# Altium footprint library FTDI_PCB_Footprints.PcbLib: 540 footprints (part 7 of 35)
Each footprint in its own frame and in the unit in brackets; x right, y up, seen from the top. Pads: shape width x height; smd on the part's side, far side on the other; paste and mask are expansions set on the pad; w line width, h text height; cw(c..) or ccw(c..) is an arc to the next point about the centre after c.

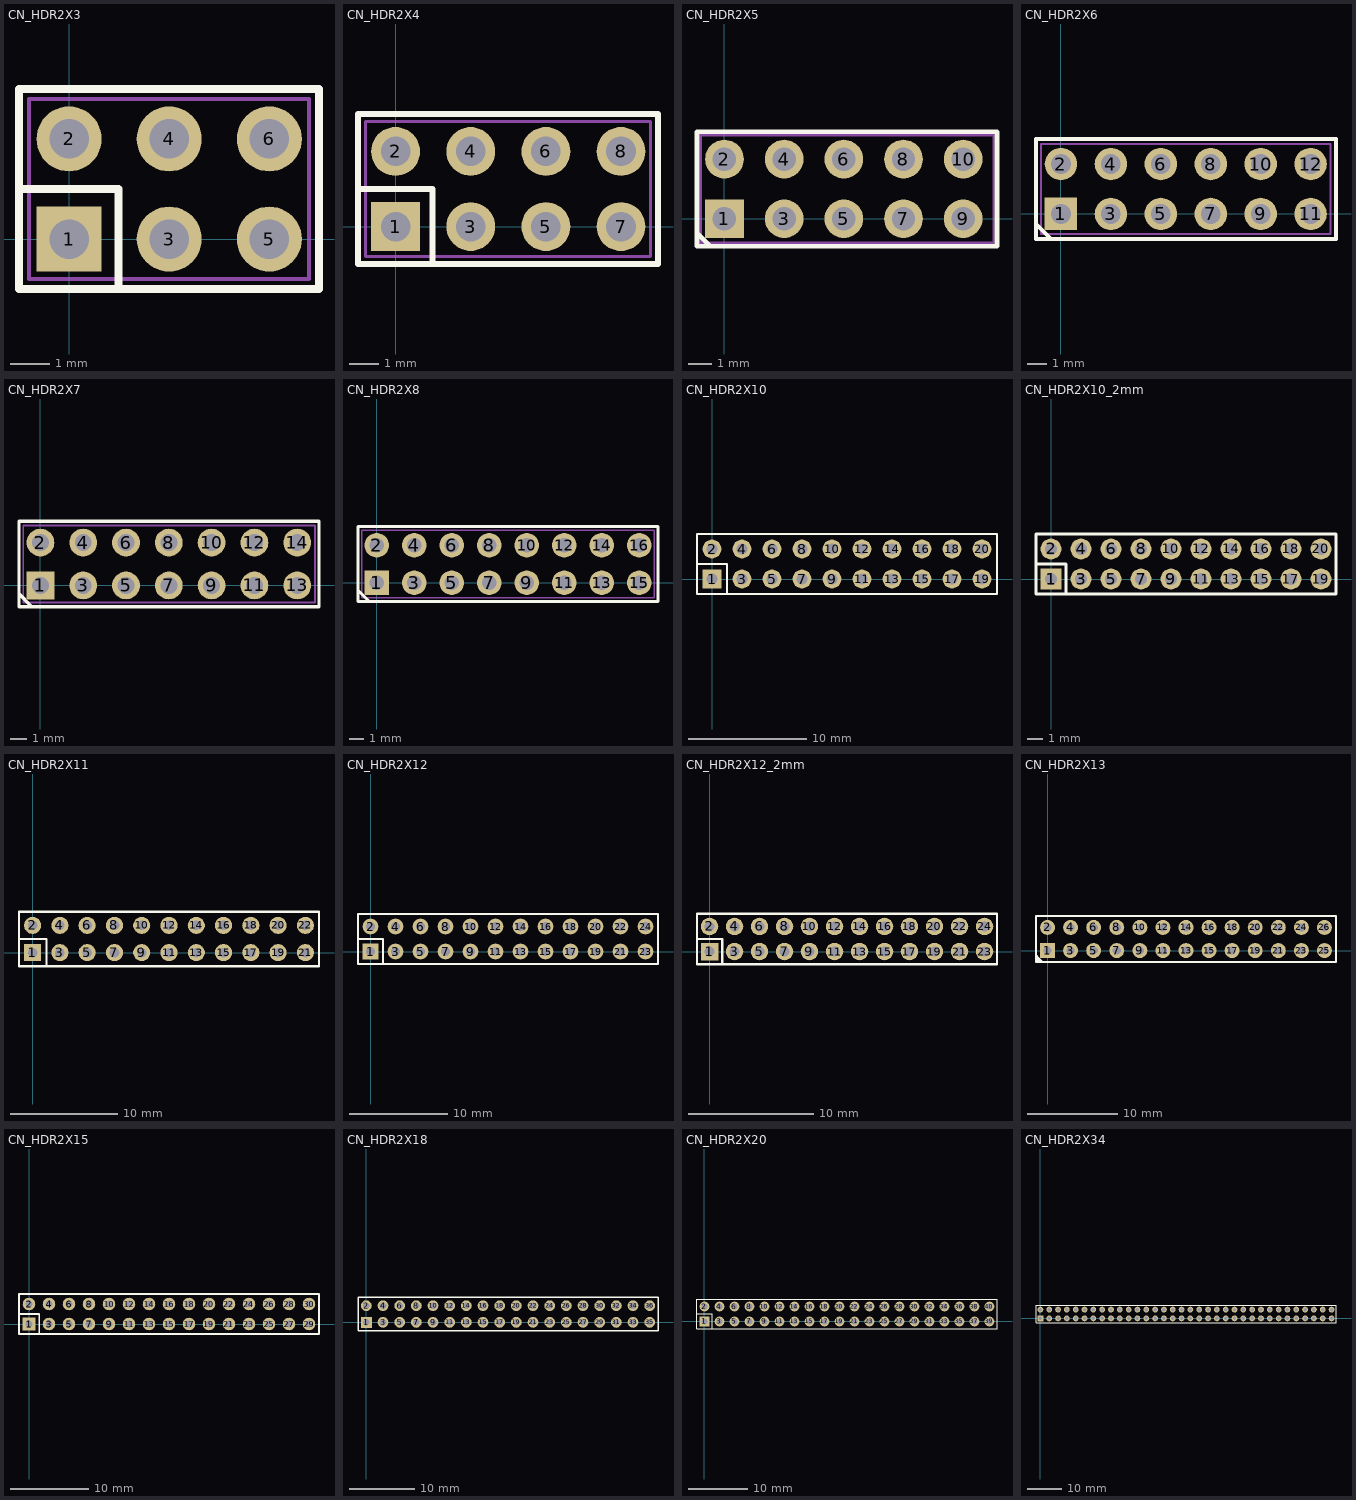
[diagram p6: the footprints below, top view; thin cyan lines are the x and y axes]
## CN_HDR2X3 [mil] "Connector; Header; 2x3 Position; pitch 0.1\""
pads (6):
  rect 65x65 hole 39.37: 1(0,0)
  round 65 hole 39.37: 2(0,100) 3(100,0) 4(100,100) 5(200,0) 6(200,100)
Top Overlay:
  lines w7.87: -50,50 49.21,50 49.21,-50 ; -50,-50 249.61,-50 249.61,150 -50,150 -50,-50
M7_3D_Body:
  lines w3.94: -40,-40 -40,140 239.76,140 239.76,-40 -40,-40

## CN_HDR2X4 [mil] "Connector; Header; 2x4 Position; pitch 0.1\""
pads (8):
  rect 65x65 hole 39.37: 1(0,0)
  round 65 hole 39.37: 2(0,100) 3(100,0) 4(100,100) 5(200,0) 6(200,100) 7(300,0) 8(300,100)
Top Overlay:
  lines w7.87: -50,50 49.21,50 49.21,-50 ; -50,-50 349.21,-50 349.21,150 -50,150 -50,-50
M7_3D_Body:
  lines w3.94: -40,-40 -40,140 339.37,140 339.37,-40 -40,-40

## CN_HDR2X5 [mil] "Connector; Header; 2x5 Position; pitch 0.1\""
pads (10):
  rect 65x65 hole 39.37: 1(0,0)
  round 65 hole 39.37: 2(0,100) 3(100,0) 4(100,100) 5(200,0) 6(200,100) 7(300,0) 8(300,100) 9(400,0) 10(400,100)
Top Overlay:
  lines w7.87: -45.96,-23.92 -23.72,-46.16 ; -46.06,-46.06 456.69,-46.06 456.69,146.06 -46.06,146.06 -46.06,-46.06
M13_Assembly_Info:
  lines w3.94: -40,-40 -40,140 450.79,140 450.79,-40 -40,-40

## CN_HDR2X6 [mil] "Connector; Header; 6x2 Position; pitch 0.1\""
pads (12):
  rect 65x65 hole 39.37: 1(0,0)
  round 65 hole 39.37: 2(0,100) 3(100,0) 4(100,100) 5(200,0) 6(200,100) 7(300,0) 8(300,100) 9(400,0) 10(400,100) 11(500,0) 12(500,100)
Top Overlay:
  lines w7.87: -50,-19.88 -19.88,-50 ; -50,-50 550.79,-50 550.79,150 -50,150 -50,-50
M7_3D_Body:
  lines w3.94: -40,-40 540,-40 540,140 -40,140 -40,-40

## CN_HDR2X7 [mil] "Connector; Header; 7x2 Position; pitch 0.1\""
pads (14):
  rect 65x65 hole 39.37: 1(0,0)
  round 65 hole 39.37: 2(0,100) 3(100,0) 4(100,100) 5(200,0) 6(200,100) 7(300,0) 8(300,100) 9(400,0) 10(400,100) 11(500,0) 12(500,100) 13(600,0) 14(600,100)
Top Overlay:
  lines w7.87: -50,-19.88 -19.88,-50 ; -50,-50 650.79,-50 650.79,150 -50,150 -50,-50
M7_3D_Body:
  lines w3.94: -40,-40 -40,140 641.34,140 641.34,-40 -40,-40

## CN_HDR2X8 [mil] "Connector; Header; 8x2 Position; pitch 0.1\""
pads (16):
  rect 65x65 hole 39.37: 1(0,0)
  round 65 hole 39.37: 2(0,100) 3(100,0) 4(100,100) 5(200,0) 6(200,100) 7(300,0) 8(300,100) 9(400,0) 10(400,100) 11(500,0) 12(500,100) 13(600,0) 14(600,100) 15(700,0) 16(700,100)
Top Overlay:
  lines w7.87: -50,-19.88 -19.88,-50 ; -50,-50 750,-50 750,150 -50,150 -50,-50
M7_3D_Body:
  lines w3.94: -40,-40 -40,140 740,140 740,-40 -40,-40

## CN_HDR2X10 [mm] "Connector; Header; Female; 2x10 Position; Pitch 0.1\""
pads (20):
  rect 1.6x1.6 hole 0.9: 1(0,0)
  round 1.6 hole 0.9: 2(0,2.54) 3(2.54,0) 4(2.54,2.54) 5(5.08,0) 6(5.08,2.54) 7(7.62,0) 8(7.62,2.54) 9(10.16,0) 10(10.16,2.54) 11(12.7,0) 12(12.7,2.54) 13(15.24,0) 14(15.24,2.54) 15(17.78,0) 16(17.78,2.54) 17(20.32,0) 18(20.32,2.54) 19(22.86,0) 20(22.86,2.54)
Top Overlay:
  lines w0.2: -1.265,1.27 1.275,1.27 1.275,-1.27 ; -1.27,-1.27 24.13,-1.27 24.13,3.81 -1.27,3.81 -1.27,-1.27

## CN_HDR2X10_2mm [mm] "Connector; Header; 2 Rows x 10 Positions; pitch 2.0mm"
pads (20):
  rect 1.4x1.4 hole 0.8: 1(0,0)
  round 1.4 hole 0.8: 2(0,2) 3(2,0) 4(2,2) 5(4,0) 6(4,2) 7(6,0) 8(6,2) 9(8,0) 10(8,2) 11(10,0) 12(10,2) 13(12,0) 14(12,2) 15(14,0) 16(14,2) 17(16,0) 18(16,2) 19(18,0) 20(18,2)
Top Overlay:
  lines w0.2: 1,-1 1,1 -1,1 ; -1,1 -1,-1 19,-1 19,1 19,3 -1,3 -1,1

## CN_HDR2X11 [mm] "Connector; Header; Female; 2x11 Position; Pitch 0.1\""
pads (22):
  rect 1.6x1.6 hole 0.9: 1(0,0)
  round 1.6 hole 0.9: 2(0,2.54) 3(2.54,0) 4(2.54,2.54) 5(5.08,0) 6(5.08,2.54) 7(7.62,0) 8(7.62,2.54) 9(10.16,0) 10(10.16,2.54) 11(12.7,0) 12(12.7,2.54) 13(15.24,0) 14(15.24,2.54) 15(17.78,0) 16(17.78,2.54) 17(20.32,0) 18(20.32,2.54) 19(22.86,0) 20(22.86,2.54) 21(25.4,0) 22(25.4,2.54)
Top Overlay:
  lines w0.2: -1.265,1.27 1.275,1.27 1.275,-1.27 ; -1.27,-1.27 26.67,-1.27 26.67,3.81 -1.27,3.81 -1.27,-1.27

## CN_HDR2X12 [mm] "Connector; Header; Female; 2x12 Position; Pitch 0.1\""
pads (24):
  rect 1.6x1.6 hole 0.9: 1(0,0)
  round 1.6 hole 0.9: 2(0,2.54) 3(2.54,0) 4(2.54,2.54) 5(5.08,0) 6(5.08,2.54) 7(7.62,0) 8(7.62,2.54) 9(10.16,0) 10(10.16,2.54) 11(12.7,0) 12(12.7,2.54) 13(15.24,0) 14(15.24,2.54) 15(17.78,0) 16(17.78,2.54) 17(20.32,0) 18(20.32,2.54) 19(22.86,0) 20(22.86,2.54) 21(25.4,0) 22(25.4,2.54) 23(27.94,0) 24(27.94,2.54)
Top Overlay:
  lines w0.2: -1.265,1.27 1.275,1.27 1.275,-1.27 ; -1.27,-1.27 -1.27,3.81 29.21,3.81 29.21,-1.27 -1.27,-1.27

## CN_HDR2X12_2mm [mm] "Connector; Header; 2 Rows x 12 Positions; pitch 2.0mm"
height 4.5
pads (24):
  rect 1.4x1.4 hole 0.8: 1(0,0)
  round 1.4 hole 0.8: 2(0,2) 3(2,0) 4(2,2) 5(4,0) 6(4,2) 7(6,0) 8(6,2) 9(8,0) 10(8,2) 11(10,0) 12(10,2) 13(12,0) 14(12,2) 15(14,0) 16(14,2) 17(16,0) 18(16,2) 19(18,0) 20(18,2) 21(20,0) 22(20,2) 23(22,0) 24(22,2)
Top Overlay:
  lines w0.2: 1,-1 1,1 -1,1 ; -1,1 -1,3 23,3 23,-1 -1,-1 -1,1

## CN_HDR2X13 [mil] "Connector; Header; Male; 13x2 Position; Pitch 0.1\""
pads (26):
  rect 65x65 hole 35.43: 1(0,0)
  round 65 hole 35.43: 2(0,100) 3(100,0) 4(100,100) 5(200,0) 6(200,100) 7(300,0) 8(300,100) 9(400,0) 10(400,100) 11(500,0) 12(500,100) 13(600,0) 14(600,100) 15(700,0) 16(700,100) 17(800,0) 18(800,100) 19(900,0) 20(900,100) 21(1000,0) 22(1000,100) 23(1100,0) 24(1100,100) 25(1200,0) 26(1200,100)
Top Overlay:
  region: -50,-50 -50,-15.35 -32.68,-32.68 -15.35,-50
  lines w7.87: -50,-50 -50,150 1250,150 1250,-50 -50,-50

## CN_HDR2X15 [mm] "Connector; Header; Female; 15x2 Position; Pitch 0.1\""
pads (30):
  rect 1.6x1.6 hole 0.9: 1(0,0)
  round 1.6 hole 0.9: 2(0,2.54) 3(2.54,0) 4(2.54,2.54) 5(5.08,0) 6(5.08,2.54) 7(7.62,0) 8(7.62,2.54) 9(10.16,0) 10(10.16,2.54) 11(12.7,0) 12(12.7,2.54) 13(15.24,0) 14(15.24,2.54) 15(17.78,0) 16(17.78,2.54) 17(20.32,0) 18(20.32,2.54) 19(22.86,0) 20(22.86,2.54) 21(25.4,0) 22(25.4,2.54) 23(27.94,0) 24(27.94,2.54) 25(30.48,0) 26(30.48,2.54) 27(33.02,0) 28(33.02,2.54) 29(35.56,0) 30(35.56,2.54)
Top Overlay:
  lines w0.2: -1.265,1.27 1.275,1.27 1.275,-1.27 ; -1.27,-1.27 36.83,-1.27 36.83,3.81 -1.27,3.81 -1.27,-1.27

## CN_HDR2X18 [mil] "Connector; Header; 18x2 Position; Pitch 0.1\""
pads (36):
  rect 65x65 hole 39.37: 1(0,0)
  round 65 hole 39.37: 2(0,100) 3(100,0) 4(100,100) 5(200,0) 6(200,100) 7(300,0) 8(300,100) 9(400,0) 10(400,100) 11(500,0) 12(500,100) 13(600,0) 14(600,100) 15(700,0) 16(700,100) 17(800,0) 18(800,100) 19(900,0) 20(900,100) 21(1000,0) 22(1000,100) 23(1100,0) 24(1100,100) 25(1200,0) 26(1200,100) 27(1300,0) 28(1300,100) 29(1400,0) 30(1400,100) 31(1500,0) 32(1500,100) 33(1600,0) 34(1600,100) 35(1700,0) 36(1700,100)
Top Overlay:
  lines w7.87: -50,-50 -50,150 1750,150 1750,-50 -50,-50

## CN_HDR2X20 [mil] "Connector; Header; Male; 2x20 Positions; Pitch 0.1\""
height 329.92
pads (40):
  rect 65x65 hole 39.37: 1(0,0)
  round 65 hole 39.37: 2(0,100) 3(100,0) 4(100,100) 5(200,0) 6(200,100) 7(300,0) 8(300,100) 9(400,0) 10(400,100) 11(500,0) 12(500,100) 13(600,0) 14(600,100) 15(700,0) 16(700,100) 17(800,0) 18(800,100) 19(900,0) 20(900,100) 21(1000,0) 22(1000,100) 23(1100,0) 24(1100,100) 25(1200,0) 26(1200,100) 27(1300,0) 28(1300,100) 29(1400,0) 30(1400,100) 31(1500,0) 32(1500,100) 33(1600,0) 34(1600,100) 35(1700,0) 36(1700,100) 37(1800,0) 38(1800,100) 39(1900,0) 40(1900,100)
Top Overlay:
  lines w7.87: -50,51.18 51.18,51.18 51.18,-50 ; -50,-50 1750,-50 1950.39,-50 1950.39,150 1750,150 -50,150 -50,-50

## CN_HDR2X34 [mil] "Connector; Header; Male; 2x34 Positions; Pitch 0.1\""
height 329.92
pads (68):
  rect 65x65 hole 39.37: 1(0,0)
  round 65 hole 39.37: 2(0,100) 3(100,0) 4(100,100) 5(200,0) 6(200,100) 7(300,0) 8(300,100) 9(400,0) 10(400,100) 11(500,0) 12(500,100) 13(600,0) 14(600,100) 15(700,0) 16(700,100) 17(800,0) 18(800,100) 19(900,0) 20(900,100) 21(1000,0) 22(1000,100) 23(1100,0) 24(1100,100) 25(1200,0) 26(1200,100) 27(1300,0) 28(1300,100) 29(1400,0) 30(1400,100) 31(1500,0) 32(1500,100) 33(1600,0) 34(1600,100) 35(1700,0) 36(1700,100) 37(1800,0) 38(1800,100) 39(1900,0) 40(1900,100) 41(2000,0) 42(2000,100) 43(2100,0) 44(2100,100) 45(2200,0) 46(2200,100) 47(2300,0) 48(2300,100) 49(2400,0) 50(2400,100) 51(2500,0) 52(2500,100) 53(2600,0) 54(2600,100) 55(2700,0) 56(2700,100) 57(2800,0) 58(2800,100) 59(2900,0) 60(2900,100) 61(3000,0) 62(3000,100) 63(3100,0) 64(3100,100) 65(3200,0) 66(3200,100) 67(3300,0) 68(3300,100)
Top Overlay:
  lines w7.87: -50,-50 -50,150 1750,150 3350.39,150 3350.39,-50 1750,-50 -50,-50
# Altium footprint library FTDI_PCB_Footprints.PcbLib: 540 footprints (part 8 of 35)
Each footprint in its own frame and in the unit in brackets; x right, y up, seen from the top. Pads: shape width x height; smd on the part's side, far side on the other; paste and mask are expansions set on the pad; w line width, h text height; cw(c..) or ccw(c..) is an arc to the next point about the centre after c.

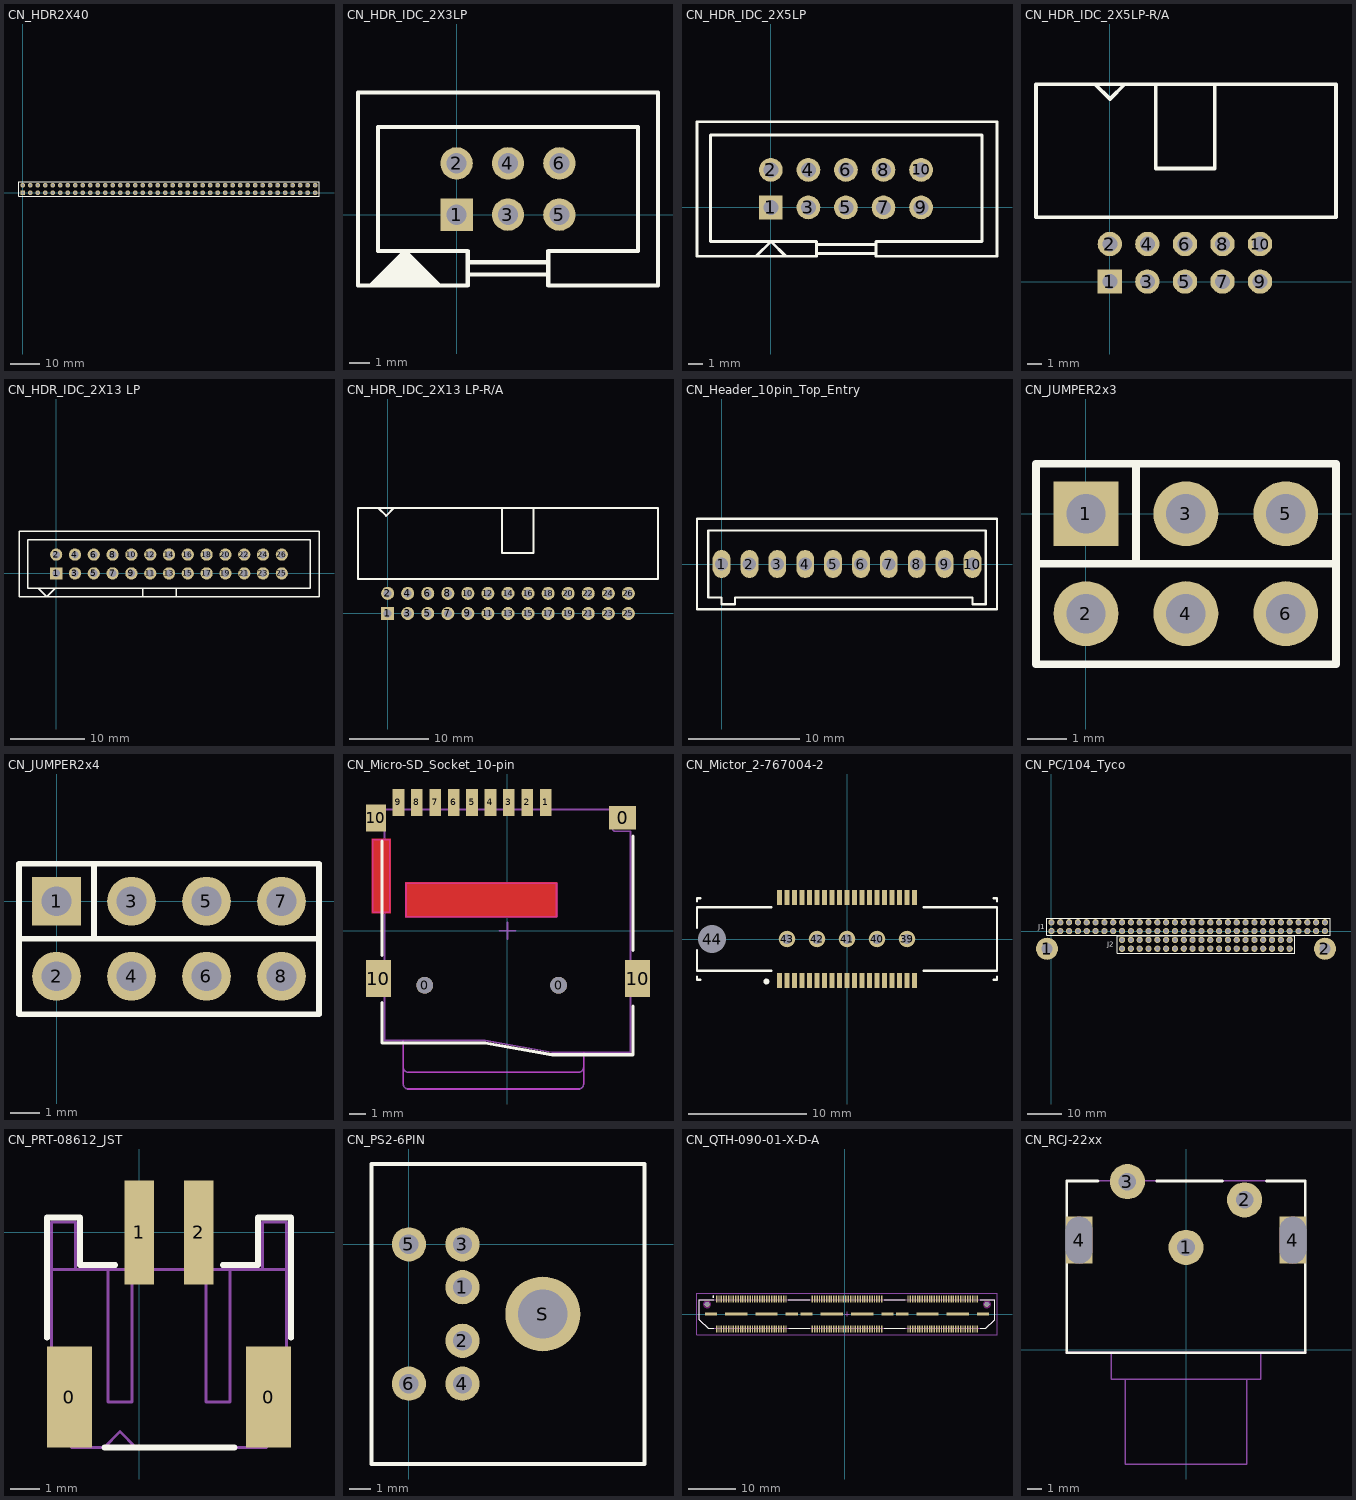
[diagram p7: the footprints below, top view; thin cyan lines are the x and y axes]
## CN_HDR2X40 [mil] "Connector; Header; Male; 2x80 Positions; Pitch 0.1\""
height 329.92
pads (80):
  rect 65x65 hole 39.37: 1(0,0)
  round 65 hole 39.37: 2(0,100) 3(100,0) 4(100,100) 5(200,0) 6(200,100) 7(300,0) 8(300,100) 9(400,0) 10(400,100) 11(500,0) 12(500,100) 13(600,0) 14(600,100) 15(700,0) 16(700,100) 17(800,0) 18(800,100) 19(900,0) 20(900,100) 21(1000,0) 22(1000,100) 23(1100,0) 24(1100,100) 25(1200,0) 26(1200,100) 27(1300,0) 28(1300,100) 29(1400,0) 30(1400,100) 31(1500,0) 32(1500,100) 33(1600,0) 34(1600,100) 35(1700,0) 36(1700,100) 37(1800,0) 38(1800,100) 39(1900,0) 40(1900,100) 41(2000,0) 42(2000,100) 43(2100,0) 44(2100,100) 45(2200,0) 46(2200,100) 47(2300,0) 48(2300,100) 49(2400,0) 50(2400,100) 51(2500,0) 52(2500,100) 53(2600,0) 54(2600,100) 55(2700,0) 56(2700,100) 57(2800,0) 58(2800,100) 59(2900,0) 60(2900,100) 61(3000,0) 62(3000,100) 63(3100,0) 64(3100,100) 65(3200,0) 66(3200,100) 67(3300,0) 68(3300,100) 69(3400,0) 70(3400,100) 71(3500,0) 72(3500,100) 73(3600,0) 74(3600,100) 75(3700,0) 76(3700,100) 77(3800,0) 78(3800,100) 79(3900,0) 80(3900,100)
Top Overlay:
  lines w7.87: -50,-50 1750,-50 3950.39,-50 3950.39,150 1750,150 -50,150 -50,-50

## CN_HDR_IDC_2X3LP [mm] "Connector; Header; Lo Profile; 2x3 Position; Pitch 0.1\""
height 9.57
pads (6):
  rect 1.6x1.6 hole 1: 1(0,0)
  round 1.6 hole 1: 2(0,2.54) 3(2.54,0) 4(2.54,2.54) 5(5.08,0) 6(5.08,2.54)
Top Overlay:
  region: -2.55,-1.805 -4.25,-3.505 -0.85,-3.505
  lines w0.2: -4.25,-3.505 -2.55,-1.805 -0.85,-3.505 ; 0.55,-2.95 4.53,-2.95 ; 0.55,-2.35 4.53,-2.35 ; -4.875,-3.505 -4.875,6.045 9.955,6.045 9.955,-3.505 4.53,-3.505 4.53,-1.805 8.965,-1.805 8.965,4.345 -3.885,4.345 -3.885,-1.805 0.55,-1.805 0.55,-3.505 -4.875,-3.505

## CN_HDR_IDC_2X5LP [mm] "Connector; Header; Lo Profile; 5x2 Position; Pitch 0.1\""
pads (10):
  rect 1.6x1.6 hole 1: 1(0,0)
  round 1.6 hole 1: 2(0,2.54) 3(2.54,0) 4(2.54,2.54) 5(5.08,0) 6(5.08,2.54) 7(7.62,0) 8(7.62,2.54) 9(10.16,0) 10(10.16,2.54)
Top Overlay:
  lines w0.2: -1,-3.3 0,-2.3 1,-3.3 ; 3.1,-3.1 7.1,-3.1 ; 3.1,-2.5 7.1,-2.5 ; -5,-3.3 3.1,-3.3 3.1,-2.3 -4.1,-2.3 -4.1,4.9 14.3,4.9 14.3,-2.3 7.1,-2.3 7.1,-3.3 15.3,-3.3 15.3,5.8 -5,5.8 -5,-3.3

## CN_HDR_IDC_2X5LP-R/A [mil] "Connector; Header; Horizontal; Lo Profile; 5x2 Position; Pitch 0.1\""
pads (10):
  rect 65x65 hole 39.37: 1(0,0)
  round 65 hole 39.37: 2(0,100) 3(100,0) 4(100,100) 5(200,0) 6(200,100) 7(300,0) 8(300,100) 9(400,0) 10(400,100)
Top Overlay:
  lines w10: -39.37,525.59 0,486.22 39.37,525.59 ; 122.05,525.59 122.05,301.18 279.53,301.18 279.53,525.59 ; -196.85,171.26 602.36,171.26 602.36,525.59 -196.85,525.59 -196.85,171.26
3D body: height 393.7, standoff 0, extent -196.85,171.26 602.36,525.59

## CN_HDR_IDC_2X13 LP [mil] "Connector; Header; Vertical; Low Profile; 2x13 Positions; Pitch 0.1\""
height 358.27
pads (26):
  rect 65x65 hole 39.37: 1(0,0)
  round 65 hole 39.37: 2(0,100) 3(100,0) 4(100,100) 5(200,0) 6(200,100) 7(300,0) 8(300,100) 9(400,0) 10(400,100) 11(500,0) 12(500,100) 13(600,0) 14(600,100) 15(700,0) 16(700,100) 17(800,0) 18(800,100) 19(900,0) 20(900,100) 21(1000,0) 22(1000,100) 23(1100,0) 24(1100,100) 25(1200,0) 26(1200,100)
Top Overlay:
  lines w7.87: -95.08,-78.15 -50,-123.23 -4.92,-78.15 ; 461.42,-123.23 461.42,-77.95 ; 638.58,-123.23 638.58,-77.95 ; -197.64,-123.23 -197.64,223.23 1397.64,223.23 1397.64,-123.23 -197.64,-123.23 ; -152.36,-77.95 1352.36,-77.95 1352.36,177.95 -152.36,177.95 -152.36,-77.95
3D body: height 358.27, standoff 0, extent -197.64,-123.23 1397.64,223.23

## CN_HDR_IDC_2X13 LP-R/A [mil] "Connector; Header; Horizontal; Low Profile; 2x13 Positions; Pitch 0.1\""
height 358.27
pads (26):
  rect 65x65 hole 39.37: 1(0,0)
  round 65 hole 39.37: 2(0,100) 3(100,0) 4(100,100) 5(200,0) 6(200,100) 7(300,0) 8(300,100) 9(400,0) 10(400,100) 11(500,0) 12(500,100) 13(600,0) 14(600,100) 15(700,0) 16(700,100) 17(800,0) 18(800,100) 19(900,0) 20(900,100) 21(1000,0) 22(1000,100) 23(1100,0) 24(1100,100) 25(1200,0) 26(1200,100)
Top Overlay:
  lines w7.87: 602.36,171.26 688.74,171.26
  lines w10: -47.24,525.59 -7.87,486.22 31.5,525.59 ; 569.29,525.59 569.29,301.18 726.77,301.18 726.77,525.59 ; -147.64,171.26 -147.64,525.59 1347.64,525.59 1347.64,171.26 -147.64,171.26
3D body: height 393.7, standoff 0, extent -147.64,171.26 1347.64,525.59

## CN_Header_10pin_Top_Entry [mm] "HEADER, TOP ENTRY, 10WAY     Connector Type:Board to Board; No. of Positions:10; Pitch:2.5mm; Mounting Type:PCB; Series:Type 373; Colour:Green; Current Rating:4A; Voltage Rating AC:130V;"
height 10.1
pads (10):
  oval 1.6x2.5 hole 1.2: 1(0,0) 2(2.5,0) 3(5,0) 4(7.5,0) 5(10,0) 6(12.5,0) 7(15,0) 8(17.5,0) 9(20,0) 10(22.5,0)
Top Overlay:
  lines w0.2: -1.19,2.995 -1.19,-3 0,-3 0,-3.6 ; -1.19,3 23.7,3 23.7,-3.6 22.5,-3.6 ; 0,-3.6 1.2,-3.6 1.2,-3 22.5,-3 22.5,-3.6 ; 0,-3.6 0,-3.6 ; 22.5,-3.6 22.5,-3.6 ; -2.2,-4.05 -2.2,4.05 24.7,4.05 24.7,-4.05 -2.2,-4.05

## CN_JUMPER2x3 [mil] "2 possition jumper; 0.1\" pitch"
pads (6):
  rect 65x65 hole 39.37: 1(0,0)
  round 65 hole 39.37: 2(0,-100) 3(100,0) 4(100,-100) 5(200,0) 6(200,-100)
Top Overlay:
  lines w7.87: -50,-50 250.28,-50 ; 50.2,-50 50.2,50 ; -50,-150.59 -50,50 250.28,50 250.28,-150.59 -50,-150.59
M13_Assembly_Info:
  lines w3.94: -50,-150.59 -50,50 250.28,50 250.28,-150.59 -50,-150.59
3D body: height 0, standoff 0, extent -50,-150.59 250.28,50

## CN_JUMPER2x4 [mil] "2 possition jumper; 0.1\" pitch"
pads (8):
  rect 65x65 hole 39.37: 1(0,0)
  round 65 hole 39.37: 2(0,-100) 3(100,0) 4(100,-100) 5(200,0) 6(200,-100) 7(300,0) 8(300,-100)
Top Overlay:
  lines w7.87: -50,-50 349.96,-50 ; 50.2,-50 50.2,50 ; 349.96,-150.59 -50,-150.59 -50,50 349.96,50 ; 350,-150.59 350,50
M13_Assembly_Info:
  lines w3.94: -50,-150.59 349.96,-150.59 349.96,50 -50,50 -50,-150.59
3D body: height 0, standoff 0, extent -50,-150.59 349.96,50

## CN_Micro-SD_Socket_10-pin [mm] "Micro SD PUSH connector Connector"
height 1.85
pads (15):
  round 1 hole 1 unplated: 0(-4.95,-3.25) 0(3.05,-3.25)
  rect 1.6x1.4 smd: 0(6.88,6.75)
  rect 0.7x1.6 smd: 1(2.28,7.68) 2(1.18,7.68) 3(0.08,7.68) 4(-1.02,7.68) 5(-2.12,7.68) 6(-3.22,7.68) 7(-4.32,7.68) 8(-5.42,7.68) 9(-6.52,7.68)
  rect 1.2x1.6 smd: 10(-7.87,6.75)
  rect 1.5x2.2 smd: 10(-7.72,-2.85) 10(7.78,-2.85)
Top Layer:
  pour cut-out: -6.12,0.8 -6.12,2.9 2.98,2.9 2.98,0.8
  pour cut-out: -8.12,5.5 -6.97,5.5 -6.97,1.05 -8.12,1.05
Top Overlay:
  lines w0.2: -7.5,-4.3 -7.5,-6.7 -1.34,-6.7 2.66,-7.4 7.5,-7.4 7.5,-4.5 ; -7.5,-1.47 -7.5,5.35 ; 7.5,-1.16 7.5,5.66
M13_Assembly_Info:
  lines w0.1: -7.35,-3.45 -8.05,-3.45 -8.05,-2.25 -7.35,-2.25 ; -7.35,6.25 -8.05,6.25 -8.05,7.25 -7.35,7.25 ; -6.67,7.25 -6.67,8.05 -6.37,8.05 -6.37,7.25 ; -6.23,-9.15 ccw(c-5.93,-9.15) -5.93,-9.45 ; -6.23,-8.15 ccw(c-5.93,-8.15) -5.93,-8.45 ; -5.57,7.25 -5.57,8.05 -5.27,8.05 -5.27,7.25 ; -4.47,7.25 -4.47,8.05 -4.17,8.05 -4.17,7.25 ; -3.37,7.25 -3.37,8.05 -3.07,8.05 -3.07,7.25 ; -2.27,7.25 -2.27,8.05 -1.97,8.05 -1.97,7.25 ; -1.17,7.25 -1.17,8.05 -0.87,8.05 -0.87,7.25 ; -0.07,7.25 -0.07,8.05 0.23,8.05 0.23,7.25 ; 1.03,7.25 1.03,8.05 1.33,8.05 1.33,7.25 ; 2.13,7.25 2.13,8.05 2.43,8.05 2.43,7.25 ; 4.25,-9.45 ccw(c4.25,-9.15) 4.55,-9.15 ; 4.25,-8.45 ccw(c4.25,-8.15) 4.55,-8.15 ; 6.43,7.25 6.43,6.25 ; 7.35,-3.45 8.05,-3.45 8.05,-2.25 7.35,-2.25 ; -7.35,7.25 -7.35,-6.55 -1.35,-6.55 2.65,-7.25 7.35,-7.25 7.35,5.95 6.43,5.95 cw(c6.43,6.1) 6.43,6.25 ; -7.35,7.25 7.13,7.25 7.13,6.25 6.43,6.25
M13_Assembly_Info keep-out:
  lines w0.1: -6.23,-9.15 -6.23,-6.55 ; -5.93,-9.45 4.25,-9.45 ; -5.93,-8.45 4.25,-8.45 ; 4.55,-9.15 4.55,-7.25 ; -8.06,1.11 -7.04,1.11 -7.04,1.95 -7.04,5.44 -8.055,5.44 -8.06,5.435 -8.06,1.11 ; -6.07,0.85 2.93,0.85 2.93,2.85 -6.07,2.85 -6.07,0.85
M15_Country_Yard:
  lines w0.1: -0.5,0 0.5,0 ; 0,-0.5 0,0.5
3D body: height 1.85, standoff 0, extent -7.35,-7.25 7.35,7.25

## CN_Mictor_2-767004-2 [mil] "Connector; High-Speed, Receptacle; 38 Position; Vertical"
height 250
pads (44):
  rect 17x50 smd: 1(-225,-139) 2(-225,139) 3(-200,-139) 4(-200,139) 5(-175,-139) 6(-175,139) 7(-150,-139) 8(-150,139) 9(-125,-139) 10(-125,139) 11(-100,-139) 12(-100,139) 13(-75,-139) 14(-75,139) 15(-50,-139) 16(-50,139) 17(-25,-139) 18(-25,139) 19(0,-139) 20(0,139) 21(25,-139) 22(25,139) 23(50,-139) 24(50,139) 25(75,-139) 26(75,139) 27(100,-139) 28(100,139) 29(125,-139) 30(125,139) 31(150,-139) 32(150,139) 33(175,-139) 34(175,139) 35(200,-139) 36(200,139) 37(225,-139) 38(225,139)
  round 55.12 hole 32: 39(200,0) 40(100,0) 41(0,0) 42(-100,0) 43(-200,0)
  round 82.19 hole 94 unplated: 44(-450,0)
Top Overlay:
  circle w9.84: c-268.7,-141.73 r4.92
  lines w7.87: -500,-125.69 -500,-136 -489.69,-136 ; -500,-37.91 -500,-106 -251.97,-106 ; -500,37.91 -500,106 -251.97,106 ; -500,125.69 -500,136 -489.69,136 ; 255.91,-106 500,-106 500,106 255.91,106 ; 489.69,-136 500,-136 500,-125.69 ; 489.69,136 500,136 500,125.69

## CN_PC/104_Tyco [mm] "Tyco Electronics; PC/104 series; Part No. 1375793-2; Number of Positions = 104; 104 Loaded Positions; Contact Type = Stackthrough; 2.54 mm Centerline"
height 15.24
pads (106):
  round 6.35 hole 3.18: 1(-1.27,-5.08) 2(78.74,-5.08)
  round 1.8 hole 1.15: A1(0,0) A2(2.54,0) A3(5.08,0) A4(7.62,0) A5(10.16,0) A6(12.7,0) A7(15.24,0) A8(17.78,0) A9(20.32,0) A10(22.86,0) A11(25.4,0) A12(27.94,0) A13(30.48,0) A14(33.02,0) A15(35.56,0) A16(38.1,0) A17(40.64,0) A18(43.18,0) A19(45.72,0) A20(48.26,0) A21(50.8,0) A22(53.34,0) A23(55.88,0) A24(58.42,0) A25(60.96,0) A26(63.5,0) A27(66.04,0) A28(68.58,0) A29(71.12,0) A30(73.66,0) A31(76.2,0) A32(78.74,0) B1(0,2.54) B2(2.54,2.54) B3(5.08,2.54) B4(7.62,2.54) B5(10.16,2.54) B6(12.7,2.54) B7(15.24,2.54) B8(17.78,2.54) B9(20.32,2.54) B10(22.86,2.54) B11(25.4,2.54) B12(27.94,2.54) B13(30.48,2.54) B14(33.02,2.54) B15(35.56,2.54) B16(38.1,2.54) B17(40.64,2.54) B18(43.18,2.54) B19(45.72,2.54) B20(48.26,2.54) B21(50.8,2.54) B22(53.34,2.54) B23(55.88,2.54) B24(58.42,2.54) B25(60.96,2.54) B26(63.5,2.54) B27(66.04,2.54) B28(68.58,2.54) B29(71.12,2.54) B30(73.66,2.54) B31(76.2,2.54) B32(78.74,2.54) C0(20.32,-2.54) C1(22.86,-2.54) C2(25.4,-2.54) C3(27.94,-2.54) C4(30.48,-2.54) C5(33.02,-2.54) C6(35.56,-2.54) C7(38.1,-2.54) C8(40.64,-2.54) C9(43.18,-2.54) C10(45.72,-2.54) C11(48.26,-2.54) C12(50.8,-2.54) C13(53.34,-2.54) C14(55.88,-2.54) C15(58.42,-2.54) C16(60.96,-2.54) C17(63.5,-2.54) C18(66.04,-2.54) C19(68.58,-2.54) D0(20.32,-5.08) D1(22.86,-5.08) D2(25.4,-5.08) D3(27.94,-5.08) D4(30.48,-5.08) D5(33.02,-5.08) D6(35.56,-5.08) D7(38.1,-5.08) D8(40.64,-5.08) D9(43.18,-5.08) D10(45.72,-5.08) D11(48.26,-5.08) D12(50.8,-5.08) D13(53.34,-5.08) D14(55.88,-5.08) D15(58.42,-5.08) D16(60.96,-5.08) D17(63.5,-5.08) D18(66.04,-5.08) D19(68.58,-5.08)
Top Overlay:
  lines w0.2: -1.4,-1.25 -1.4,3.7 80.2,3.7 80.2,-1.25 -1.4,-1.25 ; 18.95,-6.35 18.95,-1.4 70.05,-1.4 70.05,-6.35 18.95,-6.35
  text "J1" at -3.75,0.6 h1.5
  text "J2" at 16,-4.5 h1.5

## CN_PRT-08612_JST [mm] "2-pin; 2.0mm-pitch; JST Right Angle Connector - White"
height 5.5
pads (4):
  rect 1.5x3.4 smd: 0(-2.35,-5.55) 0(4.35,-5.55)
  rect 1x3.5 smd: 1(0,0) 2(2,0)
Top Overlay:
  lines w0.2: -3.1,-3.55 -3.1,0.5 -2,0.5 -2,-1.1 -0.81,-1.1 ; -1.17,-7.25 3.2,-7.25 ; 2.81,-1.1 4,-1.1 4,0.5 5.1,0.5 5.1,-3.55
M13_Assembly_Info:
  lines w0.1: -2.15,-1.25 -2.15,0.35 -2.95,0.35 -2.95,-1.25 ; -1.89,-7.25 -1.89,-6.25 -2.29,-6.25 ; -1.19,-7.25 -0.65,-6.71 -0.11,-7.25 ; -1.05,-1.25 -1.05,-5.71 -0.25,-5.71 -0.25,-1.25 -0.25,1.35 0.25,1.35 0.25,-1.25 ; 1.75,-1.25 1.75,1.35 2.25,1.35 2.25,-1.25 2.25,-5.71 3.05,-5.71 3.05,-1.25 ; 3.89,-7.25 3.89,-6.25 4.29,-6.25 ; 4.15,-1.25 4.15,0.35 4.95,0.35 4.95,-1.25 ; -2.95,-1.25 -2.95,-6.25 -2.29,-6.25 ; -2.95,-1.25 4.95,-1.25 ; -2.29,-6.25 -2.29,-7.25 4.29,-7.25 4.29,-6.25 ; 4.29,-6.25 4.95,-6.25 4.95,-1.25
3D body: height 5.5, standoff 0, extent -2.95,-7.25 4.95,0.35

## CN_PS2-6PIN [mm] "PS2 Socket, 6 Pin, Through Hole"
pads (7):
  round 1.6 hole 0.9: 1(2.5,-2) 2(2.5,-4.5) 3(2.5,0) 4(2.5,-6.5) 5(0,0) 6(0,-6.5)
  round 3.5 hole 2.3: S(6.25,-3.25)
Top Overlay:
  lines w0.2: -1.75,-10.25 -1.75,3.75 11,3.75 11,-10.25 -1.75,-10.25

## CN_QTH-090-01-X-D-A [mm] "0.50mm pitch, 180 pin, high speed terminal strip; Samtec"
height 4.27
pads (194):
  rect 0.3x1.45 smd: 1(-26.75,3.09) 2(-26.75,-3.09) 3(-26.25,3.09) 4(-26.25,-3.09) 5(-25.75,3.09) 6(-25.75,-3.09) 7(-25.25,3.09) 8(-25.25,-3.09) 9(-24.75,3.09) 10(-24.75,-3.09) 11(-24.25,3.09) 12(-24.25,-3.09) 13(-23.75,3.09) 14(-23.75,-3.09) 15(-23.25,3.09) 16(-23.25,-3.09) 17(-22.75,3.09) 18(-22.75,-3.09) 19(-22.25,3.09) 20(-22.25,-3.09) 21(-21.75,3.09) 22(-21.75,-3.09) 23(-21.25,3.09) 24(-21.25,-3.09) 25(-20.75,3.09) 26(-20.75,-3.09) 27(-20.25,3.09) 28(-20.25,-3.09) 29(-19.75,3.09) 30(-19.75,-3.09) 31(-19.25,3.09) 32(-19.25,-3.09) 33(-18.75,3.09) 34(-18.75,-3.09) 35(-18.25,3.09) 36(-18.25,-3.09) 37(-17.75,3.09) 38(-17.75,-3.09) 39(-17.25,3.09) 40(-17.25,-3.09) 41(-16.75,3.09) 42(-16.75,-3.09) 43(-16.25,3.09) 44(-16.25,-3.09) 45(-15.75,3.09) 46(-15.75,-3.09) 47(-15.25,3.09) 48(-15.25,-3.09) 49(-14.75,3.09) 50(-14.75,-3.09) 51(-14.25,3.09) 52(-14.25,-3.09) 53(-13.75,3.09) 54(-13.75,-3.09) 55(-13.25,3.09) 56(-13.25,-3.09) 57(-12.75,3.09) 58(-12.75,-3.09) 59(-12.25,3.09) 60(-12.25,-3.09) 61(-6.75,3.09) 62(-6.75,-3.09) 63(-6.25,3.09) 64(-6.25,-3.09) 65(-5.75,3.09) 66(-5.75,-3.09) 67(-5.25,3.09) 68(-5.25,-3.09) 69(-4.75,3.09) 70(-4.75,-3.09) 71(-4.25,3.09) 72(-4.25,-3.09) 73(-3.75,3.09) 74(-3.75,-3.09) 75(-3.25,3.09) 76(-3.25,-3.09) 77(-2.75,3.09) 78(-2.75,-3.09) 79(-2.25,3.09) 80(-2.25,-3.09) 81(-1.75,3.09) 82(-1.75,-3.09) 83(-1.25,3.09) 84(-1.25,-3.09) 85(-0.75,3.09) 86(-0.75,-3.09) 87(-0.25,3.09) 88(-0.25,-3.09) 89(0.25,3.09) 90(0.25,-3.09) 91(0.75,3.09) 92(0.75,-3.09) 93(1.25,3.09) 94(1.25,-3.09) 95(1.75,3.09) 96(1.75,-3.09) 97(2.25,3.09) 98(2.25,-3.09) 99(2.75,3.09) 100(2.75,-3.09) 101(3.25,3.09) 102(3.25,-3.09) 103(3.75,3.09) 104(3.75,-3.09) 105(4.25,3.09) 106(4.25,-3.09) 107(4.75,3.09) 108(4.75,-3.09) 109(5.25,3.09) 110(5.25,-3.09) 111(5.75,3.09) 112(5.75,-3.09) 113(6.25,3.09) 114(6.25,-3.09) 115(6.75,3.09) 116(6.75,-3.09) 117(7.25,3.09) 118(7.25,-3.09) 119(7.75,3.09) 120(7.75,-3.09) 121(13.25,3.09) 122(13.25,-3.09) 123(13.75,3.09) 124(13.75,-3.09) 125(14.25,3.09) 126(14.25,-3.09) 127(14.75,3.09) 128(14.75,-3.09) 129(15.25,3.09) 130(15.25,-3.09) 131(15.75,3.09) 132(15.75,-3.09) 133(16.25,3.09) 134(16.25,-3.09) 135(16.75,3.09) 136(16.75,-3.09) 137(17.25,3.09) 138(17.25,-3.09) 139(17.75,3.09) 140(17.75,-3.09) 141(18.25,3.09) 142(18.25,-3.09) 143(18.75,3.09) 144(18.75,-3.09) 145(19.25,3.09) 146(19.25,-3.09) 147(19.75,3.09) 148(19.75,-3.09) 149(20.25,3.09) 150(20.25,-3.09) 151(20.75,3.09) 152(20.75,-3.09) 153(21.25,3.09) 154(21.25,-3.09) 155(21.75,3.09) 156(21.75,-3.09) 157(22.25,3.09) 158(22.25,-3.09) 159(22.75,3.09) 160(22.75,-3.09) 161(23.25,3.09) 162(23.25,-3.09) 163(23.75,3.09) 164(23.75,-3.09) 165(24.25,3.09) 166(24.25,-3.09) 167(24.75,3.09) 168(24.75,-3.09) 169(25.25,3.09) 170(25.25,-3.09) 171(25.75,3.09) 172(25.75,-3.09) 173(26.25,3.09) 174(26.25,-3.09) 175(26.75,3.09) 176(26.75,-3.09) 177(27.25,3.09) 178(27.25,-3.09) 179(27.75,3.09) 180(27.75,-3.09)
  rect 2.54x0.635 smd: 181(-27.955,0) 184(-11.045,0) 185(-7.955,0) 188(8.955,0) 189(12.045,0) 192(28.955,0)
  rect 4.7x0.635 smd: 182(-22.675,0) 183(-16.325,0) 186(-2.675,0) 187(3.675,0) 190(17.325,0) 191(23.675,0)
  round 1 hole 1 unplated: 193(-28.74,2.03) 194(29.74,2.03)
Top Overlay:
  circle w0.25: c-27.45,3.65 r0.125
  lines w0.2: -27.3,-3 -28.55,-3 -30.35,-1.2 -30.35,3 -27.3,3 ; -11.75,3 -7.3,3 ; -11.7,-3 -7.25,-3 ; 8.3,-3 12.7,-3 ; 8.3,3 12.7,3 ; 28.3,-3 29.55,-3 31.35,-1.2 31.35,3 28.3,3
Keep-Out Layer:
  pour cut-out: -27.933,2.03 -27.961,2.239 -28.041,2.433 -28.169,2.601 -28.337,2.729 -28.531,2.809 -28.74,2.837 -28.949,2.809 -29.143,2.729 -29.311,2.601 -29.439,2.433 -29.519,2.239 -29.547,2.03 -29.519,1.821 -29.439,1.627 -29.311,1.459 -29.143,1.331 -28.949,1.251 -28.74,1.223 -28.531,1.251 -28.337,1.331 -28.169,1.459 -28.041,1.627 -27.961,1.821
  pour cut-out: 30.547,2.03 30.519,2.239 30.439,2.433 30.311,2.601 30.143,2.729 29.949,2.809 29.74,2.837 29.531,2.809 29.337,2.729 29.169,2.601 29.041,2.433 28.961,2.239 28.933,2.03 28.961,1.821 29.041,1.627 29.169,1.459 29.337,1.331 29.531,1.251 29.74,1.223 29.949,1.251 30.143,1.331 30.311,1.459 30.439,1.627 30.519,1.821
M13_Assembly_Info:
  lines w0.1: -30.35,-1.2 -30.35,3 31.35,3 31.35,-1.2 29.55,-3 -28.55,-3 -30.35,-1.2
M15_Country_Yard:
  lines w0.05: 0,0 1,0 ; 0.5,-0.5 0.5,0.5 ; -30.85,-4.3 31.85,-4.3 31.85,4.3 -30.85,4.3 -30.85,-4.3

## CN_RCJ-22xx [mm] "RCA Jack; Dual; Right Angle; PCB Mount; Vertical"
height 27.4
pads (5):
  round 2.4 hole 1.2: 1(0,7) 2(4,10.25) 3(-4,11.5)
  rect 1.8x3.2 hole 1.8 slot 3.2 at 90 deg unplated: 4(-7.3,7.5) 4(7.3,7.5)
Top Overlay:
  lines w0.2: -6,11.55 -8.15,11.55 -8.15,-0.2 8.15,-0.2 8.15,11.55 5.5,11.55 ; -2,11.55 2.5,11.55
Mechanical 1:
  lines w0.2: -8.15,-0.2 8.15,-0.2
M13_Assembly_Info:
  lines w0.1: -5.1,-0.2 -5.1,-2 -4.15,-2 ; 5.1,-0.2 5.1,-2 4.15,-2 ; -4.15,-2 4.15,-2 ; -4.15,-2 -4.15,-7.8 4.15,-7.8 4.15,-2 ; 4.15,-2 4.15,-2 ; -8.15,-0.2 8.15,-0.2 8.15,11.55 -8.15,11.55 -8.15,-0.2
3D body: height 0, standoff 0, extent -8.15,-0.2 8.15,11.55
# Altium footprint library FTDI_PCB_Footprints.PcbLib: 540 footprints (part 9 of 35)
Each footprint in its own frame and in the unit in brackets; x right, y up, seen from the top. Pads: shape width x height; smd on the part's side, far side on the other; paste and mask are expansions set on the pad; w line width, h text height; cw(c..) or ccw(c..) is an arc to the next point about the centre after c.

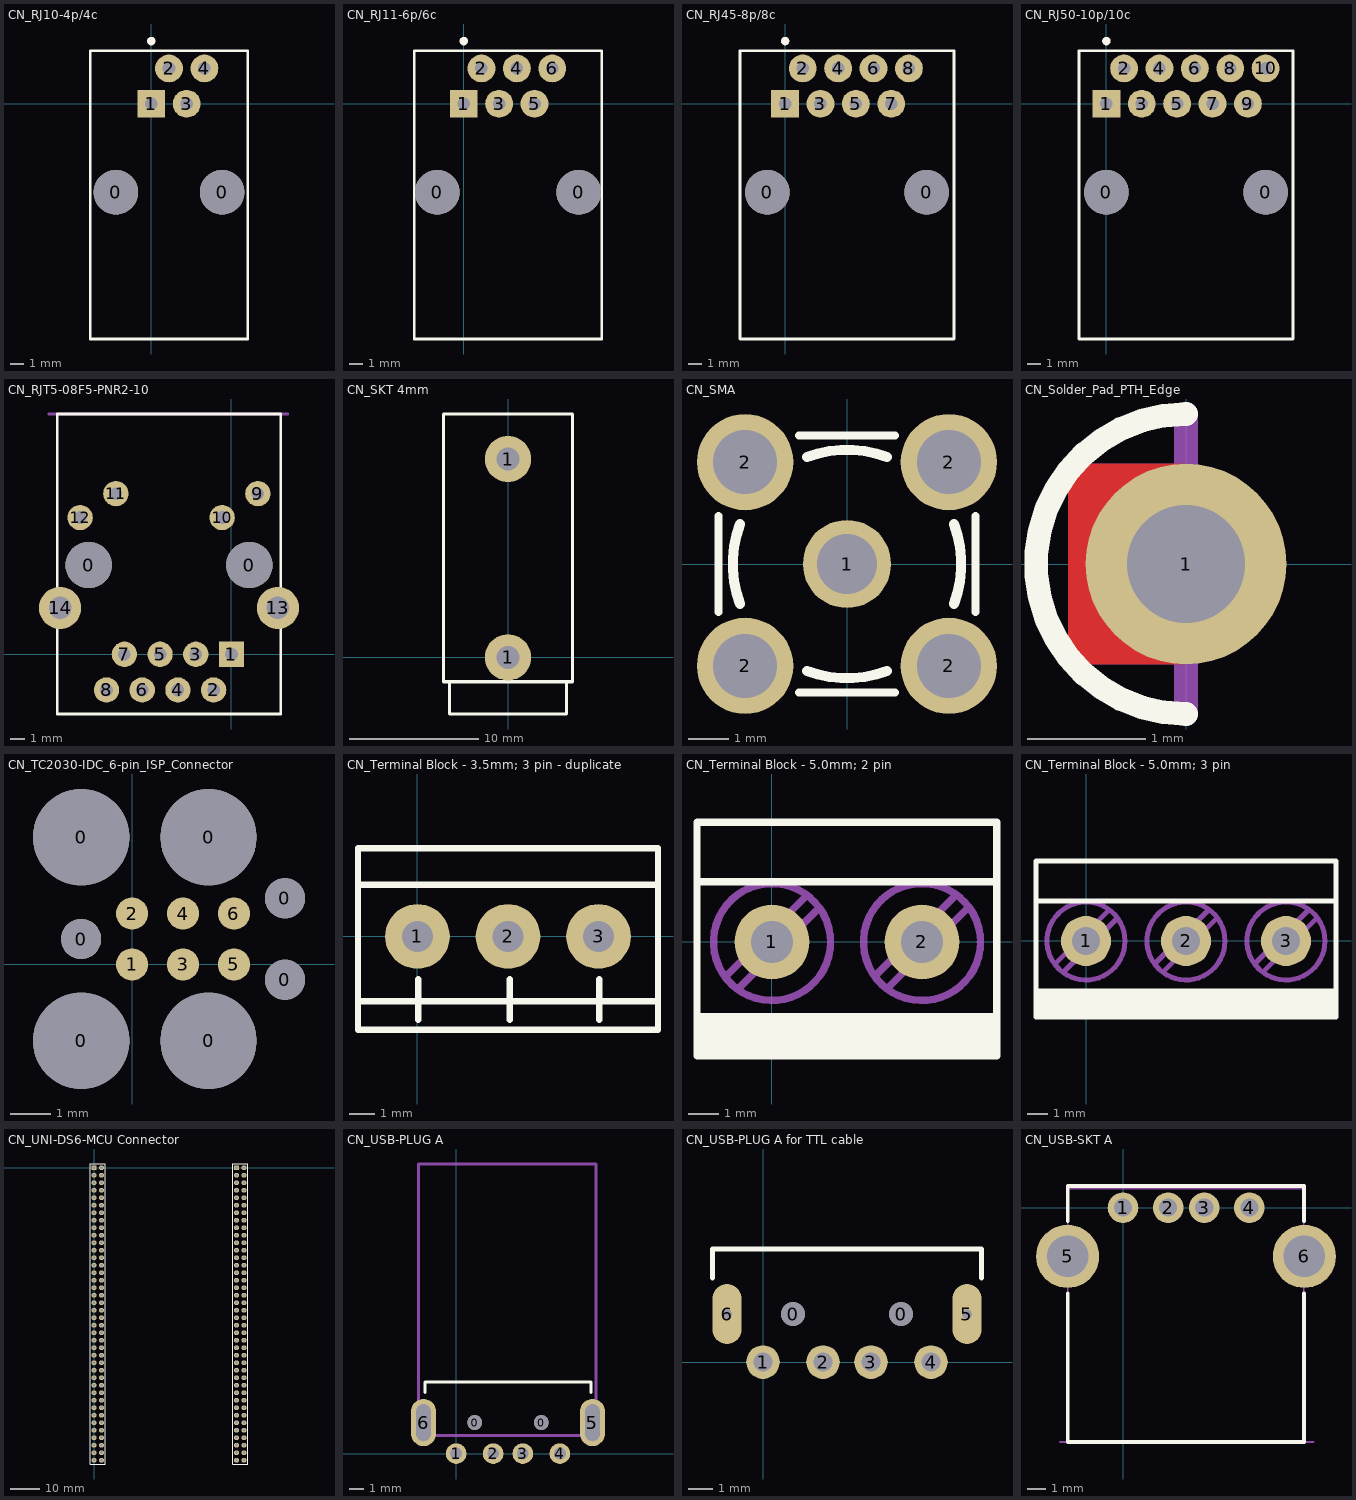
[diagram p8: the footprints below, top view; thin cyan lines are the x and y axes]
## CN_RJ10-4p/4c [mm] "SS-64444-NF; RJ10-4p/4c; Steward Connector"
height 12.83
pads (6):
  round 3.2 hole 3.2 unplated: 0(-2.54,-6.35) 0(5.08,-6.35)
  rect 2x2 hole 0.9: 1(0,0)
  round 2 hole 0.9: 2(1.27,2.54) 3(2.54,0) 4(3.81,2.54)
Top Overlay:
  circle w0.3: c0,4.5 r0.15
  lines w0.2: -4.381,-16.891 6.921,-16.891 6.921,3.81 -4.381,3.81 -4.381,-16.891
3D body: height 12.83, standoff 0, extent -4.375,-16.9 6.925,3.8

## CN_RJ11-6p/6c [mm] "SS-6466-NF; RJ11-6p/6c; Steward Connector"
height 12.83
pads (8):
  round 3.2 hole 3.2 unplated: 0(-1.905,-6.35) 0(8.255,-6.35)
  rect 2x2 hole 0.9: 1(0,0)
  round 2 hole 0.9: 2(1.27,2.54) 3(2.54,0) 4(3.81,2.54) 5(5.08,0) 6(6.35,2.54)
Top Overlay:
  circle w0.3: c0,4.5 r0.15
  lines w0.2: -3.556,-16.891 9.906,-16.891 9.906,3.81 -3.556,3.81 -3.556,-16.891
3D body: height 12.83, standoff 0, extent -3.55,-16.9 9.9,3.8

## CN_RJ45-8p/8c [mm] "SS-6488-NF; RJ45-8p/8c; Steward Connector"
height 12.83
pads (10):
  round 3.2 hole 3.2 unplated: 0(-1.27,-6.35) 0(10.16,-6.35)
  rect 2x2 hole 0.9: 1(0,0)
  round 2 hole 0.9: 2(1.27,2.54) 3(2.54,0) 4(3.81,2.54) 5(5.08,0) 6(6.35,2.54) 7(7.62,0) 8(8.89,2.54)
Top Overlay:
  circle w0.3: c0,4.5 r0.15
  lines w0.2: -3.238,-16.891 12.128,-16.891 12.128,3.81 -3.238,3.81 -3.238,-16.891
3D body: height 12.83, standoff 0, extent -3.25,-16.9 12.125,3.8

## CN_RJ50-10p/10c [mm] "SS-641010-NF; RJ50-10p/10c; Steward Connector"
height 12.83
pads (12):
  round 3.2 hole 3.2 unplated: 0(0,-6.35) 0(11.43,-6.35)
  rect 2x2 hole 0.9: 1(0,0)
  round 2 hole 0.9: 2(1.27,2.54) 3(2.54,0) 4(3.81,2.54) 5(5.08,0) 6(6.35,2.54) 7(7.62,0) 8(8.89,2.54) 9(10.16,0) 10(11.43,2.54)
Top Overlay:
  circle w0.3: c0,4.5 r0.15
  lines w0.2: -1.968,-16.891 13.399,-16.891 13.399,3.81 -1.968,3.81 -1.968,-16.891
3D body: height 12.83, standoff 0, extent -1.975,-16.9 13.4,3.8

## CN_RJT5-08F5-PNR2-10 [mm] "RJ45 Connector with magnetics and LEDs; eConn Electronics (Su-Zhou) Ltd."
height 13.75
pads (16):
  round 3.3 hole 3.3 unplated: 0(-10.16,6.35) 0(1.27,6.35)
  rect 1.8x1.8 hole 0.9: 1(0,0)
  round 1.8 hole 0.9: 2(-1.27,-2.54) 3(-2.54,0) 4(-3.81,-2.54) 5(-5.08,0) 6(-6.35,-2.54) 7(-7.62,0) 8(-8.89,-2.54) 9(1.88,11.43) 10(-0.66,9.73) 11(-8.23,11.43) 12(-10.77,9.73)
  round 3 hole 1.6: 13(3.305,3.3) 14(-12.195,3.3)
Top Overlay:
  lines w0.2: -12.395,17.05 -12.395,-4.25 3.505,-4.25 3.505,17.05 ; -12.395,17.1 3.505,17.1
Mechanical 1:
  lines w0.2: -13,17.1 4,17.1
3D body: height 13.5, standoff 0, extent -12.375,-4.25 3.5,17.1

## CN_SKT 4mm [mm] "pcb mounted insulated socket 4mm right angle"
height 12.4
pads (2):
  round 3.6 hole 1.8: 1(0,0) 1(0,15.4)
Top Overlay:
  lines w0.25: -4.55,-1.9 -4.55,-4.4 4.55,-4.4 4.55,-1.9 ; -5,-1.9 -5,18.9 5,18.9 5,-1.9 -5,-1.9
M13_Assembly_Info:
  lines w0.1: -5,-1.9 -5,18.9 5,18.9 5,-1.9 -5,-1.9
3D body: height 12.7, standoff 0, extent -5,-1.9 5,18.9

## CN_SMA [mm] "SMA Straight PCB Socket"
pads (5):
  round 2.2 hole 1.5: 1(0,0)
  round 2.4 hole 1.6: 2(-2.54,-2.54) 2(-2.54,2.54) 2(2.54,-2.54) 2(2.54,2.54)
Top Overlay:
  lines w0.2: -3.2,-1.2 -3.2,1.2 ; -1.2,-3.2 1.2,-3.2 ; -1.2,3.2 1.2,3.2 ; 3.2,-1.2 3.2,1.2
  lines w0.254: -2.67,-0.998 cw(c0,0) -2.67,0.998 ; -0.998,-2.67 ccw(c0,0) 0.998,-2.67 ; -0.998,2.67 cw(c0,0) 0.998,2.67 ; 2.67,-0.998 ccw(c0,0) 2.67,0.998

## CN_Solder_Pad_PTH_Edge [mm] "Soldering pad for PCB on PCB designs"
height 4.6
pads (1):
  round 1.7 hole 1: 1(0,0)
Top Layer:
  rectangle: -1,-0.85 0,0.85
Bottom Layer:
  rectangle: -1,-0.85 0,0.85
Top Overlay:
  lines w0.2: 0,-1.27 cw(c0,0) 0,1.27
Mechanical 1:
  lines w0.2: 0,-1.27 0,1.27

## CN_TC2030-IDC_6-pin_ISP_Connector [mm] "TC2030-IDC-10 6-Pin Tag-Connect Plug-of-Nails(tm) Legged Spring-Pin Cable with Ribbon; Tag-Connect"
pads (13):
  round 2.4 hole 2.4 unplated: 0(-1.27,-1.905) 0(-1.27,3.175) 0(1.905,-1.905) 0(1.905,3.175)
  round 1 hole 1 unplated: 0(-1.27,0.635) 0(3.81,-0.381) 0(3.81,1.651)
  round 0.8 smd paste-1: 1(0,0) 2(0,1.27) 3(1.27,0) 4(1.27,1.27) 5(2.54,0) 6(2.54,1.27)

## CN_Terminal Block - 3.5mm; 3 pin - duplicate [mm] "3pin; Terminal Block Connector; 5.0mm pitch; Phoenix Contact; 1729021"
height 10
pads (3):
  round 2.5 hole 1.2: 1(0,0) 2(3.5,0) 3(7,0)
Top Overlay:
  lines w0.25: -2.3,-2.5 9.3,-2.5 ; -2.3,2 9.3,2 ; 0.025,-3.225 0.025,-1.65 ; 3.575,-3.225 3.575,-1.65 ; 7.025,-3.225 7.025,-1.65 ; -2.3,-3.6 9.3,-3.6 9.3,3.4 -2.3,3.4 -2.3,-3.6
3D body: height 9, standoff 0, extent -2.375,-3.675 9.475,3.4

## CN_Terminal Block - 5.0mm; 2 pin [mm] "2pin; Terminal Block Connector; 5.0mm pitch; Phoenix Contact; 1729018"
height 10
pads (2):
  round 2.5 hole 1.4: 1(0,0) 2(5,0)
Top Overlay:
  rectangle: -2.5,-3.8 7.5,-2.55
  lines w0.25: -2.5,-2.5 7.5,-2.5 ; -2.5,2 7.5,2 ; -2.5,-3.8 7.5,-3.8 7.5,4 -2.5,4 -2.5,-3.8
M13_Assembly_Info:
  circle w0.25: c0,0 r1.95
  circle w0.25: c5,0 r1.95
  lines w0.25: -1.556,-1.167 1.167,1.556 ; -1.149,-1.573 1.573,1.149 ; 3.427,-1.149 6.149,1.573 ; 3.833,-1.556 6.556,1.167
3D body: height 9, standoff 0, extent -2.375,-3.675 7.375,3.875

## CN_Terminal Block - 5.0mm; 3 pin [mm] "3pin; Terminal Block Connector; 5.0mm pitch; Phoenix Contact; 1729021"
height 10
pads (3):
  round 2.5 hole 1.4: 1(0,0) 2(5,0) 3(10,0)
Top Overlay:
  rectangle: -2.5,-3.8 12.5,-2.525
  lines w0.25: -2.5,-2.5 12.5,-2.5 ; -2.5,2 12.5,2 ; -2.5,-3.8 12.5,-3.8 12.5,4 -2.5,4 -2.5,-3.8
M13_Assembly_Info:
  circle w0.25: c10,0 r1.95
  circle w0.25: c0,0 r1.95
  circle w0.25: c5,0 r1.95
  lines w0.25: -1.556,-1.167 1.167,1.556 ; -1.149,-1.573 1.573,1.149 ; 3.427,-1.149 6.149,1.573 ; 3.833,-1.556 6.556,1.167 ; 8.427,-1.149 11.149,1.573 ; 8.833,-1.556 11.556,1.167
3D body: height 9, standoff 0, extent -2.375,-3.675 12.375,3.875

## CN_UNI-DS6-MCU Connector [mil] "MCU Connector for UNI-DS6 Board from Mikroelektronika"
height 329.92
pads (160):
  rect 65x65 hole 39.37: 1(0,0) 81(1900,0)
  round 65 hole 39.37: 2(100,0) 3(0,-100) 4(100,-100) 5(0,-200) 6(100,-200) 7(0,-300) 8(100,-300) 9(0,-400) 10(100,-400) 11(0,-500) 12(100,-500) 13(0,-600) 14(100,-600) 15(0,-700) 16(100,-700) 17(0,-800) 18(100,-800) 19(0,-900) 20(100,-900) 21(0,-1000) 22(100,-1000) 23(0,-1100) 24(100,-1100) 25(0,-1200) 26(100,-1200) 27(0,-1300) 28(100,-1300) 29(0,-1400) 30(100,-1400) 31(0,-1500) 32(100,-1500) 33(0,-1600) 34(100,-1600) 35(0,-1700) 36(100,-1700) 37(0,-1800) 38(100,-1800) 39(0,-1900) 40(100,-1900) 41(0,-2000) 42(100,-2000) 43(0,-2100) 44(100,-2100) 45(0,-2200) 46(100,-2200) 47(0,-2300) 48(100,-2300) 49(0,-2400) 50(100,-2400) 51(0,-2500) 52(100,-2500) 53(0,-2600) 54(100,-2600) 55(0,-2700) 56(100,-2700) 57(0,-2800) 58(100,-2800) 59(0,-2900) 60(100,-2900) 61(0,-3000) 62(100,-3000) 63(0,-3100) 64(100,-3100) 65(0,-3200) 66(100,-3200) 67(0,-3300) 68(100,-3300) 69(0,-3400) 70(100,-3400) 71(0,-3500) 72(100,-3500) 73(0,-3600) 74(100,-3600) 75(0,-3700) 76(100,-3700) 77(0,-3800) 78(100,-3800) 79(0,-3900) 80(100,-3900) 82(2000,0) 83(1900,-100) 84(2000,-100) 85(1900,-200) 86(2000,-200) 87(1900,-300) 88(2000,-300) 89(1900,-400) 90(2000,-400) 91(1900,-500) 92(2000,-500) 93(1900,-600) 94(2000,-600) 95(1900,-700) 96(2000,-700) 97(1900,-800) 98(2000,-800) 99(1900,-900) 100(2000,-900) 101(1900,-1000) 102(2000,-1000) 103(1900,-1100) 104(2000,-1100) 105(1900,-1200) 106(2000,-1200) 107(1900,-1300) 108(2000,-1300) 109(1900,-1400) 110(2000,-1400) 111(1900,-1500) 112(2000,-1500) 113(1900,-1600) 114(2000,-1600) 115(1900,-1700) 116(2000,-1700) 117(1900,-1800) 118(2000,-1800) 119(1900,-1900) 120(2000,-1900) 121(1900,-2000) 122(2000,-2000) 123(1900,-2100) 124(2000,-2100) 125(1900,-2200) 126(2000,-2200) 127(1900,-2300) 128(2000,-2300) 129(1900,-2400) 130(2000,-2400) 131(1900,-2500) 132(2000,-2500) 133(1900,-2600) 134(2000,-2600) 135(1900,-2700) 136(2000,-2700) 137(1900,-2800) 138(2000,-2800) 139(1900,-2900) 140(2000,-2900) 141(1900,-3000) 142(2000,-3000) 143(1900,-3100) 144(2000,-3100) 145(1900,-3200) 146(2000,-3200) 147(1900,-3300) 148(2000,-3300) 149(1900,-3400) 150(2000,-3400) 151(1900,-3500) 152(2000,-3500) 153(1900,-3600) 154(2000,-3600) 155(1900,-3700) 156(2000,-3700) 157(1900,-3800) 158(2000,-3800) 159(1900,-3900) 160(2000,-3900)
Top Overlay:
  lines w7.87: -50,-3950.39 -50,-1750 -50,50 150,50 150,-1750 150,-3950.39 -50,-3950.39 ; 1850,-3950.39 2050,-3950.39 2050,-1750 2050,50 1850,50 1850,-1750 1850,-3950.39

## CN_USB-PLUG A [mm] "Connector; USB2.0, Type A, Thru-Hole; 4 Position; Right Angle"
pads (8):
  round 1 hole 1 unplated: 0(1.25,2.1) 0(5.75,2.1)
  round 1.4 hole 0.8: 1(0,0) 2(2.5,0) 3(4.5,0) 4(7,0)
  oval 1.7x3.2 hole 1 slot 2.5 at 90 deg: 5(9.2,2.1) 6(-2.2,2.1)
Top Overlay:
  lines w0.2: -2.1,4.115 -2.1,4.825 ; -2.1,4.835 9.1,4.835 ; 9.1,4.115 9.1,4.825
M13_Assembly_Info:
  lines w0.2: -2.55,19.555 9.45,19.555 ; -2.55,19.555 -2.55,19.555 ; -2.55,19.555 -2.55,1.225 9.45,1.225 9.45,19.555 ; 9.45,19.555 9.45,19.555
3D body: height 1.88, standoff -2.62, extent -2.55,1.225 9.45,19.555

## CN_USB-PLUG A for TTL cable [mm] "Connector; USB2.0, Type A, Thru-Hole; 4 Position; Right Angle"
pads (8):
  round 1 hole 1 unplated: 0(1.25,2) 0(5.75,2)
  round 1.4 hole 0.8: 1(0,0) 2(2.5,0) 3(4.5,0) 4(7,0)
  oval 1.2x2.5 hole 0.4: 5(8.5,2) 6(-1.5,2)
Top Overlay:
  lines w0.2: -2.1,3.5 -2.1,4.71 9.1,4.71 9.1,3.5

## CN_USB-SKT A [mm] "Connector; USB2.0, Type A, Thru-Hole; 4 Position; Right Angle"
pads (6):
  round 1.7 hole 1: 1(-0.01,0) 2(2.49,0) 3(4.49,0) 4(6.99,0)
  round 3.5 hole 2.3: 5(-3.08,-2.7) 6(10.04,-2.7)
Top Overlay:
  lines w0.2: -3.08,-4.75 -3.08,-12.98 10.02,-12.98 10.02,-4.75 ; -3.08,-0.75 -3.08,1.2 10.02,1.2 10.02,-0.75
M13_Assembly_Info:
  lines w0.1: -3.5,-12.975 10.55,-12.975 ; -3.075,1.025 -3.075,-12.95 -3.05,-12.975 10,-12.975 10,1.05 -3.05,1.05
3D body: height 7.57, standoff -3.28, extent -4.425,-13.035 11.375,1.125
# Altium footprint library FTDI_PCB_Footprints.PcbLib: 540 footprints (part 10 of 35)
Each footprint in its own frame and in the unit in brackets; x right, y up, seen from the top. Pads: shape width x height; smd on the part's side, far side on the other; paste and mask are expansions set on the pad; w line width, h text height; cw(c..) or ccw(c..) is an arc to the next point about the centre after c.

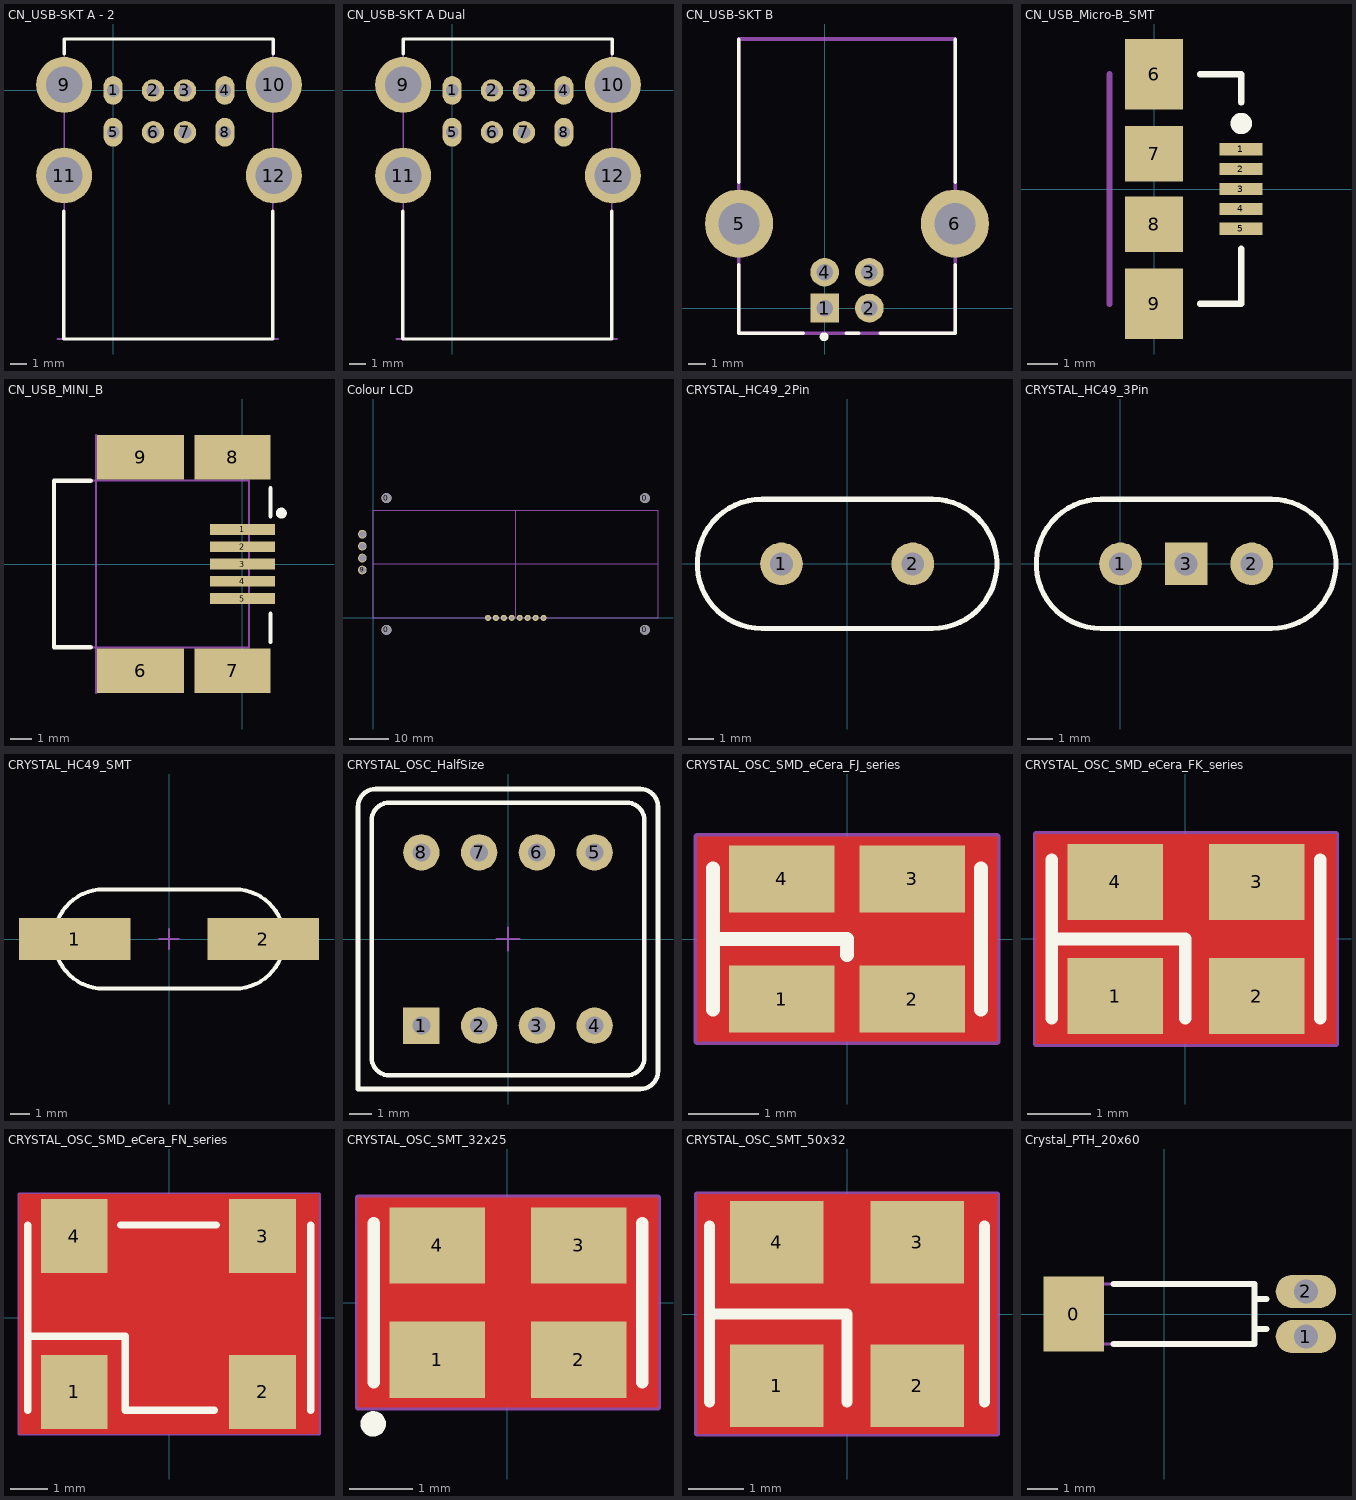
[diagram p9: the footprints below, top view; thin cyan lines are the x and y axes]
## CN_USB-SKT A - 2 [mm] "Connector; USB2.0, Type A, Thru-Hole; 4 Position; Right Angle"
pads (12):
  oval 1.2x1.8 hole 0.8: 1(0,0) 4(7,0) 5(0,-2.62) 8(7,-2.62)
  round 1.4 hole 0.8: 2(2.5,0) 3(4.5,0) 6(2.5,-2.62) 7(4.5,-2.62)
  round 3.5 hole 2.3: 9(-3.07,0.35) 10(10.07,0.35) 11(-3.07,-5.33) 12(10.07,-5.33)
Top Overlay:
  lines w0.2: -3.095,-7.55 -3.095,-15.575 10.005,-15.575 10.005,-7.55 ; -3.07,2.3 -3.07,3.225 10.03,3.225 10.03,2.3
M13_Assembly_Info:
  lines w0.1: -3.5,-15.575 10.35,-15.575 ; -3.065,-15.575 10.01,-15.575 10.01,3.225 -3.065,3.225 -3.065,-15.575
3D body: height 16.17, standoff -3.97, extent -4.659,-15.58 11.58,1.6

## CN_USB-SKT A Dual [mm] "Connector; USB2.0, Type A, Thru-Hole; 4 Position; Right Angle"
pads (12):
  oval 1.2x1.8 hole 0.8: 1(0,0) 4(7,0) 5(0,-2.62) 8(7,-2.62)
  round 1.4 hole 0.8: 2(2.5,0) 3(4.5,0) 6(2.5,-2.62) 7(4.5,-2.62)
  round 3.5 hole 2.3: 9(-3.07,0.35) 10(10.07,0.35) 11(-3.07,-5.33) 12(10.07,-5.33)
Top Overlay:
  lines w0.2: -3.095,-7.55 -3.095,-15.575 10.005,-15.575 10.005,-7.55 ; -3.07,2.3 -3.07,3.225 10.03,3.225 10.03,2.3
M13_Assembly_Info:
  lines w0.1: -3.5,-15.575 10.35,-15.575 ; -3.065,-15.575 10.01,-15.575 10.01,3.225 -3.065,3.225 -3.065,-15.575
3D body: height 0, standoff 0, extent -3.075,-15.6 10,3.175

## CN_USB-SKT B [mm] "Connector; USB2.0, Type B, Thru-Hole; 4 Position; Right Angle"
height 10.95
pads (6):
  rect 1.6x1.6 hole 0.92: 1(0,0)
  round 1.6 hole 0.92: 2(2.5,0) 3(2.5,2) 4(0,2)
  round 3.8 hole 2.3: 5(-4.77,4.71) 6(7.27,4.71)
Top Overlay:
  circle w0.25: c-0.025,-1.6 r0.125
  lines w0.2: -4.8,2.41 -4.8,-1.4 -1.2,-1.4 ; -4.8,7.01 -4.8,14.99 ; 1.2,-1.4 1.9,-1.4 ; 3.1,-1.4 7.3,-1.4 7.3,2.41 ; 7.3,7.01 7.3,14.99
M13_Assembly_Info:
  lines w0.2: -4.8,-1.4 -4.8,15.01 7.3,15.01 7.3,-1.4 -4.8,-1.4
3D body: height 11.02, standoff -3.7, extent -6.199,-1.3 8.699,15

## CN_USB_Micro-B_SMT [mm] "USB-Micro-B connector SMT"
pads (9):
  rect 1.4x0.4 smd: 1(2.84,1.3) 2(2.84,0.65) 3(2.84,0) 4(2.84,-0.65) 5(2.84,-1.3)
  rect 1.9x2.3 smd: 6(0,3.75) 9(0,-3.75)
  rect 1.9x1.8 smd: 7(0,1.15) 8(0,-1.15)
Top Overlay:
  circle w0.5: c2.85,2.14 r0.1
  lines w0.2: 1.5,-3.75 2.85,-3.75 2.85,-1.95 ; 1.5,3.75 2.85,3.75 2.85,2.82
Mechanical 1:
  lines w0.2: -1.45,-3.75 -1.45,3.75
3D body: height 2.77, standoff -0.18, extent -2.76,-4.037 2.84,4.037

## CN_USB_MINI_B [mm] "USB Mini-B Connector"
height 5
pads (9):
  rect 3x0.5 smd: 1(0,1.6) 2(0,0.8) 3(0,0) 4(0,-0.8) 5(0,-1.6)
  rect 4x2.05 smd: 6(-4.7,-4.925) 9(-4.7,4.925)
  rect 3.5x2.05 smd: 7(-0.45,-4.925) 8(-0.45,4.925)
Top Overlay:
  circle w0.25: c1.8,2.35 r0.125
  lines w0.2: -7,-3.85 -8.7,-3.85 -8.7,3.85 -7,3.85 ; 1.3,-3.6 1.3,-2.3 ; 1.3,2.2 1.3,3.5
Mechanical 1:
  lines w0.1: -6.75,-5.95 -6.75,5.95
M13_Assembly_Info:
  lines w0.1: -8.7,-3.85 -8.7,3.85 0.3,3.85 0.3,-3.85 -8.7,-3.85
3D body: height 3.97, standoff -0.98, extent -8.35,-5.35 0.85,5.35

## Colour LCD [mm]
pads (16):
  round 2.5 hole 2.5 unplated: 0(3.3,30.1) 0(3.3,-3) 0(68.3,30.1) 0(68.3,-3)
  round 1.524 hole 0.8: 1(42.814,0) 2(40.814,0) 3(38.814,0) 4(36.814,0) 5(34.814,0) 6(32.814,0) 7(30.814,0) 8(28.814,0)
  round 2.2 hole 1.7: 9(-2.769,12.042) 10(-2.769,21.042) 11(-2.769,18.042) 12(-2.769,15.042)
M13_Assembly_Info:
  lines w0.254: 0,13.55 71.6,13.55 ; 35.8,0 35.8,27.1 ; 0,0 0,27.1 71.6,27.1 71.6,0 0,0

## CRYSTAL_HC49_2Pin [mil] "Crystal"
pads (2):
  round 65 hole 35: 1(-100,0) 2(100,0)
Top Overlay:
  lines w7.87: -129.92,-98.43 cw(c-129.92,0) -129.92,98.43 129.92,98.43 cw(c129.92,0) 129.92,-98.43 -129.92,-98.43
M13_Assembly_Info:
  lines w3.94: -130.31,-98.82 cw(c-130.31,-0.39) -130.31,98.03 129.53,98.03 cw(c129.53,-0.39) 129.53,-98.82 -130.31,-98.82
3D body: height 138.4, standoff -156.88, extent -223.43,-91.34 223.43,91.73

## CRYSTAL_HC49_3Pin [mil] "Crystal with ground pin"
pads (3):
  round 65 hole 35: 1(0,0) 2(200,0)
  rect 65x65 hole 35: 3(100,0)
Top Overlay:
  lines w7.87: -29.92,-98.43 cw(c-29.92,0) -29.92,98.43 229.92,98.43 cw(c229.92,0) 229.92,-98.43 -29.92,-98.43
M13_Assembly_Info:
  lines w3.94: -30.31,-98.82 cw(c-30.31,-0.39) -30.31,98.03 229.53,98.03 cw(c229.53,-0.39) 229.53,-98.82 -30.31,-98.82
3D body: height 138.4, standoff -156.88, extent -123.43,-91.34 323.43,91.73

## CRYSTAL_HC49_SMT [mm] "Crystal SMT"
pads (2):
  rect 5.6x2.1 smd: 1(-4.75,0) 2(4.75,0)
Top Overlay:
  lines w0.2: -3.29,-2.5 cw(c-3.29,0) -3.29,2.5 3.31,2.5 cw(c3.31,0) 3.31,-2.5 -3.29,-2.5
M13_Assembly_Info:
  lines w0.1: -3.3,-2.51 cw(c-3.3,-0.01) -3.3,2.49 3.3,2.49 cw(c3.3,-0.01) 3.3,-2.51 -3.3,-2.51
M15_Country_Yard:
  lines w0.1: -0.5,0 0.5,0 ; 0,-0.5 0,0.5
3D body: height 3.52, standoff -3.98, extent -5.665,-2.32 5.685,2.33

## CRYSTAL_OSC_HalfSize [mm] "DIP; 8 Leads; Row Spacing 7.62 mm; Pitch 2.54 mm"
height 5.33
pads (8):
  rect 1.6x1.6 hole 0.8: 1(-3.81,-3.81)
  round 1.6 hole 0.8: 2(-1.27,-3.81) 3(1.27,-3.81) 4(3.81,-3.81) 5(3.81,3.81) 6(1.27,3.81) 7(-1.27,3.81) 8(-3.81,3.81)
Top Overlay:
  lines w0.2: -6.6,-6.6 5.82,-6.6 ccw(c5.82,-5.82) 6.6,-5.82 6.6,5.82 ccw(c5.82,5.82) 5.82,6.6 -5.82,6.6 ccw(c-5.82,5.82) -6.6,5.82 -6.6,-6.6 ; -6,-5.22 ccw(c-5.22,-5.22) -5.22,-6 5.22,-6 ccw(c5.22,-5.22) 6,-5.22 6,5.22 ccw(c5.22,5.22) 5.22,6 -5.22,6 ccw(c-5.22,5.22) -6,5.22 -6,-5.22
M13_Assembly_Info:
  lines w0.1: -6.6,-6.6 5.82,-6.6 ccw(c5.82,-5.82) 6.6,-5.82 6.6,5.82 ccw(c5.82,5.82) 5.82,6.6 -5.82,6.6 ccw(c-5.82,5.82) -6.6,5.82 -6.6,-6.6
M15_Country_Yard:
  lines w0.1: -0.5,0 0.5,0 ; 0,-0.5 0,0.5
3D body: height 0, standoff 0, extent -6.6,-6.6 6.6,6.6

## CRYSTAL_OSC_SMD_eCera_FJ_series [mm] "eCera; FJ series; 3.3V CMOS; Low Jitter; Seam Sealed Crystal Clock Oscillator; 2.5x2mm"
height 0.9
pads (4):
  rect 1.5x0.95 smd: 1(-0.925,-0.85) 2(0.925,-0.85) 3(0.925,0.85) 4(-0.925,0.85)
Top Layer:
  pour cut-out: -2.125,1.45 2.125,1.45 2.125,-1.45 -2.125,-1.45
Top Overlay:
  lines w0.2: -1.9,-1 -1.9,1 ; -1.9,0 0,0 0,-0.225 ; 1.9,-1 1.9,1
M13_Assembly_Info:
  circle w0.2: c-0.95,-0.675 r0.1
  lines w0.1: -1.25,-1 -1.25,1 1.25,1 1.25,-1 -1.25,-1
M15_Country_Yard:
  lines w0.1: -0.5,0 0.5,0 ; 0,-0.5 0,0.5 ; -2.125,-1.45 2.125,-1.45 2.125,1.45 -2.125,1.45 -2.125,-1.45
3D body: height 0, standoff 0, extent -1.25,-1 1.25,1

## CRYSTAL_OSC_SMD_eCera_FK_series [mm] "eCera; FK series; 3.3V CMOS; Low Jitter; Seam Sealed Crystal Clock Oscillator; 3.2x2.5mm"
height 1
pads (4):
  rect 1.5x1.2 smd: 1(-1.1,-0.9) 2(1.125,-0.9) 3(1.125,0.9) 4(-1.1,0.9)
Top Layer:
  pour cut-out: -2.35,1.65 2.375,1.65 2.375,-1.65 -2.35,-1.65
Top Overlay:
  lines w0.2: -2.1,-1.25 -2.1,1.25 ; -2.1,0 0,0 0,-1.25 ; 2.125,-1.25 2.125,1.25
M13_Assembly_Info:
  circle w0.2: c-1.275,-0.925 r0.1
  lines w0.1: -1.6,-1.25 -1.6,1.25 1.6,1.25 1.6,-1.25 -1.6,-1.25
M15_Country_Yard:
  lines w0.1: -0.5,0 0.5,0 ; 0,-0.5 0,0.5 ; -2.35,-1.65 -2.35,1.65 2.375,1.65 2.375,-1.65 -2.35,-1.65
3D body: height 0, standoff 0, extent -1.6,-1.25 1.6,1.25

## CRYSTAL_OSC_SMD_eCera_FN_series [mm] "eCera; FN series; 3.3V CMOS; Low Jitter; Seam Sealed Crystal Clock Oscillator; 7x5mm"
height 1.4
pads (4):
  rect 1.8x2 smd: 1(-2.562,-2) 2(2.518,-2) 3(2.518,2.2) 4(-2.562,2.2)
Top Layer:
  pour cut-out: -4.05,3.325 4.025,3.325 4.025,-3.125 -4.05,-3.125
Top Overlay:
  lines w0.2: -3.812,-2.5 -3.812,2.5 ; -3.812,-0.5 -1.187,-0.5 -1.187,-2.5 1.213,-2.5 ; -1.312,2.5 1.263,2.5 ; 3.813,-2.5 3.813,2.5
M13_Assembly_Info:
  circle w0.2: c-3.487,-2.15 r0.1
  lines w0.1: -3.812,-2.5 3.813,-2.5 3.813,2.5 -3.812,2.5 -3.812,-2.5
M15_Country_Yard:
  lines w0.1: -0.5,0 0.5,0 ; 0,-0.5 0,0.5 ; -4.038,-3.125 -4.038,3.325 4.038,3.325 4.038,-3.125 -4.038,-3.125
3D body: height 0, standoff 0, extent -3.812,-2.5 3.813,2.5

## CRYSTAL_OSC_SMT_32x25 [mm] "3.3V CMOS; Low Jitter; Crystal Clock Oscillator; 3.2x2.5mm"
height 1
pads (4):
  rect 1.5x1.2 smd: 1(-1.1,-0.9) 2(1.125,-0.9) 3(1.125,0.9) 4(-1.1,0.9)
Top Layer:
  pour cut-out: -2.35,1.65 2.375,1.65 2.375,-1.65 -2.35,-1.65
Top Overlay:
  circle w0.2: c-2.11,-1.91 r0.1
  lines w0.2: -2.1,-1.25 -2.1,1.25 ; 2.125,-1.25 2.125,1.25
M13_Assembly_Info:
  circle w0.2: c-1.275,-0.925 r0.1
  lines w0.1: -1.6,-1.25 -1.6,1.25 1.6,1.25 1.6,-1.25 -1.6,-1.25
M15_Country_Yard:
  lines w0.1: -0.5,0 0.5,0 ; 0,-0.5 0,0.5 ; -2.35,-1.65 -2.35,1.65 2.375,1.65 2.375,-1.65 -2.35,-1.65
3D body: height 0, standoff 0, extent -1.6,-1.25 1.6,1.25

## CRYSTAL_OSC_SMT_50x32 [mm] "3.3V CMOS; Low Jitter; Crystal Clock Oscillator; 5.0x3.2mm"
height 1.2
pads (4):
  rect 1.7x1.5 smd: 1(-1.275,-1.3) 2(1.275,-1.3) 3(1.275,1.3) 4(-1.275,1.3)
Top Layer:
  pour cut-out: -2.725,2.175 2.725,2.175 2.725,-2.175 -2.725,-2.175
Top Overlay:
  lines w0.2: -2.5,-1.6 -2.5,1.6 ; -2.5,0 0,0 0,-1.6 ; 2.5,-1.6 2.5,1.6
M13_Assembly_Info:
  circle w0.2: c-2.15,-1.225 r0.1
  lines w0.1: -2.5,-1.6 -2.5,1.6 2.5,1.6 2.5,-1.6 -2.5,-1.6
M15_Country_Yard:
  lines w0.1: -0.5,0 0.5,0 ; 0,-0.5 0,0.5 ; -2.725,-2.175 2.725,-2.175 2.725,2.175 -2.725,2.175 -2.725,-2.175
3D body: height 0, standoff 0, extent -2.5,-1.6 2.5,1.6

## Crystal_PTH_20x60 [mm] "Tuning Fork Quartz Crystal; 32.768kHz; PTH"
height 2
pads (3):
  rect 2x2.5 smd: 0(-3,0)
  oval 2x1.1 hole 0.8: 1(4.7,-0.75) 2(4.7,0.75)
Top Overlay:
  lines w0.2: -1.68,-1 3,-1 3,1 -1.68,1 ; 3,-0.5 3.4,-0.5 ; 3,0.5 3.4,0.5
M13_Assembly_Info:
  lines w0.1: -3,-1 3,-1 3,1 -3,1 -3,-1
3D body: height 2, standoff 0, extent -3,-1 3,1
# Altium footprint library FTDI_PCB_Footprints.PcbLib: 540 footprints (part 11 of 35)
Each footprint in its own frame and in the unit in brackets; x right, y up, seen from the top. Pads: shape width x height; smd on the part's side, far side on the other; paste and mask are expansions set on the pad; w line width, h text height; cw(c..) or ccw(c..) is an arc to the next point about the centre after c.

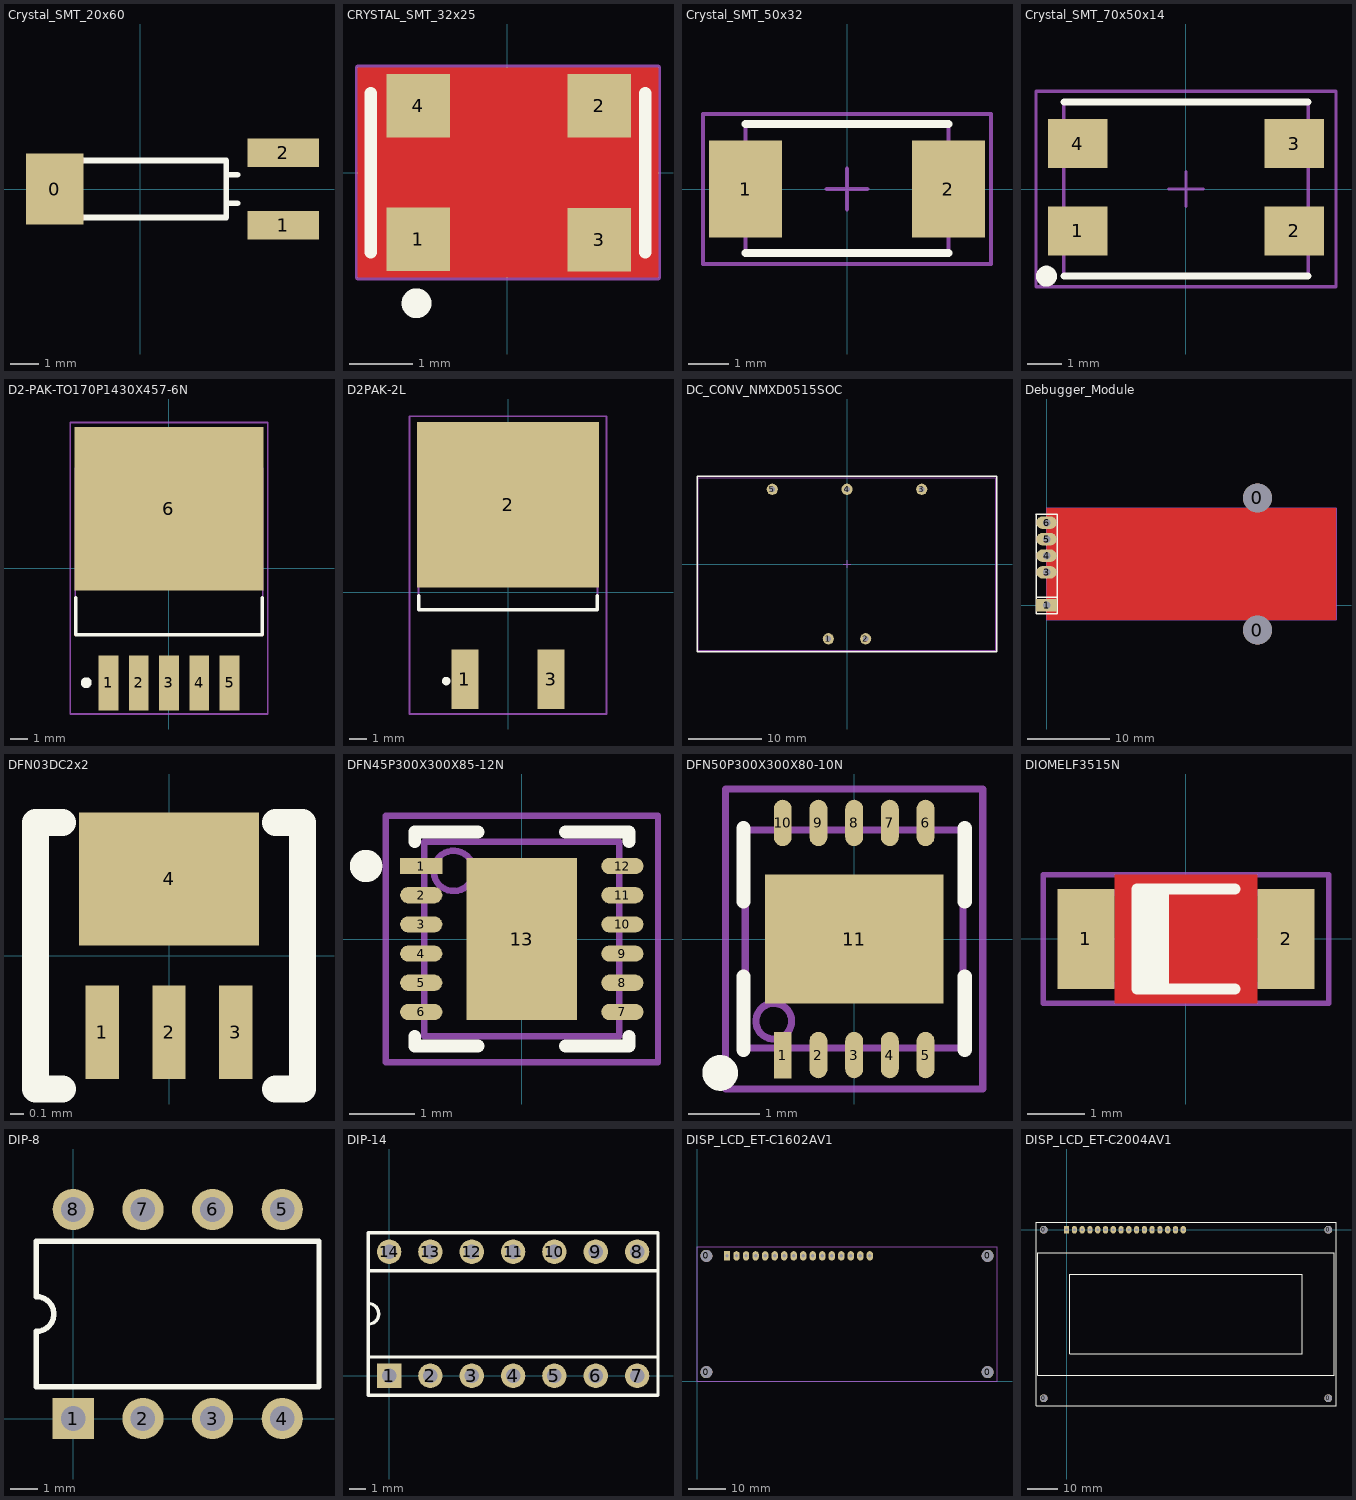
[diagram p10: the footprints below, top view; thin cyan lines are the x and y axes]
## Crystal_SMT_20x60 [mm] "Tuning Fork Quartz Crystal; 32.768kHz; SMD"
height 2
pads (3):
  rect 2x2.5 smd: 0(-3,0)
  rect 2.5x1 smd: 1(5,-1.275) 2(5,1.275)
Top Overlay:
  lines w0.2: 3,-0.5 3.4,-0.5 ; 3,0.5 3.4,0.5 ; -3,-1 -3,1 3,1 3,-1 -3,-1
M13_Assembly_Info:
  lines w0.1: -3,-1 -3,1 3,1 3,-1 -3,-1
3D body: height 2, standoff 0, extent -3,-1 3,1

## CRYSTAL_SMT_32x25 [mm] "Seam Sealed Crystal; 3.2x2.5mm"
height 1
pads (4):
  rect 1x1 smd: 1(-1.4,-1.05) 2(1.45,1.05) 3(1.45,-1.06) 4(-1.4,1.05)
Top Layer:
  pour cut-out: -2.35,1.65 2.375,1.65 2.375,-1.65 -2.35,-1.65
Top Overlay:
  circle w0.254: c-1.429,-2.057 r0.108
  lines w0.2: -2.15,-1.25 -2.15,1.25 ; 2.175,-1.25 2.175,1.25
M13_Assembly_Info:
  circle w0.2: c-1.275,-0.925 r0.1
  lines w0.1: -1.6,-1.25 -1.6,1.25 1.6,1.25 1.6,-1.25 -1.6,-1.25
M15_Country_Yard:
  lines w0.1: -0.5,0 0.5,0 ; 0,-0.5 0,0.5 ; -2.35,-1.65 -2.35,1.65 2.375,1.65 2.375,-1.65 -2.35,-1.65
3D body: height 0, standoff 0, extent -1.6,-1.25 1.6,1.25

## Crystal_SMT_50x32 [mm] "Quartz Crystal; 5.0x3.2mm"
height 1.3
pads (2):
  rect 1.8x2.4 smd: 1(-2.5,0) 2(2.5,0)
Top Overlay:
  lines w0.2: -2.5,-1.575 2.5,-1.575 ; -2.5,1.6 2.5,1.6
M13_Assembly_Info:
  lines w0.1: -2.5,-1.6 -2.5,1.6 2.5,1.6 2.5,-1.6 -2.5,-1.6
M15_Country_Yard:
  lines w0.1: -0.5,0 0.5,0 ; 0,-0.5 0,0.5 ; -3.55,-1.85 3.55,-1.85 3.55,1.85 -3.55,1.85 -3.55,-1.85
3D body: height 0, standoff 0, extent -2.5,-1.6 2.5,1.6

## Crystal_SMT_70x50x14 [mm] "Quartz Crystal; 7.0x5.0mm"
height 1.25
pads (4):
  rect 1.7x1.4 smd: 1(-3.1,-1.2) 2(3.1,-1.2) 3(3.1,1.3) 4(-3.1,1.3)
Top Overlay:
  circle w0.4: c-4,-2.5 r0.1
  lines w0.2: -3.5,-2.5 3.5,-2.5 ; -3.5,2.5 3.5,2.5
M13_Assembly_Info:
  lines w0.1: -3.5,-2.5 3.5,-2.5 3.5,2.5 -3.5,2.5 -3.5,-2.5
M15_Country_Yard:
  lines w0.1: -0.5,0 0.5,0 ; 0,-0.5 0,0.5 ; -4.3,-2.8 -4.3,2.8 4.3,2.8 4.3,-2.8 -4.3,-2.8
3D body: height 0, standoff 0, extent -3.5,-2.5 3.5,2.5

## D2-PAK-TO170P1430X457-6N [mm] "D2-PAK, 6-Pads, Body 9.4x10.5mm (max), IPC Medium Density"
height 4.572
pads (6):
  rect 1.1x3.1 smd: 1(-3.404,-6.45) 2(-1.702,-6.45) 3(0,-6.45) 4(1.702,-6.45) 5(3.404,-6.45)
  rect 10.65x9.2 smd: 6(0,3.35)
Top Overlay:
  circle w0.3: c-4.656,-6.44 r0.156
  lines w0.2: -5.25,-1.65 -5.25,-3.75 5.25,-3.75 5.25,-1.65
M13_Assembly_Info:
  lines w0.1: -5.275,-3.75 5.275,-3.75 5.275,5.65 -5.275,5.65 -5.275,-3.75
M15_Country_Yard:
  lines w0.1: -0.5,0 0.5,0 ; 0,-0.5 0,0.5 ; -5.55,-8.2 5.55,-8.2 5.55,8.2 -5.55,8.2 -5.55,-8.2
3D body: height 4.57, standoff 0.1, extent -5.275,-3.75 5.275,5.65

## D2PAK-2L [mm] "D2PAK-2L, Body 15.85x10.4x4.6mm (max)"
height 4.6
pads (3):
  rect 1.6x3.5 smd: 1(-2.54,-5.138) 3(2.54,-5.138)
  rect 10.7x9.75 smd: 2(0,5.138)
Top Overlay:
  circle w0.25: c-3.64,-5.238 r0.125
  lines w0.2: -5.25,-0.203 -5.25,-1.038 5.25,-1.038 5.25,-0.203
M13_Assembly_Info:
  lines w0.1: -5.275,-1.038 5.275,-1.038 5.275,7.962 -5.275,7.962 -5.275,-1.038
M15_Country_Yard:
  lines w0.1: -5.8,-7.176 5.8,-7.176 5.8,10.363 -5.8,10.363 -5.8,-7.176
3D body: height 4.69, standoff 0, extent -5.275,-1.038 5.275,7.962

## DC_CONV_NMXD0515SOC [mil] "Isolated 5W Regulated Dual Output DC/DC Converter"
pads (5):
  round 60 hole 30: 1(-100,-400) 2(100,-400) 3(400,400) 4(0,400) 5(-400,400)
Top Overlay:
  lines w7.87: -802.76,-468.11 802.76,-468.11 802.76,468.5 -802.76,468.5 -802.76,-468.11
M13_Assembly_Info:
  lines w3.94: -797,-462.5 797,-462.5 797,462.5 -797,462.5 -797,-462.5
M15_Country_Yard:
  lines w3.94: -19.68,0 19.68,0 ; 0,-19.68 0,19.68

## Debugger_Module [mm] "VNC2 Debugger Module"
pads (7):
  round 3.5 hole 3.5 unplated: 0(25.5,-3) 0(25.5,13)
  rect 2.5x1.5 hole 0.9: 1(0,0)
  oval 2.5x1.5 hole 0.9: 3(0,4) 4(0,6) 5(0,8) 6(0,10)
Top Layer:
  pour cut-out: 0,-1.75 35,-1.75 35,11.75 0,11.75
Top Overlay:
  lines w0.2: -1.28,11 1.26,11 ; -1.27,11 -1.27,-1 1.27,-1 1.27,11 ; -1.26,0.98 1.28,0.98
M13_Assembly_Info:
  lines w0.2: 24,-1.75 24,11.75 ; 27,-1.75 27,11.75 ; 0,-1.75 0,11.75 35,11.75 35,-1.75 0,-1.75
3D body: height 1.88, standoff 0, extent 0,-1.75 35,11.75

## DFN03DC2x2 [mm]
pads (4):
  rect 0.25x0.7 smd: 1(-0.5,-0.575) 2(0,-0.575) 3(0.5,-0.575)
  rect 1.35x1 smd: 4(0,0.575)
Top Overlay:
  lines w0.203: -0.8,-1 -1,-1 -1,1 -0.8,1 ; 0.8,-1 1,-1 1,1 0.8,1

## DFN45P300X300X85-12N [mm] "DFN, 12-Leads, Body 3.0x3.0mm (max), Pitch 0.45mm, IPC Medium Density"
height 0.85
pads (13):
  rect 0.65x0.25 smd: 1(-1.55,1.125)
  oval 0.65x0.25 smd: 2(-1.55,0.675) 3(-1.55,0.225) 4(-1.55,-0.225) 5(-1.55,-0.675) 6(-1.55,-1.125) 7(1.55,-1.125) 8(1.55,-0.675) 9(1.55,-0.225) 10(1.55,0.225) 11(1.55,0.675) 12(1.55,1.125)
  rect 1.7x2.5 smd: 13(0,0)
Top Overlay:
  circle w0.25: c-2.4,1.125 r0.125
  lines w0.2: -1.65,-1.5 -1.65,-1.65 -0.675,-1.65 ; -1.65,1.5 -1.65,1.65 -0.675,1.65 ; 0.675,-1.65 1.65,-1.65 1.65,-1.5 ; 0.675,1.65 1.65,1.65 1.65,1.5
M13_Assembly_Info:
  circle w0.1: c-1.05,1.05 r0.31
  lines w0.1: -1.5,-1.5 -1.5,1.5 1.5,1.5 1.5,-1.5 -1.5,-1.5
M15_Country_Yard:
  lines w0.1: -0.5,0 0.5,0 ; 0,-0.5 0,0.5 ; -2.1,-1.9 -2.1,1.9 2.1,1.9 2.1,-1.9 -2.1,-1.9
3D body: height 0.85, standoff 0.02, extent -1.5,-1.5 1.5,1.5

## DFN50P300X300X80-10N [mm] "DFN, 10-Leads, Body 3.0x3.0mm (max), Pitch 0.50mm, IPC Medium Density"
height 0.8
pads (11):
  rect 0.25x0.65 smd: 1(-1,-1.625)
  oval 0.25x0.65 smd: 2(-0.5,-1.625) 3(0,-1.625) 4(0.5,-1.625) 5(1,-1.625) 6(1,1.625) 7(0.5,1.625) 8(0,1.625) 9(-0.5,1.625) 10(-1,1.625)
  rect 2.5x1.8 smd paste+0: 11(0,0)
Top Overlay:
  circle w0.25: c-1.875,-1.875 r0.125
  lines w0.2: -1.55,-1.55 -1.55,-0.525 ; -1.55,0.525 -1.55,1.55 ; 1.55,-1.55 1.55,-0.525 ; 1.55,0.525 1.55,1.55
M13_Assembly_Info:
  circle w0.1: c-1.125,-1.15 r0.25
  lines w0.1: -1.525,-1.525 -1.525,1.525 1.525,1.525 1.525,-1.525 -1.525,-1.525
M15_Country_Yard:
  lines w0.1: -0.5,0 0.5,0 ; 0,-0.5 0,0.5 ; -1.8,-2.1 -1.8,2.1 1.8,2.1 1.8,-2.1 -1.8,-2.1
3D body: height 0.8, standoff 0.05, extent -1.525,-1.525 1.525,1.525

## DIOMELF3515N [mm] "MELF Diode, 2-Leads, Body 3.5x1.5mm, IPC Medium Density"
height 1.6
pads (2):
  rect 1x1.75 smd: 1(-1.75,0) 2(1.75,0)
Top Layer:
  pour cut-out: -1.25,1.125 1.25,1.125 1.25,-1.125 -1.25,-1.125
Top Overlay:
  rectangle: -0.85,-0.875 -0.3,0.875
  lines w0.2: 0.85,-0.875 -0.85,-0.875 -0.85,0.875 0.85,0.875
M13_Assembly_Info:
  rectangle: -1.85,-0.8 -1.352,0.8
  lines w0.1: -1.85,-0.8 -1.85,0.8 1.85,0.8 1.85,-0.8 -1.85,-0.8
M15_Country_Yard:
  lines w0.1: -0.5,0 0.5,0 ; 0,-0.5 0,0.5 ; -2.5,-1.125 -2.5,1.125 2.5,1.125 2.5,-1.125 -2.5,-1.125
3D body: height 1.6, standoff 0, extent -1.85,-0.8 1.85,0.8

## DIP-8 [mm] "DIP; 8 Leads; Row Spacing 7.62 mm; Pitch 2.54 mm"
height 5.33
pads (8):
  rect 1.5x1.5 hole 0.9: 1(0,0)
  round 1.5 hole 0.9: 2(2.54,0) 3(5.08,0) 4(7.62,0) 5(7.62,7.62) 6(5.08,7.62) 7(2.54,7.62) 8(0,7.62)
Top Overlay:
  lines w0.2: -1.34,1.16 8.96,1.16 8.96,6.46 -1.34,6.46 -1.34,4.445 cw(c-1.34,3.81) -1.34,3.175 -1.34,1.16

## DIP-14 [mm] "DIP; 14 Leads; Row Spacing 7.62 mm; Pitch 2.54 mm"
height 5.08
pads (14):
  rect 1.5x1.5 hole 0.9: 1(0,0)
  round 1.5 hole 0.9: 2(2.54,0) 3(5.08,0) 4(7.62,0) 5(10.16,0) 6(12.7,0) 7(15.24,0) 8(15.24,7.62) 9(12.7,7.62) 10(10.16,7.62) 11(7.62,7.62) 12(5.08,7.62) 13(2.54,7.62) 14(0,7.62)
Top Overlay:
  lines w0.2: -1.275,1.16 16.525,1.16 ; -1.275,3.175 ccw(c-1.275,3.81) -1.275,4.445 ; -1.275,6.46 16.525,6.46 ; -1.275,-1.2 -1.275,8.8 16.525,8.8 16.525,-1.2 -1.275,-1.2

## DISP_LCD_ET-C1602AV1 [mm] "LCD Module; 16x2"
height 14
pads (20):
  round 3.2 hole 3.2 unplated: 0(2.5,2.5) 0(2.5,33.5) 0(77.5,2.5) 0(77.5,33.5)
  rect 1.7x2.5 hole 0.9: 1(8,33.5)
  oval 1.7x2.5 hole 0.9: 2(10.54,33.5) 3(13.08,33.5) 4(15.62,33.5) 5(18.16,33.5) 6(20.7,33.5) 7(23.24,33.5) 8(25.78,33.5) 9(28.32,33.5) 10(30.86,33.5) 11(33.4,33.5) 12(35.94,33.5) 13(38.48,33.5) 14(41.02,33.5) 15(43.56,33.5) 16(46.1,33.5)
M13_Assembly_Info:
  lines w0.1: 0,0 0,36 80,36 80,0 0,0
3D body: height 4.14, standoff 2.54, extent 0,0 80,36
3D body: height 11.5, standoff 1.6, extent 4.35,4.55 75.65,31.45
3D body: height 12, standoff 10, extent 7.75,11.1 72.25,24.9

## DISP_LCD_ET-C2004AV1 [mm] "LCD Module; 20x4"
height 14
pads (20):
  round 2.54 hole 2.54: 0(-7.5,-55) 0(-7.5,0) 0(85.5,-55) 0(85.5,0)
  rect 1.7x2.5 hole 0.9: 1(0,0)
  oval 1.7x2.5 hole 0.9: 2(2.54,0) 3(5.08,0) 4(7.62,0) 5(10.16,0) 6(12.7,0) 7(15.24,0) 8(17.78,0) 9(20.32,0) 10(22.86,0) 11(25.4,0) 12(27.94,0) 13(30.48,0) 14(33.02,0) 15(35.56,0) 16(38.1,0)
Top Overlay:
  lines w0.2: -10,-57.5 88,-57.5 88,2.5 -10,2.5 -10,-57.5 ; -9.5,-47.5 87.5,-47.5 87.5,-7.5 -9.5,-7.5 -9.5,-47.5 ; 1,-40.5 1,-14.5 77,-14.5 77,-40.5 1,-40.5
3D body: height 12, standoff 10, extent 1,-40.5 77,-14.5
3D body: height 11.5, standoff 1.6, extent -9.5,-47.5 87.5,-7.5
3D body: height 1.6, standoff 0, extent -10,-57.5 88,2.5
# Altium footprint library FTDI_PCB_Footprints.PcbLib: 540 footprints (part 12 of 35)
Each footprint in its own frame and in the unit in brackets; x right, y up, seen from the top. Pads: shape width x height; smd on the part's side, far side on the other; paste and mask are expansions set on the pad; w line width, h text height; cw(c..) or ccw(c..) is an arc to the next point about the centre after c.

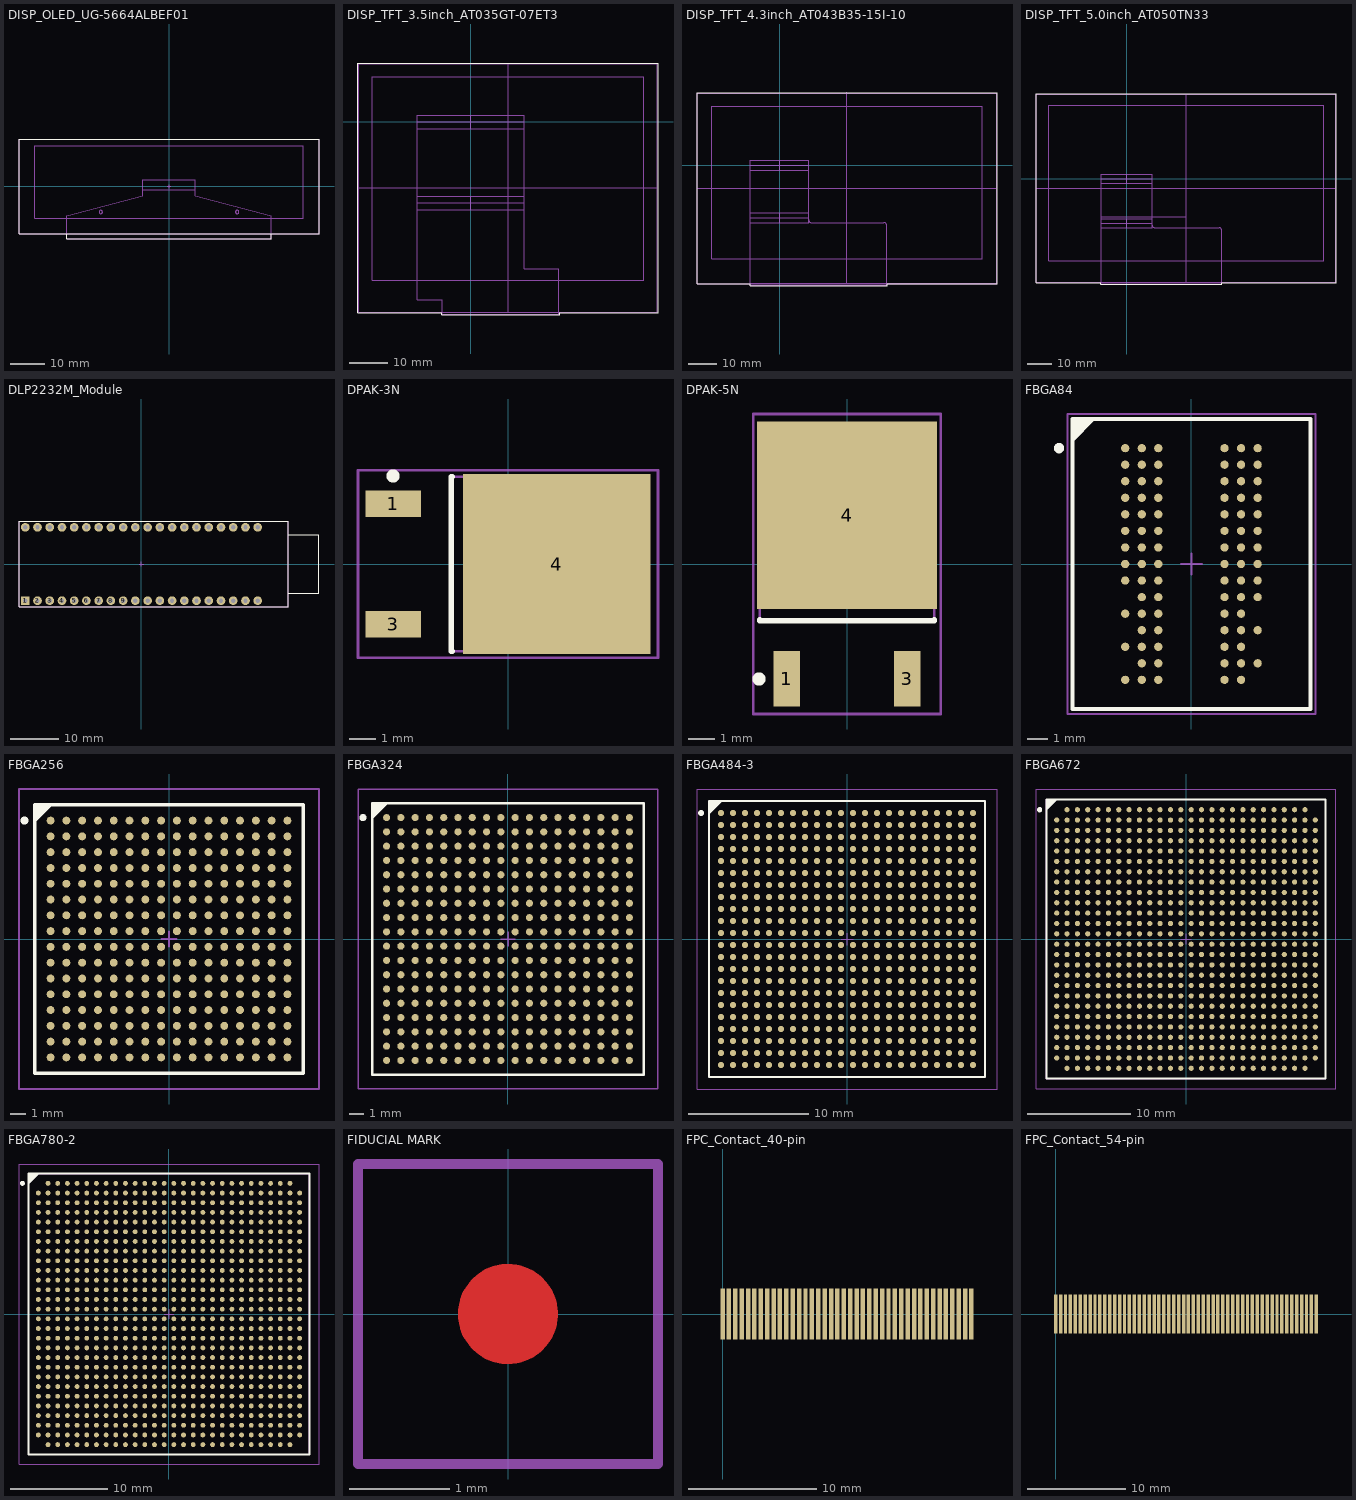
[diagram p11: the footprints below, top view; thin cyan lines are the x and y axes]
## DISP_OLED_UG-5664ALBEF01 [mm] "UG-5664ALBEF01; Folding Type; OEL Display Module; 256x64 pixels; Monochrome; COF Package"
height 4
Top Overlay:
  lines w0.2: -30,-13.9 -30,-15.4 30,-15.4 30,-13.9 ; -44,-13.9 44,-13.9 44,13.9 -44,13.9 -44,-13.9
M15_Country_Yard:
  circle w0.2: c-20,-7.5 r0.5
  circle w0.2: c20,-7.5 r0.5
  lines w0.1: -30,-8.626 -30,-13.9 -30,-15.4 30,-15.4 30,-13.9 30,-8.625 7.752,-2.66 7.752,-1 ; -29.999,-8.626 -7.748,-2.66 -7.748,-1 ; -0.55,0 0.55,0 ; 0,-0.5 0,0.5 ; -7.748,-1 7.752,-1 ; -7.748,-1 -7.748,2 7.752,2 7.752,-1 ; -44,-13.9 -44,13.9 44,13.9 44,-13.9 -44,-13.9 ; -39.4,-9.275 -39.4,11.9 39.375,11.9 39.375,-9.275 -39.4,-9.275

## DISP_TFT_3.5inch_AT035GT-07ET3 [mm] "3.5\"; TFT Display; 320x240 pixels; with Touch-pad; A-TOPS ELECTRONICS COMPANY; Part No. AT035GT-07ET3"
height 4.05
Top Overlay:
  lines w0.2: -29.1,-49.25 -7.5,-49.25 -7.5,-49.81 22.9,-49.81 22.9,-49.25 48.3,-49.25 48.3,15.15 -29.1,15.15 -29.1,-49.25
M13_Assembly_Info:
  lines w0.1: -28.95,-49.1 48.15,-49.1 48.15,15 -28.95,15 -28.95,-49.1 ; -25.44,-40.88 44.64,-40.88 44.64,11.68 -25.44,11.68 -25.44,-40.88
M15_Country_Yard:
  lines w0.1: -28.95,-17.05 48.15,-17.05 ; -13.75,-20.9 13.75,-20.9 ; -13.75,-0.1 -13.75,-45.94 -7.35,-45.94 -7.35,-49.66 22.75,-49.66 22.75,-37.94 13.75,-37.94 13.75,-1.75 ; -13.75,0 13.75,0 ; 0,-22.65 0,-19.15 ; 0,-1.75 0,1.75 ; 9.6,-49.1 9.6,15 ; 13.75,-1.75 13.75,1.75 -13.75,1.75 -13.75,-1.75 13.75,-1.75 ; -13.75,-22.65 13.75,-22.65 13.75,-19.15 -13.75,-19.15 -13.75,-22.65
  text "1" at 13.17,-23.69 h0.8
  text "54" at -13.43,-23.71 h0.8
  text "54" at -13.43,-2.81 h0.8
  text "1" at 13.17,-2.79 h0.8
  text "For TFT cable on top of the PCB" at -9.66,0.48 h0.8
  text "For TFT cable on bottom of the PCB" at -9.63,-20.51 h0.8
3D body: height 8.1, standoff 3.6, extent -28.95,-49.1 48.15,15

## DISP_TFT_4.3inch_AT043B35-15I-10 [mm] "4.3\"; TFT Display; 480x272 pixels; with Touch-pad; A-TOPS ELECTRONICS COMPANY; Part No. AT043B35-15I-10"
height 4.2
Top Overlay:
  lines w0.2: -29.14,-41.9 -29.14,25.5 76.65,25.5 76.65,-41.9 37.95,-41.9 37.95,-42.46 -10.4,-42.46 -10.4,-41.9 -29.14,-41.9
M13_Assembly_Info:
  lines w0.1: 76.49,25.35 -29,25.35 -29,-41.75 76.5,-41.75 76.5,25.35 ; -23.984,-33.062 71.416,-33.062 71.416,20.798 -23.984,20.798 -23.984,-33.062
M15_Country_Yard:
  lines w0.1: -29,-8.2 76.5,-8.2 ; -10.31,-42.31 -10.31,1.75 10.19,1.75 10.19,-16.76 ; -10.31,-41.6 37.79,-41.6 76.5,-41.6 ; -10.31,-20.25 10.19,-20.25 10.19,-16.76 ; -10.31,-18.5 10.19,-18.5 ; -10.31,-16.75 10.18,-16.75 10.19,-16.76 ; -10.31,-1.75 10.19,-1.75 ; -10.31,0 10.19,0 ; -10.25,-42.31 37.79,-42.31 37.79,-21.25 ccw(c36.79,-21.25) 36.79,-20.25 ; 0,-20.25 0,-16.75 ; 0,-1.75 0,1.75 ; 10.19,-19.25 ccw(c11.19,-19.25) 11.19,-20.25 36.8,-20.25 ; 23.75,-41.75 23.75,25.65
  text "TFT cable - straight" at -6.85,0.45 h0.8
  text "TFT cable - folded back" at -6.9,-18.05 h0.8
  text "40" at 8.7,-1.5 h0.8
  text "1" at -10,-1.5 h0.8
  text "1" at -10.1,-20.05 h0.8
  text "40" at 8.7,-20.05 h0.8
3D body: height 4.5, standoff 0.5, extent -29,-41.75 76.5,25.35

## DISP_TFT_5.0inch_AT050TN33 [mm] "5\"; TFT Display; 480x272 pixels; with Touch-pad; A-TOPS ELECTRONICS COMPANY; Part No. AT050TN33"
height 4.25
Top Overlay:
  lines w0.2: -36.55,-41.9 -10.35,-41.9 -10.35,-42.46 38.45,-42.46 38.45,-41.9 84.45,-41.9 84.45,34.2 -36.55,34.2 -36.55,-41.9
M13_Assembly_Info:
  lines w0.1: -36.4,-41.75 -36.4,34.05 84.3,34.05 84.3,-41.75 -36.4,-41.75 ; -31.44,-33.086 -31.44,29.746 79.44,29.746 79.44,-33.086 -31.44,-33.086
M15_Country_Yard:
  lines w0.1: -36.4,-3.85 84.3,-3.85 ; -10.25,-42.16 -10.25,1.75 10.25,1.75 10.25,-19.7 -10.25,-19.7 ; -10.25,-17.95 10.25,-17.95 ; -10.25,-16.2 10.25,-16.2 ; -10.25,-15.3 23.95,-15.3 ; -10.25,-1.75 10.25,-1.75 ; -10.25,0 10.25,0 ; -10.2,-42.31 38.29,-42.31 38.29,-20.7 ccw(c37.29,-20.7) 37.29,-19.7 11.25,-19.7 cw(c11.25,-18.7) 10.25,-18.7 ; 0,-1.75 0,1.75 ; 0.05,-19.7 0.05,-16.2 ; 23.5,-3.81 24.5,-3.81 ; 23.95,-41.75 23.95,34.05 ; 24,-4.31 24,-3.31
  text "TFT cable - straight" at -6.85,0.5 h0.8
  text "TFT cable - folded back" at -6.9,-17.45 h0.8
  text "1" at -9.85,-1.5 h0.8
  text "40" at 8.64,-1.47 h0.8
  text "40" at 8.64,-19.47 h0.8
  text "1" at -9.85,-19.5 h0.8
3D body: height 4.5, standoff 0.5, extent -36.4,-41.75 84.3,34.05

## DLP2232M_Module [mm] "DIP; 40 Leads; Row Spacing 15.24 mm; Pitch 2.54 mm"
height 5.59
pads (40):
  rect 1.8x1.8 hole 0.9: 1(-24.13,-7.62)
  round 1.8 hole 0.9: 2(-21.59,-7.62) 3(-19.05,-7.62) 4(-16.51,-7.62) 5(-13.97,-7.62) 6(-11.43,-7.62) 7(-8.89,-7.62) 8(-6.35,-7.62) 9(-3.81,-7.62) 10(-1.27,-7.62) 11(1.27,-7.62) 12(3.81,-7.62) 13(6.35,-7.62) 14(8.89,-7.62) 15(11.43,-7.62) 16(13.97,-7.62) 17(16.51,-7.62) 18(19.05,-7.62) 19(21.59,-7.62) 20(24.13,-7.62) 21(24.13,7.62) 22(21.59,7.62) 23(19.05,7.62) 24(16.51,7.62) 25(13.97,7.62) 26(11.43,7.62) 27(8.89,7.62) 28(6.35,7.62) 29(3.81,7.62) 30(1.27,7.62) 31(-1.27,7.62) 32(-3.81,7.62) 33(-6.35,7.62) 34(-8.89,7.62) 35(-11.43,7.62) 36(-13.97,7.62) 37(-16.51,7.62) 38(-19.05,7.62) 39(-21.59,7.62) 40(-24.13,7.62)
Top Overlay:
  lines w0.2: 30.47,-6.1 36.86,-6.1 36.86,6.1 30.47,6.1 ; -25.43,-8.9 30.47,-8.9 30.47,8.9 -25.43,8.9 -25.43,-8.9
M13_Assembly_Info:
  lines w0.1: -25.43,-8.9 -25.43,8.9 30.47,8.9 30.47,-8.9 -25.43,-8.9
M15_Country_Yard:
  lines w0.1: -0.5,0 0.5,0 ; 0,-0.5 0,0.5
3D body: height 0, standoff 0, extent -25.43,-8.9 30.47,8.9

## DPAK-3N [mm] "D-PAK, 3-Pads, Body 6.2x6.6mm (max), IPC Medium Density"
height 2.4
pads (3):
  rect 2.1x1 smd: 1(-4.35,2.28) 3(-4.35,-2.28)
  rect 7.1x6.8 smd: 4(1.85,0)
Top Overlay:
  circle w0.25: c-4.35,3.33 r0.125
  lines w0.2: -2.1,-3.3 -2.15,-3.3 -2.15,3.3 -2.1,3.3
M13_Assembly_Info:
  lines w0.1: -2.15,-3.3 4.05,-3.3 4.05,3.3 -2.15,3.3 -2.15,-3.3
M15_Country_Yard:
  lines w0.1: -0.5,0 0.5,0 ; 0,-0.5 0,0.5 ; -5.675,-3.55 5.675,-3.55 5.675,3.55 -5.675,3.55 -5.675,-3.55
3D body: height 2.4, standoff 0, extent -2.15,-3.3 4.05,3.3

## DPAK-5N [mm] "D-PAK, 5-Pins, Body 6.2x6.6mm (max), IPC Medium Density"
height 2.4
pads (3):
  rect 1x2.1 smd: 1(-2.28,-4.35) 3(2.28,-4.35)
  rect 6.8x7.1 smd: 4(0,1.85)
Top Overlay:
  circle w0.25: c-3.33,-4.35 r0.125
  lines w0.2: -3.3,-2.1 -3.3,-2.15 3.3,-2.15 3.3,-2.1
M13_Assembly_Info:
  lines w0.1: -3.3,-2.15 -3.3,4.05 3.3,4.05 3.3,-2.15 -3.3,-2.15
M15_Country_Yard:
  lines w0.1: -0.5,0 0.5,0 ; 0,-0.5 0,0.5 ; -3.55,-5.675 -3.55,5.675 3.55,5.675 3.55,-5.675 -3.55,-5.675
3D body: height 2.4, standoff 0, extent -3.3,-2.15 3.3,4.05

## FBGA84 [mm] "FBGA, 84-Leads, Body 14.0x11.5mm,  Pitch 0.80mm"
height 1.2
pads (84):
  round 0.4 smd: A1(-3.2,5.6) A2(-2.4,5.6) A3(-1.6,5.6) A7(1.6,5.6) A8(2.4,5.6) A9(3.2,5.6) B1(-3.2,4.8) B2(-2.4,4.8) B3(-1.6,4.8) B7(1.6,4.8) B8(2.4,4.8) B9(3.2,4.8) C1(-3.2,4) C2(-2.4,4) C3(-1.6,4) C7(1.6,4) C8(2.4,4) C9(3.2,4) D1(-3.2,3.2) D2(-2.4,3.2) D3(-1.6,3.2) D7(1.6,3.2) D8(2.4,3.2) D9(3.2,3.2) E1(-3.2,2.4) E2(-2.4,2.4) E3(-1.6,2.4) E7(1.6,2.4) E8(2.4,2.4) E9(3.2,2.4) F1(-3.2,1.6) F2(-2.4,1.6) F3(-1.6,1.6) F7(1.6,1.6) F8(2.4,1.6) F9(3.2,1.6) G1(-3.2,0.8) G2(-2.4,0.8) G3(-1.6,0.8) G7(1.6,0.8) G8(2.4,0.8) G9(3.2,0.8) H1(-3.2,0) H2(-2.4,0) H3(-1.6,0) H7(1.6,0) H8(2.4,0) H9(3.2,0) J1(-3.2,-0.8) J2(-2.4,-0.8) J3(-1.6,-0.8) J7(1.6,-0.8) J8(2.4,-0.8) J9(3.2,-0.8) K2(-2.4,-1.6) K3(-1.6,-1.6) K7(1.6,-1.6) K8(2.4,-1.6) K9(3.2,-1.6) L1(-3.2,-2.4) L2(-2.4,-2.4) L3(-1.6,-2.4) L7(1.6,-2.4) L8(2.4,-2.4) M2(-2.4,-3.2) M3(-1.6,-3.2) M7(1.6,-3.2) M8(2.4,-3.2) M9(3.2,-3.2) N1(-3.2,-4) N2(-2.4,-4) N3(-1.6,-4) N7(1.6,-4) N8(2.4,-4) P2(-2.4,-4.8) P3(-1.6,-4.8) P7(1.6,-4.8) P8(2.4,-4.8) P9(3.2,-4.8) R1(-3.2,-5.6) R2(-2.4,-5.6) R3(-1.6,-5.6) R7(1.6,-5.6) R8(2.4,-5.6)
Top Overlay:
  circle w0.25: c-6.4,5.6 r0.125
  region: -4.75,7 -5.75,6 -5.75,7
  lines w0.2: -5.75,6 -4.75,7 ; -5.75,-7 5.75,-7 5.75,7 -5.75,7 -5.75,-7
M13_Assembly_Info:
  lines w0.1: -5.75,-7 5.75,-7 5.75,7 -5.75,7 -5.75,-7
M15_Country_Yard:
  lines w0.1: -0.5,0 0.5,0 ; 0,-0.5 0,0.5 ; -6,-7.25 6,-7.25 6,7.25 -6,7.25 -6,-7.25
3D body: height 1.2, standoff 0.25, extent -5.75,-7 5.75,7

## FBGA256 [mm] "BGA, 256-Leads, Body 17x17mm, Pitch 1mm"
height 2.2
pads (256):
  round 0.5 smd: A1(-7.5,7.5) A2(-6.5,7.5) A3(-5.5,7.5) A4(-4.5,7.5) A5(-3.5,7.5) A6(-2.5,7.5) A7(-1.5,7.5) A8(-0.5,7.5) A9(0.5,7.5) A10(1.5,7.5) A11(2.5,7.5) A12(3.5,7.5) A13(4.5,7.5) A14(5.5,7.5) A15(6.5,7.5) A16(7.5,7.5) B1(-7.5,6.5) B2(-6.5,6.5) B3(-5.5,6.5) B4(-4.5,6.5) B5(-3.5,6.5) B6(-2.5,6.5) B7(-1.5,6.5) B8(-0.5,6.5) B9(0.5,6.5) B10(1.5,6.5) B11(2.5,6.5) B12(3.5,6.5) B13(4.5,6.5) B14(5.5,6.5) B15(6.5,6.5) B16(7.5,6.5) C1(-7.5,5.5) C2(-6.5,5.5) C3(-5.5,5.5) C4(-4.5,5.5) C5(-3.5,5.5) C6(-2.5,5.5) C7(-1.5,5.5) C8(-0.5,5.5) C9(0.5,5.5) C10(1.5,5.5) C11(2.5,5.5) C12(3.5,5.5) C13(4.5,5.5) C14(5.5,5.5) C15(6.5,5.5) C16(7.5,5.5) D1(-7.5,4.5) D2(-6.5,4.5) D3(-5.5,4.5) D4(-4.5,4.5) D5(-3.5,4.5) D6(-2.5,4.5) D7(-1.5,4.5) D8(-0.5,4.5) D9(0.5,4.5) D10(1.5,4.5) D11(2.5,4.5) D12(3.5,4.5) D13(4.5,4.5) D14(5.5,4.5) D15(6.5,4.5) D16(7.5,4.5) E1(-7.5,3.5) E2(-6.5,3.5) E3(-5.5,3.5) E4(-4.5,3.5) E5(-3.5,3.5) E6(-2.5,3.5) E7(-1.5,3.5) E8(-0.5,3.5) E9(0.5,3.5) E10(1.5,3.5) E11(2.5,3.5) E12(3.5,3.5) E13(4.5,3.5) E14(5.5,3.5) E15(6.5,3.5) E16(7.5,3.5) F1(-7.5,2.5) F2(-6.5,2.5) F3(-5.5,2.5) F4(-4.5,2.5) F5(-3.5,2.5) F6(-2.5,2.5) F7(-1.5,2.5) F8(-0.5,2.5) F9(0.5,2.5) F10(1.5,2.5) F11(2.5,2.5) F12(3.5,2.5) F13(4.5,2.5) F14(5.5,2.5) F15(6.5,2.5) F16(7.5,2.5) G1(-7.5,1.5) G2(-6.5,1.5) G3(-5.5,1.5) G4(-4.5,1.5) G5(-3.5,1.5) G6(-2.5,1.5) G7(-1.5,1.5) G8(-0.5,1.5) G9(0.5,1.5) G10(1.5,1.5) G11(2.5,1.5) G12(3.5,1.5) G13(4.5,1.5) G14(5.5,1.5) G15(6.5,1.5) G16(7.5,1.5) H1(-7.5,0.5) H2(-6.5,0.5) H3(-5.5,0.5) H4(-4.5,0.5) H5(-3.5,0.5) H6(-2.5,0.5) H7(-1.5,0.5) H8(-0.5,0.5) H9(0.5,0.5) H10(1.5,0.5) H11(2.5,0.5) H12(3.5,0.5) H13(4.5,0.5) H14(5.5,0.5) H15(6.5,0.5) H16(7.5,0.5) J1(-7.5,-0.5) J2(-6.5,-0.5) J3(-5.5,-0.5) J4(-4.5,-0.5) J5(-3.5,-0.5) J6(-2.5,-0.5) J7(-1.5,-0.5) J8(-0.5,-0.5) J9(0.5,-0.5) J10(1.5,-0.5) J11(2.5,-0.5) J12(3.5,-0.5) J13(4.5,-0.5) J14(5.5,-0.5) J15(6.5,-0.5) J16(7.5,-0.5) K1(-7.5,-1.5) K2(-6.5,-1.5) K3(-5.5,-1.5) K4(-4.5,-1.5) K5(-3.5,-1.5) K6(-2.5,-1.5) K7(-1.5,-1.5) K8(-0.5,-1.5) K9(0.5,-1.5) K10(1.5,-1.5) K11(2.5,-1.5) K12(3.5,-1.5) K13(4.5,-1.5) K14(5.5,-1.5) K15(6.5,-1.5) K16(7.5,-1.5) L1(-7.5,-2.5) L2(-6.5,-2.5) L3(-5.5,-2.5) L4(-4.5,-2.5) L5(-3.5,-2.5) L6(-2.5,-2.5) L7(-1.5,-2.5) L8(-0.5,-2.5) L9(0.5,-2.5) L10(1.5,-2.5) L11(2.5,-2.5) L12(3.5,-2.5) L13(4.5,-2.5) L14(5.5,-2.5) L15(6.5,-2.5) L16(7.5,-2.5) M1(-7.5,-3.5) M2(-6.5,-3.5) M3(-5.5,-3.5) M4(-4.5,-3.5) M5(-3.5,-3.5) M6(-2.5,-3.5) M7(-1.5,-3.5) M8(-0.5,-3.5) M9(0.5,-3.5) M10(1.5,-3.5) M11(2.5,-3.5) M12(3.5,-3.5) M13(4.5,-3.5) M14(5.5,-3.5) M15(6.5,-3.5) M16(7.5,-3.5) N1(-7.5,-4.5) N2(-6.5,-4.5) N3(-5.5,-4.5) N4(-4.5,-4.5) N5(-3.5,-4.5) N6(-2.5,-4.5) N7(-1.5,-4.5) N8(-0.5,-4.5) N9(0.5,-4.5) N10(1.5,-4.5) N11(2.5,-4.5) N12(3.5,-4.5) N13(4.5,-4.5) N14(5.5,-4.5) N15(6.5,-4.5) N16(7.5,-4.5) P1(-7.5,-5.5) P2(-6.5,-5.5) P3(-5.5,-5.5) P4(-4.5,-5.5) P5(-3.5,-5.5) P6(-2.5,-5.5) P7(-1.5,-5.5) P8(-0.5,-5.5) P9(0.5,-5.5) P10(1.5,-5.5) P11(2.5,-5.5) P12(3.5,-5.5) P13(4.5,-5.5) P14(5.5,-5.5) P15(6.5,-5.5) P16(7.5,-5.5) R1(-7.5,-6.5) R2(-6.5,-6.5) R3(-5.5,-6.5) R4(-4.5,-6.5) R5(-3.5,-6.5) R6(-2.5,-6.5) R7(-1.5,-6.5) R8(-0.5,-6.5) R9(0.5,-6.5) R10(1.5,-6.5) R11(2.5,-6.5) R12(3.5,-6.5) R13(4.5,-6.5) R14(5.5,-6.5) R15(6.5,-6.5) R16(7.5,-6.5) T1(-7.5,-7.5) T2(-6.5,-7.5) T3(-5.5,-7.5) T4(-4.5,-7.5) T5(-3.5,-7.5) T6(-2.5,-7.5) T7(-1.5,-7.5) T8(-0.5,-7.5) T9(0.5,-7.5) T10(1.5,-7.5) T11(2.5,-7.5) T12(3.5,-7.5) T13(4.5,-7.5) T14(5.5,-7.5) T15(6.5,-7.5) T16(7.5,-7.5)
Top Overlay:
  circle w0.25: c-9.15,7.5 r0.125
  region: -7.5,8.5 -8.5,7.5 -8.5,8.5
  lines w0.2: -8.5,7.5 -7.5,8.5 ; -8.5,-8.5 -8.5,8.5 8.5,8.5 8.5,-8.5 -8.5,-8.5
M13_Assembly_Info:
  lines w0.1: -8.5,-8.5 -8.5,8.5 8.5,8.5 8.5,-8.5 -8.5,-8.5
M15_Country_Yard:
  lines w0.1: -0.5,0 0.5,0 ; 0,-0.5 0,0.5 ; -9.5,-9.5 -9.5,9.5 9.5,9.5 9.5,-9.5 -9.5,-9.5
3D body: height 2.2, standoff 0, extent -8.5,-8.5 8.5,8.5

## FBGA324 [mm] "BGA, 324-Leads, Body 19x19mm, Pitch 1mm"
height 2.2
pads (324):
  round 0.5 smd: A1(-8.5,8.5) A2(-7.5,8.5) A3(-6.5,8.5) A4(-5.5,8.5) A5(-4.5,8.5) A6(-3.5,8.5) A7(-2.5,8.5) A8(-1.5,8.5) A9(-0.5,8.5) A10(0.5,8.5) A11(1.5,8.5) A12(2.5,8.5) A13(3.5,8.5) A14(4.5,8.5) A15(5.5,8.5) A16(6.5,8.5) A17(7.5,8.5) A18(8.5,8.5) B1(-8.5,7.5) B2(-7.5,7.5) B3(-6.5,7.5) B4(-5.5,7.5) B5(-4.5,7.5) B6(-3.5,7.5) B7(-2.5,7.5) B8(-1.5,7.5) B9(-0.5,7.5) B10(0.5,7.5) B11(1.5,7.5) B12(2.5,7.5) B13(3.5,7.5) B14(4.5,7.5) B15(5.5,7.5) B16(6.5,7.5) B17(7.5,7.5) B18(8.5,7.5) C1(-8.5,6.5) C2(-7.5,6.5) C3(-6.5,6.5) C4(-5.5,6.5) C5(-4.5,6.5) C6(-3.5,6.5) C7(-2.5,6.5) C8(-1.5,6.5) C9(-0.5,6.5) C10(0.5,6.5) C11(1.5,6.5) C12(2.5,6.5) C13(3.5,6.5) C14(4.5,6.5) C15(5.5,6.5) C16(6.5,6.5) C17(7.5,6.5) C18(8.5,6.5) D1(-8.5,5.5) D2(-7.5,5.5) D3(-6.5,5.5) D4(-5.5,5.5) D5(-4.5,5.5) D6(-3.5,5.5) D7(-2.5,5.5) D8(-1.5,5.5) D9(-0.5,5.5) D10(0.5,5.5) D11(1.5,5.5) D12(2.5,5.5) D13(3.5,5.5) D14(4.5,5.5) D15(5.5,5.5) D16(6.5,5.5) D17(7.5,5.5) D18(8.5,5.5) E1(-8.5,4.5) E2(-7.5,4.5) E3(-6.5,4.5) E4(-5.5,4.5) E5(-4.5,4.5) E6(-3.5,4.5) E7(-2.5,4.5) E8(-1.5,4.5) E9(-0.5,4.5) E10(0.5,4.5) E11(1.5,4.5) E12(2.5,4.5) E13(3.5,4.5) E14(4.5,4.5) E15(5.5,4.5) E16(6.5,4.5) E17(7.5,4.5) E18(8.5,4.5) F1(-8.5,3.5) F2(-7.5,3.5) F3(-6.5,3.5) F4(-5.5,3.5) F5(-4.5,3.5) F6(-3.5,3.5) F7(-2.5,3.5) F8(-1.5,3.5) F9(-0.5,3.5) F10(0.5,3.5) F11(1.5,3.5) F12(2.5,3.5) F13(3.5,3.5) F14(4.5,3.5) F15(5.5,3.5) F16(6.5,3.5) F17(7.5,3.5) F18(8.5,3.5) G1(-8.5,2.5) G2(-7.5,2.5) G3(-6.5,2.5) G4(-5.5,2.5) G5(-4.5,2.5) G6(-3.5,2.5) G7(-2.5,2.5) G8(-1.5,2.5) G9(-0.5,2.5) G10(0.5,2.5) G11(1.5,2.5) G12(2.5,2.5) G13(3.5,2.5) G14(4.5,2.5) G15(5.5,2.5) G16(6.5,2.5) G17(7.5,2.5) G18(8.5,2.5) H1(-8.5,1.5) H2(-7.5,1.5) H3(-6.5,1.5) H4(-5.5,1.5) H5(-4.5,1.5) H6(-3.5,1.5) H7(-2.5,1.5) H8(-1.5,1.5) H9(-0.5,1.5) H10(0.5,1.5) H11(1.5,1.5) H12(2.5,1.5) H13(3.5,1.5) H14(4.5,1.5) H15(5.5,1.5) H16(6.5,1.5) H17(7.5,1.5) H18(8.5,1.5) J1(-8.5,0.5) J2(-7.5,0.5) J3(-6.5,0.5) J4(-5.5,0.5) J5(-4.5,0.5) J6(-3.5,0.5) J7(-2.5,0.5) J8(-1.5,0.5) J9(-0.5,0.5) J10(0.5,0.5) J11(1.5,0.5) J12(2.5,0.5) J13(3.5,0.5) J14(4.5,0.5) J15(5.5,0.5) J16(6.5,0.5) J17(7.5,0.5) J18(8.5,0.5) K1(-8.5,-0.5) K2(-7.5,-0.5) K3(-6.5,-0.5) K4(-5.5,-0.5) K5(-4.5,-0.5) K6(-3.5,-0.5) K7(-2.5,-0.5) K8(-1.5,-0.5) K9(-0.5,-0.5) K10(0.5,-0.5) K11(1.5,-0.5) K12(2.5,-0.5) K13(3.5,-0.5) K14(4.5,-0.5) K15(5.5,-0.5) K16(6.5,-0.5) K17(7.5,-0.5) K18(8.5,-0.5) L1(-8.5,-1.5) L2(-7.5,-1.5) L3(-6.5,-1.5) L4(-5.5,-1.5) L5(-4.5,-1.5) L6(-3.5,-1.5) L7(-2.5,-1.5) L8(-1.5,-1.5) L9(-0.5,-1.5) L10(0.5,-1.5) L11(1.5,-1.5) L12(2.5,-1.5) L13(3.5,-1.5) L14(4.5,-1.5) L15(5.5,-1.5) L16(6.5,-1.5) L17(7.5,-1.5) L18(8.5,-1.5) M1(-8.5,-2.5) M2(-7.5,-2.5) M3(-6.5,-2.5) M4(-5.5,-2.5) M5(-4.5,-2.5) M6(-3.5,-2.5) M7(-2.5,-2.5) M8(-1.5,-2.5) M9(-0.5,-2.5) M10(0.5,-2.5) M11(1.5,-2.5) M12(2.5,-2.5) M13(3.5,-2.5) M14(4.5,-2.5) M15(5.5,-2.5) M16(6.5,-2.5) M17(7.5,-2.5) M18(8.5,-2.5) N1(-8.5,-3.5) N2(-7.5,-3.5) N3(-6.5,-3.5) N4(-5.5,-3.5) N5(-4.5,-3.5) N6(-3.5,-3.5) N7(-2.5,-3.5) N8(-1.5,-3.5) N9(-0.5,-3.5) N10(0.5,-3.5) N11(1.5,-3.5) N12(2.5,-3.5) N13(3.5,-3.5) N14(4.5,-3.5) N15(5.5,-3.5) N16(6.5,-3.5) N17(7.5,-3.5) N18(8.5,-3.5) P1(-8.5,-4.5) P2(-7.5,-4.5) P3(-6.5,-4.5) P4(-5.5,-4.5) P5(-4.5,-4.5) P6(-3.5,-4.5) P7(-2.5,-4.5) P8(-1.5,-4.5) P9(-0.5,-4.5) P10(0.5,-4.5) P11(1.5,-4.5) P12(2.5,-4.5) P13(3.5,-4.5) P14(4.5,-4.5) P15(5.5,-4.5) P16(6.5,-4.5) P17(7.5,-4.5) P18(8.5,-4.5) R1(-8.5,-5.5) R2(-7.5,-5.5) R3(-6.5,-5.5) R4(-5.5,-5.5) R5(-4.5,-5.5) R6(-3.5,-5.5) R7(-2.5,-5.5) R8(-1.5,-5.5) R9(-0.5,-5.5) R10(0.5,-5.5) R11(1.5,-5.5) R12(2.5,-5.5) R13(3.5,-5.5) R14(4.5,-5.5) R15(5.5,-5.5) R16(6.5,-5.5) R17(7.5,-5.5) R18(8.5,-5.5) T1(-8.5,-6.5) T2(-7.5,-6.5) T3(-6.5,-6.5) T4(-5.5,-6.5) T5(-4.5,-6.5) T6(-3.5,-6.5) T7(-2.5,-6.5) T8(-1.5,-6.5) T9(-0.5,-6.5) T10(0.5,-6.5) T11(1.5,-6.5) T12(2.5,-6.5) T13(3.5,-6.5) T14(4.5,-6.5) T15(5.5,-6.5) T16(6.5,-6.5) T17(7.5,-6.5) T18(8.5,-6.5) U1(-8.5,-7.5) U2(-7.5,-7.5) U3(-6.5,-7.5) U4(-5.5,-7.5) U5(-4.5,-7.5) U6(-3.5,-7.5) U7(-2.5,-7.5) U8(-1.5,-7.5) U9(-0.5,-7.5) U10(0.5,-7.5) U11(1.5,-7.5) U12(2.5,-7.5) U13(3.5,-7.5) U14(4.5,-7.5) U15(5.5,-7.5) U16(6.5,-7.5) U17(7.5,-7.5) U18(8.5,-7.5) V1(-8.5,-8.5) V2(-7.5,-8.5) V3(-6.5,-8.5) V4(-5.5,-8.5) V5(-4.5,-8.5) V6(-3.5,-8.5) V7(-2.5,-8.5) V8(-1.5,-8.5) V9(-0.5,-8.5) V10(0.5,-8.5) V11(1.5,-8.5) V12(2.5,-8.5) V13(3.5,-8.5) V14(4.5,-8.5) V15(5.5,-8.5) V16(6.5,-8.5) V17(7.5,-8.5) V18(8.5,-8.5)
Top Overlay:
  circle w0.25: c-10.15,8.5 r0.125
  region: -8.5,9.5 -9.5,8.5 -9.5,9.5
  lines w0.2: -9.5,8.5 -8.5,9.5 ; -9.5,-9.5 -9.5,9.5 9.5,9.5 9.5,-9.5 -9.5,-9.5
M13_Assembly_Info:
  lines w0.1: -9.5,-9.5 -9.5,9.5 9.5,9.5 9.5,-9.5 -9.5,-9.5
M15_Country_Yard:
  lines w0.1: -0.5,0 0.5,0 ; 0,-0.5 0,0.5 ; -10.5,-10.5 -10.5,10.5 10.5,10.5 10.5,-10.5 -10.5,-10.5
3D body: height 2.2, standoff 0, extent -9.5,-9.5 9.5,9.5

## FBGA484-3 [mm] "BGA, 484-Leads, Body 23x23mm, Pitch 1mm"
height 2.6
pads (484):
  round 0.5 smd: A1(-10.5,10.5) A2(-9.5,10.5) A3(-8.5,10.5) A4(-7.5,10.5) A5(-6.5,10.5) A6(-5.5,10.5) A7(-4.5,10.5) A8(-3.5,10.5) A9(-2.5,10.5) A10(-1.5,10.5) A11(-0.5,10.5) A12(0.5,10.5) A13(1.5,10.5) A14(2.5,10.5) A15(3.5,10.5) A16(4.5,10.5) A17(5.5,10.5) A18(6.5,10.5) A19(7.5,10.5) A20(8.5,10.5) A21(9.5,10.5) A22(10.5,10.5) AA1(-10.5,-9.5) AA2(-9.5,-9.5) AA3(-8.5,-9.5) AA4(-7.5,-9.5) AA5(-6.5,-9.5) AA6(-5.5,-9.5) AA7(-4.5,-9.5) AA8(-3.5,-9.5) AA9(-2.5,-9.5) AA10(-1.5,-9.5) AA11(-0.5,-9.5) AA12(0.5,-9.5) AA13(1.5,-9.5) AA14(2.5,-9.5) AA15(3.5,-9.5) AA16(4.5,-9.5) AA17(5.5,-9.5) AA18(6.5,-9.5) AA19(7.5,-9.5) AA20(8.5,-9.5) AA21(9.5,-9.5) AA22(10.5,-9.5) AB1(-10.5,-10.5) AB2(-9.5,-10.5) AB3(-8.5,-10.5) AB4(-7.5,-10.5) AB5(-6.5,-10.5) AB6(-5.5,-10.5) AB7(-4.5,-10.5) AB8(-3.5,-10.5) AB9(-2.5,-10.5) AB10(-1.5,-10.5) AB11(-0.5,-10.5) AB12(0.5,-10.5) AB13(1.5,-10.5) AB14(2.5,-10.5) AB15(3.5,-10.5) AB16(4.5,-10.5) AB17(5.5,-10.5) AB18(6.5,-10.5) AB19(7.5,-10.5) AB20(8.5,-10.5) AB21(9.5,-10.5) AB22(10.5,-10.5) B1(-10.5,9.5) B2(-9.5,9.5) B3(-8.5,9.5) B4(-7.5,9.5) B5(-6.5,9.5) B6(-5.5,9.5) B7(-4.5,9.5) B8(-3.5,9.5) B9(-2.5,9.5) B10(-1.5,9.5) B11(-0.5,9.5) B12(0.5,9.5) B13(1.5,9.5) B14(2.5,9.5) B15(3.5,9.5) B16(4.5,9.5) B17(5.5,9.5) B18(6.5,9.5) B19(7.5,9.5) B20(8.5,9.5) B21(9.5,9.5) B22(10.5,9.5) C1(-10.5,8.5) C2(-9.5,8.5) C3(-8.5,8.5) C4(-7.5,8.5) C5(-6.5,8.5) C6(-5.5,8.5) C7(-4.5,8.5) C8(-3.5,8.5) C9(-2.5,8.5) C10(-1.5,8.5) C11(-0.5,8.5) C12(0.5,8.5) C13(1.5,8.5) C14(2.5,8.5) C15(3.5,8.5) C16(4.5,8.5) C17(5.5,8.5) C18(6.5,8.5) C19(7.5,8.5) C20(8.5,8.5) C21(9.5,8.5) C22(10.5,8.5) D1(-10.5,7.5) D2(-9.5,7.5) D3(-8.5,7.5) D4(-7.5,7.5) D5(-6.5,7.5) D6(-5.5,7.5) D7(-4.5,7.5) D8(-3.5,7.5) D9(-2.5,7.5) D10(-1.5,7.5) D11(-0.5,7.5) D12(0.5,7.5) D13(1.5,7.5) D14(2.5,7.5) D15(3.5,7.5) D16(4.5,7.5) D17(5.5,7.5) D18(6.5,7.5) D19(7.5,7.5) D20(8.5,7.5) D21(9.5,7.5) D22(10.5,7.5) E1(-10.5,6.5) E2(-9.5,6.5) E3(-8.5,6.5) E4(-7.5,6.5) E5(-6.5,6.5) E6(-5.5,6.5) E7(-4.5,6.5) E8(-3.5,6.5) E9(-2.5,6.5) E10(-1.5,6.5) E11(-0.5,6.5) E12(0.5,6.5) E13(1.5,6.5) E14(2.5,6.5) E15(3.5,6.5) E16(4.5,6.5) E17(5.5,6.5) E18(6.5,6.5) E19(7.5,6.5) E20(8.5,6.5) E21(9.5,6.5) E22(10.5,6.5) F1(-10.5,5.5) F2(-9.5,5.5) F3(-8.5,5.5) F4(-7.5,5.5) F5(-6.5,5.5) F6(-5.5,5.5) F7(-4.5,5.5) F8(-3.5,5.5) F9(-2.5,5.5) F10(-1.5,5.5) F11(-0.5,5.5) F12(0.5,5.5) F13(1.5,5.5) F14(2.5,5.5) F15(3.5,5.5) F16(4.5,5.5) F17(5.5,5.5) F18(6.5,5.5) F19(7.5,5.5) F20(8.5,5.5) F21(9.5,5.5) F22(10.5,5.5) G1(-10.5,4.5) G2(-9.5,4.5) G3(-8.5,4.5) G4(-7.5,4.5) G5(-6.5,4.5) G6(-5.5,4.5) G7(-4.5,4.5) G8(-3.5,4.5) G9(-2.5,4.5) G10(-1.5,4.5) G11(-0.5,4.5) G12(0.5,4.5) G13(1.5,4.5) G14(2.5,4.5) G15(3.5,4.5) G16(4.5,4.5) G17(5.5,4.5) G18(6.5,4.5) G19(7.5,4.5) G20(8.5,4.5) G21(9.5,4.5) G22(10.5,4.5) H1(-10.5,3.5) H2(-9.5,3.5) H3(-8.5,3.5) H4(-7.5,3.5) H5(-6.5,3.5) H6(-5.5,3.5) H7(-4.5,3.5) H8(-3.5,3.5) H9(-2.5,3.5) H10(-1.5,3.5) H11(-0.5,3.5) H12(0.5,3.5) H13(1.5,3.5) H14(2.5,3.5) H15(3.5,3.5) H16(4.5,3.5) H17(5.5,3.5) H18(6.5,3.5) H19(7.5,3.5) H20(8.5,3.5) H21(9.5,3.5) H22(10.5,3.5) J1(-10.5,2.5) J2(-9.5,2.5) J3(-8.5,2.5) J4(-7.5,2.5) J5(-6.5,2.5) J6(-5.5,2.5) J7(-4.5,2.5) J8(-3.5,2.5) J9(-2.5,2.5) J10(-1.5,2.5) J11(-0.5,2.5) J12(0.5,2.5) J13(1.5,2.5) J14(2.5,2.5) J15(3.5,2.5) J16(4.5,2.5) J17(5.5,2.5) J18(6.5,2.5) J19(7.5,2.5) J20(8.5,2.5) J21(9.5,2.5) J22(10.5,2.5) K1(-10.5,1.5) K2(-9.5,1.5) K3(-8.5,1.5) K4(-7.5,1.5) K5(-6.5,1.5) K6(-5.5,1.5) K7(-4.5,1.5) K8(-3.5,1.5) K9(-2.5,1.5) K10(-1.5,1.5) K11(-0.5,1.5) K12(0.5,1.5) K13(1.5,1.5) K14(2.5,1.5) K15(3.5,1.5) K16(4.5,1.5) K17(5.5,1.5) K18(6.5,1.5) K19(7.5,1.5) K20(8.5,1.5) K21(9.5,1.5) K22(10.5,1.5) L1(-10.5,0.5) L2(-9.5,0.5) L3(-8.5,0.5) L4(-7.5,0.5) L5(-6.5,0.5) L6(-5.5,0.5) L7(-4.5,0.5) L8(-3.5,0.5) L9(-2.5,0.5) L10(-1.5,0.5) L11(-0.5,0.5) L12(0.5,0.5) L13(1.5,0.5) L14(2.5,0.5) L15(3.5,0.5) L16(4.5,0.5) L17(5.5,0.5) L18(6.5,0.5) L19(7.5,0.5) L20(8.5,0.5) L21(9.5,0.5) L22(10.5,0.5) M1(-10.5,-0.5) M2(-9.5,-0.5) M3(-8.5,-0.5) M4(-7.5,-0.5) M5(-6.5,-0.5) M6(-5.5,-0.5) M7(-4.5,-0.5) M8(-3.5,-0.5) M9(-2.5,-0.5) M10(-1.5,-0.5) M11(-0.5,-0.5) M12(0.5,-0.5) M13(1.5,-0.5) M14(2.5,-0.5) M15(3.5,-0.5) M16(4.5,-0.5) M17(5.5,-0.5) M18(6.5,-0.5) M19(7.5,-0.5) M20(8.5,-0.5) M21(9.5,-0.5) M22(10.5,-0.5) N1(-10.5,-1.5) N2(-9.5,-1.5) N3(-8.5,-1.5) N4(-7.5,-1.5) N5(-6.5,-1.5) N6(-5.5,-1.5) N7(-4.5,-1.5) N8(-3.5,-1.5) N9(-2.5,-1.5) N10(-1.5,-1.5) N11(-0.5,-1.5) N12(0.5,-1.5) N13(1.5,-1.5) N14(2.5,-1.5) N15(3.5,-1.5) N16(4.5,-1.5) N17(5.5,-1.5) N18(6.5,-1.5) N19(7.5,-1.5) N20(8.5,-1.5) N21(9.5,-1.5) N22(10.5,-1.5) P1(-10.5,-2.5) P2(-9.5,-2.5) P3(-8.5,-2.5) P4(-7.5,-2.5) P5(-6.5,-2.5) P6(-5.5,-2.5) P7(-4.5,-2.5) P8(-3.5,-2.5) P9(-2.5,-2.5) P10(-1.5,-2.5) P11(-0.5,-2.5) P12(0.5,-2.5) P13(1.5,-2.5) P14(2.5,-2.5) P15(3.5,-2.5) P16(4.5,-2.5) P17(5.5,-2.5) P18(6.5,-2.5) P19(7.5,-2.5) P20(8.5,-2.5) P21(9.5,-2.5) P22(10.5,-2.5) R1(-10.5,-3.5) R2(-9.5,-3.5) R3(-8.5,-3.5) R4(-7.5,-3.5) R5(-6.5,-3.5) R6(-5.5,-3.5) R7(-4.5,-3.5) R8(-3.5,-3.5) R9(-2.5,-3.5) R10(-1.5,-3.5) R11(-0.5,-3.5) R12(0.5,-3.5) R13(1.5,-3.5) R14(2.5,-3.5) R15(3.5,-3.5) R16(4.5,-3.5) R17(5.5,-3.5) R18(6.5,-3.5) R19(7.5,-3.5) R20(8.5,-3.5) R21(9.5,-3.5) R22(10.5,-3.5) T1(-10.5,-4.5) T2(-9.5,-4.5) T3(-8.5,-4.5) T4(-7.5,-4.5) T5(-6.5,-4.5) T6(-5.5,-4.5) T7(-4.5,-4.5) T8(-3.5,-4.5) T9(-2.5,-4.5) T10(-1.5,-4.5) T11(-0.5,-4.5) T12(0.5,-4.5) T13(1.5,-4.5) T14(2.5,-4.5) T15(3.5,-4.5) T16(4.5,-4.5) T17(5.5,-4.5) T18(6.5,-4.5) T19(7.5,-4.5) T20(8.5,-4.5) T21(9.5,-4.5) T22(10.5,-4.5) U1(-10.5,-5.5) U2(-9.5,-5.5) U3(-8.5,-5.5) U4(-7.5,-5.5) U5(-6.5,-5.5) U6(-5.5,-5.5) U7(-4.5,-5.5) U8(-3.5,-5.5) U9(-2.5,-5.5) U10(-1.5,-5.5) U11(-0.5,-5.5) U12(0.5,-5.5) U13(1.5,-5.5) U14(2.5,-5.5) U15(3.5,-5.5) U16(4.5,-5.5) U17(5.5,-5.5) U18(6.5,-5.5) U19(7.5,-5.5) U20(8.5,-5.5) U21(9.5,-5.5) U22(10.5,-5.5) V1(-10.5,-6.5) V2(-9.5,-6.5) V3(-8.5,-6.5) V4(-7.5,-6.5) V5(-6.5,-6.5) V6(-5.5,-6.5) V7(-4.5,-6.5) V8(-3.5,-6.5) V9(-2.5,-6.5) V10(-1.5,-6.5) V11(-0.5,-6.5) V12(0.5,-6.5) V13(1.5,-6.5) V14(2.5,-6.5) V15(3.5,-6.5) V16(4.5,-6.5) V17(5.5,-6.5) V18(6.5,-6.5) V19(7.5,-6.5) V20(8.5,-6.5) V21(9.5,-6.5) V22(10.5,-6.5) W1(-10.5,-7.5) W2(-9.5,-7.5) W3(-8.5,-7.5) W4(-7.5,-7.5) W5(-6.5,-7.5) W6(-5.5,-7.5) W7(-4.5,-7.5) W8(-3.5,-7.5) W9(-2.5,-7.5) W10(-1.5,-7.5) W11(-0.5,-7.5) W12(0.5,-7.5) W13(1.5,-7.5) W14(2.5,-7.5) W15(3.5,-7.5) W16(4.5,-7.5) W17(5.5,-7.5) W18(6.5,-7.5) W19(7.5,-7.5) W20(8.5,-7.5) W21(9.5,-7.5) W22(10.5,-7.5) Y1(-10.5,-8.5) Y2(-9.5,-8.5) Y3(-8.5,-8.5) Y4(-7.5,-8.5) Y5(-6.5,-8.5) Y6(-5.5,-8.5) Y7(-4.5,-8.5) Y8(-3.5,-8.5) Y9(-2.5,-8.5) Y10(-1.5,-8.5) Y11(-0.5,-8.5) Y12(0.5,-8.5) Y13(1.5,-8.5) Y14(2.5,-8.5) Y15(3.5,-8.5) Y16(4.5,-8.5) Y17(5.5,-8.5) Y18(6.5,-8.5) Y19(7.5,-8.5) Y20(8.5,-8.5) Y21(9.5,-8.5) Y22(10.5,-8.5)
Top Overlay:
  circle w0.25: c-12.15,10.5 r0.125
  region: -10.5,11.5 -11.5,10.5 -11.5,11.5
  lines w0.2: -11.5,10.5 -10.5,11.5 ; -11.5,-11.5 -11.5,11.5 11.5,11.5 11.5,-11.5 -11.5,-11.5
M13_Assembly_Info:
  lines w0.1: -11.5,-11.5 -11.5,11.5 11.5,11.5 11.5,-11.5 -11.5,-11.5
M15_Country_Yard:
  lines w0.1: -0.5,0 0.5,0 ; 0,-0.5 0,0.5 ; -12.5,-12.5 -12.5,12.5 12.5,12.5 12.5,-12.5 -12.5,-12.5
3D body: height 2.6, standoff 0, extent -11.5,-11.5 11.5,11.5

## FBGA672 [mm] "BGA, 672-Leads, Body 27x27mm, Pitch 1mm"
height 3.5
pads (672):
  round 0.5 smd: A2(-11.5,12.5) A3(-10.5,12.5) A4(-9.5,12.5) A5(-8.5,12.5) A6(-7.5,12.5) A7(-6.5,12.5) A8(-5.5,12.5) A9(-4.5,12.5) A10(-3.5,12.5) A11(-2.5,12.5) A12(-1.5,12.5) A13(-0.5,12.5) A14(0.5,12.5) A15(1.5,12.5) A16(2.5,12.5) A17(3.5,12.5) A18(4.5,12.5) A19(5.5,12.5) A20(6.5,12.5) A21(7.5,12.5) A22(8.5,12.5) A23(9.5,12.5) A24(10.5,12.5) A25(11.5,12.5) AA1(-12.5,-7.5) AA2(-11.5,-7.5) AA3(-10.5,-7.5) AA4(-9.5,-7.5) AA5(-8.5,-7.5) AA6(-7.5,-7.5) AA7(-6.5,-7.5) AA8(-5.5,-7.5) AA9(-4.5,-7.5) AA10(-3.5,-7.5) AA11(-2.5,-7.5) AA12(-1.5,-7.5) AA13(-0.5,-7.5) AA14(0.5,-7.5) AA15(1.5,-7.5) AA16(2.5,-7.5) AA17(3.5,-7.5) AA18(4.5,-7.5) AA19(5.5,-7.5) AA20(6.5,-7.5) AA21(7.5,-7.5) AA22(8.5,-7.5) AA23(9.5,-7.5) AA24(10.5,-7.5) AA25(11.5,-7.5) AA26(12.5,-7.5) AB1(-12.5,-8.5) AB2(-11.5,-8.5) AB3(-10.5,-8.5) AB4(-9.5,-8.5) AB5(-8.5,-8.5) AB6(-7.5,-8.5) AB7(-6.5,-8.5) AB8(-5.5,-8.5) AB9(-4.5,-8.5) AB10(-3.5,-8.5) AB11(-2.5,-8.5) AB12(-1.5,-8.5) AB13(-0.5,-8.5) AB14(0.5,-8.5) AB15(1.5,-8.5) AB16(2.5,-8.5) AB17(3.5,-8.5) AB18(4.5,-8.5) AB19(5.5,-8.5) AB20(6.5,-8.5) AB21(7.5,-8.5) AB22(8.5,-8.5) AB23(9.5,-8.5) AB24(10.5,-8.5) AB25(11.5,-8.5) AB26(12.5,-8.5) AC1(-12.5,-9.5) AC2(-11.5,-9.5) AC3(-10.5,-9.5) AC4(-9.5,-9.5) AC5(-8.5,-9.5) AC6(-7.5,-9.5) AC7(-6.5,-9.5) AC8(-5.5,-9.5) AC9(-4.5,-9.5) AC10(-3.5,-9.5) AC11(-2.5,-9.5) AC12(-1.5,-9.5) AC13(-0.5,-9.5) AC14(0.5,-9.5) AC15(1.5,-9.5) AC16(2.5,-9.5) AC17(3.5,-9.5) AC18(4.5,-9.5) AC19(5.5,-9.5) AC20(6.5,-9.5) AC21(7.5,-9.5) AC22(8.5,-9.5) AC23(9.5,-9.5) AC24(10.5,-9.5) AC25(11.5,-9.5) AC26(12.5,-9.5) AD1(-12.5,-10.5) AD2(-11.5,-10.5) AD3(-10.5,-10.5) AD4(-9.5,-10.5) AD5(-8.5,-10.5) AD6(-7.5,-10.5) AD7(-6.5,-10.5) AD8(-5.5,-10.5) AD9(-4.5,-10.5) AD10(-3.5,-10.5) AD11(-2.5,-10.5) AD12(-1.5,-10.5) AD13(-0.5,-10.5) AD14(0.5,-10.5) AD15(1.5,-10.5) AD16(2.5,-10.5) AD17(3.5,-10.5) AD18(4.5,-10.5) AD19(5.5,-10.5) AD20(6.5,-10.5) AD21(7.5,-10.5) AD22(8.5,-10.5) AD23(9.5,-10.5) AD24(10.5,-10.5) AD25(11.5,-10.5) AD26(12.5,-10.5) AE1(-12.5,-11.5) AE2(-11.5,-11.5) AE3(-10.5,-11.5) AE4(-9.5,-11.5) AE5(-8.5,-11.5) AE6(-7.5,-11.5) AE7(-6.5,-11.5) AE8(-5.5,-11.5) AE9(-4.5,-11.5) AE10(-3.5,-11.5) AE11(-2.5,-11.5) AE12(-1.5,-11.5) AE13(-0.5,-11.5) AE14(0.5,-11.5) AE15(1.5,-11.5) AE16(2.5,-11.5) AE17(3.5,-11.5) AE18(4.5,-11.5) AE19(5.5,-11.5) AE20(6.5,-11.5) AE21(7.5,-11.5) AE22(8.5,-11.5) AE23(9.5,-11.5) AE24(10.5,-11.5) AE25(11.5,-11.5) AE26(12.5,-11.5) AF2(-11.5,-12.5) AF3(-10.5,-12.5) AF4(-9.5,-12.5) AF5(-8.5,-12.5) AF6(-7.5,-12.5) AF7(-6.5,-12.5) AF8(-5.5,-12.5) AF9(-4.5,-12.5) AF10(-3.5,-12.5) AF11(-2.5,-12.5) AF12(-1.5,-12.5) AF13(-0.5,-12.5) AF14(0.5,-12.5) AF15(1.5,-12.5) AF16(2.5,-12.5) AF17(3.5,-12.5) AF18(4.5,-12.5) AF19(5.5,-12.5) AF20(6.5,-12.5) AF21(7.5,-12.5) AF22(8.5,-12.5) AF23(9.5,-12.5) AF24(10.5,-12.5) AF25(11.5,-12.5) B1(-12.5,11.5) B2(-11.5,11.5) B3(-10.5,11.5) B4(-9.5,11.5) B5(-8.5,11.5) B6(-7.5,11.5) B7(-6.5,11.5) B8(-5.5,11.5) B9(-4.5,11.5) B10(-3.5,11.5) B11(-2.5,11.5) B12(-1.5,11.5) B13(-0.5,11.5) B14(0.5,11.5) B15(1.5,11.5) B16(2.5,11.5) B17(3.5,11.5) B18(4.5,11.5) B19(5.5,11.5) B20(6.5,11.5) B21(7.5,11.5) B22(8.5,11.5) B23(9.5,11.5) B24(10.5,11.5) B25(11.5,11.5) B26(12.5,11.5) C1(-12.5,10.5) C2(-11.5,10.5) C3(-10.5,10.5) C4(-9.5,10.5) C5(-8.5,10.5) C6(-7.5,10.5) C7(-6.5,10.5) C8(-5.5,10.5) C9(-4.5,10.5) C10(-3.5,10.5) C11(-2.5,10.5) C12(-1.5,10.5) C13(-0.5,10.5) C14(0.5,10.5) C15(1.5,10.5) C16(2.5,10.5) C17(3.5,10.5) C18(4.5,10.5) C19(5.5,10.5) C20(6.5,10.5) C21(7.5,10.5) C22(8.5,10.5) C23(9.5,10.5) C24(10.5,10.5) C25(11.5,10.5) C26(12.5,10.5) D1(-12.5,9.5) D2(-11.5,9.5) D3(-10.5,9.5) D4(-9.5,9.5) D5(-8.5,9.5) D6(-7.5,9.5) D7(-6.5,9.5) D8(-5.5,9.5) D9(-4.5,9.5) D10(-3.5,9.5) D11(-2.5,9.5) D12(-1.5,9.5) D13(-0.5,9.5) D14(0.5,9.5) D15(1.5,9.5) D16(2.5,9.5) D17(3.5,9.5) D18(4.5,9.5) D19(5.5,9.5) D20(6.5,9.5) D21(7.5,9.5) D22(8.5,9.5) D23(9.5,9.5) D24(10.5,9.5) D25(11.5,9.5) D26(12.5,9.5) E1(-12.5,8.5) E2(-11.5,8.5) E3(-10.5,8.5) E4(-9.5,8.5) E5(-8.5,8.5) E6(-7.5,8.5) E7(-6.5,8.5) E8(-5.5,8.5) E9(-4.5,8.5) E10(-3.5,8.5) E11(-2.5,8.5) E12(-1.5,8.5) E13(-0.5,8.5) E14(0.5,8.5) E15(1.5,8.5) E16(2.5,8.5) E17(3.5,8.5) E18(4.5,8.5) E19(5.5,8.5) E20(6.5,8.5) E21(7.5,8.5) E22(8.5,8.5) E23(9.5,8.5) E24(10.5,8.5) E25(11.5,8.5) E26(12.5,8.5) F1(-12.5,7.5) F2(-11.5,7.5) F3(-10.5,7.5) F4(-9.5,7.5) F5(-8.5,7.5) F6(-7.5,7.5) F7(-6.5,7.5) F8(-5.5,7.5) F9(-4.5,7.5) F10(-3.5,7.5) F11(-2.5,7.5) F12(-1.5,7.5) F13(-0.5,7.5) F14(0.5,7.5) F15(1.5,7.5) F16(2.5,7.5) F17(3.5,7.5) F18(4.5,7.5) F19(5.5,7.5) F20(6.5,7.5) F21(7.5,7.5) F22(8.5,7.5) F23(9.5,7.5) F24(10.5,7.5) F25(11.5,7.5) F26(12.5,7.5) G1(-12.5,6.5) G2(-11.5,6.5) G3(-10.5,6.5) G4(-9.5,6.5) G5(-8.5,6.5) G6(-7.5,6.5) G7(-6.5,6.5) G8(-5.5,6.5) G9(-4.5,6.5) G10(-3.5,6.5) G11(-2.5,6.5) G12(-1.5,6.5) G13(-0.5,6.5) G14(0.5,6.5) G15(1.5,6.5) G16(2.5,6.5) G17(3.5,6.5) G18(4.5,6.5) G19(5.5,6.5) G20(6.5,6.5) G21(7.5,6.5) G22(8.5,6.5) G23(9.5,6.5) G24(10.5,6.5) G25(11.5,6.5) G26(12.5,6.5) H1(-12.5,5.5) H2(-11.5,5.5) H3(-10.5,5.5) H4(-9.5,5.5) H5(-8.5,5.5) H6(-7.5,5.5) H7(-6.5,5.5) H8(-5.5,5.5) H9(-4.5,5.5) H10(-3.5,5.5) H11(-2.5,5.5) H12(-1.5,5.5) H13(-0.5,5.5) H14(0.5,5.5) H15(1.5,5.5) H16(2.5,5.5) H17(3.5,5.5) H18(4.5,5.5) H19(5.5,5.5) H20(6.5,5.5) H21(7.5,5.5) H22(8.5,5.5) H23(9.5,5.5) H24(10.5,5.5) H25(11.5,5.5) H26(12.5,5.5) J1(-12.5,4.5) J2(-11.5,4.5) J3(-10.5,4.5) J4(-9.5,4.5) J5(-8.5,4.5) J6(-7.5,4.5) J7(-6.5,4.5) J8(-5.5,4.5) J9(-4.5,4.5) J10(-3.5,4.5) J11(-2.5,4.5) J12(-1.5,4.5) J13(-0.5,4.5) J14(0.5,4.5) J15(1.5,4.5) J16(2.5,4.5) J17(3.5,4.5) J18(4.5,4.5) J19(5.5,4.5) J20(6.5,4.5) J21(7.5,4.5) J22(8.5,4.5) J23(9.5,4.5) J24(10.5,4.5) J25(11.5,4.5) J26(12.5,4.5) K1(-12.5,3.5) K2(-11.5,3.5) K3(-10.5,3.5) K4(-9.5,3.5) K5(-8.5,3.5) K6(-7.5,3.5) K7(-6.5,3.5) K8(-5.5,3.5) K9(-4.5,3.5) K10(-3.5,3.5) K11(-2.5,3.5) K12(-1.5,3.5) K13(-0.5,3.5) K14(0.5,3.5) K15(1.5,3.5) K16(2.5,3.5) K17(3.5,3.5) K18(4.5,3.5) K19(5.5,3.5) K20(6.5,3.5) K21(7.5,3.5) K22(8.5,3.5) K23(9.5,3.5) K24(10.5,3.5) K25(11.5,3.5) K26(12.5,3.5) L1(-12.5,2.5) L2(-11.5,2.5) L3(-10.5,2.5) L4(-9.5,2.5) L5(-8.5,2.5) L6(-7.5,2.5) L7(-6.5,2.5) L8(-5.5,2.5) L9(-4.5,2.5) L10(-3.5,2.5) L11(-2.5,2.5) L12(-1.5,2.5) L13(-0.5,2.5) L14(0.5,2.5) L15(1.5,2.5) L16(2.5,2.5) L17(3.5,2.5) L18(4.5,2.5) L19(5.5,2.5) L20(6.5,2.5) L21(7.5,2.5) L22(8.5,2.5) L23(9.5,2.5) L24(10.5,2.5) L25(11.5,2.5) L26(12.5,2.5) M1(-12.5,1.5) M2(-11.5,1.5) M3(-10.5,1.5) M4(-9.5,1.5) M5(-8.5,1.5) M6(-7.5,1.5) M7(-6.5,1.5) M8(-5.5,1.5) M9(-4.5,1.5) M10(-3.5,1.5) M11(-2.5,1.5) M12(-1.5,1.5) M13(-0.5,1.5) M14(0.5,1.5) M15(1.5,1.5) M16(2.5,1.5) M17(3.5,1.5) M18(4.5,1.5) M19(5.5,1.5) M20(6.5,1.5) M21(7.5,1.5) M22(8.5,1.5) M23(9.5,1.5) M24(10.5,1.5) M25(11.5,1.5) M26(12.5,1.5) N1(-12.5,0.5) N2(-11.5,0.5) N3(-10.5,0.5) N4(-9.5,0.5) N5(-8.5,0.5) N6(-7.5,0.5) N7(-6.5,0.5) N8(-5.5,0.5) N9(-4.5,0.5) N10(-3.5,0.5) N11(-2.5,0.5) N12(-1.5,0.5) N13(-0.5,0.5) N14(0.5,0.5) N15(1.5,0.5) N16(2.5,0.5) N17(3.5,0.5) N18(4.5,0.5) N19(5.5,0.5) N20(6.5,0.5) N21(7.5,0.5) N22(8.5,0.5) N23(9.5,0.5) N24(10.5,0.5) N25(11.5,0.5) N26(12.5,0.5) P1(-12.5,-0.5) P2(-11.5,-0.5) P3(-10.5,-0.5) P4(-9.5,-0.5) P5(-8.5,-0.5) P6(-7.5,-0.5) P7(-6.5,-0.5) P8(-5.5,-0.5) P9(-4.5,-0.5) P10(-3.5,-0.5) P11(-2.5,-0.5) P12(-1.5,-0.5) P13(-0.5,-0.5) P14(0.5,-0.5) P15(1.5,-0.5) P16(2.5,-0.5) P17(3.5,-0.5) P18(4.5,-0.5) P19(5.5,-0.5) P20(6.5,-0.5) P21(7.5,-0.5) P22(8.5,-0.5) P23(9.5,-0.5) P24(10.5,-0.5) P25(11.5,-0.5) P26(12.5,-0.5) R1(-12.5,-1.5) R2(-11.5,-1.5) R3(-10.5,-1.5) R4(-9.5,-1.5) R5(-8.5,-1.5) R6(-7.5,-1.5) R7(-6.5,-1.5) R8(-5.5,-1.5) R9(-4.5,-1.5) R10(-3.5,-1.5) R11(-2.5,-1.5) R12(-1.5,-1.5) R13(-0.5,-1.5) R14(0.5,-1.5) R15(1.5,-1.5) R16(2.5,-1.5) R17(3.5,-1.5) R18(4.5,-1.5) R19(5.5,-1.5) R20(6.5,-1.5) R21(7.5,-1.5) R22(8.5,-1.5) R23(9.5,-1.5) R24(10.5,-1.5) R25(11.5,-1.5) R26(12.5,-1.5) T1(-12.5,-2.5) T2(-11.5,-2.5) T3(-10.5,-2.5) T4(-9.5,-2.5) T5(-8.5,-2.5) T6(-7.5,-2.5) T7(-6.5,-2.5) T8(-5.5,-2.5) T9(-4.5,-2.5) T10(-3.5,-2.5) T11(-2.5,-2.5) T12(-1.5,-2.5) T13(-0.5,-2.5) T14(0.5,-2.5) T15(1.5,-2.5) T16(2.5,-2.5) T17(3.5,-2.5) T18(4.5,-2.5) T19(5.5,-2.5) T20(6.5,-2.5) T21(7.5,-2.5) T22(8.5,-2.5) T23(9.5,-2.5) T24(10.5,-2.5) T25(11.5,-2.5) T26(12.5,-2.5) U1(-12.5,-3.5) U2(-11.5,-3.5) U3(-10.5,-3.5) U4(-9.5,-3.5) U5(-8.5,-3.5) U6(-7.5,-3.5) U7(-6.5,-3.5) U8(-5.5,-3.5) U9(-4.5,-3.5) U10(-3.5,-3.5) U11(-2.5,-3.5) U12(-1.5,-3.5) U13(-0.5,-3.5) U14(0.5,-3.5) U15(1.5,-3.5) U16(2.5,-3.5) U17(3.5,-3.5) U18(4.5,-3.5) U19(5.5,-3.5) U20(6.5,-3.5) U21(7.5,-3.5) U22(8.5,-3.5) U23(9.5,-3.5) U24(10.5,-3.5) U25(11.5,-3.5) U26(12.5,-3.5) V1(-12.5,-4.5) V2(-11.5,-4.5) V3(-10.5,-4.5) V4(-9.5,-4.5) V5(-8.5,-4.5) V6(-7.5,-4.5) V7(-6.5,-4.5) V8(-5.5,-4.5) V9(-4.5,-4.5) V10(-3.5,-4.5) V11(-2.5,-4.5) V12(-1.5,-4.5) V13(-0.5,-4.5) V14(0.5,-4.5) V15(1.5,-4.5) V16(2.5,-4.5) V17(3.5,-4.5) V18(4.5,-4.5) V19(5.5,-4.5) V20(6.5,-4.5) V21(7.5,-4.5) V22(8.5,-4.5) V23(9.5,-4.5) V24(10.5,-4.5) V25(11.5,-4.5) V26(12.5,-4.5) W1(-12.5,-5.5) W2(-11.5,-5.5) W3(-10.5,-5.5) W4(-9.5,-5.5) W5(-8.5,-5.5) W6(-7.5,-5.5) W7(-6.5,-5.5) W8(-5.5,-5.5) W9(-4.5,-5.5) W10(-3.5,-5.5) W11(-2.5,-5.5) W12(-1.5,-5.5) W13(-0.5,-5.5) W14(0.5,-5.5) W15(1.5,-5.5) W16(2.5,-5.5) W17(3.5,-5.5) W18(4.5,-5.5) W19(5.5,-5.5) W20(6.5,-5.5) W21(7.5,-5.5) W22(8.5,-5.5) W23(9.5,-5.5) W24(10.5,-5.5) W25(11.5,-5.5) W26(12.5,-5.5) Y1(-12.5,-6.5) Y2(-11.5,-6.5) Y3(-10.5,-6.5) Y4(-9.5,-6.5) Y5(-8.5,-6.5) Y6(-7.5,-6.5) Y7(-6.5,-6.5) Y8(-5.5,-6.5) Y9(-4.5,-6.5) Y10(-3.5,-6.5) Y11(-2.5,-6.5) Y12(-1.5,-6.5) Y13(-0.5,-6.5) Y14(0.5,-6.5) Y15(1.5,-6.5) Y16(2.5,-6.5) Y17(3.5,-6.5) Y18(4.5,-6.5) Y19(5.5,-6.5) Y20(6.5,-6.5) Y21(7.5,-6.5) Y22(8.5,-6.5) Y23(9.5,-6.5) Y24(10.5,-6.5) Y25(11.5,-6.5) Y26(12.5,-6.5)
Top Overlay:
  circle w0.25: c-14.15,12.5 r0.125
  region: -12.5,13.5 -13.5,12.5 -13.5,13.5
  lines w0.2: -13.5,12.5 -12.5,13.5 ; -13.5,-13.5 -13.5,13.5 13.5,13.5 13.5,-13.5 -13.5,-13.5
M13_Assembly_Info:
  lines w0.1: -13.5,-13.5 -13.5,13.5 13.5,13.5 13.5,-13.5 -13.5,-13.5
M15_Country_Yard:
  lines w0.1: -0.5,0 0.5,0 ; 0,-0.5 0,0.5 ; -14.5,-14.5 -14.5,14.5 14.5,14.5 14.5,-14.5 -14.5,-14.5
3D body: height 3.5, standoff 0, extent -13.5,-13.5 13.5,13.5

## FBGA780-2 [mm] "BGA, 780-Leads, Body 29x29mm, Pitch 1mm"
height 2.6
pads (780):
  round 0.5 smd: A2(-12.5,13.5) A3(-11.5,13.5) A4(-10.5,13.5) A5(-9.5,13.5) A6(-8.5,13.5) A7(-7.5,13.5) A8(-6.5,13.5) A9(-5.5,13.5) A10(-4.5,13.5) A11(-3.5,13.5) A12(-2.5,13.5) A13(-1.5,13.5) A14(-0.5,13.5) A15(0.5,13.5) A16(1.5,13.5) A17(2.5,13.5) A18(3.5,13.5) A19(4.5,13.5) A20(5.5,13.5) A21(6.5,13.5) A22(7.5,13.5) A23(8.5,13.5) A24(9.5,13.5) A25(10.5,13.5) A26(11.5,13.5) A27(12.5,13.5) AA1(-13.5,-6.5) AA2(-12.5,-6.5) AA3(-11.5,-6.5) AA4(-10.5,-6.5) AA5(-9.5,-6.5) AA6(-8.5,-6.5) AA7(-7.5,-6.5) AA8(-6.5,-6.5) AA9(-5.5,-6.5) AA10(-4.5,-6.5) AA11(-3.5,-6.5) AA12(-2.5,-6.5) AA13(-1.5,-6.5) AA14(-0.5,-6.5) AA15(0.5,-6.5) AA16(1.5,-6.5) AA17(2.5,-6.5) AA18(3.5,-6.5) AA19(4.5,-6.5) AA20(5.5,-6.5) AA21(6.5,-6.5) AA22(7.5,-6.5) AA23(8.5,-6.5) AA24(9.5,-6.5) AA25(10.5,-6.5) AA26(11.5,-6.5) AA27(12.5,-6.5) AA28(13.5,-6.5) AB1(-13.5,-7.5) AB2(-12.5,-7.5) AB3(-11.5,-7.5) AB4(-10.5,-7.5) AB5(-9.5,-7.5) AB6(-8.5,-7.5) AB7(-7.5,-7.5) AB8(-6.5,-7.5) AB9(-5.5,-7.5) AB10(-4.5,-7.5) AB11(-3.5,-7.5) AB12(-2.5,-7.5) AB13(-1.5,-7.5) AB14(-0.5,-7.5) AB15(0.5,-7.5) AB16(1.5,-7.5) AB17(2.5,-7.5) AB18(3.5,-7.5) AB19(4.5,-7.5) AB20(5.5,-7.5) AB21(6.5,-7.5) AB22(7.5,-7.5) AB23(8.5,-7.5) AB24(9.5,-7.5) AB25(10.5,-7.5) AB26(11.5,-7.5) AB27(12.5,-7.5) AB28(13.5,-7.5) AC1(-13.5,-8.5) AC2(-12.5,-8.5) AC3(-11.5,-8.5) AC4(-10.5,-8.5) AC5(-9.5,-8.5) AC6(-8.5,-8.5) AC7(-7.5,-8.5) AC8(-6.5,-8.5) AC9(-5.5,-8.5) AC10(-4.5,-8.5) AC11(-3.5,-8.5) AC12(-2.5,-8.5) AC13(-1.5,-8.5) AC14(-0.5,-8.5) AC15(0.5,-8.5) AC16(1.5,-8.5) AC17(2.5,-8.5) AC18(3.5,-8.5) AC19(4.5,-8.5) AC20(5.5,-8.5) AC21(6.5,-8.5) AC22(7.5,-8.5) AC23(8.5,-8.5) AC24(9.5,-8.5) AC25(10.5,-8.5) AC26(11.5,-8.5) AC27(12.5,-8.5) AC28(13.5,-8.5) AD1(-13.5,-9.5) AD2(-12.5,-9.5) AD3(-11.5,-9.5) AD4(-10.5,-9.5) AD5(-9.5,-9.5) AD6(-8.5,-9.5) AD7(-7.5,-9.5) AD8(-6.5,-9.5) AD9(-5.5,-9.5) AD10(-4.5,-9.5) AD11(-3.5,-9.5) AD12(-2.5,-9.5) AD13(-1.5,-9.5) AD14(-0.5,-9.5) AD15(0.5,-9.5) AD16(1.5,-9.5) AD17(2.5,-9.5) AD18(3.5,-9.5) AD19(4.5,-9.5) AD20(5.5,-9.5) AD21(6.5,-9.5) AD22(7.5,-9.5) AD23(8.5,-9.5) AD24(9.5,-9.5) AD25(10.5,-9.5) AD26(11.5,-9.5) AD27(12.5,-9.5) AD28(13.5,-9.5) AE1(-13.5,-10.5) AE2(-12.5,-10.5) AE3(-11.5,-10.5) AE4(-10.5,-10.5) AE5(-9.5,-10.5) AE6(-8.5,-10.5) AE7(-7.5,-10.5) AE8(-6.5,-10.5) AE9(-5.5,-10.5) AE10(-4.5,-10.5) AE11(-3.5,-10.5) AE12(-2.5,-10.5) AE13(-1.5,-10.5) AE14(-0.5,-10.5) AE15(0.5,-10.5) AE16(1.5,-10.5) AE17(2.5,-10.5) AE18(3.5,-10.5) AE19(4.5,-10.5) AE20(5.5,-10.5) AE21(6.5,-10.5) AE22(7.5,-10.5) AE23(8.5,-10.5) AE24(9.5,-10.5) AE25(10.5,-10.5) AE26(11.5,-10.5) AE27(12.5,-10.5) AE28(13.5,-10.5) AF1(-13.5,-11.5) AF2(-12.5,-11.5) AF3(-11.5,-11.5) AF4(-10.5,-11.5) AF5(-9.5,-11.5) AF6(-8.5,-11.5) AF7(-7.5,-11.5) AF8(-6.5,-11.5) AF9(-5.5,-11.5) AF10(-4.5,-11.5) AF11(-3.5,-11.5) AF12(-2.5,-11.5) AF13(-1.5,-11.5) AF14(-0.5,-11.5) AF15(0.5,-11.5) AF16(1.5,-11.5) AF17(2.5,-11.5) AF18(3.5,-11.5) AF19(4.5,-11.5) AF20(5.5,-11.5) AF21(6.5,-11.5) AF22(7.5,-11.5) AF23(8.5,-11.5) AF24(9.5,-11.5) AF25(10.5,-11.5) AF26(11.5,-11.5) AF27(12.5,-11.5) AF28(13.5,-11.5) AG1(-13.5,-12.5) AG2(-12.5,-12.5) AG3(-11.5,-12.5) AG4(-10.5,-12.5) AG5(-9.5,-12.5) AG6(-8.5,-12.5) AG7(-7.5,-12.5) AG8(-6.5,-12.5) AG9(-5.5,-12.5) AG10(-4.5,-12.5) AG11(-3.5,-12.5) AG12(-2.5,-12.5) AG13(-1.5,-12.5) AG14(-0.5,-12.5) AG15(0.5,-12.5) AG16(1.5,-12.5) AG17(2.5,-12.5) AG18(3.5,-12.5) AG19(4.5,-12.5) AG20(5.5,-12.5) AG21(6.5,-12.5) AG22(7.5,-12.5) AG23(8.5,-12.5) AG24(9.5,-12.5) AG25(10.5,-12.5) AG26(11.5,-12.5) AG27(12.5,-12.5) AG28(13.5,-12.5) AH2(-12.5,-13.5) AH3(-11.5,-13.5) AH4(-10.5,-13.5) AH5(-9.5,-13.5) AH6(-8.5,-13.5) AH7(-7.5,-13.5) AH8(-6.5,-13.5) AH9(-5.5,-13.5) AH10(-4.5,-13.5) AH11(-3.5,-13.5) AH12(-2.5,-13.5) AH13(-1.5,-13.5) AH14(-0.5,-13.5) AH15(0.5,-13.5) AH16(1.5,-13.5) AH17(2.5,-13.5) AH18(3.5,-13.5) AH19(4.5,-13.5) AH20(5.5,-13.5) AH21(6.5,-13.5) AH22(7.5,-13.5) AH23(8.5,-13.5) AH24(9.5,-13.5) AH25(10.5,-13.5) AH26(11.5,-13.5) AH27(12.5,-13.5) B1(-13.5,12.5) B2(-12.5,12.5) B3(-11.5,12.5) B4(-10.5,12.5) B5(-9.5,12.5) B6(-8.5,12.5) B7(-7.5,12.5) B8(-6.5,12.5) B9(-5.5,12.5) B10(-4.5,12.5) B11(-3.5,12.5) B12(-2.5,12.5) B13(-1.5,12.5) B14(-0.5,12.5) B15(0.5,12.5) B16(1.5,12.5) B17(2.5,12.5) B18(3.5,12.5) B19(4.5,12.5) B20(5.5,12.5) B21(6.5,12.5) B22(7.5,12.5) B23(8.5,12.5) B24(9.5,12.5) B25(10.5,12.5) B26(11.5,12.5) B27(12.5,12.5) B28(13.5,12.5) C1(-13.5,11.5) C2(-12.5,11.5) C3(-11.5,11.5) C4(-10.5,11.5) C5(-9.5,11.5) C6(-8.5,11.5) C7(-7.5,11.5) C8(-6.5,11.5) C9(-5.5,11.5) C10(-4.5,11.5) C11(-3.5,11.5) C12(-2.5,11.5) C13(-1.5,11.5) C14(-0.5,11.5) C15(0.5,11.5) C16(1.5,11.5) C17(2.5,11.5) C18(3.5,11.5) C19(4.5,11.5) C20(5.5,11.5) C21(6.5,11.5) C22(7.5,11.5) C23(8.5,11.5) C24(9.5,11.5) C25(10.5,11.5) C26(11.5,11.5) C27(12.5,11.5) C28(13.5,11.5) D1(-13.5,10.5) D2(-12.5,10.5) D3(-11.5,10.5) D4(-10.5,10.5) D5(-9.5,10.5) D6(-8.5,10.5) D7(-7.5,10.5) D8(-6.5,10.5) D9(-5.5,10.5) D10(-4.5,10.5) D11(-3.5,10.5) D12(-2.5,10.5) D13(-1.5,10.5) D14(-0.5,10.5) D15(0.5,10.5) D16(1.5,10.5) D17(2.5,10.5) D18(3.5,10.5) D19(4.5,10.5) D20(5.5,10.5) D21(6.5,10.5) D22(7.5,10.5) D23(8.5,10.5) D24(9.5,10.5) D25(10.5,10.5) D26(11.5,10.5) D27(12.5,10.5) D28(13.5,10.5) E1(-13.5,9.5) E2(-12.5,9.5) E3(-11.5,9.5) E4(-10.5,9.5) E5(-9.5,9.5) E6(-8.5,9.5) E7(-7.5,9.5) E8(-6.5,9.5) E9(-5.5,9.5) E10(-4.5,9.5) E11(-3.5,9.5) E12(-2.5,9.5) E13(-1.5,9.5) E14(-0.5,9.5) E15(0.5,9.5) E16(1.5,9.5) E17(2.5,9.5) E18(3.5,9.5) E19(4.5,9.5) E20(5.5,9.5) E21(6.5,9.5) E22(7.5,9.5) E23(8.5,9.5) E24(9.5,9.5) E25(10.5,9.5) E26(11.5,9.5) E27(12.5,9.5) E28(13.5,9.5) F1(-13.5,8.5) F2(-12.5,8.5) F3(-11.5,8.5) F4(-10.5,8.5) F5(-9.5,8.5) F6(-8.5,8.5) F7(-7.5,8.5) F8(-6.5,8.5) F9(-5.5,8.5) F10(-4.5,8.5) F11(-3.5,8.5) F12(-2.5,8.5) F13(-1.5,8.5) F14(-0.5,8.5) F15(0.5,8.5) F16(1.5,8.5) F17(2.5,8.5) F18(3.5,8.5) F19(4.5,8.5) F20(5.5,8.5) F21(6.5,8.5) F22(7.5,8.5) F23(8.5,8.5) F24(9.5,8.5) F25(10.5,8.5) F26(11.5,8.5) F27(12.5,8.5) F28(13.5,8.5) G1(-13.5,7.5) G2(-12.5,7.5) G3(-11.5,7.5) G4(-10.5,7.5) G5(-9.5,7.5) G6(-8.5,7.5) G7(-7.5,7.5) G8(-6.5,7.5) G9(-5.5,7.5) G10(-4.5,7.5) G11(-3.5,7.5) G12(-2.5,7.5) G13(-1.5,7.5) G14(-0.5,7.5) G15(0.5,7.5) G16(1.5,7.5) G17(2.5,7.5) G18(3.5,7.5) G19(4.5,7.5) G20(5.5,7.5) G21(6.5,7.5) G22(7.5,7.5) G23(8.5,7.5) G24(9.5,7.5) G25(10.5,7.5) G26(11.5,7.5) G27(12.5,7.5) G28(13.5,7.5) H1(-13.5,6.5) H2(-12.5,6.5) H3(-11.5,6.5) H4(-10.5,6.5) H5(-9.5,6.5) H6(-8.5,6.5) H7(-7.5,6.5) H8(-6.5,6.5) H9(-5.5,6.5) H10(-4.5,6.5) H11(-3.5,6.5) H12(-2.5,6.5) H13(-1.5,6.5) H14(-0.5,6.5) H15(0.5,6.5) H16(1.5,6.5) H17(2.5,6.5) H18(3.5,6.5) H19(4.5,6.5) H20(5.5,6.5) H21(6.5,6.5) H22(7.5,6.5) H23(8.5,6.5) H24(9.5,6.5) H25(10.5,6.5) H26(11.5,6.5) H27(12.5,6.5) H28(13.5,6.5) J1(-13.5,5.5) J2(-12.5,5.5) J3(-11.5,5.5) J4(-10.5,5.5) J5(-9.5,5.5) J6(-8.5,5.5) J7(-7.5,5.5) J8(-6.5,5.5) J9(-5.5,5.5) J10(-4.5,5.5) J11(-3.5,5.5) J12(-2.5,5.5) J13(-1.5,5.5) J14(-0.5,5.5) J15(0.5,5.5) J16(1.5,5.5) J17(2.5,5.5) J18(3.5,5.5) J19(4.5,5.5) J20(5.5,5.5) J21(6.5,5.5) J22(7.5,5.5) J23(8.5,5.5) J24(9.5,5.5) J25(10.5,5.5) J26(11.5,5.5) J27(12.5,5.5) J28(13.5,5.5) K1(-13.5,4.5) K2(-12.5,4.5) K3(-11.5,4.5) K4(-10.5,4.5) K5(-9.5,4.5) K6(-8.5,4.5) K7(-7.5,4.5) K8(-6.5,4.5) K9(-5.5,4.5) K10(-4.5,4.5) K11(-3.5,4.5) K12(-2.5,4.5) K13(-1.5,4.5) K14(-0.5,4.5) K15(0.5,4.5) K16(1.5,4.5) K17(2.5,4.5) K18(3.5,4.5) K19(4.5,4.5) K20(5.5,4.5) K21(6.5,4.5) K22(7.5,4.5) K23(8.5,4.5) K24(9.5,4.5) K25(10.5,4.5) K26(11.5,4.5) K27(12.5,4.5) K28(13.5,4.5) L1(-13.5,3.5) L2(-12.5,3.5) L3(-11.5,3.5) L4(-10.5,3.5) L5(-9.5,3.5) L6(-8.5,3.5) L7(-7.5,3.5) L8(-6.5,3.5) L9(-5.5,3.5) L10(-4.5,3.5) L11(-3.5,3.5) L12(-2.5,3.5) L13(-1.5,3.5) L14(-0.5,3.5) L15(0.5,3.5) L16(1.5,3.5) L17(2.5,3.5) L18(3.5,3.5) L19(4.5,3.5) L20(5.5,3.5) L21(6.5,3.5) L22(7.5,3.5) L23(8.5,3.5) L24(9.5,3.5) L25(10.5,3.5) L26(11.5,3.5) L27(12.5,3.5) L28(13.5,3.5) M1(-13.5,2.5) M2(-12.5,2.5) M3(-11.5,2.5) M4(-10.5,2.5) M5(-9.5,2.5) M6(-8.5,2.5) M7(-7.5,2.5) M8(-6.5,2.5) M9(-5.5,2.5) M10(-4.5,2.5) M11(-3.5,2.5) M12(-2.5,2.5) M13(-1.5,2.5) M14(-0.5,2.5) M15(0.5,2.5) M16(1.5,2.5) M17(2.5,2.5) M18(3.5,2.5) M19(4.5,2.5) M20(5.5,2.5) M21(6.5,2.5) M22(7.5,2.5) M23(8.5,2.5) M24(9.5,2.5) M25(10.5,2.5) M26(11.5,2.5) M27(12.5,2.5) M28(13.5,2.5) N1(-13.5,1.5) N2(-12.5,1.5) N3(-11.5,1.5) N4(-10.5,1.5) N5(-9.5,1.5) N6(-8.5,1.5) N7(-7.5,1.5) N8(-6.5,1.5) N9(-5.5,1.5) N10(-4.5,1.5) N11(-3.5,1.5) N12(-2.5,1.5) N13(-1.5,1.5) N14(-0.5,1.5) N15(0.5,1.5) N16(1.5,1.5) N17(2.5,1.5) N18(3.5,1.5) N19(4.5,1.5) N20(5.5,1.5) N21(6.5,1.5) N22(7.5,1.5) N23(8.5,1.5) N24(9.5,1.5) N25(10.5,1.5) N26(11.5,1.5) N27(12.5,1.5) N28(13.5,1.5) P1(-13.5,0.5) P2(-12.5,0.5) P3(-11.5,0.5) P4(-10.5,0.5) P5(-9.5,0.5) P6(-8.5,0.5) P7(-7.5,0.5) P8(-6.5,0.5) P9(-5.5,0.5) P10(-4.5,0.5) P11(-3.5,0.5) P12(-2.5,0.5) P13(-1.5,0.5) P14(-0.5,0.5) P15(0.5,0.5) P16(1.5,0.5) P17(2.5,0.5) P18(3.5,0.5) P19(4.5,0.5) P20(5.5,0.5) P21(6.5,0.5) P22(7.5,0.5) P23(8.5,0.5) P24(9.5,0.5) P25(10.5,0.5) P26(11.5,0.5) P27(12.5,0.5) P28(13.5,0.5) R1(-13.5,-0.5) R2(-12.5,-0.5) R3(-11.5,-0.5) R4(-10.5,-0.5) R5(-9.5,-0.5) R6(-8.5,-0.5) R7(-7.5,-0.5) R8(-6.5,-0.5) R9(-5.5,-0.5) R10(-4.5,-0.5) R11(-3.5,-0.5) R12(-2.5,-0.5) R13(-1.5,-0.5) R14(-0.5,-0.5) R15(0.5,-0.5) R16(1.5,-0.5) R17(2.5,-0.5) R18(3.5,-0.5) R19(4.5,-0.5) R20(5.5,-0.5) R21(6.5,-0.5) R22(7.5,-0.5) R23(8.5,-0.5) R24(9.5,-0.5) R25(10.5,-0.5) R26(11.5,-0.5) R27(12.5,-0.5) R28(13.5,-0.5) T1(-13.5,-1.5) T2(-12.5,-1.5) T3(-11.5,-1.5) T4(-10.5,-1.5) T5(-9.5,-1.5) T6(-8.5,-1.5) T7(-7.5,-1.5) T8(-6.5,-1.5) T9(-5.5,-1.5) T10(-4.5,-1.5) T11(-3.5,-1.5) T12(-2.5,-1.5) T13(-1.5,-1.5) T14(-0.5,-1.5) T15(0.5,-1.5) T16(1.5,-1.5) T17(2.5,-1.5) T18(3.5,-1.5) T19(4.5,-1.5) T20(5.5,-1.5) T21(6.5,-1.5) T22(7.5,-1.5) T23(8.5,-1.5) T24(9.5,-1.5) T25(10.5,-1.5) T26(11.5,-1.5) T27(12.5,-1.5) T28(13.5,-1.5) U1(-13.5,-2.5) U2(-12.5,-2.5) U3(-11.5,-2.5) U4(-10.5,-2.5) U5(-9.5,-2.5) U6(-8.5,-2.5) U7(-7.5,-2.5) U8(-6.5,-2.5) U9(-5.5,-2.5) U10(-4.5,-2.5) U11(-3.5,-2.5) U12(-2.5,-2.5) U13(-1.5,-2.5) U14(-0.5,-2.5) U15(0.5,-2.5) U16(1.5,-2.5) U17(2.5,-2.5) U18(3.5,-2.5) U19(4.5,-2.5) U20(5.5,-2.5) U21(6.5,-2.5) U22(7.5,-2.5) U23(8.5,-2.5) U24(9.5,-2.5) U25(10.5,-2.5) U26(11.5,-2.5) U27(12.5,-2.5) U28(13.5,-2.5) V1(-13.5,-3.5) V2(-12.5,-3.5) V3(-11.5,-3.5) V4(-10.5,-3.5) V5(-9.5,-3.5) V6(-8.5,-3.5) V7(-7.5,-3.5) V8(-6.5,-3.5) V9(-5.5,-3.5) V10(-4.5,-3.5) V11(-3.5,-3.5) V12(-2.5,-3.5) V13(-1.5,-3.5) V14(-0.5,-3.5) V15(0.5,-3.5) V16(1.5,-3.5) V17(2.5,-3.5) V18(3.5,-3.5) V19(4.5,-3.5) V20(5.5,-3.5) V21(6.5,-3.5) V22(7.5,-3.5) V23(8.5,-3.5) V24(9.5,-3.5) V25(10.5,-3.5) V26(11.5,-3.5) V27(12.5,-3.5) V28(13.5,-3.5) W1(-13.5,-4.5) W2(-12.5,-4.5) W3(-11.5,-4.5) W4(-10.5,-4.5) W5(-9.5,-4.5) W6(-8.5,-4.5) W7(-7.5,-4.5) W8(-6.5,-4.5) W9(-5.5,-4.5) W10(-4.5,-4.5) W11(-3.5,-4.5) W12(-2.5,-4.5) W13(-1.5,-4.5) W14(-0.5,-4.5) W15(0.5,-4.5) W16(1.5,-4.5) W17(2.5,-4.5) W18(3.5,-4.5) W19(4.5,-4.5) W20(5.5,-4.5) W21(6.5,-4.5) W22(7.5,-4.5) W23(8.5,-4.5) W24(9.5,-4.5) W25(10.5,-4.5) W26(11.5,-4.5) W27(12.5,-4.5) W28(13.5,-4.5) Y1(-13.5,-5.5) Y2(-12.5,-5.5) Y3(-11.5,-5.5) Y4(-10.5,-5.5) Y5(-9.5,-5.5) Y6(-8.5,-5.5) Y7(-7.5,-5.5) Y8(-6.5,-5.5) Y9(-5.5,-5.5) Y10(-4.5,-5.5) Y11(-3.5,-5.5) Y12(-2.5,-5.5) Y13(-1.5,-5.5) Y14(-0.5,-5.5) Y15(0.5,-5.5) Y16(1.5,-5.5) Y17(2.5,-5.5) Y18(3.5,-5.5) Y19(4.5,-5.5) Y20(5.5,-5.5) Y21(6.5,-5.5) Y22(7.5,-5.5) Y23(8.5,-5.5) Y24(9.5,-5.5) Y25(10.5,-5.5) Y26(11.5,-5.5) Y27(12.5,-5.5) Y28(13.5,-5.5)
Top Overlay:
  circle w0.25: c-15.15,13.5 r0.125
  region: -13.5,14.5 -14.5,13.5 -14.5,14.5
  lines w0.2: -14.5,13.5 -13.5,14.5 ; -14.5,-14.5 14.5,-14.5 14.5,14.5 -14.5,14.5 -14.5,-14.5
M13_Assembly_Info:
  lines w0.1: -14.5,-14.5 14.5,-14.5 14.5,14.5 -14.5,14.5 -14.5,-14.5
M15_Country_Yard:
  lines w0.1: -0.5,0 0.5,0 ; 0,-0.5 0,0.5 ; -15.5,-15.5 15.5,-15.5 15.5,15.5 -15.5,15.5 -15.5,-15.5
3D body: height 2.6, standoff 0, extent -14.5,-14.5 14.5,14.5

## FIDUCIAL MARK [mm]
Top Layer:
  circle w0.5: c0,0 r0.25
Top Solder:
  circle w1.5: c0,0 r0.75
M15_Country_Yard:
  lines w0.1: -1.5,-1.5 -1.5,1.5 1.5,1.5 1.5,-1.5 -1.5,-1.5
3D body: height 0, standoff 0, extent -0.5,-0.5 0.5,0.5

## FPC_Contact_40-pin [mm]
pads (40):
  rect 0.35x4 smd: 1(0,0) 2(0.5,0) 3(1,0) 4(1.5,0) 5(2,0) 6(2.5,0) 7(3,0) 8(3.5,0) 9(4,0) 10(4.5,0) 11(5,0) 12(5.5,0) 13(6,0) 14(6.5,0) 15(7,0) 16(7.5,0) 17(8,0) 18(8.5,0) 19(9,0) 20(9.5,0) 21(10,0) 22(10.5,0) 23(11,0) 24(11.5,0) 25(12,0) 26(12.5,0) 27(13,0) 28(13.5,0) 29(14,0) 30(14.5,0) 31(15,0) 32(15.5,0) 33(16,0) 34(16.5,0) 35(17,0) 36(17.5,0) 37(18,0) 38(18.5,0) 39(19,0) 40(19.5,0)

## FPC_Contact_54-pin [mm]
pads (54):
  rect 0.35x4 smd: 1(0,0) 2(0.5,0) 3(1,0) 4(1.5,0) 5(2,0) 6(2.5,0) 7(3,0) 8(3.5,0) 9(4,0) 10(4.5,0) 11(5,0) 12(5.5,0) 13(6,0) 14(6.5,0) 15(7,0) 16(7.5,0) 17(8,0) 18(8.5,0) 19(9,0) 20(9.5,0) 21(10,0) 22(10.5,0) 23(11,0) 24(11.5,0) 25(12,0) 26(12.5,0) 27(13,0) 28(13.5,0) 29(14,0) 30(14.5,0) 31(15,0) 32(15.5,0) 33(16,0) 34(16.5,0) 35(17,0) 36(17.5,0) 37(18,0) 38(18.5,0) 39(19,0) 40(19.5,0) 41(20,0) 42(20.5,0) 43(21,0) 44(21.5,0) 45(22,0) 46(22.5,0) 47(23,0) 48(23.5,0) 49(24,0) 50(24.5,0) 51(25,0) 52(25.5,0) 53(26,0) 54(26.5,0)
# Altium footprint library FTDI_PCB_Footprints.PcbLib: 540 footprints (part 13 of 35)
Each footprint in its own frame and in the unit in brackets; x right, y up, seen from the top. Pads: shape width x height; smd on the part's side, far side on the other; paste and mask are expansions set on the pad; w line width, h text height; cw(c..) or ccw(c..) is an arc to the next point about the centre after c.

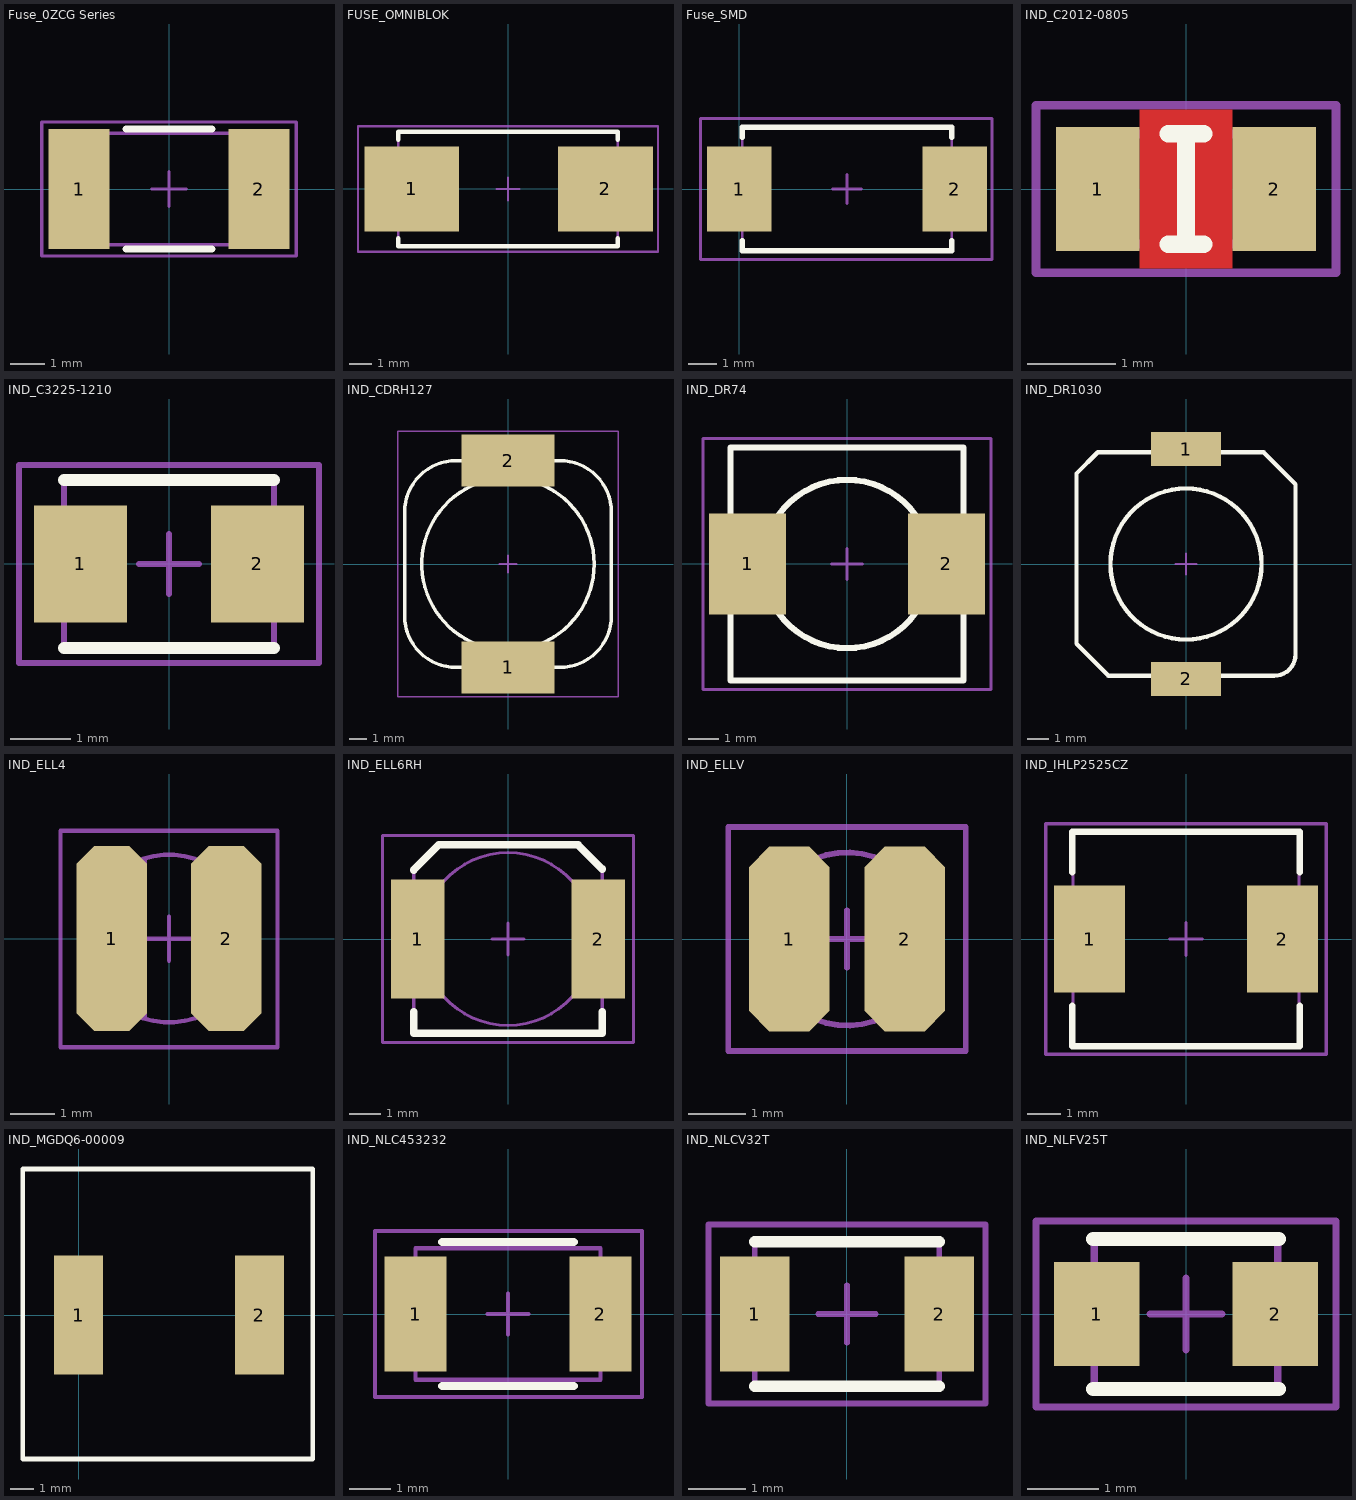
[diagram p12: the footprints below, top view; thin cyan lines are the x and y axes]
## Fuse_0ZCG Series [mm] "Fuse SMT; 0ZCG Series - 1812 Chip; Bel Fuse"
pads (2):
  rect 1.78x3.5 smd: 1(-2.615,0) 2(2.615,0)
Top Overlay:
  lines w0.2: -1.25,-1.75 1.25,-1.75 ; -1.25,1.75 1.25,1.75
M13_Assembly_Info:
  lines w0.1: -2.275,-1.62 -2.275,1.62 2.275,1.62 2.275,-1.62 -2.275,-1.62
M15_Country_Yard:
  lines w0.1: -0.5,0 0.5,0 ; 0,-0.5 0,0.5 ; -3.7,-1.95 3.7,-1.95 3.7,1.95 -3.7,1.95 -3.7,-1.95
3D body: height 0, standoff 0, extent -2.275,-1.62 2.275,1.62

## FUSE_OMNIBLOK [mm]
pads (2):
  rect 4.24x3.81 smd: 1(-4.3,0) 2(4.35,0)
Top Overlay:
  lines w0.2: -4.9,-2.2 -4.9,-2.55 4.9,-2.55 4.9,-2.2 ; -4.9,2.2 -4.9,2.55 4.9,2.55 4.9,2.2
M13_Assembly_Info:
  lines w0.1: -4.9,-2.55 4.9,-2.55 4.9,2.55 -4.9,2.55 -4.9,-2.55
M15_Country_Yard:
  lines w0.1: -0.5,0 0.5,0 ; 0,-0.5 0,0.5 ; -6.7,-2.8 -6.7,2.8 6.7,2.8 6.7,-2.8 -6.7,-2.8
3D body: height 0, standoff 0, extent -4.9,-2.55 4.9,2.55

## Fuse_SMD [mm] "Fuse SMT; Picofuse series; Littelfuse"
pads (2):
  rect 2.25x2.95 smd: 1(0,0) 2(7.5,0)
Top Overlay:
  lines w0.2: 0.1,-1.8 0.1,-2.15 7.4,-2.15 7.4,-1.8 ; 0.1,1.8 0.1,2.15 7.4,2.15 7.4,1.8
M13_Assembly_Info:
  lines w0.1: 0.1,-2.15 7.4,-2.15 7.4,2.15 0.1,2.15 0.1,-2.15
M15_Country_Yard:
  lines w0.1: 3.25,0 4.25,0 ; 3.75,-0.5 3.75,0.5 ; -1.35,-2.45 8.8,-2.45 8.8,2.45 -1.35,2.45 -1.35,-2.45
3D body: height 0, standoff 0, extent 0.1,-2.15 7.4,2.15

## IND_C2012-0805 [mm] "Chip Inductor; Body 2 x 1.2 mm (LxW typ)"
height 1.1
pads (2):
  rect 0.95x1.4 smd: 1(-1,0) 2(1,0)
Top Layer:
  pour cut-out: -0.525,0.9 0.525,0.9 0.525,-0.9 -0.525,-0.9
Top Overlay:
  lines w0.2: -0.2,-0.625 0.2,-0.625 ; -0.2,0.625 0.2,0.625 ; 0,-0.625 0,0.625
M13_Assembly_Info:
  lines w0.1: -1,-0.625 1,-0.625 1,0.625 -1,0.625 -1,-0.625
M15_Country_Yard:
  lines w0.1: -0.35,0 0.35,0 ; 0,-0.35 0,0.35 ; -1.7,-0.95 -1.7,0.95 1.7,0.95 1.7,-0.95 -1.7,-0.95
3D body: height 1, standoff 0, extent 0.7,-0.625 1,0.625
3D body: height 1, standoff 0, extent -1,-0.625 -0.7,0.625
3D body: height 1, standoff 0, extent -0.7,-0.625 0.7,0.625

## IND_C3225-1210 [mm] "Molded Inductor, 2-Leads, Body 3.2x2.5mm, IPC Medium Density"
height 2.4
pads (2):
  rect 1.55x1.95 smd: 1(-1.475,0) 2(1.475,0)
Top Overlay:
  lines w0.2: -1.75,-1.4 1.75,-1.4 ; -1.75,1.4 1.75,1.4
M13_Assembly_Info:
  lines w0.1: -1.75,-1.35 1.75,-1.35 1.75,1.35 -1.75,1.35 -1.75,-1.35
M15_Country_Yard:
  lines w0.1: -0.5,0 0.5,0 ; 0,-0.5 0,0.5 ; -2.5,-1.65 2.5,-1.65 2.5,1.65 -2.5,1.65 -2.5,-1.65
3D body: height 2.4, standoff 0, extent -1.75,-1.35 1.75,1.35

## IND_CDRH127 [mm] "Sumida Power Inductor-CDRH series"
pads (2):
  rect 5.4x3 smd: 1(0,-6) 2(0,6)
Top Overlay:
  circle w0.2: c0,0 r5
  lines w0.2: -6,-3 ccw(c-3,-3) -3,-6 3,-6 ccw(c3,-3) 6,-3 6,3 ccw(c3,3) 3,6 -3,6 ccw(c-3,3) -6,3 -6,-3
M13_Assembly_Info:
  lines w0.1: -6,-3 ccw(c-3,-3) -3,-6 3,-6 ccw(c3,-3) 6,-3 6,3 ccw(c3,3) 3,6 -3,6 ccw(c-3,3) -6,3 -6,-3
M15_Country_Yard:
  lines w0.1: -0.5,0 0.5,0 ; 0,-0.5 0,0.5 ; -6.4,-7.7 6.4,-7.7 6.4,7.7 -6.4,7.7 -6.4,-7.7
3D body: height 0, standoff 0, extent -6,-6 6,6

## IND_DR74 [mm] "DR Series  High Power Density,  High Efficiency, Shielded Inductors"
height 3.5
pads (2):
  rect 2.5x3.3 smd: 1(-3.25,0) 2(3.25,0)
Top Overlay:
  circle w0.2: c0,0 r2.75
  lines w0.2: -3.8,-3.8 -3.8,3.8 3.8,3.8 3.8,-3.8 -3.8,-3.8
M13_Assembly_Info:
  circle w0.1: c0,0 r2.75
  lines w0.1: -3.8,-3.8 -3.8,3.8 3.8,3.8 3.8,-3.8 -3.8,-3.8
M15_Country_Yard:
  lines w0.1: -0.5,0 0.5,0 ; 0,-0.5 0,0.5 ; -4.7,-4.1 -4.7,4.1 4.7,4.1 4.7,-4.1 -4.7,-4.1
3D body: height 0, standoff 0, extent -3.8,-3.8 3.8,3.8

## IND_DR1030 [mm] "TAIYO YUDEN Inductor, series NP04S"
height 3
pads (2):
  rect 3.3x1.6 smd: 1(0,5.4) 2(0,-5.4)
Top Overlay:
  circle w0.2: c0,0 r3.55
  lines w0.2: -5.15,-3.75 -3.65,-5.25 4.15,-5.25 ccw(c4.15,-4.25) 5.15,-4.25 5.15,3.75 3.65,5.25 -4.15,5.25 -5.15,4.25 -5.15,-3.75
M13_Assembly_Info:
  circle w0.1: c0,0 r3.55
  lines w0.1: -5.15,-3.75 -3.65,-5.25 4.15,-5.25 ccw(c4.15,-4.25) 5.15,-4.25 5.15,3.75 3.65,5.25 -4.15,5.25 -5.15,4.25 -5.15,-3.75
M15_Country_Yard:
  lines w0.1: -0.5,0 0.5,0 ; 0,-0.5 0,0.5
3D body: height 0, standoff 0, extent -5.15,-5.25 5.15,5.25

## IND_ELL4 [mm] "ELL4 SMD Choke Coils; Panasonic"
height 1.2
pads (2):
  oct 1.6x4.2 smd: 1(-1.3,0) 2(1.3,0)
M13_Assembly_Info:
  circle w0.1: c0,0 r1.9
  region: -0.5,-1.82 -0.74,-1.74 -1.06,-1.62 -1.58,-1.1 -1.58,-0.98 -1.76,-0.8 -1.76,-0.58 -1.86,-0.48 -1.86,-0.22 -1.9,-0.18 -1.88,-0.16 -1.88,0.46 -1.78,0.56 -1.78,0.76 -1.62,0.92 -1.62,1.06 -1.34,1.34 -1.34,1.36 -1.32,1.36 -1.06,1.62 -0.92,1.62 -0.76,1.78 -0.56,1.78 -0.5,1.84
M15_Country_Yard:
  lines w0.1: -0.5,0 0.5,0 ; 0,-0.5 0,0.5 ; -2.46,-2.46 2.46,-2.46 2.46,2.44 -2.46,2.44 -2.46,-2.46
3D body: height 1.2, standoff 0, extent -1.885,-1.9 1.9,1.893

## IND_ELL6RH [mm] "Panasonic; SMD Choke Coil"
height 2.8
pads (2):
  rect 1.7x3.8 smd: 1(-2.875,0) 2(2.875,0)
Top Overlay:
  lines w0.25: -3,-2.325 -3,-3 3,-3 3,-2.325 ; -3,2.2 -2.2,3 2.225,3 3,2.225
M13_Assembly_Info:
  circle w0.1: c0,0 r2.75
  lines w0.1: -3,-3 3,-3 3,2.225 2.225,3 -2.2,3 -3,2.2 -3,-3
M15_Country_Yard:
  lines w0.1: -0.5,0 0.5,0 ; 0,-0.5 0,0.5 ; -4,-3.3 -4,3.3 4,3.3 4,-3.3 -4,-3.3
3D body: height 2.8, standoff 0, extent -3,-3 3,3

## IND_ELLV [mm] "SMD Choke Coil; Panasonic; ELLV series"
height 1.5
pads (2):
  oct 1.4x3.2 smd: 1(-1,0) 2(1,0)
M13_Assembly_Info:
  circle w0.1: c0,0 r1.5
  region: -0.5,1.4 -0.5,-1.4 -0.58,-1.4 -0.7,-1.28 -0.78,-1.28 -0.9,-1.16 -0.94,-1.16 -1.08,-1.02 -1.1,-1.02 -1.1,-1 -1.24,-0.86 -1.24,-0.82 -1.36,-0.7 -1.36,-0.56 -1.44,-0.48 -1.44,-0.28 -1.5,-0.22 -1.5,0.28 -1.44,0.34 -1.44,0.5 -1.38,0.56 -1.38,0.66 -1.24,0.8 -1.24,0.86 -0.9,1.2 -0.84,1.2 -0.66,1.38 -0.52,1.38
M15_Country_Yard:
  lines w0.1: -0.5,0 0.5,0 ; 0,-0.5 0,0.5 ; -2.06,-1.94 2.06,-1.94 2.06,1.94 -2.06,1.94 -2.06,-1.94
3D body: height 1.5, standoff 0, extent -1.5,-1.467 1.488,1.527

## IND_IHLP2525CZ [mm] "Molded Inductor, 2-Leads, Body 6.9x6.5mm, IHLP2525CZ series, Vishay, IPC Medium Density"
height 3
pads (2):
  rect 2.15x3.25 smd: 1(-2.925,0) 2(2.925,0)
Top Overlay:
  lines w0.2: -3.45,-2.025 -3.45,-3.25 3.45,-3.25 3.45,-2.025 ; -3.45,2.025 -3.45,3.25 3.45,3.25 3.45,2.025
M13_Assembly_Info:
  lines w0.1: -3.43,-3.25 3.43,-3.25 3.43,3.25 -3.43,3.25 -3.43,-3.25
M15_Country_Yard:
  lines w0.1: -0.5,0 0.5,0 ; 0,-0.5 0,0.5 ; -4.25,-3.5 4.25,-3.5 4.25,3.5 -4.25,3.5 -4.25,-3.5
3D body: height 3, standoff 0, extent -3.43,-3.25 3.43,3.25

## IND_MGDQ6-00009 [mm] "10uH/5.4A Power inductor. Tayco Electronics"
pads (2):
  rect 2.13x5.13 smd: 1(0,0) 2(7.8,0)
Top Overlay:
  lines w0.2: -2.4,-6.2 -2.4,6.3 10.1,6.3 10.1,-6.2 -2.4,-6.2

## IND_NLC453232 [mm] "Molded Inductor, NLC453232 series, TDK; 2-Leads, Body 4.5x3.2mm (1812), IPC Medium Density"
height 3.2
pads (2):
  rect 1.5x2.8 smd: 1(-2.25,0) 2(2.25,0)
Top Overlay:
  lines w0.2: -1.6,-1.75 1.6,-1.75 ; -1.6,1.75 1.6,1.75
M13_Assembly_Info:
  lines w0.1: -2.25,-1.6 -2.25,1.6 2.25,1.6 2.25,-1.6 -2.25,-1.6
M15_Country_Yard:
  lines w0.1: -0.5,0 0.5,0 ; 0,-0.5 0,0.5 ; -3.24,-2.02 -3.24,2.02 3.26,2.02 3.26,-2.02 -3.24,-2.02
3D body: height 3.2, standoff 0, extent -2.25,-1.6 2.25,1.6

## IND_NLCV32T [mm] "Molded Inductor, NLCV32T series, TDK; 2-Leads, Body 3.2x2.5mm (1210), IPC Medium Density"
height 1.9
pads (2):
  rect 1.2x2 smd: 1(-1.6,0) 2(1.6,0)
Top Overlay:
  lines w0.2: -1.6,-1.25 1.6,-1.25 ; -1.6,1.25 1.6,1.25
M13_Assembly_Info:
  lines w0.1: -1.6,-1.25 -1.6,1.25 1.6,1.25 1.6,-1.25 -1.6,-1.25
M15_Country_Yard:
  lines w0.1: -0.5,0 0.5,0 ; 0,-0.5 0,0.5 ; -2.4,-1.55 2.4,-1.55 2.4,1.55 -2.4,1.55 -2.4,-1.55
3D body: height 0, standoff 0, extent -1.6,-1.25 1.6,1.25

## IND_NLFV25T [mm] "Molded Inductor, NLFV25T series, TDK; 2-Leads, Body 2.5x2.0mm, IPC Medium Density"
height 1.9
pads (2):
  rect 1.2x1.45 smd: 1(-1.25,0) 2(1.25,0)
Top Overlay:
  lines w0.2: -1.3,-1.05 1.3,-1.05 ; -1.3,1.05 1.3,1.05
M13_Assembly_Info:
  lines w0.1: -1.285,-1.05 -1.285,1.05 1.285,1.05 1.285,-1.05 -1.285,-1.05
M15_Country_Yard:
  lines w0.1: -0.5,0 0.5,0 ; 0,-0.5 0,0.5 ; -2.1,-1.3 -2.1,1.3 2.1,1.3 2.1,-1.3 -2.1,-1.3
3D body: height 1.9, standoff 0, extent -1.285,-1.05 1.285,1.05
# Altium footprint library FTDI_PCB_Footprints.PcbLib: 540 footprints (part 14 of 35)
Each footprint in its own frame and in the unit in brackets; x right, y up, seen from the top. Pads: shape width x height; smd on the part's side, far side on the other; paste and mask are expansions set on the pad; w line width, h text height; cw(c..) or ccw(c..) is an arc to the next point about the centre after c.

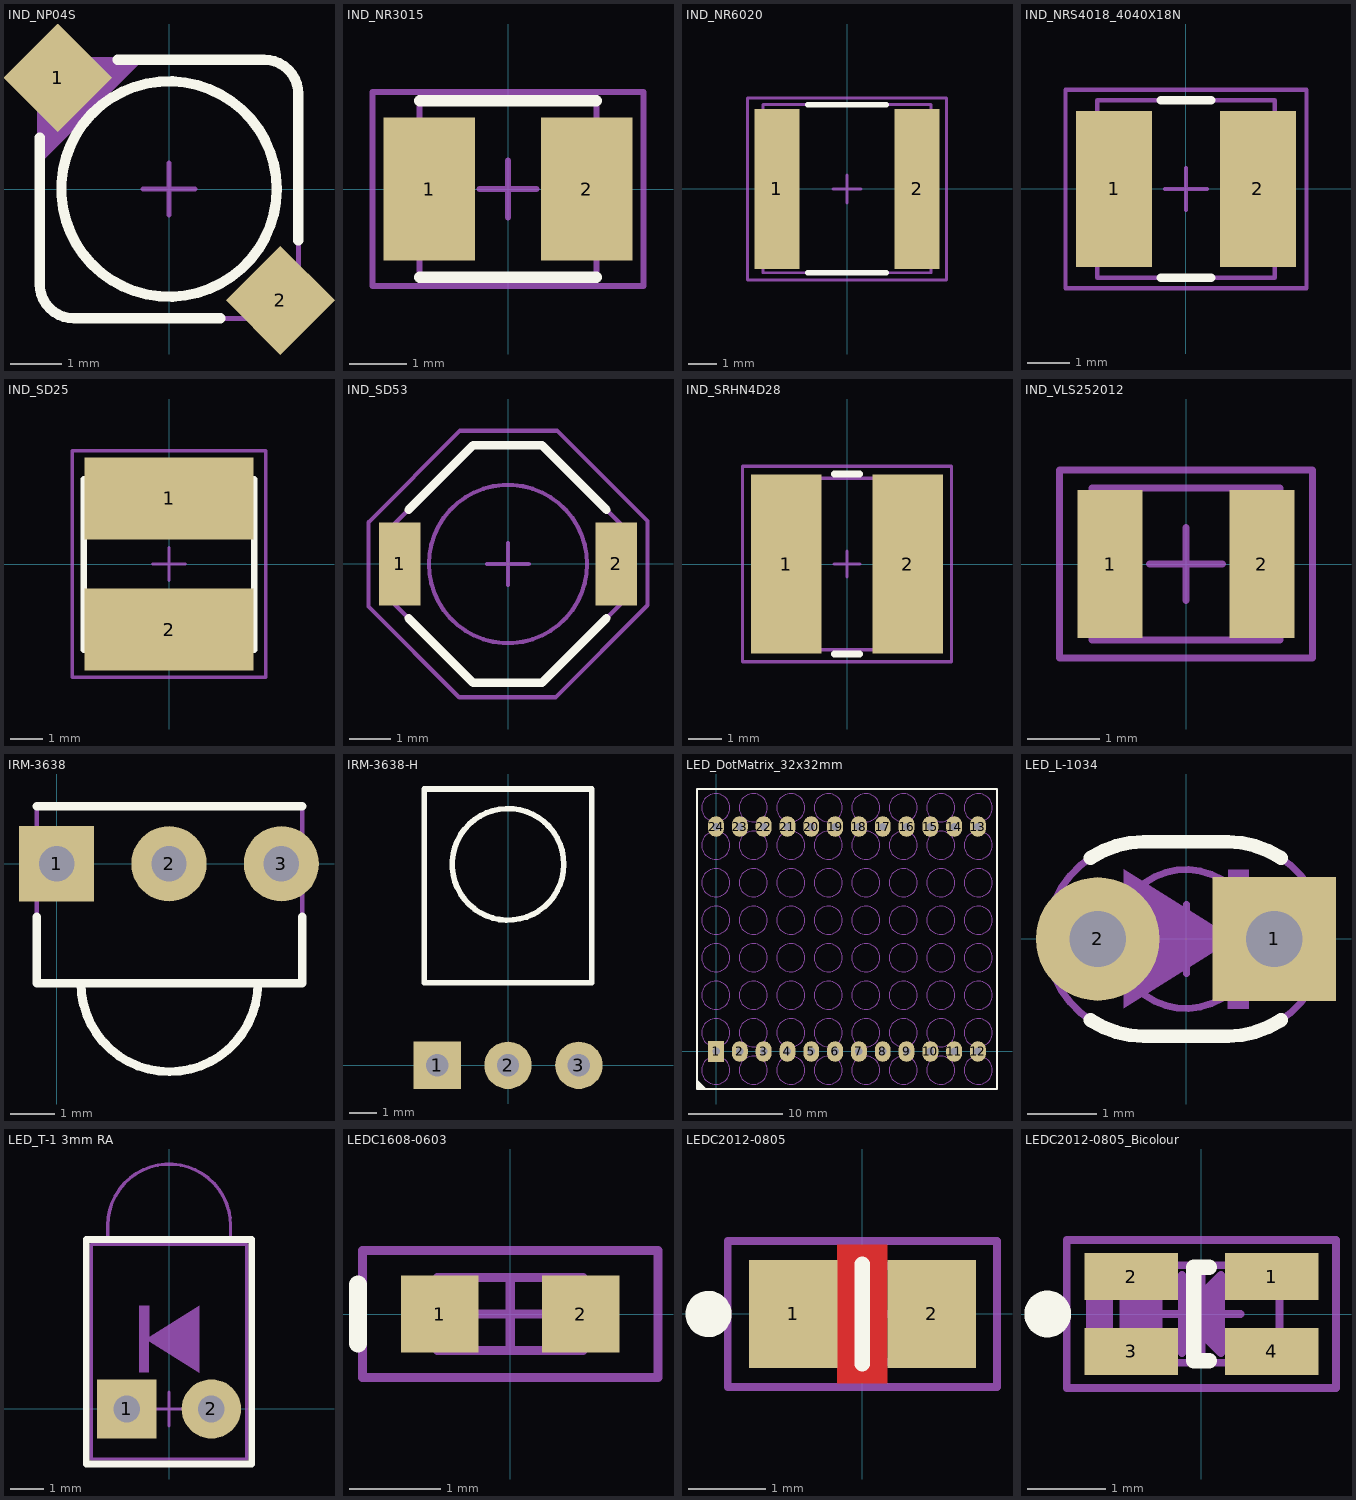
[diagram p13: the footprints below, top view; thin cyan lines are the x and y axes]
## IND_NP04S [mm] "TAIYO YUDEN Inductor, series NP04S"
height 3
pads (2):
  rect 1.5x1.5 smd rot 45: 1(-2.16,2.16) 2(2.16,-2.16)
Top Overlay:
  circle w0.2: c0,0 r2.09
  lines w0.2: -2.51,1 -2.51,-1.84 ccw(c-1.84,-1.84) -1.84,-2.51 1,-2.51 ; -1,2.51 1.84,2.51 cw(c1.84,1.84) 2.51,1.84 2.51,-1
M13_Assembly_Info:
  circle w0.1: c0,0 r2.09
  region: -1.81,2.51 -0.5,2.51 -2.51,0.49 -2.51,1.82
  lines w0.1: -2.51,1.81 -1.81,2.51 1.84,2.51 cw(c1.84,1.84) 2.51,1.84 2.51,-1.81 1.81,-2.51 -1.84,-2.51 cw(c-1.84,-1.84) -2.51,-1.84 -2.51,1.82
M15_Country_Yard:
  lines w0.1: -0.5,0 0.5,0 ; 0,-0.5 0,0.5
3D body: height 0, standoff 0, extent -2.51,-2.51 2.51,2.51

## IND_NR3015 [mm] "Precision Wire Wound Inductor, 2-Leads, Body 3.00x3.00mm, IPC Medium Density"
height 1.5
pads (2):
  rect 1.6x2.5 smd: 1(-1.38,0) 2(1.38,0)
Top Overlay:
  lines w0.2: -1.55,-1.55 1.55,-1.55 ; -1.55,1.55 1.55,1.55
M13_Assembly_Info:
  lines w0.1: -1.55,-1.55 -1.55,1.55 1.55,1.55 1.55,-1.55 -1.55,-1.55
M15_Country_Yard:
  lines w0.1: -0.5,0 0.5,0 ; 0,-0.5 0,0.5 ; -2.375,-1.7 -2.375,1.7 2.375,1.7 2.375,-1.7 -2.375,-1.7
3D body: height 1.5, standoff 0, extent -1.55,-1.55 1.55,1.55

## IND_NR6020 [mm] "Inductor, NR6020 series, Taiyo Yuden"
height 2
pads (2):
  rect 1.6x5.7 smd: 1(-2.5,0) 2(2.5,0)
Top Overlay:
  lines w0.2: -1.4,-2.99 1.4,-2.99 ; -1.4,3.01 1.4,3.01
M13_Assembly_Info:
  lines w0.1: -3,-2.99 3,-2.99 3,3.01 -3,3.01 -3,-2.99
M15_Country_Yard:
  lines w0.1: -0.5,0 0.5,0 ; 0,-0.5 0,0.5 ; -3.55,-3.25 3.55,-3.25 3.55,3.25 -3.55,3.25 -3.55,-3.25
3D body: height 2, standoff 0, extent -3,-2.99 3,3.01

## IND_NRS4018_4040X18N [mm] "Molded Inductor, 2-Leads, Body 4.0x4.0mm, IPC Medium Density"
height 1.8
pads (2):
  rect 1.8x3.7 smd: 1(-1.7,0) 2(1.7,0)
Top Overlay:
  lines w0.2: -0.6,-2.1 0.6,-2.1 ; -0.6,2.1 0.6,2.1
M13_Assembly_Info:
  lines w0.1: -2.1,-2.1 2.1,-2.1 2.1,2.1 -2.1,2.1 -2.1,-2.1
M15_Country_Yard:
  lines w0.1: -0.5,0 0.5,0 ; 0,-0.5 0,0.5 ; -2.85,-2.35 2.85,-2.35 2.85,2.35 -2.85,2.35 -2.85,-2.35
3D body: height 1.8, standoff 0, extent -2.1,-2.1 2.1,2.1

## IND_SD25 [mm] "SD25 series, Cooper Bussmann, High Power Density,  Low Profile, Shielded Inductor"
height 2.5
pads (2):
  rect 5.15x2.5 smd: 1(0,2) 2(0,-2)
Top Overlay:
  lines w0.2: -2.6,-2.61 -2.6,2.59 2.6,2.59 2.6,-2.61 -2.6,-2.61
M13_Assembly_Info:
  lines w0.1: -2.6,-2.61 2.6,-2.61 2.6,2.59 -2.6,2.59 -2.6,-2.61
M15_Country_Yard:
  lines w0.1: -0.5,0 0.5,0 ; 0,-0.5 0,0.5 ; -2.95,-3.45 2.95,-3.45 2.95,3.45 -2.95,3.45 -2.95,-3.45
3D body: height 2.5, standoff 0, extent -2.6,-2.61 2.6,2.59

## IND_SD53 [mm] "SD53 series, Coiltronics/Cooper Bussmann, High Power Density,  Low Profile, Shielded Inductor"
height 3
pads (2):
  rect 1x2 smd: 1(-2.6,0) 2(2.6,0)
Top Overlay:
  lines w0.2: -2.385,-1.302 -0.837,-2.85 0.817,-2.85 2.365,-1.302 ; -2.385,1.302 -0.837,2.85 0.817,2.85 2.365,1.302
M13_Assembly_Info:
  circle w0.1: c0,0 r1.9
  lines w0.1: -2.85,-0.837 -0.837,-2.85 0.817,-2.85 2.85,-0.817 2.85,0.817 0.817,2.85 -0.837,2.85 -2.85,0.837 -2.85,-0.837
M15_Country_Yard:
  lines w0.1: -0.5,0 0.5,0 ; 0,-0.5 0,0.5 ; -3.35,-1.02 -3.35,1 -1.15,3.2 1.18,3.2 3.35,1.03 3.35,-0.99 1.14,-3.2 -1.17,-3.2 -3.35,-1.02
3D body: height 3, standoff 0, extent -2.85,-2.85 2.85,2.85

## IND_SRHN4D28 [mm] "Power Inductor SRHN4D28 series"
height 3
pads (2):
  rect 2.1x5.3 smd: 1(-1.8,0) 2(1.8,0)
Top Overlay:
  lines w0.2: -0.381,-2.667 0.381,-2.667 ; -0.381,2.667 0.381,2.667
M13_Assembly_Info:
  lines w0.1: -2.413,-2.54 -2.413,2.54 2.413,2.54 2.413,-2.54 -2.413,-2.54
M15_Country_Yard:
  lines w0.1: -0.381,0 0.381,0 ; 0,-0.381 0,0.381 ; -3.1,-2.9 -3.1,2.9 3.1,2.9 3.1,-2.9 -3.1,-2.9
3D body: height 3, standoff 0, extent -2.413,-2.54 2.413,2.54

## IND_VLS252012 [mm] "Inductor, 2-Leads, Body 2.5x2.0mm, VLS series, TDK; IPC Medium Density"
height 1.2
pads (2):
  rect 0.9x2.05 smd: 1(-1.05,0) 2(1.05,0)
M13_Assembly_Info:
  lines w0.1: -1.3,-1.05 1.3,-1.05 1.3,1.05 -1.3,1.05 -1.3,-1.05
M15_Country_Yard:
  lines w0.1: -0.5,0 0.5,0 ; 0,-0.5 0,0.5 ; -1.75,-1.3 1.75,-1.3 1.75,1.3 -1.75,1.3 -1.75,-1.3
3D body: height 1.2, standoff 0, extent -1.3,-1.05 1.3,1.05

## IRM-3638 [mm] "Infrared remote control receiver"
pads (3):
  rect 1.7x1.7 hole 0.8: 1(0,0)
  round 1.7 hole 0.8: 2(2.54,0) 3(5.08,0)
Top Overlay:
  lines w0.2: -0.45,-1.2 -0.45,-2.7 5.55,-2.7 5.55,-1.2 ; -0.45,1.3 5.55,1.3 ; 0.55,-2.7 ccw(c2.55,-2.7) 4.55,-2.7
M13_Assembly_Info:
  lines w0.1: 0.55,-2.7 ccw(c2.55,-2.7) 4.55,-2.7 ; -0.45,-2.7 -0.45,1.3 5.55,1.3 5.55,-2.7 -0.45,-2.7

## IRM-3638-H [mm] "Infrared remote control receiver"
pads (3):
  rect 1.7x1.7 hole 0.8: 1(-2.54,0)
  round 1.7 hole 0.8: 2(0,0) 3(2.54,0)
Top Overlay:
  circle w0.2: c0,7.2 r2
  lines w0.2: -3,2.95 -3,9.9 3,9.9 3,2.95 -3,2.95
M13_Assembly_Info:
  circle w0.1: c0,7.2 r2
  lines w0.1: -3,2.95 -3,9.9 3,9.9 3,2.95 -3,2.95

## LED_DotMatrix_32x32mm [mm]
pads (24):
  rect 1.7x2.2 hole 0.8: 1(0,0)
  oval 1.7x2.2 hole 0.8: 2(2.54,0) 3(5.08,0) 4(7.62,0) 5(10.16,0) 6(12.7,0) 7(15.24,0) 8(17.78,0) 9(20.32,0) 10(22.86,0) 11(25.4,0) 12(27.94,0) 13(27.94,24) 14(25.4,24) 15(22.86,24) 16(20.32,24) 17(17.78,24) 18(15.24,24) 19(12.7,24) 20(10.16,24) 21(7.62,24) 22(5.08,24) 23(2.54,24) 24(0,24)
Top Overlay:
  region: -2.03,-4 -2.03,-3 -1.03,-4
  lines w0.2: -2.03,-4 -2.03,28 29.97,28 29.97,-4 -2.03,-4
M13_Assembly_Info:
  circle w0.1: c-0.03,14 r1.5
  circle w0.1: c3.97,14 r1.5
  circle w0.1: c11.97,14 r1.5
  circle w0.1: c7.97,14 r1.5
  circle w0.1: c23.97,14 r1.5
  circle w0.1: c27.97,14 r1.5
  circle w0.1: c19.97,14 r1.5
  circle w0.1: c15.97,14 r1.5
  circle w0.1: c15.97,18 r1.5
  circle w0.1: c19.97,18 r1.5
  circle w0.1: c27.97,18 r1.5
  circle w0.1: c23.97,18 r1.5
  circle w0.1: c7.97,18 r1.5
  circle w0.1: c11.97,18 r1.5
  circle w0.1: c3.97,18 r1.5
  circle w0.1: c-0.03,18 r1.5
  circle w0.1: c-0.03,26 r1.5
  circle w0.1: c3.97,26 r1.5
  circle w0.1: c11.97,26 r1.5
  circle w0.1: c7.97,26 r1.5
  circle w0.1: c23.97,26 r1.5
  circle w0.1: c27.97,26 r1.5
  circle w0.1: c19.97,26 r1.5
  circle w0.1: c15.97,26 r1.5
  circle w0.1: c15.97,22 r1.5
  circle w0.1: c19.97,22 r1.5
  circle w0.1: c27.97,22 r1.5
  circle w0.1: c23.97,22 r1.5
  circle w0.1: c7.97,22 r1.5
  circle w0.1: c11.97,22 r1.5
  circle w0.1: c3.97,22 r1.5
  circle w0.1: c-0.03,22 r1.5
  circle w0.1: c-0.03,6 r1.5
  circle w0.1: c3.97,6 r1.5
  circle w0.1: c11.97,6 r1.5
  circle w0.1: c7.97,6 r1.5
  circle w0.1: c23.97,6 r1.5
  circle w0.1: c27.97,6 r1.5
  circle w0.1: c19.97,6 r1.5
  circle w0.1: c15.97,6 r1.5
  circle w0.1: c15.97,10 r1.5
  circle w0.1: c19.97,10 r1.5
  circle w0.1: c27.97,10 r1.5
  circle w0.1: c23.97,10 r1.5
  circle w0.1: c7.97,10 r1.5
  circle w0.1: c11.97,10 r1.5
  circle w0.1: c3.97,10 r1.5
  circle w0.1: c-0.03,10 r1.5
  circle w0.1: c-0.03,2 r1.5
  circle w0.1: c3.97,2 r1.5
  circle w0.1: c11.97,2 r1.5
  circle w0.1: c7.97,2 r1.5
  circle w0.1: c23.97,2 r1.5
  circle w0.1: c27.97,2 r1.5
  circle w0.1: c19.97,2 r1.5
  circle w0.1: c15.97,2 r1.5
  circle w0.1: c15.97,-2 r1.5
  circle w0.1: c19.97,-2 r1.5
  circle w0.1: c27.97,-2 r1.5
  circle w0.1: c23.97,-2 r1.5
  circle w0.1: c7.97,-2 r1.5
  circle w0.1: c11.97,-2 r1.5
  circle w0.1: c3.97,-2 r1.5
  circle w0.1: c-0.03,-2 r1.5
  lines w0.1: -2.03,-4 -2.03,28 29.97,28 29.97,-4 -2.03,-4
3D body: height 10, standoff 0, extent -1.93,-3.9 29.87,27.9

## LED_L-1034 [mil] "2mm; Flat Top LED Lamp"
height 196.85
pads (2):
  rect 70x70 hole 32: 1(49.8,0)
  round 70 hole 32: 2(-50.2,0)
Top Overlay:
  lines w7.87: -54.36,-46.01 ccw(c-24.02,0) -24.02,-55.12 ; -54.36,46.01 cw(c-24.02,0) -24.02,55.12 ; -23.62,-55.12 23.62,-55.12 ; -23.62,55.12 23.62,55.12 ; 23.23,-55.12 ccw(c23.23,0) 53.58,-46.01 ; 23.23,55.12 cw(c23.23,0) 53.58,46.01
M13_Assembly_Info:
  circle w3.94: c-0.39,0 r39.37
  region: 23.74,39.29 35.35,39.29 35.35,-39.41 23.54,-39.41
  region: -35.47,39.49 -35.47,-39.21 27.48,0.12
  lines w3.94: -24.02,-55.12 cw(c-24.02,0) -24.02,55.12 23.23,55.12 cw(c23.23,0) 23.23,-55.12 -24.02,-55.12
M15_Country_Yard:
  lines w3.94: -19.68,0 19.69,0 ; 0,-19.68 0,19.69
3D body: height 74.8, standoff 0, extent -38.19,-39.37 40.24,39.21

## LED_T-1 3mm RA [mil] "T-1 (3 mm) Right Angle LED Indicators"
height 196.85
pads (2):
  rect 70x70 hole 31.5: 1(-50,0)
  round 70 hole 31.5: 2(50,0)
Top Overlay:
  lines w7.87: -97.44,-64.96 -97.44,200 97.44,200 97.44,-64.96 -97.44,-64.96
M13_Assembly_Info:
  region: -23.74,42.99 -35.35,42.99 -35.35,121.69 -23.54,121.69
  region: 35.47,42.8 35.47,121.5 -27.48,82.17
  lines w3.94: -72.24,194.09 -72.24,216.54 cw(c0.2,216.54) 72.64,216.54 72.64,194.09 ; -91.54,-59.06 -91.54,194.09 91.54,194.09 91.54,-59.06 -91.54,-59.06
M15_Country_Yard:
  lines w3.94: -19.68,0 19.69,0 ; 0,-19.69 0,19.68

## LEDC1608-0603 [mm] "Molded Diode, 2-Leads, Body 1.6x0.8mm, IPC Medium Density"
height 0.8
pads (2):
  rect 0.85x0.85 smd: 1(-0.775,0) 2(0.775,0)
Top Overlay:
  lines w0.2: -1.675,-0.325 -1.675,0.325
M13_Assembly_Info:
  rectangle: -0.8,-0.4 -0.4,0.4
  lines w0.1: -0.8,-0.4 -0.8,0.4 0.8,0.4 0.8,-0.4 -0.8,-0.4
M15_Country_Yard:
  lines w0.1: -0.4,0 0.4,0 ; 0,-0.4 0,0.4 ; -1.625,-0.7 -1.625,0.7 1.625,0.7 1.625,-0.7 -1.625,-0.7
3D body: height 0.8, standoff 0, extent -0.8,-0.4 0.8,0.4

## LEDC2012-0805 [mm] "Chip LED diode; Body 2 x 1.3 mm (LxW typ)"
height 0.65
pads (2):
  rect 1.15x1.4 smd: 1(-0.9,0) 2(0.9,0)
Top Layer:
  pour cut-out: -0.325,0.9 0.325,0.9 0.325,-0.9 -0.325,-0.9
Top Overlay:
  circle w0.3: c-2,0 r0.15
  lines w0.2: 0,-0.65 0,0.65
M13_Assembly_Info:
  rectangle: -1,-0.625 -0.5,0.625
  region: 0.25,-0.5 0.25,0.5 -0.25,0
  lines w0.1: -0.25,-0.5 -0.25,0.5 ; -1,-0.625 -1,0.625 1,0.625 1,-0.625 -1,-0.625 ; -0.25,0 0.25,-0.5 0.25,0.5 -0.25,0
M15_Country_Yard:
  lines w0.1: -0.35,0 0.35,0 ; 0,-0.35 0,0.35 ; -1.75,-0.95 1.75,-0.95 1.75,0.95 -1.75,0.95 -1.75,-0.95
3D body: height 1, standoff 0, extent -1,-0.625 1,0.625

## LEDC2012-0805_Bicolour [mm] "Chip LED, 4-Leads, Body 2.0x1.5mm, IPC Medium Density"
height 0.45
pads (4):
  rect 1.2x0.6 smd: 1(0.9,0.48) 2(-0.9,0.48) 3(-0.9,-0.48) 4(0.9,-0.48)
Top Overlay:
  circle w0.3: c-1.97,0 r0.15
  lines w0.2: 0.1,-0.6 -0.1,-0.6 -0.1,0.6 0.1,0.6
M13_Assembly_Info:
  rectangle: -1.48,-0.18 -1.13,0.18
  rectangle: -1,-0.625 -0.5,0.625
  region: 0.25,-0.5 0.25,0.5 -0.25,0
  lines w0.1: -0.25,-0.5 -0.25,0.5 ; -1,-0.625 1,-0.625 1,0.625 -1,0.625 -1,-0.625 ; -0.25,0 0.25,0.5 0.25,-0.5 -0.25,0
M15_Country_Yard:
  lines w0.1: -0.5,0 0.5,0 ; 0,-0.5 0,0.5 ; -1.725,-0.95 1.725,-0.95 1.725,0.95 -1.725,0.95 -1.725,-0.95
3D body: height 0.45, standoff 0, extent -1,-0.625 1,0.625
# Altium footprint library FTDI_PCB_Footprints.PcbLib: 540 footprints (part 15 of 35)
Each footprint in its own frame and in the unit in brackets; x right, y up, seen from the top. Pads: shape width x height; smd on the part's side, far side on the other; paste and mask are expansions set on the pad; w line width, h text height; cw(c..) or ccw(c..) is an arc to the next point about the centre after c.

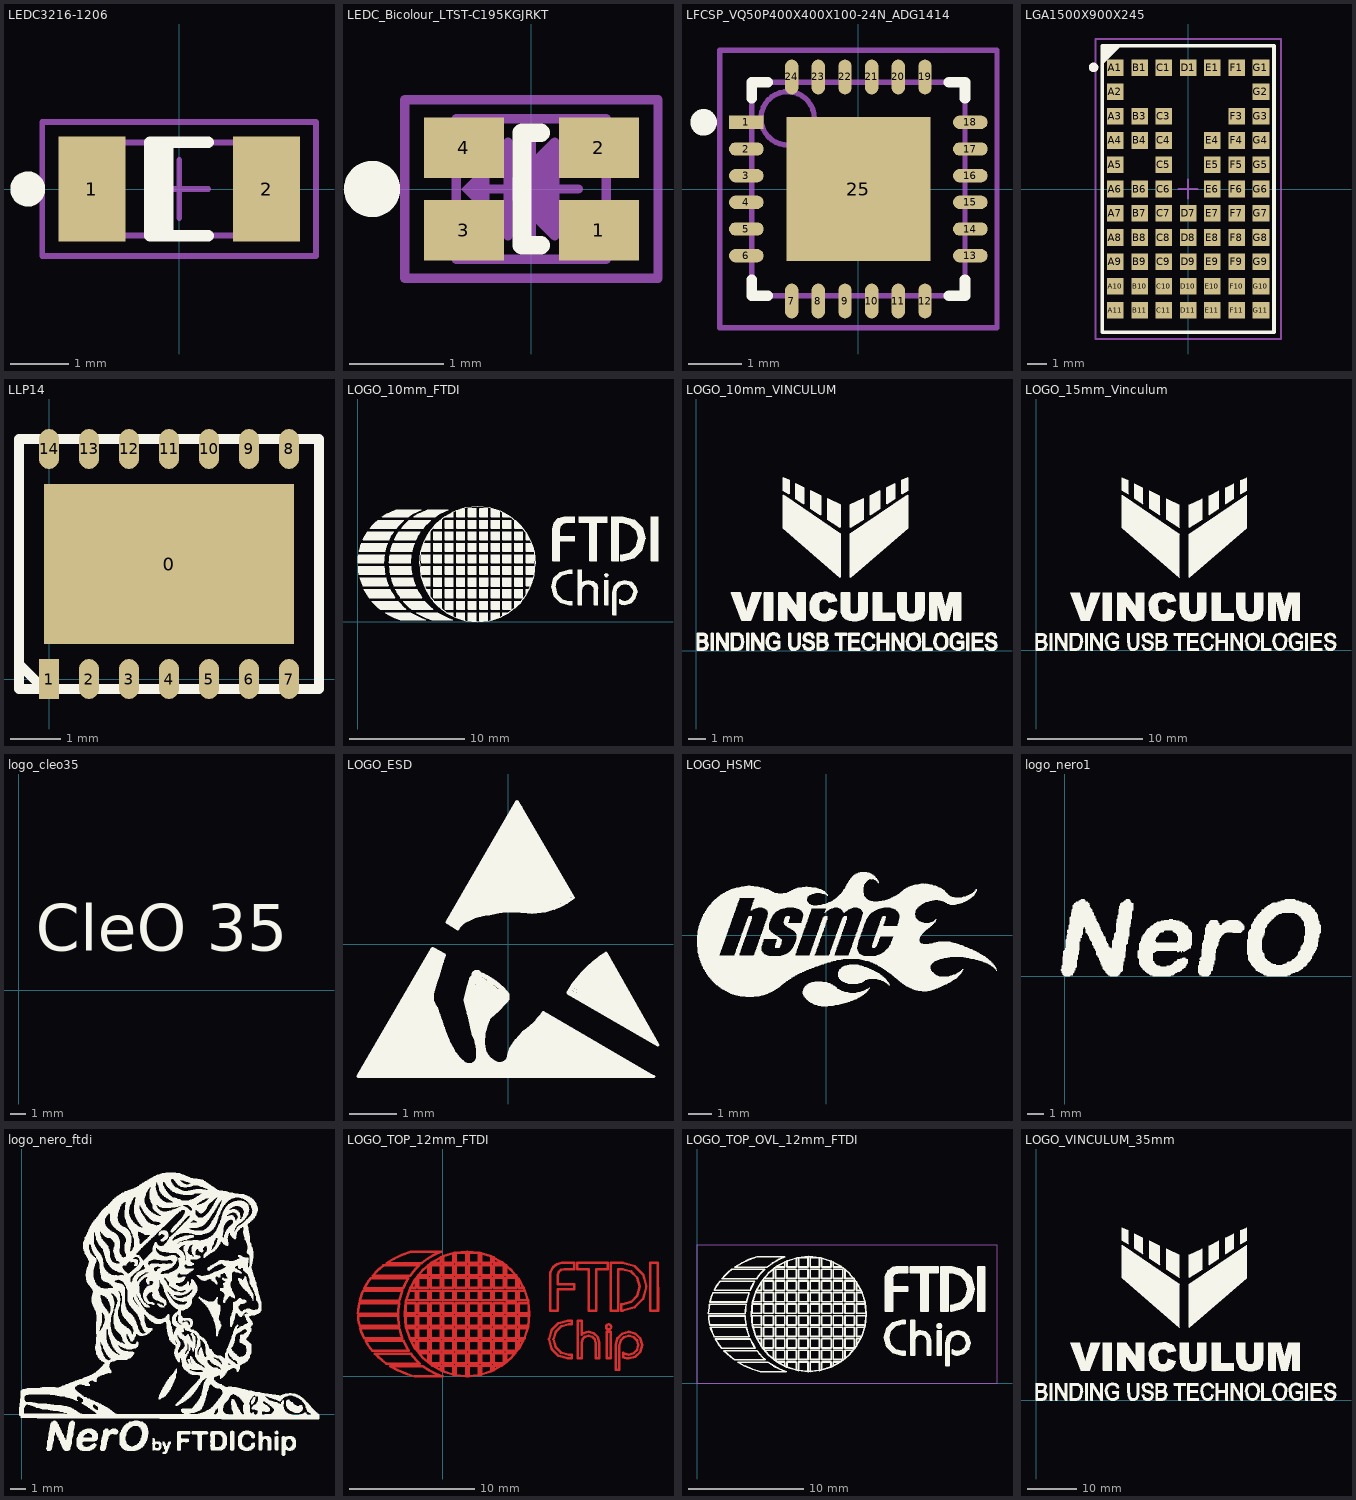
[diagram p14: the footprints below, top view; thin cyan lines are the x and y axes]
## LEDC3216-1206 [mm] "Chip LED diode; Body 3.2 x 1.6 mm (LxW typ)"
height 0.71
pads (2):
  rect 1.15x1.8 smd: 1(-1.5,0) 2(1.5,0)
Top Overlay:
  circle w0.3: c-2.6,0 r0.15
  lines w0.2: -0.35,-0.8 -0.35,0.8 ; -0.2,-0.8 -0.2,0.8 ; 0.5,-0.8 -0.5,-0.8 -0.5,0.8 0.5,0.8
M13_Assembly_Info:
  rectangle: -1.6,-0.8 -0.992,0.8
  lines w0.1: -1.6,-0.8 -1.6,0.8 1.6,0.8 1.6,-0.8 -1.6,-0.8
M15_Country_Yard:
  lines w0.1: -0.5,0 0.5,0 ; 0,-0.5 0,0.5 ; -2.35,-1.15 -2.35,1.15 2.35,1.15 2.35,-1.15 -2.35,-1.15
3D body: height 1.12, standoff -0.4, extent -1.6,-0.8 1.6,0.8

## LEDC_Bicolour_LTST-C195KGJRKT [mm] "Chip LED, 4-Leads, Body 2.0x1.5mm, IPC Medium Density"
height 0.45
pads (4):
  rect 0.85x0.65 smd: 1(0.72,-0.44) 2(0.72,0.44) 3(-0.72,-0.44) 4(-0.72,0.44)
Top Overlay:
  circle w0.3: c-1.7,0 r0.15
  lines w0.2: 0.1,-0.6 -0.1,-0.6 -0.1,0.6 0.1,0.6
M13_Assembly_Info:
  region: -0.75,0 -0.45,0.3 -0.45,-0.3
  region: 0.25,-0.5 0.25,0.5 -0.25,0
  lines w0.1: -0.25,-0.5 -0.25,0.5 ; -0.8,-0.75 -0.8,0.75 0.8,0.75 0.8,-0.75 -0.8,-0.75 ; -0.25,0 0.25,-0.5 0.25,0.5 -0.25,0
M15_Country_Yard:
  lines w0.1: -0.5,0 0.5,0 ; 0,-0.5 0,0.5 ; -1.35,-0.95 -1.35,0.95 1.35,0.95 1.35,-0.95 -1.35,-0.95
3D body: height 0.45, standoff 0, extent -0.8,-0.75 0.8,0.75

## LFCSP_VQ50P400X400X100-24N_ADG1414 [mm] "QFN, 24-Leads, Body 4.0x4.0mm (max), Pitch 0.50mm, IPC Medium Density"
height 1
pads (25):
  rect 0.65x0.25 smd: 1(-2.1,1.25)
  oval 0.65x0.25 smd: 2(-2.1,0.75) 3(-2.1,0.25) 4(-2.1,-0.25) 5(-2.1,-0.75) 6(-2.1,-1.25) 13(2.1,-1.25) 14(2.1,-0.75) 15(2.1,-0.25) 16(2.1,0.25) 17(2.1,0.75) 18(2.1,1.25)
  oval 0.25x0.65 smd: 7(-1.25,-2.1) 8(-0.75,-2.1) 9(-0.25,-2.1) 10(0.25,-2.1) 11(0.75,-2.1) 12(1.25,-2.1) 19(1.25,2.1) 20(0.75,2.1) 21(0.25,2.1) 22(-0.25,2.1) 23(-0.75,2.1) 24(-1.25,2.1)
  rect 2.7x2.7 smd: 25(0,0)
Top Overlay:
  circle w0.25: c-2.9,1.25 r0.125
  lines w0.2: -2,-1.7 -2,-2 -1.7,-2 ; -2,1.7 -2,2 -1.7,2 ; 1.7,-2 2,-2 2,-1.7 ; 1.7,2 2,2 2,1.7
M13_Assembly_Info:
  circle w0.1: c-1.325,1.325 r0.5
  lines w0.1: -2,-2 2,-2 2,2 -2,2 -2,-2
M15_Country_Yard:
  lines w0.1: -0.5,0 0.5,0 ; 0,-0.5 0,0.5 ; -2.6,-2.6 2.6,-2.6 2.6,2.6 -2.6,2.6 -2.6,-2.6
3D body: height 1, standoff 0.02, extent -2,-2 2,2

## LGA1500X900X245 [mm] "uModule, LGA, 77-Leads, Body 15.0x9.0mm,  Pitch 1.27mm, Linear Technology"
height 2.45
pads (66):
  rect 0.87x0.87 smd: A1(-3.81,6.35) A2(-3.81,5.08) A3(-3.81,3.81) A4(-3.81,2.54) A5(-3.81,1.27) A6(-3.81,0) A7(-3.81,-1.27) A8(-3.81,-2.54) A9(-3.81,-3.81) A10(-3.81,-5.08) A11(-3.81,-6.35) B1(-2.54,6.35) B3(-2.54,3.81) B4(-2.54,2.54) B6(-2.54,0) B7(-2.54,-1.27) B8(-2.54,-2.54) B9(-2.54,-3.81) B10(-2.54,-5.08) B11(-2.54,-6.35) C1(-1.27,6.35) C3(-1.27,3.81) C4(-1.27,2.54) C5(-1.27,1.27) C6(-1.27,0) C7(-1.27,-1.27) C8(-1.27,-2.54) C9(-1.27,-3.81) C10(-1.27,-5.08) C11(-1.27,-6.35) D1(0,6.35) D7(0,-1.27) D8(0,-2.54) D9(0,-3.81) D10(0,-5.08) D11(0,-6.35) E1(1.27,6.35) E4(1.27,2.54) E5(1.27,1.27) E6(1.27,0) E7(1.27,-1.27) E8(1.27,-2.54) E9(1.27,-3.81) E10(1.27,-5.08) E11(1.27,-6.35) F1(2.54,6.35) F3(2.54,3.81) F4(2.54,2.54) F5(2.54,1.27) F6(2.54,0) F7(2.54,-1.27) F8(2.54,-2.54) F9(2.54,-3.81) F10(2.54,-5.08) F11(2.54,-6.35) G1(3.81,6.35) G2(3.81,5.08) G3(3.81,3.81) G4(3.81,2.54) G5(3.81,1.27) G6(3.81,0) G7(3.81,-1.27) G8(3.81,-2.54) G9(3.81,-3.81) G10(3.81,-5.08) G11(3.81,-6.35)
Top Overlay:
  circle w0.25: c-4.95,6.365 r0.125
  region: -4.5,6.61 -3.61,7.5 -4.5,7.5
  lines w0.2: -4.5,6.61 -3.61,7.5 ; -4.5,-7.5 4.5,-7.5 4.5,7.5 -4.5,7.5 -4.5,-7.5
M13_Assembly_Info:
  lines w0.1: -4.5,-7.5 4.5,-7.5 4.5,7.5 -4.5,7.5 -4.5,-7.5
M15_Country_Yard:
  lines w0.1: -0.5,0 0.5,0 ; 0,-0.5 0,0.5 ; -4.85,-7.85 4.85,-7.85 4.85,7.85 -4.85,7.85 -4.85,-7.85
3D body: height 2.45, standoff 0, extent -4.5,-7.5 4.5,7.5

## LLP14 [mm]
pads (15):
  rect 5x3.2 smd: 0(2.4,2.3)
  rect 0.4x0.8 smd: 1(0,0)
  oval 0.4x0.8 smd: 2(0.8,0) 3(1.6,0) 4(2.4,0) 5(3.2,0) 6(4,0) 7(4.8,0) 8(4.8,4.6) 9(4,4.6) 10(3.2,4.6) 11(2.4,4.6) 12(1.6,4.6) 13(0.8,4.6) 14(0,4.6)
Top Overlay:
  lines w0.2: -0.6,0.3 -0.1,-0.2 ; -0.6,-0.2 5.4,-0.2 5.4,4.8 -0.6,4.8 -0.6,-0.2

## LOGO_10mm_FTDI [mm]
Top Overlay:
  drawing of 816 lines, arcs and shapes, not listed

## LOGO_10mm_VINCULUM [mm]
Top Overlay:
  drawing of 1161 lines, arcs and shapes, not listed

## LOGO_15mm_Vinculum [mm] "Logo, Vinculum, 15mm Height"
Top Overlay:
  drawing of 1150 lines, arcs and shapes, not listed

## logo_cleo35 [mm]
pads (88):
  round 0.4 on Top Overlay: 0(0.203,2.845) 0(0.203,3.327) 0(0.279,2.388) 0(0.279,3.759) 0(0.432,4.191) 0(0.457,1.905) 0(0.635,4.623) 0(0.711,1.448) 0(0.889,5.004) 0(1.067,1.041) 0(1.219,5.334) 0(1.448,0.711) 0(1.626,5.639) 0(1.854,0.457) 0(2.083,5.867) 0(2.362,0.279) 0(2.642,5.994) 0(2.896,0.178) 0(3.254,6.011) 0(3.48,0.159) 0(3.754,6.011) 0(3.98,0.159) 0(4.254,6.011) 0(4.48,0.159) 0(4.754,6.011) 0(4.98,0.159) 0(5.26,6.011) 0(5.486,0.159) 0(5.76,6.011) 0(5.986,0.159) 0(6.26,6.011) 0(6.486,0.159) 0(6.76,6.011) 0(6.986,0.159) 0(7.239,6.045) 0(7.465,0.192) 0(7.739,6.045) 0(7.965,0.192) 0(8.239,6.045) 0(8.465,0.192) 0(8.739,6.045) 0(8.965,0.192) 0(9.246,6.045) 0(9.472,0.192) 0(9.746,6.045) 0(9.972,0.192) 0(10.246,6.045) 0(10.472,0.192) 0(10.746,6.045) 0(10.972,0.192) 0(11.252,6.045) 0(11.478,0.192) 0(11.752,6.045) 0(11.978,0.192) 0(12.252,6.045) 0(12.478,0.192) 0(12.752,6.045) 0(12.978,0.192) 0(13.259,6.045) 0(13.485,0.192) 0(13.759,6.045) 0(13.985,0.192) 0(14.259,6.045) 0(14.485,0.192) 0(14.759,6.045) 0(14.985,0.192) 0(15.291,6.045) 0(15.517,0.192) 0(15.791,6.045) 0(16.017,0.192) 0(16.291,6.045) 0(16.509,0.192) 0(16.789,6.045) 0(17.018,0.33) 0(17.297,5.842) 0(17.501,0.533) 0(17.755,5.588) 0(17.932,0.813) 0(18.136,5.258) 0(18.313,1.143) 0(18.466,4.902) 0(18.618,1.575) 0(18.72,4.47) 0(18.872,2.032) 0(18.923,4.013) 0(18.999,2.515) 0(19.05,3.531) 0(19.075,3.023)
Top Overlay:
  text "CleO 35" at 1.092,1.524 h5.08

## LOGO_ESD [mm]
Top Overlay:
  drawing of 1029 lines, arcs and shapes, not listed

## LOGO_HSMC [mm]
Top Overlay:
  drawing of 2170 lines, arcs and shapes, not listed

## logo_nero1 [mm]
pads (99):
  round 0.3 on Top Overlay: 0(0.686,-1.295) 0(2.413,6.274) 0(2.819,-1.651) 0(4.445,6.274) 0(5.258,-1.651) 0(6.071,-1.651) 0(6.477,6.274) 0(8.103,-1.651) 0(8.509,6.274) 0(9.322,6.274) 0(10.135,-1.651) 0(11.76,6.274) 0(12.167,-1.651) 0(13.995,6.071) 1(1.194,-1.473) 1(2.007,6.274) 1(3.226,-1.651) 1(4.039,6.274) 1(5.664,-1.651) 1(6.071,6.274) 1(6.477,-1.651) 1(8.103,6.274) 1(8.509,-1.651) 1(8.915,6.274) 1(10.541,-1.651) 1(11.354,6.274) 1(12.573,-1.651) 1(13.487,6.198) 2(1.6,-1.575) 2(1.6,6.223) 2(3.632,-1.651) 2(3.632,6.274) 2(5.664,6.274) 2(6.883,-1.651) 2(7.696,6.274) 2(8.915,-1.651) 2(10.947,-1.651) 2(10.947,6.274) 2(12.979,-1.626) 2(12.979,6.274) 3(1.067,6.096) 3(2.007,-1.651) 3(3.226,6.274) 3(4.039,-1.651) 3(5.258,6.274) 3(7.29,-1.651) 3(7.29,6.274) 3(9.322,-1.651) 3(10.541,6.274) 3(11.354,-1.651) 3(12.573,6.274) 3(13.386,-1.6) 4(-1.651,2.464) 4(-1.626,1.905) 4(-1.575,2.997) 4(-1.524,1.346) 4(-1.448,3.505) 4(-1.346,0.787) 4(-1.27,3.962) 4(-1.092,0.254) 4(-1.041,4.394) 4(-0.762,4.801) 4(-0.737,-0.229) 4(-0.356,5.232) 4(-0.33,-0.66) 4(0.076,5.588) 4(0.178,-1.041) 4(0.559,5.867) 4(2.413,-1.645) 4(2.819,6.268) 4(4.445,-1.645) 4(4.851,6.268) 4(6.883,6.268) 4(7.696,-1.645) 4(9.728,-1.645) 4(10.135,6.268) 4(11.76,-1.645) 4(12.167,6.268) 4(13.792,-1.499) 4(14.529,5.842) 4(14.605,-1.194) 4(14.986,5.563) 4(15.088,-0.889) 4(15.392,5.232) 4(15.494,-0.559) 4(15.824,-0.203) 4(15.824,4.801) 4(16.129,0.203) 4(16.129,4.343) 4(16.332,0.635) 4(16.383,3.81) 4(16.51,1.092) 4(16.586,3.277) 4(16.637,1.626) 4(16.662,2.718) 4(16.688,2.159) 9(14.199,-1.372) 10(4.851,-1.651) 10(9.728,6.274)
Top Overlay:
  drawing of 1107 lines, arcs and shapes, not listed

## logo_nero_ftdi [mm]
Top Overlay:
  drawing of 7473 lines, arcs and shapes, not listed

## LOGO_TOP_12mm_FTDI [mm]
Top Layer:
  lines w0.2: -2.955,4.121 -2.955,4.857 -2.154,4.857 -2.154,4.059 ; -2.955,5.795 -2.955,5.062 -2.154,5.062 -2.154,5.867 -2.944,5.867 ; -2.944,4.061 -2.154,4.059 ; -2.908,6.072 -2.154,6.072 -2.154,6.869 -2.656,6.869 ; -2.899,3.861 -2.154,3.858 -2.154,3.053 -2.62,3.053 ; -2.57,7.07 -2.154,7.07 -2.154,7.809 ; -2.527,2.855 -2.154,2.855 -2.154,2.208 ; -2.174,4.062 -2.168,4.061 -2.16,4.059 -2.154,4.059 ; -1.951,8.082 -1.147,8.082 -1.147,8.88 ; -1.886,1.85 -1.147,1.85 -1.147,1.121 ; -0.898,9.084 -0.141,9.084 -0.141,9.513 ; -0.765,0.843 -0.141,0.843 -0.141,0.496 ; 0.056,0.409 0.056,0.843 0.863,0.843 0.863,0.151 ; 0.056,9.601 0.056,9.084 0.863,9.084 0.863,9.859 ; 1.062,0.105 1.062,0.843 1.868,0.843 1.868,0.024 ; 2.068,0.026 2.068,0.843 2.874,0.843 2.874,0.11 ; 3.076,0.151 3.076,0.843 3.879,0.843 3.879,0.409 ; 3.076,9.859 3.076,9.084 3.879,9.084 3.879,9.595 ; 4.073,0.498 4.073,0.843 4.686,0.843 ; 4.073,9.508 4.073,9.084 4.809,9.084 ; 5.079,1.13 5.079,1.85 5.8,1.85 ; 5.079,8.88 5.079,8.082 5.872,8.082 ; 6.081,2.22 6.081,2.855 6.446,2.855 ; 6.081,7.791 6.081,7.07 6.488,7.07 ; 6.542,3.053 6.081,3.053 6.081,3.858 6.806,3.858 ; 6.575,6.869 6.081,6.869 6.081,6.072 6.824,6.072 ; 6.846,4.059 6.081,4.059 6.081,4.857 6.891,4.857 6.891,4.326 ; 6.847,5.867 6.081,5.867 6.081,5.062 6.891,5.062 6.891,5.694 ; 9.197,8.111 9.265,8.347 9.447,8.515 9.705,8.579 10.507,8.579 10.508,9.084 9.513,9.086 9.139,8.979 8.822,8.727 8.627,8.382 8.611,8.316 8.601,8.25 8.597,8.187 8.6,5.263 9.202,5.263 9.202,6.974 10.507,6.974 10.507,7.375 9.202,7.375 9.197,8.111 ; 9.197,8.111 9.197,8.11 9.197,8.113 9.197,8.111 ; 10.807,1.445 10.818,1.445 10.807,1.445 ; 10.807,1.445 10.807,4.462 11.111,4.462 11.111,3.35 11.276,3.461 11.464,3.533 11.662,3.559 12.094,3.442 12.401,3.137 12.518,2.706 12.518,1.445 12.216,1.445 12.216,2.709 12.14,2.986 11.941,3.181 11.662,3.256 11.384,3.182 11.186,2.987 11.111,2.71 11.111,1.445 10.807,1.445 ; 14.387,9.085 13.421,9.077 13.421,5.261 14.026,5.264 14.026,8.58 14.389,8.579 15.066,8.388 15.551,7.887 15.737,7.18 15.553,6.47 15.072,5.965 14.396,5.772 14.29,5.772 14.29,5.27 14.393,5.27 15.348,5.532 16.028,6.219 16.287,7.183 16.026,8.143 15.343,8.825 14.386,9.085 ; 14.386,9.085 14.387,9.085 ; 14.387,9.085 14.387,9.085 ; 14.387,9.085 14.387,9.085 ; -6.764,5.041 -6.758,5.041 -6.746,5.041 -6.739,5.041 -3.559,5.027 -3.546,5.305 -3.517,5.588 -3.477,5.853 -6.657,5.853 -6.696,5.596 -6.742,5.311 -6.764,5.041 ; -6.742,4.841 -6.726,4.571 -6.686,4.303 -6.636,4.047 -3.488,4.047 -3.525,4.298 -3.556,4.576 -3.567,4.841 -6.742,4.841 ; -6.624,6.049 -6.554,6.314 -6.457,6.592 -6.353,6.857 -3.227,6.857 -3.316,6.592 -3.4,6.314 -3.461,6.049 -6.624,6.049 ; -6.576,3.846 -6.49,3.577 -6.386,3.294 -6.267,3.04 -3.211,3.04 -3.304,3.294 -3.385,3.577 -3.45,3.846 -6.576,3.846 ; -6.254,7.06 -6.107,7.326 -5.93,7.603 -5.748,7.854 -2.744,7.854 -2.886,7.603 -3.02,7.326 -3.136,7.06 -6.254,7.06 ; -6.158,2.839 -6.003,2.572 -5.808,2.291 -5.605,2.037 -2.694,2.037 -2.851,2.295 -2.998,2.567 -3.126,2.839 -6.158,2.839 ; -5.583,8.051 -5.328,8.334 -5.034,8.62 -4.73,8.875 -1.883,8.875 -2.134,8.621 -2.377,8.336 -2.588,8.055 -5.583,8.051 ; -5.42,1.827 -2.548,1.827 -2.322,1.544 -2.083,1.275 -1.831,1.031 -4.502,1.031 -4.818,1.279 -5.138,1.552 -5.42,1.827 ; -4.473,9.062 -3.878,9.419 -3.224,9.732 -2.546,9.979 -0.131,9.979 -0.676,9.732 -1.197,9.419 -1.676,9.062 -4.473,9.062 ; -4.185,0.821 -3.576,0.49 -2.919,0.208 -2.243,0 0,0 -0.545,0.213 -1.093,0.498 -1.581,0.821 -4.185,0.821 ; -3.035,5 -2.934,6.002 -2.643,6.936 -2.182,7.782 -1.573,8.52 -0.835,9.13 0.012,9.59 0.946,9.881 1.948,9.983 2.951,9.881 3.886,9.59 4.732,9.13 5.47,8.52 6.079,7.782 6.54,6.936 6.831,6.002 6.932,5 6.831,3.997 6.54,3.062 6.079,2.216 5.47,1.478 4.732,0.868 3.886,0.408 2.951,0.117 1.948,0.015 0.946,0.117 0.012,0.408 -0.835,0.868 -1.573,1.478 -2.182,2.216 -2.643,3.062 -2.934,3.997 -3.035,5 ; -1.951,2.056 -1.951,2.855 -1.143,2.855 -1.143,2.056 -1.951,2.056 ; -1.951,3.059 -1.951,3.858 -1.143,3.858 -1.143,3.059 -1.951,3.059 ; -1.951,4.058 -1.951,4.857 -1.143,4.857 -1.143,4.058 -1.951,4.058 ; -1.951,5.068 -1.951,5.867 -1.143,5.867 -1.143,5.068 -1.951,5.068 ; -1.951,6.071 -1.951,6.869 -1.143,6.869 -1.143,6.071 -1.951,6.071 ; -1.951,7.075 -1.951,7.875 -1.143,7.875 -1.143,7.075 -1.951,7.075 ; -0.949,1.051 -0.949,1.85 -0.141,1.85 -0.141,1.051 -0.949,1.051 ; -0.949,2.056 -0.949,2.855 -0.141,2.855 -0.141,2.056 -0.949,2.056 ; -0.949,3.059 -0.949,3.858 -0.141,3.858 -0.141,3.059 -0.949,3.059 ; -0.949,4.058 -0.949,4.857 -0.141,4.857 -0.141,4.058 -0.949,4.058 ; -0.949,5.068 -0.949,5.867 -0.141,5.867 -0.141,5.068 -0.949,5.068 ; -0.949,6.071 -0.949,6.869 -0.141,6.869 -0.141,6.071 -0.949,6.071 ; -0.949,7.075 -0.949,7.875 -0.141,7.875 -0.141,7.075 -0.949,7.075 ; -0.949,8.082 -0.949,8.88 -0.141,8.88 -0.141,8.082 -0.949,8.082 ; 0.056,1.051 0.056,1.85 0.865,1.85 0.865,1.051 0.056,1.051 ; 0.056,2.056 0.056,2.855 0.865,2.855 0.865,2.056 0.056,2.056 ; 0.056,3.059 0.056,3.858 0.865,3.858 0.865,3.059 0.056,3.059 ; 0.056,4.058 0.056,4.857 0.865,4.857 0.865,4.058 0.056,4.058 ; 0.056,5.068 0.056,5.867 0.865,5.867 0.865,5.068 0.056,5.068 ; 0.056,6.071 0.056,6.869 0.865,6.869 0.865,6.071 0.056,6.071 ; 0.056,7.075 0.056,7.875 0.865,7.875 0.865,7.075 0.056,7.075 ; 0.056,8.082 0.056,8.88 0.865,8.88 0.865,8.082 0.056,8.082 ; 1.062,1.051 1.062,1.85 1.869,1.85 1.869,1.051 1.062,1.051 ; 1.062,2.056 1.062,2.855 1.869,2.855 1.869,2.056 1.062,2.056 ; 1.062,3.059 1.062,3.858 1.869,3.858 1.869,3.059 1.062,3.059 ; 1.062,4.058 1.062,4.857 1.869,4.857 1.869,4.058 1.062,4.058 ; 1.062,5.068 1.062,5.867 1.869,5.867 1.869,5.068 1.062,5.068 ; 1.062,6.071 1.062,6.869 1.869,6.869 1.869,6.071 1.062,6.071 ; 1.062,7.075 1.062,7.875 1.869,7.875 1.869,7.075 1.062,7.075 ; 1.062,8.082 1.062,8.88 1.869,8.88 1.869,8.082 1.062,8.082 ; 1.062,9.084 1.062,9.882 1.869,9.882 1.869,9.084 1.062,9.084 ; 2.068,1.051 2.068,1.85 2.876,1.85 2.876,1.051 2.068,1.051 ; 2.068,2.056 2.068,2.855 2.876,2.855 2.876,2.056 2.068,2.056 ; 2.068,3.059 2.068,3.858 2.876,3.858 2.876,3.059 2.068,3.059 ; 2.068,4.058 2.068,4.857 2.876,4.857 2.876,4.058 2.068,4.058 ; 2.068,5.068 2.068,5.867 2.876,5.867 2.876,5.068 2.068,5.068 ; 2.068,6.071 2.068,6.869 2.876,6.869 2.876,6.071 2.068,6.071 ; 2.068,7.075 2.068,7.875 2.876,7.875 2.876,7.075 2.068,7.075 ; 2.068,8.082 2.068,8.88 2.876,8.88 2.876,8.082 2.068,8.082 ; 2.068,9.084 2.068,9.882 2.876,9.882 2.876,9.084 2.068,9.084 ; 3.076,1.051 3.076,1.85 3.883,1.85 3.883,1.051 3.076,1.051 ; 3.076,2.056 3.076,2.855 3.883,2.855 3.883,2.056 3.076,2.056 ; 3.076,3.059 3.076,3.858 3.883,3.858 3.883,3.059 3.076,3.059 ; 3.076,4.058 3.076,4.857 3.883,4.857 3.883,4.058 3.076,4.058 ; 3.076,5.068 3.076,5.867 3.883,5.867 3.883,5.068 3.076,5.068 ; 3.076,6.071 3.076,6.869 3.883,6.869 3.883,6.071 3.076,6.071 ; 3.076,7.075 3.076,7.875 3.883,7.875 3.883,7.075 3.076,7.075 ; 3.076,8.082 3.076,8.88 3.883,8.88 3.883,8.082 3.076,8.082 ; 4.073,1.051 4.073,1.85 4.88,1.85 4.88,1.051 4.073,1.051 ; 4.073,2.056 4.073,2.855 4.88,2.855 4.88,2.056 4.073,2.056 ; 4.073,3.059 4.073,3.858 4.88,3.858 4.88,3.059 4.073,3.059 ; 4.073,4.058 4.073,4.857 4.88,4.857 4.88,4.058 4.073,4.058 ; 4.073,5.068 4.073,5.867 4.88,5.867 4.88,5.068 4.073,5.068 ; 4.073,6.071 4.073,6.869 4.88,6.869 4.88,6.071 4.073,6.071 ; 4.073,7.075 4.073,7.875 4.88,7.875 4.88,7.075 4.073,7.075 ; 4.073,8.082 4.073,8.88 4.88,8.88 4.88,8.082 4.073,8.082 ; 5.079,2.056 5.079,2.855 5.887,2.855 5.887,2.056 5.079,2.056 ; 5.079,3.059 5.079,3.858 5.887,3.858 5.887,3.059 5.079,3.059 ; 5.079,4.058 5.079,4.857 5.887,4.857 5.887,4.058 5.079,4.058 ; 5.079,5.068 5.079,5.867 5.887,5.867 5.887,5.068 5.079,5.068 ; 5.079,6.066 5.079,6.865 5.887,6.865 5.887,6.066 5.079,6.066 ; 5.079,7.075 5.079,7.875 5.887,7.875 5.887,7.075 5.079,7.075 ; 8.497,2.954 8.703,2.194 9.244,1.652 10.005,1.445 10.307,1.445 10.307,1.75 10.061,1.75 9.455,1.914 9.022,2.347 8.857,2.954 9.023,3.561 9.458,3.993 10.066,4.158 10.307,4.158 10.307,4.463 10.002,4.463 9.242,4.256 8.702,3.715 8.497,2.954 ; 10.769,8.578 10.769,9.085 13.181,9.085 13.181,8.578 12.276,8.579 12.278,5.261 11.669,5.261 11.673,8.578 10.769,8.578 ; 13.066,3.96 13.093,4.06 13.165,4.13 13.265,4.157 13.366,4.13 13.438,4.06 13.465,3.96 13.438,3.858 13.366,3.786 13.265,3.759 13.165,3.786 13.093,3.858 13.066,3.96 ; 13.117,1.445 13.117,3.56 13.423,3.56 13.423,1.445 13.117,1.445 ; 13.821,0.538 14.13,0.538 14.13,2.502 14.233,2.881 14.504,3.151 14.883,3.255 15.262,3.151 15.533,2.881 15.636,2.501 15.533,2.122 15.262,1.852 14.883,1.749 14.719,1.768 14.561,1.822 14.419,1.909 14.419,1.552 14.566,1.495 14.72,1.458 14.878,1.445 15.411,1.589 15.79,1.969 15.934,2.502 15.79,3.034 15.411,3.414 14.878,3.559 14.345,3.414 13.966,3.034 13.821,2.502 13.821,0.538 ; 16.603,5.268 16.603,9.085 17.207,9.085 17.209,5.268 16.603,5.268

## LOGO_TOP_OVL_12mm_FTDI [mm]
Top Overlay:
  drawing of 586 lines, arcs and shapes, not listed
M15_Country_Yard:
  lines w0.1: 0,0 26.02,0 26.02,12.01 0,12.01 0,0

## LOGO_VINCULUM_35mm [mm] "Logo, Vinculum, H=35mm"
Top Overlay:
  drawing of 1150 lines, arcs and shapes, not listed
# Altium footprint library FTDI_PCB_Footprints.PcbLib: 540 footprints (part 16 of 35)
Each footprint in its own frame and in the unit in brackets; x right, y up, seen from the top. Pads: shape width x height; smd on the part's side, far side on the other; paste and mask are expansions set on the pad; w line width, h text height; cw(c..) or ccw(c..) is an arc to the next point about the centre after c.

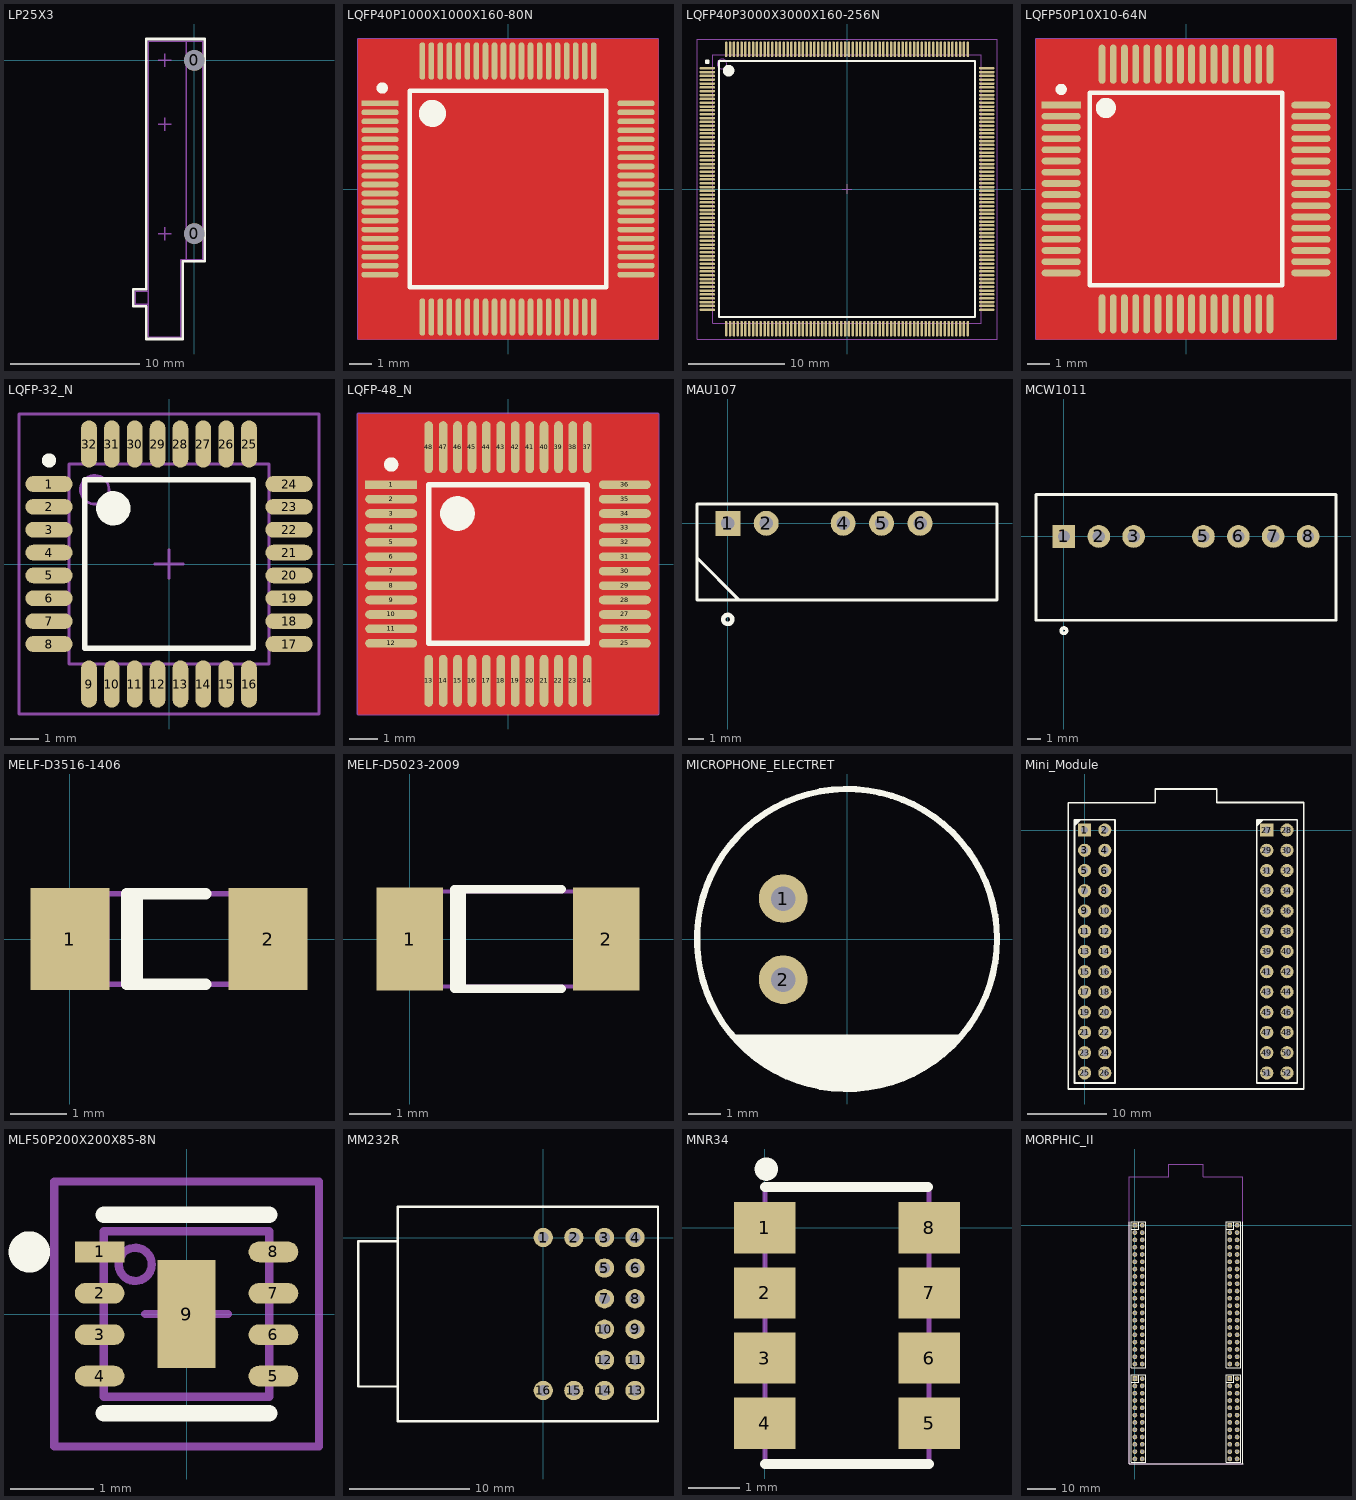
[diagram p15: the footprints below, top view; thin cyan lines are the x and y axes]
## LP25X3 [mm] "Light Pipe; Dialight; 515-1064; + 3xLEDs 0805 (Red, Green, Yellow)"
height 3.5
pads (2):
  round 1.6 hole 1.6 unplated: 0(0,-13.41) 0(0,0)
Top Overlay:
  lines w0.2: -4.73,-19.02 -4.73,-17.71 -3.72,-17.71 -3.72,1.65 0.79,1.65 0.79,-15.56 -0.89,-15.56 -0.89,-21.56 -3.72,-21.56 -3.72,-19.02 -4.73,-19.02
M13_Assembly_Info:
  lines w0.1: -3.565,-21.41 -3.565,1.492 0.635,1.492 0.635,-15.41 -1.04,-15.41 -1.04,-21.41 -3.54,-21.41 ; -3.565,-18.87 -4.585,-18.87 -4.585,-17.85 -3.565,-17.85 ; -0.635,-15.41 -0.635,1.492
M15_Country_Yard:
  lines w0.1: -2.79,-13.41 -1.79,-13.41 ; -2.79,-4.95 -1.79,-4.95 ; -2.79,0 -1.79,0 ; -2.29,-13.91 -2.29,-12.91 ; -2.29,-5.45 -2.29,-4.45 ; -2.29,-0.5 -2.29,0.5
3D body: height 13.71, standoff -2.85, extent -4.612,-21.408 0.57,1.528

## LQFP40P1000X1000X160-80N [mm] "LQFP, 80-Leads, Body 10.0x10.0mm (max), Pitch 0.40mm, IPC Medium Density"
height 1.6
pads (80):
  rect 1.65x0.25 smd: 1(-5.675,3.8)
  oval 1.65x0.25 smd: 2(-5.675,3.4) 3(-5.675,3) 4(-5.675,2.6) 5(-5.675,2.2) 6(-5.675,1.8) 7(-5.675,1.4) 8(-5.675,1) 9(-5.675,0.6) 10(-5.675,0.2) 11(-5.675,-0.2) 12(-5.675,-0.6) 13(-5.675,-1) 14(-5.675,-1.4) 15(-5.675,-1.8) 16(-5.675,-2.2) 17(-5.675,-2.6) 18(-5.675,-3) 19(-5.675,-3.4) 20(-5.675,-3.8) 41(5.675,-3.8) 42(5.675,-3.4) 43(5.675,-3) 44(5.675,-2.6) 45(5.675,-2.2) 46(5.675,-1.8) 47(5.675,-1.4) 48(5.675,-1) 49(5.675,-0.6) 50(5.675,-0.2) 51(5.675,0.2) 52(5.675,0.6) 53(5.675,1) 54(5.675,1.4) 55(5.675,1.8) 56(5.675,2.2) 57(5.675,2.6) 58(5.675,3) 59(5.675,3.4) 60(5.675,3.8)
  oval 0.25x1.65 smd: 21(-3.8,-5.675) 22(-3.4,-5.675) 23(-3,-5.675) 24(-2.6,-5.675) 25(-2.2,-5.675) 26(-1.8,-5.675) 27(-1.4,-5.675) 28(-1,-5.675) 29(-0.6,-5.675) 30(-0.2,-5.675) 31(0.2,-5.675) 32(0.6,-5.675) 33(1,-5.675) 34(1.4,-5.675) 35(1.8,-5.675) 36(2.2,-5.675) 37(2.6,-5.675) 38(3,-5.675) 39(3.4,-5.675) 40(3.8,-5.675) 61(3.8,5.675) 62(3.4,5.675) 63(3,5.675) 64(2.6,5.675) 65(2.2,5.675) 66(1.8,5.675) 67(1.4,5.675) 68(1,5.675) 69(0.6,5.675) 70(0.2,5.675) 71(-0.2,5.675) 72(-0.6,5.675) 73(-1,5.675) 74(-1.4,5.675) 75(-1.8,5.675) 76(-2.2,5.675) 77(-2.6,5.675) 78(-3,5.675) 79(-3.4,5.675) 80(-3.8,5.675)
Top Layer:
  pour cut-out: -6.65,6.65 6.65,6.65 6.65,-6.65 -6.65,-6.65
Top Overlay:
  circle w0.6: c-3.35,3.35 r0.3
  circle w0.25: c-5.575,4.475 r0.125
  lines w0.2: -4.35,-4.35 4.35,-4.35 4.35,4.35 -4.35,4.35 -4.35,-4.35
M13_Assembly_Info:
  circle w0.1: c-4.05,4.05 r0.5
  lines w0.1: -5,-5 5,-5 5,5 -5,5 -5,-5
M15_Country_Yard:
  lines w0.1: -0.5,0 0.5,0 ; 0,-0.5 0,0.5 ; -6.65,-6.65 6.65,-6.65 6.65,6.65 -6.65,6.65 -6.65,-6.65
3D body: height 1.6, standoff 0.15, extent -5,-5 5,5

## LQFP40P3000X3000X160-256N [mm] "LQFP, 256-Leads, Body 30.0x30.0mm (max), Pitch 0.40mm, IPC Medium Density"
height 1.6
pads (256):
  oval 1.65x0.25 smd: 1(-14.575,12.6) 2(-14.575,12.2) 3(-14.575,11.8) 4(-14.575,11.4) 5(-14.575,11) 6(-14.575,10.6) 7(-14.575,10.2) 8(-14.575,9.8) 9(-14.575,9.4) 10(-14.575,9) 11(-14.575,8.6) 12(-14.575,8.2) 13(-14.575,7.8) 14(-14.575,7.4) 15(-14.575,7) 16(-14.575,6.6) 17(-14.575,6.2) 18(-14.575,5.8) 19(-14.575,5.4) 20(-14.575,5) 21(-14.575,4.6) 22(-14.575,4.2) 23(-14.575,3.8) 24(-14.575,3.4) 25(-14.575,3) 26(-14.575,2.6) 27(-14.575,2.2) 28(-14.575,1.8) 29(-14.575,1.4) 30(-14.575,1) 31(-14.575,0.6) 32(-14.575,0.2) 33(-14.575,-0.2) 34(-14.575,-0.6) 35(-14.575,-1) 36(-14.575,-1.4) 37(-14.575,-1.8) 38(-14.575,-2.2) 39(-14.575,-2.6) 40(-14.575,-3) 41(-14.575,-3.4) 42(-14.575,-3.8) 43(-14.575,-4.2) 44(-14.575,-4.6) 45(-14.575,-5) 46(-14.575,-5.4) 47(-14.575,-5.8) 48(-14.575,-6.2) 49(-14.575,-6.6) 50(-14.575,-7) 51(-14.575,-7.4) 52(-14.575,-7.8) 53(-14.575,-8.2) 54(-14.575,-8.6) 55(-14.575,-9) 56(-14.575,-9.4) 57(-14.575,-9.8) 58(-14.575,-10.2) 59(-14.575,-10.6) 60(-14.575,-11) 61(-14.575,-11.4) 62(-14.575,-11.8) 63(-14.575,-12.2) 64(-14.575,-12.6) 129(14.575,-12.6) 130(14.575,-12.2) 131(14.575,-11.8) 132(14.575,-11.4) 133(14.575,-11) 134(14.575,-10.6) 135(14.575,-10.2) 136(14.575,-9.8) 137(14.575,-9.4) 138(14.575,-9) 139(14.575,-8.6) 140(14.575,-8.2) 141(14.575,-7.8) 142(14.575,-7.4) 143(14.575,-7) 144(14.575,-6.6) 145(14.575,-6.2) 146(14.575,-5.8) 147(14.575,-5.4) 148(14.575,-5) 149(14.575,-4.6) 150(14.575,-4.2) 151(14.575,-3.8) 152(14.575,-3.4) 153(14.575,-3) 154(14.575,-2.6) 155(14.575,-2.2) 156(14.575,-1.8) 157(14.575,-1.4) 158(14.575,-1) 159(14.575,-0.6) 160(14.575,-0.2) 161(14.575,0.2) 162(14.575,0.6) 163(14.575,1) 164(14.575,1.4) 165(14.575,1.8) 166(14.575,2.2) 167(14.575,2.6) 168(14.575,3) 169(14.575,3.4) 170(14.575,3.8) 171(14.575,4.2) 172(14.575,4.6) 173(14.575,5) 174(14.575,5.4) 175(14.575,5.8) 176(14.575,6.2) 177(14.575,6.6) 178(14.575,7) 179(14.575,7.4) 180(14.575,7.8) 181(14.575,8.2) 182(14.575,8.6) 183(14.575,9) 184(14.575,9.4) 185(14.575,9.8) 186(14.575,10.2) 187(14.575,10.6) 188(14.575,11) 189(14.575,11.4) 190(14.575,11.8) 191(14.575,12.2) 192(14.575,12.6)
  oval 0.25x1.65 smd: 65(-12.6,-14.575) 66(-12.2,-14.575) 67(-11.8,-14.575) 68(-11.4,-14.575) 69(-11,-14.575) 70(-10.6,-14.575) 71(-10.2,-14.575) 72(-9.8,-14.575) 73(-9.4,-14.575) 74(-9,-14.575) 75(-8.6,-14.575) 76(-8.2,-14.575) 77(-7.8,-14.575) 78(-7.4,-14.575) 79(-7,-14.575) 80(-6.6,-14.575) 81(-6.2,-14.575) 82(-5.8,-14.575) 83(-5.4,-14.575) 84(-5,-14.575) 85(-4.6,-14.575) 86(-4.2,-14.575) 87(-3.8,-14.575) 88(-3.4,-14.575) 89(-3,-14.575) 90(-2.6,-14.575) 91(-2.2,-14.575) 92(-1.8,-14.575) 93(-1.4,-14.575) 94(-1,-14.575) 95(-0.6,-14.575) 96(-0.2,-14.575) 97(0.2,-14.575) 98(0.6,-14.575) 99(1,-14.575) 100(1.4,-14.575) 101(1.8,-14.575) 102(2.2,-14.575) 103(2.6,-14.575) 104(3,-14.575) 105(3.4,-14.575) 106(3.8,-14.575) 107(4.2,-14.575) 108(4.6,-14.575) 109(5,-14.575) 110(5.4,-14.575) 111(5.8,-14.575) 112(6.2,-14.575) 113(6.6,-14.575) 114(7,-14.575) 115(7.4,-14.575) 116(7.8,-14.575) 117(8.2,-14.575) 118(8.6,-14.575) 119(9,-14.575) 120(9.4,-14.575) 121(9.8,-14.575) 122(10.2,-14.575) 123(10.6,-14.575) 124(11,-14.575) 125(11.4,-14.575) 126(11.8,-14.575) 127(12.2,-14.575) 128(12.6,-14.575) 193(12.6,14.575) 194(12.2,14.575) 195(11.8,14.575) 196(11.4,14.575) 197(11,14.575) 198(10.6,14.575) 199(10.2,14.575) 200(9.8,14.575) 201(9.4,14.575) 202(9,14.575) 203(8.6,14.575) 204(8.2,14.575) 205(7.8,14.575) 206(7.4,14.575) 207(7,14.575) 208(6.6,14.575) 209(6.2,14.575) 210(5.8,14.575) 211(5.4,14.575) 212(5,14.575) 213(4.6,14.575) 214(4.2,14.575) 215(3.8,14.575) 216(3.4,14.575) 217(3,14.575) 218(2.6,14.575) 219(2.2,14.575) 220(1.8,14.575) 221(1.4,14.575) 222(1,14.575) 223(0.6,14.575) 224(0.2,14.575) 225(-0.2,14.575) 226(-0.6,14.575) 227(-1,14.575) 228(-1.4,14.575) 229(-1.8,14.575) 230(-2.2,14.575) 231(-2.6,14.575) 232(-3,14.575) 233(-3.4,14.575) 234(-3.8,14.575) 235(-4.2,14.575) 236(-4.6,14.575) 237(-5,14.575) 238(-5.4,14.575) 239(-5.8,14.575) 240(-6.2,14.575) 241(-6.6,14.575) 242(-7,14.575) 243(-7.4,14.575) 244(-7.8,14.575) 245(-8.2,14.575) 246(-8.6,14.575) 247(-9,14.575) 248(-9.4,14.575) 249(-9.8,14.575) 250(-10.2,14.575) 251(-10.6,14.575) 252(-11,14.575) 253(-11.4,14.575) 254(-11.8,14.575) 255(-12.2,14.575) 256(-12.6,14.575)
Top Overlay:
  circle w0.6: c-12.35,12.35 r0.3
  circle w0.25: c-14.575,13.275 r0.125
  lines w0.2: -13.35,-13.35 13.35,-13.35 13.35,13.35 -13.35,13.35 -13.35,-13.35
M13_Assembly_Info:
  circle w0.1: c-13.05,13.05 r0.5
  lines w0.1: -14,-14 14,-14 14,14 -14,14 -14,-14
M15_Country_Yard:
  lines w0.1: -0.5,0 0.5,0 ; 0,-0.5 0,0.5 ; -15.65,-15.65 15.65,-15.65 15.65,15.65 -15.65,15.65 -15.65,-15.65
3D body: height 1.6, standoff 0.15, extent -14,-14 14,14

## LQFP50P10X10-64N [mm] "LQFP, 64-Leads, Body 10x10mm (max), Pitch 0.50mm, IPC Medium Density"
height 1.6
pads (64):
  rect 1.75x0.3 smd: 1(-5.575,3.75)
  oval 1.75x0.3 smd: 2(-5.575,3.25) 3(-5.575,2.75) 4(-5.575,2.25) 5(-5.575,1.75) 6(-5.575,1.25) 7(-5.575,0.75) 8(-5.575,0.25) 9(-5.575,-0.25) 10(-5.575,-0.75) 11(-5.575,-1.25) 12(-5.575,-1.75) 13(-5.575,-2.25) 14(-5.575,-2.75) 15(-5.575,-3.25) 16(-5.575,-3.75) 33(5.575,-3.75) 34(5.575,-3.25) 35(5.575,-2.75) 36(5.575,-2.25) 37(5.575,-1.75) 38(5.575,-1.25) 39(5.575,-0.75) 40(5.575,-0.25) 41(5.575,0.25) 42(5.575,0.75) 43(5.575,1.25) 44(5.575,1.75) 45(5.575,2.25) 46(5.575,2.75) 47(5.575,3.25) 48(5.575,3.75)
  oval 0.3x1.75 smd: 17(-3.75,-5.575) 18(-3.25,-5.575) 19(-2.75,-5.575) 20(-2.25,-5.575) 21(-1.75,-5.575) 22(-1.25,-5.575) 23(-0.75,-5.575) 24(-0.25,-5.575) 25(0.25,-5.575) 26(0.75,-5.575) 27(1.25,-5.575) 28(1.75,-5.575) 29(2.25,-5.575) 30(2.75,-5.575) 31(3.25,-5.575) 32(3.75,-5.575) 49(3.75,5.575) 50(3.25,5.575) 51(2.75,5.575) 52(2.25,5.575) 53(1.75,5.575) 54(1.25,5.575) 55(0.75,5.575) 56(0.25,5.575) 57(-0.25,5.575) 58(-0.75,5.575) 59(-1.25,5.575) 60(-1.75,5.575) 61(-2.25,5.575) 62(-2.75,5.575) 63(-3.25,5.575) 64(-3.75,5.575)
Top Layer:
  pour cut-out: -6.7,6.7 6.7,6.7 6.7,-6.7 -6.7,-6.7
Top Overlay:
  circle w0.25: c-5.575,4.45 r0.125
  circle w0.6: c-3.58,3.62 r0.15
  lines w0.2: -4.3,-4.3 -4.3,4.3 4.3,4.3 4.3,-4.3 -4.3,-4.3
M13_Assembly_Info:
  circle w0.1: c-4.3,4.3 r0.4
  lines w0.1: -5,-5 -5,5 5,5 5,-5 -5,-5
M15_Country_Yard:
  lines w0.1: -0.5,0 0.5,0 ; 0,-0.5 0,0.5 ; -6.7,-6.7 -6.7,6.7 6.7,6.7 6.7,-6.7 -6.7,-6.7
3D body: height 1.22, standoff -0.13, extent -6.014,-6.003 6.014,6.025

## LQFP-32_N [mm] "32-Pin Thin Quad Flat Pack 0.8 mm Pitch, IPC Medium Density"
height 1.6
pads (32):
  oval 1.65x0.55 smd: 1(-4.2,2.8) 2(-4.2,2) 3(-4.2,1.2) 4(-4.2,0.4) 5(-4.2,-0.4) 6(-4.2,-1.2) 7(-4.2,-2) 8(-4.2,-2.8) 17(4.2,-2.8) 18(4.2,-2) 19(4.2,-1.2) 20(4.2,-0.4) 21(4.2,0.4) 22(4.2,1.2) 23(4.2,2) 24(4.2,2.8)
  oval 0.55x1.65 smd: 9(-2.8,-4.2) 10(-2,-4.2) 11(-1.2,-4.2) 12(-0.4,-4.2) 13(0.4,-4.2) 14(1.2,-4.2) 15(2,-4.2) 16(2.8,-4.2) 25(2.8,4.2) 26(2,4.2) 27(1.2,4.2) 28(0.4,4.2) 29(-0.4,4.2) 30(-1.2,4.2) 31(-2,4.2) 32(-2.8,4.2)
Top Overlay:
  circle w0.6: c-1.95,1.95 r0.3
  circle w0.25: c-4.2,3.625 r0.125
  lines w0.2: -2.95,-2.95 2.95,-2.95 2.95,2.95 -2.95,2.95 -2.95,-2.95
M13_Assembly_Info:
  circle w0.1: c-2.6,2.6 r0.5
  lines w0.1: -3.5,-3.5 3.5,-3.5 3.5,3.5 -3.5,3.5 -3.5,-3.5
M15_Country_Yard:
  lines w0.1: -0.5,0 0.5,0 ; 0,-0.5 0,0.5 ; -5.25,-5.25 5.25,-5.25 5.25,5.25 -5.25,5.25 -5.25,-5.25
3D body: height 1.6, standoff 0, extent -3.5,-3.5 3.5,3.5

## LQFP-48_N [mm] "48-Pin Thin Quad Flat Pack 0.5 mm Pitch, IPC Medium Density"
height 1.6
pads (48):
  rect 1.8x0.3 smd: 1(-4.05,2.75)
  oval 1.8x0.3 smd: 2(-4.05,2.25) 3(-4.05,1.75) 4(-4.05,1.25) 5(-4.05,0.75) 6(-4.05,0.25) 7(-4.05,-0.25) 8(-4.05,-0.75) 9(-4.05,-1.25) 10(-4.05,-1.75) 11(-4.05,-2.25) 12(-4.05,-2.75) 25(4.05,-2.75) 26(4.05,-2.25) 27(4.05,-1.75) 28(4.05,-1.25) 29(4.05,-0.75) 30(4.05,-0.25) 31(4.05,0.25) 32(4.05,0.75) 33(4.05,1.25) 34(4.05,1.75) 35(4.05,2.25) 36(4.05,2.75)
  oval 0.3x1.8 smd: 13(-2.75,-4.05) 14(-2.25,-4.05) 15(-1.75,-4.05) 16(-1.25,-4.05) 17(-0.75,-4.05) 18(-0.25,-4.05) 19(0.25,-4.05) 20(0.75,-4.05) 21(1.25,-4.05) 22(1.75,-4.05) 23(2.25,-4.05) 24(2.75,-4.05) 37(2.75,4.05) 38(2.25,4.05) 39(1.75,4.05) 40(1.25,4.05) 41(0.75,4.05) 42(0.25,4.05) 43(-0.25,4.05) 44(-0.75,4.05) 45(-1.25,4.05) 46(-1.75,4.05) 47(-2.25,4.05) 48(-2.75,4.05)
Top Layer:
  pour cut-out: -5.2,5.2 5.2,5.2 5.2,-5.2 -5.2,-5.2
Top Overlay:
  circle w0.6: c-1.75,1.75 r0.3
  circle w0.25: c-4.05,3.45 r0.125
  lines w0.2: -2.75,-2.75 2.75,-2.75 2.75,2.75 -2.75,2.75 -2.75,-2.75
M13_Assembly_Info:
  circle w0.1: c-2.6,2.6 r0.5
  lines w0.1: -3.5,-3.5 3.5,-3.5 3.5,3.5 -3.5,3.5 -3.5,-3.5
M15_Country_Yard:
  lines w0.1: -0.5,0 0.5,0 ; 0,-0.5 0,0.5 ; -5.2,-5.2 5.2,-5.2 5.2,5.2 -5.2,5.2 -5.2,-5.2
3D body: height 1.6, standoff 0, extent -3.5,-3.5 3.5,3.5

## MAU107 [mil]
pads (5):
  rect 65x65 hole 35: 1(-0.02,-0.01)
  round 65 hole 35: 2(99.98,-0.01) 4(299.98,-0.01) 5(399.98,-0.01) 6(499.98,-0.01)
Top Overlay:
  circle w11.81: c0,-250 r11.81
  lines w7.87: -80.02,-90.01 29.98,-200.01 ; -80.02,-200.01 -80.02,49.99 699.98,49.99 699.98,-200.01 -80.02,-200.01

## MCW1011 [mil] "DC/DC Converter"
height 437.01
pads (7):
  rect 65x65 hole 35: 1(0,0)
  round 65 hole 35: 2(100,0) 3(200,0) 5(400,0) 6(500,0) 7(600,0) 8(700,0)
Top Overlay:
  circle w9.84: c0,-270 r7.87
  lines w7.87: -80,-240 -80,120 780,120 780,-240 -80,-240

## MELF-D3516-1406 [mm] "Metal Electrode Face (MELF) Diode; Body 3.5 x 1.7 mm (LxDia)"
height 1.7
pads (2):
  rect 1.4x1.8 smd: 1(0,0) 2(3.5,0)
Top Overlay:
  lines w0.2: 1.19,-0.8 1.19,0.8 ; 2.4,-0.8 1,-0.8 1,0.8 2.4,0.8
M13_Assembly_Info:
  rectangle: 0,-0.8 0.7,0.8
  lines w0.1: 0,-0.8 0,0.8 3.5,0.8 3.5,-0.8 0,-0.8
3D body: height 0, standoff 0, extent 0,-0.8 3.5,0.8

## MELF-D5023-2009 [mm] "Metal Electrode Face (MELF) Diode; Body 5 x 2.5 mm (LxDia)"
height 2.5
pads (2):
  rect 1.6x2.5 smd: 1(0,0) 2(4.75,0)
Top Overlay:
  lines w0.2: 1.265,-1.2 1.265,1.2 ; 3.675,-1.2 1.075,-1.2 1.075,1.2 3.675,1.2
M13_Assembly_Info:
  rectangle: 0,-1.15 0.8,1.15
  lines w0.1: 0,-1.15 0,1.15 5,1.15 5,-1.15 0,-1.15
3D body: height 0, standoff 0, extent 0,-1.15 5,1.15

## MICROPHONE_ELECTRET [mil] "CMB-6544PF; electret condenser microphone"
height 263.78
pads (2):
  round 60 hole 30: 1(-78.74,49.8) 2(-78.74,-50.2)
Top Overlay:
  circle w7.87: c0,0 r185.04
  region: -142.72,-118.11 141.73,-118.11 141.73,-119.09 126.97,-135.83 118.11,-142.72 102.36,-154.53 94.49,-158.46 85.63,-164.37 79.72,-166.34 71.85,-171.26 56.1,-177.17 46.26,-179.13 38.39,-183.07 26.57,-184.06 19.68,-185.04 -16.73,-185.04 -26.57,-183.07 -46.26,-182.09 -61.02,-173.23 -77.76,-170.28 -94.49,-158.46 -104.33,-152.56 -122.05,-139.76 -127.95,-132.87

## Mini_Module [mil]
pads (52):
  rect 65x65 hole 35.43: 1(0,0) 27(900,0)
  round 65 hole 35.43: 2(100,0) 3(0,-100) 4(100,-100) 5(0,-200) 6(100,-200) 7(0,-300) 8(100,-300) 9(0,-400) 10(100,-400) 11(0,-500) 12(100,-500) 13(0,-600) 14(100,-600) 15(0,-700) 16(100,-700) 17(0,-800) 18(100,-800) 19(0,-900) 20(100,-900) 21(0,-1000) 22(100,-1000) 23(0,-1100) 24(100,-1100) 25(0,-1200) 26(100,-1200) 28(1000,0) 29(900,-100) 30(1000,-100) 31(900,-200) 32(1000,-200) 33(900,-300) 34(1000,-300) 35(900,-400) 36(1000,-400) 37(900,-500) 38(1000,-500) 39(900,-600) 40(1000,-600) 41(900,-700) 42(1000,-700) 43(900,-800) 44(1000,-800) 45(900,-900) 46(1000,-900) 47(900,-1000) 48(1000,-1000) 49(900,-1100) 50(1000,-1100) 51(900,-1200) 52(1000,-1200)
Top Overlay:
  region: -50,50 -15.35,50 -32.68,32.68 -50,15.35
  region: 850,50 884.65,50 867.32,32.68 850,15.35
  lines w7.87: -80.71,-1279.53 -80.71,135.63 349.21,135.63 349.41,135.83 349.41,202.76 652.56,202.76 652.56,135.83 1082.68,135.83 1082.68,-1279.53 -80.71,-1279.53 ; -50,-1250 150,-1250 150,50 -50,50 -50,-1250 ; 850,-1250 850,50 1050,50 1050,-1250 850,-1250
3D body: height 314.96, standoff 0, extent -50.2,-1250 149.61,50.2
3D body: height 314.96, standoff 0, extent 851.38,-1250.98 1051.18,49.21
3D body: height 377.95, standoff 314.96, extent -80.71,-1279.53 1082.68,135.83
3D body: height 533.46, standoff 338.58, extent 291.34,-163.39 712.6,198.82

## MLF50P200X200X85-8N [mm] "MLF, 8-Leads, Body 2.0x2.0mm (max), Pitch 0.50mm, IPC Medium Density"
height 0.85
pads (9):
  rect 0.6x0.25 smd: 1(-1.05,0.75)
  oval 0.6x0.25 smd: 2(-1.05,0.25) 3(-1.05,-0.25) 4(-1.05,-0.75) 5(1.05,-0.75) 6(1.05,-0.25) 7(1.05,0.25) 8(1.05,0.75)
  rect 0.7x1.3 smd: 9(0,0)
Top Overlay:
  circle w0.25: c-1.9,0.75 r0.125
  lines w0.2: -1,-1.2 1,-1.2 ; -1,1.2 1,1.2
M13_Assembly_Info:
  circle w0.1: c-0.62,0.6 r0.2
  lines w0.1: -1,-1 1,-1 1,1 -1,1 -1,-1
M15_Country_Yard:
  lines w0.1: -0.5,0 0.5,0 ; 0,-0.5 0,0.5 ; -1.6,-1.6 1.6,-1.6 1.6,1.6 -1.6,1.6 -1.6,-1.6
3D body: height 0.85, standoff 0.05, extent -1,-1 1,1

## MM232R [mm]
pads (16):
  round 1.6 hole 0.9: 1(0,0) 2(2.54,0) 3(5.08,0) 4(7.62,0) 5(5.08,-2.54) 6(7.62,-2.54) 7(5.08,-5.08) 8(7.62,-5.08) 9(7.62,-7.62) 10(5.08,-7.62) 11(7.62,-10.16) 12(5.08,-10.16) 13(7.62,-12.7) 14(5.08,-12.7) 15(2.54,-12.7) 16(0,-12.7)
Top Overlay:
  lines w0.2: -15.38,-12.365 -12.065,-12.365 ; -15.38,-0.325 -12.065,-0.325 ; -15.36,-12.365 -15.36,-0.325 ; -12.065,-15.24 -12.065,2.54 9.525,2.54 9.525,-15.24 -12.065,-15.24

## MNR34 [mm] "3216x4 Resistor Array"
height 0.55
pads (8):
  rect 1.2x1 smd: 1(0,0) 2(0,-1.27) 3(0,-2.54) 4(0,-3.81) 5(3.2,-3.81) 6(3.2,-2.54) 7(3.2,-1.27) 8(3.2,0)
Top Overlay:
  circle w0.254: c0.027,1.143 r0.1
  lines w0.2: 0,-4.605 3.2,-4.605 ; 0,0.795 3.175,0.795
M13_Assembly_Info:
  lines w0.1: 0,-4.605 0,0.795 3.2,0.795 3.2,-4.605 0,-4.605
3D body: height 0, standoff 0, extent 0,-4.605 3.2,0.795

## MORPHIC_II [mil] "MorphIC II Module"
pads (128):
  rect 65x65 hole 39.37: 1(0,0) 41(1300,0) 81(0,-2100) 105(1300,-2100)
  round 65 hole 39.37: 2(100,0) 3(0,-100) 4(100,-100) 5(0,-200) 6(100,-200) 7(0,-300) 8(100,-300) 9(0,-400) 10(100,-400) 11(0,-500) 12(100,-500) 13(0,-600) 14(100,-600) 15(0,-700) 16(100,-700) 17(0,-800) 18(100,-800) 19(0,-900) 20(100,-900) 21(0,-1000) 22(100,-1000) 23(0,-1100) 24(100,-1100) 25(0,-1200) 26(100,-1200) 27(0,-1300) 28(100,-1300) 29(0,-1400) 30(100,-1400) 31(0,-1500) 32(100,-1500) 33(0,-1600) 34(100,-1600) 35(0,-1700) 36(100,-1700) 37(0,-1800) 38(100,-1800) 39(0,-1900) 40(100,-1900) 42(1400,0) 43(1300,-100) 44(1400,-100) 45(1300,-200) 46(1400,-200) 47(1300,-300) 48(1400,-300) 49(1300,-400) 50(1400,-400) 51(1300,-500) 52(1400,-500) 53(1300,-600) 54(1400,-600) 55(1300,-700) 56(1400,-700) 57(1300,-800) 58(1400,-800) 59(1300,-900) 60(1400,-900) 61(1300,-1000) 62(1400,-1000) 63(1300,-1100) 64(1400,-1100) 65(1300,-1200) 66(1400,-1200) 67(1300,-1300) 68(1400,-1300) 69(1300,-1400) 70(1400,-1400) 71(1300,-1500) 72(1400,-1500) 73(1300,-1600) 74(1400,-1600) 75(1300,-1700) 76(1400,-1700) 77(1300,-1800) 78(1400,-1800) 79(1300,-1900) 80(1400,-1900) 82(100,-2100) 83(0,-2200) 84(100,-2200) 85(0,-2300) 86(100,-2300) 87(0,-2400) 88(100,-2400) 89(0,-2500) 90(100,-2500) 91(0,-2600) 92(100,-2600) 93(0,-2700) 94(100,-2700) 95(0,-2800) 96(100,-2800) 97(0,-2900) 98(100,-2900) 99(0,-3000) 100(100,-3000) 101(0,-3100) 102(100,-3100) 103(0,-3200) 104(100,-3200) 106(1400,-2100) 107(1300,-2200) 108(1400,-2200) 109(1300,-2300) 110(1400,-2300) 111(1300,-2400) 112(1400,-2400) 113(1300,-2500) 114(1400,-2500) 115(1300,-2600) 116(1400,-2600) 117(1300,-2700) 118(1400,-2700) 119(1300,-2800) 120(1400,-2800) 121(1300,-2900) 122(1400,-2900) 123(1300,-3000) 124(1400,-3000) 125(1300,-3100) 126(1400,-3100) 127(1300,-3200) 128(1400,-3200)
Top Overlay:
  lines w7.87: -78.74,50 -78.74,-3268.5 1477.95,-3268.5 1478.74,-3269.29 1478.74,50 ; -50,-2151.18 51.18,-2151.18 51.18,-2050 ; -50,-51.18 51.18,-51.18 51.18,50 ; 1250,-2151.18 1351.18,-2151.18 1351.18,-2050 ; 1250,-51.18 1351.18,-51.18 1351.18,50 ; -50,-3243.31 -50,-2050 150,-2050 150,-3243.31 -50,-3243.31 ; -50,-1950 -50,50 150,50 150,-1950 -50,-1950 ; 1250,-3243.31 1450,-3243.31 1450,-2050 1250,-2050 1250,-3243.31 ; 1250,-1950 1450,-1950 1450,50 1250,50 1250,-1950
M13_Assembly_Info:
  lines w7.87: 1477.95,-3268.5 -78.74,-3268.5 -78.74,661.42 461.81,661.42 461.81,839.37 938.19,839.37 938.19,661.42 1478.74,661.42 1478.74,-3269.29
3D body: height 314.96, standoff 0, extent -50.2,-1949.8 149.61,50.2
3D body: height 314.96, standoff 0, extent 1250,-1949.8 1449.8,50.2
3D body: height 314.96, standoff 0, extent -50.2,-3243.11 149.61,-2050.2
3D body: height 314.96, standoff 0, extent 1250,-3243.11 1449.8,-2050.2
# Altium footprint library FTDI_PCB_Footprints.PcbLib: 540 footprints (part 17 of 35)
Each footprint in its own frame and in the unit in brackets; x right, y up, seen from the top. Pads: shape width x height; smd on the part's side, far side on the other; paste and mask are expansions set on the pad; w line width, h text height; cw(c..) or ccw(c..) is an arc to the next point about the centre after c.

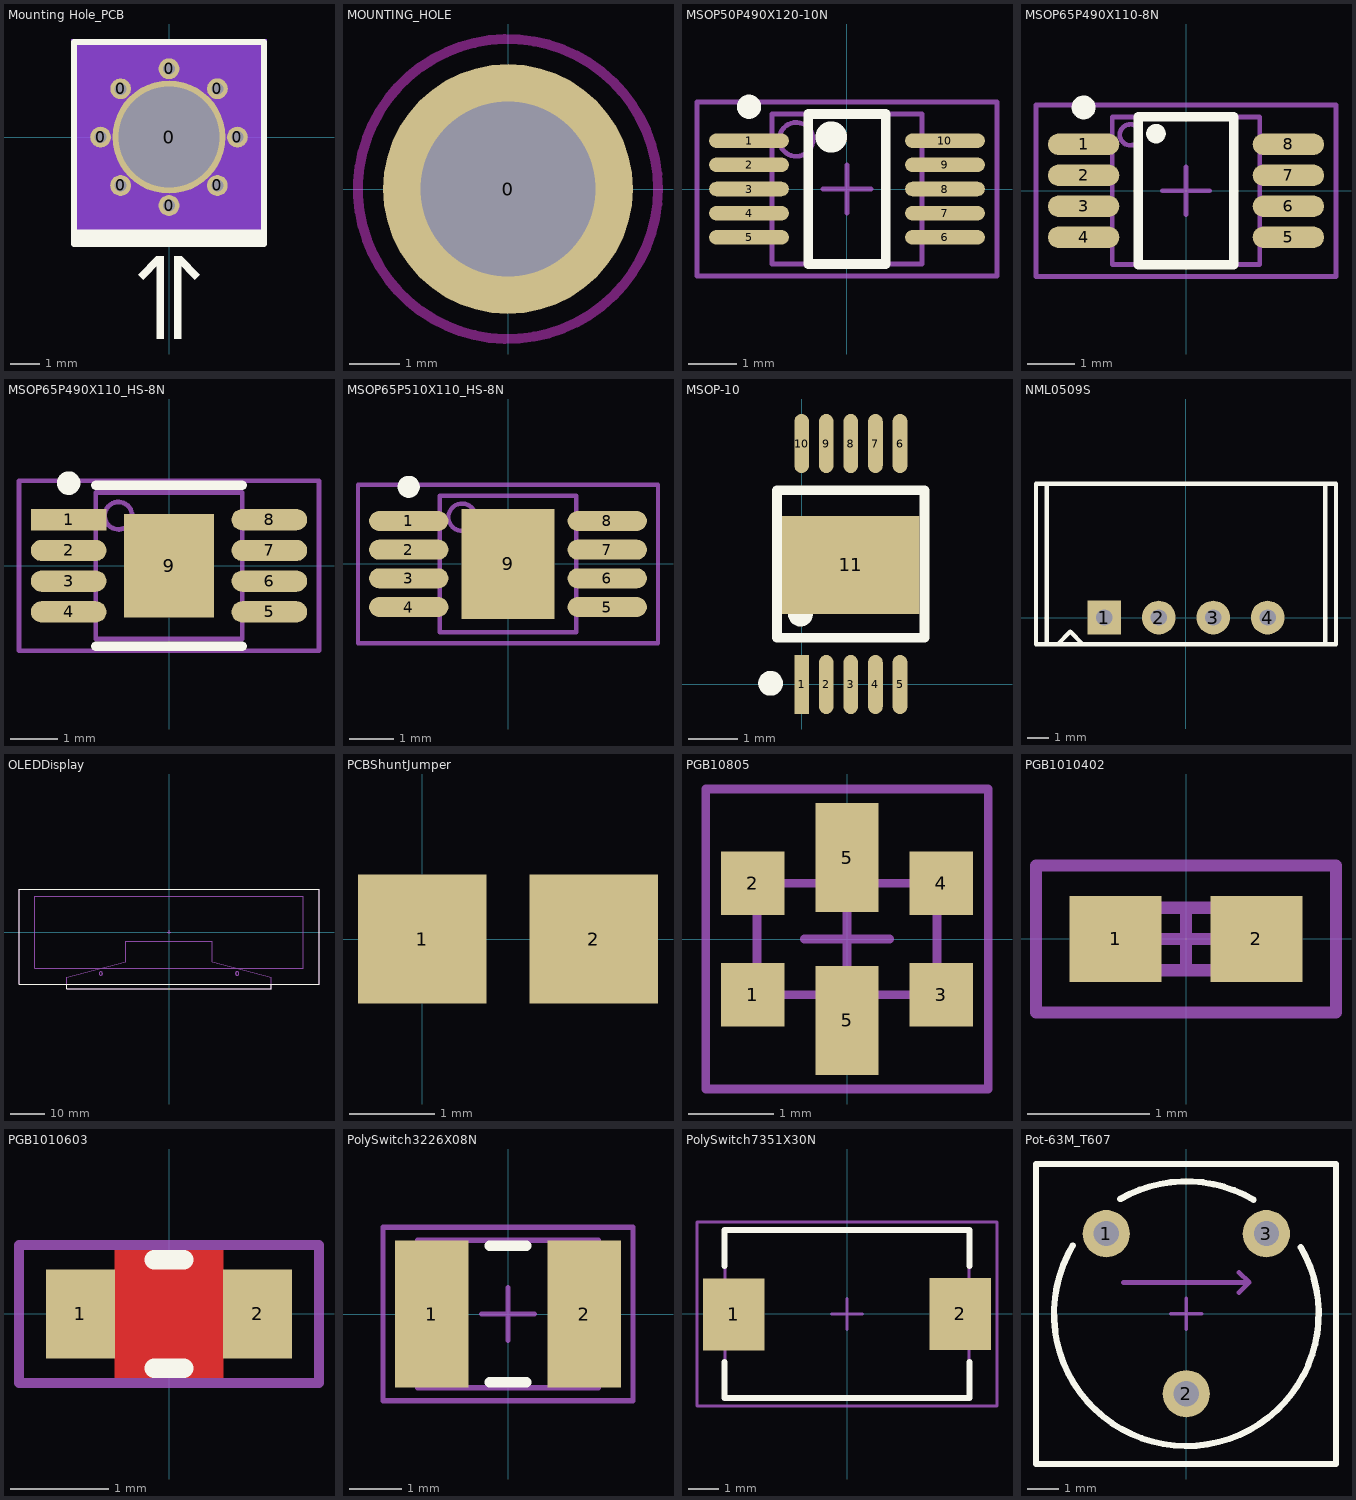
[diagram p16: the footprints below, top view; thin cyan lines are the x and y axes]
## Mounting Hole_PCB [mm]
pads (9):
  round 0.7 hole 0.4 unplated: 0(-2.3,0) 0(-1.626,-1.626) 0(-1.625,1.625) 0(0,-2.3) 0(0,2.3) 0(1.625,-1.625) 0(1.627,1.627) 0(2.3,0)
  round 3.8 hole 3.4 paste+0.038 mask+0.2: 0(0,0)
Top Layer keep-out:
  region: 3.3,3.3 -3.3,3.3 -3.3,-3.3 3.3,-3.3
Bottom Layer keep-out:
  region: 3.3,3.3 -3.3,3.3 -3.3,-3.3 3.3,-3.3
Top Overlay:
  rectangle: -3.2,-3.7 3.2,-3.2
  region: -0.167,-3.993 -0.421,-3.993 -0.421,-6.787 -0.167,-6.787
  region: -1.05,-4.622 -0.87,-4.802 -0.242,-4.173 -0.421,-3.993
  rectangle: 0.167,-6.787 0.421,-3.993
  region: 0.421,-3.993 0.242,-4.173 0.87,-4.802 1.05,-4.622
  lines w0.2: -3.2,-3.6 -3.2,-3.2 ; 3.2,-3.6 3.2,-3.2 ; -3.2,-3.2 -3.2,3.2 3.2,3.2 3.2,-3.2 ; -3.2,-3.2 3.2,-3.2
Bottom Overlay:
  rectangle: -3.2,-3.6 3.2,-3.2
  lines w0.2: -3.2,-3.2 -3.2,-3.6 3.2,-3.6 3.2,-3.2 ; -3.2,-3.2 3.2,-3.2 ; -3.2,-3.2 -3.2,3.2 3.2,3.2 3.2,-3.2
Top Solder:
  region: 3.2,3.2 -3.2,3.2 -3.2,-3.2 3.2,-3.2
Bottom Solder:
  region: 3,3 -3,3 -3,-3 3,-3
Keep-Out Layer:
  circle w1.2: c0,0 r2.5

## MOUNTING_HOLE [mm] "3.5mm Mouting hole"
pads (1):
  round 5 hole 3.5: 0(0,0)
Keep-Out Layer:
  circle w0.2: c0,0 r3

## MSOP50P490X120-10N [mm] "MSOP, 10-Leads, Body 3.1x3.1mm (max), Pitch 0.50mm, IPC Medium Density"
height 1.2
pads (10):
  oval 1.65x0.3 smd: 1(-2.025,1) 2(-2.025,0.5) 3(-2.025,0) 4(-2.025,-0.5) 5(-2.025,-1) 6(2.025,-1) 7(2.025,-0.5) 8(2.025,0) 9(2.025,0.5) 10(2.025,1)
Top Overlay:
  circle w0.25: c-2.025,1.7 r0.125
  circle w0.6: c-0.325,1.075 r0.025
  lines w0.2: -0.8,-1.55 -0.8,1.55 0.8,1.55 0.8,-1.55 -0.8,-1.55
M13_Assembly_Info:
  circle w0.1: c-1.05,1.025 r0.35
  lines w0.1: -1.55,-1.55 -1.55,1.55 1.55,1.55 1.55,-1.55 -1.55,-1.55
M15_Country_Yard:
  lines w0.1: -0.5,0 0.5,0 ; 0,-0.5 0,0.5 ; -3.1,-1.8 -3.1,1.8 3.1,1.8 3.1,-1.8 -3.1,-1.8
3D body: height 1.2, standoff 0.15, extent -1.55,-1.55 1.55,1.55

## MSOP65P490X110-8N [mm] "MSOP, 8-Leads, Body 3.1x3.1mm (max), Pitch 0.65mm, IPC Medium Density"
height 1.1
pads (8):
  oval 1.5x0.45 smd: 1(-2.15,0.975) 2(-2.15,0.325) 3(-2.15,-0.325) 4(-2.15,-0.975) 5(2.15,-0.975) 6(2.15,-0.325) 7(2.15,0.325) 8(2.15,0.975)
Top Overlay:
  circle w0.25: c-2.15,1.75 r0.125
  circle w0.2: c-0.63,1.2 r0.105
  lines w0.2: -1,-1.55 -1,1.55 1,1.55 1,-1.55 -1,-1.55
M13_Assembly_Info:
  circle w0.1: c-1.17,1.175 r0.22
  lines w0.1: -1.55,-1.55 -1.55,1.55 1.55,1.55 1.55,-1.55 -1.55,-1.55
M15_Country_Yard:
  lines w0.1: -0.5,0 0.5,0 ; 0,-0.5 0,0.5 ; -3.15,-1.8 -3.15,1.8 3.15,1.8 3.15,-1.8 -3.15,-1.8
3D body: height 1.1, standoff 0.15, extent -1.55,-1.55 1.55,1.55

## MSOP65P490X110_HS-8N [mm] "MSOP, 8-Leads, Body 3.1x3.1mm (max), Pitch 0.65mm, with heat sink, IPC Medium Density"
height 1.1
pads (9):
  rect 1.6x0.45 smd: 1(-2.125,0.975)
  oval 1.6x0.45 smd: 2(-2.125,0.325) 3(-2.125,-0.325) 4(-2.125,-0.975) 5(2.125,-0.975) 6(2.125,-0.325) 7(2.125,0.325) 8(2.125,0.975)
  rect 1.9x2.2 smd: 9(0,0)
Top Overlay:
  circle w0.25: c-2.125,1.75 r0.125
  lines w0.2: -1.55,-1.7 1.55,-1.7 ; -1.55,1.7 1.55,1.7
M13_Assembly_Info:
  circle w0.1: c-1.07,1.06 r0.29
  lines w0.1: -1.55,-1.55 -1.55,1.55 1.55,1.55 1.55,-1.55 -1.55,-1.55
M15_Country_Yard:
  lines w0.1: -0.5,0 0.5,0 ; 0,-0.5 0,0.5 ; -3.175,-1.8 -3.175,1.8 3.175,1.8 3.175,-1.8 -3.175,-1.8
3D body: height 1.1, standoff 0.15, extent -1.55,-1.55 1.55,1.55

## MSOP65P510X110_HS-8N [mm] "MSOP, 8-Leads, Body 3.1x3.1mm (max), Pitch 0.65mm, IPC Medium Density"
height 1.1
pads (9):
  oval 1.8x0.45 smd: 1(-2.25,0.975) 2(-2.25,0.325) 3(-2.25,-0.325) 4(-2.25,-0.975) 5(2.25,-0.975) 6(2.25,-0.325) 7(2.25,0.325) 8(2.25,0.975)
  rect 2.1x2.5 smd: 9(0,0)
Top Overlay:
  circle w0.25: c-2.25,1.75 r0.125
M13_Assembly_Info:
  circle w0.1: c-1.04,1.06 r0.31
  lines w0.1: -1.55,-1.55 1.55,-1.55 1.55,1.55 -1.55,1.55 -1.55,-1.55
M15_Country_Yard:
  lines w0.1: -0.5,0 0.5,0 ; 0,-0.5 0,0.5 ; -3.4,-1.8 3.4,-1.8 3.4,1.8 -3.4,1.8 -3.4,-1.8
3D body: height 1.1, standoff 0.2, extent -1.55,-1.55 1.55,1.55

## MSOP-10 [mm] "MSE-Type MSOP-10 with exposed die pad"
pads (11):
  rect 0.3x1.2 smd: 1(0,0)
  oval 0.3x1.2 smd: 2(0.5,0) 3(1,0) 4(1.5,0) 5(2,0) 6(2,4.9) 7(1.5,4.9) 8(1,4.9) 9(0.5,4.9) 10(0,4.9)
  rect 2.8x2 smd: 11(1,2.43)
Top Overlay:
  lines w0.2: -0.5,0.95 -0.5,3.95 2.5,3.95 2.5,0.95 -0.5,0.95
  lines w0.254: -0.508,0 cw(c-0.631,0.025) -0.506,0.025 ; 0.098,1.405 cw(c-0.025,1.43) 0.1,1.43

## NML0509S [mil] "5V/9V, Step Up, DC-DC Converter"
height 393.7
pads (4):
  rect 62x62 hole 30: 1(-150,0)
  round 62 hole 30: 2(-50,0) 3(50,0) 4(150,0)
Top Overlay:
  lines w7.87: -188.98,-49.21 -212.6,-25.59 -236.22,-49.21 ; -236.22,-49.21 -236.22,-49.21
  lines w8: -255.91,-49.21 -255.91,246.06 ; 255.91,-49.21 255.91,246.06 ; -275.59,-49.21 275.59,-49.21 275.59,246.06 -275.59,246.06 -275.59,-49.21

## OLEDDisplay [mm] "UG-5664ALBBT02; Folding Type; OEL Display Module; 256x64 pixels; Monochrome; TCP Package"
height 4
Top Overlay:
  lines w0.2: -30,-15.225 -30,-16.575 30,-16.575 30,-15.225 ; -44,-15.225 44,-15.225 44,12.575 -44,12.575 -44,-15.225
M15_Country_Yard:
  circle w0.2: c-20,-12.125 r0.5
  circle w0.2: c20,-12.125 r0.5
  lines w0.1: -0.55,0 0.55,0 ; 0,-0.5 0,0.5 ; -44,-15.225 -44,12.575 44,12.575 44,-15.225 -44,-15.225 ; -39.4,-10.6 -39.4,10.575 39.375,10.575 39.375,-10.6 -39.4,-10.6 ; -30,-16.575 30,-16.575 30,-15.225 30,-13.25 12.75,-8.625 12.75,-5.625 12.75,-2.625 -12.75,-2.625 -12.75,-5.625 -12.75,-8.625 -30,-13.25 -30,-15.225 -30,-16.575

## PCBShuntJumper [mm]
pads (2):
  rect 1.5x1.5 smd: 1(0,0) 2(2,0)

## PGB10805 [mm]
pads (6):
  rect 0.737x0.737 smd: 1(-1.1,-0.65) 2(-1.1,0.65) 3(1.1,-0.65) 4(1.1,0.65)
  rect 0.737x1.27 smd: 5(0,-0.95) 5(0,0.95)
M13_Assembly_Info:
  lines w0.1: -1.05,-0.65 -1.05,0.65 1.05,0.65 1.05,-0.65 -1.05,-0.65
M15_Country_Yard:
  lines w0.1: -0.5,0 0.5,0 ; 0,-0.5 0,0.5 ; -1.65,-1.75 1.65,-1.75 1.65,1.75 -1.65,1.75 -1.65,-1.75
3D body: height 0, standoff 0, extent -1.05,-0.65 1.05,0.65

## PGB1010402 [mm] "TVS, PGB1010402, Littelfuse, 2-Leads, Body 1.0x0.5mm, IPC Medium Density"
height 0.3
pads (2):
  rect 0.75x0.7 smd: 1(-0.575,0) 2(0.575,0)
M13_Assembly_Info:
  lines w0.1: -0.495,-0.255 -0.495,0.255 0.495,0.255 0.495,-0.255 -0.495,-0.255
M15_Country_Yard:
  lines w0.1: -0.255,0 0.255,0 ; 0,-0.255 0,0.255 ; -1.225,-0.6 -1.225,0.6 1.225,0.6 1.225,-0.6 -1.225,-0.6
3D body: height 0.3, standoff 0, extent -0.495,-0.255 0.495,0.255

## PGB1010603 [mm] "Chip Transil, Littelfuse, PGB1 series, 2-Leads, Body 1.6x0.8mm, IPC Medium Density"
height 0.356
pads (2):
  rect 0.7x0.9 smd: 1(-0.9,0) 2(0.9,0)
Top Layer:
  pour cut-out: -0.55,-0.65 -0.55,0.65 0.55,0.65 0.55,-0.65
Top Overlay:
  lines w0.2: -0.15,-0.55 0.15,-0.55 ; -0.15,0.55 0.15,0.55
M13_Assembly_Info:
  lines w0.1: -0.8,-0.395 0.8,-0.395 0.8,0.395 -0.8,0.395 -0.8,-0.395
M15_Country_Yard:
  lines w0.1: -0.395,0 0.395,0 ; 0,-0.395 0,0.395 ; -1.525,-0.7 1.525,-0.7 1.525,0.7 -1.525,0.7 -1.525,-0.7
3D body: height 0.36, standoff 0, extent -0.8,-0.395 0.8,0.395

## PolySwitch3226X08N [mm] "PTC Fuse, 2-Leads, Body 3.2x2.6mm, IPC Medium Density"
height 0.76
pads (2):
  rect 1.4x2.8 smd: 1(-1.45,0) 2(1.45,0)
Top Overlay:
  lines w0.2: -0.35,-1.3 0.35,-1.3 ; -0.35,1.3 0.35,1.3
M13_Assembly_Info:
  lines w0.1: -1.715,-1.4 -1.715,1.4 1.715,1.4 1.715,-1.4 -1.715,-1.4
M15_Country_Yard:
  lines w0.1: -0.5,0 0.5,0 ; 0,-0.5 0,0.5 ; -2.375,-1.65 -2.375,1.65 2.375,1.65 2.375,-1.65 -2.375,-1.65
3D body: height 0.76, standoff 0, extent -1.715,-1.4 1.715,1.4

## PolySwitch7351X30N [mm] "PolySwitch; SMD300F, 2-Leads, Body 7.3x5.1mm, IPC Medium Density"
height 3
pads (2):
  rect 2x2.35 smd: 1(-3.7,-0.01) 2(3.7,0)
Top Overlay:
  lines w0.2: -4,-1.575 -4,-2.75 4,-2.75 4,-1.575 ; -4,1.575 -4,2.75 4,2.75 4,1.575
M13_Assembly_Info:
  lines w0.1: -3.99,-2.72 3.99,-2.72 3.99,2.72 -3.99,2.72 -3.99,-2.72
M15_Country_Yard:
  lines w0.1: -0.5,0 0.5,0 ; 0,-0.5 0,0.5 ; -4.9,-3 4.9,-3 4.9,3 -4.9,3 -4.9,-3
3D body: height 3, standoff 0, extent -3.99,-2.72 3.99,2.72

## Pot-63M_T607 [mm] "Finger adjustable cermet trimmer"
pads (3):
  round 1.5 hole 0.8: 1(-2.54,2.54) 2(0,-2.54) 3(2.54,2.54)
Top Overlay:
  lines w0.2: -3.601,2.161 ccw(c0,0) 3.634,2.105 ; -2.1,3.638 cw(c0,0) 2.131,3.619 ; -4.77,-4.77 -4.77,4.75 4.75,4.75 4.75,-4.77 -4.77,-4.77
M13_Assembly_Info:
  lines w0.15: -2,0.99 1.99,0.99 ; 1.67,0.67 1.99,0.99 ; 1.67,1.31 1.99,0.99
  text "CW" at -0.71,1.32 h0.8
M15_Country_Yard:
  lines w0.1: -0.5,0 0.5,0 ; 0,-0.5 0,0.5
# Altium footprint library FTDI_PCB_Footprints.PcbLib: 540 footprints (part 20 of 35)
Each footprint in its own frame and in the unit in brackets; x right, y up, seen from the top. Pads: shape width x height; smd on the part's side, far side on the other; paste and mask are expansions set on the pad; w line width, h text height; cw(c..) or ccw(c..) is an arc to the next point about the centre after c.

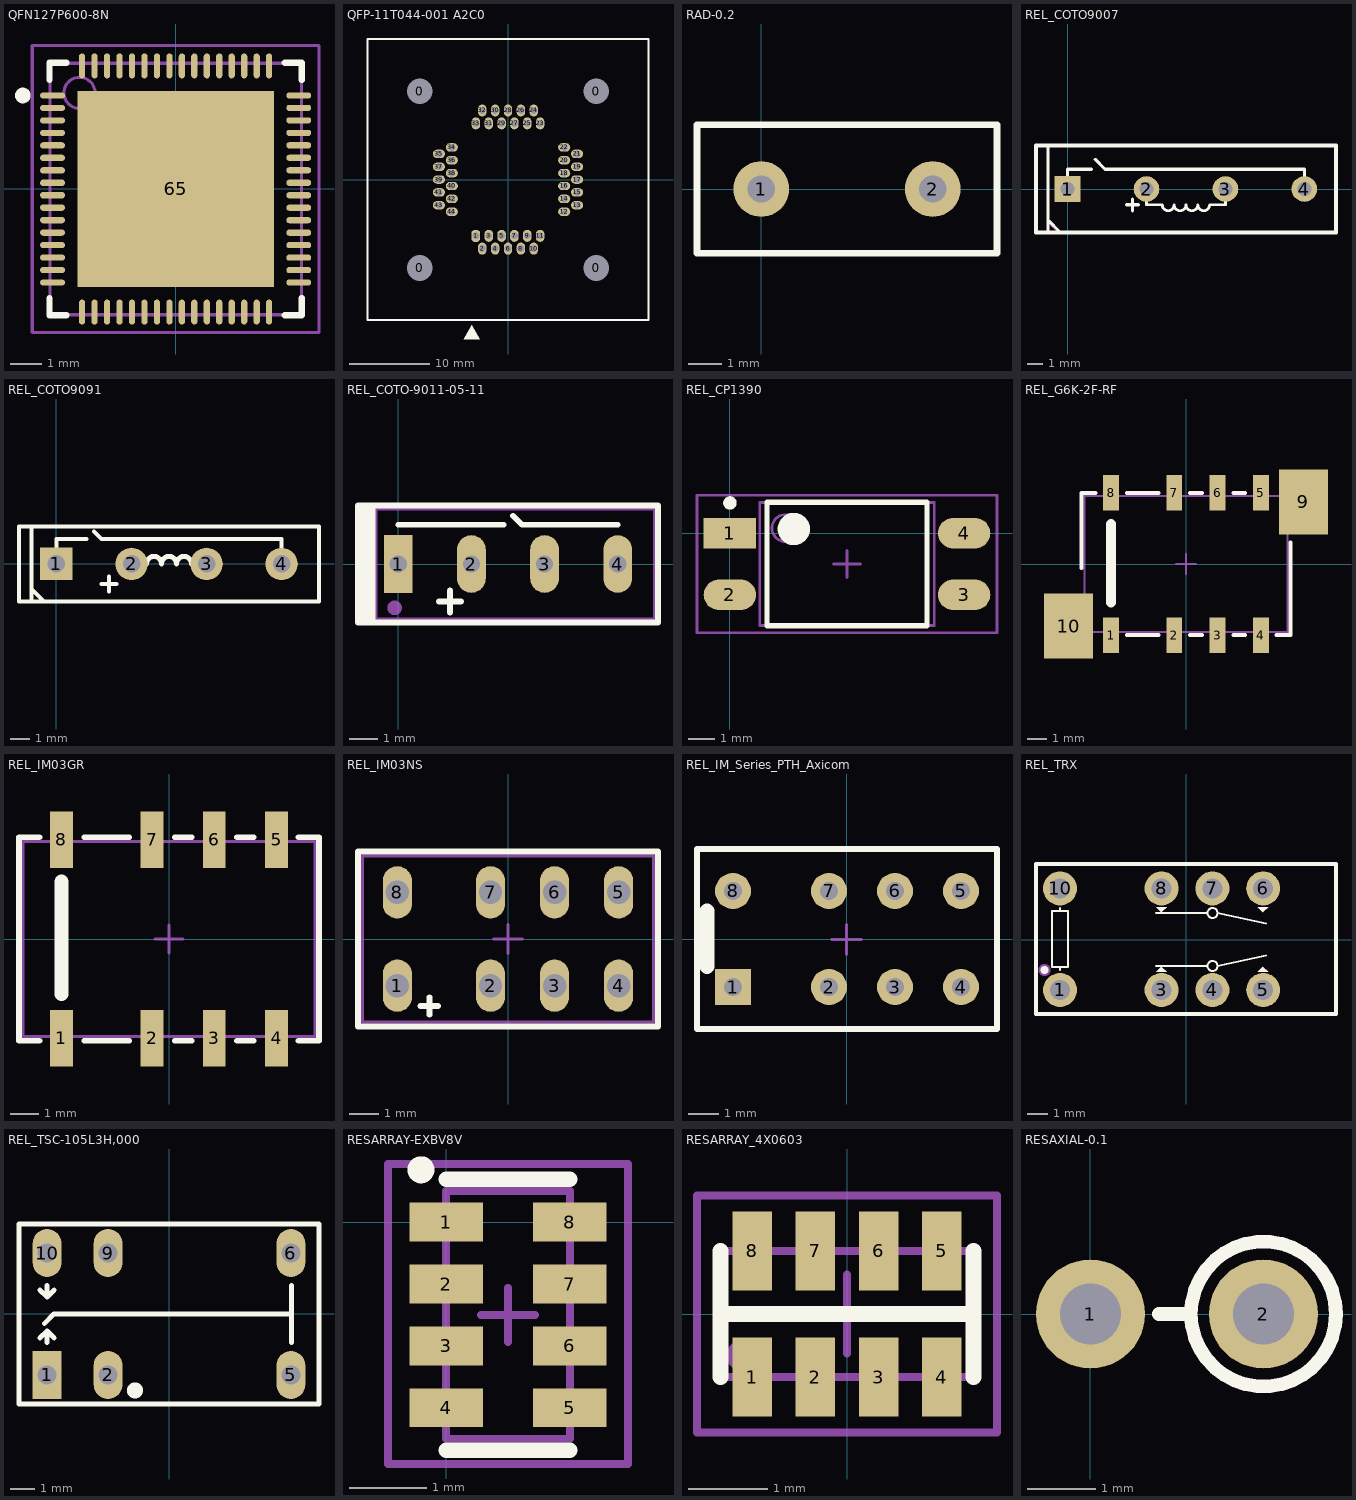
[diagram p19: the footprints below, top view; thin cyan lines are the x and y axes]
## QFN127P600-8N [mm]
height 0.9
pads (65):
  oval 0.8x0.2 smd: 1(-3.95,3) 2(-3.95,2.6) 3(-3.95,2.2) 4(-3.95,1.8) 5(-3.95,1.4) 6(-3.95,1) 7(-3.95,0.6) 8(-3.95,0.2) 9(-3.95,-0.2) 10(-3.95,-0.6) 11(-3.95,-1) 12(-3.95,-1.4) 13(-3.95,-1.8) 14(-3.95,-2.2) 15(-3.95,-2.6) 16(-3.95,-3) 33(3.95,-3) 34(3.95,-2.6) 35(3.95,-2.2) 36(3.95,-1.8) 37(3.95,-1.4) 38(3.95,-1) 39(3.95,-0.6) 40(3.95,-0.2) 41(3.95,0.2) 42(3.95,0.6) 43(3.95,1) 44(3.95,1.4) 45(3.95,1.8) 46(3.95,2.2) 47(3.95,2.6) 48(3.95,3)
  oval 0.2x0.8 smd: 17(-3,-3.95) 18(-2.6,-3.95) 19(-2.2,-3.95) 20(-1.8,-3.95) 21(-1.4,-3.95) 22(-1,-3.95) 23(-0.6,-3.95) 24(-0.2,-3.95) 25(0.2,-3.95) 26(0.6,-3.95) 27(1,-3.95) 28(1.4,-3.95) 29(1.8,-3.95) 30(2.2,-3.95) 31(2.6,-3.95) 32(3,-3.95) 49(3,3.95) 50(2.6,3.95) 51(2.2,3.95) 52(1.8,3.95) 53(1.4,3.95) 54(1,3.95) 55(0.6,3.95) 56(0.2,3.95) 57(-0.2,3.95) 58(-0.6,3.95) 59(-1,3.95) 60(-1.4,3.95) 61(-1.8,3.95) 62(-2.2,3.95) 63(-2.6,3.95) 64(-3,3.95)
  rect 6.3x6.3 smd: 65(0,0)
Top Overlay:
  circle w0.25: c-4.9,3 r0.125
  lines w0.2: -4.05,-3.5 -4.05,-4.05 -3.5,-4.05 ; -4.05,3.5 -4.05,4.05 -3.5,4.05 ; 3.5,-4.05 4.05,-4.05 4.05,-3.5 ; 3.5,4.05 4.05,4.05 4.05,3.5
M13_Assembly_Info:
  circle w0.1: c-3.085,3.085 r0.5
  lines w0.1: -4.035,-4.035 -4.035,4.035 4.035,4.035 4.035,-4.035 -4.035,-4.035
M15_Country_Yard:
  lines w0.1: -0.5,0 0.5,0 ; 0,-0.5 0,0.5 ; -4.6,-4.6 -4.6,4.6 4.6,4.6 4.6,-4.6 -4.6,-4.6
3D body: height 0.9, standoff 0.05, extent -4.035,-4.035 4.035,4.035

## QFP-11T044-001 A2C0 [mm] "44-pin Socket Saver"
pads (48):
  oct 2x2 hole 3.2: 0(-11,-11) 0(-11,11) 0(11,-11) 0(11,11)
  oct 1.05x1.5 hole 0.85: 1(-4,-7)
  oval 1.05x1.5 hole 0.85: 2(-3.2,-8.6) 3(-2.4,-7) 4(-1.6,-8.6) 5(-0.8,-7) 6(0,-8.6) 7(0.8,-7) 8(1.6,-8.6) 9(2.4,-7) 10(3.2,-8.6) 11(4,-7) 23(4,7) 24(3.2,8.6) 25(2.4,7) 26(1.6,8.6) 27(0.8,7) 28(0,8.6) 29(-0.8,7) 30(-1.6,8.6) 31(-2.4,7) 32(-3.2,8.6) 33(-4,7)
  oval 1.5x1.05 hole 0.85: 12(7,-4) 13(8.6,-3.2) 14(7,-2.4) 15(8.6,-1.6) 16(7,-0.8) 17(8.6,0) 18(7,0.8) 19(8.6,1.6) 20(7,2.4) 21(8.6,3.2) 22(7,4) 34(-7,4) 35(-8.6,3.2) 36(-7,2.4) 37(-8.6,1.6) 38(-7,0.8) 39(-8.6,0) 40(-7,-0.8) 41(-8.6,-1.6) 42(-7,-2.4) 43(-8.6,-3.2) 44(-7,-4)
Top Overlay:
  region: -4.483,-18.148 -5.499,-19.85 -3.492,-19.85
  lines w0.254: -17.5,-17.5 17.5,-17.5 17.5,17.5 -17.5,17.5 -17.501,-17.5

## RAD-0.2 [mil] "Jumper Wire; 2 Leads"
pads (2):
  round 65 hole 32: 1(0,0) 2(200,0)
Top Overlay:
  lines w7.87: -75,-75 -75,75 275,75 275,-75 -75,-75

## REL_COTO9007 [mil] "Miniature SIP Relay on 150mil pitch"
height 275
pads (4):
  rect 65x65 hole 35: 1(0,0)
  round 65 hole 35: 2(200,0) 3(400,0) 4(600,0)
Top Overlay:
  lines w7: 200,0 200,-40 240,-40 ccw(c255,-40) 270,-40 ccw(c285,-40) 300,-40 ccw(c315,-40) 330,-40 ccw(c345,-40) 360,-40 400,-40 400,0
  lines w7.87: -49.21,-110.24 -49.21,110.24 ; -46.65,-81.3 -21.65,-106.3 ; 0,25 0,50 60,50 ; 70,75 95,50 130,50 600,50 600,0 ; 150,-40 180,-40 ; 165,-55 165,-25
  lines w10: -80,-110.24 -80,110.24 680,110.24 680,-110.24 -80,-110.24
M13_Assembly_Info:
  lines w3.94: -49.21,-110.24 -49.21,110.24 ; -49.21,-84.65 -24.21,-109.65 ; -79.72,-110.24 -79.72,110.24 680.12,110.24 680.12,-110.24 -79.72,-110.24
3D body: height 0, standoff 0, extent -79.72,-110.24 680.12,110.24

## REL_COTO9091 [mil] "Miniature SIP Relay on 150mil pitch"
height 275
pads (4):
  rect 65x65 hole 35: 1(0,0)
  round 65 hole 35: 2(150.02,0.01) 3(300.02,0.01) 4(450.02,0.01)
Top Overlay:
  lines w7.87: -50,-50 -25,-75 ; 0,25 0,50 60,50 ; 75,65 90,50 450,50 ; 90,-40 120,-40 ; 105,-55 105,-25 ; 165,0 180,0 ; 270,0 285,0 ; 450.02,0.01 450.02,49.98 ; -50,-75 -50,75 ; -50,-75 -75,-75 -75,75 -50,75 ; -50,-75 350,-75 ; -50,75 350,75 525,75 525,-75 350,-75 ; 350,-75 350,-75 ; 450,50 450.02,49.98
  lines w10: 180,0 cw(c195,0) 210,0 cw(c225,0) 240,0 cw(c255,0) 270,0

## REL_COTO-9011-05-11 [mm] "Miniature SIP Relay on 100mil pitch"
height 6.985
pads (4):
  rect 1x2 hole 0.6: 1(0,0)
  oval 1x2 hole 0.6: 2(2.54,0) 3(5.08,0) 4(7.62,0)
Top Overlay:
  rectangle: -1.397,-2.032 -0.889,2.032
  lines w0.2: -0.889,-2.032 -0.889,2.032 ; 0,1.36 3.66,1.36 ; 1.416,-1.3 2.178,-1.3 ; 1.797,-1.681 1.797,-0.919 ; 3.985,1.675 4.3,1.36 ; 4.31,1.36 7.62,1.36 ; -1.397,-2.032 -1.397,2.032 9.017,2.032 9.017,-2.032 -1.397,-2.032
M13_Assembly_Info:
  circle w0.254: c-0.127,-1.524 r0.127
  rectangle: -1.27,-1.905 -0.762,1.905
  lines w0.1: -0.762,-1.905 -0.762,1.905 ; -1.27,-1.905 -1.27,1.905 8.89,1.905 8.89,-1.905 -1.27,-1.905

## REL_CP1390 [mm] "Single Pole, Normally Open  4-Pin OptoMOS® Relay"
height 2.65
pads (4):
  rect 1.95x1.15 smd: 1(0,0)
  oval 1.95x1.15 smd: 2(0,-2.287) 3(8.7,-2.287) 4(8.7,0)
Top Overlay:
  circle w0.6: c2.375,0.156 r0.3
  circle w0.25: c0,1.125 r0.125
  lines w0.2: 1.375,-3.444 7.325,-3.444 7.325,1.157 1.375,1.157 1.375,-3.444
M13_Assembly_Info:
  circle w0.1: c2.06,0.192 r0.5
  lines w0.1: 1.11,-3.428 7.59,-3.428 7.59,1.141 1.11,1.141 1.11,-3.428
M15_Country_Yard:
  lines w0.1: 3.85,-1.144 4.85,-1.144 ; 4.35,-1.643 4.35,-0.643 ; -1.225,-3.694 9.925,-3.694 9.925,1.406 -1.225,1.406 -1.225,-3.694
3D body: height 2.65, standoff 0.1, extent 1.11,-3.428 7.59,1.141

## REL_G6K-2F-RF [mm] "High Frequency Relay; Omron"
height 5.4
pads (10):
  rect 0.8x1.8 smd: 1(-3.8,-3.6) 2(-0.6,-3.6) 3(1.6,-3.6) 4(3.8,-3.6) 5(3.8,3.6) 6(1.6,3.6) 7(-0.6,3.6) 8(-3.8,3.6)
  rect 2.5x3.3 smd: 9(5.95,3.15) 10(-5.95,-3.15)
Top Overlay:
  lines w0.2: -5.3,-0.2 -5.3,3.6 -4.575,3.6 ; -3,-3.6 -1.4,-3.6 ; -3,3.6 -1.4,3.6 ; 0.2,-3.6 0.8,-3.6 ; 0.2,3.6 0.8,3.6 ; 2.4,-3.6 3,-3.6 ; 2.4,3.6 3,3.6 ; 4.575,-3.6 5.3,-3.6 5.3,1.1
  lines w0.5: -3.8,-1.945 -3.8,2.025
M13_Assembly_Info:
  lines w0.1: -5.15,-3.45 -5.15,3.45 5.15,3.45 5.15,-3.45 -5.15,-3.45
M15_Country_Yard:
  lines w0.1: -0.5,0 0.5,0 ; 0,-0.5 0,0.5
3D body: height 5.65, standoff 0, extent -4.99,-3.779 5.01,3.738

## REL_IM03GR [mm] "High Frequency Relay; Omron"
height 5.4
pads (8):
  rect 0.8x2 smd: 1(-3.8,-3.5) 2(-0.6,-3.5) 3(1.6,-3.5) 4(3.8,-3.5) 5(3.8,3.5) 6(1.6,3.5) 7(-0.6,3.5) 8(-3.8,3.5)
Top Overlay:
  lines w0.2: -4.575,-3.6 -5.3,-3.6 -5.3,3.6 -4.575,3.6 ; -3,-3.6 -1.4,-3.6 ; -3,3.6 -1.4,3.6 ; 0.2,-3.6 0.8,-3.6 ; 0.2,3.6 0.8,3.6 ; 2.4,-3.6 3,-3.6 ; 2.4,3.6 3,3.6 ; 4.575,-3.6 5.3,-3.6 5.3,3.6 4.575,3.6
  lines w0.5: -3.8,-1.945 -3.8,2.025
M13_Assembly_Info:
  lines w0.1: -5.15,-3.45 5.15,-3.45 5.15,3.45 -5.15,3.45 -5.15,-3.45
M15_Country_Yard:
  lines w0.1: -0.5,0 0.5,0 ; 0,-0.5 0,0.5
3D body: height 5.65, standoff 0, extent -4.99,-3.779 5.01,3.738

## REL_IM03NS [mm] "Signal Relay, Narrow version; Axicom - TE Connectivity"
height 5.8
pads (8):
  oval 1x1.8 hole 0.8: 1(-3.8,-1.6) 2(-0.6,-1.6) 3(1.6,-1.6) 4(3.8,-1.6) 5(3.8,1.6) 6(1.6,1.6) 7(-0.6,1.6) 8(-3.8,1.6)
Top Overlay:
  lines w0.2: -3,-2.3 -2.4,-2.3 ; -2.7,-2.6 -2.7,-2 ; -5.15,-3 -5.15,3 5.15,3 5.15,-3 -5.15,-3
M13_Assembly_Info:
  lines w0.1: -5,-2.85 -5,2.85 5,2.85 5,-2.85 -5,-2.85
M15_Country_Yard:
  lines w0.1: -0.5,0 0.5,0 ; 0,-0.5 0,0.5

## REL_IM_Series_PTH_Axicom [mm] "IM series signal relays - Axicom"
height 5.67
pads (8):
  rect 1.2x1.2 hole 0.6: 1(-3.79,-1.59)
  round 1.2 hole 0.6: 2(-0.59,-1.59) 3(1.61,-1.59) 4(3.81,-1.59) 5(3.81,1.61) 6(1.61,1.61) 7(-0.59,1.61) 8(-3.79,1.61)
Top Overlay:
  lines w0.2: -4.99,-2.99 -4.99,3.01 5.01,3.01 5.01,-2.99 -4.99,-2.99
  lines w0.5: -4.66,-0.91 -4.66,0.94
M15_Country_Yard:
  lines w0.1: -0.5,0 0.5,0 ; 0,-0.5 0,0.5
3D body: height 5.65, standoff 0, extent -4.92,-3.73 5.08,3.787

## REL_TRX [mm] "DIL Relay; Tai-Shing"
height 9.4
pads (8):
  round 1.7 hole 1: 1(-6.3,-2.525) 3(-1.22,-2.525) 4(1.32,-2.525) 5(3.86,-2.525) 6(3.86,2.555) 7(1.32,2.555) 8(-1.22,2.555) 10(-6.3,2.555)
Top Overlay:
  circle w0.3: c-7.075,-1.525 r0.05
  circle w0.1: c1.325,-1.325 r0.25
  circle w0.1: c1.325,1.325 r0.25
  region: -1.5,-1.625 -0.95,-1.625 -1.225,-1.35
  region: 3.575,-1.625 4.125,-1.625 3.85,-1.35
  region: 3.575,1.625 4.125,1.625 3.85,1.35
  region: -1.5,1.625 -0.95,1.625 -1.225,1.35
  lines w0.1: -6.3,-1.525 -6.3,-1.375 ; -6.3,1.425 -6.3,1.575 ; -1.5,-1.325 1.075,-1.325 ; -1.5,1.325 1.075,1.325 ; 1.575,-1.325 4,-0.8 ; 1.575,1.325 4,0.8 ; -6.7,-1.375 -6.7,1.425 -5.9,1.425 -5.9,-1.375 -6.7,-1.375
  lines w0.2: -7.5,-3.725 -7.5,3.775 7.5,3.775 7.5,-3.725 -7.5,-3.725
M13_Assembly_Info:
  circle w0.3: c-7.075,-1.525 r0.15
  lines w0.1: -7.5,-3.725 7.5,-3.725 7.5,3.775 -7.5,3.775 -7.5,-3.725
3D body: height 0, standoff 0, extent -7.5,-3.725 7.5,3.775

## REL_TSC-105L3H,000 [mm] "TSC series signal relays - TE Connectivity"
height 9.9
pads (6):
  rect 1.2x2 hole 0.8: 1(-5.08,-2.54)
  oval 1.2x2 hole 0.8: 2(-2.54,-2.54) 5(5.08,-2.54) 6(5.08,2.54) 9(-2.54,2.54) 10(-5.08,2.54)
Top Overlay:
  lines w0.2: -5.38,-1 -5.08,-0.7 ; -5.38,1 -5.08,0.7 ; -5.2,-0.4 -4.8,0 5.1,0 ; -5.08,-1.2 -5.08,-0.7 ; -5.08,1.2 -5.08,0.7 ; -4.78,-1 -5.08,-0.7 ; -4.78,1 -5.08,0.7 ; 5.1,-1.2 5.1,0 ; 5.1,1.2 5.1,0 ; -6.25,-3.75 6.25,-3.75 6.25,3.75 -6.25,3.75 -6.25,-3.75
  lines w0.5: -1.33,-3.19 cw(c-1.415,-3.184) -1.33,-3.18

## RESARRAY-EXBV8V [mm] "EXBV8 Series Resistor Array, 4x0603, Isolated; Panasonic"
height 0.6
pads (8):
  rect 0.95x0.5 smd: 1(0,0) 2(0,-0.8) 3(0,-1.6) 4(0,-2.4) 5(1.6,-2.4) 6(1.6,-1.6) 7(1.6,-0.8) 8(1.6,0)
Top Overlay:
  circle w0.2: c-0.325,0.675 r0.075
  lines w0.2: 0,-2.95 1.6,-2.95 ; 0,0.55 1.6,0.55
M13_Assembly_Info:
  lines w0.1: 0,-2.8 1.6,-2.8 1.6,-2 1.6,-1.2 1.6,-0.4 1.6,0.4 0,0.4 0,-0.4 0,-1.2 0,-2 0,-2.8
M15_Country_Yard:
  lines w0.1: 0.45,-1.2 1.15,-1.2 ; 0.8,-1.55 0.8,-0.85 ; -0.75,-3.125 2.35,-3.125 2.35,0.75 -0.75,0.75 -0.75,-3.125
3D body: height 0, standoff 0, extent 0,-2.8 1.6,0.4

## RESARRAY_4X0603 [mm]
height 0.71
pads (8):
  rect 0.5x1 smd: 1(-1.2,-0.8) 2(-0.4,-0.8) 3(0.4,-0.8) 4(1.2,-0.8) 5(1.2,0.8) 6(0.4,0.8) 7(-0.4,0.8) 8(-1.2,0.8)
Top Overlay:
  lines w0.203: -1.6,-0.8 -1.6,0.8 ; -1.6,0 1.6,0 ; 1.6,-0.8 1.6,0.8
M13_Assembly_Info:
  circle w0.2: c-1.325,-0.525 r0.1
  lines w0.1: -1.6,-0.8 1.6,-0.8 1.6,0.8 -1.6,0.8 -1.6,-0.8
M15_Country_Yard:
  lines w0.1: -0.5,0 0.5,0 ; 0,-0.5 0,0.5 ; -1.9,-1.5 1.9,-1.5 1.9,1.5 -1.9,1.5 -1.9,-1.5
3D body: height 0, standoff 0, extent -1.6,-0.8 1.6,0.8

## RESAXIAL-0.1 [mm]
pads (2):
  round 1.6 hole 0.9: 1(0,0) 2(2.54,0)
Top Overlay:
  circle w0.2: c2.54,0 r1.065
  lines w0.2: 1,0 1.475,0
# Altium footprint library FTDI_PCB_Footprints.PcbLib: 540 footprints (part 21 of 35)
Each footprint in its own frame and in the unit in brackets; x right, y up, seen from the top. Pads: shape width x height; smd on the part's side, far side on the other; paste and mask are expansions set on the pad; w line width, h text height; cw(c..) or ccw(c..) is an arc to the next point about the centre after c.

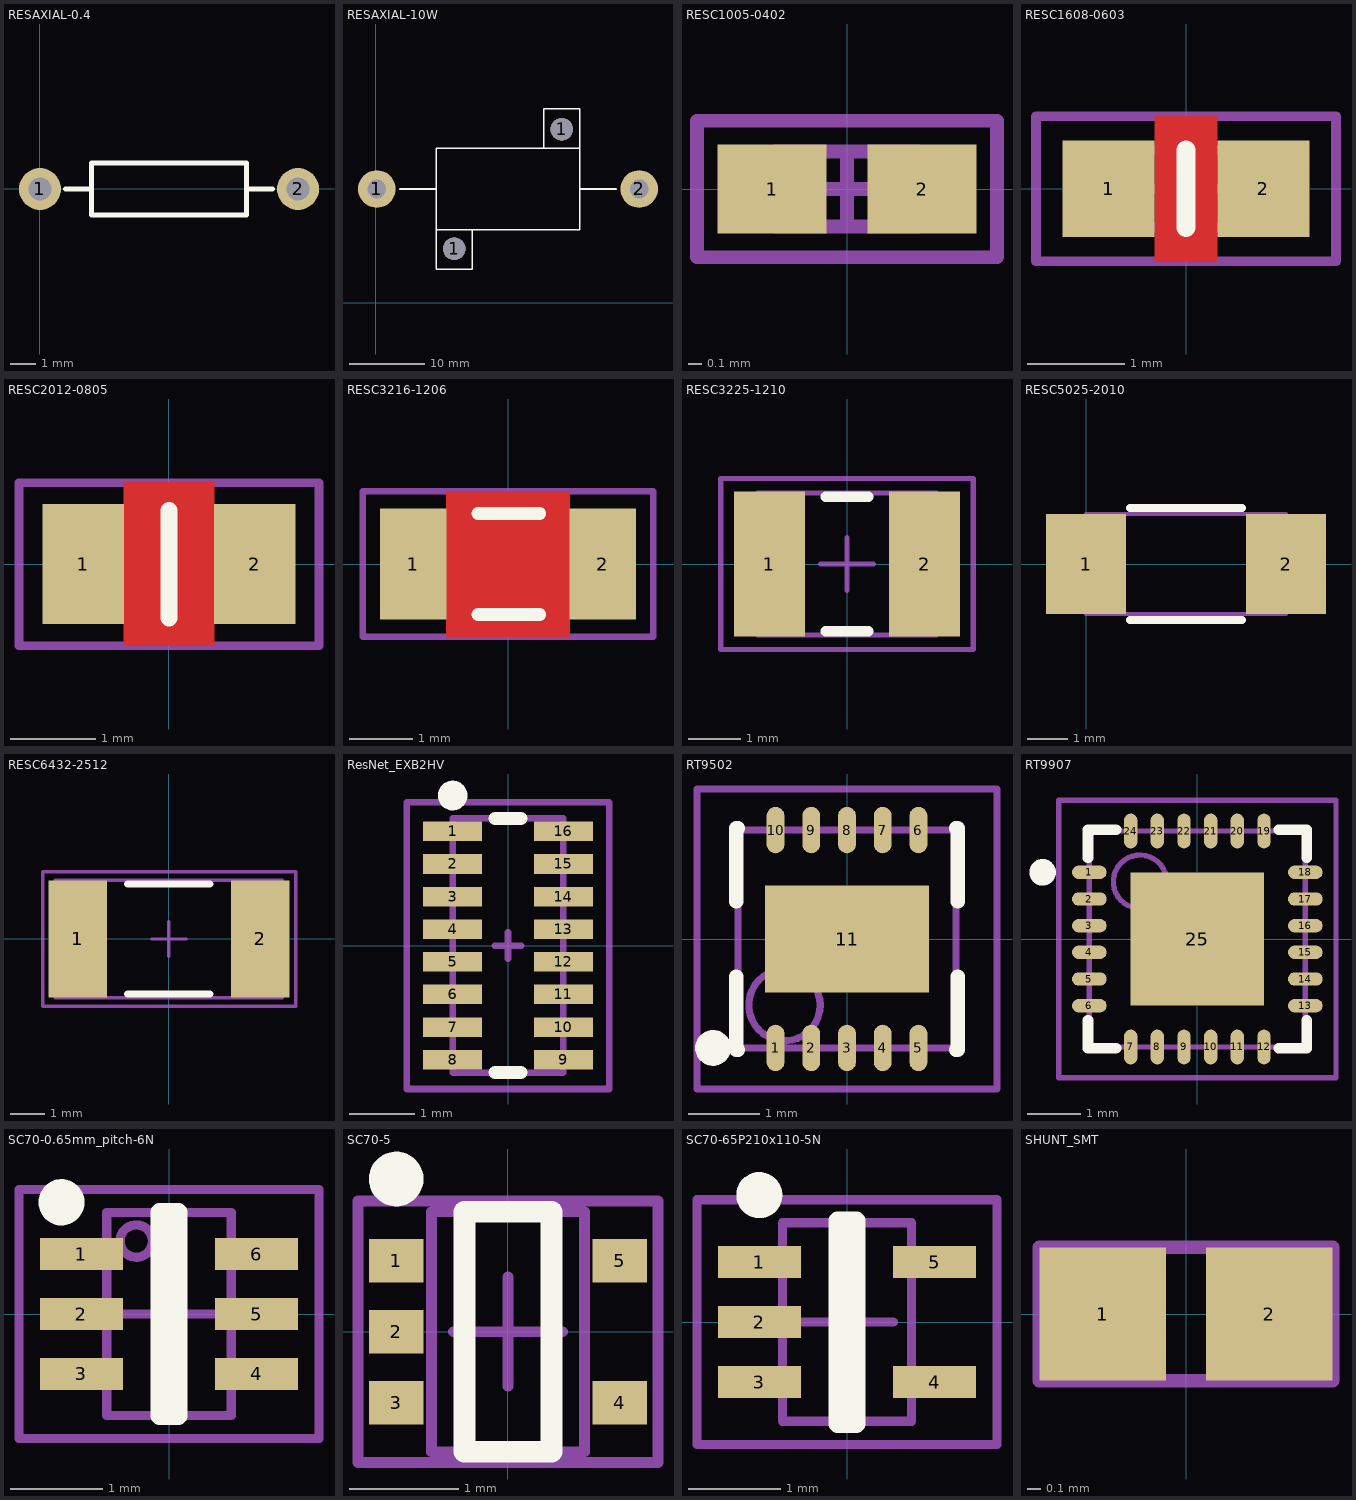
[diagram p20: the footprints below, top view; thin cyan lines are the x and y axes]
## RESAXIAL-0.4 [mil]
pads (2):
  round 65 hole 35: 1(0,0) 2(400,0)
Top Overlay:
  lines w7.87: 40,0 80,0 ; 320,0 360,0 ; 80,-40 80,40 320,40 320,-40 80,-40

## RESAXIAL-10W [mm] "Vishay Dale; 10W; Wirewound Resistor; Type RW; Precision Power; Silicone Coated"
height 15
pads (4):
  round 5 hole 2.5: 1(0.11,15.12) 2(35.01,15.12)
  round 3 hole 3 unplated: 1(10.41,7.17) 1(24.71,23.07)
Top Overlay:
  lines w0.2: 3.15,15.12 8.01,15.12 ; 12.81,9.67 12.81,4.47 8.01,4.47 8.01,9.67 ; 22.31,20.57 22.31,25.77 27.11,25.77 27.11,20.57 ; 27.11,15.12 31.97,15.12 ; 8.01,9.67 27.11,9.67 27.11,20.57 ; 8.01,9.67 8.01,20.57 27.11,20.57

## RESC1005-0402 [mm] "Chip Resistor, 2-Leads, Body 1.0x0.5mm, IPC Medium Density"
height 0.4
pads (2):
  rect 0.8x0.65 smd: 1(-0.55,0) 2(0.55,0)
M13_Assembly_Info:
  lines w0.1: -0.525,-0.275 -0.525,0.275 0.525,0.275 0.525,-0.275 -0.525,-0.275
M15_Country_Yard:
  lines w0.1: -0.275,0 0.275,0 ; 0,-0.275 0,0.275 ; -1.1,-0.5 -1.1,0.5 1.1,0.5 1.1,-0.5 -1.1,-0.5
3D body: height 0.4, standoff 0, extent -0.525,-0.275 0.525,0.275

## RESC1608-0603 [mm] "Chip Resistor; Body 1.6 x 0.8 mm (LxW typ)"
height 0.6
pads (2):
  rect 0.95x1 smd: 1(-0.8,0) 2(0.8,0)
Top Layer:
  pour cut-out: -0.325,-0.755 -0.325,0.75 0.325,0.75 0.325,-0.755
Top Overlay:
  lines w0.2: 0,-0.4 0,0.4
M13_Assembly_Info:
  lines w0.1: -0.8,-0.4 -0.8,0.4 0.8,0.4 0.8,-0.4 -0.8,-0.4
M15_Country_Yard:
  lines w0.1: -0.35,0 0.35,0 ; 0,-0.35 0,0.35 ; -1.55,-0.75 1.55,-0.75 1.55,0.75 -1.55,0.75 -1.55,-0.75
3D body: height 0.57, standoff 0.02, extent -0.775,-0.4 0.825,0.4

## RESC2012-0805 [mm] "Chip Resistor; Body 2 x 1.3 mm (LxW typ)"
height 0.65
pads (2):
  rect 0.95x1.4 smd: 1(-1,0) 2(1,0)
Top Layer:
  pour cut-out: -0.525,0.955 0.525,0.955 0.525,-0.95 -0.525,-0.95
Top Overlay:
  lines w0.2: 0,-0.625 0,0.625
M13_Assembly_Info:
  lines w0.1: -1,-0.625 1,-0.625 1,0.625 -1,0.625 -1,-0.625
M15_Country_Yard:
  lines w0.1: -0.35,0 0.35,0 ; 0,-0.35 0,0.35 ; -1.75,-0.95 -1.75,0.95 1.75,0.95 1.75,-0.95 -1.75,-0.95
3D body: height 0.62, standoff 0.02, extent -1.025,-0.625 0.975,0.575

## RESC3216-1206 [mm] "Chip Resistor; Body 3.2 x 1.6 mm (LxW typ)"
height 0.71
pads (2):
  rect 1.05x1.75 smd: 1(-1.5,0) 2(1.5,0)
Top Layer:
  pour cut-out: -0.975,1.15 0.975,1.15 0.975,-1.15 -0.975,-1.15
Top Overlay:
  lines w0.2: -0.475,-0.8 0.5,-0.8 ; -0.475,0.8 0.5,0.8
M13_Assembly_Info:
  lines w0.1: -1.6,-0.8 -1.6,0.8 1.6,0.8 1.6,-0.8 -1.6,-0.8
M15_Country_Yard:
  lines w0.1: -0.5,0 0.5,0 ; 0,-0.5 0,0.5 ; -2.3,-1.15 -2.3,1.15 2.3,1.15 2.3,-1.15 -2.3,-1.15
3D body: height 0.67, standoff 0.02, extent -1.625,-0.825 1.575,0.775

## RESC3225-1210 [mm] "Chip Resistor, 2-Leads, Body 3.2x2.5mm, IPC Medium Density"
height 0.6
pads (2):
  rect 1.35x2.75 smd: 1(-1.475,0) 2(1.475,0)
Top Overlay:
  lines w0.2: -0.4,-1.275 0.4,-1.275 ; -0.4,1.275 0.4,1.275
M13_Assembly_Info:
  lines w0.1: -1.7,-1.35 1.7,-1.35 1.7,1.35 -1.7,1.35 -1.7,-1.35
M15_Country_Yard:
  lines w0.1: -0.5,0 0.5,0 ; 0,-0.5 0,0.5 ; -2.4,-1.625 2.4,-1.625 2.4,1.625 -2.4,1.625 -2.4,-1.625
3D body: height 0.67, standoff 0.02, extent -1.575,-1.25 1.625,1.25

## RESC5025-2010 [mm] "Chip Resistor; Body 5.0 x 2.5 mm (LxW typ)"
height 0.71
pads (2):
  rect 2x2.5 smd: 1(0,0) 2(5,0)
Top Overlay:
  lines w0.2: 1.1,-1.4 3.9,-1.4 ; 1.1,1.4 3.9,1.4
M13_Assembly_Info:
  lines w0.1: 0,-1.25 0,1.25 5,1.25 5,-1.25 0,-1.25
3D body: height 0, standoff 0, extent 0,-1.25 5,1.25

## RESC6432-2512 [mm] "Chip Resistor, 2-Leads, Body 6.4x3.2mm, IPC Medium Density"
height 1.2
pads (2):
  rect 1.7x3.4 smd: 1(-2.65,0) 2(2.66,0)
Top Overlay:
  lines w0.2: -1.2,-1.6 1.2,-1.6 ; -1.2,1.6 1.2,1.6
M13_Assembly_Info:
  lines w0.1: -3.3,-1.7 -3.3,1.7 3.3,1.7 3.3,-1.7 -3.3,-1.7
M15_Country_Yard:
  lines w0.1: -0.5,0 0.5,0 ; 0,-0.5 0,0.5 ; -3.66,-1.95 -3.66,1.95 3.68,1.95 3.68,-1.95 -3.66,-1.95
3D body: height 1.2, standoff 0, extent -3.3,-1.7 3.3,1.7

## ResNet_EXB2HV [mm] "Chip Resistor network, 16-Leads, Body 1.6x3.8mm, IPC Medium Density"
height 0.55
pads (16):
  rect 0.9x0.3 smd: 1(-0.85,1.75) 2(-0.85,1.25) 3(-0.85,0.75) 4(-0.85,0.25) 5(-0.85,-0.25) 6(-0.85,-0.75) 7(-0.85,-1.25) 8(-0.85,-1.75) 9(0.85,-1.75) 10(0.85,-1.25) 11(0.85,-0.75) 12(0.85,-0.25) 13(0.85,0.25) 14(0.85,0.75) 15(0.85,1.25) 16(0.85,1.75)
Top Overlay:
  circle w0.254: c-0.85,2.3 r0.1
  lines w0.2: -0.2,-1.95 0.2,-1.95 ; -0.2,1.95 0.2,1.95
M13_Assembly_Info:
  lines w0.1: -0.85,-1.95 0.85,-1.95 0.85,1.95 -0.85,1.95 -0.85,-1.95
M15_Country_Yard:
  lines w0.1: -0.2,0 0.2,0 ; 0,-0.2 0,0.2 ; -1.55,-2.2 1.55,-2.2 1.55,2.2 -1.55,2.2 -1.55,-2.2
3D body: height 0.55, standoff 0, extent -0.85,-1.95 0.85,1.95

## RT9502 [mm] "RT9502 Battery Charger Footprint"
height 0.75
pads (11):
  oval 0.25x0.65 smd: 1(-1,-1.525) 2(-0.5,-1.525) 3(0,-1.525) 4(0.5,-1.525) 5(1,-1.525) 6(1,1.525) 7(0.5,1.525) 8(0,1.525) 9(-0.5,1.525) 10(-1,1.525)
  rect 2.3x1.5 smd: 11(0,0)
Top Overlay:
  circle w0.25: c-1.875,-1.525 r0.125
  lines w0.2: -1.55,-0.525 -1.55,-1.55 -1.525,-1.55 ; -1.55,0.525 -1.55,1.55 -1.525,1.55 ; 1.525,-1.55 1.55,-1.55 1.55,-0.525 ; 1.525,1.55 1.55,1.55 1.55,0.525
M13_Assembly_Info:
  circle w0.1: c-0.875,-0.925 r0.5
  lines w0.1: -1.525,-1.525 1.525,-1.525 1.525,1.525 -1.525,1.525 -1.525,-1.525
M15_Country_Yard:
  lines w0.1: -0.5,0 0.5,0 ; 0,-0.5 0,0.5 ; -2.1,-2.1 2.1,-2.1 2.1,2.1 -2.1,2.1 -2.1,-2.1
3D body: height 0.75, standoff 0.05, extent -1.525,-1.525 1.525,1.525

## RT9907 [mm] "RT9907 Footprint"
height 0.75
pads (25):
  oval 0.65x0.25 smd: 1(-2.025,1.25) 2(-2.025,0.75) 3(-2.025,0.25) 4(-2.025,-0.25) 5(-2.025,-0.75) 6(-2.025,-1.25) 13(2.025,-1.25) 14(2.025,-0.75) 15(2.025,-0.25) 16(2.025,0.25) 17(2.025,0.75) 18(2.025,1.25)
  oval 0.25x0.65 smd: 7(-1.25,-2.025) 8(-0.75,-2.025) 9(-0.25,-2.025) 10(0.25,-2.025) 11(0.75,-2.025) 12(1.25,-2.025) 19(1.25,2.025) 20(0.75,2.025) 21(0.25,2.025) 22(-0.25,2.025) 23(-0.75,2.025) 24(-1.25,2.025)
  rect 2.5x2.5 smd: 25(0,0)
Top Overlay:
  circle w0.25: c-2.9,1.25 r0.125
  lines w0.2: -2.05,-1.525 -2.05,-2.05 -1.525,-2.05 ; -2.05,1.525 -2.05,2.05 -1.525,2.05 ; 1.525,-2.05 2.05,-2.05 2.05,-1.525 ; 1.525,2.05 2.05,2.05 2.05,1.525
M13_Assembly_Info:
  circle w0.1: c-1.075,1.075 r0.5
  lines w0.1: -2.025,-2.025 -2.025,2.025 2.025,2.025 2.025,-2.025 -2.025,-2.025
M15_Country_Yard:
  lines w0.1: -0.5,0 0.5,0 ; 0,-0.5 0,0.5 ; -2.6,-2.6 -2.6,2.6 2.6,2.6 2.6,-2.6 -2.6,-2.6
3D body: height 0.75, standoff 0.05, extent -2.025,-2.025 2.025,2.025

## SC70-0.65mm_pitch-6N [mm] "SC70, 6-Leads, Body 2.2x2.4mm (max), Pitch 0.65mm, IPC Medium Density"
height 1
pads (6):
  rect 0.9x0.35 smd: 1(-0.95,0.65) 2(-0.95,0) 3(-0.95,-0.65) 4(0.95,-0.65) 5(0.95,0) 6(0.95,0.65)
Top Overlay:
  circle w0.25: c-1.165,1.21 r0.125
  lines w0.2: -0.1,-1.1 0.1,-1.1 0.1,1.1 -0.1,1.1 -0.1,-1.1
M13_Assembly_Info:
  circle w0.1: c-0.355,0.79 r0.175
  lines w0.1: -0.675,-1.1 -0.675,1.1 0.675,1.1 0.675,-1.1 -0.675,-1.1
M15_Country_Yard:
  lines w0.1: -0.5,0 0.5,0 ; 0,-0.5 0,0.5 ; -1.625,-1.35 -1.625,1.35 1.625,1.35 1.625,-1.35 -1.625,-1.35
3D body: height 1, standoff 0.1, extent -0.675,-1.1 0.675,1.1

## SC70-5 [mm] "SC70, 5-Leads, Body 2.0x1.3mm, Pitch 0.65mm, Lead Span 2.1mm"
height 1.1
pads (5):
  rect 0.5x0.4 smd: 1(-1.025,0.65) 2(-1.025,0) 3(-1.025,-0.65) 4(1.025,-0.65) 5(1.025,0.65)
Top Overlay:
  circle w0.25: c-1.025,1.4 r0.125
  lines w0.2: -0.4,-1.1 0.4,-1.1 0.4,1.1 -0.4,1.1 -0.4,-1.1
M13_Assembly_Info:
  lines w0.1: -0.7,-1.1 -0.7,1.1 0.7,1.1 0.7,-1.1 -0.7,-1.1
M15_Country_Yard:
  lines w0.1: -0.5,0 0.5,0 ; 0,-0.5 0,0.5 ; -1.375,-1.2 -1.375,1.2 1.375,1.2 1.375,-1.2 -1.375,-1.2
3D body: height 1.1, standoff 0, extent -0.7,-1.1 0.7,1.1

## SC70-65P210x110-5N [mm] "SC70, 5-Leads, Body 2.2x2.4mm (max), Pitch 0.65mm, IPC Medium Density"
height 1.1
pads (5):
  rect 0.9x0.35 smd: 1(-0.95,0.65) 2(-0.95,0) 3(-0.95,-0.65) 4(0.95,-0.65) 5(0.95,0.65)
Top Overlay:
  circle w0.25: c-0.95,1.375 r0.125
  lines w0.2: -0.1,-1.1 0.1,-1.1 0.1,1.1 -0.1,1.1 -0.1,-1.1
M13_Assembly_Info:
  lines w0.1: -0.7,-1.075 -0.7,1.075 0.7,1.075 0.7,-1.075 -0.7,-1.075
M15_Country_Yard:
  lines w0.1: -0.5,0 0.5,0 ; 0,-0.5 0,0.5 ; -1.625,-1.325 -1.625,1.325 1.625,1.325 1.625,-1.325 -1.625,-1.325
3D body: height 1.1, standoff 0.1, extent -0.7,-1.075 0.7,1.075

## SHUNT_SMT [mm]
pads (2):
  rect 0.95x1 smd: 1(-0.625,0) 2(0.625,0)
M13_Assembly_Info:
  lines w0.1: -1.1,-0.5 1.1,-0.5 1.1,0.5 -1.1,0.5 -1.1,-0.5
3D body: height 1, standoff 0, extent -1.1,-0.5 1.1,0.5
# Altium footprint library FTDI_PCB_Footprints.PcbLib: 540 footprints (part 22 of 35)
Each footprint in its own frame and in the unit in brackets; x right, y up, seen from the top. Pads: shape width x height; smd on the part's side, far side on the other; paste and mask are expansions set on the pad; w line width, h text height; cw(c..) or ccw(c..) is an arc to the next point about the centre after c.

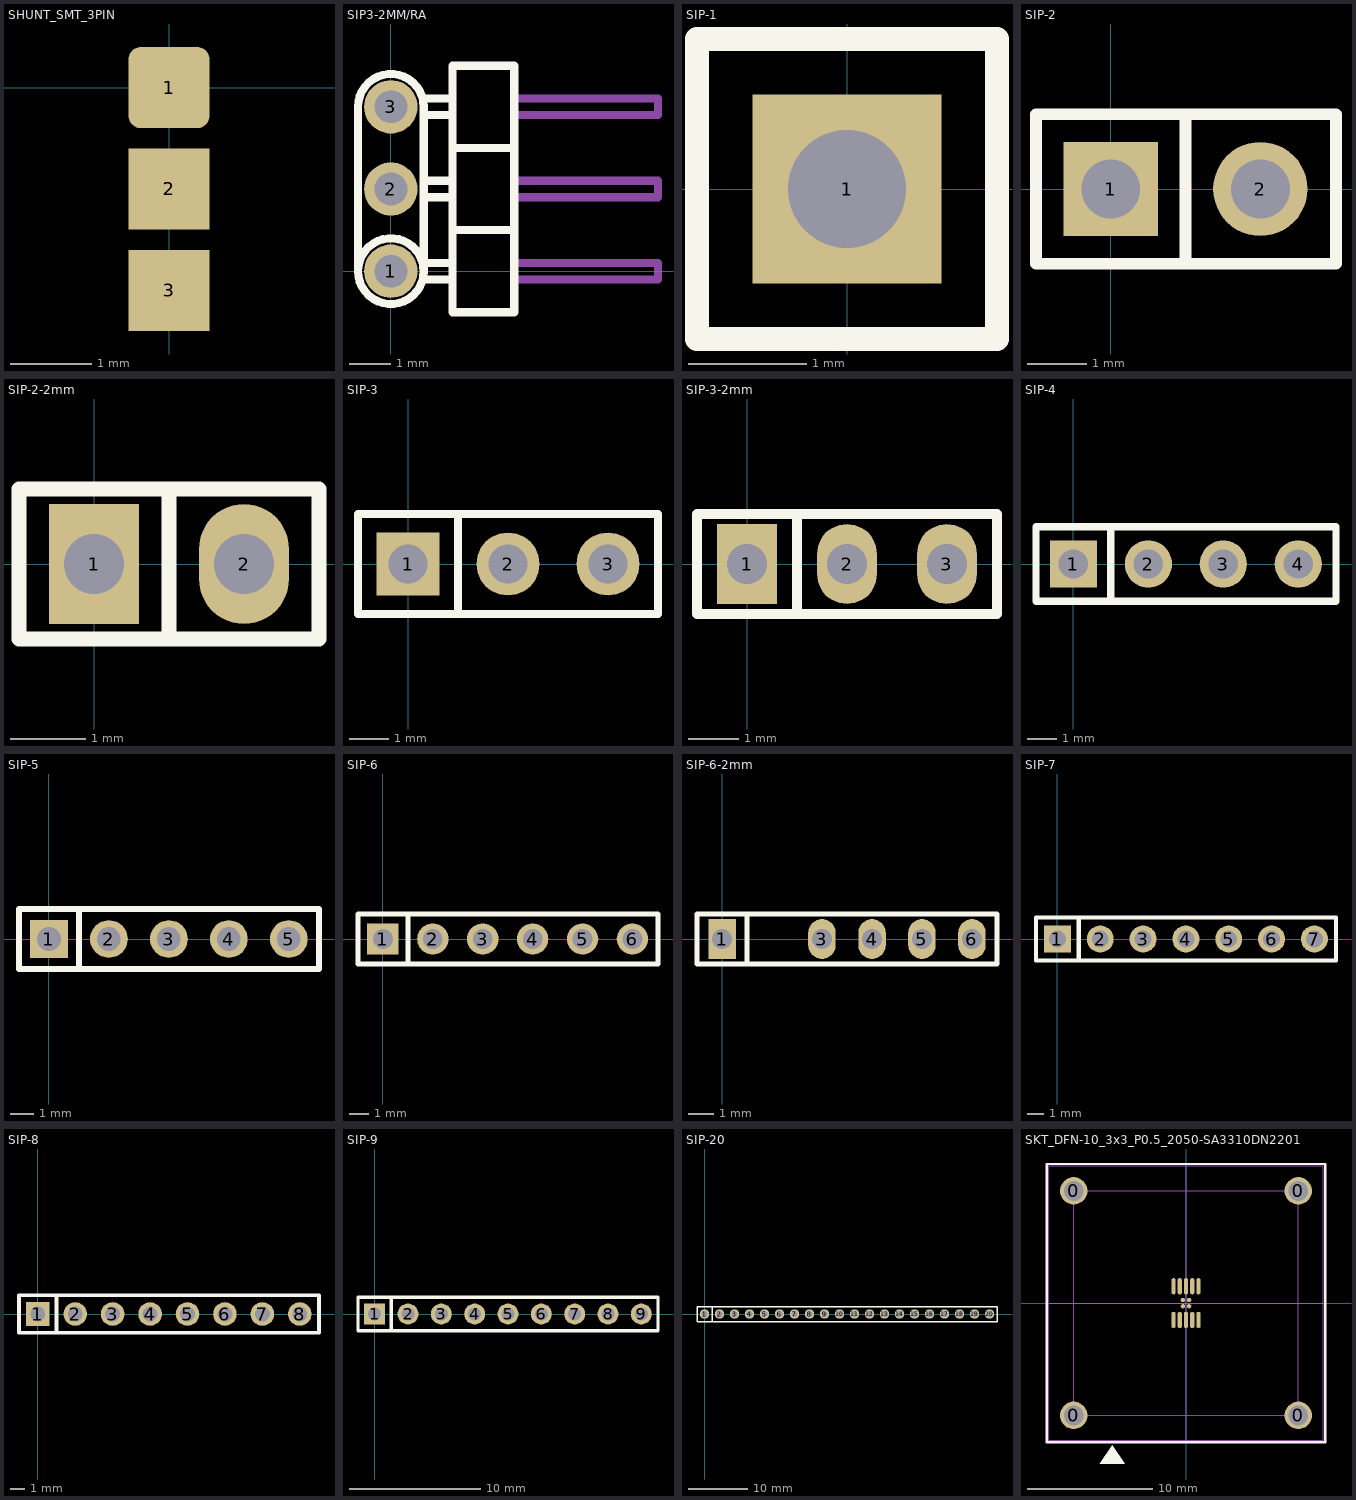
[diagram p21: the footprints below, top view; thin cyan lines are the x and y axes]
## SHUNT_SMT_3PIN [mm]
pads (3):
  rrect30% 1x1 smd: 1(0,0)
  rect 1x1 smd: 2(0,-1.25) 3(0,-2.5)
Top Solder:
  region: -0.6,0.6 -0.6,-3.1 0.6,-3.1 0.6,0.6

## SIP3-2MM/RA [mm] "Right Angle 2mm 3 way header"
pads (3):
  round 1.3 hole 0.8: 1(0,0) 2(0,2) 3(0,4)
Top Overlay:
  lines w0.2: 0.8,-0.2 1.5,-0.2 ; 0.8,0.2 1.5,0.2 ; 0.8,1.8 1.5,1.8 ; 0.8,2.2 1.5,2.2 ; 0.8,3.8 1.5,3.8 ; 0.8,4.2 1.5,4.2 ; 1.5,1 3,1 ; 1.5,3 3,3 ; -0.8,0 ccw(c0,0) 0.8,0 ; -0.8,0 cw(c0,0) 0.8,0 ; -0.8,0 -0.8,4 cw(c0,4) 0.8,4 0.8,0 ; 1.5,-1 1.5,5 3,5 3,-1 1.5,-1
M13_Assembly_Info:
  lines w0.2: 3,-0.2 6.5,-0.2 6.5,0.2 3,0.2 ; 3,1.8 6.5,1.8 6.5,2.2 3,2.2 ; 3,3.8 6.5,3.8 6.5,4.2 3,4.2

## SIP-1 [mm] "Single possition jumper"
pads (1):
  rect 1.6x1.6 hole 1: 1(0,0)
Top Overlay:
  lines w0.2: -1.27,-1.27 1.27,-1.27 1.27,1.27 -1.27,1.27 -1.27,-1.27
M13_Assembly_Info:
  lines w0.1: -1.27,-1.27 1.27,-1.27 1.27,1.27 -1.27,1.27 -1.27,-1.27
3D body: height 0, standoff 0, extent -1.27,-1.27 1.27,1.27

## SIP-2 [mm] "2 possition jumper; 0.1\" pitch"
pads (2):
  rect 1.6x1.6 hole 1: 1(0,0)
  round 1.6 hole 1: 2(2.54,0)
Top Overlay:
  lines w0.2: 1.27,-1.27 1.27,1.27 ; -1.27,-1.27 3.825,-1.27 3.825,1.27 -1.27,1.27 -1.27,-1.27
M13_Assembly_Info:
  lines w0.1: -1.27,-1.27 3.825,-1.27 3.825,1.27 -1.27,1.27 -1.27,-1.27
3D body: height 0, standoff 0, extent -1.27,-1.27 3.825,1.27

## SIP-2-2mm [mm] "Header, 2 pin, pitch 2.0mm"
pads (2):
  rect 1.2x1.6 hole 0.8: 1(0,0)
  oval 1.2x1.6 hole 0.8: 2(2,0)
Top Overlay:
  lines w0.2: 1,-1 1,1 ; -1,-1 -1,1 3,1 3,-1 -1,-1
3D body: height 6.5, standoff 0, extent -0.9,-0.9 2.9,0.9

## SIP-3 [mm] "3 possition jumper; pitch 0.1\""
pads (3):
  rect 1.6x1.6 hole 1: 1(0,0)
  round 1.6 hole 1: 2(2.54,0) 3(5.08,0)
Top Overlay:
  lines w0.2: 1.27,-1.27 1.27,1.27 ; -1.27,-1.27 6.35,-1.27 6.35,1.27 -1.27,1.27 -1.27,-1.27
M13_Assembly_Info:
  lines w0.1: -1.27,-1.27 6.35,-1.27 6.35,1.27 -1.27,1.27 -1.27,-1.27
3D body: height 0, standoff 0, extent -1.27,-1.27 6.35,1.27

## SIP-3-2mm [mm] "Header, 3 pin, pitch 2.0mm"
pads (3):
  rect 1.2x1.6 hole 0.8: 1(0,0)
  oval 1.2x1.6 hole 0.8: 2(2,0) 3(4,0)
Top Overlay:
  lines w0.2: 1,-1 1,1 ; -1,-1 5,-1 5,1 -1,1 -1,-1
3D body: height 6.5, standoff 0, extent -0.9,-0.9 4.9,0.9

## SIP-4 [mm] "Header; 4pin; pitch 0.1\""
pads (4):
  rect 1.6x1.6 hole 1: 1(0,0)
  round 1.6 hole 1: 2(2.54,0) 3(5.08,0) 4(7.62,0)
Top Overlay:
  lines w0.254: 1.27,-1.27 1.27,1.27 ; -1.27,-1.27 -1.27,1.27 8.9,1.27 8.9,-1.27 -1.27,-1.27
3D body: height 6.5, standoff 0, extent -1.15,-1.15 8.77,1.16

## SIP-5 [mm] "Header; 5 pin; pitch 0.1\""
pads (5):
  rect 1.6x1.6 hole 1: 1(0,0)
  round 1.6 hole 1: 2(2.54,0) 3(5.08,0) 4(7.62,0) 5(10.16,0)
Top Overlay:
  lines w0.254: 1.27,-1.27 1.27,1.27 ; -1.27,-1.27 11.44,-1.27 11.44,1.27 -1.27,1.27 -1.27,-1.27
3D body: height 6.5, standoff 0, extent -1.15,-1.15 11.325,1.15

## SIP-6 [mm] "Header, 6 pin, pitch 0.1\""
pads (6):
  rect 1.6x1.6 hole 1: 1(0,0)
  round 1.6 hole 1: 2(2.54,0) 3(5.08,0) 4(7.62,0) 5(10.16,0) 6(12.7,0)
Top Overlay:
  lines w0.254: 1.27,-1.27 1.27,1.27 ; -1.27,-1.27 14,-1.27 14,1.27 -1.27,1.27 -1.27,-1.27
3D body: height 6.5, standoff 0, extent -1.15,-1.15 13.875,1.15

## SIP-6-2mm [mm] "Header, 6 pin, pitch 2.0mm; pin 2 blind; for VII debugger module"
pads (5):
  rect 1.1x1.6 hole 0.8: 1(0,0)
  oval 1.1x1.6 hole 0.8: 3(4,0) 4(6,0) 5(8,0) 6(10,0)
Top Overlay:
  lines w0.2: 1,-1 1,1 ; -1,-1 11,-1 11,1 -1,1 -1,-1
3D body: height 6.5, standoff 0, extent -0.9,-0.9 10.9,0.9

## SIP-7 [mm] "Header, 7 pin, pitch 0.1\""
pads (7):
  rect 1.6x1.6 hole 1: 1(0,0)
  round 1.6 hole 1: 2(2.54,0) 3(5.08,0) 4(7.62,0) 5(10.16,0) 6(12.7,0) 7(15.24,0)
Top Overlay:
  lines w0.254: 1.27,-1.27 1.27,1.27 ; -1.27,-1.27 -1.27,1.27 16.52,1.27 16.52,-1.27 -1.27,-1.27
3D body: height 6.5, standoff 0, extent -1.15,-1.15 16.39,1.15

## SIP-8 [mm] "Header, 8 pin, pitch 0.1\""
pads (8):
  rect 1.6x1.6 hole 1: 1(0,0)
  round 1.6 hole 1: 2(2.54,0) 3(5.08,0) 4(7.62,0) 5(10.16,0) 6(12.7,0) 7(15.24,0) 8(17.78,0)
Top Overlay:
  lines w0.254: 1.27,-1.27 1.27,1.27 ; -1.27,-1.27 19.08,-1.27 19.08,1.27 -1.27,1.27 -1.27,-1.27
3D body: height 6.5, standoff 0, extent -1.15,-1.15 18.975,1.15

## SIP-9 [mm] "Resistor array"
pads (9):
  rect 1.6x1.6 hole 1: 1(0,0)
  round 1.6 hole 1: 2(2.54,0) 3(5.08,0) 4(7.62,0) 5(10.16,0) 6(12.7,0) 7(15.24,0) 8(17.78,0) 9(20.32,0)
Top Overlay:
  lines w0.254: 1.27,-1.27 1.27,1.27 ; -1.27,-1.27 21.59,-1.27 21.59,1.27 -1.27,1.27 -1.27,-1.27

## SIP-20 [mm]
pads (20):
  round 1.6 hole 1: 1(0,0) 2(2.54,0) 3(5.08,0) 4(7.62,0) 5(10.16,0) 6(12.7,0) 7(15.24,0) 8(17.78,0) 9(20.32,0) 10(22.86,0) 11(25.4,0) 12(27.94,0) 13(30.48,0) 14(33.02,0) 15(35.56,0) 16(38.1,0) 17(40.64,0) 18(43.18,0) 19(45.72,0) 20(48.26,0)
Top Overlay:
  lines w0.254: 1.27,-1.27 1.27,1.27 ; -1.27,-1.27 -1.27,1.27 49.53,1.27 49.53,-1.27 -1.27,-1.27

## SKT_DFN-10_3x3_P0.5_2050-SA3310DN2201 [mm] "Tai-Chen Precision Inc. DFN-10 3x3mm body; 0.5mm pitch; Test Socket; 2050-SA3310DN2201"
height 6.6
pads (18):
  round 2.2 hole 1.6: 0(-9,-9) 0(-9,9) 0(9,-9) 0(9,9)
  oval 0.35x1.3 smd: 1(-1,-1.35) 2(-0.5,-1.35) 3(0,-1.35) 4(0.5,-1.35) 5(1,-1.35) 6(1,1.35) 7(0.5,1.35) 8(0,1.35) 9(-0.5,1.35) 10(-1,1.35)
  round 0.35 smd: 11(-0.25,-0.25) 11(-0.25,0.25) 11(0.25,-0.25) 11(0.25,0.25)
Top Overlay:
  region: -5.9,-11.4 -4.9,-12.9 -6.9,-12.9
  lines w0.2: -11.15,-11.14 11.15,-11.14 11.15,11.15 -11.15,11.15 -11.15,-11.14
Top Solder:
  region: 11,-11 -11,-11 -11,11 11,11
M15_Country_Yard:
  lines w0.1: -11,0 11,0 ; -9,0 9,0 ; -0.5,0 0.5,0 ; 0,-11 0,11 ; 0,-9 0,9 ; 0,-0.5 0,0.5 ; -11,-11 11,-11 11,11 -11,11 -11,-11 ; -9,-9 9,-9 9,9 -9,9 -9,-9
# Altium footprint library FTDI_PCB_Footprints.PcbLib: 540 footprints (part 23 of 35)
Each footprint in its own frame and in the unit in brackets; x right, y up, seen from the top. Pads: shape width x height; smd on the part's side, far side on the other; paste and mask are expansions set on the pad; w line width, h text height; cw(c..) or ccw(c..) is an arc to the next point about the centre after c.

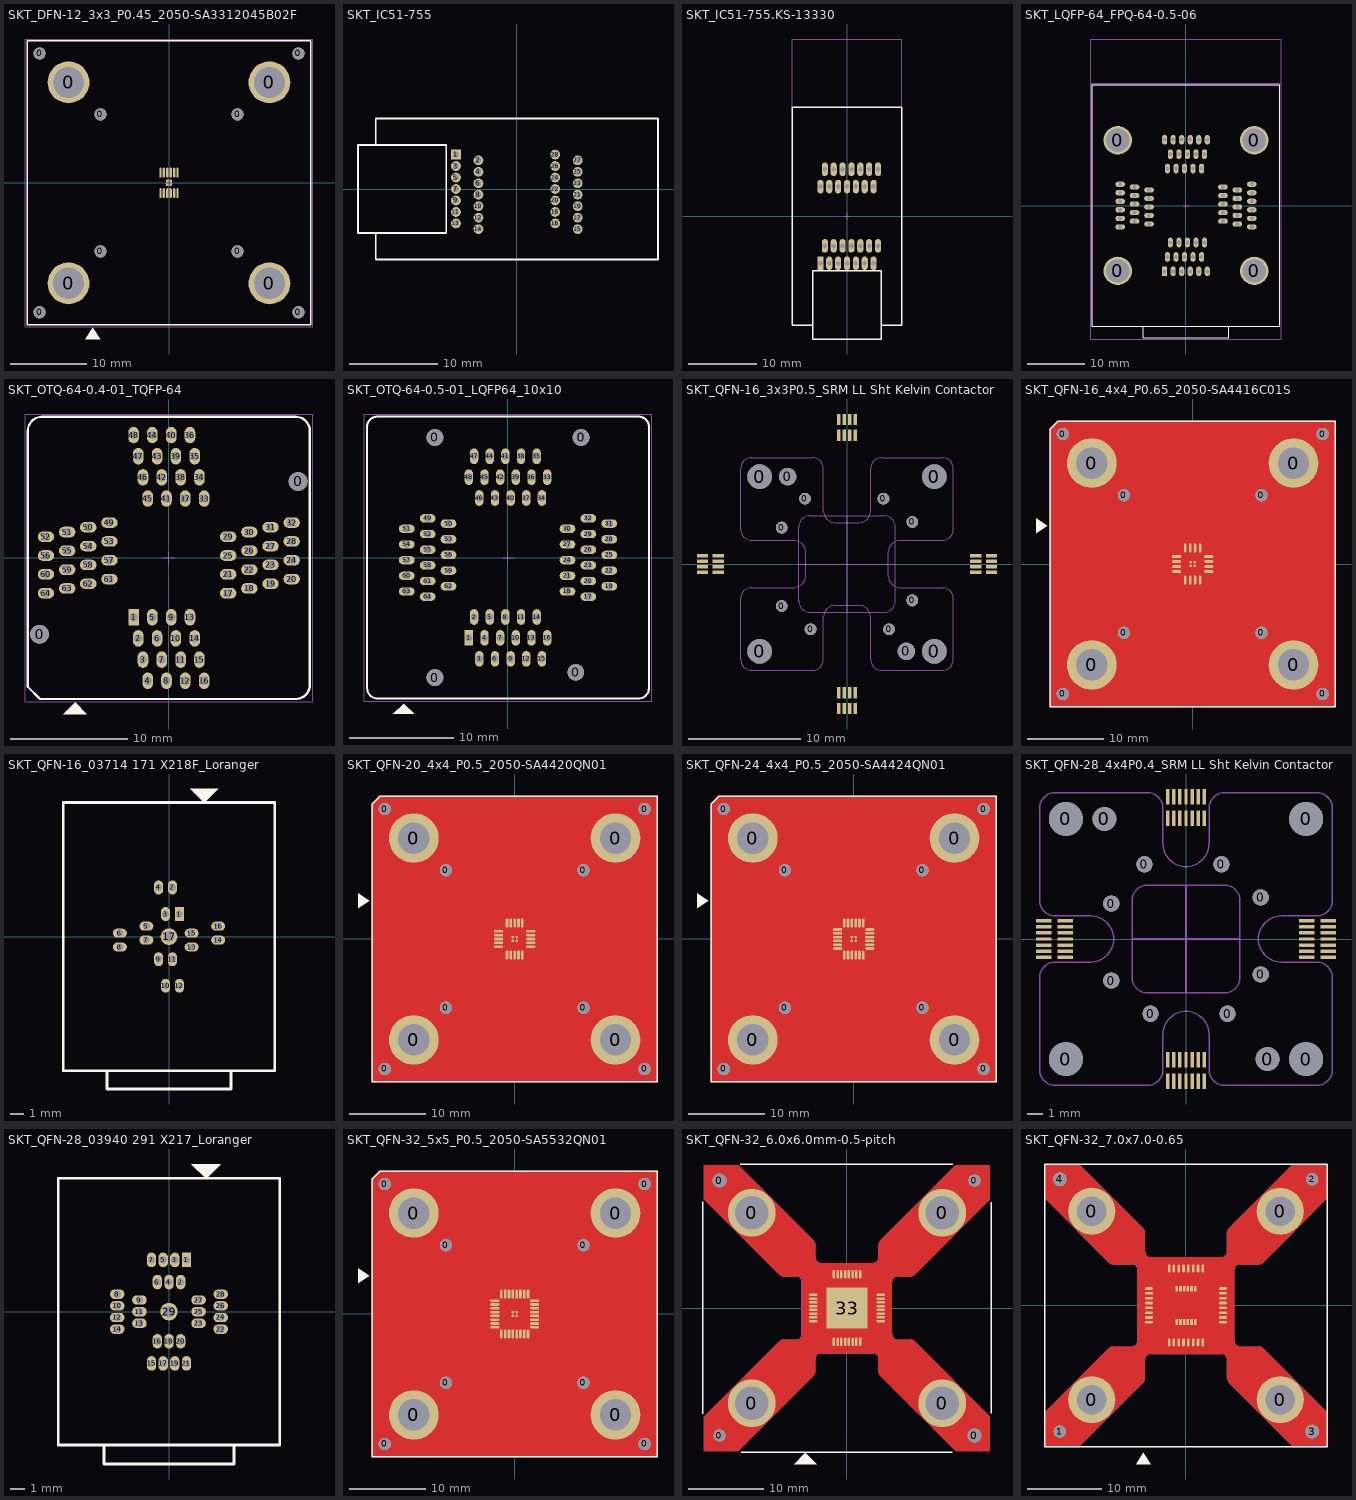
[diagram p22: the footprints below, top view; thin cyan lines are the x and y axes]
## SKT_DFN-12_3x3_P0.45_2050-SA3312045B02F [mm] "Tai-Chen Precision Inc. DFN-12 3x3mm body; 0.45mm pitch; Test Socket; 2050-SA3312045B02F"
height 6.6
pads (28):
  round 1.6 hole 1.6 unplated: 0(-17,-17) 0(-17,17) 0(-9,-9) 0(-9,9) 0(9,-9) 0(9,9) 0(17,-17) 0(17,17)
  round 5.5 hole 4.1: 0(-13.2,-13.2) 0(-13.2,13.2) 0(13.2,-13.2) 0(13.2,13.2)
  oval 0.3x1.3 smd: 1(-1.125,-1.35) 2(-0.675,-1.35) 3(-0.225,-1.35) 4(0.225,-1.35) 5(0.675,-1.35) 6(1.125,-1.35) 7(1.125,1.35) 8(0.675,1.35) 9(0.225,1.35) 10(-0.225,1.35) 11(-0.675,1.35) 12(-1.125,1.35)
  round 0.35 smd: 13(-0.25,-0.25) 13(-0.25,0.25) 13(0.25,-0.25) 13(0.25,0.25)
Top Overlay:
  region: -10,-19.01 -9,-20.51 -11,-20.51
  lines w0.2: -18.65,-18.65 -18.65,18.65 18.65,18.65 18.65,-18.65 -18.65,-18.65
Top Solder:
  region: 18.5,-18.5 -18.5,-18.5 -18.5,18.5 18.5,18.5
M15_Country_Yard:
  lines w0.1: -0.5,0 0.5,0 ; 0,-0.5 0,0.5 ; -18.9,-18.9 18.9,-18.9 18.9,18.9 -18.9,18.9 -18.9,-18.9

## SKT_IC51-755 [mm] "CLAMSHELL SOCKET 28PIN SSOP"
height 20
pads (28):
  rect 1.1x1.1 hole 0.7: 1(-6.9,3.9)
  round 1.1 hole 0.7: 2(-4.35,3.25) 3(-6.9,2.6) 4(-4.35,1.95) 5(-6.9,1.3) 6(-4.35,0.65) 7(-6.9,0) 8(-4.35,-0.65) 9(-6.9,-1.3) 10(-4.35,-1.95) 11(-6.9,-2.6) 12(-4.35,-3.25) 13(-6.9,-3.9) 14(-4.35,-4.55) 15(6.9,-4.55) 16(4.35,-3.9) 17(6.9,-3.25) 18(4.35,-2.6) 19(6.9,-1.95) 20(4.35,-1.3) 21(6.9,-0.65) 22(4.35,0) 23(6.9,0.65) 24(4.35,1.3) 25(6.9,1.95) 26(4.35,2.6) 27(6.9,3.25) 28(4.35,3.9)
Top Overlay:
  lines w0.2: -16,-5 -16,-8 16,-8 16,8 -16,8 -16,5 ; -18,-5 -18,5 -8,5 -8,-5 -18,-5

## SKT_IC51-755.KS-13330 [mm] "CLAMSHELL SOCKET 28PIN SSOP; Yamaichi - IC51-755.KS-13330"
height 20
pads (28):
  rect 0.9x2 hole 0.7: 1(-3.9,-6.89)
  oval 0.9x2 hole 0.7: 2(-3.25,-4.35) 3(-2.6,-6.89) 4(-1.95,-4.35) 5(-1.3,-6.89) 6(-0.65,-4.35) 7(0,-6.89) 8(0.65,-4.35) 9(1.3,-6.89) 10(1.95,-4.35) 11(2.6,-6.89) 12(3.25,-4.35) 13(3.9,-6.89) 14(4.55,-4.35) 15(4.55,6.89) 16(3.9,4.35) 17(3.25,6.89) 18(2.6,4.35) 19(1.95,6.89) 20(1.3,4.35) 21(0.65,6.89) 22(0,4.35) 23(-0.65,6.89) 24(-1.3,4.35) 25(-1.95,6.89) 26(-2.6,4.35) 27(-3.25,6.89) 28(-3.9,4.35)
Top Overlay:
  lines w0.2: -5,-16 -8,-16 -8,16 8,16 8,-16 5,-16 ; -5,-18 -5,-8 5,-8 5,-18 -5,-18
M15_Country_Yard:
  lines w0.1: -8,16 -8,26 8,26 8,16 ; -0.5,0 0.5,0 ; 0,-0.5 0,0.5

## SKT_LQFP-64_FPQ-64-0.5-06 [mm] "Test & Burn socket for LQFP-64, 0.5mm pitch, 10x10mm body. Enplas FPQ-64-0.5-06"
height 16
pads (68):
  round 5 hole 4.1: 0(-12,-11.5) 0(-12,11.5) 0(12,-11.5) 0(12,11.5)
  rect 0.9x1.7 hole 0.7: 1(-3.751,-11.582)
  oval 0.9x1.7 hole 0.7: 2(-3.251,-9.042) 3(-2.751,-6.502) 4(-2.251,-11.582) 5(-1.751,-9.042) 6(-1.251,-6.502) 7(-0.751,-11.582) 8(-0.251,-9.042) 9(0.249,-6.502) 10(0.749,-11.582) 11(1.249,-9.042) 12(1.749,-6.502) 13(2.249,-11.582) 14(2.749,-9.042) 15(3.249,-6.502) 16(3.749,-11.582) 33(3.749,11.582) 34(3.249,9.042) 35(2.749,6.502) 36(2.249,11.582) 37(1.749,9.042) 38(1.249,6.502) 39(0.749,11.582) 40(0.249,9.042) 41(-0.251,6.502) 42(-0.751,11.582) 43(-1.251,9.042) 44(-1.751,6.502) 45(-2.251,11.582) 46(-2.751,9.042) 47(-3.251,6.502) 48(-3.751,11.582)
  oval 1.7x0.9 hole 0.7: 17(11.582,-3.751) 18(9.042,-3.251) 19(6.502,-2.751) 20(11.582,-2.251) 21(9.042,-1.751) 22(6.502,-1.251) 23(11.582,-0.751) 24(9.042,-0.251) 25(6.502,0.249) 26(11.582,0.749) 27(9.042,1.249) 28(6.502,1.749) 29(11.582,2.249) 30(9.042,2.749) 31(6.502,3.249) 32(11.582,3.749) 49(-11.583,3.749) 50(-9.043,3.249) 51(-6.503,2.749) 52(-11.583,2.249) 53(-9.043,1.749) 54(-6.503,1.249) 55(-11.583,0.749) 56(-9.043,0.249) 57(-6.503,-0.251) 58(-11.583,-0.751) 59(-9.043,-1.251) 60(-6.503,-1.751) 61(-11.583,-2.251) 62(-9.043,-2.751) 63(-6.503,-3.251) 64(-11.583,-3.751)
Top Overlay:
  lines w0.2: -7.501,-21.25 -7.501,-23.24 7.499,-23.24 7.499,-21.25 ; -16.5,-21.25 16.5,-21.25 16.5,21.25 -16.5,21.25 -16.5,-21.25
M13_Assembly_Info:
  lines w0.1: -16.5,-21.25 16.5,-21.25 16.5,21.25 -16.5,21.25 -16.5,-21.25
M15_Country_Yard:
  lines w0.1: -16.74,21.51 16.75,21.51 ; -0.5,0 0.5,0 ; 0,-0.5 0,0.5 ; -16.74,-23.48 16.75,-23.48 16.75,-21 16.75,21.25 16.75,29.3 -16.74,29.3 -16.74,21.25 -16.74,-21.01 -16.74,-23.48

## SKT_OTQ-64-0.4-01_TQFP-64 [mm] "Test & Burn socket for TQFP-64 package"
height 19
pads (66):
  round 1.6 hole 1.6 unplated: 0(-11,-6.5) 0(11,6.5)
  rect 0.9x1.4 hole 0.7: 1(-3,-5.05)
  oval 0.9x1.4 hole 0.7: 2(-2.6,-6.85) 3(-2.2,-8.65) 4(-1.8,-10.45) 5(-1.4,-5.05) 6(-1,-6.85) 7(-0.6,-8.65) 8(-0.2,-10.45) 9(0.2,-5.05) 10(0.6,-6.85) 11(1,-8.65) 12(1.4,-10.45) 13(1.8,-5.05) 14(2.2,-6.85) 15(2.6,-8.65) 16(3,-10.45) 33(3,5.05) 34(2.6,6.85) 35(2.2,8.65) 36(1.8,10.45) 37(1.4,5.05) 38(1,6.85) 39(0.6,8.65) 40(0.2,10.45) 41(-0.2,5.05) 42(-0.6,6.85) 43(-1,8.65) 44(-1.4,10.45) 45(-1.8,5.05) 46(-2.2,6.85) 47(-2.6,8.65) 48(-3,10.45)
  oval 1.4x0.9 hole 0.7: 17(5.05,-3) 18(6.85,-2.6) 19(8.65,-2.2) 20(10.45,-1.8) 21(5.05,-1.4) 22(6.85,-1) 23(8.65,-0.6) 24(10.45,-0.2) 25(5.05,0.2) 26(6.85,0.6) 27(8.65,1) 28(10.45,1.4) 29(5.05,1.8) 30(6.85,2.2) 31(8.65,2.6) 32(10.45,3) 49(-5.05,3) 50(-6.85,2.6) 51(-8.65,2.2) 52(-10.45,1.8) 53(-5.05,1.4) 54(-6.85,1) 55(-8.65,0.6) 56(-10.45,0.2) 57(-5.05,-0.2) 58(-6.85,-0.6) 59(-8.65,-1) 60(-10.45,-1.4) 61(-5.05,-1.8) 62(-6.85,-2.2) 63(-8.65,-2.6) 64(-10.45,-3)
Top Overlay:
  region: -7.98,-12.28 -8.98,-13.28 -6.98,-13.28
  lines w0.2: -12,-10.96 -10.96,-12 10.8,-12 ccw(c10.8,-10.8) 12,-10.8 12,10.8 ccw(c10.8,10.8) 10.8,12 -10.8,12 ccw(c-10.8,10.8) -12,10.8 -12,-10.96
M15_Country_Yard:
  lines w0.1: -0.5,0 0.5,0 ; 0,-0.5 0,0.5 ; -12.23,-12.25 12.26,-12.25 12.26,12.24 -12.23,12.24 -12.23,-12.25

## SKT_OTQ-64-0.5-01_LQFP64_10x10 [mm] "http://wvshare.com/product/OTQ-64-0.5-01.htm"
height 16
pads (68):
  round 1.6 hole 1.6 unplated: 0(-7,-11.5) 0(-7,11.5) 0(6.5,-11) 0(7,11.5)
  rect 0.8x1.5 hole 0.7: 1(-3.75,-7.7)
  oval 0.8x1.5 hole 0.7: 2(-3.25,-5.7) 3(-2.75,-9.7) 4(-2.25,-7.7) 5(-1.75,-5.7) 6(-1.25,-9.7) 7(-0.75,-7.7) 8(-0.25,-5.7) 9(0.25,-9.7) 10(0.75,-7.7) 11(1.25,-5.7) 12(1.75,-9.7) 13(2.25,-7.7) 14(2.75,-5.7) 15(3.25,-9.7) 16(3.75,-7.7) 33(3.75,7.7) 34(3.25,5.7) 35(2.75,9.7) 36(2.25,7.7) 37(1.75,5.7) 38(1.25,9.7) 39(0.75,7.7) 40(0.25,5.7) 41(-0.25,9.7) 42(-0.75,7.7) 43(-1.25,5.7) 44(-1.75,9.7) 45(-2.25,7.7) 46(-2.75,5.7) 47(-3.25,9.7) 48(-3.75,7.7)
  oval 1.5x0.8 hole 0.7: 17(7.7,-3.75) 18(5.7,-3.25) 19(9.7,-2.75) 20(7.7,-2.25) 21(5.7,-1.75) 22(9.7,-1.25) 23(7.7,-0.75) 24(5.7,-0.25) 25(9.7,0.25) 26(7.7,0.75) 27(5.7,1.25) 28(9.7,1.75) 29(7.7,2.25) 30(5.7,2.75) 31(9.7,3.25) 32(7.7,3.75) 49(-7.7,3.75) 50(-5.7,3.25) 51(-9.7,2.75) 52(-7.7,2.25) 53(-5.7,1.75) 54(-9.7,1.25) 55(-7.7,0.75) 56(-5.7,0.25) 57(-9.7,-0.25) 58(-7.7,-0.75) 59(-5.7,-1.25) 60(-9.7,-1.75) 61(-7.7,-2.25) 62(-5.7,-2.75) 63(-9.7,-3.25) 64(-7.7,-3.75)
Top Overlay:
  region: -10,-13.99 -11,-14.99 -9,-14.99
  lines w0.2: -13.5,-12.5 -13.5,12.51 cw(c-12.51,12.51) -12.51,13.5 12.51,13.5 cw(c12.51,12.51) 13.5,12.51 13.5,-12.51 cw(c12.51,-12.51) 12.51,-13.5 -12.5,-13.5 cw(c-12.5,-12.51) -13.49,-12.51
M15_Country_Yard:
  lines w0.1: -0.5,0 0.5,0 ; 0,-0.5 0,0.5 ; -13.75,-13.75 -13.75,13.75 13.75,13.75 13.75,13.35 13.75,-13.75 -13.75,-13.75
3D body: height 16, standoff 0, extent -5,-5 5,5
3D body: height 16, standoff 0, extent -13.5,-13.5 13.5,13.5

## SKT_QFN-16_3x3P0.5_SRM LL Sht Kelvin Contactor [mm] "Test Socket for QFN-16; 3x3mm package; 0.5mm pitch; SRM LL Sht Kelvin Contactor"
height 18
pads (46):
  round 2.2 hole 2.2 unplated: 0(-7.8,-7.8) 0(-7.8,7.8) 0(7.8,-7.8) 0(7.8,7.8)
  round 1.05 hole 1.05 unplated: 0(-5.83,-3.75) 0(-5.83,3.25) 0(-3.75,5.83) 0(-3.25,-5.83) 0(3.25,5.83) 0(3.75,-5.83) 0(5.83,-3.25) 0(5.83,3.75)
  round 1.55 hole 1.55 unplated: 0(-5.3,7.8) 0(5.3,-7.8)
  rect 1x0.3 smd: 1(11.49,-0.75) 1(12.89,-0.75) 2(11.49,-0.25) 2(12.89,-0.25) 3(11.49,0.25) 3(12.89,0.25) 4(11.49,0.75) 4(12.89,0.75) 9(-12.89,0.75) 9(-11.49,0.75) 10(-12.89,0.25) 10(-11.49,0.25) 11(-12.89,-0.25) 11(-11.49,-0.25) 12(-12.89,-0.75) 12(-11.49,-0.75)
  rect 0.3x1 smd: 5(0.75,11.49) 5(0.75,12.89) 6(0.25,11.49) 6(0.25,12.89) 7(-0.25,11.49) 7(-0.25,12.89) 8(-0.75,11.49) 8(-0.75,12.89) 13(-0.75,-12.89) 13(-0.75,-11.49) 14(-0.25,-12.89) 14(-0.25,-11.49) 15(0.25,-12.89) 15(0.25,-11.49) 16(0.75,-12.89) 16(0.75,-11.49)
Mechanical 1:
  lines w0.1: -4.3,-3.36 -4.3,3.3 cw(c-3.3,3.3) -3.3,4.3 3.3,4.3 cw(c3.3,3.3) 4.3,3.3 4.3,-3.3 cw(c3.3,-3.3) 3.3,-4.3 -3.3,-4.3 cw(c-3.3,-3.3) -4.3,-3.3
  text "PCB Cutout" at -3.19,0.2 h0.8
  text "area" at -3.19,-0.85 h0.8
M15_Country_Yard:
  lines w0.1: -4.3,0 4.3,0 ; -3.75,0 0,0 ; 0,-4.3 0,4.3 ; 0,-3.75 0,0 ; 0,3.75 0,0 ; 3.75,0 0,0 ; 0,0 3.7,0 -3.7,0 0,0 ; 0,0 0,3.7 0,-3.7 0,0 ; -9.5,-8.5 ccw(c-8.5,-8.5) -8.5,-9.5 -3.1,-9.5 ccw(c-3.1,-8.5) -2.1,-8.5 -2.1,-4.7 cw(c-1.1,-4.7) -1.1,-3.7 1.1,-3.7 cw(c1.1,-4.7) 2.1,-4.7 2.1,-8.5 ccw(c3.1,-8.5) 3.1,-9.5 8.5,-9.5 ccw(c8.5,-8.5) 9.5,-8.5 9.5,-3.1 ccw(c8.5,-3.1) 8.5,-2.1 4.7,-2.1 cw(c4.7,-1.1) 3.7,-1.1 3.7,1.1 cw(c4.7,1.1) 4.7,2.1 8.5,2.1 ccw(c8.5,3.1) 9.5,3.1 9.5,8.5 ccw(c8.5,8.5) 8.5,9.5 3.1,9.5 ccw(c3.1,8.5) 2.1,8.5 2.1,4.7 cw(c1.1,4.7) 1.1,3.7 -1.1,3.7 cw(c-1.1,4.7) -2.1,4.7 -2.1,8.5 ccw(c-3.1,8.5) -3.1,9.5 -8.5,9.5 ccw(c-8.5,8.5) -9.5,8.5 -9.5,3.1 ccw(c-8.5,3.1) -8.5,2.1 -4.7,2.1 cw(c-4.7,1.1) -3.7,1.1 -3.7,-1.1 cw(c-4.7,-1.1) -4.7,-2.1 -8.5,-2.1 ccw(c-8.5,-3.1) -9.5,-3.1 -9.5,-8.5

## SKT_QFN-16_4x4_P0.65_2050-SA4416C01S [mm] "Tai-Chen Precision Inc. QFN-16 4x4mm body; 0.65mm pitch; Test Socket; 2050-SA4416C01S"
height 6.6
pads (32):
  round 1.6 hole 1.6 unplated: 0(-17,-17) 0(-17,17) 0(-9,-9) 0(-9,9) 0(9,-9) 0(9,9) 0(17,-17) 0(17,17)
  round 6.5 hole 4.1: 0(-13.2,-13.2) 0(-13.2,13.2) 0(13.2,-13.2) 0(13.2,13.2)
  rect 1.2x0.35 smd: 1(-2.1,0.97)
  oval 1.2x0.35 smd: 2(-2.1,0.32) 3(-2.1,-0.33) 4(-2.1,-0.98) 9(2.1,-0.98) 10(2.1,-0.33) 11(2.1,0.32) 12(2.1,0.97)
  oval 0.35x1.2 smd: 5(-0.98,-2.1) 6(-0.33,-2.1) 7(0.32,-2.1) 8(0.97,-2.1) 13(0.97,2.1) 14(0.32,2.1) 15(-0.33,2.1) 16(-0.98,2.1)
  round 0.35 smd: 17(-0.25,-0.25) 17(-0.25,0.25) 17(0.25,-0.25) 17(0.25,0.25)
Top Layer:
  pour cut-out: 18.75,18.75 18.75,-18.75 -18.75,-18.75 -18.75,17.69 -17.69,18.75
Top Overlay:
  region: -19,5 -20.5,4 -20.5,6
  lines w0.2: -18.65,-18.65 18.65,-18.65 18.65,18.65 -17.65,18.65 -18.65,17.65 -18.65,-18.65
Top Solder:
  region: -18.55,-18.55 -18.55,17.61 -17.61,18.55 18.55,18.55 18.55,-18.55
M15_Country_Yard:
  lines w0.1: -0.5,0 0.5,0 ; 0,-0.5 0,0.5

## SKT_QFN-16_03714 171 X218F_Loranger [mm] "Test&Burn In Socket for QFN-16; 3x3mm package; 0.5mm pitch; Loranger part No. 03714 171 X218F"
height 18
pads (17):
  rect 0.65x1 hole 0.5: 1(0.75,1.625)
  oval 0.65x1 hole 0.5: 2(0.25,3.535) 3(-0.25,1.625) 4(-0.75,3.535) 9(-0.75,-1.625) 10(-0.25,-3.535) 11(0.25,-1.625) 12(0.75,-3.535)
  oval 1x0.65 hole 0.5: 5(-1.625,0.75) 6(-3.535,0.25) 7(-1.625,-0.25) 8(-3.535,-0.75) 13(1.625,-0.75) 14(3.535,-0.25) 15(1.625,0.25) 16(3.535,0.75)
  round 1.2 hole 0.8: 17(0,0)
Top Overlay:
  region: 2.54,9.615 1.54,10.615 3.54,10.615
  lines w0.2: -4.45,-9.66 -4.45,-10.96 4.45,-10.96 4.45,-9.66 ; -7.6,-9.65 7.6,-9.65 7.6,9.65 -7.6,9.65 -7.6,-9.65
M15_Country_Yard:
  lines w0.1: -0.5,0 0.5,0 ; 0,-0.5 0,0.5

## SKT_QFN-20_4x4_P0.5_2050-SA4420QN01 [mm] "Tai-Chen Precision Inc. QFN-20 4x4mm body; 0.5mm pitch; Test Socket; 2050-SA4420QN01"
height 6.6
pads (36):
  round 1.6 hole 1.6 unplated: 0(-17,-17) 0(-17,17) 0(-9,-9) 0(-9,9) 0(9,-9) 0(9,9) 0(17,-17) 0(17,17)
  round 6.5 hole 4.1: 0(-13.2,-13.2) 0(-13.2,13.2) 0(13.2,-13.2) 0(13.2,13.2)
  rect 1.2x0.35 smd: 1(-2.1,1)
  oval 1.2x0.35 smd: 2(-2.1,0.5) 3(-2.1,0) 4(-2.1,-0.5) 5(-2.1,-1) 11(2.1,-1) 12(2.1,-0.5) 13(2.1,0) 14(2.1,0.5) 15(2.1,1)
  oval 0.35x1.2 smd: 6(-1,-2.1) 7(-0.5,-2.1) 8(0,-2.1) 9(0.5,-2.1) 10(1,-2.1) 16(1,2.1) 17(0.5,2.1) 18(0,2.1) 19(-0.5,2.1) 20(-1,2.1)
  round 0.35 smd: 21(-0.25,-0.25) 21(-0.25,0.25) 21(0.25,-0.25) 21(0.25,0.25)
Top Layer:
  pour cut-out: -18.75,-18.75 -18.75,17.725 -17.725,18.75 18.75,18.75 18.75,-18.75
Top Overlay:
  region: -19,5 -20.5,4 -20.5,6
  lines w0.2: -18.65,-18.65 -18.65,17.65 -17.65,18.65 18.65,18.65 18.65,-18.65 -18.65,-18.65
Top Solder:
  region: -18.55,-18.55 -18.55,17.61 -17.61,18.55 18.55,18.55 18.55,-18.55
M15_Country_Yard:
  lines w0.1: -0.5,0 0.5,0 ; 0,-0.5 0,0.5

## SKT_QFN-24_4x4_P0.5_2050-SA4424QN01 [mm] "Tai-Chen Precision Inc. QFN-24 4x4mm body; 0.5mm pitch; Test Socket; 2050-SA4424QN01"
height 6.6
pads (40):
  round 1.6 hole 1.6 unplated: 0(-17,-17) 0(-17,17) 0(-9,-9) 0(-9,9) 0(9,-9) 0(9,9) 0(17,-17) 0(17,17)
  round 6.5 hole 4.1: 0(-13.2,-13.2) 0(-13.2,13.2) 0(13.2,-13.2) 0(13.2,13.2)
  rect 1.2x0.35 smd: 1(-2.1,1.25)
  oval 1.2x0.35 smd: 2(-2.1,0.75) 3(-2.1,0.25) 4(-2.1,-0.25) 5(-2.1,-0.75) 6(-2.1,-1.25) 13(2.1,-1.25) 14(2.1,-0.75) 15(2.1,-0.25) 16(2.1,0.25) 17(2.1,0.75) 18(2.1,1.25)
  oval 0.35x1.2 smd: 7(-1.25,-2.1) 8(-0.75,-2.1) 9(-0.25,-2.1) 10(0.25,-2.1) 11(0.75,-2.1) 12(1.25,-2.1) 19(1.25,2.1) 20(0.75,2.1) 21(0.25,2.1) 22(-0.25,2.1) 23(-0.75,2.1) 24(-1.25,2.1)
  round 0.35 smd: 25(-0.25,-0.25) 25(-0.25,0.25) 25(0.25,-0.25) 25(0.25,0.25)
Top Layer:
  pour cut-out: -18.75,-18.75 -18.75,17.725 -17.725,18.75 18.75,18.75 18.75,-18.75
  lines w0.2: -2.1,1.25 -2.1,1.25
Top Overlay:
  region: -19,5 -20.5,4 -20.5,6
  lines w0.2: -18.65,-18.65 -18.65,17.65 -17.65,18.65 18.65,18.65 18.65,-18.65 -18.65,-18.65
Top Solder:
  region: -18.55,-18.55 -18.55,17.61 -17.61,18.55 18.55,18.55 18.55,-18.55
M15_Country_Yard:
  lines w0.1: -0.5,0 0.5,0 ; 0,-0.5 0,0.5

## SKT_QFN-28_4x4P0.4_SRM LL Sht Kelvin Contactor [mm] "Test Socket for QFN-28; 4x4mm package; 0.4mm pitch; SRM LL Sht Kelvin Contactor"
height 18
pads (70):
  round 2.2 hole 2.2 unplated: 0(-7.8,-7.8) 0(-7.8,7.8) 0(7.8,-7.8) 0(7.8,7.8)
  round 1.55 hole 1.55 unplated: 0(-5.3,7.8) 0(5.3,-7.8)
  round 1.05 hole 1.05 unplated: 0(-4.85,-2.7) 0(-4.85,2.3) 0(-2.7,4.85) 0(-2.3,-4.85) 0(2.3,4.85) 0(2.7,-4.85) 0(4.85,-2.3) 0(4.85,2.7)
  rect 1x0.225 smd: 1(7.84,-1.2) 1(9.24,-1.2) 2(7.84,-0.8) 2(9.24,-0.8) 3(7.84,-0.4) 3(9.24,-0.4) 4(7.84,0) 4(9.24,0) 5(7.84,0.4) 5(9.24,0.4) 6(7.84,0.8) 6(9.24,0.8) 7(7.84,1.2) 7(9.24,1.2) 15(-9.24,1.2) 15(-7.84,1.2) 16(-9.24,0.8) 16(-7.84,0.8) 17(-9.24,0.4) 17(-7.84,0.4) 18(-9.24,0) 18(-7.84,0) 19(-9.24,-0.4) 19(-7.84,-0.4) 20(-9.24,-0.8) 20(-7.84,-0.8) 21(-9.24,-1.2) 21(-7.84,-1.2)
  rect 0.225x1 smd: 8(1.2,9.24) 8(1.2,7.84) 9(0.8,9.24) 9(0.8,7.84) 10(0.4,9.24) 10(0.4,7.84) 11(0,9.24) 11(0,7.84) 12(-0.4,9.24) 12(-0.4,7.84) 13(-0.8,9.24) 13(-0.8,7.84) 14(-1.2,9.24) 14(-1.2,7.84) 22(-1.2,-7.84) 22(-1.2,-9.24) 23(-0.8,-7.84) 23(-0.8,-9.24) 24(-0.4,-7.84) 24(-0.4,-9.24) 25(0,-7.84) 25(0,-9.24) 26(0.4,-7.84) 26(0.4,-9.24) 27(0.8,-7.84) 27(0.8,-9.24) 28(1.2,-7.84) 28(1.2,-9.24)
Mechanical 1:
  lines w0.1: -3.5,-2.5 ccw(c-2.5,-2.5) -2.5,-3.5 2.5,-3.5 ccw(c2.5,-2.5) 3.5,-2.5 3.5,2.5 ccw(c2.5,2.5) 2.5,3.5 -2.5,3.5 ccw(c-2.5,2.5) -3.5,2.5 -3.5,-2.5
  text "PCB Cutout" at -3.15,0.72 h0.8
  text "area" at -3.15,-0.33 h0.8
M15_Country_Yard:
  lines w0.1: -3.5,0 3.5,0 ; 0,-3.5 0,3.5 ; -9.5,-8.5 ccw(c-8.5,-8.5) -8.5,-9.5 -2.5,-9.5 ccw(c-2.5,-8.5) -1.5,-8.5 -1.5,-6.2 cw(c0,-6.2) 1.5,-6.2 1.5,-8.5 ccw(c2.5,-8.5) 2.5,-9.5 8.5,-9.5 ccw(c8.5,-8.5) 9.5,-8.5 9.5,-2.5 ccw(c8.5,-2.5) 8.5,-1.5 6.2,-1.5 cw(c6.2,0) 6.2,1.5 8.5,1.5 ccw(c8.5,2.5) 9.5,2.5 9.5,8.5 ccw(c8.5,8.5) 8.5,9.5 2.5,9.5 ccw(c2.5,8.5) 1.5,8.5 1.5,6.2 cw(c0,6.2) -1.5,6.2 -1.5,8.5 ccw(c-2.5,8.5) -2.5,9.5 -8.5,9.5 ccw(c-8.5,8.5) -9.5,8.5 -9.5,2.5 ccw(c-8.5,2.5) -8.5,1.5 -6.2,1.5 cw(c-6.2,0) -6.2,-1.5 -8.5,-1.5 ccw(c-8.5,-2.5) -9.5,-2.5 -9.5,-8.5

## SKT_QFN-28_03940 291 X217_Loranger [mm] "Test&Burn In Socket for QFN-28; 4x4mm package; 0.4mm pitch; Loranger part No. 03940 291 X217"
height 18
pads (29):
  rect 0.65x1 hole 0.5: 1(1.2,3.55)
  oval 0.65x1 hole 0.5: 2(0.8,2.03) 3(0.4,3.55) 4(0,2.03) 5(-0.4,3.55) 6(-0.8,2.03) 7(-1.2,3.55) 15(-1.2,-3.55) 16(-0.8,-2.03) 17(-0.4,-3.55) 18(0,-2.03) 19(0.4,-3.55) 20(0.8,-2.03) 21(1.2,-3.55)
  oval 1x0.65 hole 0.5: 8(-3.55,1.2) 9(-2.03,0.8) 10(-3.55,0.4) 11(-2.03,0) 12(-3.55,-0.4) 13(-2.03,-0.8) 14(-3.55,-1.2) 22(3.55,-1.2) 23(2.03,-0.8) 24(3.55,-0.4) 25(2.03,0) 26(3.55,0.4) 27(2.03,0.8) 28(3.55,1.2)
  round 1.2 hole 0.8: 29(0,0)
Top Overlay:
  region: 2.54,9.13 1.54,10.13 3.54,10.13
  lines w0.2: -4.45,-9.15 -4.45,-10.45 4.45,-10.45 4.45,-9.15 ; -7.6,-9.15 7.6,-9.15 7.6,9.15 -7.6,9.15 -7.6,-9.15
M15_Country_Yard:
  lines w0.1: -0.5,0 0.5,0 ; 0,-0.5 0,0.5

## SKT_QFN-32_5x5_P0.5_2050-SA5532QN01 [mm] "Tai-Chen Precision Inc. QFN-32 5x5mm body; 0.5mm pitch; Test Socket; 2050-SA5532QN01"
height 6.6
pads (48):
  round 1.6 hole 1.6 unplated: 0(-17,-17) 0(-17,17) 0(-9,-9) 0(-9,9) 0(9,-9) 0(9,9) 0(17,-17) 0(17,17)
  round 6.5 hole 4.1: 0(-13.2,-13.2) 0(-13.2,13.2) 0(13.2,-13.2) 0(13.2,13.2)
  oval 1.2x0.35 smd: 1(-2.6,1.75) 2(-2.6,1.25) 3(-2.6,0.75) 4(-2.6,0.25) 5(-2.6,-0.25) 6(-2.6,-0.75) 7(-2.6,-1.25) 8(-2.6,-1.75) 17(2.6,-1.75) 18(2.6,-1.25) 19(2.6,-0.75) 20(2.6,-0.25) 21(2.6,0.25) 22(2.6,0.75) 23(2.6,1.25) 24(2.6,1.75)
  oval 0.35x1.2 smd: 9(-1.75,-2.6) 10(-1.25,-2.6) 11(-0.75,-2.6) 12(-0.25,-2.6) 13(0.25,-2.6) 14(0.75,-2.6) 15(1.25,-2.6) 16(1.75,-2.6) 25(1.75,2.61) 26(1.25,2.61) 27(0.75,2.61) 28(0.25,2.61) 29(-0.25,2.61) 30(-0.75,2.61) 31(-1.25,2.61) 32(-1.75,2.61)
  round 0.35 smd: 33(-0.25,-0.25) 33(-0.25,0.25) 33(0.25,-0.25) 33(0.25,0.25)
Top Layer:
  pour cut-out: -18.75,-18.75 -18.75,17.725 -17.725,18.75 18.75,18.75 18.75,-18.75
Top Overlay:
  region: -19,5 -20.5,4 -20.5,6
  lines w0.2: -18.65,-18.65 -18.65,17.65 -17.65,18.65 18.65,18.65 18.65,-18.65 -18.65,-18.65
Top Solder:
  region: -18.55,-18.55 -18.55,17.61 -17.61,18.55 18.55,18.55 18.55,-18.55
M15_Country_Yard:
  lines w0.1: -0.5,0 0.5,0 ; 0,-0.5 0,0.5

## SKT_QFN-32_6.0x6.0mm-0.5-pitch [mm] "Load Board Socket for QFN-32; 6.0x6.0mm-0.5mm-pitch; Johnstech; Pad ROL(tm)200 series JTI-LBD-32-QFN-6.0X6.0-0.50"
height 5.5
pads (41):
  round 1.61 hole 1.61 unplated: 0(-17,-17) 0(17,17)
  round 1.85 hole 1.85 unplated: 0(-17,17) 0(17,-17)
  round 6.35 hole 4.5: 0(-12.7,-12.7) 0(-12.7,12.7) 0(12.7,-12.7) 0(12.7,12.7)
  oval 0.356x1.1 smd: 1(-1.75,-4.5) 2(-1.25,-4.5) 3(-0.75,-4.5) 4(-0.25,-4.5) 5(0.25,-4.5) 6(0.75,-4.5) 7(1.25,-4.5) 8(1.75,-4.5) 17(1.75,4.5) 18(1.25,4.5) 19(0.75,4.5) 20(0.25,4.5) 21(-0.25,4.5) 22(-0.75,4.5) 23(-1.25,4.5) 24(-1.75,4.5)
  oval 1.1x0.356 smd: 9(4.5,-1.75) 10(4.5,-1.25) 11(4.5,-0.75) 12(4.5,-0.25) 13(4.5,0.25) 14(4.5,0.75) 15(4.5,1.25) 16(4.5,1.75) 25(-4.5,1.75) 26(-4.5,1.25) 27(-4.5,0.75) 28(-4.5,0.25) 29(-4.5,-0.25) 30(-4.5,-0.75) 31(-4.5,-1.25) 32(-4.5,-1.75)
  rect 5.45x5.45 smd: 33(0,0)
Top Layer:
  pour cut-out: -19.049,-19.05 -14.478,-19.05 -4.47,-9.042 -4.292,-8.763 -4.249,-8.482 -4.249,-6.745 -4.19,-6.477 -4.038,-6.223 -3.784,-6.045 -3.505,-6 3.48,-6 3.48,-6.03 3.785,-6.096 4.039,-6.248 4.192,-6.502 4.251,-6.8 4.251,-8.821 14.479,-19.05 19.051,-19.05 19.051,-14.479 9.556,-4.984 9.055,-4.483 8.814,-4.293 8.489,-4.249 6.8,-4.25 6.502,-4.191 6.325,-4.089 6.172,-3.937 6.071,-3.81 6,-3.45 6,3.607 6.172,3.937 6.375,4.115 6.528,4.191 6.8,4.25 8.484,4.25 8.814,4.293 9.049,4.484 9.22,4.623 19.051,14.48 19.051,19.05 14.479,19.05 4.481,9.052 4.319,8.788 4.251,8.482 4.251,7.3 4.242,7.061 4.25,6.8 4.14,6.401 3.937,6.198 3.658,6.045 3.454,6 -3.454,6 -3.759,6.071 -3.962,6.172 -4.115,6.35 -4.242,6.604 -4.25,6.883 -4.249,7.3 -4.249,8.482 -4.292,8.788 -4.483,9.055 -14.478,19.05 -19.049,19.05 -19.049,14.479 -9.052,4.481 -8.788,4.293 -8.483,4.25 -6.799,4.25 -6.451,4.166 -6.172,3.988 -6.019,3.708 -5.999,3.429 -5.999,-3.45 -6.045,-3.734 -6.197,-3.988 -6.476,-4.166 -6.799,-4.25 -8.483,-4.25 -8.839,-4.343 -9.048,-4.484 -19.049,-14.479
Top Overlay:
  region: -5.56,-19.3 -4.06,-20.8 -7.06,-20.8
  lines w0.2: -19.2,-14.13 -19.2,14.195 ; -14.205,19.2 14.12,19.2 ; -14.13,-19.2 14.02,-19.2 ; 19.2,-14.03 19.2,14.12
Top Solder:
  region: -19.075,19.05 -14.503,19.05 -4.877,9.398 -4.42,8.966 -4.343,8.763 -4.301,8.533 -4.301,6.851 -4.267,6.629 -4.216,6.477 -4.013,6.223 -3.81,6.096 -3.505,6.051 3.404,6.051 3.658,6.071 3.861,6.198 4.089,6.401 4.191,6.629 4.216,7.188 4.216,8.407 4.242,8.611 4.293,8.788 4.369,8.941 4.47,9.093 14.453,19.05 19.025,19.05 19.025,14.478 9.296,4.75 9.049,4.484 8.814,4.318 8.484,4.25 6.8,4.25 6.401,4.14 6.147,3.962 6,3.607 6,-3.45 6.071,-3.785 6.248,-4.013 6.452,-4.166 6.8,-4.25 8.489,-4.249 8.788,-4.293 9.055,-4.483 9.271,-4.75 19.025,-14.503 19.025,-19.05 14.478,-19.05 14.453,-19.075 4.216,-8.839 4.216,-6.756 4.115,-6.426 3.962,-6.172 3.759,-6.045 3.454,-5.994 -3.505,-5.994 -3.912,-6.096 -4.216,-6.426 -4.267,-6.756 -4.267,-8.839 -14.503,-19.075 -14.529,-19.05 -19.101,-19.05 -19.101,-14.529 -9.042,-4.47 -8.839,-4.318 -8.661,-4.267 -8.484,-4.242 -6.833,-4.242 -6.579,-4.191 -6.426,-4.115 -6.274,-4.013 -6.071,-3.734 -6.045,3.556 -6.172,3.785 -6.274,3.912 -6.452,4.089 -6.579,4.191 -6.68,4.242 -6.883,4.267 -8.865,4.267 -19.075,14.478
  lines w0.1: -9.067,4.496 -19.05,14.479 -19.05,19.05 -14.479,19.05 -4.48,9.052 ; -9.049,-4.484 cw(c-8.483,-5.05) -8.483,-4.25 ; -9.049,-4.478 -19.05,-14.479 -19.05,-19.05 -14.479,-19.05 -4.48,-9.052 ; -9.049,4.484 ccw(c-8.484,5.05) -8.484,4.25 -6.8,4.25 cw(c-6.8,3.45) -6,3.45 -6,-3.531 ; -8.476,-4.25 -6.8,-4.25 ccw(c-6.8,-3.45) -6,-3.45 ; -4.484,-9.048 ccw(c-5.05,-8.482) -4.25,-8.482 -4.25,-6.792 ; -4.484,9.048 cw(c-5.05,8.482) -4.25,8.482 -4.25,6.8 ccw(c-3.45,6.8) -3.45,6 ; -4.25,-6.8 cw(c-3.45,-6.8) -3.45,-6 ; -3.531,-6 3.454,-6 ; -3.454,6 3.454,6 ; 3.45,-6 cw(c3.45,-6.8) 4.25,-6.8 4.25,-8.49 ccw(c5.05,-8.49) 4.484,-9.056 14.479,-19.05 19.05,-19.05 19.05,-14.479 9.055,-4.483 ccw(c8.489,-5.049) 8.489,-4.249 6.782,-4.25 ; 3.45,6 ccw(c3.45,6.8) 4.25,6.8 ; 4.25,7.3 4.25,8.482 cw(c5.05,8.482) 4.484,9.048 ; 4.48,9.052 14.479,19.05 19.05,19.05 19.05,14.48 9.052,4.482 ; 6,3.45 cw(c6.8,3.45) 6.8,4.25 8.484,4.25 ccw(c8.484,5.05) 9.049,4.484 ; 6,3.607 6,-3.45 ccw(c6.8,-3.45) 6.8,-4.25
M13_Assembly_Info:
  lines w0.1: -9.052,-4.481 -19.05,-14.479 -19.05,-19.05 -14.479,-19.05 -4.471,-9.042 ; -9.052,4.481 -19.05,14.479 -19.05,19.05 -14.479,19.05 -4.483,9.055 ; -9.049,-4.484 cw(c-8.483,-5.05) -8.483,-4.25 ; -9.049,4.484 ccw(c-8.484,5.05) -8.484,4.25 -6.8,4.25 cw(c-6.8,3.45) -6,3.45 -6,-3.45 cw(c-6.8,-3.45) -6.8,-4.25 -8.476,-4.25 ; -4.484,-9.048 ccw(c-5.05,-8.482) -4.25,-8.482 -4.25,-6.792 ; -4.484,9.048 cw(c-5.05,8.482) -4.25,8.482 -4.25,6.8 ccw(c-3.45,6.8) -3.45,6 ; -4.25,-6.8 cw(c-3.45,-6.8) -3.45,-6 ; -3.505,-6 3.48,-6 ; -3.454,6 3.454,6 ; 3.45,-6 cw(c3.45,-6.8) 4.25,-6.8 4.25,-8.49 ccw(c5.05,-8.49) 4.484,-9.056 14.479,-19.05 19.05,-19.05 19.05,-14.479 9.055,-4.483 ccw(c8.489,-5.049) 8.489,-4.249 6.8,-4.25 cw(c6.8,-3.45) 6,-3.45 6,3.607 ; 3.45,6 ccw(c3.45,6.8) 4.25,6.8 4.25,8.482 cw(c5.05,8.482) 4.484,9.048 ; 4.48,9.052 14.479,19.05 19.05,19.05 19.05,14.48 9.064,4.494 ; 6,3.45 cw(c6.8,3.45) 6.8,4.25 8.484,4.25 ccw(c8.484,5.05) 9.049,4.484
M15_Country_Yard:
  lines w0.1: -0.5,0 0.5,0 ; 0,-0.5 0,0.5

## SKT_QFN-32_7.0x7.0-0.65 [mm] "Load Board Socket for QFN-32; 7.0 x 7.0mm; 0.65mm pitch; Johnstech; Pad ROL(tm)200 series Production Test Contactor"
height 5.5
pads (52):
  round 6.35 hole 4: 0(-12.7,-12.7) 0(-12.7,12.7) 0(12.7,-12.7) 0(12.7,12.7)
  round 1.65 hole 1.65 unplated: 1(-17,-17) 2(17,17)
  oval 0.356x1.07 smd: 1(-2.275,-4.985) 2(-1.625,-4.985) 3(-0.975,-4.985) 4(-0.325,-4.985) 5(0.325,-4.985) 6(0.975,-4.985) 7(1.625,-4.985) 8(2.275,-4.985) 17(2.275,4.98) 18(1.625,4.98) 19(0.975,4.98) 20(0.325,4.98) 21(-0.325,4.98) 22(-0.975,4.98) 23(-1.625,4.98) 24(-2.275,4.98)
  round 1.85 hole 1.85 unplated: 3(17,-17) 4(-17,17)
  oval 1.07x0.356 smd: 9(4.98,-2.275) 10(4.98,-1.625) 11(4.98,-0.975) 12(4.98,-0.325) 13(4.98,0.325) 14(4.98,0.975) 15(4.98,1.625) 16(4.98,2.275) 25(-4.98,2.275) 26(-4.98,1.625) 27(-4.98,0.975) 28(-4.98,0.325) 29(-4.98,-0.325) 30(-4.98,-0.975) 31(-4.98,-1.625) 32(-4.98,-2.275)
  rect 0.36x0.8 smd: 33(-1.25,-2.25) 33(-1.25,2.25) 33(-0.75,-2.25) 33(-0.75,2.25) 33(-0.25,-2.25) 33(-0.25,2.25) 33(0.25,-2.25) 33(0.25,2.25) 33(0.75,-2.25) 33(0.75,2.25) 33(1.25,-2.25) 33(1.25,2.25)
Top Layer:
  pour cut-out: -19.05,-19.05 -19.05,-14.48 -11.13,-6.545 -10.62,-6.045 -10.09,-5.595 -9.385,-5.54 -8.65,-5.545 -7.21,-5.54 -6.94,-5.465 -6.695,-5.295 -6.56,-5.065 -6.495,-4.825 -6.495,4.885 -6.59,5.125 -6.735,5.345 -6.94,5.475 -7.165,5.555 -9.765,5.555 -10.105,5.61 -10.38,5.82 -10.65,6.095 -11.205,6.64 -12.365,7.81 -14.6,10.035 -19.045,14.485 -19.045,19.06 -14.48,19.06 -10.02,14.605 -7.76,12.35 -6.65,11.235 -5.8,10.385 -5.595,10.08 -5.545,9.86 -5.54,9.48 -5.545,7.275 -5.485,6.98 -5.31,6.71 -5.05,6.56 -4.77,6.5 4.8,6.5 4.8,6.505 5.075,6.57 5.325,6.71 5.49,6.98 5.56,7.265 5.555,8.71 5.55,9.45 5.55,9.83 5.605,10.135 5.82,10.415 6.1,10.69 6.67,11.255 7.805,12.375 10.025,14.605 14.48,19.055 19.05,19.055 19.05,14.48 14.605,10.03 12.36,7.79 11.245,6.68 10.68,6.11 10.395,5.825 10.26,5.7 10.11,5.605 9.94,5.57 9.765,5.55 9.4,5.555 7.265,5.555 6.965,5.485 6.715,5.315 6.565,5.065 6.505,4.795 6.505,-4.78 6.51,-4.78 6.56,-5.05 6.72,-5.31 6.965,-5.47 7.275,-5.545 9.81,-5.545 10.12,-5.6 10.395,-5.81 10.685,-6.1 11.25,-6.67 12.365,-7.785 14.6,-10.015 19.055,-14.475 19.055,-19.045 14.485,-19.045 10.015,-14.565 7.76,-12.325 6.64,-11.21 6.075,-10.645 5.78,-10.345 5.6,-10.08 5.55,-9.73 5.555,-9.355 5.555,-8.62 5.55,-7.17 5.46,-6.91 5.305,-6.695 5.095,-6.565 4.875,-6.495 -4.825,-6.495 -5.09,-6.58 -5.325,-6.73 -5.48,-6.965 -5.545,-7.215 -5.545,-8.655 -5.54,-9.41 -5.545,-9.785 -5.6,-10.095 -5.785,-10.375 -6.065,-10.655 -6.645,-11.225 -7.775,-12.335 -10.04,-14.585 -14.48,-19.05
Top Overlay:
  region: -5.73,-19.87 -4.73,-21.37 -6.73,-21.37
  lines w0.2: -19.05,-19.05 19.05,-19.05 19.05,19.05 -19.05,19.05 -19.05,-19.05
Top Solder:
  drawing of 49 lines, arcs and shapes, not listed
M13_Assembly_Info:
  lines w0.1: 19.05,14.479 19.05,19.05 14.479,19.05 5.784,10.356 ccw(c6.35,9.79) 5.55,9.79 5.55,7.3 cw(c4.75,7.3) 4.75,6.5 -4.75,6.5 cw(c-4.75,7.3) -5.55,7.3 -5.55,9.79 ccw(c-6.35,9.79) -5.784,10.356 -14.479,19.05 -19.05,19.05 -19.05,14.479 -10.356,5.784 ccw(c-9.79,6.35) -9.79,5.55 -7.3,5.55 cw(c-7.3,4.75) -6.5,4.75 -6.5,-4.75 cw(c-7.3,-4.75) -7.3,-5.55 -9.79,-5.55 ccw(c-9.79,-6.35) -10.356,-5.784 -19.05,-14.479 -19.05,-19.05 -14.479,-19.05 -5.784,-10.356 ccw(c-6.35,-9.79) -5.55,-9.79 -5.55,-7.3 cw(c-4.75,-7.3) -4.75,-6.5 4.75,-6.5 cw(c4.75,-7.3) 5.55,-7.3 5.55,-9.79 ccw(c6.35,-9.79) 5.784,-10.356 14.479,-19.05 19.05,-19.05 19.05,-14.479 10.356,-5.784 ccw(c9.79,-6.35) 9.79,-5.55 7.3,-5.55 cw(c7.3,-4.75) 6.5,-4.75 6.5,4.75 cw(c7.3,4.75) 7.3,5.55 9.79,5.55 ccw(c9.79,6.35) 10.356,5.784 19.05,14.48 ; -3.75,-3.75 3.75,-3.75 3.75,3.75 -3.75,3.75 -3.75,-3.75
M15_Country_Yard:
  lines w0.1: -0.5,0 0.5,0 ; 0,-0.5 0,0.5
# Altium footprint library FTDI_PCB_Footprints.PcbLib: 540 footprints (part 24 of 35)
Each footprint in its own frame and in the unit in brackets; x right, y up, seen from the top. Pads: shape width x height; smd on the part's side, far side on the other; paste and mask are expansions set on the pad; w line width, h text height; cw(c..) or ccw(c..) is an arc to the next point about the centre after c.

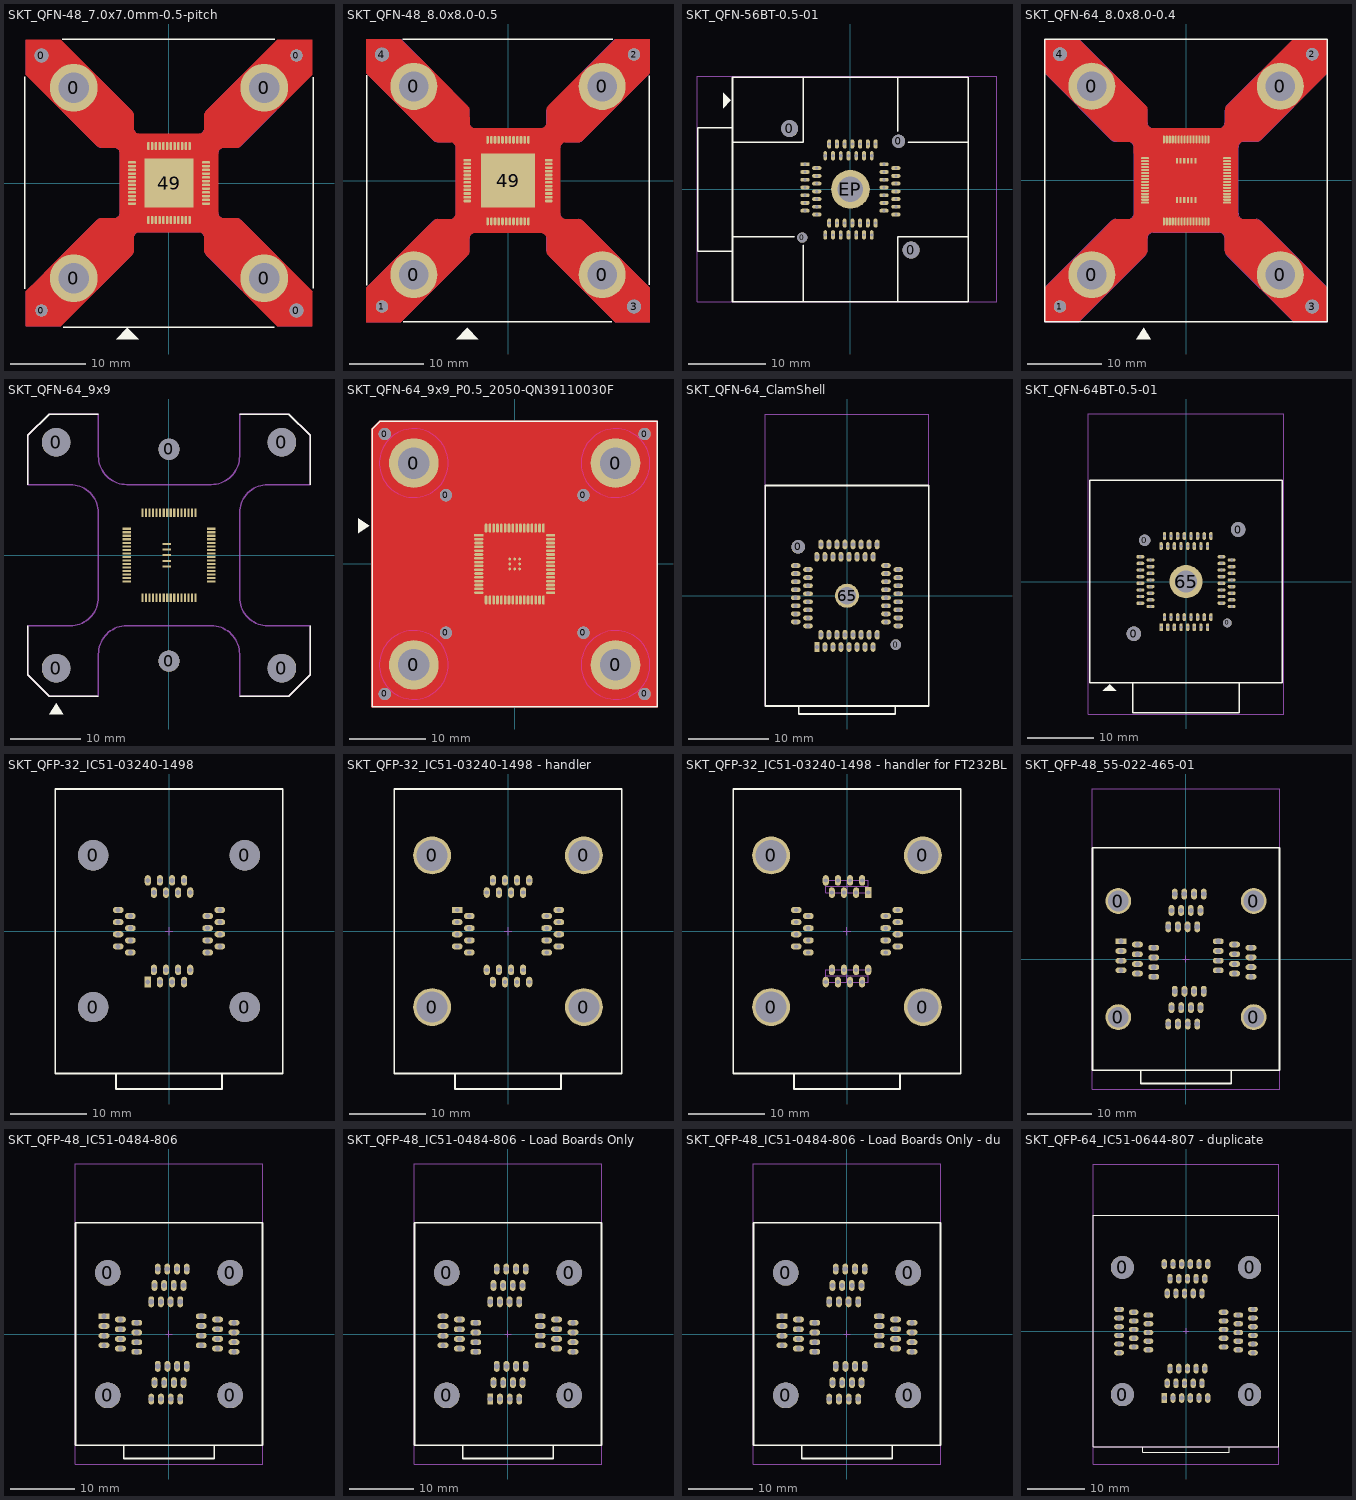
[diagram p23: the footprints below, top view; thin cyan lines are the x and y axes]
## SKT_QFN-48_7.0x7.0mm-0.5-pitch [mm] "Load Board Socket for QFN-48; 7.0x7.0mm-0.5mm-pitch; Johnstech; Pad ROL(tm)200 series JTI-TS-48-QFN-7.0X7.0-0.50-7884-0201;"
height 5.5
pads (57):
  round 1.61 hole 1.61 unplated: 0(-17,-17) 0(17,17)
  round 1.85 hole 1.85 unplated: 0(-17,17) 0(17,-17)
  round 6.35 hole 4.1: 0(-12.7,-12.7) 0(-12.7,12.7) 0(12.7,-12.7) 0(12.7,12.7)
  oval 0.356x1.1 smd: 1(-2.75,-4.94) 2(-2.25,-4.94) 3(-1.75,-4.94) 4(-1.25,-4.94) 5(-0.75,-4.94) 6(-0.25,-4.94) 7(0.25,-4.94) 8(0.75,-4.94) 9(1.25,-4.94) 10(1.75,-4.94) 11(2.25,-4.94) 12(2.75,-4.94) 25(2.75,4.94) 26(2.25,4.94) 27(1.75,4.94) 28(1.25,4.94) 29(0.75,4.94) 30(0.25,4.94) 31(-0.25,4.94) 32(-0.75,4.94) 33(-1.25,4.94) 34(-1.75,4.94) 35(-2.25,4.94) 36(-2.75,4.94)
  oval 1.1x0.356 smd: 13(4.94,-2.75) 14(4.94,-2.25) 15(4.94,-1.75) 16(4.94,-1.25) 17(4.94,-0.75) 18(4.94,-0.25) 19(4.94,0.25) 20(4.94,0.75) 21(4.94,1.25) 22(4.94,1.75) 23(4.94,2.25) 24(4.94,2.75) 37(-4.94,2.75) 38(-4.94,2.25) 39(-4.94,1.75) 40(-4.94,1.25) 41(-4.94,0.75) 42(-4.94,0.25) 43(-4.94,-0.25) 44(-4.94,-0.75) 45(-4.94,-1.25) 46(-4.94,-1.75) 47(-4.94,-2.25) 48(-4.94,-2.75)
  rect 6.5x6.5 smd: 49(0,0)
Top Layer:
  pour cut-out: 191 vertices and 0 holes, not listed, extent -19.1,-19.1 19.1,19.1
Top Overlay:
  region: -5.56,-19.3 -4.06,-20.8 -7.06,-20.8
  lines w0.2: -19.2,-14.13 -19.2,14.195 ; -14.205,19.2 14.12,19.2 ; -14.13,-19.2 14.02,-19.2 ; 19.2,-14.03 19.2,14.12
Top Solder:
  region: -19.05,-19.05 -14.479,-19.05 -9.871,-14.443 -7.52,-12.08 -6.165,-10.736 -4.984,-9.556 -4.82,-9.31 -4.75,-8.99 -4.75,-7.3 -4.7,-6.97 -4.52,-6.72 -4.28,-6.57 -3.95,-6.5 3.95,-6.5 4.31,-6.58 4.56,-6.77 4.71,-7.01 4.75,-7.3 4.75,-8.99 4.83,-9.32 4.984,-9.556 14.479,-19.05 19.05,-19.05 19.05,-14.479 10.056,-5.484 9.82,-5.26 9.556,-4.984 9.29,-4.81 8.99,-4.75 7.3,-4.75 6.99,-4.7 6.73,-4.52 6.55,-4.26 6.5,-3.95 6.5,3.95 6.55,4.21 6.67,4.46 6.93,4.68 7.3,4.75 8.99,4.75 9.31,4.81 9.556,4.984 9.71,5.14 9.84,5.27 10.056,5.486 10.864,6.294 12.09,7.56 14.38,9.85 19.05,14.48 19.05,19.05 14.479,19.05 5.25,9.821 4.984,9.556 4.77,9.22 4.75,8.99 4.75,7.96 4.75,7.3 4.7,7 4.55,6.76 4.28,6.57 3.95,6.5 -3.95,6.5 -4.33,6.55 -4.55,6.75 -4.68,6.96 -4.76,7.06 -4.75,7.3 -4.75,7.84 -4.75,8.99 -4.82,9.31 -4.984,9.556 -5.28,9.83 -5.484,10.056 -14.479,19.05 -19.05,19.05 -19.05,14.479 -9.56,4.989 -9.3,4.81 -8.99,4.75 -7.3,4.75 -6.93,4.67 -6.69,4.49 -6.55,4.24 -6.5,3.95 -6.5,-3.95 -6.55,-4.26 -6.71,-4.5 -6.96,-4.7 -7.3,-4.75 -8.99,-4.75 -9.29,-4.81 -9.556,-4.984 -19.05,-14.479
  lines w0.1: -19.05,-19.05 -19.05,-14.479 -9.556,-4.984 cw(c-8.99,-5.55) -8.99,-4.75 -7.3,-4.75 ccw(c-7.3,-3.95) -6.5,-3.95 -6.5,3.95 ccw(c-7.3,3.95) -7.3,4.75 -8.99,4.75 cw(c-8.99,5.55) -9.556,4.984 -19.05,14.479 -19.05,19.05 -14.479,19.05 -4.984,9.556 cw(c-5.55,8.99) -4.75,8.99 -4.75,7.3 ccw(c-3.95,7.3) -3.95,6.5 3.95,6.5 ccw(c3.95,7.3) 4.75,7.3 4.75,8.99 cw(c5.55,8.99) 4.984,9.556 14.479,19.05 19.05,19.05 19.05,14.48 9.555,4.985 cw(c8.99,5.55) 8.99,4.75 7.3,4.75 ccw(c7.3,3.95) 6.5,3.95 6.5,-3.95 ccw(c7.3,-3.95) 7.3,-4.75 8.99,-4.75 cw(c8.99,-5.55) 9.556,-4.984 19.05,-14.479 19.05,-19.05 14.479,-19.05 4.984,-9.556 cw(c5.55,-8.99) 4.75,-8.99 4.75,-7.3 ccw(c3.95,-7.3) 3.95,-6.5 -3.95,-6.5 ccw(c-3.95,-7.3) -4.75,-7.3 -4.75,-8.99 cw(c-5.55,-8.99) -4.984,-9.556 -14.479,-19.05 -19.05,-19.05
M13_Assembly_Info:
  lines w0.1: -19.05,-19.05 -14.479,-19.05 -4.984,-9.556 ccw(c-5.55,-8.99) -4.75,-8.99 -4.75,-7.3 cw(c-3.95,-7.3) -3.95,-6.5 3.95,-6.5 cw(c3.95,-7.3) 4.75,-7.3 4.75,-8.99 ccw(c5.55,-8.99) 4.984,-9.556 14.479,-19.05 19.05,-19.05 19.05,-14.479 9.556,-4.984 ccw(c8.99,-5.55) 8.99,-4.75 7.3,-4.75 cw(c7.3,-3.95) 6.5,-3.95 6.5,3.95 cw(c7.3,3.95) 7.3,4.75 8.99,4.75 ccw(c8.99,5.55) 9.556,4.984 19.05,14.48 19.05,19.05 14.479,19.05 4.984,9.556 ccw(c5.55,8.99) 4.75,8.99 4.75,7.3 cw(c3.95,7.3) 3.95,6.5 -3.95,6.5 cw(c-3.95,7.3) -4.75,7.3 -4.75,8.99 ccw(c-5.55,8.99) -4.984,9.556 -14.479,19.05 -19.05,19.05 -19.05,14.479 -9.556,4.984 ccw(c-8.99,5.55) -8.99,4.75 -7.3,4.75 cw(c-7.3,3.95) -6.5,3.95 -6.5,-3.95 cw(c-7.3,-3.95) -7.3,-4.75 -8.99,-4.75 ccw(c-8.99,-5.55) -9.556,-4.984 -19.05,-14.479 -19.05,-19.05
M15_Country_Yard:
  lines w0.1: -0.5,0 0.5,0 ; 0,-0.5 0,0.5

## SKT_QFN-48_8.0x8.0-0.5 [mm] "Load Board Socket for QFN-48; 8.0 x 8.0mm; 0.5mm pitch; Johnstech; Pad ROL(tm)200 series JTI-48-QFN-8.0X8.0-0.50-6022; Production Test Contactor"
height 5.5
pads (69):
  round 6.35 hole 4: 0(-12.7,-12.7) 0(-12.7,12.7) 0(12.7,-12.7) 0(12.7,12.7)
  round 1.65 hole 1.65 unplated: 1(-17,-17) 2(17,17)
  oval 0.356x1.07 smd: 1(-2.75,-5.5) 2(-2.25,-5.5) 3(-1.75,-5.5) 4(-1.25,-5.5) 5(-0.75,-5.5) 6(-0.25,-5.5) 7(0.25,-5.5) 8(0.75,-5.5) 9(1.25,-5.5) 10(1.75,-5.5) 11(2.25,-5.5) 12(2.75,-5.5) 25(2.75,5.5) 26(2.25,5.5) 27(1.75,5.5) 28(1.25,5.5) 29(0.75,5.5) 30(0.25,5.5) 31(-0.25,5.5) 32(-0.75,5.5) 33(-1.25,5.5) 34(-1.75,5.5) 35(-2.25,5.5) 36(-2.75,5.5)
  round 1.85 hole 1.85 unplated: 3(17,-17) 4(-17,17)
  oval 1.07x0.356 smd: 13(5.5,-2.75) 14(5.5,-2.25) 15(5.5,-1.75) 16(5.5,-1.25) 17(5.5,-0.75) 18(5.5,-0.25) 19(5.5,0.25) 20(5.5,0.75) 21(5.5,1.25) 22(5.5,1.75) 23(5.5,2.25) 24(5.5,2.75) 37(-5.5,2.75) 38(-5.5,2.25) 39(-5.5,1.75) 40(-5.5,1.25) 41(-5.5,0.75) 42(-5.5,0.25) 43(-5.5,-0.25) 44(-5.5,-0.75) 45(-5.5,-1.25) 46(-5.5,-1.75) 47(-5.5,-2.25) 48(-5.5,-2.75)
  rect 0.36x0.8 smd: 49(-1.25,-2.65) 49(-1.25,2.65) 49(-0.75,-2.65) 49(-0.75,2.65) 49(-0.25,-2.65) 49(-0.25,2.65) 49(0.25,-2.65) 49(0.25,2.65) 49(0.75,-2.65) 49(0.75,2.65) 49(1.25,-2.65) 49(1.25,2.65)
  rect 7.3x7.3 smd: 49(0,0)
Top Layer:
  pour cut-out: -19.1,19.1 -14.45,19.1 -9.825,14.475 -5.25,9.83 -5.175,7.55 -4.95,7.25 -4.725,7.1 -4.475,7.05 4.475,7.05 4.7,7.1 4.875,7.2 4.95,7.25 4.975,7.275 5.075,7.4 5.175,7.6 5.2,7.75 5.2,9.55 5.225,9.7 5.25,9.8 5.3,9.9 5.375,10 5.425,10.075 5.475,10.125 5.575,10.225 14.45,19.1 19.1,19.1 19.1,14.45 10.05,5.4 9.975,5.35 9.9,5.3 9.85,5.275 9.65,5.2 7.775,5.2 7.55,5.15 7.425,5.1 7.375,5.075 7.225,4.925 7.175,4.85 7.125,4.775 7.1,4.725 7.075,4.65 7.05,4.55 7.05,-4.475 7.075,-4.625 7.1,-4.725 7.15,-4.825 7.2,-4.9 7.3,-5 7.425,-5.1 7.5,-5.125 7.6,-5.175 7.75,-5.2 9.5,-5.2 9.7,-5.225 9.775,-5.25 9.85,-5.275 9.95,-5.325 10.1,-5.45 19.1,-14.45 19.1,-19.1 14.45,-19.1 14.425,-19.075 5.425,-10.075 5.3,-9.9 5.25,-9.775 5.225,-9.7 5.2,-9.65 5.2,-7.7 5.175,-7.6 5.15,-7.55 5.125,-7.475 5.1,-7.425 5.05,-7.35 4.9,-7.2 4.8,-7.15 4.725,-7.1 4.65,-7.075 4.525,-7.05 -4.5,-7.05 -4.675,-7.1 -4.75,-7.125 -4.825,-7.15 -4.875,-7.2 -4.925,-7.225 -5.025,-7.325 -5.075,-7.4 -5.125,-7.475 -5.15,-7.55 -5.175,-7.625 -5.2,-7.725 -5.2,-9.525 -5.25,-9.8 -5.35,-10 -14.45,-19.1 -19.1,-19.1 -19.1,-14.45 -12.325,-7.675 -11.15,-6.5 -9.975,-5.35 -9.875,-5.275 -9.775,-5.25 -9.675,-5.2 -7.7,-5.2 -7.475,-5.125 -7.275,-4.975 -7.125,-4.75 -7.05,-4.475 -7.05,4.125 -7.075,4.6 -7.25,4.95 -7.6,5.175 -8.425,5.2 -9.5,5.2 -9.7,5.225 -9.875,5.275 -10.025,5.375 -11.9,7.25 -12.5,7.85 -15.8,11.15 -17.45,12.8 -19.1,14.45
Top Overlay:
  region: -5.5,-19.875 -4,-21.375 -7,-21.375
  lines w0.2: -19.05,-14.125 -19.05,14.2 ; -14.2,19.05 14.125,19.05 ; -14.125,-19.05 14.025,-19.05 ; 19.05,-14.025 19.05,14.125
Top Solder:
  region: -19.05,-19.05 -14.479,-19.05 -9.871,-14.443 -7.52,-12.08 -6.165,-10.736 -5.484,-10.056 -5.28,-9.8 -5.24,-9.55 -5.25,-9.3 -5.25,-7.8 -5.21,-7.49 -5.02,-7.24 -4.77,-7.04 -4.45,-7 4.45,-7 4.81,-7.05 5.05,-7.2 5.21,-7.48 5.25,-7.8 5.25,-9.49 5.3,-9.81 5.484,-10.056 14.479,-19.05 19.05,-19.05 19.05,-14.479 10.056,-5.484 9.8,-5.3 9.49,-5.25 7.8,-5.25 7.51,-5.19 7.26,-5.03 7.06,-4.77 7,-4.45 7,4.45 7.06,4.77 7.24,5.04 7.49,5.2 7.8,5.25 8.795,5.27 9.34,5.25 9.58,5.25 9.82,5.3 10.056,5.486 10.864,6.294 12.09,7.56 14.38,9.85 19.05,14.48 19.05,19.05 14.479,19.05 5.25,9.821 5.25,7.8 5.16,7.49 5.01,7.24 4.74,7.07 4.45,7 -4.45,7 -4.76,7.06 -5.04,7.23 -5.18,7.47 -5.25,7.8 -5.25,9.49 -5.32,9.81 -5.484,10.056 -14.479,19.05 -19.05,19.05 -19.05,14.479 -9.821,5.25 -7.8,5.25 -7.48,5.18 -7.22,4.99 -7.06,4.74 -7,4.45 -7,-4.45 -7.08,-4.78 -7.25,-5.04 -7.51,-5.18 -7.8,-5.25 -9.49,-5.25 -9.78,-5.3 -10.056,-5.484 -19.05,-14.479
  lines w0.1: -19.05,-19.05 -14.479,-19.05 -5.484,-10.056 ccw(c-6.05,-9.49) -5.25,-9.49 -5.25,-7.8 cw(c-4.45,-7.8) -4.45,-7 4.45,-7 cw(c4.45,-7.8) 5.25,-7.8 5.25,-9.49 ccw(c6.05,-9.49) 5.484,-10.056 14.479,-19.05 19.05,-19.05 19.05,-14.479 10.056,-5.484 ccw(c9.49,-6.05) 9.49,-5.25 7.8,-5.25 cw(c7.8,-4.45) 7,-4.45 7,4.45 cw(c7.8,4.45) 7.8,5.25 9.49,5.25 ccw(c9.49,6.05) 10.056,5.484 10.056,5.486 19.05,14.48 19.05,19.05 14.479,19.05 5.484,10.056 ccw(c6.05,9.49) 5.25,9.49 5.25,7.8 cw(c4.45,7.8) 4.45,7 -4.45,7 cw(c-4.45,7.8) -5.25,7.8 -5.25,9.49 ccw(c-6.05,9.49) -5.484,10.056 -14.479,19.05 -19.05,19.05 -19.05,14.479 -10.056,5.484 ccw(c-9.49,6.05) -9.49,5.25 -7.8,5.25 cw(c-7.8,4.45) -7,4.45 -7,-4.45 cw(c-7.8,-4.45) -7.8,-5.25 -9.49,-5.25 ccw(c-9.49,-6.05) -10.056,-5.484 -19.05,-14.479 -19.05,-19.05 ; -4,-4 -4,4 4,4 4,-4 -4,-4
M13_Assembly_Info:
  lines w0.1: -19.05,-19.05 -19.05,-14.479 -10.056,-5.484 cw(c-9.49,-6.05) -9.49,-5.25 -7.8,-5.25 ccw(c-7.8,-4.45) -7,-4.45 -7,4.45 ccw(c-7.8,4.45) -7.8,5.25 -9.49,5.25 cw(c-9.49,6.05) -10.056,5.484 -19.05,14.479 -19.05,19.05 -14.479,19.05 -5.484,10.056 cw(c-6.05,9.49) -5.25,9.49 -5.25,7.8 ccw(c-4.45,7.8) -4.45,7 4.45,7 ccw(c4.45,7.8) 5.25,7.8 5.25,9.49 cw(c6.05,9.49) 5.484,10.056 14.479,19.05 19.05,19.05 19.05,14.48 10.056,5.486 10.056,5.484 cw(c9.49,6.05) 9.49,5.25 7.8,5.25 ccw(c7.8,4.45) 7,4.45 7,-4.45 ccw(c7.8,-4.45) 7.8,-5.25 9.49,-5.25 cw(c9.49,-6.05) 10.056,-5.484 19.05,-14.479 19.05,-19.05 14.479,-19.05 5.484,-10.056 cw(c6.05,-9.49) 5.25,-9.49 5.25,-7.8 ccw(c4.45,-7.8) 4.45,-7 -4.45,-7 ccw(c-4.45,-7.8) -5.25,-7.8 -5.25,-9.49 cw(c-6.05,-9.49) -5.484,-10.056 -14.479,-19.05 -19.05,-19.05 ; -4,-4 4,-4 4,4 -4,4 -4,-4
M15_Country_Yard:
  lines w0.1: -0.5,0 0.5,0 ; 0,-0.5 0,0.5

## SKT_QFN-56BT-0.5-01 [mm] "QFN-56BT-0.5-01 clamshell socket for QFN56 8X8 0.5MM"
height 18.9
pads (61):
  round 2.2 hole 2.2: 0(-7.85,7.85) 0(7.85,-7.85)
  round 1.32 hole 1.32 unplated: 0(-6.225,-6.225)
  round 1.7 hole 1.7: 0(6.225,6.225)
  rect 1.2x0.5 hole 0.41: 1(-5.875,3.25)
  oval 1.2x0.5 hole 0.41: 2(-4.35,2.75) 3(-5.875,2.25) 4(-4.35,1.75) 5(-5.875,1.25) 6(-4.35,0.75) 7(-5.875,0.25) 8(-4.35,-0.25) 9(-5.875,-0.75) 10(-4.35,-1.25) 11(-5.875,-1.75) 12(-4.35,-2.25) 13(-5.875,-2.75) 14(-4.35,-3.25) 29(5.875,-3.25) 30(4.35,-2.75) 31(5.875,-2.25) 32(4.35,-1.75) 33(5.875,-1.25) 34(4.35,-0.75) 35(5.875,-0.25) 36(4.35,0.25) 37(5.875,0.75) 38(4.35,1.25) 39(5.875,1.75) 40(4.35,2.25) 41(5.875,2.75) 42(4.35,3.25)
  oval 0.5x1.2 hole 0.41: 15(-3.25,-5.875) 16(-2.75,-4.35) 17(-2.25,-5.875) 18(-1.75,-4.35) 19(-1.25,-5.875) 20(-0.75,-4.35) 21(-0.25,-5.875) 22(0.25,-4.35) 23(0.75,-5.875) 24(1.25,-4.35) 25(1.75,-5.875) 26(2.25,-4.35) 27(2.75,-5.875) 28(3.25,-4.35) 43(3.25,5.875) 44(2.75,4.35) 45(2.25,5.875) 46(1.75,4.35) 47(1.25,5.875) 48(0.75,4.35) 49(0.25,5.875) 50(-0.25,4.35) 51(-0.75,5.875) 52(-1.25,4.35) 53(-1.75,5.875) 54(-2.25,4.35) 55(-2.75,5.875) 56(-3.25,4.35)
  round 5 hole 3.3: EP(0,0)
Top Overlay:
  region: -15.45,11.51 -16.45,12.51 -16.45,10.51
  lines w0.2: -15.25,-8 -19.75,-8 -19.75,8 -15.25,8 ; -15.25,-6.1 -7.25,-6.1 ; -15.25,6.1 -6.1,6.1 -6.1,14.5 ; -6.1,-14.5 -6.1,-7.25 ; 6.1,-14.5 6.1,-6.1 15.25,-6.1 ; 6.1,7.5 6.1,14.5 ; 7.5,6.1 15.25,6.1 ; -15.25,-14.5 -15.25,14.5 15.25,14.5 15.25,-14.5 -15.25,-14.5
M15_Country_Yard:
  lines w0.1: -19.837,-14.5 -19.837,14.605 18.948,14.605 18.948,-14.5 -19.837,-14.5

## SKT_QFN-64_8.0x8.0-0.4 [mm] "Load Board Socket for QFN-64; 8.0 x 8.0mm; 0.4mm pitch; Johnstech; Pad ROL(tm)200 series Production Test Contactor"
height 5.5
pads (84):
  round 6.35 hole 4: 0(-12.7,-12.7) 0(-12.7,12.7) 0(12.7,-12.7) 0(12.7,12.7)
  round 1.65 hole 1.65 unplated: 1(-17,-17) 2(17,17)
  oval 0.279x1.07 smd: 1(-3,-5.525) 2(-2.6,-5.525) 3(-2.2,-5.525) 4(-1.8,-5.525) 5(-1.4,-5.525) 6(-1,-5.525) 7(-0.6,-5.525) 8(-0.2,-5.525) 9(0.2,-5.525) 10(0.6,-5.525) 11(1,-5.525) 12(1.4,-5.525) 13(1.8,-5.525) 14(2.2,-5.525) 15(2.6,-5.525) 16(3,-5.525) 33(3,5.525) 34(2.6,5.525) 35(2.2,5.525) 36(1.8,5.525) 37(1.4,5.525) 38(1,5.525) 39(0.6,5.525) 40(0.2,5.525) 41(-0.2,5.525) 42(-0.6,5.525) 43(-1,5.525) 44(-1.4,5.525) 45(-1.8,5.525) 46(-2.2,5.525) 47(-2.6,5.525) 48(-3,5.525)
  round 1.85 hole 1.85 unplated: 3(17,-17) 4(-17,17)
  oval 1.07x0.279 smd: 17(5.525,-3) 18(5.525,-2.6) 19(5.525,-2.2) 20(5.525,-1.8) 21(5.525,-1.4) 22(5.525,-1) 23(5.525,-0.6) 24(5.525,-0.2) 25(5.525,0.2) 26(5.525,0.6) 27(5.525,1) 28(5.525,1.4) 29(5.525,1.8) 30(5.525,2.2) 31(5.525,2.6) 32(5.525,3) 49(-5.525,3) 50(-5.525,2.6) 51(-5.525,2.2) 52(-5.525,1.8) 53(-5.525,1.4) 54(-5.525,1) 55(-5.525,0.6) 56(-5.525,0.2) 57(-5.525,-0.2) 58(-5.525,-0.6) 59(-5.525,-1) 60(-5.525,-1.4) 61(-5.525,-1.8) 62(-5.525,-2.2) 63(-5.525,-2.6) 64(-5.525,-3)
  rect 0.28x0.8 smd: 65(-1.25,-2.65) 65(-1.25,2.65) 65(-0.75,-2.65) 65(-0.75,2.65) 65(-0.25,-2.65) 65(-0.25,2.65) 65(0.25,-2.65) 65(0.25,2.65) 65(0.75,-2.65) 65(0.75,2.65) 65(1.25,-2.65) 65(1.25,2.65)
Top Layer:
  pour cut-out: -19.05,19.06 -14.465,19.06 -14.465,19.05 -5.25,9.835 -5.25,7.52 -4.735,7.005 4.725,7.005 4.93,7.21 4.995,7.21 4.995,7.22 5.14,7.365 5.14,7.47 5.23,7.56 5.23,7.755 5.255,7.78 5.255,9.59 5.28,9.615 5.28,9.75 5.37,9.84 5.37,9.945 5.49,10.065 5.49,10.07 14.465,19.045 19.05,19.045 19.05,14.475 10.015,5.44 9.98,5.44 9.89,5.35 9.84,5.35 9.77,5.28 9.645,5.28 9.615,5.25 7.61,5.25 7.54,5.18 7.43,5.18 7.35,5.1 7.305,5.1 7.185,4.98 7.185,4.95 7.09,4.855 7.09,4.78 7.02,4.71 7.02,4.56 6.995,4.535 6.995,-4.515 7.015,-4.535 7.015,-4.675 7.055,-4.715 7.055,-4.795 7.14,-4.88 7.14,-4.92 7.37,-5.15 7.49,-5.15 7.565,-5.225 7.755,-5.225 7.785,-5.255 9.615,-5.255 9.64,-5.28 9.76,-5.28 9.82,-5.34 9.895,-5.34 10.04,-5.485 10.055,-5.485 19.045,-14.475 19.045,-19.055 18.81,-19.055 18.805,-19.06 14.48,-19.06 14.48,-19.05 5.34,-9.91 5.34,-9.83 5.3,-9.79 5.3,-9.735 5.275,-9.71 5.275,-9.64 5.25,-9.615 5.25,-9.525 5.245,-9.52 5.245,-7.72 5.23,-7.705 5.23,-7.585 5.19,-7.545 5.19,-7.465 5.135,-7.41 5.135,-7.385 5.06,-7.31 5.06,-7.285 4.975,-7.2 4.975,-7.195 4.96,-7.195 4.89,-7.125 4.86,-7.125 4.79,-7.055 4.705,-7.055 4.66,-7.01 4.54,-7.01 4.525,-6.995 -4.455,-6.995 -4.47,-7.01 -4.695,-7.01 -4.75,-7.065 -4.815,-7.065 -4.9,-7.15 -4.925,-7.15 -5.035,-7.26 -5.055,-7.26 -5.055,-7.285 -5.15,-7.38 -5.15,-7.425 -5.205,-7.48 -5.205,-7.59 -5.235,-7.62 -5.235,-7.805 -5.255,-7.825 -5.255,-9.69 -5.315,-9.75 -5.315,-9.845 -5.415,-9.945 -5.415,-9.985 -14.47,-19.04 -19.05,-19.04 -19.05,-14.455 -12.27,-7.7 -9.945,-5.39 -9.685,-5.265 -7.685,-5.245 -7.21,-5.03 -6.99,-4.495 -6.995,-2.835 -7,-0.085 -6.995,2.555 -7.02,4.655 -7.215,5 -7.595,5.23 -8.42,5.245 -9.27,5.23 -9.675,5.265 -9.985,5.41 -12.465,7.89 -19.07,14.485
Top Overlay:
  region: -5.73,-19.87 -4.73,-21.37 -6.73,-21.37
  lines w0.2: -19.05,-19.05 19.05,-19.05 19.05,19.05 -19.05,19.05 -19.05,-19.05
Top Solder:
  pour cut-out: -19.05,-19.05 -14.479,-19.05 -9.871,-14.443 -7.52,-12.08 -6.165,-10.736 -5.484,-10.056 -5.28,-9.8 -5.24,-9.55 -5.25,-9.3 -5.25,-7.8 -5.21,-7.49 -5.02,-7.24 -4.77,-7.04 -4.45,-7 4.45,-7 4.81,-7.05 5.05,-7.2 5.21,-7.48 5.25,-7.8 5.25,-9.49 5.3,-9.81 5.484,-10.056 14.479,-19.05 19.05,-19.05 19.05,-14.479 10.056,-5.484 9.8,-5.3 9.49,-5.25 7.8,-5.25 7.51,-5.19 7.26,-5.03 7.06,-4.77 7,-4.45 7,4.45 7.06,4.77 7.24,5.04 7.49,5.2 7.8,5.25 8.795,5.27 9.34,5.25 9.58,5.25 9.82,5.3 10.056,5.486 10.864,6.294 12.09,7.56 14.38,9.85 19.05,14.48 19.05,19.05 14.479,19.05 5.25,9.821 5.25,7.8 5.16,7.49 5.01,7.24 4.74,7.07 4.45,7 -4.45,7 -4.76,7.06 -5.04,7.23 -5.18,7.47 -5.25,7.8 -5.25,9.49 -5.32,9.81 -5.484,10.056 -14.479,19.05 -19.05,19.05 -19.05,14.479 -9.821,5.25 -7.8,5.25 -7.48,5.18 -7.22,4.99 -7.06,4.74 -7,4.45 -7,-4.45 -7.08,-4.78 -7.25,-5.04 -7.51,-5.18 -7.8,-5.25 -9.49,-5.25 -9.78,-5.3 -10.056,-5.484 -19.05,-14.479
M13_Assembly_Info:
  lines w0.1: -19.05,-19.05 -14.479,-19.05 -5.484,-10.056 ccw(c-6.05,-9.49) -5.25,-9.49 -5.25,-7.8 cw(c-4.45,-7.8) -4.45,-7 4.45,-7 cw(c4.45,-7.8) 5.25,-7.8 5.25,-9.49 ccw(c6.05,-9.49) 5.484,-10.056 14.479,-19.05 19.05,-19.05 19.05,-14.479 10.056,-5.484 ccw(c9.49,-6.05) 9.49,-5.25 7.8,-5.25 cw(c7.8,-4.45) 7,-4.45 7,4.45 cw(c7.8,4.45) 7.8,5.25 9.49,5.25 ccw(c9.49,6.05) 10.056,5.484 10.056,5.486 19.05,14.48 19.05,19.05 14.479,19.05 5.484,10.056 ccw(c6.05,9.49) 5.25,9.49 5.25,7.8 cw(c4.45,7.8) 4.45,7 -4.45,7 cw(c-4.45,7.8) -5.25,7.8 -5.25,9.49 ccw(c-6.05,9.49) -5.484,10.056 -14.479,19.05 -19.05,19.05 -19.05,14.479 -10.056,5.484 ccw(c-9.49,6.05) -9.49,5.25 -7.8,5.25 cw(c-7.8,4.45) -7,4.45 -7,-4.45 cw(c-7.8,-4.45) -7.8,-5.25 -9.49,-5.25 ccw(c-9.49,-6.05) -10.056,-5.484 -19.05,-14.479 -19.05,-19.05 ; -4,-4 -4,4 4,4 4,-4 -4,-4
M15_Country_Yard:
  lines w0.1: -0.5,0 0.5,0 ; 0,-0.5 0,0.5

## SKT_QFN-64_9x9 [mm]
pads (75):
  round 4.05 hole 4.05 unplated: 0(-16,-16) 0(-16,16) 0(16,-16) 0(16,16)
  round 3 hole 3 unplated: 0(0,-15) 0(0,15)
  rect 0.3x1.2 smd: 1(-3.75,-6) 2(-3.25,-6) 3(-2.75,-6) 4(-2.25,-6) 5(-1.75,-6) 6(-1.25,-6) 7(-0.75,-6) 8(-0.25,-6) 9(0.25,-6) 10(0.75,-6) 11(1.25,-6) 12(1.75,-6) 13(2.25,-6) 14(2.75,-6) 15(3.25,-6) 16(3.75,-6) 33(3.75,6) 34(3.25,6) 35(2.75,6) 36(2.25,6) 37(1.75,6) 38(1.25,6) 39(0.75,6) 40(0.25,6) 41(-0.25,6) 42(-0.75,6) 43(-1.25,6) 44(-1.75,6) 45(-2.25,6) 46(-2.75,6) 47(-3.25,6) 48(-3.75,6)
  rect 1.2x0.3 smd: 17(6,-3.75) 18(6,-3.25) 19(6,-2.75) 20(6,-2.25) 21(6,-1.75) 22(6,-1.25) 23(6,-0.75) 24(6,-0.25) 25(6,0.25) 26(6,0.75) 27(6,1.25) 28(6,1.75) 29(6,2.25) 30(6,2.75) 31(6,3.25) 32(6,3.75) 49(-6,3.75) 50(-6,3.25) 51(-6,2.75) 52(-6,2.25) 53(-6,1.75) 54(-6,1.25) 55(-6,0.75) 56(-6,0.25) 57(-6,-0.25) 58(-6,-0.75) 59(-6,-1.25) 60(-6,-1.75) 61(-6,-2.25) 62(-6,-2.75) 63(-6,-3.25) 64(-6,-3.75) 65(-0.3,-1.6) 65(-0.3,-0.8) 65(-0.3,0) 65(-0.3,0.8) 65(-0.3,1.6)
Top Overlay:
  region: -16,-21 -15,-22.5 -17,-22.5
  lines w0.2: -20,-10 -20,-16.975 -16.975,-20 -10,-20 ; -20,10 -20,16.975 -16.975,20 -10,20 ; 10,-20 16.975,-20 20,-16.975 20,-10 ; 10,20 16.975,20 20,16.975 20,10
M13_Assembly_Info:
  lines w0.2: 13.975,-10 20,-10 20,-16.975 16.975,-20 10,-20 10,-14 ccw(c6,-14) 6,-10 -6,-10 ccw(c-6,-14) -10,-14 -10,-20 -16.975,-20 -20,-16.975 -20,-10 -14,-10 ccw(c-14,-6) -10,-6 -10,6 ccw(c-14,6) -14,10 -20,10 -20,16.975 -16.975,20 -10,20 -10,14 ccw(c-6,14) -6,10 6,10 ccw(c6,14) 10,14 10,20 16.975,20 20,16.975 20,10 13.975,10 ; 14,-10 cw(c14,-6) 10,-6 10,6 cw(c14,6) 14,10

## SKT_QFN-64_9x9_P0.5_2050-QN39110030F [mm] "Tai-Chen Precision Inc. QFN-64 9x9mm body; 0.5mm pitch; Test Socket; 2050-QN39110030F"
height 6.6
pads (84):
  round 1.6 hole 1.6 unplated: 0(-17,-17) 0(-17,17) 0(-9,-9) 0(-9,9) 0(9,-9) 0(9,9) 0(17,-17) 0(17,17)
  round 6.5 hole 4.1: 0(-13.2,-13.2) 0(-13.2,13.2) 0(13.2,-13.2) 0(13.2,13.2)
  rect 1.2x0.35 smd: 1(-4.7,3.75)
  oval 1.2x0.35 smd: 2(-4.7,3.25) 3(-4.7,2.75) 4(-4.7,2.25) 5(-4.7,1.75) 6(-4.7,1.25) 7(-4.7,0.75) 8(-4.7,0.25) 9(-4.7,-0.25) 10(-4.7,-0.75) 11(-4.7,-1.25) 12(-4.7,-1.75) 13(-4.7,-2.25) 14(-4.7,-2.75) 15(-4.7,-3.25) 16(-4.7,-3.75) 33(4.7,-3.75) 34(4.7,-3.25) 35(4.7,-2.75) 36(4.7,-2.25) 37(4.7,-1.75) 38(4.7,-1.25) 39(4.7,-0.75) 40(4.7,-0.25) 41(4.7,0.25) 42(4.7,0.75) 43(4.7,1.25) 44(4.7,1.75) 45(4.7,2.25) 46(4.7,2.75) 47(4.7,3.25) 48(4.7,3.75)
  oval 0.35x1.2 smd: 17(-3.75,-4.7) 18(-3.25,-4.7) 19(-2.75,-4.7) 20(-2.25,-4.7) 21(-1.75,-4.7) 22(-1.25,-4.7) 23(-0.75,-4.7) 24(-0.25,-4.7) 25(0.25,-4.7) 26(0.75,-4.7) 27(1.25,-4.7) 28(1.75,-4.7) 29(2.25,-4.7) 30(2.75,-4.7) 31(3.25,-4.7) 32(3.75,-4.7) 49(3.75,4.7) 50(3.25,4.7) 51(2.75,4.7) 52(2.25,4.7) 53(1.75,4.7) 54(1.25,4.7) 55(0.75,4.7) 56(0.25,4.7) 57(-0.25,4.7) 58(-0.75,4.7) 59(-1.25,4.7) 60(-1.75,4.7) 61(-2.25,4.7) 62(-2.75,4.7) 63(-3.25,4.7) 64(-3.75,4.7)
  round 0.35 smd: 65(-0.66,-0.65) 65(-0.66,0) 65(-0.66,0.65) 65(-0.01,-0.65) 65(-0.01,0.65) 65(0.64,-0.65) 65(0.64,0) 65(0.64,0.65)
Top Layer:
  pour cut-out: -18.75,-18.75 -18.75,17.725 -17.725,18.75 18.75,18.75 18.75,-18.75
Top Overlay:
  region: -19,5 -20.5,4 -20.5,6
  lines w0.2: -18.65,-18.65 -18.65,17.65 -17.65,18.65 18.65,18.65 18.65,-18.65 -18.65,-18.65
Keep-Out Layer:
  circle w0.1: c-13.2,13.2 r4.5
  circle w0.1: c13.2,13.2 r4.5
  circle w0.1: c13.2,-13.2 r4.5
  circle w0.1: c-13.2,-13.2 r4.5
M15_Country_Yard:
  lines w0.1: -0.5,0 0.5,0 ; 0,-0.5 0,0.5

## SKT_QFN-64_ClamShell [mm] "Test & Burn socket for QFN-64"
height 15
pads (67):
  round 1.7 hole 1.7: 0(-6.075,6.075)
  round 1.3 hole 1.3: 0(6.075,-6.072)
  rect 0.6x1.2 hole 0.5: 1(-3.75,-6.375)
  oval 0.6x1.2 hole 0.5: 2(-3.25,-4.85) 3(-2.75,-6.375) 4(-2.25,-4.85) 5(-1.75,-6.375) 6(-1.25,-4.85) 7(-0.75,-6.375) 8(-0.25,-4.85) 9(0.25,-6.375) 10(0.75,-4.85) 11(1.25,-6.375) 12(1.75,-4.85) 13(2.25,-6.375) 14(2.75,-4.85) 15(3.25,-6.375) 16(3.75,-4.85) 33(3.75,6.376) 34(3.25,4.851) 35(2.75,6.376) 36(2.25,4.851) 37(1.75,6.376) 38(1.25,4.851) 39(0.75,6.376) 40(0.25,4.851) 41(-0.25,6.376) 42(-0.75,4.851) 43(-1.25,6.376) 44(-1.75,4.851) 45(-2.25,6.376) 46(-2.75,4.851) 47(-3.25,6.376) 48(-3.75,4.851)
  oval 1.2x0.6 hole 0.5: 17(6.373,-3.75) 18(4.848,-3.25) 19(6.373,-2.75) 20(4.848,-2.25) 21(6.373,-1.75) 22(4.848,-1.25) 23(6.373,-0.75) 24(4.848,-0.25) 25(6.373,0.25) 26(4.848,0.75) 27(6.373,1.25) 28(4.848,1.75) 29(6.373,2.25) 30(4.848,2.75) 31(6.373,3.25) 32(4.848,3.75) 49(-6.376,3.75) 50(-4.851,3.25) 51(-6.376,2.75) 52(-4.851,2.25) 53(-6.376,1.75) 54(-4.851,1.25) 55(-6.376,0.75) 56(-4.851,0.25) 57(-6.376,-0.25) 58(-4.851,-0.75) 59(-6.376,-1.25) 60(-4.851,-1.75) 61(-6.376,-2.25) 62(-4.851,-2.75) 63(-6.376,-3.25) 64(-4.851,-3.75)
  round 3 hole 2.2: 65(0,0)
Top Overlay:
  lines w0.2: -6,-13.715 -6,-14.707 6,-14.707 6,-13.715 ; -10.16,-13.715 10.16,-13.715 10.16,13.715 -10.16,13.715 -10.16,-13.715
M13_Assembly_Info:
  lines w0.1: -10.16,-13.715 10.16,-13.715 10.16,13.715 -10.16,13.715 -10.16,-13.715
M15_Country_Yard:
  lines w0.1: -10.16,13.715 -10.16,22.604 10.16,22.604 10.16,13.715

## SKT_QFN-64BT-0.5-01 [mm] "QFN-64BT-0.5-01 clamshell socket for QFN50P900X900X90-64"
height 16.7
pads (69):
  round 2.2 hole 2.2: 0(-7.85,-7.85) 0(7.85,7.85)
  round 1.7 hole 1.7: 0(-6.225,6.225)
  round 1.32 hole 1.32 unplated: 0(6.225,-6.225)
  rect 0.5x1.2 hole 0.4: 1(-3.75,-6.875)
  oval 0.5x1.2 hole 0.4: 2(-3.25,-5.35) 3(-2.75,-6.875) 4(-2.25,-5.35) 5(-1.75,-6.875) 6(-1.25,-5.35) 7(-0.75,-6.875) 8(-0.25,-5.35) 9(0.25,-6.875) 10(0.75,-5.35) 11(1.25,-6.875) 12(1.75,-5.35) 13(2.25,-6.875) 14(2.75,-5.35) 15(3.25,-6.875) 16(3.75,-5.35) 33(3.75,6.875) 34(3.25,5.35) 35(2.75,6.875) 36(2.25,5.35) 37(1.75,6.875) 38(1.25,5.35) 39(0.75,6.875) 40(0.25,5.35) 41(-0.25,6.875) 42(-0.75,5.35) 43(-1.25,6.875) 44(-1.75,5.35) 45(-2.25,6.875) 46(-2.75,5.35) 47(-3.25,6.875) 48(-3.75,5.35)
  oval 1.2x0.5 hole 0.4: 17(6.875,-3.75) 18(5.35,-3.25) 19(6.875,-2.75) 20(5.35,-2.25) 21(6.875,-1.75) 22(5.35,-1.25) 23(6.875,-0.75) 24(5.35,-0.25) 25(6.875,0.25) 26(5.35,0.75) 27(6.875,1.25) 28(5.35,1.75) 29(6.875,2.25) 30(5.35,2.75) 31(6.875,3.25) 32(5.35,3.75) 49(-6.875,3.75) 50(-5.35,3.25) 51(-6.875,2.75) 52(-5.35,2.25) 53(-6.875,1.75) 54(-5.35,1.25) 55(-6.875,0.75) 56(-5.35,0.25) 57(-6.875,-0.25) 58(-5.35,-0.75) 59(-6.875,-1.25) 60(-5.35,-1.75) 61(-6.875,-2.25) 62(-5.35,-2.75) 63(-6.875,-3.25) 64(-5.35,-3.75)
  round 5 hole 3.3: 65(0,0)
Top Overlay:
  region: -11.51,-15.45 -12.51,-16.45 -10.51,-16.45
  lines w0.2: -8,-15.25 -8,-19.75 8,-19.75 8,-15.25 ; -14.5,-15.25 -14.5,15.25 14.5,15.25 14.5,-15.25 -14.5,-15.25
M15_Country_Yard:
  lines w0.1: -14.69,-19.94 14.69,-19.94 14.69,25.25 -14.69,25.25 -14.69,-19.94

## SKT_QFP-32_IC51-03240-1498 [mm] "Test & Burn socket for QFP-32, 0.8mm pitch, 7x7mm body. Yamaichi IC51-03240-1498"
height 18.6
pads (36):
  round 4 hole 4 unplated: 0(-10,-10) 0(-10,10) 0(10,-10) 0(10,10)
  rect 0.8x1.4 hole 0.65: 1(-2.8,-6.7)
  oval 0.8x1.4 hole 0.65: 2(-2,-5.1) 3(-1.2,-6.7) 4(-0.4,-5.1) 5(0.4,-6.7) 6(1.2,-5.1) 7(2,-6.7) 8(2.8,-5.1) 17(2.8,5.1) 18(2,6.7) 19(1.2,5.1) 20(0.4,6.7) 21(-0.4,5.1) 22(-1.2,6.7) 23(-2,5.1) 24(-2.8,6.7)
  oval 1.4x0.8 hole 0.65: 9(5.1,-2.8) 10(6.7,-2) 11(5.1,-1.2) 12(6.7,-0.4) 13(5.1,0.4) 14(6.7,1.2) 15(5.1,2) 16(6.7,2.8) 25(-6.7,2.8) 26(-5.1,2) 27(-6.7,1.2) 28(-5.1,0.4) 29(-6.7,-0.4) 30(-5.1,-1.2) 31(-6.7,-2) 32(-5.1,-2.8)
Top Overlay:
  lines w0.25: -7,-20.8 7,-20.8 7,-18.75 -7,-18.75 -7,-20.8
  lines w0.254: -15,-18.75 15,-18.75 15,18.75 -15,18.75 -15,-18.75
M15_Country_Yard:
  lines w0.1: -0.5,0 0.5,0 ; 0,-0.5 0,0.5

## SKT_QFP-32_IC51-03240-1498 - handler [mm] "Test & Burn socket for QFP-32, 0.8mm pitch, 7x7mm body. Yamaichi IC51-03240-1498"
height 18.6
pads (36):
  round 5 hole 4.1: 0(-10,-10) 0(-10,10) 0(10,-10) 0(10,10)
  rect 1.4x0.8 hole 0.55: 1(-6.7,2.8)
  oval 1.4x0.8 hole 0.55: 2(-5.1,2) 3(-6.7,1.2) 4(-5.1,0.4) 5(-6.7,-0.4) 6(-5.1,-1.2) 7(-6.7,-2) 8(-5.1,-2.8) 17(5.1,-2.8) 18(6.7,-2) 19(5.1,-1.2) 20(6.7,-0.4) 21(5.1,0.4) 22(6.7,1.2) 23(5.1,2) 24(6.7,2.8)
  oval 0.8x1.4 hole 0.55: 9(-2.8,-5.1) 10(-2,-6.7) 11(-1.2,-5.1) 12(-0.4,-6.7) 13(0.4,-5.1) 14(1.2,-6.7) 15(2,-5.1) 16(2.8,-6.7) 25(2.8,6.7) 26(2,5.1) 27(1.2,6.7) 28(0.4,5.1) 29(-0.4,6.7) 30(-1.2,5.1) 31(-2,6.7) 32(-2.8,5.1)
Top Overlay:
  lines w0.25: -7,-20.8 -7,-18.75 7,-18.75 7,-20.8 -7,-20.8
  lines w0.254: -15,-18.75 -15,18.75 15,18.75 15,-18.75 -15,-18.75
M15_Country_Yard:
  lines w0.1: -0.5,0 0.5,0 ; 0,-0.5 0,0.5

## SKT_QFP-32_IC51-03240-1498 - handler for FT232BL [mm] "Test & Burn socket for QFP-32, 0.8mm pitch, 7x7mm body. Yamaichi IC51-03240-1498"
height 18.6
pads (36):
  round 5 hole 4.1: 0(-10,-10) 0(-10,10) 0(10,-10) 0(10,10)
  rect 0.8x1.4 hole 0.55: 1(2.8,5.1)
  oval 0.8x1.4 hole 0.55: 2(2,6.7) 3(1.2,5.1) 4(0.4,6.7) 5(-0.4,5.1) 6(-1.2,6.7) 7(-2,5.1) 8(-2.8,6.7) 17(-2.8,-6.7) 18(-2,-5.1) 19(-1.2,-6.7) 20(-0.4,-5.1) 21(0.4,-6.7) 22(1.2,-5.1) 23(2,-6.7) 24(2.8,-5.1)
  oval 1.4x0.8 hole 0.55: 9(-6.7,2.8) 10(-5.1,2) 11(-6.7,1.2) 12(-5.1,0.4) 13(-6.7,-0.4) 14(-5.1,-1.2) 15(-6.7,-2) 16(-5.1,-2.8) 25(5.1,-2.8) 26(6.7,-2) 27(5.1,-1.2) 28(6.7,-0.4) 29(5.1,0.4) 30(6.7,1.2) 31(5.1,2) 32(6.7,2.8)
Top Overlay:
  lines w0.25: -7,-20.8 -7,-18.75 7,-18.75 7,-20.8 -7,-20.8
  lines w0.254: -15,-18.75 -15,18.75 15,18.75 15,-18.75 -15,-18.75
M15_Country_Yard:
  lines w0.1: -2.8,-5.9 2.8,-5.9 ; -2.8,5.9 2.8,5.9 ; -0.5,0 0.5,0 ; 0,-6.7 0,-5.1 ; 0,-0.5 0,0.5 ; 0,5.1 0,6.7 ; -2.8,-6.7 -2.8,-5.1 2.8,-5.1 2.8,-6.7 -2.8,-6.7 ; -2.8,5.1 2.8,5.1 2.8,6.7 -2.8,6.7 -2.8,5.1

## SKT_QFP-48_55-022-465-01 [mm] "Test & Burn socket for QFP-48, 0.5mm pitch, 7x7mm body. Enplas, 55-022-465-01"
height 18.6
pads (52):
  round 4 hole 3.2 unplated: 0(-10.5,-9) 0(-10.5,9) 0(10.5,-9) 0(10.5,9)
  rect 1.7x0.9 hole 0.8: 1(-10.08,2.75)
  oval 1.7x0.9 hole 0.8: 2(-7.54,2.25) 3(-5,1.75) 4(-10.08,1.25) 5(-7.54,0.75) 6(-5,0.25) 7(-10.08,-0.26) 8(-7.54,-0.76) 9(-5,-1.26) 10(-10.08,-1.75) 11(-7.54,-2.25) 12(-5,-2.75) 25(10.08,-2.75) 26(7.54,-2.25) 27(5,-1.75) 28(10.08,-1.25) 29(7.54,-0.75) 30(5,-0.25) 31(10.08,0.26) 32(7.54,0.76) 33(5,1.26) 34(10.08,1.75) 35(7.54,2.25) 36(5,2.75)
  oval 0.9x1.7 hole 0.8: 13(-2.75,-10.08) 14(-2.25,-7.54) 15(-1.75,-5) 16(-1.25,-10.08) 17(-0.75,-7.54) 18(-0.25,-5) 19(0.26,-10.08) 20(0.76,-7.54) 21(1.26,-5) 22(1.75,-10.08) 23(2.25,-7.54) 24(2.75,-5) 37(2.75,10.08) 38(2.25,7.54) 39(1.75,5) 40(1.25,10.08) 41(0.75,7.54) 42(0.25,5) 43(-0.26,10.08) 44(-0.76,7.54) 45(-1.26,5) 46(-1.75,10.08) 47(-2.25,7.54) 48(-2.75,5)
Top Overlay:
  lines w0.25: -7,-17.25 -7,-19.3 7,-19.3 7,-17.25 ; -14.5,-17.25 14.5,-17.25 14.5,17.25 -14.5,17.25 -14.5,-17.25
M15_Country_Yard:
  lines w0.1: -0.5,0 0.5,0 ; 0,-0.5 0,0.5 ; -14.5,-20.15 -14.5,26.37 14.5,26.37 14.5,-20.15 -14.5,-20.15
3D body: height 15, standoff 0, extent -14.5,-17.25 14.5,17.25

## SKT_QFP-48_IC51-0484-806 [mm] "Test & Burn socket for QFP-48, 0.5mm pitch, 7x7mm body. Yamaichi, IC51-0484-806"
height 18.6
pads (52):
  round 4 hole 4 unplated: 0(-9.5,-9.5) 0(-9.5,9.5) 0(9.5,-9.5) 0(9.5,9.5)
  rect 1.7x0.9 hole 0.8: 1(-10.08,2.75)
  oval 1.7x0.9 hole 0.8: 2(-7.54,2.25) 3(-5,1.75) 4(-10.08,1.25) 5(-7.54,0.75) 6(-5,0.25) 7(-10.08,-0.26) 8(-7.54,-0.76) 9(-5,-1.26) 10(-10.08,-1.75) 11(-7.54,-2.25) 12(-5,-2.75) 25(10.08,-2.75) 26(7.54,-2.25) 27(5,-1.75) 28(10.08,-1.25) 29(7.54,-0.75) 30(5,-0.25) 31(10.08,0.26) 32(7.54,0.76) 33(5,1.26) 34(10.08,1.75) 35(7.54,2.25) 36(5,2.75)
  oval 0.9x1.7 hole 0.8: 13(-2.75,-10.08) 14(-2.25,-7.54) 15(-1.75,-5) 16(-1.25,-10.08) 17(-0.75,-7.54) 18(-0.25,-5) 19(0.26,-10.08) 20(0.76,-7.54) 21(1.26,-5) 22(1.75,-10.08) 23(2.25,-7.54) 24(2.75,-5) 37(2.75,10.08) 38(2.25,7.54) 39(1.75,5) 40(1.25,10.08) 41(0.75,7.54) 42(0.25,5) 43(-0.26,10.08) 44(-0.76,7.54) 45(-1.26,5) 46(-1.75,10.08) 47(-2.25,7.54) 48(-2.75,5)
Top Overlay:
  lines w0.25: -7,-17.25 -7,-19.3 7,-19.3 7,-17.25 ; -14.5,-17.25 -14.5,17.25 14.5,17.25 14.5,-17.25 -14.5,-17.25
M15_Country_Yard:
  lines w0.1: -0.5,0 0.5,0 ; 0,-0.5 0,0.5 ; -14.5,-20.15 14.5,-20.15 14.5,26.37 -14.5,26.37 -14.5,-20.15
3D body: height 15, standoff 0, extent -14.5,-17.25 14.5,17.25

## SKT_QFP-48_IC51-0484-806 - Load Boards Only [mm] "Test & Burn socket for QFP-48, 0.5mm pitch, 7x7mm body. Yamaichi, IC51-0484-806; Use only for Load Boards; Pin No. 1 rotated by 90 degrees"
height 18.6
pads (52):
  round 4 hole 4 unplated: 0(-9.5,-9.5) 0(-9.5,9.5) 0(9.5,-9.5) 0(9.5,9.5)
  rect 0.9x1.7 hole 0.8: 1(-2.75,-10.08)
  oval 0.9x1.7 hole 0.8: 2(-2.25,-7.54) 3(-1.75,-5) 4(-1.25,-10.08) 5(-0.75,-7.54) 6(-0.25,-5) 7(0.26,-10.08) 8(0.76,-7.54) 9(1.26,-5) 10(1.75,-10.08) 11(2.25,-7.54) 12(2.75,-5) 25(2.75,10.08) 26(2.25,7.54) 27(1.75,5) 28(1.25,10.08) 29(0.75,7.54) 30(0.25,5) 31(-0.26,10.08) 32(-0.76,7.54) 33(-1.26,5) 34(-1.75,10.08) 35(-2.25,7.54) 36(-2.75,5)
  oval 1.7x0.9 hole 0.8: 13(10.08,-2.75) 14(7.54,-2.25) 15(5,-1.75) 16(10.08,-1.25) 17(7.54,-0.75) 18(5,-0.25) 19(10.08,0.26) 20(7.54,0.76) 21(5,1.26) 22(10.08,1.75) 23(7.54,2.25) 24(5,2.75) 37(-10.08,2.75) 38(-7.54,2.25) 39(-5,1.75) 40(-10.08,1.25) 41(-7.54,0.75) 42(-5,0.25) 43(-10.08,-0.26) 44(-7.54,-0.76) 45(-5,-1.26) 46(-10.08,-1.75) 47(-7.54,-2.25) 48(-5,-2.75)
Top Overlay:
  lines w0.25: -7,-17.25 -7,-19.3 7,-19.3 7,-17.25 ; -14.5,-17.25 -14.5,17.25 14.5,17.25 14.5,-17.25 -14.5,-17.25
M15_Country_Yard:
  lines w0.1: -0.5,0 0.5,0 ; 0,-0.5 0,0.5 ; -14.5,-20.15 14.5,-20.15 14.5,26.37 -14.5,26.37 -14.5,-20.15
3D body: height 15, standoff 0, extent -14.5,-17.25 14.5,17.25

## SKT_QFP-48_IC51-0484-806 - Load Boards Only - duplicate1 [mm] "Test & Burn socket for QFP-48, 0.5mm pitch, 7x7mm body. Yamaichi, IC51-0484-806; Use only for Load Boards; Pin No. 1 rotated by 180 degrees"
height 18.6
pads (52):
  round 4 hole 4 unplated: 0(-9.5,-9.5) 0(-9.5,9.5) 0(9.5,-9.5) 0(9.5,9.5)
  rect 1.7x0.9 hole 0.8: 1(-10.08,2.75)
  oval 1.7x0.9 hole 0.8: 2(-7.54,2.25) 3(-5,1.75) 4(-10.08,1.25) 5(-7.54,0.75) 6(-5,0.25) 7(-10.08,-0.26) 8(-7.54,-0.76) 9(-5,-1.26) 10(-10.08,-1.75) 11(-7.54,-2.25) 12(-5,-2.75) 25(10.08,-2.75) 26(7.54,-2.25) 27(5,-1.75) 28(10.08,-1.25) 29(7.54,-0.75) 30(5,-0.25) 31(10.08,0.26) 32(7.54,0.76) 33(5,1.26) 34(10.08,1.75) 35(7.54,2.25) 36(5,2.75)
  oval 0.9x1.7 hole 0.8: 13(-2.75,-10.08) 14(-2.25,-7.54) 15(-1.75,-5) 16(-1.25,-10.08) 17(-0.75,-7.54) 18(-0.25,-5) 19(0.26,-10.08) 20(0.76,-7.54) 21(1.26,-5) 22(1.75,-10.08) 23(2.25,-7.54) 24(2.75,-5) 37(2.75,10.08) 38(2.25,7.54) 39(1.75,5) 40(1.25,10.08) 41(0.75,7.54) 42(0.25,5) 43(-0.26,10.08) 44(-0.76,7.54) 45(-1.26,5) 46(-1.75,10.08) 47(-2.25,7.54) 48(-2.75,5)
Top Overlay:
  lines w0.25: -7,-17.25 -7,-19.3 7,-19.3 7,-17.25 ; -14.5,-17.25 -14.5,17.25 14.5,17.25 14.5,-17.25 -14.5,-17.25
M15_Country_Yard:
  lines w0.1: -0.5,0 0.5,0 ; 0,-0.5 0,0.5 ; -14.5,-20.15 14.5,-20.15 14.5,26.37 -14.5,26.37 -14.5,-20.15
3D body: height 15, standoff 0, extent -14.5,-17.25 14.5,17.25

## SKT_QFP-64_IC51-0644-807 - duplicate [mm] "Test & Burn socket for QFP-64, 0.5mm pitch, 10x10mm body. Yamaichi, IC51-0644-807"
height 15
pads (68):
  round 4 hole 4 unplated: 0(-10.999,-10.997) 0(-10.999,10.999) 0(10.998,-10.997) 0(10.998,10.999)
  rect 0.9x1.7 hole 0.8: 1(-3.751,-11.582)
  oval 0.9x1.7 hole 0.8: 2(-3.251,-9.042) 3(-2.751,-6.502) 4(-2.251,-11.582) 5(-1.751,-9.042) 6(-1.251,-6.502) 7(-0.751,-11.582) 8(-0.251,-9.042) 9(0.249,-6.502) 10(0.749,-11.582) 11(1.249,-9.042) 12(1.749,-6.502) 13(2.249,-11.582) 14(2.749,-9.042) 15(3.249,-6.502) 16(3.749,-11.582) 33(3.749,11.582) 34(3.249,9.042) 35(2.749,6.502) 36(2.249,11.582) 37(1.749,9.042) 38(1.249,6.502) 39(0.749,11.582) 40(0.249,9.042) 41(-0.251,6.502) 42(-0.751,11.582) 43(-1.251,9.042) 44(-1.751,6.502) 45(-2.251,11.582) 46(-2.751,9.042) 47(-3.251,6.502) 48(-3.751,11.582)
  oval 1.7x0.9 hole 0.8: 17(11.582,-3.751) 18(9.042,-3.251) 19(6.502,-2.751) 20(11.582,-2.251) 21(9.042,-1.751) 22(6.502,-1.251) 23(11.582,-0.751) 24(9.042,-0.251) 25(6.502,0.249) 26(11.582,0.749) 27(9.042,1.249) 28(6.502,1.749) 29(11.582,2.249) 30(9.042,2.749) 31(6.502,3.249) 32(11.582,3.749) 49(-11.583,3.749) 50(-9.043,3.249) 51(-6.503,2.749) 52(-11.583,2.249) 53(-9.043,1.749) 54(-6.503,1.249) 55(-11.583,0.749) 56(-9.043,0.249) 57(-6.503,-0.251) 58(-11.583,-0.751) 59(-9.043,-1.251) 60(-6.503,-1.751) 61(-11.583,-2.251) 62(-9.043,-2.751) 63(-6.503,-3.251) 64(-11.583,-3.751)
Top Overlay:
  lines w0.2: -7.501,-19.999 -7.501,-20.93 7.499,-20.93 7.499,-19.999 ; -16,-19.999 -16,20.001 16,20.001 16,-19.999 -16,-19.999
M13_Assembly_Info:
  lines w0.1: -16,-19.999 -16,20.001 16,20.001 16,-19.999 -16,-19.999
M15_Country_Yard:
  lines w0.1: -16,-20 -16,-23 16,-23 16,-20 ; -16,20.001 -16,28.891 16,28.891 16,20.001 ; -0.5,0 0.5,0 ; 0,-0.5 0,0.5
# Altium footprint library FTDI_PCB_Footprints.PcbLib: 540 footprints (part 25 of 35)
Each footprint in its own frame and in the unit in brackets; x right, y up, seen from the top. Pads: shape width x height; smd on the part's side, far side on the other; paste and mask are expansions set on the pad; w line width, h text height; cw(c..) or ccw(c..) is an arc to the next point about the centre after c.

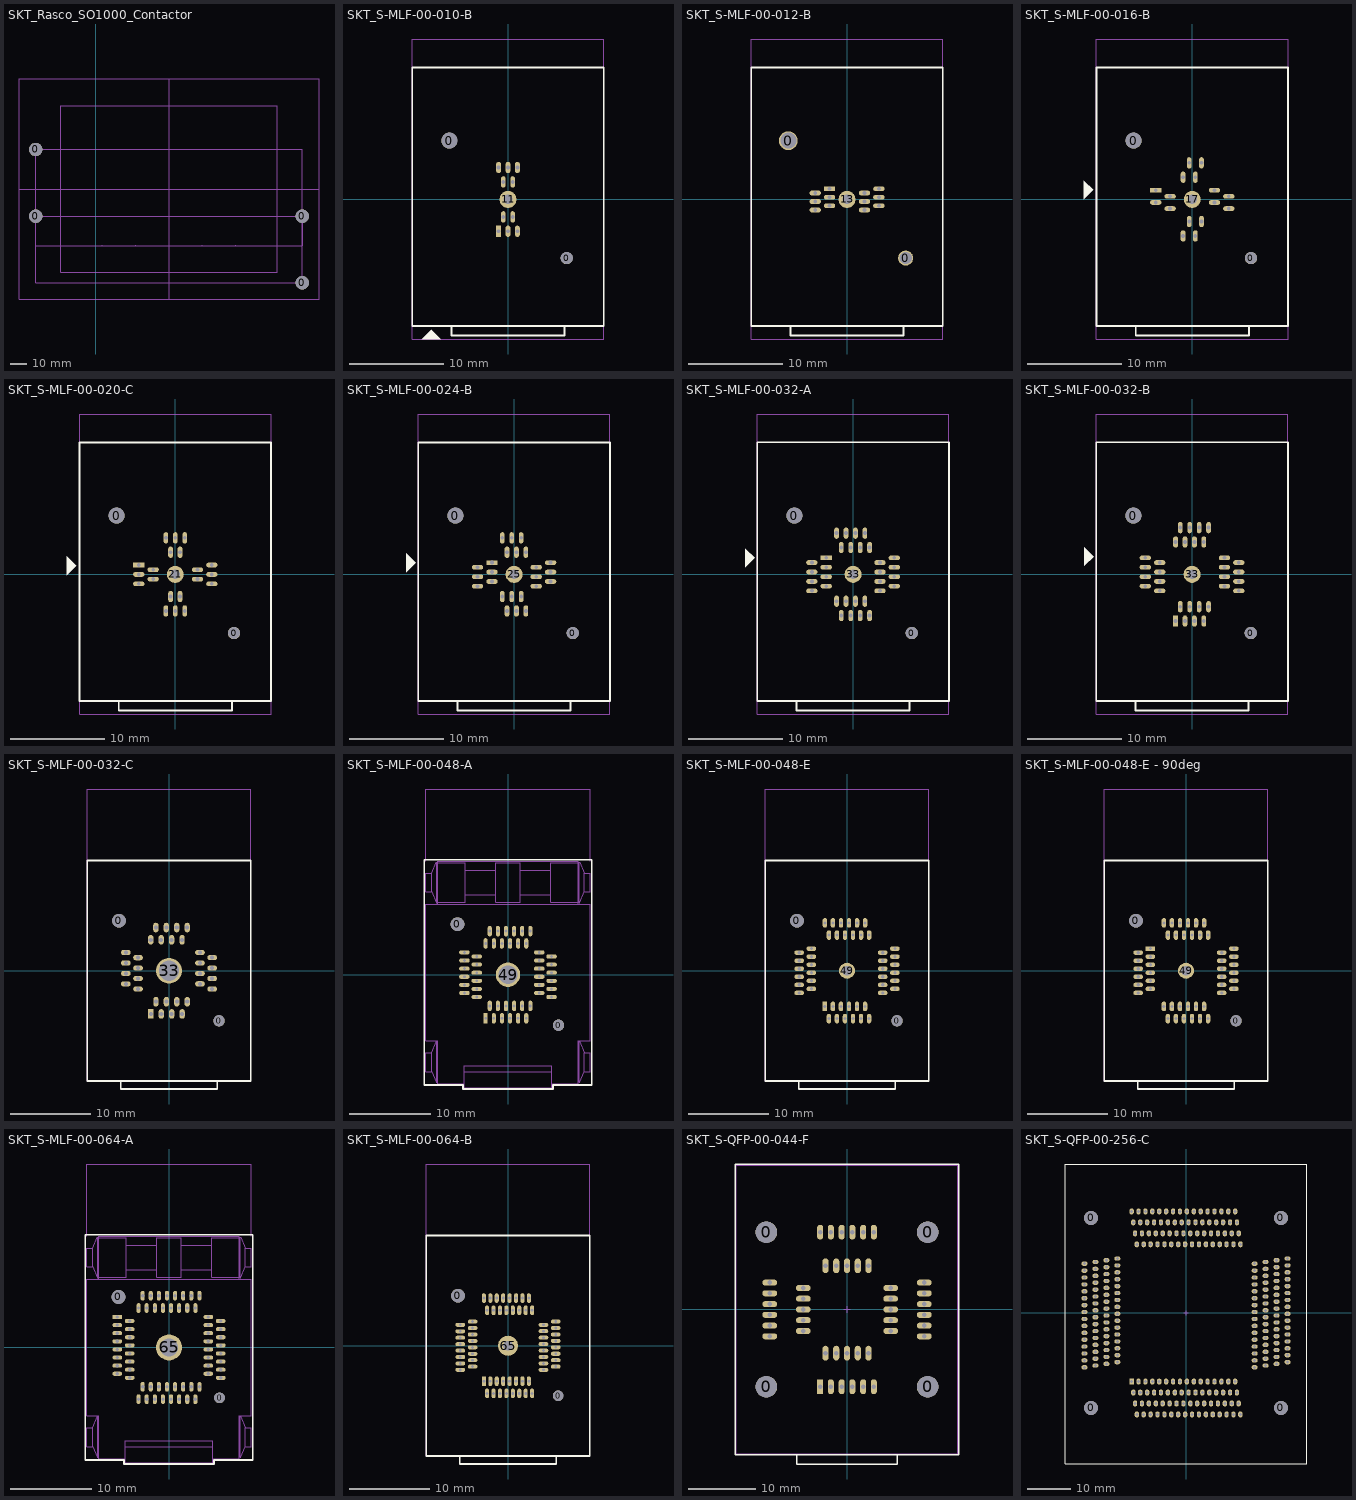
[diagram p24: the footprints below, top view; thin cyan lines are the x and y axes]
## SKT_Rasco_SO1000_Contactor [mm]
pads (4):
  round 8 hole 8 unplated: 0(-35.93,134.21) 0(-35.93,174.21) 0(124.07,94.21) 0(124.07,134.21)
M15_Country_Yard:
  lines w0.1: -45.93,150.51 134.07,150.51 ; -35.93,116.43 124.07,116.43 ; -35.93,134.21 124.07,134.21 ; -20.93,150.51 109.07,150.51 ; 3.91,116.1 3.91,116.74 ; 24.23,116.1 24.23,116.74 ; 44.07,84.26 44.07,216.76 ; 44.07,94.21 44.07,174.21 ; 44.07,100.51 44.07,200.51 ; 63.91,116.1 63.91,116.74 ; 84.23,116.1 84.23,116.74 ; 124.3,116.43 124.3,134.21 ; -45.93,84.26 134.07,84.26 134.07,216.76 -45.93,216.76 -45.93,84.26 ; -35.93,94.21 124.07,94.21 124.07,174.21 -35.93,174.21 -35.93,94.21 ; -20.93,100.51 109.07,100.51 109.07,200.51 -20.93,200.51 -20.93,100.51

## SKT_S-MLF-00-010-B [mm] "Test & Burn socket for QFN-10, 0.5mm pitch, 3x3mm body. Emulation Technology S-MLF-00-010-B"
height 15
pads (13):
  round 1.7 hole 1.7 unplated: 0(-6.225,6.225)
  round 1.3 hole 1.3 unplated: 0(6.225,-6.225)
  rect 0.5x1.2 hole 0.4: 1(-1,-3.38)
  oval 0.5x1.2 hole 0.4: 2(-0.5,-1.855) 3(0,-3.38) 4(0.5,-1.855) 5(1,-3.38) 6(1,3.38) 7(0.5,1.855) 8(0,3.38) 9(-0.5,1.855) 10(-1,3.38)
  round 1.8 hole 1: 11(0,0)
Top Overlay:
  region: -8.14,-13.805 -7.14,-14.805 -9.14,-14.805
  lines w0.2: -6,-13.43 -6,-14.422 6,-14.422 6,-13.43 ; -10.16,-13.43 10.16,-13.43 10.16,14 -10.16,14 -10.16,-13.43
M15_Country_Yard:
  lines w0.1: -10.16,13.715 -10.16,17.01 10.16,17.01 10.16,13.715 ; -0.5,0 0.5,0 ; 0,-0.5 0,0.5 ; -10.16,-14.805 10.16,-14.805 10.16,14 -10.16,14 -10.16,-14.805

## SKT_S-MLF-00-012-B [mm] "Test & Burn socket for DFN-12, 0.45mm pitch, 3x3mm body. Emulation Technology S-MLF-00-012-B"
height 15
pads (15):
  round 2 hole 1.7: 0(-6.225,6.225)
  round 1.6 hole 1.3: 0(6.225,-6.225)
  rect 1.2x0.5 hole 0.4: 1(-1.85,1.125)
  oval 1.2x0.5 hole 0.4: 2(-3.375,0.675) 3(-1.85,0.225) 4(-3.375,-0.225) 5(-1.85,-0.675) 6(-3.375,-1.125) 7(1.855,-1.125) 8(3.38,-0.675) 9(1.855,-0.225) 10(3.38,0.225) 11(1.855,0.675) 12(3.38,1.125)
  round 1.8 hole 1: 13(0,0)
Top Overlay:
  lines w0.2: -6,-13.43 -6,-14.422 6,-14.422 6,-13.43 ; -10.16,-13.43 10.16,-13.43 10.16,14 -10.16,14 -10.16,-13.43
M15_Country_Yard:
  lines w0.1: -10.16,13.715 -10.16,17.01 10.16,17.01 10.16,13.715 ; -0.5,0 0.5,0 ; 0,-0.5 0,0.5 ; -10.16,-14.805 10.16,-14.805 10.16,14 -10.16,14 -10.16,-14.805

## SKT_S-MLF-00-016-B [mm] "Test & Burn socket for QFN-16, 0.65mm pitch, 4x4mm body. Emulation Technology S-MLF-00-016-B"
height 15
pads (19):
  round 1.7 hole 1.7 unplated: 0(-6.225,6.225)
  round 1.3 hole 1.3 unplated: 0(6.225,-6.225)
  rect 1.2x0.5 hole 0.4: 1(-3.875,0.975)
  oval 1.2x0.5 hole 0.4: 2(-2.35,0.325) 3(-3.875,-0.325) 4(-2.35,-0.975) 9(3.875,-0.975) 10(2.35,-0.325) 11(3.875,0.325) 12(2.35,0.975)
  oval 0.5x1.2 hole 0.4: 5(-0.975,-3.875) 6(-0.325,-2.35) 7(0.325,-3.875) 8(0.975,-2.35) 13(0.975,3.875) 14(0.325,2.35) 15(-0.325,3.875) 16(-0.975,2.35)
  round 1.8 hole 1: 17(0,0)
Top Overlay:
  region: -10.49,1 -11.49,0 -11.49,2
  lines w0.2: -6,-13.43 -6,-14.422 6,-14.422 6,-13.43 ; -10.16,-13.43 10.16,-13.43 10.16,14 -10.16,14 -10.16,-13.43
M15_Country_Yard:
  lines w0.1: -10.16,13.715 -10.16,17.01 10.16,17.01 10.16,13.715 ; -0.5,0 0.5,0 ; 0,-0.5 0,0.5 ; -10.16,-14.805 10.16,-14.805 10.16,14 -10.16,14 -10.16,-14.805

## SKT_S-MLF-00-020-C [mm] "Test & Burn socket for QFN-20, 0.5mm pitch, 4x4mm body. Emulation Technology S-MLF-00-020-C"
height 15
pads (23):
  round 1.7 hole 1.7 unplated: 0(-6.225,6.225)
  round 1.3 hole 1.3 unplated: 0(6.225,-6.225)
  rect 1.2x0.5 hole 0.4: 1(-3.875,1)
  oval 1.2x0.5 hole 0.4: 2(-2.35,0.5) 3(-3.875,0) 4(-2.35,-0.5) 5(-3.875,-1) 11(3.875,-1) 12(2.35,-0.5) 13(3.875,0) 14(2.35,0.5) 15(3.875,1)
  oval 0.5x1.2 hole 0.4: 6(-1,-3.875) 7(-0.5,-2.35) 8(0,-3.875) 9(0.5,-2.35) 10(1,-3.875) 16(1,3.875) 17(0.5,2.35) 18(0,3.875) 19(-0.5,2.35) 20(-1,3.875)
  round 1.8 hole 1: 21(0,0)
Top Overlay:
  region: -10.5,0.9 -11.5,-0.1 -11.5,1.9
  lines w0.2: -6,-13.43 -6,-14.422 6,-14.422 6,-13.43 ; -10.16,-13.43 -10.16,14 10.16,14 10.16,-13.43 -10.16,-13.43
M15_Country_Yard:
  lines w0.1: -10.16,13.715 -10.16,17.01 10.16,17.01 10.16,13.715 ; -0.5,0 0.5,0 ; 0,-0.5 0,0.5 ; -10.16,-14.805 -10.16,14 10.16,14 10.16,-14.805 -10.16,-14.805

## SKT_S-MLF-00-024-B [mm] "Test & Burn socket for QFN-24, 0.5mm pitch, 4x4mm body. Emulation Technology S-MLF-00-024-B"
height 15
pads (27):
  round 1.7 hole 1.7 unplated: 0(-6.225,6.225)
  round 1.3 hole 1.3 unplated: 0(6.225,-6.225)
  rect 1.2x0.5 hole 0.4: 1(-2.35,1.25)
  oval 1.2x0.5 hole 0.4: 2(-3.875,0.75) 3(-2.35,0.25) 4(-3.875,-0.25) 5(-2.35,-0.75) 6(-3.875,-1.25) 13(2.35,-1.25) 14(3.875,-0.75) 15(2.35,-0.25) 16(3.875,0.25) 17(2.35,0.75) 18(3.875,1.25)
  oval 0.5x1.2 hole 0.4: 7(-1.25,-2.35) 8(-0.75,-3.875) 9(-0.25,-2.35) 10(0.25,-3.875) 11(0.75,-2.35) 12(1.25,-3.875) 19(1.25,2.35) 20(0.75,3.875) 21(0.25,2.35) 22(-0.25,3.875) 23(-0.75,2.35) 24(-1.25,3.875)
  round 1.8 hole 1: 25(0,0)
Top Overlay:
  region: -10.45,1.25 -11.45,0.25 -11.45,2.25
  lines w0.2: -6,-13.43 -6,-14.422 6,-14.422 6,-13.43 ; -10.16,-13.43 10.16,-13.43 10.16,14 -10.16,14 -10.16,-13.43
M15_Country_Yard:
  lines w0.1: -10.16,13.715 -10.16,17.01 10.16,17.01 10.16,13.715 ; -0.5,0 0.5,0 ; 0,-0.5 0,0.5 ; -10.16,-14.805 10.16,-14.805 10.16,14 -10.16,14 -10.16,-14.805

## SKT_S-MLF-00-032-A [mm] "Test & Burn socket for QFN-32, 0.5mm pitch, 5x5mm body. Emulation Technology S-MLF-00-032-A"
height 15
pads (35):
  round 1.7 hole 1.7 unplated: 0(-6.225,6.225)
  round 1.3 hole 1.3 unplated: 0(6.225,-6.225)
  rect 1.2x0.5 hole 0.4: 1(-2.845,1.75)
  oval 1.2x0.5 hole 0.4: 2(-4.37,1.25) 3(-2.845,0.75) 4(-4.37,0.25) 5(-2.845,-0.25) 6(-4.37,-0.75) 7(-2.845,-1.25) 8(-4.37,-1.75) 17(2.845,-1.75) 18(4.37,-1.25) 19(2.845,-0.75) 20(4.37,-0.25) 21(2.845,0.25) 22(4.37,0.75) 23(2.845,1.25) 24(4.37,1.75)
  oval 0.5x1.2 hole 0.4: 9(-1.75,-2.845) 10(-1.25,-4.37) 11(-0.75,-2.845) 12(-0.25,-4.37) 13(0.25,-2.845) 14(0.75,-4.37) 15(1.25,-2.845) 16(1.75,-4.37) 25(1.75,2.845) 26(1.25,4.37) 27(0.75,2.845) 28(0.25,4.37) 29(-0.25,2.845) 30(-0.75,4.37) 31(-1.25,2.845) 32(-1.75,4.37)
  round 1.8 hole 1: 33(0,0)
Top Overlay:
  region: -10.45,1.74 -11.45,0.74 -11.45,2.74
  lines w0.2: -6,-13.43 -6,-14.422 6,-14.422 6,-13.43 ; -10.16,-13.43 -10.16,14 10.16,14 10.16,-13.43 -10.16,-13.43
M15_Country_Yard:
  lines w0.1: -10.16,13.715 -10.16,17 10.16,17 10.16,13.715 ; -0.5,0 0.5,0 ; 0,-0.5 0,0.5 ; -10.16,-14.805 -10.16,14 10.16,14 10.16,-14.805 -10.16,-14.805

## SKT_S-MLF-00-032-B [mm] "Test & Burn socket for QFN-32, 0.5mm pitch, 6x6mm body. Emulation Technology S-MLF-00-032-B"
height 15
pads (35):
  round 1.7 hole 1.7 unplated: 0(-6.225,6.225)
  round 1.3 hole 1.3 unplated: 0(6.225,-6.225)
  rect 0.5x1.2 hole 0.4: 1(-1.75,-4.955)
  oval 0.5x1.2 hole 0.4: 2(-1.25,-3.43) 3(-0.75,-4.955) 4(-0.25,-3.43) 5(0.25,-4.955) 6(0.75,-3.43) 7(1.25,-4.955) 8(1.75,-3.43) 17(1.75,4.955) 18(1.25,3.43) 19(0.75,4.955) 20(0.25,3.43) 21(-0.25,4.955) 22(-0.75,3.43) 23(-1.25,4.955) 24(-1.75,3.43)
  oval 1.2x0.5 hole 0.4: 9(4.955,-1.75) 10(3.43,-1.25) 11(4.955,-0.75) 12(3.43,-0.25) 13(4.955,0.25) 14(3.43,0.75) 15(4.955,1.25) 16(3.43,1.75) 25(-4.955,1.75) 26(-3.43,1.25) 27(-4.955,0.75) 28(-3.43,0.25) 29(-4.955,-0.25) 30(-3.43,-0.75) 31(-4.955,-1.25) 32(-3.43,-1.75)
  round 1.8 hole 1: 33(0,0)
Top Overlay:
  region: -10.447,1.888 -11.447,0.888 -11.447,2.888
  lines w0.2: -6,-13.43 -6,-14.422 6,-14.422 6,-13.43 ; -10.16,-13.43 10.16,-13.43 10.16,14 -10.16,14 -10.16,-13.43
M15_Country_Yard:
  lines w0.1: -10.16,13.715 -10.16,17 10.16,17 10.16,13.715 ; -0.5,0 0.5,0 ; 0,-0.5 0,0.5 ; -10.16,-14.805 10.16,-14.805 10.16,14 -10.16,14 -10.16,-14.805

## SKT_S-MLF-00-032-C [mm] "Test & Burn socket for QFN-48"
height 15
pads (35):
  round 1.7 hole 1.7: 0(-6.225,6.225)
  round 1.4 hole 1.4: 0(6.225,-6.225)
  rect 0.65x1.2 hole 0.5: 1(-2.265,-5.37)
  oval 0.65x1.2 hole 0.5: 2(-1.63,-3.85) 3(-0.965,-5.37) 4(-0.33,-3.85) 5(0.335,-5.37) 6(0.97,-3.85) 7(1.635,-5.37) 8(2.27,-3.85) 17(2.265,5.37) 18(1.63,3.85) 19(0.965,5.37) 20(0.33,3.85) 21(-0.335,5.37) 22(-0.97,3.85) 23(-1.635,5.37) 24(-2.27,3.85)
  oval 1.2x0.65 hole 0.5: 9(5.37,-2.265) 10(3.85,-1.63) 11(5.37,-0.965) 12(3.85,-0.33) 13(5.37,0.335) 14(3.85,0.97) 15(5.37,1.635) 16(3.85,2.27) 25(-5.37,2.265) 26(-3.85,1.63) 27(-5.37,0.965) 28(-3.85,0.33) 29(-5.37,-0.335) 30(-3.85,-0.97) 31(-5.37,-1.635) 32(-3.85,-2.27)
  round 3.2 hole 2.5: 33(0,0)
Top Overlay:
  lines w0.2: -6,-13.715 -6,-14.707 6,-14.707 6,-13.715 ; -10.16,-13.715 -10.16,13.715 10.16,13.715 10.16,-13.715 -10.16,-13.715
M13_Assembly_Info:
  lines w0.1: -10.16,-13.715 -10.16,13.715 10.16,13.715 10.16,-13.715 -10.16,-13.715
M15_Country_Yard:
  lines w0.1: -10.16,13.715 -10.16,22.604 10.16,22.604 10.16,13.715

## SKT_S-MLF-00-048-A [mm] "Test & Burn socket for QFN-48"
height 15
pads (51):
  round 1.7 hole 1.7: 0(-6.225,6.225)
  round 1.4 hole 1.4: 0(6.225,-6.225)
  rect 0.5x1.3 hole 0.35: 1(-2.75,-5.37)
  oval 0.5x1.3 hole 0.35: 2(-2.25,-3.85) 3(-1.75,-5.37) 4(-1.25,-3.85) 5(-0.75,-5.37) 6(-0.25,-3.85) 7(0.25,-5.37) 8(0.75,-3.85) 9(1.25,-5.37) 10(1.75,-3.85) 11(2.25,-5.37) 12(2.75,-3.85) 25(2.75,5.37) 26(2.25,3.85) 27(1.75,5.37) 28(1.25,3.85) 29(0.75,5.37) 30(0.25,3.85) 31(-0.25,5.37) 32(-0.75,3.85) 33(-1.25,5.37) 34(-1.75,3.85) 35(-2.25,5.37) 36(-2.75,3.85)
  oval 1.3x0.5 hole 0.35: 13(5.37,-2.75) 14(3.85,-2.25) 15(5.37,-1.75) 16(3.85,-1.25) 17(5.37,-0.75) 18(3.85,-0.25) 19(5.37,0.25) 20(3.85,0.75) 21(5.37,1.25) 22(3.85,1.75) 23(5.37,2.25) 24(3.85,2.75) 37(-5.37,2.75) 38(-3.85,2.25) 39(-5.37,1.75) 40(-3.85,1.25) 41(-5.37,0.75) 42(-3.85,0.25) 43(-5.37,-0.25) 44(-3.85,-0.75) 45(-5.37,-1.25) 46(-3.85,-1.75) 47(-5.37,-2.25) 48(-3.85,-2.75)
  round 3 hole 2.3: 49(0,0)
Top Overlay:
  lines w0.2: -10.31,-13.585 -5.55,-13.585 -5.55,-14.085 5.55,-14.085 5.55,-13.585 10.31,-13.585 10.31,14.155 -10.31,14.155 -10.31,-13.585
M13_Assembly_Info:
  lines w0.1: -8.66,8.905 -5.26,8.905 -5.26,13.795 -8.66,13.795 ; -5.4,-13.43 -8.66,-13.43 -8.66,-8.13 -10.16,-8.13 -10.16,8.7 -8.66,8.7 ; -5.4,-11.975 5.4,-11.975 ; -5.26,9.875 -1.5,9.875 ; -5.26,12.875 -1.5,12.875 ; 1.5,9.87 5.26,9.87 ; 1.5,12.87 5.26,12.87 ; 5.4,-13.43 8.66,-13.43 8.66,-8.13 10.16,-8.13 10.16,8.7 8.66,8.7 ; 8.66,8.905 5.26,8.905 5.26,13.795 8.66,13.795 ; -9.39,-11.93 -10.16,-11.93 -10.16,-9.63 -9.39,-9.63 ; -9.39,-11.93 -8.86,-13.28 -8.76,-13.28 -8.76,-8.28 -8.86,-8.28 -9.39,-9.63 ; -9.39,-11.93 -9.39,-9.63 ; -9.39,10.2 -8.86,8.85 -8.76,8.85 -8.76,13.85 -8.86,13.85 -9.39,12.5 ; -9.39,10.2 -10.16,10.2 -10.16,12.5 -9.39,12.5 ; -9.39,10.2 -9.39,12.5 ; -8.66,8.7 -8.66,14 8.66,14 8.66,8.7 ; -8.66,8.7 8.66,8.7 ; 9.39,-11.93 10.16,-11.93 10.16,-9.63 9.39,-9.63 ; 9.39,-11.93 8.86,-13.28 8.76,-13.28 8.76,-8.28 8.86,-8.28 9.39,-9.63 ; 9.39,-11.93 9.39,-9.63 ; 9.39,10.2 9.39,12.5 ; 9.39,10.2 10.16,10.2 10.16,12.5 9.39,12.5 ; 9.39,10.2 8.86,8.85 8.76,8.85 8.76,13.85 8.86,13.85 9.39,12.5 ; -5.4,-13.93 5.4,-13.93 5.4,-11.23 -5.4,-11.23 -5.4,-13.93 ; -1.5,8.945 1.5,8.945 1.5,13.795 -1.5,13.795 -1.5,8.945
M15_Country_Yard:
  lines w0.1: -10.16,14 -10.16,22.89 10.16,22.89 ; 10.16,14 10.16,22.889

## SKT_S-MLF-00-048-E [mm] "Test & Burn socket for QFN-48 8x8mm; 0.5mm pitch; Load Boards only, pin No.1 rotated by 90 degrees"
height 15
pads (51):
  round 1.7 hole 1.7 unplated: 0(-6.225,6.225)
  round 1.4 hole 1.4 unplated: 0(6.225,-6.225)
  rect 0.55x1.2 hole 0.4: 1(-2.755,-4.435)
  oval 0.55x1.2 hole 0.4: 2(-2.255,-5.955) 3(-1.755,-4.435) 4(-1.255,-5.955) 5(-0.755,-4.435) 6(-0.255,-5.955) 7(0.245,-4.435) 8(0.745,-5.955) 9(1.245,-4.435) 10(1.745,-5.955) 11(2.245,-4.435) 12(2.745,-5.955) 25(2.75,4.435) 26(2.25,5.955) 27(1.75,4.435) 28(1.25,5.955) 29(0.75,4.435) 30(0.25,5.955) 31(-0.25,4.435) 32(-0.75,5.955) 33(-1.25,4.435) 34(-1.75,5.955) 35(-2.25,4.435) 36(-2.75,5.955)
  oval 1.2x0.55 hole 0.4: 13(4.435,-2.75) 14(5.955,-2.25) 15(4.435,-1.75) 16(5.955,-1.25) 17(4.435,-0.75) 18(5.955,-0.25) 19(4.435,0.25) 20(5.955,0.75) 21(4.435,1.25) 22(5.955,1.75) 23(4.435,2.25) 24(5.955,2.75) 37(-4.43,2.75) 38(-5.95,2.25) 39(-4.43,1.75) 40(-5.95,1.25) 41(-4.43,0.75) 42(-5.95,0.25) 43(-4.43,-0.25) 44(-5.95,-0.75) 45(-4.43,-1.25) 46(-5.95,-1.75) 47(-4.43,-2.25) 48(-5.95,-2.75)
  round 2 hole 1.2: 49(0,0)
Top Overlay:
  lines w0.2: -6,-13.715 -6,-14.707 6,-14.707 6,-13.715 ; -10.16,-13.715 10.16,-13.715 10.16,13.715 -10.16,13.715 -10.16,-13.715
M13_Assembly_Info:
  lines w0.1: -10.16,-13.715 10.16,-13.715 10.16,13.715 -10.16,13.715 -10.16,-13.715
M15_Country_Yard:
  lines w0.1: -10.16,13.715 -10.16,22.604 10.16,22.604 10.16,13.715
3D body: height 20, standoff 0, extent -10.15,-13.7 10.15,13.7

## SKT_S-MLF-00-048-E - 90deg [mm] "Test & Burn socket for QFN-48 8x8mm; 0.5mm pitch; Load Boards only, pin No.1 rotated by 90 degrees"
height 15
pads (51):
  round 1.7 hole 1.7 unplated: 0(-6.225,6.225)
  round 1.4 hole 1.4 unplated: 0(6.225,-6.225)
  rect 1.2x0.55 hole 0.4: 1(-4.43,2.75)
  oval 1.2x0.55 hole 0.4: 2(-5.95,2.25) 3(-4.43,1.75) 4(-5.95,1.25) 5(-4.43,0.75) 6(-5.95,0.25) 7(-4.43,-0.25) 8(-5.95,-0.75) 9(-4.43,-1.25) 10(-5.95,-1.75) 11(-4.43,-2.25) 12(-5.95,-2.75) 25(4.435,-2.75) 26(5.955,-2.25) 27(4.435,-1.75) 28(5.955,-1.25) 29(4.435,-0.75) 30(5.955,-0.25) 31(4.435,0.25) 32(5.955,0.75) 33(4.435,1.25) 34(5.955,1.75) 35(4.435,2.25) 36(5.955,2.75)
  oval 0.55x1.2 hole 0.4: 13(-2.755,-4.435) 14(-2.255,-5.955) 15(-1.755,-4.435) 16(-1.255,-5.955) 17(-0.755,-4.435) 18(-0.255,-5.955) 19(0.245,-4.435) 20(0.745,-5.955) 21(1.245,-4.435) 22(1.745,-5.955) 23(2.245,-4.435) 24(2.745,-5.955) 37(2.75,4.435) 38(2.25,5.955) 39(1.75,4.435) 40(1.25,5.955) 41(0.75,4.435) 42(0.25,5.955) 43(-0.25,4.435) 44(-0.75,5.955) 45(-1.25,4.435) 46(-1.75,5.955) 47(-2.25,4.435) 48(-2.75,5.955)
  round 2 hole 1.2: 49(0,0)
Top Overlay:
  lines w0.2: -6,-13.715 -6,-14.707 6,-14.707 6,-13.715 ; -10.16,-13.715 -10.16,13.715 10.16,13.715 10.16,-13.715 -10.16,-13.715
M13_Assembly_Info:
  lines w0.1: -10.16,-13.715 -10.16,13.715 10.16,13.715 10.16,-13.715 -10.16,-13.715
M15_Country_Yard:
  lines w0.1: -10.16,13.715 -10.16,22.604 10.16,22.604 10.16,13.715
3D body: height 20, standoff 0, extent -10.15,-13.7 10.15,13.7

## SKT_S-MLF-00-064-A [mm] "Test & Burn socket for QFN-64"
height 15
pads (67):
  round 1.7 hole 1.7 unplated: 0(-6.225,6.225)
  round 1.3 hole 1.3 unplated: 0(6.225,-6.225)
  rect 1.2x0.5 hole 0.4: 1(-6.375,3.75)
  oval 1.2x0.5 hole 0.4: 2(-4.85,3.25) 3(-6.375,2.75) 4(-4.85,2.25) 5(-6.375,1.75) 6(-4.85,1.25) 7(-6.375,0.75) 8(-4.85,0.25) 9(-6.375,-0.25) 10(-4.85,-0.75) 11(-6.375,-1.25) 12(-4.85,-1.75) 13(-6.375,-2.25) 14(-4.85,-2.75) 15(-6.375,-3.25) 16(-4.85,-3.75) 33(6.375,-3.75) 34(4.85,-3.25) 35(6.375,-2.75) 36(4.85,-2.25) 37(6.375,-1.75) 38(4.85,-1.25) 39(6.375,-0.75) 40(4.85,-0.25) 41(6.375,0.25) 42(4.85,0.75) 43(6.375,1.25) 44(4.85,1.75) 45(6.375,2.25) 46(4.85,2.75) 47(6.375,3.25) 48(4.85,3.75)
  oval 0.5x1.2 hole 0.4: 17(-3.75,-6.375) 18(-3.25,-4.85) 19(-2.75,-6.375) 20(-2.25,-4.85) 21(-1.75,-6.375) 22(-1.25,-4.85) 23(-0.75,-6.375) 24(-0.25,-4.85) 25(0.25,-6.375) 26(0.75,-4.85) 27(1.25,-6.375) 28(1.75,-4.85) 29(2.25,-6.375) 30(2.75,-4.85) 31(3.25,-6.375) 32(3.75,-4.85) 49(3.75,6.375) 50(3.25,4.85) 51(2.75,6.375) 52(2.25,4.85) 53(1.75,6.375) 54(1.25,4.85) 55(0.75,6.375) 56(0.25,4.85) 57(-0.25,6.375) 58(-0.75,4.85) 59(-1.25,6.375) 60(-1.75,4.85) 61(-2.25,6.375) 62(-2.75,4.85) 63(-3.25,6.375) 64(-3.75,4.85)
  round 3.2 hole 2.2: 65(0,0)
Top Overlay:
  lines w0.2: -10.31,-13.87 -10.31,13.87 10.31,13.87 10.31,-13.87 5.55,-13.87 5.55,-14.37 -5.55,-14.37 -5.55,-13.87 -10.31,-13.87
M13_Assembly_Info:
  lines w0.1: -8.66,8.62 -5.26,8.62 -5.26,13.51 -8.66,13.51 ; -5.4,-13.715 -8.66,-13.715 -8.66,-8.415 -10.16,-8.415 -10.16,8.415 -8.66,8.415 ; -5.4,-12.26 5.4,-12.26 ; -5.26,9.59 -1.5,9.59 ; -5.26,12.59 -1.5,12.59 ; 1.5,9.585 5.26,9.585 ; 1.5,12.585 5.26,12.585 ; 5.4,-13.715 8.66,-13.715 8.66,-8.415 10.16,-8.415 10.16,8.415 8.66,8.415 ; 8.66,8.62 5.26,8.62 5.26,13.51 8.66,13.51 ; -9.39,-12.215 -9.39,-9.915 ; -9.39,-12.215 -8.86,-13.565 -8.76,-13.565 -8.76,-8.565 -8.86,-8.565 -9.39,-9.915 ; -9.39,-12.215 -10.16,-12.215 -10.16,-9.915 -9.39,-9.915 ; -9.39,9.915 -9.39,12.215 ; -9.39,9.915 -10.16,9.915 -10.16,12.215 -9.39,12.215 ; -9.39,9.915 -8.86,8.565 -8.76,8.565 -8.76,13.565 -8.86,13.565 -9.39,12.215 ; -8.66,8.415 8.66,8.415 ; -8.66,8.415 -8.66,13.715 8.66,13.715 8.66,8.415 ; 9.39,-12.215 9.39,-9.915 ; 9.39,-12.215 8.86,-13.565 8.76,-13.565 8.76,-8.565 8.86,-8.565 9.39,-9.915 ; 9.39,-12.215 10.16,-12.215 10.16,-9.915 9.39,-9.915 ; 9.39,9.915 8.86,8.565 8.76,8.565 8.76,13.565 8.86,13.565 9.39,12.215 ; 9.39,9.915 10.16,9.915 10.16,12.215 9.39,12.215 ; 9.39,9.915 9.39,12.215 ; -5.4,-14.215 -5.4,-11.515 5.4,-11.515 5.4,-14.215 -5.4,-14.215 ; -1.5,8.66 -1.5,13.51 1.5,13.51 1.5,8.66 -1.5,8.66
M15_Country_Yard:
  lines w0.1: -10.16,13.715 -10.16,22.605 10.16,22.605 ; 10.16,13.715 10.16,22.604

## SKT_S-MLF-00-064-B [mm] "Test & Burn socket for QFN-64"
height 15
pads (67):
  round 1.7 hole 1.7: 0(-6.225,6.225)
  round 1.3 hole 1.3: 0(6.225,-6.225)
  rect 0.5x1.2 hole 0.35: 1(-3,-4.405)
  oval 0.5x1.2 hole 0.35: 2(-2.6,-5.925) 3(-2.2,-4.405) 4(-1.8,-5.925) 5(-1.4,-4.405) 6(-1,-5.925) 7(-0.6,-4.405) 8(-0.2,-5.925) 9(0.2,-4.405) 10(0.6,-5.925) 11(1,-4.405) 12(1.4,-5.925) 13(1.8,-4.405) 14(2.2,-5.925) 15(2.6,-4.405) 16(3,-5.925) 33(3,4.406) 34(2.6,5.93) 35(2.2,4.406) 36(1.8,5.93) 37(1.4,4.406) 38(1,5.93) 39(0.6,4.406) 40(0.2,5.93) 41(-0.2,4.406) 42(-0.6,5.93) 43(-1,4.406) 44(-1.4,5.93) 45(-1.8,4.406) 46(-2.2,5.93) 47(-2.6,4.406) 48(-3,5.93)
  oval 1.2x0.5 hole 0.35: 17(4.412,-2.995) 18(5.932,-2.595) 19(4.412,-2.195) 20(5.932,-1.795) 21(4.412,-1.395) 22(5.932,-0.995) 23(4.412,-0.595) 24(5.932,-0.195) 25(4.412,0.205) 26(5.932,0.605) 27(4.412,1.005) 28(5.932,1.405) 29(4.412,1.805) 30(5.932,2.205) 31(4.412,2.605) 32(5.932,3.005) 49(-4.404,3) 50(-5.93,2.6) 51(-4.404,2.2) 52(-5.93,1.8) 53(-4.404,1.4) 54(-5.93,1) 55(-4.404,0.6) 56(-5.93,0.2) 57(-4.404,-0.2) 58(-5.93,-0.6) 59(-4.404,-1) 60(-5.93,-1.4) 61(-4.404,-1.8) 62(-5.93,-2.2) 63(-4.404,-2.6) 64(-5.93,-3)
  round 2.5 hole 1.2: 65(0,0)
Top Overlay:
  lines w0.2: -6,-13.715 -6,-14.707 6,-14.707 6,-13.715 ; -10.16,-13.715 -10.16,13.715 10.16,13.715 10.16,-13.715 -10.16,-13.715
M13_Assembly_Info:
  lines w0.1: -10.16,-13.715 -10.16,13.715 10.16,13.715 10.16,-13.715 -10.16,-13.715
M15_Country_Yard:
  lines w0.1: -10.16,13.715 -10.16,22.604 10.16,22.604 10.16,13.715

## SKT_S-QFP-00-044-F [mm] "Test & Burn socket for QFP-44, 0.8mm pitch, 10x10mm body. Emulation Technology; S-QFP-00-044-F"
height 17
pads (48):
  round 3.2 hole 3.2 unplated: 0(-12,-11.5) 0(-12,11.5) 0(12,-11.5) 0(12,11.5)
  rect 0.9x2.2 hole 0.7: 1(-4,-11.5)
  oval 0.9x2.2 hole 0.7: 2(-3.2,-6.5) 3(-2.4,-11.5) 4(-1.6,-6.5) 5(-0.8,-11.5) 6(0,-6.5) 7(0.8,-11.5) 8(1.6,-6.5) 9(2.4,-11.5) 10(3.2,-6.5) 11(4,-11.5) 23(4,11.5) 24(3.2,6.5) 25(2.4,11.5) 26(1.6,6.5) 27(0.8,11.5) 28(0,6.5) 29(-0.8,11.5) 30(-1.6,6.5) 31(-2.4,11.5) 32(-3.2,6.5) 33(-4,11.5)
  oval 2.2x0.9 hole 0.7: 12(11.5,-4) 13(6.5,-3.2) 14(11.5,-2.4) 15(6.5,-1.6) 16(11.5,-0.8) 17(6.5,0) 18(11.5,0.8) 19(6.5,1.6) 20(11.5,2.4) 21(6.5,3.2) 22(11.5,4) 34(-11.5,4) 35(-6.5,3.2) 36(-11.5,2.4) 37(-6.5,1.6) 38(-11.5,0.8) 39(-6.5,0) 40(-11.5,-0.8) 41(-6.5,-1.6) 42(-11.5,-2.4) 43(-6.5,-3.2) 44(-11.5,-4)
Top Overlay:
  lines w0.2: -7.501,-21.65 -7.501,-23 7.499,-23 7.499,-21.65 ; -16.65,-21.65 -16.65,21.65 16.65,21.65 16.65,-21.65 -16.65,-21.65
M13_Assembly_Info:
  lines w0.1: -16.5,-21.5 -16.5,21.5 16.5,21.5 16.5,-21.5 -16.5,-21.5
M15_Country_Yard:
  lines w0.1: -0.5,0 0.5,0 ; 0,-0.5 0,0.5

## SKT_S-QFP-00-256-C [mm] "256 pin; LQFP Burn-in socket; Emulation Technology"
height 20.1
pads (260):
  round 3.2 hole 3.2 unplated: 0(-22,-22) 0(-22,22) 0(22,-22) 0(22,22)
  rect 1x1.4 hole 0.7: 1(-12.6,-15.9)
  oval 1x1.4 hole 0.7: 2(-12.2,-18.44) 3(-11.8,-20.98) 4(-11.4,-23.52) 5(-11,-15.9) 6(-10.6,-18.44) 7(-10.2,-20.98) 8(-9.8,-23.52) 9(-9.4,-15.9) 10(-9,-18.44) 11(-8.6,-20.98) 12(-8.2,-23.52) 13(-7.8,-15.9) 14(-7.4,-18.44) 15(-7,-20.98) 16(-6.6,-23.52) 17(-6.2,-15.9) 18(-5.8,-18.44) 19(-5.4,-20.98) 20(-5,-23.52) 21(-4.6,-15.9) 22(-4.2,-18.44) 23(-3.8,-20.98) 24(-3.4,-23.52) 25(-3,-15.9) 26(-2.6,-18.44) 27(-2.2,-20.98) 28(-1.8,-23.52) 29(-1.4,-15.9) 30(-1,-18.44) 31(-0.6,-20.98) 32(-0.2,-23.52) 33(0.2,-15.9) 34(0.6,-18.44) 35(1,-20.98) 36(1.4,-23.52) 37(1.8,-15.9) 38(2.2,-18.44) 39(2.6,-20.98) 40(3,-23.52) 41(3.4,-15.9) 42(3.8,-18.44) 43(4.2,-20.98) 44(4.6,-23.52) 45(5,-15.9) 46(5.4,-18.44) 47(5.8,-20.98) 48(6.2,-23.52) 49(6.6,-15.9) 50(7,-18.44) 51(7.4,-20.98) 52(7.8,-23.52) 53(8.2,-15.9) 54(8.6,-18.44) 55(9,-20.98) 56(9.4,-23.52) 57(9.8,-15.9) 58(10.2,-18.44) 59(10.6,-20.98) 60(11,-23.52) 61(11.4,-15.9) 62(11.8,-18.44) 63(12.2,-20.98) 64(12.6,-23.52) 129(12.6,15.9) 130(12.2,18.44) 131(11.8,20.98) 132(11.4,23.52) 133(11,15.9) 134(10.6,18.44) 135(10.2,20.98) 136(9.8,23.52) 137(9.4,15.9) 138(9,18.44) 139(8.6,20.98) 140(8.2,23.52) 141(7.8,15.9) 142(7.4,18.44) 143(7,20.98) 144(6.6,23.52) 145(6.2,15.9) 146(5.8,18.44) 147(5.4,20.98) 148(5,23.52) 149(4.6,15.9) 150(4.2,18.44) 151(3.8,20.98) 152(3.4,23.52) 153(3,15.9) 154(2.6,18.44) 155(2.2,20.98) 156(1.8,23.52) 157(1.4,15.9) 158(1,18.44) 159(0.6,20.98) 160(0.2,23.52) 161(-0.2,15.9) 162(-0.6,18.44) 163(-1,20.98) 164(-1.4,23.52) 165(-1.8,15.9) 166(-2.2,18.44) 167(-2.6,20.98) 168(-3,23.52) 169(-3.4,15.9) 170(-3.8,18.44) 171(-4.2,20.98) 172(-4.6,23.52) 173(-5,15.9) 174(-5.4,18.44) 175(-5.8,20.98) 176(-6.2,23.52) 177(-6.6,15.9) 178(-7,18.44) 179(-7.4,20.98) 180(-7.8,23.52) 181(-8.2,15.9) 182(-8.6,18.44) 183(-9,20.98) 184(-9.4,23.52) 185(-9.8,15.9) 186(-10.2,18.44) 187(-10.6,20.98) 188(-11,23.52) 189(-11.4,15.9) 190(-11.8,18.44) 191(-12.2,20.98) 192(-12.6,23.52)
  oval 1.4x1 hole 0.7: 65(15.9,-12.6) 66(18.44,-12.2) 67(20.98,-11.8) 68(23.52,-11.4) 69(15.9,-11) 70(18.44,-10.6) 71(20.98,-10.2) 72(23.52,-9.8) 73(15.9,-9.4) 74(18.44,-9) 75(20.98,-8.6) 76(23.52,-8.2) 77(15.9,-7.8) 78(18.44,-7.4) 79(20.98,-7) 80(23.52,-6.6) 81(15.9,-6.2) 82(18.44,-5.8) 83(20.98,-5.4) 84(23.52,-5) 85(15.9,-4.6) 86(18.44,-4.2) 87(20.98,-3.8) 88(23.52,-3.4) 89(15.9,-3) 90(18.44,-2.6) 91(20.98,-2.2) 92(23.52,-1.8) 93(15.9,-1.4) 94(18.44,-1) 95(20.98,-0.6) 96(23.52,-0.2) 97(15.9,0.2) 98(18.44,0.6) 99(20.98,1) 100(23.52,1.4) 101(15.9,1.8) 102(18.44,2.2) 103(20.98,2.6) 104(23.52,3) 105(15.9,3.4) 106(18.44,3.8) 107(20.98,4.2) 108(23.52,4.6) 109(15.9,5) 110(18.44,5.4) 111(20.98,5.8) 112(23.52,6.2) 113(15.9,6.6) 114(18.44,7) 115(20.98,7.4) 116(23.52,7.8) 117(15.9,8.2) 118(18.44,8.6) 119(20.98,9) 120(23.52,9.4) 121(15.9,9.8) 122(18.44,10.2) 123(20.98,10.6) 124(23.52,11) 125(15.9,11.4) 126(18.44,11.8) 127(20.98,12.2) 128(23.52,12.6) 193(-15.9,12.6) 194(-18.44,12.2) 195(-20.98,11.8) 196(-23.52,11.4) 197(-15.9,11) 198(-18.44,10.6) 199(-20.98,10.2) 200(-23.52,9.8) 201(-15.9,9.4) 202(-18.44,9) 203(-20.98,8.6) 204(-23.52,8.2) 205(-15.9,7.8) 206(-18.44,7.4) 207(-20.98,7) 208(-23.52,6.6) 209(-15.9,6.2) 210(-18.44,5.8) 211(-20.98,5.4) 212(-23.52,5) 213(-15.9,4.6) 214(-18.44,4.2) 215(-20.98,3.8) 216(-23.52,3.4) 217(-15.9,3) 218(-18.44,2.6) 219(-20.98,2.2) 220(-23.52,1.8) 221(-15.9,1.4) 222(-18.44,1) 223(-20.98,0.6) 224(-23.52,0.2) 225(-15.9,-0.2) 226(-18.44,-0.6) 227(-20.98,-1) 228(-23.52,-1.4) 229(-15.9,-1.8) 230(-18.44,-2.2) 231(-20.98,-2.6) 232(-23.52,-3) 233(-15.9,-3.4) 234(-18.44,-3.8) 235(-20.98,-4.2) 236(-23.52,-4.6) 237(-15.9,-5) 238(-18.44,-5.4) 239(-20.98,-5.8) 240(-23.52,-6.2) 241(-15.9,-6.6) 242(-18.44,-7) 243(-20.98,-7.4) 244(-23.52,-7.8) 245(-15.9,-8.2) 246(-18.44,-8.6) 247(-20.98,-9) 248(-23.52,-9.4) 249(-15.9,-9.8) 250(-18.44,-10.2) 251(-20.98,-10.6) 252(-23.52,-11) 253(-15.9,-11.4) 254(-18.44,-11.8) 255(-20.98,-12.2) 256(-23.52,-12.6)
Top Overlay:
  lines w0.2: -28,-35 -28,34.5 28,34.5 28,-35 -28,-35
M15_Country_Yard:
  lines w0.1: -0.5,0 0.5,0 ; 0,-0.5 0,0.5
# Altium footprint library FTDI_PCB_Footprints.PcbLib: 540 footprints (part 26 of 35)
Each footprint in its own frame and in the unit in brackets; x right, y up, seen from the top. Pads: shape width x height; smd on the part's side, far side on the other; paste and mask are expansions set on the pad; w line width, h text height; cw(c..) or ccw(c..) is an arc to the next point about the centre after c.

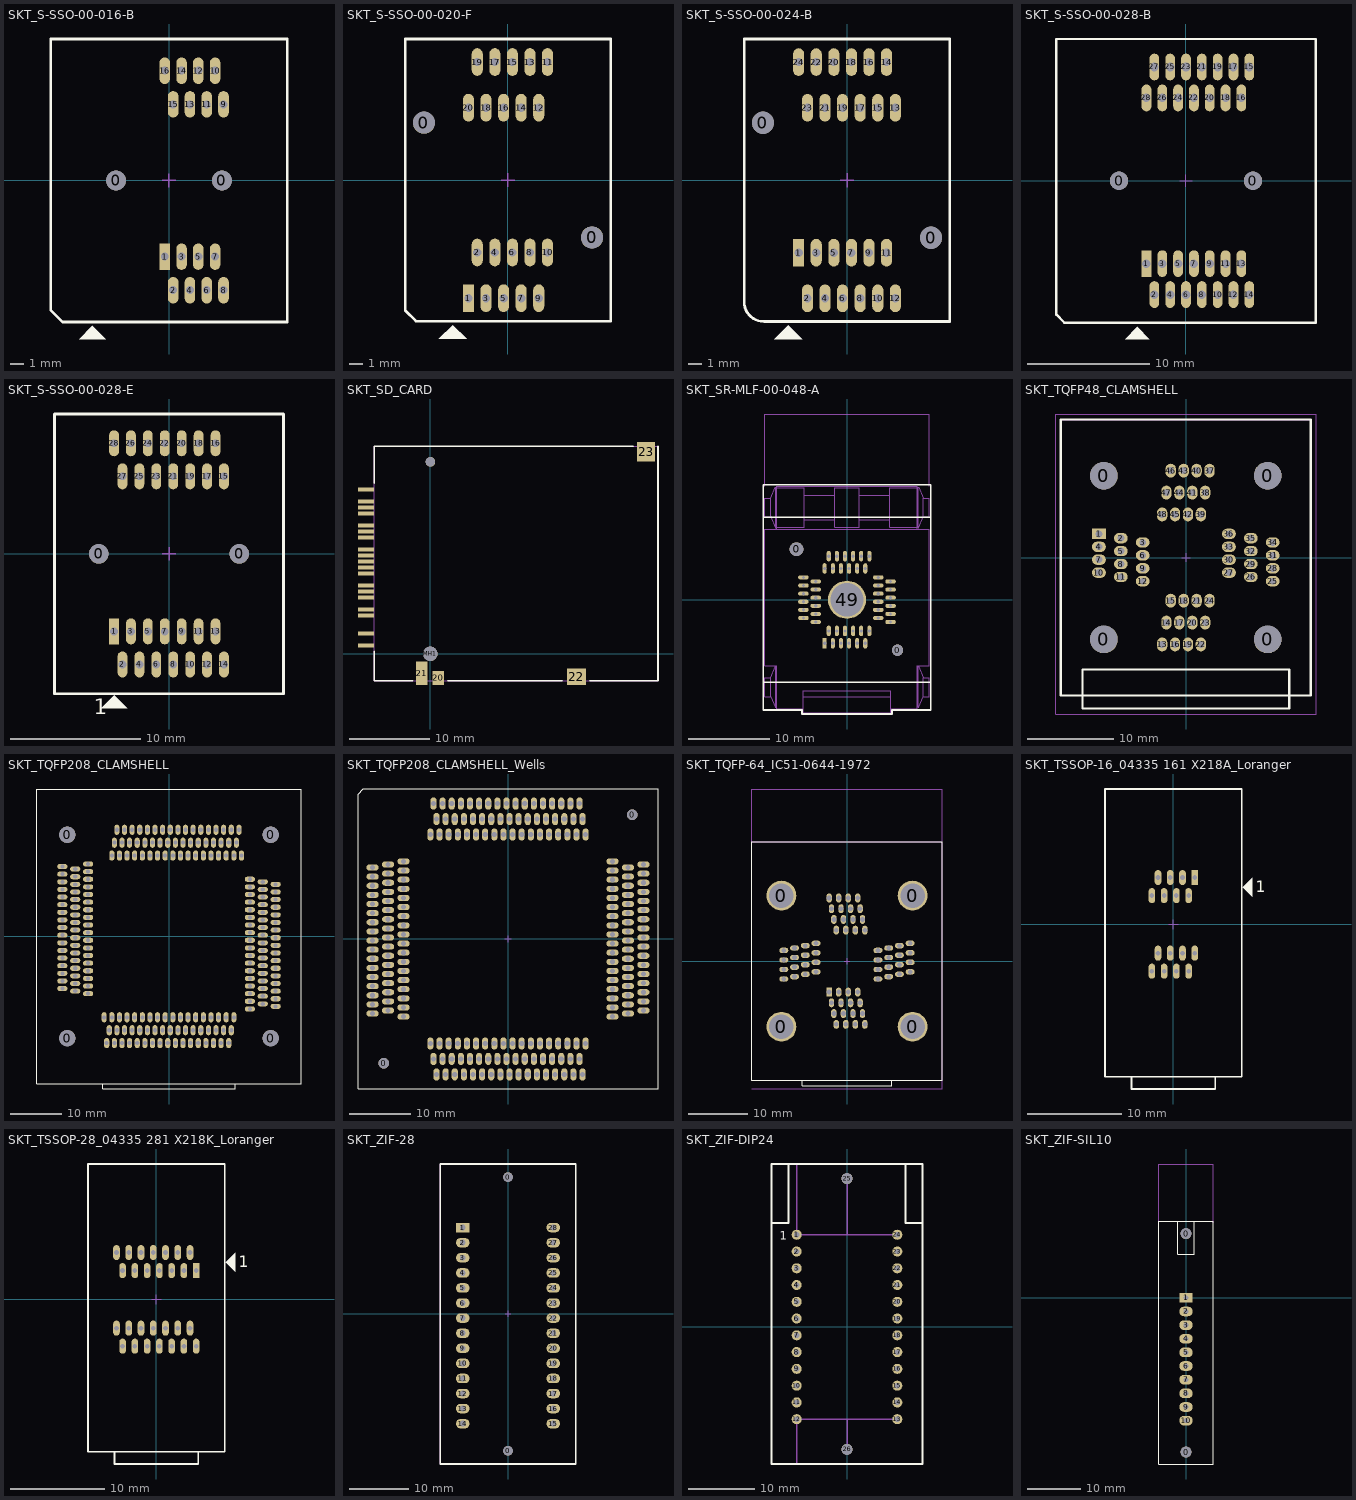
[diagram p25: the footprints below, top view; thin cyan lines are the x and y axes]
## SKT_S-SSO-00-016-B [mm] "Open Top Socket 16PIN SSOP; 0.635mm pitch; Emulation Technology; S-SSO-00-016-B"
height 13.6
pads (18):
  round 1.5 hole 1.5 unplated: 0(-4,0) 0(4,0)
  rect 0.8x2 hole 0.6: 1(-0.321,-5.759)
  oval 0.8x2 hole 0.6: 2(0.314,-8.3) 3(0.949,-5.759) 4(1.584,-8.3) 5(2.219,-5.759) 6(2.854,-8.3) 7(3.489,-5.759) 8(4.124,-8.3) 9(4.124,5.76) 10(3.489,8.301) 11(2.854,5.76) 12(2.219,8.301) 13(1.584,5.76) 14(0.949,8.301) 15(0.314,5.76) 16(-0.321,8.301)
Top Overlay:
  region: -5.8,-10.99 -4.8,-11.99 -6.8,-11.99
  lines w0.2: -8.95,-9.81 -8.95,10.7 8.95,10.7 8.95,-10.7 -8.06,-10.7 -8.95,-9.81
M15_Country_Yard:
  lines w0.1: -0.5,0 0.5,0 ; 0,-0.5 0,0.5

## SKT_S-SSO-00-020-F [mm] "Open Top Socket 20PIN SSOP; 0.635mm pitch; Emulation Technology; S-SSO-00-020-F"
height 13.6
pads (22):
  round 1.6 hole 1.6 unplated: 0(-6.075,4.15) 0(6.075,-4.15)
  rect 0.8x2 hole 0.6: 1(-2.857,-8.535)
  oval 0.8x2 hole 0.6: 2(-2.222,-5.235) 3(-1.587,-8.535) 4(-0.953,-5.235) 5(-0.318,-8.535) 6(0.318,-5.235) 7(0.953,-8.535) 8(1.587,-5.235) 9(2.222,-8.535) 10(2.857,-5.235) 11(2.857,8.535) 12(2.222,5.235) 13(1.587,8.535) 14(0.953,5.235) 15(0.318,8.535) 16(-0.318,5.235) 17(-0.953,8.535) 18(-1.587,5.235) 19(-2.222,8.535) 20(-2.857,5.235)
Top Overlay:
  region: -4,-10.49 -3,-11.49 -5,-11.49
  lines w0.2: -7.43,-9.42 -6.65,-10.2 7.43,-10.2 7.43,10.2 -7.43,10.2 -7.43,-9.42
M15_Country_Yard:
  lines w0.1: -0.5,0 0.5,0 ; 0,-0.5 0,0.5

## SKT_S-SSO-00-024-B [mm] "Open Top Socket 24PIN SSOP; 0.635mm pitch; Emulation Technology; S-SSO-00-024-B"
height 13.59
pads (26):
  round 1.6 hole 1.6 unplated: 0(-6.07,4.155) 0(6.07,-4.155)
  rect 0.8x2 hole 0.6: 1(-3.492,-5.23)
  oval 0.8x2 hole 0.6: 2(-2.857,-8.535) 3(-2.222,-5.23) 4(-1.587,-8.535) 5(-0.953,-5.23) 6(-0.318,-8.535) 7(0.318,-5.23) 8(0.953,-8.535) 9(1.587,-5.23) 10(2.222,-8.535) 11(2.857,-5.23) 12(3.492,-8.535) 13(3.492,5.23) 14(2.857,8.535) 15(2.222,5.23) 16(1.587,8.535) 17(0.953,5.23) 18(0.318,8.535) 19(-0.318,5.23) 20(-0.953,8.535) 21(-1.587,5.23) 22(-2.222,8.535) 23(-2.857,5.23) 24(-3.492,8.535)
Top Overlay:
  region: -4.25,-10.47 -3.25,-11.47 -5.25,-11.47
  lines w0.2: -7.43,-8.78 ccw(c-6,-8.78) -6,-10.21 -5.19,-10.21 7.43,-10.21 7.43,10.2 -7.43,10.2 -7.43,-8.78
M15_Country_Yard:
  lines w0.1: -0.5,0 0.5,0 ; 0,-0.5 0,0.5

## SKT_S-SSO-00-028-B [mm] "Open Top Socket 28PIN SSOP; 0.65mm pitch; Emulation Technology; S-SSO-00-028-B"
height 20
pads (30):
  round 1.5 hole 1.5 unplated: 0(-5.5,0) 0(5.5,0)
  rect 0.8x2.2 hole 0.7: 1(-3.25,-6.81)
  oval 0.8x2.2 hole 0.7: 2(-2.6,-9.35) 3(-1.95,-6.81) 4(-1.3,-9.35) 5(-0.65,-6.81) 6(0,-9.35) 7(0.65,-6.81) 8(1.3,-9.35) 9(1.95,-6.81) 10(2.6,-9.35) 11(3.25,-6.81) 12(3.9,-9.35) 13(4.55,-6.81) 14(5.2,-9.35) 15(5.2,9.35) 16(4.55,6.81) 17(3.9,9.35) 18(3.25,6.81) 19(2.6,9.35) 20(1.95,6.81) 21(1.3,9.35) 22(0.65,6.81) 23(0,9.35) 24(-0.65,6.81) 25(-1.3,9.35) 26(-1.95,6.81) 27(-2.6,9.35) 28(-3.25,6.81)
Top Overlay:
  region: -4,-12 -3,-13 -5,-13
  lines w0.2: -10.65,-11 -10,-11.65 10.65,-11.65 10.65,11.65 -10.65,11.65 -10.65,-11
M15_Country_Yard:
  lines w0.1: -0.5,0 0.5,0 ; 0,-0.5 0,0.5

## SKT_S-SSO-00-028-E [mm] "Open Top Socket 28PIN SSOP; 0.65mm pitch; Emulation Technology; S-SSO-00-028-E"
height 20
pads (30):
  round 1.5 hole 1.5 unplated: 0(-5.4,0) 0(5.4,0)
  rect 0.75x2 hole 0.6: 1(-4.225,-5.96)
  oval 0.75x2 hole 0.6: 2(-3.575,-8.5) 3(-2.925,-5.96) 4(-2.275,-8.5) 5(-1.625,-5.96) 6(-0.975,-8.5) 7(-0.325,-5.96) 8(0.325,-8.5) 9(0.975,-5.96) 10(1.625,-8.5) 11(2.275,-5.96) 12(2.925,-8.5) 13(3.575,-5.96) 14(4.225,-8.5) 15(4.225,5.96) 16(3.575,8.5) 17(2.925,5.96) 18(2.275,8.5) 19(1.625,5.96) 20(0.975,8.5) 21(0.325,5.96) 22(-0.325,8.5) 23(-0.975,5.96) 24(-1.625,8.5) 25(-2.275,5.96) 26(-2.925,8.5) 27(-3.575,5.96) 28(-4.225,8.5)
Top Overlay:
  region: -4.22,-10.86 -3.22,-11.86 -5.22,-11.86
  lines w0.2: -8.8,-10.75 8.8,-10.75 8.8,10.75 -8.8,10.75 -8.8,-10.75
  text "1" at -5.8,-12.31 h1.2
M15_Country_Yard:
  lines w0.1: -0.5,0 0.5,0 ; 0,-0.5 0,0.5

## SKT_SD_CARD [mm]
height 4.5
pads (25):
  rect 2x0.5 smd: 1(-8.05,5.56) 2(-8.05,7.06) 3(-8.05,8.56) 4(-8.05,10.06) 5(-8.05,11.555) 6(-8.05,13.06) 7(-8.05,14.56) 8(-8.05,16.06) 9(-8.05,17.56) 10(-8.05,19.06) 11(-8.05,18.31) 12(-8.05,15.31) 13(-8.05,12.31) 14(-8.05,10.81) 15(-8.05,7.808) 16(-8.05,4.81) 17(-8.05,2.56) 18(-8.05,1.055) 19(-8.05,20.56)
  rect 1.4x1.76 smd: 20(0.97,-3)
  rect 1.4x2.9 smd: 21(-1.075,-2.425)
  rect 2.4x2.06 smd: 22(18.26,-2.85)
  rect 2.28x2.48 smd: 23(26.96,25.27)
  round 1.8 hole 1.8 unplated: MH1(0,0)
  round 1.2 hole 1.2 unplated: MH2(0,24)
Top Overlay:
  lines w0.2: -7,0.3 -7,-3.375 -2.2,-3.375 ; -7,21.3 -7,25.925 25.35,25.925 ; 2.2,-3.375 16.5,-3.375 ; 19.9,-3.375 28.45,-3.375 28.45,25.925
M13_Assembly_Info:
  lines w0.1: -7,-3.38 28.45,-3.38 28.45,25.92 -7,25.92 -7,-3.38
3D body: height 4.5, standoff 0, extent -7,-3.38 28.45,25.92

## SKT_SR-MLF-00-048-A [mm] "Test & Burn receptcle for asocket for QFN-48"
height 15
pads (51):
  round 1.7 hole 1.7: 0(-6.225,6.225)
  round 1.4 hole 1.4: 0(6.225,-6.225)
  rect 0.5x1.3 hole 0.4: 1(-2.75,-5.37)
  oval 0.5x1.3 hole 0.4: 2(-2.25,-3.85) 3(-1.75,-5.37) 4(-1.25,-3.85) 5(-0.75,-5.37) 6(-0.25,-3.85) 7(0.25,-5.37) 8(0.75,-3.85) 9(1.25,-5.37) 10(1.75,-3.85) 11(2.25,-5.37) 12(2.75,-3.85) 25(2.75,5.37) 26(2.25,3.85) 27(1.75,5.37) 28(1.25,3.85) 29(0.75,5.37) 30(0.25,3.85) 31(-0.25,5.37) 32(-0.75,3.85) 33(-1.25,5.37) 34(-1.75,3.85) 35(-2.25,5.37) 36(-2.75,3.85)
  oval 1.3x0.5 hole 0.4: 13(5.37,-2.75) 14(3.85,-2.25) 15(5.37,-1.75) 16(3.85,-1.25) 17(5.37,-0.75) 18(3.85,-0.25) 19(5.37,0.25) 20(3.85,0.75) 21(5.37,1.25) 22(3.85,1.75) 23(5.37,2.25) 24(3.85,2.75) 37(-5.37,2.75) 38(-3.85,2.25) 39(-5.37,1.75) 40(-3.85,1.25) 41(-5.37,0.75) 42(-3.85,0.25) 43(-5.37,-0.25) 44(-3.85,-0.75) 45(-5.37,-1.25) 46(-3.85,-1.75) 47(-5.37,-2.25) 48(-3.85,-2.75)
  round 4.7 hole 4.1: 49(0,0)
Top Overlay:
  lines w0.2: -10.312,-10.16 10.308,-10.16 ; -10.31,10.16 10.31,10.16 ; -10.31,-13.585 -5.55,-13.585 -5.55,-14.085 5.55,-14.085 5.55,-13.585 10.31,-13.585 10.31,14.155 -10.31,14.155 -10.31,-13.585
M13_Assembly_Info:
  lines w0.1: -8.66,8.905 -5.26,8.905 -5.26,13.795 -8.66,13.795 ; -5.4,-13.43 -8.66,-13.43 -8.66,-8.13 -10.16,-8.13 -10.16,8.7 -8.66,8.7 ; -5.4,-11.975 5.4,-11.975 ; -5.26,9.875 -1.5,9.875 ; -5.26,12.875 -1.5,12.875 ; 1.5,9.87 5.26,9.87 ; 1.5,12.87 5.26,12.87 ; 5.4,-13.43 8.66,-13.43 8.66,-8.13 10.16,-8.13 10.16,8.7 8.66,8.7 ; 8.66,8.905 5.26,8.905 5.26,13.795 8.66,13.795 ; -9.39,-11.93 -10.16,-11.93 -10.16,-9.63 -9.39,-9.63 ; -9.39,-11.93 -8.86,-13.28 -8.76,-13.28 -8.76,-8.28 -8.86,-8.28 -9.39,-9.63 ; -9.39,-11.93 -9.39,-9.63 ; -9.39,10.2 -8.86,8.85 -8.76,8.85 -8.76,13.85 -8.86,13.85 -9.39,12.5 ; -9.39,10.2 -10.16,10.2 -10.16,12.5 -9.39,12.5 ; -9.39,10.2 -9.39,12.5 ; -8.66,8.7 -8.66,14 8.66,14 8.66,8.7 ; -8.66,8.7 8.66,8.7 ; 9.39,-11.93 10.16,-11.93 10.16,-9.63 9.39,-9.63 ; 9.39,-11.93 8.86,-13.28 8.76,-13.28 8.76,-8.28 8.86,-8.28 9.39,-9.63 ; 9.39,-11.93 9.39,-9.63 ; 9.39,10.2 9.39,12.5 ; 9.39,10.2 10.16,10.2 10.16,12.5 9.39,12.5 ; 9.39,10.2 8.86,8.85 8.76,8.85 8.76,13.85 8.86,13.85 9.39,12.5 ; -5.4,-13.93 5.4,-13.93 5.4,-11.23 -5.4,-11.23 -5.4,-13.93 ; -1.5,8.945 1.5,8.945 1.5,13.795 -1.5,13.795 -1.5,8.945
M15_Country_Yard:
  lines w0.1: -10.16,14 -10.16,22.89 10.16,22.89 ; 10.16,14 10.16,22.889

## SKT_TQFP48_CLAMSHELL [mm] "YAMAICHI IC51-0484-806 WITH FIXING HOLES"
height 19
pads (52):
  round 3.2 hole 3.2 unplated: 0(-9.52,-9.5) 0(-9.52,9.5) 0(9.48,-9.5) 0(9.48,9.5)
  rect 1.6x1.2 hole 0.8: 1(-10.1,2.75)
  oval 1.6x1.2 hole 0.8: 2(-7.56,2.25) 3(-5.02,1.75) 4(-10.1,1.25) 5(-7.56,0.75) 6(-5.02,0.25) 7(-10.1,-0.25) 8(-7.56,-0.75) 9(-5.02,-1.25) 10(-10.1,-1.75) 11(-7.56,-2.25) 12(-5.02,-2.75) 25(10.06,-2.75) 26(7.52,-2.25) 27(4.98,-1.75) 28(10.06,-1.25) 29(7.52,-0.75) 30(4.98,-0.25) 31(10.06,0.25) 32(7.52,0.75) 33(4.98,1.25) 34(10.06,1.75) 35(7.52,2.25) 36(4.98,2.75)
  oval 1.2x1.6 hole 0.8: 13(-2.77,-10.08) 14(-2.27,-7.54) 15(-1.77,-5) 16(-1.27,-10.08) 17(-0.77,-7.54) 18(-0.27,-5) 19(0.23,-10.08) 20(0.73,-7.54) 21(1.23,-5) 22(1.73,-10.08) 23(2.23,-7.54) 24(2.73,-5) 37(2.73,10.08) 38(2.23,7.54) 39(1.73,5) 40(1.23,10.08) 41(0.73,7.54) 42(0.23,5) 43(-0.27,10.08) 44(-0.77,7.54) 45(-1.27,5) 46(-1.77,10.08) 47(-2.27,7.54) 48(-2.77,5)
Top Overlay:
  lines w0.25: -14.52,-16 -14.52,16 14.48,16 14.48,-16 -14.52,-16 ; -12.02,-17.5 -12.02,-13 11.98,-13 11.98,-17.5 -12.02,-17.5
Mechanical 10:
  lines w0.1: -14.52,-16 14.48,-16 14.48,16 -14.52,16 -14.52,-16
M15_Country_Yard:
  lines w0.1: -0.5,0 0.5,0 ; 0,-0.5 0,0.5 ; -15.1,-18.15 -15.1,16.65 15.1,16.65 15.1,-18.15 -15.1,-18.15

## SKT_TQFP208_CLAMSHELL [mm] "YAMAICHI IC51-2084-1052"
height 19
pads (212):
  round 3.2 hole 3.2 unplated: 0(-20,-20) 0(-20,20) 0(20,-20) 0(20,20)
  oval 1x2 hole 0.8: 1(-12.75,-15.9) 2(-12.25,-20.98) 3(-11.75,-18.44) 4(-11.25,-15.9) 5(-10.75,-20.98) 6(-10.25,-18.44) 7(-9.75,-15.9) 8(-9.25,-20.98) 9(-8.75,-18.44) 10(-8.25,-15.9) 11(-7.75,-20.98) 12(-7.25,-18.44) 13(-6.75,-15.9) 14(-6.25,-20.98) 15(-5.75,-18.44) 16(-5.25,-15.9) 17(-4.75,-20.98) 18(-4.25,-18.44) 19(-3.75,-15.9) 20(-3.25,-20.98) 21(-2.75,-18.44) 22(-2.25,-15.9) 23(-1.75,-20.98) 24(-1.25,-18.44) 25(-0.75,-15.9) 26(-0.25,-20.98) 27(0.25,-18.44) 28(0.75,-15.9) 29(1.25,-20.98) 30(1.75,-18.44) 31(2.25,-15.9) 32(2.75,-20.98) 33(3.25,-18.44) 34(3.75,-15.9) 35(4.25,-20.98) 36(4.75,-18.44) 37(5.25,-15.9) 38(5.75,-20.98) 39(6.25,-18.44) 40(6.75,-15.9) 41(7.25,-20.98) 42(7.75,-18.44) 43(8.25,-15.9) 44(8.75,-20.98) 45(9.25,-18.44) 46(9.75,-15.9) 47(10.25,-20.98) 48(10.75,-18.44) 49(11.25,-15.9) 50(11.75,-20.98) 51(12.25,-18.44) 52(12.75,-15.9) 105(14.25,15.9) 106(13.75,20.98) 107(13.25,18.44) 108(12.75,15.9) 109(12.25,20.98) 110(11.75,18.44) 111(11.25,15.9) 112(10.75,20.98) 113(10.25,18.44) 114(9.75,15.9) 115(9.25,20.98) 116(8.75,18.44) 117(8.25,15.9) 118(7.75,20.98) 119(7.25,18.44) 120(6.75,15.9) 121(6.25,20.98) 122(5.75,18.44) 123(5.25,15.9) 124(4.75,20.98) 125(4.25,18.44) 126(3.75,15.9) 127(3.25,20.98) 128(2.75,18.44) 129(2.25,15.9) 130(1.75,20.98) 131(1.25,18.44) 132(0.75,15.9) 133(0.25,20.98) 134(-0.25,18.44) 135(-0.75,15.9) 136(-1.25,20.98) 137(-1.75,18.44) 138(-2.25,15.9) 139(-2.75,20.98) 140(-3.25,18.44) 141(-3.75,15.9) 142(-4.25,20.98) 143(-4.75,18.44) 144(-5.25,15.9) 145(-5.75,20.98) 146(-6.25,18.44) 147(-6.75,15.9) 148(-7.25,20.98) 149(-7.75,18.44) 150(-8.25,15.9) 151(-8.75,20.98) 152(-9.25,18.44) 153(-9.75,15.9) 154(-10.25,20.98) 155(-10.75,18.44) 156(-11.25,15.9)
  oval 2x1 hole 0.8: 53(15.9,-14.25) 54(20.98,-13.75) 55(18.44,-13.25) 56(15.9,-12.75) 57(20.98,-12.25) 58(18.44,-11.75) 59(15.9,-11.25) 60(20.98,-10.75) 61(18.44,-10.25) 62(15.9,-9.75) 63(20.98,-9.25) 64(18.44,-8.75) 65(15.9,-8.25) 66(20.98,-7.75) 67(18.44,-7.25) 68(15.9,-6.75) 69(20.98,-6.25) 70(18.44,-5.75) 71(15.9,-5.25) 72(20.98,-4.75) 73(18.44,-4.25) 74(15.9,-3.75) 75(20.98,-3.25) 76(18.44,-2.75) 77(15.9,-2.25) 78(20.98,-1.75) 79(18.44,-1.25) 80(15.9,-0.75) 81(20.98,-0.25) 82(18.44,0.25) 83(15.9,0.75) 84(20.98,1.25) 85(18.44,1.75) 86(15.9,2.25) 87(20.98,2.75) 88(18.44,3.25) 89(15.9,3.75) 90(20.98,4.25) 91(18.44,4.75) 92(15.9,5.25) 93(20.98,5.75) 94(18.44,6.25) 95(15.9,6.75) 96(20.98,7.25) 97(18.44,7.75) 98(15.9,8.25) 99(20.98,8.75) 100(18.44,9.25) 101(15.9,9.75) 102(20.98,10.25) 103(18.44,10.75) 104(15.9,11.25) 157(-15.9,14.25) 158(-20.98,13.75) 159(-18.44,13.25) 160(-15.9,12.75) 161(-20.98,12.25) 162(-18.44,11.75) 163(-15.9,11.25) 164(-20.98,10.75) 165(-18.44,10.25) 166(-15.9,9.75) 167(-20.98,9.25) 168(-18.44,8.75) 169(-15.9,8.25) 170(-20.98,7.75) 171(-18.44,7.25) 172(-15.9,6.75) 173(-20.98,6.25) 174(-18.44,5.75) 175(-15.9,5.25) 176(-20.98,4.75) 177(-18.44,4.25) 178(-15.9,3.75) 179(-20.98,3.25) 180(-18.44,2.75) 181(-15.9,2.25) 182(-20.98,1.75) 183(-18.44,1.25) 184(-15.9,0.75) 185(-20.98,0.25) 186(-18.44,-0.25) 187(-15.9,-0.75) 188(-20.98,-1.25) 189(-18.44,-1.75) 190(-15.9,-2.25) 191(-20.98,-2.75) 192(-18.44,-3.25) 193(-15.9,-3.75) 194(-20.98,-4.25) 195(-18.44,-4.75) 196(-15.9,-5.25) 197(-20.98,-5.75) 198(-18.44,-6.25) 199(-15.9,-6.75) 200(-20.98,-7.25) 201(-18.44,-7.75) 202(-15.9,-8.25) 203(-20.98,-8.75) 204(-18.44,-9.25) 205(-15.9,-9.75) 206(-20.98,-10.25) 207(-18.44,-10.75) 208(-15.9,-11.25)
Top Overlay:
  lines w0.2: -13,-29 -13,-30 13,-30 13,-29 ; -26,-29 26,-29 26,29 -26,29 -26,-29

## SKT_TQFP208_CLAMSHELL_Wells [mm] "Wells CTI 208 pin socket"
height 19
pads (210):
  round 1.75 hole 1.75 unplated: 0(-20.41,-20.41) 0(20.41,20.41)
  oval 2x1 hole 0.85: 1(-17.17,12.75) 2(-19.71,12.25) 3(-22.25,11.75) 4(-17.17,11.25) 5(-19.71,10.75) 6(-22.25,10.25) 7(-17.17,9.75) 8(-19.71,9.25) 9(-22.25,8.75) 10(-17.17,8.25) 11(-19.71,7.75) 12(-22.25,7.25) 13(-17.17,6.75) 14(-19.71,6.25) 15(-22.25,5.75) 16(-17.17,5.25) 17(-19.71,4.75) 18(-22.25,4.25) 19(-17.17,3.75) 20(-19.71,3.25) 21(-22.25,2.75) 22(-17.17,2.25) 23(-19.71,1.75) 24(-22.25,1.25) 25(-17.17,0.75) 26(-19.71,0.25) 27(-22.25,-0.25) 28(-17.17,-0.75) 29(-19.71,-1.25) 30(-22.25,-1.75) 31(-17.17,-2.25) 32(-19.71,-2.75) 33(-22.25,-3.25) 34(-17.17,-3.75) 35(-19.71,-4.25) 36(-22.25,-4.75) 37(-17.17,-5.25) 38(-19.71,-5.75) 39(-22.25,-6.25) 40(-17.17,-6.75) 41(-19.71,-7.25) 42(-22.25,-7.75) 43(-17.17,-8.25) 44(-19.71,-8.75) 45(-22.25,-9.25) 46(-17.17,-9.75) 47(-19.71,-10.25) 48(-22.25,-10.75) 49(-17.17,-11.25) 50(-19.71,-11.75) 51(-22.25,-12.25) 52(-17.17,-12.75) 105(17.17,-12.75) 106(19.71,-12.25) 107(22.25,-11.75) 108(17.17,-11.25) 109(19.71,-10.75) 110(22.25,-10.25) 111(17.17,-9.75) 112(19.71,-9.25) 113(22.25,-8.75) 114(17.17,-8.25) 115(19.71,-7.75) 116(22.25,-7.25) 117(17.17,-6.75) 118(19.71,-6.25) 119(22.25,-5.75) 120(17.17,-5.25) 121(19.71,-4.75) 122(22.25,-4.25) 123(17.17,-3.75) 124(19.71,-3.25) 125(22.25,-2.75) 126(17.17,-2.25) 127(19.71,-1.75) 128(22.25,-1.25) 129(17.17,-0.75) 130(19.71,-0.25) 131(22.25,0.25) 132(17.17,0.75) 133(19.71,1.25) 134(22.25,1.75) 135(17.17,2.25) 136(19.71,2.75) 137(22.25,3.25) 138(17.17,3.75) 139(19.71,4.25) 140(22.25,4.75) 141(17.17,5.25) 142(19.71,5.75) 143(22.25,6.25) 144(17.17,6.75) 145(19.71,7.25) 146(22.25,7.75) 147(17.17,8.25) 148(19.71,8.75) 149(22.25,9.25) 150(17.17,9.75) 151(19.71,10.25) 152(22.25,10.75) 153(17.17,11.25) 154(19.71,11.75) 155(22.25,12.25) 156(17.17,12.75)
  oval 1x2 hole 0.85: 53(-12.75,-17.17) 54(-12.25,-19.71) 55(-11.75,-22.25) 56(-11.25,-17.17) 57(-10.75,-19.71) 58(-10.25,-22.25) 59(-9.75,-17.17) 60(-9.25,-19.71) 61(-8.75,-22.25) 62(-8.25,-17.17) 63(-7.75,-19.71) 64(-7.25,-22.25) 65(-6.75,-17.17) 66(-6.25,-19.71) 67(-5.75,-22.25) 68(-5.25,-17.17) 69(-4.75,-19.71) 70(-4.25,-22.25) 71(-3.75,-17.17) 72(-3.25,-19.71) 73(-2.75,-22.25) 74(-2.25,-17.17) 75(-1.75,-19.71) 76(-1.25,-22.25) 77(-0.75,-17.17) 78(-0.25,-19.71) 79(0.25,-22.25) 80(0.75,-17.17) 81(1.25,-19.71) 82(1.75,-22.25) 83(2.25,-17.17) 84(2.75,-19.71) 85(3.25,-22.25) 86(3.75,-17.17) 87(4.25,-19.71) 88(4.75,-22.25) 89(5.25,-17.17) 90(5.75,-19.71) 91(6.25,-22.25) 92(6.75,-17.17) 93(7.25,-19.71) 94(7.75,-22.25) 95(8.25,-17.17) 96(8.75,-19.71) 97(9.25,-22.25) 98(9.75,-17.17) 99(10.25,-19.71) 100(10.75,-22.25) 101(11.25,-17.17) 102(11.75,-19.71) 103(12.25,-22.25) 104(12.75,-17.17) 158(12.25,19.71) 159(11.75,22.25) 160(11.25,17.17) 161(10.75,19.71) 162(10.25,22.25) 163(9.75,17.17) 164(9.25,19.71) 165(8.75,22.25) 166(8.25,17.17) 167(7.75,19.71) 168(7.25,22.25) 169(6.75,17.17) 170(6.25,19.71) 171(5.75,22.25) 172(5.25,17.17) 173(4.75,19.71) 174(4.25,22.25) 175(3.75,17.17) 176(3.25,19.71) 177(2.75,22.25) 178(2.25,17.17) 179(1.75,19.71) 180(1.25,22.25) 181(0.75,17.17) 182(0.25,19.71) 183(-0.25,22.25) 184(-0.75,17.17) 185(-1.25,19.71) 186(-1.75,22.25) 187(-2.25,17.17) 188(-2.75,19.71) 189(-3.25,22.25) 190(-3.75,17.17) 191(-4.25,19.71) 192(-4.75,22.25) 193(-5.25,17.17) 194(-5.75,19.71) 195(-6.25,22.25) 196(-6.75,17.17) 197(-7.25,19.71) 198(-7.75,22.25) 199(-8.25,17.17) 200(-8.75,19.71) 201(-9.25,22.25) 202(-9.75,17.17) 203(-10.25,19.71) 204(-10.75,22.25) 205(-11.25,17.17) 206(-11.75,19.71) 207(-12.25,22.25) 208(-12.75,17.17) 457(12.75,17.17)
Top Overlay:
  lines w0.2: -24.65,-24.65 -24.65,23.81 -23.81,24.65 24.65,24.65 24.65,-24.65 -24.65,-24.65
M15_Country_Yard:
  lines w0.1: -0.5,0 0.5,0 ; 0,-0.5 0,0.5

## SKT_TQFP-64_IC51-0644-1972 [mm] "Test & Burn socket for TQFP-64, 0.4mm pitch, 7x7mm body. Yamaichi, IC51-0644-1972"
height 18
pads (68):
  round 5 hole 4.1: 0(-11,-11) 0(-11,11) 0(11,-11) 0(11,11)
  rect 0.9x1.5 hole 0.8: 1(-3.001,-5.2)
  oval 0.9x1.5 hole 0.8: 2(-2.601,-7) 3(-2.201,-8.8) 4(-1.801,-10.6) 5(-1.401,-5.2) 6(-1.001,-7) 7(-0.601,-8.8) 8(-0.201,-10.6) 9(0.199,-5.2) 10(0.599,-7) 11(0.999,-8.8) 12(1.399,-10.6) 13(1.799,-5.2) 14(2.199,-7) 15(2.599,-8.8) 16(2.999,-10.6) 33(3.001,5.2) 34(2.601,7) 35(2.201,8.8) 36(1.801,10.6) 37(1.401,5.2) 38(1.001,7) 39(0.601,8.8) 40(0.201,10.6) 41(-0.199,5.2) 42(-0.599,7) 43(-0.999,8.8) 44(-1.399,10.6) 45(-1.799,5.2) 46(-2.199,7) 47(-2.599,8.8) 48(-2.999,10.6)
  oval 1.5x0.9 hole 0.8: 17(5.2,-3.001) 18(7,-2.601) 19(8.8,-2.201) 20(10.6,-1.801) 21(5.2,-1.401) 22(7,-1.001) 23(8.8,-0.601) 24(10.6,-0.201) 25(5.2,0.199) 26(7,0.599) 27(8.8,0.999) 28(10.6,1.399) 29(5.2,1.799) 30(7,2.199) 31(8.8,2.599) 32(10.6,2.999) 49(-5.2,3.001) 50(-7,2.601) 51(-8.8,2.201) 52(-10.6,1.801) 53(-5.2,1.401) 54(-7,1.001) 55(-8.8,0.601) 56(-10.6,0.201) 57(-5.2,-0.199) 58(-7,-0.599) 59(-8.8,-0.999) 60(-10.6,-1.399) 61(-5.2,-1.799) 62(-7,-2.199) 63(-8.8,-2.599) 64(-10.6,-2.999)
Top Overlay:
  lines w0.2: -7.501,-19.999 -7.501,-20.93 7.499,-20.93 7.499,-19.999 ; -16,-19.999 -16,20.001 16,20.001 16,-19.999 -16,-19.999
M13_Assembly_Info:
  lines w0.1: -16,-19.998 -16,20.002 16,20.002 16,-19.998 -16,-19.998
M15_Country_Yard:
  lines w0.1: -16,-21.46 16,-21.46 16,-20 ; -16,20.001 -16,28.891 16,28.891 16,20.001 ; -0.5,0 0.5,0 ; 0,-0.5 0,0.5

## SKT_TSSOP-16_04335 161 X218A_Loranger [mm] "Socket; TSSOP- 16; 0.65mm pitch; Loranger; 04335 161 X218A"
height 18.8
pads (16):
  rect 0.7x1.6 hole 0.5: 1(2.275,4.96)
  oval 0.7x1.6 hole 0.5: 2(1.625,3.05) 3(0.975,4.96) 4(0.325,3.05) 5(-0.325,4.96) 6(-0.975,3.05) 7(-1.625,4.96) 8(-2.275,3.05) 9(-2.275,-4.96) 10(-1.625,-3.05) 11(-0.975,-4.96) 12(-0.325,-3.05) 13(0.325,-4.96) 14(0.975,-3.05) 15(1.625,-4.96) 16(2.275,-3.05)
Top Overlay:
  region: 7.365,3.93 8.365,4.93 8.365,2.93
  lines w0.2: -4.45,-16.15 -4.45,-17.45 4.45,-17.45 4.45,-16.15 ; -7.25,-16.15 7.25,-16.15 7.25,14.35 -7.25,14.35 -7.25,-16.15
  text "1" at 8.74,3.43 h1.2
M15_Country_Yard:
  lines w0.1: -0.5,0 0.5,0 ; 0,-0.5 0,0.5

## SKT_TSSOP-28_04335 281 X218K_Loranger [mm] "Socket; TSSOP- 28; 0.65mm pitch; Loranger; 04335 281 X218K"
height 18.8
pads (28):
  rect 0.7x1.6 hole 0.5: 1(4.225,3.05)
  oval 0.7x1.6 hole 0.5: 2(3.575,4.96) 3(2.925,3.05) 4(2.275,4.96) 5(1.625,3.05) 6(0.975,4.96) 7(0.325,3.05) 8(-0.325,4.96) 9(-0.975,3.05) 10(-1.625,4.96) 11(-2.275,3.05) 12(-2.925,4.96) 13(-3.575,3.05) 14(-4.225,4.96) 15(-4.225,-3.05) 16(-3.575,-4.96) 17(-2.925,-3.05) 18(-2.275,-4.96) 19(-1.625,-3.05) 20(-0.975,-4.96) 21(-0.325,-3.05) 22(0.325,-4.96) 23(0.975,-3.05) 24(1.625,-4.96) 25(2.275,-3.05) 26(2.925,-4.96) 27(3.575,-3.05) 28(4.225,-4.96)
Top Overlay:
  region: 7.365,3.93 8.365,4.93 8.365,2.93
  lines w0.2: -4.45,-16.15 -4.45,-17.45 4.45,-17.45 4.45,-16.15 ; -7.25,-16.15 7.25,-16.15 7.25,14.35 -7.25,14.35 -7.25,-16.15
  text "1" at 8.74,3.43 h1.2
M15_Country_Yard:
  lines w0.1: -0.5,0 0.5,0 ; 0,-0.5 0,0.5

## SKT_ZIF-28 [mm] "40 pin ZIF socket"
pads (30):
  round 1.6 hole 1.6 unplated: 0(0,-23.05) 0(0,23.05)
  rect 2.3x1.6 hole 1: 1(-7.62,14.541)
  oval 2.3x1.6 hole 1: 2(-7.62,12.002) 3(-7.62,9.461) 4(-7.62,6.921) 5(-7.62,4.381) 6(-7.62,1.841) 7(-7.62,-0.699) 8(-7.62,-3.238) 9(-7.62,-5.779) 10(-7.62,-8.319) 11(-7.62,-10.858) 12(-7.62,-13.399) 13(-7.62,-15.938) 14(-7.62,-18.479) 15(7.62,-18.479) 16(7.62,-15.938) 17(7.62,-13.399) 18(7.62,-10.858) 19(7.62,-8.319) 20(7.62,-5.779) 21(7.62,-3.238) 22(7.62,-0.699) 23(7.62,1.841) 24(7.62,4.381) 25(7.62,6.921) 26(7.62,9.461) 27(7.62,12.002) 28(7.62,14.541)
Top Overlay:
  lines w0.254: -11.43,-25.268 11.43,-25.268 11.43,25.251 -11.43,25.251 -11.43,-25.268
M13_Assembly_Info:
  lines w0.127: -11.43,-25.268 11.43,-25.268 11.43,25.251 -11.43,25.251 -11.43,-25.268
M15_Country_Yard:
  lines w0.1: -0.5,0 0.5,0 ; 0,-0.5 0,0.5

## SKT_ZIF-DIP24 [mil]
pads (26):
  round 60 hole 32: 1(-300,550) 2(-300,450) 3(-300,350) 4(-300,250) 5(-300,150) 6(-300,50) 7(-300,-50) 8(-300,-150) 9(-300,-250) 10(-300,-350) 11(-300,-450) 12(-300,-550) 13(300,-550) 14(300,-450) 15(300,-350) 16(300,-250) 17(300,-150) 18(300,-50) 19(300,50) 20(300,150) 21(300,250) 22(300,350) 23(300,450) 24(300,550)
  round 65 hole 65: 25(0,885) 26(0,-730)
Top Overlay:
  lines w12: -450,620 -350,620 -350,970 ; 350,970 350,620 450,620 ; -450,-817 -450,972 450,972 450,-817 -450,-817
  text "1" at -400,520 h50
M13_Assembly_Info:
  lines w7.87: -300,-817.32 -300,-550 300,-550 ; -300,971.65 -300,550 300,550 ; 0,-730 0,-550 ; 0,550 0,885

## SKT_ZIF-SIL10 [mm]
pads (12):
  round 2 hole 2 unplated: 0(0,-28.702) 0(0,11.938)
  rect 2.5x1.8 hole 0.9: 1(0,0)
  oval 2.5x1.8 hole 0.9: 2(0,-2.54) 3(0,-5.08) 4(0,-7.62) 5(0,-10.16) 6(0,-12.7) 7(0,-15.24) 8(0,-17.78) 9(0,-20.32) 10(0,-22.86)
Top Overlay:
  lines w0.2: -1.524,14.224 -1.524,8.128 1.524,8.128 1.524,14.224 ; 5.08,-30.924 -5.08,-30.924 -5.08,14.224 5.08,14.224 5.08,-30.912
M13_Assembly_Info:
  lines w0.2: -5.08,13.97 -5.08,24.892 5.08,24.892 5.08,13.97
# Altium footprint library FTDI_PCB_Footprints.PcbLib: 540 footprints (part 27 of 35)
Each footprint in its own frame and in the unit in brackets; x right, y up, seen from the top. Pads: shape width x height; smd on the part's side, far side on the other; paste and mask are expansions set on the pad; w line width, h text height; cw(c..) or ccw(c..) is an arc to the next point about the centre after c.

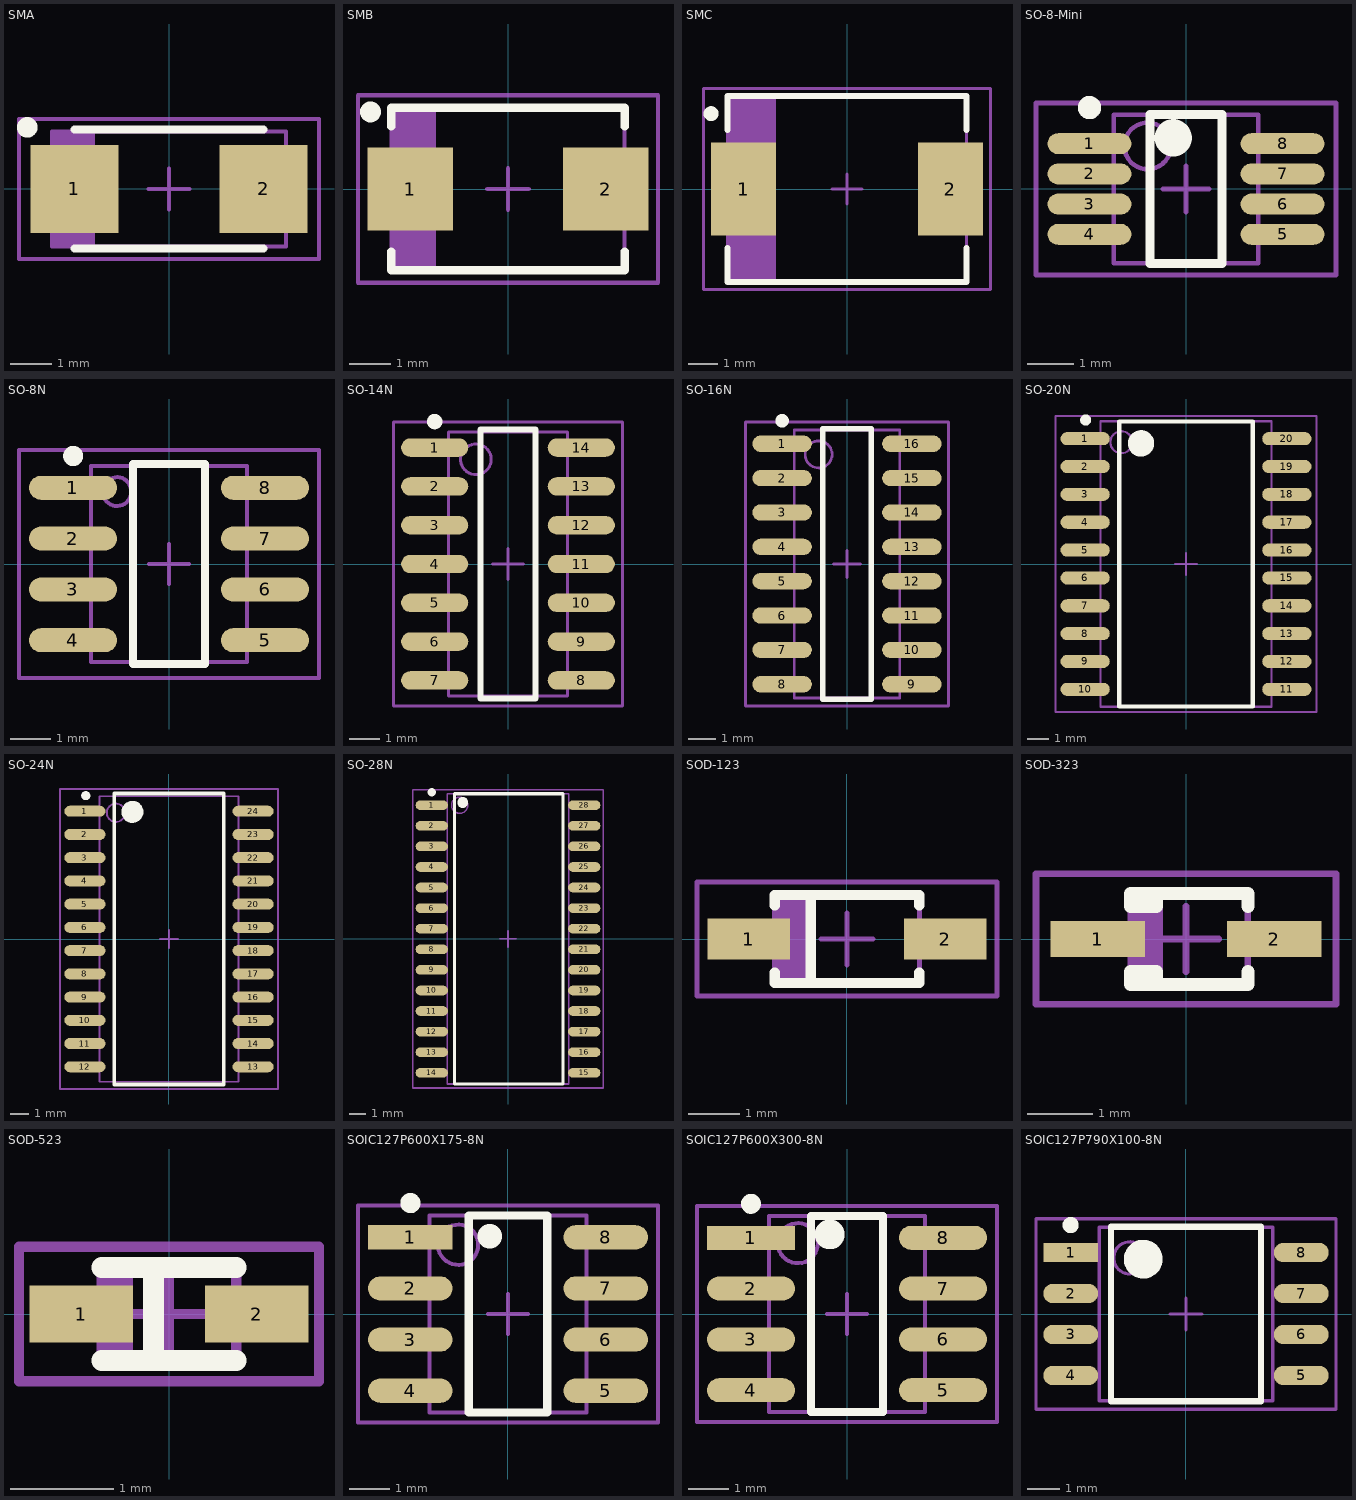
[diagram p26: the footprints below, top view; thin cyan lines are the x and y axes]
## SMA [mm] "DO-214-AC/SMA; 2 C-Bend Leads; Body 5 x 2.7 mm, inc. leads (LxW)"
height 2.44
pads (2):
  rect 2.15x2.15 smd: 1(-2.3,0) 2(2.3,0)
Top Overlay:
  circle w0.3: c-3.45,1.5 r0.1
  lines w0.2: -2.3,-1.45 0.25,-1.45 2.3,-1.45 ; -2.3,1.45 0.25,1.45 2.3,1.45
M13_Assembly_Info:
  rectangle: -2.85,-1.4 -1.8,1.4
  lines w0.1: -2.85,-1.4 2.85,-1.4 2.85,1.4 -2.85,1.4 -2.85,-1.4
M15_Country_Yard:
  lines w0.1: -0.5,0 0.5,0 ; 0,-0.5 0,0.5 ; -3.65,-1.7 3.65,-1.7 3.65,1.7 -3.65,1.7 -3.65,-1.7
3D body: height 0, standoff 0, extent -2.85,-1.4 2.85,1.4

## SMB [mm] "DO-214-AA/SMB; 2 C-Bend Leads; Body 5.3 x 3.6 mm, inc. leads (LxW)"
height 2.54
pads (2):
  rect 2.05x2 smd: 1(-2.35,0) 2(2.35,0)
Top Overlay:
  circle w0.3: c-3.3,1.85 r0.1
  lines w0.2: -2.8,-1.5 -2.8,-1.95 2.8,-1.95 2.8,-1.5 ; -2.8,1.5 -2.8,1.95 2.8,1.95 2.8,1.5
M13_Assembly_Info:
  rectangle: -2.8,-1.95 -1.725,1.95
  lines w0.1: -2.8,-1.95 -2.8,1.95 2.8,1.95 2.8,-1.95 -2.8,-1.95
M15_Country_Yard:
  lines w0.1: -0.5,0 0.5,0 ; 0,-0.5 0,0.5 ; -3.6,-2.25 -3.6,2.25 3.6,2.25 3.6,-2.25 -3.6,-2.25
3D body: height 0, standoff 0, extent -2.8,-1.95 2.8,1.95

## SMC [mm] "DO-214-AB/SMC; 2 C-Bend Leads; Body 7.9 x 5.9 mm, inc. leads (LxW)"
height 2.57
pads (2):
  rect 2.2x3.15 smd: 1(-3.5,0) 2(3.5,0)
Top Overlay:
  circle w0.3: c-4.6,2.55 r0.1
  lines w0.2: -4.05,-2 -4.05,-3.15 4.05,-3.15 4.05,-2 ; -4.05,2 -4.05,3.15 4.05,3.15 4.05,2
M13_Assembly_Info:
  rectangle: -4.05,-3.15 -2.4,3.15
  lines w0.1: -4.05,-3.15 -4.05,3.15 4.05,3.15 4.05,-3.15 -4.05,-3.15
M15_Country_Yard:
  lines w0.1: -0.5,0 0.5,0 ; 0,-0.5 0,0.5 ; -4.85,-3.4 -4.85,3.4 4.85,3.4 4.85,-3.4 -4.85,-3.4
3D body: height 3, standoff 0, extent -4.05,-3.15 4.05,3.15
3D body: height 3.1, standoff 0, extent -4.05,-3.15 -2.4,3.15

## SO-8-Mini [mm] "SO-Mini, 8-Leads, Body 3.2x3.1mm (max), Pitch 0.65mm, IPC Medium Density"
height 1.1
pads (8):
  oval 1.8x0.45 smd: 1(-2.075,0.975) 2(-2.075,0.325) 3(-2.075,-0.325) 4(-2.075,-0.975) 5(2.075,-0.975) 6(2.075,-0.325) 7(2.075,0.325) 8(2.075,0.975)
Top Overlay:
  circle w0.25: c-2.075,1.75 r0.125
  circle w0.6: c-0.275,1.1 r0.1
  lines w0.2: -0.775,-1.6 -0.775,1.6 0.775,1.6 0.775,-1.6 -0.775,-1.6
M13_Assembly_Info:
  circle w0.1: c-0.825,0.925 r0.5
  lines w0.1: -1.55,-1.6 -1.55,1.6 1.55,1.6 1.55,-1.6 -1.55,-1.6
M15_Country_Yard:
  lines w0.1: -0.5,0 0.5,0 ; 0,-0.5 0,0.5 ; -3.225,-1.85 -3.225,1.85 3.225,1.85 3.225,-1.85 -3.225,-1.85
3D body: height 1.1, standoff 0.15, extent -1.55,-1.6 1.55,1.6

## SO-8N [mm] "8-Pin Small Outline Integrated Circuit 1.27 mm Pitch, IPC Medium Density"
height 1.75
pads (8):
  oval 2.2x0.6 smd: 1(-2.4,1.905) 2(-2.4,0.635) 3(-2.4,-0.635) 4(-2.4,-1.905) 5(2.4,-1.905) 6(2.4,-0.635) 7(2.4,0.635) 8(2.4,1.905)
Top Overlay:
  circle w0.25: c-2.395,2.7 r0.125
  lines w0.2: -0.9,-2.5 -0.9,2.5 0.9,2.5 0.9,-2.5 -0.9,-2.5
M13_Assembly_Info:
  circle w0.1: c-1.3,1.81 r0.36
  lines w0.1: -1.95,-2.45 -1.95,2.45 1.95,2.45 1.95,-2.45 -1.95,-2.45
M15_Country_Yard:
  lines w0.1: -0.5,0 0.5,0 ; 0,-0.5 0,0.5 ; -3.75,-2.85 -3.75,2.85 3.75,2.85 3.75,-2.85 -3.75,-2.85
3D body: height 1.75, standoff 0, extent -1.95,-2.45 1.95,2.45

## SO-14N [mm] "14-Pin Small Outline Integrated Circuit 1.27 mm Pitch, IPC Medium Density"
height 1.75
pads (14):
  oval 2.2x0.6 smd: 1(-2.4,3.81) 2(-2.4,2.54) 3(-2.4,1.27) 4(-2.4,0) 5(-2.4,-1.27) 6(-2.4,-2.54) 7(-2.4,-3.81) 8(2.4,-3.81) 9(2.4,-2.54) 10(2.4,-1.27) 11(2.4,0) 12(2.4,1.27) 13(2.4,2.54) 14(2.4,3.81)
Top Overlay:
  circle w0.25: c-2.4,4.66 r0.125
  lines w0.2: -0.9,-4.4 0.9,-4.4 0.9,4.4 -0.9,4.4 -0.9,-4.4
M13_Assembly_Info:
  circle w0.1: c-1.05,3.425 r0.5
  lines w0.1: -1.95,-4.325 1.95,-4.325 1.95,4.325 -1.95,4.325 -1.95,-4.325
M15_Country_Yard:
  lines w0.1: -0.5,0 0.5,0 ; 0,-0.5 0,0.5 ; -3.75,-4.65 3.75,-4.65 3.75,4.65 -3.75,4.65 -3.75,-4.65
3D body: height 1.75, standoff 0, extent -1.95,-4.325 1.95,4.325

## SO-16N [mm] "16-Pin Small Outline Integrated Circuit 1.27 mm Pitch, IPC Medium Density"
height 1.75
pads (16):
  oval 2.2x0.6 smd: 1(-2.4,4.445) 2(-2.4,3.175) 3(-2.4,1.905) 4(-2.4,0.635) 5(-2.4,-0.635) 6(-2.4,-1.905) 7(-2.4,-3.175) 8(-2.4,-4.445) 9(2.4,-4.445) 10(2.4,-3.175) 11(2.4,-1.905) 12(2.4,-0.635) 13(2.4,0.635) 14(2.4,1.905) 15(2.4,3.175) 16(2.4,4.445)
Top Overlay:
  circle w0.25: c-2.4,5.295 r0.125
  lines w0.2: -0.9,-5 -0.9,5 0.9,5 0.9,-5 -0.9,-5
M13_Assembly_Info:
  circle w0.1: c-1.05,4.05 r0.5
  lines w0.1: -1.95,-4.95 -1.95,4.95 1.95,4.95 1.95,-4.95 -1.95,-4.95
M15_Country_Yard:
  lines w0.1: -0.5,0 0.5,0 ; 0,-0.5 0,0.5 ; -3.75,-5.25 -3.75,5.25 3.75,5.25 3.75,-5.25 -3.75,-5.25
3D body: height 1.75, standoff 0, extent -1.95,-4.95 1.95,4.95

## SO-20N [mm] "SOIC, 20-Leads, Body 13.0x7.8mm (max), Pitch 1.27mm, IPC Medium Density"
height 2.642
pads (20):
  oval 2.25x0.6 smd: 1(-4.6,5.715) 2(-4.6,4.445) 3(-4.6,3.175) 4(-4.6,1.905) 5(-4.6,0.635) 6(-4.6,-0.635) 7(-4.6,-1.905) 8(-4.6,-3.175) 9(-4.6,-4.445) 10(-4.6,-5.715) 11(4.6,-5.715) 12(4.6,-4.445) 13(4.6,-3.175) 14(4.6,-1.905) 15(4.6,-0.635) 16(4.6,0.635) 17(4.6,1.905) 18(4.6,3.175) 19(4.6,4.445) 20(4.6,5.715)
Top Overlay:
  circle w0.6: c-2.05,5.5 r0.3
  circle w0.25: c-4.575,6.565 r0.125
  lines w0.2: -3.05,-6.5 3.05,-6.5 3.05,6.5 -3.05,6.5 -3.05,-6.5
M13_Assembly_Info:
  circle w0.1: c-2.95,5.555 r0.5
  lines w0.1: -3.9,-6.505 3.9,-6.505 3.9,6.505 -3.9,6.505 -3.9,-6.505
M15_Country_Yard:
  lines w0.1: -0.5,0 0.5,0 ; 0,-0.5 0,0.5 ; -5.95,-6.75 5.95,-6.75 5.95,6.75 -5.95,6.75 -5.95,-6.75
3D body: height 2.64, standoff 0.31, extent -3.9,-6.505 3.9,6.505

## SO-24N [mm] "SOIC, 24-Leads, Body 15.4x7.5mm, Pitch 1.27mm, IPC Medium Density"
height 2.65
pads (24):
  oval 2.25x0.6 smd: 1(-4.6,6.985) 2(-4.6,5.715) 3(-4.6,4.445) 4(-4.6,3.175) 5(-4.6,1.905) 6(-4.6,0.635) 7(-4.6,-0.635) 8(-4.6,-1.905) 9(-4.6,-3.175) 10(-4.6,-4.445) 11(-4.6,-5.715) 12(-4.6,-6.985) 13(4.6,-6.985) 14(4.6,-5.715) 15(4.6,-4.445) 16(4.6,-3.175) 17(4.6,-1.905) 18(4.6,-0.635) 19(4.6,0.635) 20(4.6,1.905) 21(4.6,3.175) 22(4.6,4.445) 23(4.6,5.715) 24(4.6,6.985)
Top Overlay:
  circle w0.6: c-2,6.95 r0.3
  circle w0.25: c-4.55,7.835 r0.125
  lines w0.2: -3,-7.95 3,-7.95 3,7.95 -3,7.95 -3,-7.95
M13_Assembly_Info:
  circle w0.1: c-2.9,6.9 r0.5
  lines w0.1: -3.8,-7.8 3.8,-7.8 3.8,7.8 -3.8,7.8 -3.8,-7.8
M15_Country_Yard:
  lines w0.1: -0.5,0 0.5,0 ; 0,-0.5 0,0.5 ; -5.95,-8.2 5.95,-8.2 5.95,8.2 -5.95,8.2 -5.95,-8.2
3D body: height 2.65, standoff 0, extent -3.8,-7.8 3.8,7.8

## SO-28N [mm] "SOIC, 28-Leads, Body 17.9x7.5mm (max), Pitch 1.27mm, IPC Medium Density"
height 2.65
pads (28):
  oval 2x0.6 smd: 1(-4.7,8.25) 2(-4.7,6.98) 3(-4.7,5.71) 4(-4.7,4.44) 5(-4.7,3.17) 6(-4.7,1.9) 7(-4.7,0.63) 8(-4.7,-0.64) 9(-4.7,-1.91) 10(-4.7,-3.18) 11(-4.7,-4.45) 12(-4.7,-5.72) 13(-4.7,-6.99) 14(-4.7,-8.26) 15(4.7,-8.26) 16(4.7,-6.99) 17(4.7,-5.72) 18(4.7,-4.45) 19(4.7,-3.18) 20(4.7,-1.91) 21(4.7,-0.64) 22(4.7,0.63) 23(4.7,1.9) 24(4.7,3.17) 25(4.7,4.44) 26(4.7,5.71) 27(4.7,6.98) 28(4.7,8.25)
Top Overlay:
  circle w0.6: c-2.795,8.42 r0.035
  circle w0.25: c-4.705,9.05 r0.125
  lines w0.2: -3.3,-8.95 3.4,-8.95 3.4,8.95 -3.3,8.95 -3.3,-8.95
M13_Assembly_Info:
  circle w0.1: c-2.98,8.25 r0.5
  lines w0.1: -3.75,-8.95 3.75,-8.95 3.75,8.95 -3.75,8.95 -3.75,-8.95
M15_Country_Yard:
  lines w0.1: -0.5,0 0.5,0 ; 0,-0.5 0,0.5 ; -5.875,-9.2 5.875,-9.2 5.875,9.2 -5.875,9.2 -5.875,-9.2
3D body: height 2.65, standoff 0.3, extent -3.75,-8.95 3.75,8.95

## SOD-123 [mm] "SOD-123; 2 Leads; Body 2.8 x 1.7 mm, (LxW)"
height 1.35
pads (2):
  rect 1.6x0.8 smd: 1(-1.9,0) 2(1.9,0)
Top Overlay:
  lines w0.2: -1.4,-0.65 -1.4,-0.85 1.4,-0.85 1.4,-0.65 ; -1.4,0.65 -1.4,0.85 1.4,0.85 1.4,0.65 ; -0.7,-0.85 -0.7,0.85
M13_Assembly_Info:
  rectangle: -1.4,-0.85 -0.775,0.85
  lines w0.1: -1.4,-0.85 1.4,-0.85 1.4,0.85 -1.4,0.85 -1.4,-0.85
M15_Country_Yard:
  lines w0.1: -0.5,0 0.5,0 ; 0,-0.5 0,0.5 ; -2.9,-1.1 -2.9,1.1 2.9,1.1 2.9,-1.1 -2.9,-1.1
3D body: height 0, standoff 0, extent -1.4,-0.85 1.4,0.85

## SOD-323 [mm] "SOD-323/SC-76; 2 Leads; Body 1.8 x 1.4 mm, (LxW)"
height 1.1
pads (2):
  rect 1.45x0.55 smd: 1(-1.35,0) 2(1.35,0)
Top Overlay:
  lines w0.2: -0.45,-0.7 -0.45,-0.5 -0.85,-0.5 -0.85,-0.7 0.95,-0.7 0.95,-0.5 ; -0.45,0.7 -0.45,0.5 -0.85,0.5 -0.85,0.7 0.95,0.7 0.95,0.5
M13_Assembly_Info:
  rectangle: -0.85,-0.7 -0.35,0.7
  lines w0.1: -0.85,-0.7 -0.85,0.7 0.95,0.7 0.95,-0.7 -0.85,-0.7
M15_Country_Yard:
  lines w0.1: -0.5,0 0.5,0 ; 0,-0.5 0,0.5 ; -2.3,-1 -2.3,1 2.3,1 2.3,-1 -2.3,-1
3D body: height 0, standoff 0, extent -0.85,-0.7 0.95,0.7

## SOD-523 [mm] "SOD-523; 2 Leads; Body 1.3 x 0.35 mm, (LxW)"
height 0.65
pads (2):
  rect 1x0.55 smd: 1(-0.85,0) 2(0.85,0)
Top Overlay:
  lines w0.2: -0.65,-0.45 0.65,-0.45 ; -0.65,0.45 0.65,0.45 ; -0.15,-0.45 -0.15,0.45
M13_Assembly_Info:
  rectangle: -0.65,-0.45 -0.35,0.45
  lines w0.1: -0.65,-0.45 -0.65,0.45 0.65,0.45 0.65,-0.45 -0.65,-0.45
M15_Country_Yard:
  lines w0.1: -0.5,0 0.5,0 ; 0,-0.5 0,0.5 ; -1.45,-0.65 1.45,-0.65 1.45,0.65 -1.45,0.65 -1.45,-0.65
3D body: height 0, standoff 0, extent -0.65,-0.45 0.65,0.45

## SOIC127P600X175-8N [mm] "SOIC, 8-Leads, Body 4.9x3.9mm (max), Pitch 1.27mm, IPC Medium Density"
height 1.75
pads (8):
  rect 2.1x0.6 smd: 1(-2.425,1.905)
  oval 2.1x0.6 smd: 2(-2.425,0.635) 3(-2.425,-0.635) 4(-2.425,-1.905) 5(2.425,-1.905) 6(2.425,-0.635) 7(2.425,0.635) 8(2.425,1.905)
Top Overlay:
  circle w0.25: c-2.425,2.755 r0.125
  circle w0.6: c-0.455,1.93 r0.005
  lines w0.2: -0.975,-2.45 -0.975,2.45 0.975,2.45 0.975,-2.45 -0.975,-2.45
M13_Assembly_Info:
  circle w0.1: c-1.24,1.72 r0.5
  lines w0.1: -1.95,-2.45 -1.95,2.45 1.95,2.45 1.95,-2.45 -1.95,-2.45
M15_Country_Yard:
  lines w0.1: -0.5,0 0.5,0 ; 0,-0.5 0,0.5 ; -3.725,-2.7 -3.725,2.7 3.725,2.7 3.725,-2.7 -3.725,-2.7
3D body: height 1.75, standoff 0.25, extent -1.95,-2.45 1.95,2.45

## SOIC127P600X300-8N [mm] "SOIC, 8-Leads, Body 4.9x3.9mm (max), Pitch 1.27mm, IPC Medium Density"
height 3
pads (8):
  rect 2.2x0.6 smd: 1(-2.4,1.905)
  oval 2.2x0.6 smd: 2(-2.4,0.635) 3(-2.4,-0.635) 4(-2.4,-1.905) 5(2.4,-1.905) 6(2.4,-0.635) 7(2.4,0.635) 8(2.4,1.905)
Top Overlay:
  circle w0.6: c-0.431,1.99 r0.071
  circle w0.25: c-2.4,2.755 r0.125
  lines w0.2: -0.9,-2.45 0.9,-2.45 0.9,2.45 -0.9,2.45 -0.9,-2.45
M13_Assembly_Info:
  circle w0.1: c-1.23,1.77 r0.5
  lines w0.1: -1.95,-2.45 1.95,-2.45 1.95,2.45 -1.95,2.45 -1.95,-2.45
M15_Country_Yard:
  lines w0.1: -0.5,0 0.5,0 ; 0,-0.5 0,0.5 ; -3.75,-2.7 3.75,-2.7 3.75,2.7 -3.75,2.7 -3.75,-2.7
3D body: height 3, standoff 0.2, extent -1.95,-2.45 1.95,2.45

## SOIC127P790X100-8N [mm] "SOIC, 8-Leads, Body 5.4x5.4mm (max), Pitch 1.27mm, IPC Medium Density"
height 1
pads (8):
  rect 1.7x0.6 smd: 1(-3.575,1.905)
  oval 1.7x0.6 smd: 2(-3.575,0.635) 3(-3.575,-0.635) 4(-3.575,-1.905) 5(3.575,-1.905) 6(3.575,-0.635) 7(3.575,0.635) 8(3.575,1.905)
Top Overlay:
  circle w0.25: c-3.575,2.755 r0.125
  circle w0.6: c-1.325,1.7 r0.3
  lines w0.2: -2.325,-2.7 -2.325,2.7 2.325,2.7 2.325,-2.7 -2.325,-2.7
M13_Assembly_Info:
  circle w0.1: c-1.74,1.74 r0.5
  lines w0.1: -2.69,-2.69 -2.69,2.69 2.69,2.69 2.69,-2.69 -2.69,-2.69
M15_Country_Yard:
  lines w0.1: -0.5,0 0.5,0 ; 0,-0.5 0,0.5 ; -4.65,-2.95 -4.65,2.95 4.65,2.95 4.65,-2.95 -4.65,-2.95
3D body: height 1, standoff 0.15, extent -2.69,-2.69 2.69,2.69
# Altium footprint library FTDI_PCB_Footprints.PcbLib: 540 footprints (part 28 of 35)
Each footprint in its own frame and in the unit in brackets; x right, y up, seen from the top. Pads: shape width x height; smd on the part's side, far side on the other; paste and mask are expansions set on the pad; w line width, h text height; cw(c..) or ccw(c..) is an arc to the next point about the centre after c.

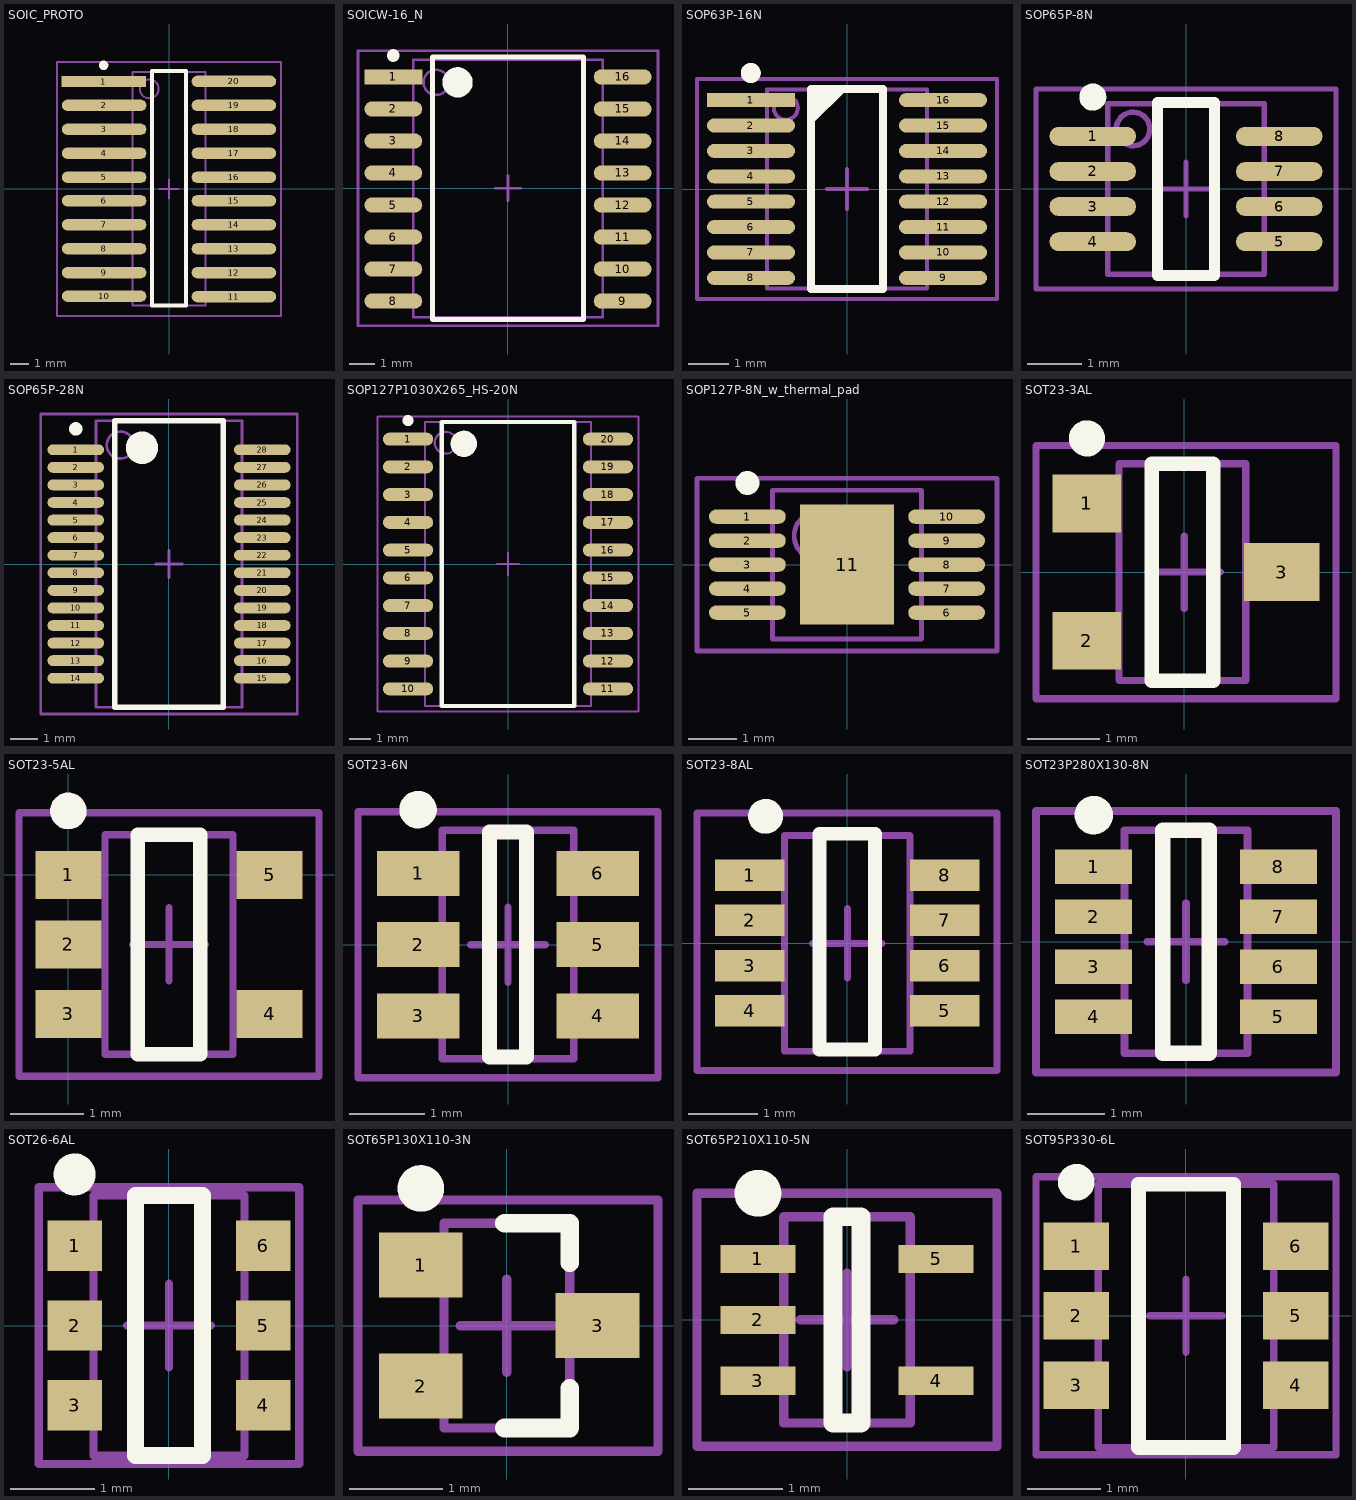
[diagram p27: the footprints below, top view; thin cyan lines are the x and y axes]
## SOIC_PROTO [mm]
pads (20):
  rect 4.5x0.6 smd: 1(-3.475,5.715)
  oval 4.5x0.6 smd: 2(-3.45,4.45) 3(-3.45,3.175) 4(-3.45,1.9) 5(-3.45,0.625) 6(-3.45,-0.625) 7(-3.45,-1.9) 8(-3.45,-3.175) 9(-3.45,-4.45) 10(-3.45,-5.7) 11(3.45,-5.726) 12(3.45,-4.45) 13(3.45,-3.175) 14(3.45,-1.9) 15(3.45,-0.625) 16(3.45,0.625) 17(3.45,1.9) 18(3.45,3.175) 19(3.45,4.45) 20(3.45,5.725)
Top Overlay:
  circle w0.25: c-3.475,6.575 r0.125
  lines w0.2: -0.9,-6.2 0.9,-6.2 0.9,6.275 -0.9,6.275 -0.9,-6.2
M13_Assembly_Info:
  circle w0.1: c-1.05,5.325 r0.5
  lines w0.1: -1.95,-6.2 1.95,-6.2 1.95,6.225 -1.95,6.225 -1.95,-6.2
M15_Country_Yard:
  lines w0.1: -0.5,0 0.5,0 ; 0,-0.5 0,0.5 ; -5.95,-6.75 5.95,-6.75 5.95,6.75 -5.95,6.75 -5.95,-6.75
3D body: height 1.75, standoff 0, extent -1.95,-6.2 1.95,6.225

## SOICW-16_N [mm] "SOIC-Wide, 16-Leads, Body 12.8x7.5mm, Pitch 1.27mm, IPC Medium Density"
height 2.65
pads (16):
  rect 2.3x0.6 smd: 1(-4.55,4.42)
  oval 2.3x0.6 smd: 2(-4.55,3.15) 3(-4.55,1.88) 4(-4.55,0.61) 5(-4.55,-0.66) 6(-4.55,-1.93) 7(-4.55,-3.2) 8(-4.55,-4.47) 9(4.55,-4.47) 10(4.55,-3.2) 11(4.55,-1.93) 12(4.55,-0.66) 13(4.55,0.61) 14(4.55,1.88) 15(4.55,3.15) 16(4.55,4.42)
Top Overlay:
  circle w0.6: c-2,4.205 r0.3
  circle w0.25: c-4.55,5.27 r0.125
  lines w0.2: -3,-5.195 3,-5.195 3,5.205 -3,5.205 -3,-5.195
M13_Assembly_Info:
  circle w0.1: c-2.85,4.205 r0.5
  lines w0.1: -3.75,-5.105 3.75,-5.105 3.75,5.105 -3.75,5.105 -3.75,-5.105
M15_Country_Yard:
  lines w0.1: -0.5,0 0.5,0 ; 0,-0.5 0,0.5 ; -5.95,-5.445 5.95,-5.445 5.95,5.455 -5.95,5.455 -5.95,-5.445
3D body: height 2.65, standoff 0, extent -3.75,-5.105 3.75,5.105

## SOP63P-16N [mm] "SOP, 16-Leads, Body 5.0x4.0mm (max), Pitch 0.63mm, IPC Medium Density"
height 1.727
pads (16):
  rect 2.2x0.35 smd: 1(-2.4,2.222)
  oval 2.2x0.35 smd: 2(-2.4,1.587) 3(-2.4,0.953) 4(-2.4,0.318) 5(-2.4,-0.318) 6(-2.4,-0.953) 7(-2.4,-1.587) 8(-2.4,-2.222) 9(2.4,-2.222) 10(2.4,-1.587) 11(2.4,-0.953) 12(2.4,-0.318) 13(2.4,0.318) 14(2.4,0.953) 15(2.4,1.587) 16(2.4,2.222)
Top Overlay:
  circle w0.25: c-2.405,2.9 r0.125
  region: -0.9,2.5 0,2.5 -0.9,1.6
  lines w0.2: -0.9,-2.5 0.9,-2.5 0.9,2.5 -0.9,2.5 -0.9,-2.5
M13_Assembly_Info:
  circle w0.1: c-1.53,2.03 r0.3
  lines w0.1: -1.995,-2.49 1.995,-2.49 1.995,2.49 -1.995,2.49 -1.995,-2.49
M15_Country_Yard:
  lines w0.1: -0.5,0 0.5,0 ; 0,-0.5 0,0.5 ; -3.75,-2.75 3.75,-2.75 3.75,2.75 -3.75,2.75 -3.75,-2.75
3D body: height 1.73, standoff 0.25, extent -1.995,-2.49 1.995,2.49

## SOP65P-8N [mm] "SOP, 8-Leads, Body 3.2x2.9mm (max), Pitch 0.65mm, IPC Medium Density"
height 1.3
pads (8):
  oval 1.6x0.35 smd: 1(-1.725,0.975) 2(-1.725,0.325) 3(-1.725,-0.325) 4(-1.725,-0.975) 5(1.725,-0.975) 6(1.725,-0.325) 7(1.725,0.325) 8(1.725,0.975)
Top Overlay:
  circle w0.25: c-1.725,1.7 r0.125
  lines w0.2: -0.525,-1.6 0.525,-1.6 0.525,1.6 -0.525,1.6 -0.525,-1.6
M13_Assembly_Info:
  circle w0.1: c-0.98,1.11 r0.31
  lines w0.1: -1.45,-1.575 1.45,-1.575 1.45,1.575 -1.45,1.575 -1.45,-1.575
M15_Country_Yard:
  lines w0.1: -0.5,0 0.5,0 ; 0,-0.5 0,0.5 ; -2.775,-1.85 2.775,-1.85 2.775,1.85 -2.775,1.85 -2.775,-1.85
3D body: height 1.3, standoff 0.1, extent -1.45,-1.575 1.45,1.575

## SOP65P-28N [mm] "SOP, 28-Leads, Body 10.2x5.3mm, Pitch 0.65mm, IPC Medium Density"
height 2
pads (28):
  oval 2.1x0.4 smd: 1(-3.45,4.225) 2(-3.45,3.575) 3(-3.45,2.925) 4(-3.45,2.275) 5(-3.45,1.625) 6(-3.45,0.975) 7(-3.45,0.325) 8(-3.45,-0.325) 9(-3.45,-0.975) 10(-3.45,-1.625) 11(-3.45,-2.275) 12(-3.45,-2.925) 13(-3.45,-3.575) 14(-3.45,-4.225) 15(3.45,-4.225) 16(3.45,-3.575) 17(3.45,-2.925) 18(3.45,-2.275) 19(3.45,-1.625) 20(3.45,-0.975) 21(3.45,-0.325) 22(3.45,0.325) 23(3.45,0.975) 24(3.45,1.625) 25(3.45,2.275) 26(3.45,2.925) 27(3.45,3.575) 28(3.45,4.225)
Top Overlay:
  circle w0.25: c-3.45,5 r0.125
  circle w0.6: c-1,4.3 r0.3
  lines w0.2: -2,-5.3 -2,5.3 2,5.3 2,-5.3 -2,-5.3
M13_Assembly_Info:
  circle w0.1: c-1.8,4.4 r0.5
  lines w0.1: -2.7,-5.3 -2.7,5.3 2.7,5.3 2.7,-5.3 -2.7,-5.3
M15_Country_Yard:
  lines w0.1: -0.5,0 0.5,0 ; 0,-0.5 0,0.5 ; -4.75,-5.55 -4.75,5.55 4.75,5.55 4.75,-5.55 -4.75,-5.55
3D body: height 2, standoff 0, extent -2.7,-5.3 2.7,5.3

## SOP127P1030X265_HS-20N [mm] "SOP, 20-Leads, Body 13.0x7.6mm (max), Pitch 1.27mm, IPC Medium Density"
height 2.65
pads (20):
  oval 2.3x0.6 smd: 1(-4.575,5.715) 2(-4.575,4.445) 3(-4.575,3.175) 4(-4.575,1.905) 5(-4.575,0.635) 6(-4.575,-0.635) 7(-4.575,-1.905) 8(-4.575,-3.175) 9(-4.575,-4.445) 10(-4.575,-5.715) 11(4.575,-5.715) 12(4.575,-4.445) 13(4.575,-3.175) 14(4.575,-1.905) 15(4.575,-0.635) 16(4.575,0.635) 17(4.575,1.905) 18(4.575,3.175) 19(4.575,4.445) 20(4.575,5.715)
Top Overlay:
  circle w0.25: c-4.575,6.565 r0.125
  circle w0.6: c-2.025,5.5 r0.3
  lines w0.2: -3.025,-6.5 -3.025,6.5 3.025,6.5 3.025,-6.5 -3.025,-6.5
M13_Assembly_Info:
  circle w0.1: c-2.85,5.55 r0.5
  lines w0.1: -3.8,-6.5 -3.8,6.5 3.8,6.5 3.8,-6.5 -3.8,-6.5
M15_Country_Yard:
  lines w0.1: -0.5,0 0.5,0 ; 0,-0.5 0,0.5 ; -5.975,-6.75 -5.975,6.75 5.975,6.75 5.975,-6.75 -5.975,-6.75
3D body: height 2.65, standoff 0.3, extent -3.8,-6.5 3.8,6.5

## SOP127P-8N_w_thermal_pad [mm]
height 1.1
pads (11):
  oval 1.6x0.3 smd: 1(-2.075,1) 2(-2.075,0.5) 3(-2.075,0) 4(-2.075,-0.5) 5(-2.075,-1) 6(2.075,-1) 7(2.075,-0.5) 8(2.075,0) 9(2.075,0.5) 10(2.075,1)
  rect 1.95x2.5 smd: 11(0,0)
Top Overlay:
  circle w0.25: c-2.075,1.7 r0.125
M13_Assembly_Info:
  circle w0.1: c-0.6,0.6 r0.5
  lines w0.1: -1.55,-1.55 1.55,-1.55 1.55,1.55 -1.55,1.55 -1.55,-1.55
M15_Country_Yard:
  lines w0.1: -0.5,0 0.5,0 ; 0,-0.5 0,0.5 ; -3.125,-1.8 3.125,-1.8 3.125,1.8 -3.125,1.8 -3.125,-1.8
3D body: height 1.1, standoff 0.2, extent -1.55,-1.55 1.55,1.55

## SOT23-3AL [mm] "SOT23 SMT Package"
pads (3):
  rect 0.95x0.8 smd: 1(-1.35,0.95) 2(-1.35,-0.95)
  rect 1.05x0.8 smd: 3(1.35,0)
Top Overlay:
  circle w0.25: c-1.345,1.85 r0.125
  lines w0.2: -0.45,-1.5 -0.45,1.5 0.4,1.5 0.4,-1.5 -0.45,-1.5
M13_Assembly_Info:
  lines w0.1: -0.9,-1.5 0.85,-1.5 0.85,1.5 -0.9,1.5 -0.9,-1.5
M15_Country_Yard:
  lines w0.1: -0.5,0 0.5,0 ; 0,-0.5 0,0.5 ; -2.05,-1.75 2.1,-1.75 2.1,1.75 -2.05,1.75 -2.05,-1.75
3D body: height 0.95, standoff -0.07, extent -1.242,-1.467 1.234,1.453

## SOT23-5AL [mm] "SOT23, 5-Leads, Body 2.9x1.6mm, Pitch 0.95mm, Lead Span 2.8mm"
height 1.45
pads (5):
  rect 0.9x0.65 smd: 1(0,0) 2(0,-0.95) 3(0,-1.9) 4(2.75,-1.9) 5(2.75,0)
Top Overlay:
  circle w0.25: c0,0.875 r0.125
  lines w0.2: 0.95,-2.45 0.95,0.55 1.8,0.55 1.8,-2.45 0.95,-2.45
M13_Assembly_Info:
  lines w0.1: 0.5,-2.45 2.25,-2.45 2.25,0.55 0.5,0.55 0.5,-2.45
M15_Country_Yard:
  lines w0.1: 0.875,-0.95 1.875,-0.95 ; 1.375,-1.45 1.375,-0.45 ; -0.675,-2.75 3.425,-2.75 3.425,0.85 -0.675,0.85 -0.675,-2.75
3D body: height 0, standoff 0, extent 0.5,-2.45 2.25,0.55

## SOT23-6N [mm] "SOT23, 6-Leads, Body 3.0x3.0mm (max), Pitch 0.95mm, IPC Medium Density"
height 1.45
pads (6):
  rect 1.1x0.6 smd: 1(-1.2,0.95) 2(-1.2,0) 3(-1.2,-0.95) 4(1.2,-0.95) 5(1.2,0) 6(1.2,0.95)
Top Overlay:
  circle w0.25: c-1.2,1.8 r0.125
  lines w0.2: -0.25,-1.5 0.25,-1.5 0.25,1.5 -0.25,1.5 -0.25,-1.5
M13_Assembly_Info:
  lines w0.1: -0.875,-1.525 -0.875,1.525 0.875,1.525 0.875,-1.525 -0.875,-1.525
M15_Country_Yard:
  lines w0.1: -0.5,0 0.5,0 ; 0,-0.5 0,0.5 ; -2,-1.775 -2,1.775 2,1.775 2,-1.775 -2,-1.775
3D body: height 1.45, standoff 0.1, extent -0.875,-1.525 0.875,1.525

## SOT23-8AL [mm] "SOT23 8-PIN 0.65mm PITCH"
height 1.45
pads (8):
  rect 1x0.45 smd: 1(-1.4,0.98) 2(-1.4,0.33) 3(-1.4,-0.32) 4(-1.4,-0.97) 5(1.4,-0.97) 6(1.4,-0.32) 7(1.4,0.33) 8(1.4,0.98)
Top Overlay:
  circle w0.25: c-1.175,1.825 r0.125
  lines w0.2: -0.4,-1.525 -0.4,1.575 0.4,1.575 0.4,-1.525 -0.4,-1.525
M13_Assembly_Info:
  lines w0.1: -0.9,-1.55 0.9,-1.55 0.9,1.55 -0.9,1.55 -0.9,-1.55
M15_Country_Yard:
  lines w0.1: -0.5,0 0.5,0 ; 0,-0.5 0,0.5 ; -2.16,-1.825 2.15,-1.825 2.15,1.875 -2.16,1.875 -2.16,-1.825
3D body: height 1.1, standoff 0, extent -0.9,-1.575 0.9,1.525

## SOT23P280X130-8N [mm] "SOT23, 8-Leads, Body 2.9x2.8mm (max), Pitch 0.65mm, IPC Medium Density"
height 1.3
pads (8):
  rect 1x0.45 smd: 1(-1.2,0.975) 2(-1.2,0.325) 3(-1.2,-0.325) 4(-1.2,-0.975) 5(1.2,-0.975) 6(1.2,-0.325) 7(1.2,0.325) 8(1.2,0.975)
Top Overlay:
  circle w0.25: c-1.2,1.645 r0.125
  lines w0.2: -0.3,-1.45 0.3,-1.45 0.3,1.45 -0.3,1.45 -0.3,-1.45
M13_Assembly_Info:
  lines w0.1: -0.8,-1.45 -0.8,1.45 0.8,1.45 0.8,-1.45 -0.8,-1.45
M15_Country_Yard:
  lines w0.1: -0.5,0 0.5,0 ; 0,-0.5 0,0.5 ; -1.95,-1.7 -1.95,1.7 1.95,1.7 1.95,-1.7 -1.95,-1.7
3D body: height 1.3, standoff 0.15, extent -0.8,-1.45 0.8,1.45

## SOT26-6AL [mm] "SOT23, 6-Leads, Body 2.9x1.6mm, Pitch 0.95mm, Lead Span 2.5mm, IPC High Density"
height 1.1
pads (6):
  rect 0.65x0.6 smd: 1(-1.125,0.95) 2(-1.125,0) 3(-1.125,-0.95) 4(1.125,-0.95) 5(1.125,0) 6(1.125,0.95)
Top Overlay:
  circle w0.25: c-1.125,1.8 r0.125
  lines w0.2: -0.4,-1.55 -0.4,1.55 0.4,1.55 0.4,-1.55 -0.4,-1.55
M13_Assembly_Info:
  lines w0.1: -0.9,-1.55 0.9,-1.55 0.9,1.55 -0.9,1.55 -0.9,-1.55
M15_Country_Yard:
  lines w0.1: -0.5,0 0.5,0 ; 0,-0.5 0,0.5 ; -1.55,-1.65 1.55,-1.65 1.55,1.65 -1.55,1.65 -1.55,-1.65
3D body: height 1.1, standoff 0, extent -0.9,-1.55 0.9,1.55

## SOT65P130X110-3N [mm] "SOT23, 3-Leads, Body 2.2x1.4mm (max), Pitch 0.65mm, IPC Medium Density"
height 1.1
pads (3):
  rect 0.9x0.7 smd: 1(-0.925,0.65) 2(-0.925,-0.65) 3(0.975,0)
Top Overlay:
  circle w0.25: c-0.925,1.475 r0.125
  lines w0.2: -0.025,-1.1 0.675,-1.1 0.675,-0.675 ; -0.025,1.1 0.675,1.1 0.675,0.675
M13_Assembly_Info:
  lines w0.1: -0.675,-1.1 0.675,-1.1 0.675,1.1 -0.675,1.1 -0.675,-1.1
M15_Country_Yard:
  lines w0.1: -0.5,0 0.5,0 ; 0,-0.5 0,0.5 ; -1.6,-1.35 1.625,-1.35 1.625,1.35 -1.6,1.35 -1.6,-1.35
3D body: height 1.1, standoff 0.05, extent -0.675,-1.1 0.675,1.1

## SOT65P210X110-5N [mm] "SOT23, 5-Leads, Body 2.2x2.2mm (max), Pitch 0.65mm, IPC Medium Density"
height 1.1
pads (5):
  rect 0.8x0.3 smd: 1(-0.95,0.65) 2(-0.95,0) 3(-0.95,-0.65) 4(0.95,-0.65) 5(0.95,0.65)
Top Overlay:
  circle w0.25: c-0.95,1.35 r0.125
  lines w0.2: -0.15,-1.1 0.15,-1.1 0.15,1.1 -0.15,1.1 -0.15,-1.1
M13_Assembly_Info:
  lines w0.1: -0.675,-1.1 -0.675,1.1 0.675,1.1 0.675,-1.1 -0.675,-1.1
M15_Country_Yard:
  lines w0.1: -0.5,0 0.5,0 ; 0,-0.5 0,0.5 ; -1.6,-1.35 -1.6,1.35 1.6,1.35 1.6,-1.35 -1.6,-1.35
3D body: height 1.1, standoff 0.05, extent -0.675,-1.1 0.675,1.1

## SOT95P330-6L [mm] "Small Outline, 6-Leads, Body 3.4x2.2mm, Pitch 0.95mm, Lead Span 3.3mm, IPC High Density"
height 1.4
pads (6):
  rect 0.9x0.65 smd: 1(-1.5,0.95) 2(-1.5,0) 3(-1.5,-0.95) 4(1.5,-0.95) 5(1.5,0) 6(1.5,0.95)
Top Overlay:
  circle w0.25: c-1.5,1.825 r0.125
  lines w0.2: -0.65,-1.8 -0.65,1.8 0.65,1.8 0.65,-1.8 -0.65,-1.8
M13_Assembly_Info:
  lines w0.1: -1.2,-1.8 1.2,-1.8 1.2,1.8 -1.2,1.8 -1.2,-1.8
M15_Country_Yard:
  lines w0.1: -0.5,0 0.5,0 ; 0,-0.5 0,0.5 ; -2.05,-1.9 2.05,-1.9 2.05,1.9 -2.05,1.9 -2.05,-1.9
3D body: height 1.4, standoff 0, extent -1.2,-1.8 1.2,1.8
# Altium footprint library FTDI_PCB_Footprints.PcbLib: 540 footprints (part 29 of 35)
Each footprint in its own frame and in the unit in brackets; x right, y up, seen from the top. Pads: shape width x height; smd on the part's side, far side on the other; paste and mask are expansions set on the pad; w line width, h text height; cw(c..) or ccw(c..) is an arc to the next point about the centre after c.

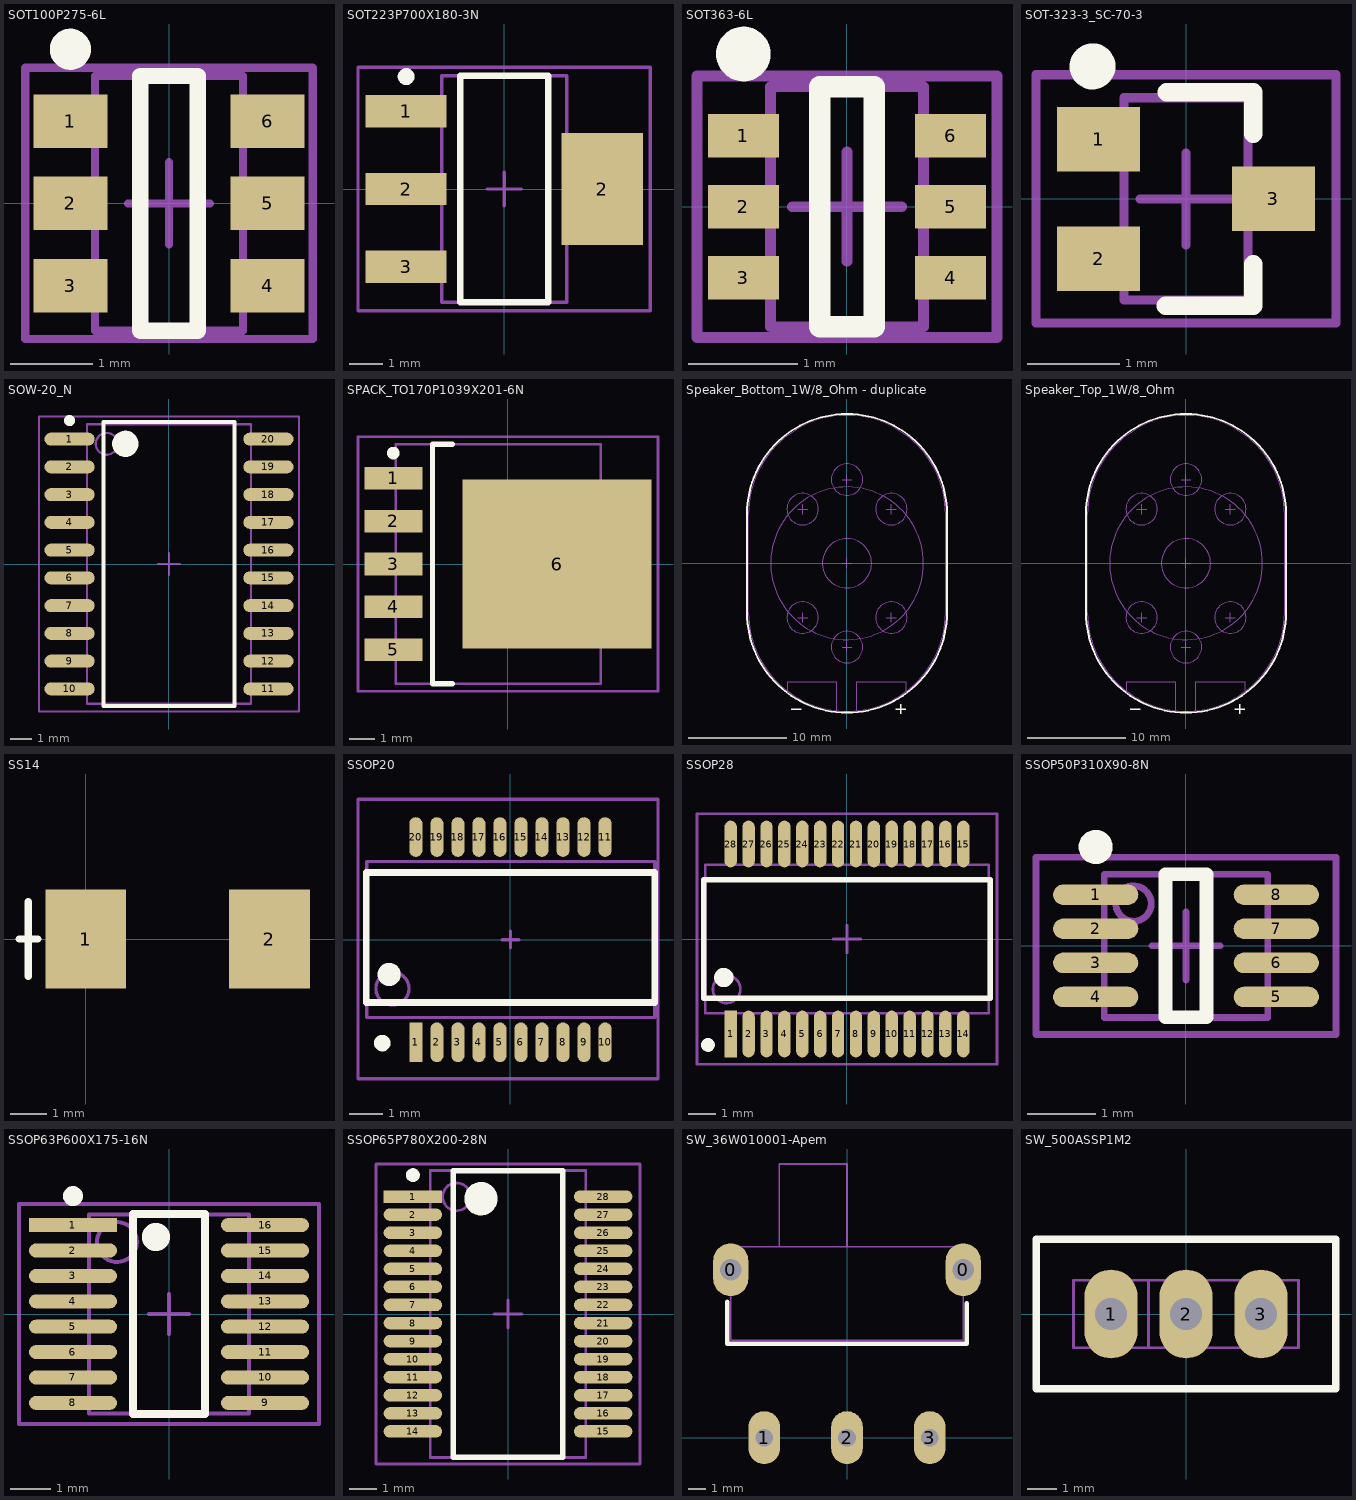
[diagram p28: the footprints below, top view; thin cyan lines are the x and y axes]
## SOT100P275-6L [mm] "SOT23, 6-Leads, Body 3x1.5mm, Pitch 1mm, Lead Span 2.7mm, IPC High Density"
height 1.1
pads (6):
  rect 0.9x0.65 smd: 1(-1.2,1) 2(-1.2,0) 3(-1.2,-1) 4(1.2,-1) 5(1.2,0) 6(1.2,1)
Top Overlay:
  circle w0.25: c-1.2,1.875 r0.125
  lines w0.2: -0.35,-1.55 -0.35,1.55 0.35,1.55 0.35,-1.55 -0.35,-1.55
M13_Assembly_Info:
  lines w0.1: -0.9,-1.55 0.9,-1.55 0.9,1.55 -0.9,1.55 -0.9,-1.55
M15_Country_Yard:
  lines w0.1: -0.5,0 0.5,0 ; 0,-0.5 0,0.5 ; -1.75,-1.65 1.75,-1.65 1.75,1.65 -1.75,1.65 -1.75,-1.65
3D body: height 1.1, standoff 0, extent -0.9,-1.55 0.9,1.55

## SOT223P700X180-3N [mm] "SOT223, 4-Leads, Body 6.7x7.3mm (max), Pitch 2.30mm, IPC Medium Density"
height 1.8
pads (4):
  rect 2.4x0.95 smd: 1(-2.9,2.3) 2(-2.9,0) 3(-2.9,-2.3)
  rect 2.4x3.3 smd: 2(2.9,0)
Top Overlay:
  circle w0.25: c-2.9,3.325 r0.125
  lines w0.2: -1.3,-3.35 -1.3,3.35 1.3,3.35 1.3,-3.35 -1.3,-3.35
M13_Assembly_Info:
  lines w0.1: -1.85,-3.35 -1.85,3.35 1.85,3.35 1.85,-3.35 -1.85,-3.35
M15_Country_Yard:
  lines w0.1: -0.5,0 0.5,0 ; 0,-0.5 0,0.5 ; -4.325,-3.6 -4.325,3.6 4.325,3.6 4.325,-3.6 -4.325,-3.6
3D body: height 1.8, standoff 0.02, extent -1.85,-3.35 1.85,3.35

## SOT363-6L [mm] "SOT363, 6-Leads, Body 2x1.3mm, Pitch 0.65mm, Lead Span 2.1mm, IPC High Density"
height 1
pads (6):
  rect 0.65x0.4 smd: 1(-0.95,0.65) 2(-0.95,0) 3(-0.95,-0.65) 4(0.95,-0.65) 5(0.95,0) 6(0.95,0.65)
Top Overlay:
  circle w0.25: c-0.95,1.4 r0.125
  lines w0.2: -0.25,-1.1 0.25,-1.1 0.25,1.1 -0.25,1.1 -0.25,-1.1
M13_Assembly_Info:
  lines w0.1: -0.7,-1.1 -0.7,1.1 0.7,1.1 0.7,-1.1 -0.7,-1.1
M15_Country_Yard:
  lines w0.1: -0.5,0 0.5,0 ; 0,-0.5 0,0.5 ; -1.375,-1.2 -1.375,1.2 1.375,1.2 1.375,-1.2 -1.375,-1.2
3D body: height 1, standoff 0, extent -0.7,-1.1 0.7,1.1

## SOT-323-3_SC-70-3 [mm] "SOT-323/SC-70, 3-Leads, Body 2.2x2.2mm (max), Pitch 0.65mm, IPC Medium Density"
height 1.1
pads (3):
  rect 0.9x0.7 smd: 1(-0.95,0.65) 2(-0.95,-0.65) 3(0.95,0)
Top Overlay:
  circle w0.25: c-1.015,1.44 r0.125
  lines w0.2: -0.22,-1.16 0.73,-1.16 0.73,-0.71 ; -0.21,1.16 0.73,1.16 0.73,0.71
M13_Assembly_Info:
  lines w0.1: -0.675,-1.1 0.675,-1.1 0.675,1.1 -0.675,1.1 -0.675,-1.1
M15_Country_Yard:
  lines w0.1: -0.5,0 0.5,0 ; 0,-0.5 0,0.5 ; -1.63,-1.35 1.63,-1.35 1.63,1.35 -1.63,1.35 -1.63,-1.35
3D body: height 1.1, standoff 0.1, extent -0.675,-1.1 0.675,1.1

## SOW-20_N [mm] "SOIC, 20-Leads, Body 12.8x7.5mm, Pitch 1.27mm, IPC Medium Density"
height 2.65
pads (20):
  oval 2.3x0.6 smd: 1(-4.55,5.715) 2(-4.55,4.445) 3(-4.55,3.175) 4(-4.55,1.905) 5(-4.55,0.635) 6(-4.55,-0.635) 7(-4.55,-1.905) 8(-4.55,-3.175) 9(-4.55,-4.445) 10(-4.55,-5.715) 11(4.55,-5.715) 12(4.55,-4.445) 13(4.55,-3.175) 14(4.55,-1.905) 15(4.55,-0.635) 16(4.55,0.635) 17(4.55,1.905) 18(4.55,3.175) 19(4.55,4.445) 20(4.55,5.715)
Top Overlay:
  circle w0.6: c-2,5.5 r0.3
  circle w0.25: c-4.55,6.565 r0.125
  lines w0.2: -3,-6.5 3,-6.5 3,6.5 -3,6.5 -3,-6.5
M13_Assembly_Info:
  circle w0.1: c-2.85,5.5 r0.5
  lines w0.1: -3.75,-6.4 3.75,-6.4 3.75,6.4 -3.75,6.4 -3.75,-6.4
M15_Country_Yard:
  lines w0.1: -0.5,0 0.5,0 ; 0,-0.5 0,0.5 ; -5.95,-6.75 5.95,-6.75 5.95,6.75 -5.95,6.75 -5.95,-6.75
3D body: height 2.65, standoff 0, extent -3.75,-6.4 3.75,6.4

## SPACK_TO170P1039X201-6N [mm] "S-PAK, 6-Pads, Body 8.1x9.5mm (max), IPC Medium Density"
height 2.01
pads (6):
  rect 2.3x0.9 smd: 1(-4.55,3.4) 2(-4.55,1.7) 3(-4.55,0) 4(-4.55,-1.7) 5(-4.55,-3.4)
  rect 7.5x6.7 smd: 6(1.95,0)
Top Overlay:
  circle w0.25: c-4.55,4.4 r0.125
  lines w0.2: -2.2,-4.75 -3,-4.75 -3,4.75 -2.2,4.75
M13_Assembly_Info:
  lines w0.1: -4.45,-4.75 3.68,-4.75 3.68,4.75 -4.45,4.75 -4.45,-4.75
M15_Country_Yard:
  lines w0.1: -0.5,0 0.5,0 ; 0,-0.5 0,0.5 ; -5.95,-5.05 5.95,-5.05 5.95,5.05 -5.95,5.05 -5.95,-5.05
3D body: height 2.01, standoff 0.13, extent -4.45,-4.75 3.68,4.75

## Speaker_Bottom_1W/8_Ohm - duplicate [mm] "Speaker; 1W; 8-Ohms; HONSON ACOUSTICS (SHENZHEN) CO., LTD; M3020N008041-R1206F-2"
height 2.65
Top Overlay:
  lines w0.127: -5.65,-14.79 -4.65,-14.79 ; 4.96,-14.79 5.96,-14.79 ; 5.46,-15.29 5.46,-14.29
  lines w0.2: -10.15,-5 ccw(c0,-5) 10.15,-5 10.15,5 ccw(c0,5) -10.15,5 -10.15,-5
M13_Assembly_Info:
  circle w0.1: c0,0 r2.5
  circle w0.1: c0,8.5 r1.6
  circle w0.1: c4.5,5.5 r1.6
  circle w0.1: c-4.5,5.5 r1.6
  circle w0.1: c-4.5,-5.5 r1.6
  circle w0.1: c4.5,-5.5 r1.6
  circle w0.1: c0,-8.5 r1.6
  circle w0.1: c0,0 r7.75
  lines w0.1: -6.03,-12.98 -6.03,-12 -1.03,-12 -1.03,-14.95 ; -5,-5.5 -4,-5.5 ; -5,5.5 -4,5.5 ; -4.5,-6 -4.5,-5 ; -4.5,5 -4.5,6 ; -0.5,-8.5 0.5,-8.5 ; -0.5,0 0.5,0 ; -0.5,8.5 0.5,8.5 ; 0,-9 0,-8 ; 0,-0.5 0,0.5 ; 0,8 0,9 ; 1,-14.95 1,-12 6,-12 6,-13 ; 4,-5.5 5,-5.5 ; 4,5.5 5,5.5 ; 4.5,-6 4.5,-5 ; 4.5,5 4.5,6 ; -10,-5 ccw(c0,-5) 10,-5 10,5 ccw(c0,5) -10,5 -10,-5
M15_Country_Yard:
  lines w0.1: -0.5,0 0.5,0 ; 0,-0.5 0,0.5
3D body: height 3.65, standoff -3.5, extent -10,-5 10,5
3D body: height -0.05, standoff -3.5, extent -9.921,-4.98 10,14.98
3D body: height -0.05, standoff -3.5, extent -9.35,-14.48 10.571,5.48
3D body: height 0, standoff -1.6, extent -7.689,-7.735 7.75,7.735

## Speaker_Top_1W/8_Ohm [mm] "Speaker; 1W; 8-Ohms; HONSON ACOUSTICS (SHENZHEN) CO., LTD; M3020N008041-R1206F-2"
height 2.65
Top Overlay:
  lines w0.127: -5.65,-14.79 -4.65,-14.79 ; 4.96,-14.79 5.96,-14.79 ; 5.46,-15.29 5.46,-14.29
  lines w0.2: -10.15,-5 ccw(c0,-5) 10.15,-5 10.15,5 ccw(c0,5) -10.15,5 -10.15,-5
M13_Assembly_Info:
  circle w0.1: c0,0 r2.5
  circle w0.1: c0,8.5 r1.6
  circle w0.1: c4.5,5.5 r1.6
  circle w0.1: c-4.5,5.5 r1.6
  circle w0.1: c-4.5,-5.5 r1.6
  circle w0.1: c4.5,-5.5 r1.6
  circle w0.1: c0,-8.5 r1.6
  circle w0.1: c0,0 r7.75
  lines w0.1: -6.03,-12.98 -6.03,-12 -1.03,-12 -1.03,-14.95 ; -5,-5.5 -4,-5.5 ; -5,5.5 -4,5.5 ; -4.5,-6 -4.5,-5 ; -4.5,5 -4.5,6 ; -0.5,-8.5 0.5,-8.5 ; -0.5,0 0.5,0 ; -0.5,8.5 0.5,8.5 ; 0,-9 0,-8 ; 0,-0.5 0,0.5 ; 0,8 0,9 ; 1,-14.95 1,-12 6,-12 6,-13 ; 4,-5.5 5,-5.5 ; 4,5.5 5,5.5 ; 4.5,-6 4.5,-5 ; 4.5,5 4.5,6 ; -10,-5 ccw(c0,-5) 10,-5 10,5 ccw(c0,5) -10,5 -10,-5
M15_Country_Yard:
  lines w0.1: -0.5,0 0.5,0 ; 0,-0.5 0,0.5
3D body: height 3.65, standoff 0.2, extent -10,-5 10,5
3D body: height 3.65, standoff 0.2, extent -9.921,-4.98 10,14.98
3D body: height 3.65, standoff 0.2, extent -9.921,-14.98 10,4.98
3D body: height 0, standoff -1.6, extent -7.689,-7.735 7.75,7.735

## SS14 [mm]
pads (2):
  rect 2.2x2.7 smd: 1(0,0) 2(5,0)
Top Overlay:
  lines w0.2: -1.818,0 -1.31,0 ; -1.564,-1.016 -1.564,1.016

## SSOP20 [mm] "SSOP20"
height 1.75
pads (20):
  rect 0.4x1.2 smd: 1(-2.857,-3.1)
  oval 0.4x1.2 smd: 2(-2.222,-3.1) 3(-1.587,-3.1) 4(-0.953,-3.1) 5(-0.318,-3.1) 6(0.318,-3.1) 7(0.953,-3.1) 8(1.587,-3.1) 9(2.222,-3.1) 10(2.857,-3.1) 11(2.857,3.1) 12(2.222,3.1) 13(1.587,3.1) 14(0.953,3.1) 15(0.318,3.1) 16(-0.318,3.1) 17(-0.953,3.1) 18(-1.587,3.1) 19(-2.222,3.1) 20(-2.857,3.1)
Top Overlay:
  circle w0.5: c-3.666,-1.05 r0.1
  circle w0.25: c-3.872,-3.125 r0.125
  lines w0.2: -4.356,-1.9 4.356,-1.9 4.356,2.029 -4.356,2.029 -4.356,-1.9
M13_Assembly_Info:
  circle w0.1: c-3.566,-1.475 r0.5
  lines w0.1: -4.346,-2.35 -4.346,2.361 4.356,2.361 4.356,-2.35 -4.346,-2.35
M15_Country_Yard:
  lines w0.1: -0.254,0 0.254,0 ; 0,-0.254 0,0.254 ; -4.606,-4.2 -4.606,4.241 4.458,4.241 4.458,-4.2 -4.606,-4.2
3D body: height 0, standoff 0, extent -4.341,-2.35 4.28,2.361

## SSOP28 [mm] "SSOP; 28 Leads; Body Width 5.3 mm; Pitch 0.65 mm"
height 1.99
pads (28):
  rect 0.45x1.7 smd: 1(-4.225,-3.45)
  oval 0.45x1.7 smd: 2(-3.575,-3.45) 3(-2.925,-3.45) 4(-2.275,-3.45) 5(-1.625,-3.45) 6(-0.975,-3.45) 7(-0.325,-3.45) 8(0.325,-3.45) 9(0.975,-3.45) 10(1.625,-3.45) 11(2.275,-3.45) 12(2.925,-3.45) 13(3.575,-3.45) 14(4.225,-3.45) 15(4.225,3.45) 16(3.575,3.45) 17(2.925,3.45) 18(2.275,3.45) 19(1.625,3.45) 20(0.975,3.45) 21(0.325,3.45) 22(-0.325,3.45) 23(-0.975,3.45) 24(-1.625,3.45) 25(-2.275,3.45) 26(-2.925,3.45) 27(-3.575,3.45) 28(-4.225,3.45)
Top Overlay:
  circle w0.5: c-4.475,-1.4 r0.1
  circle w0.25: c-5.05,-3.85 r0.125
  lines w0.2: -5.2,-2.15 5.2,-2.15 5.2,2.15 -5.2,2.15 -5.2,-2.15
M13_Assembly_Info:
  circle w0.1: c-4.375,-1.825 r0.5
  lines w0.1: -5.15,-2.7 -5.15,2.7 5.15,2.7 5.15,-2.7 -5.15,-2.7
M15_Country_Yard:
  lines w0.1: -0.5,0 0.5,0 ; 0,-0.5 0,0.5 ; -5.45,-4.55 -5.45,4.55 5.45,4.55 5.45,-4.55 -5.45,-4.55
3D body: height 0, standoff 0, extent -5.15,-2.7 5.15,2.7

## SSOP50P310X90-8N [mm] "SSOP, 8-Leads, Body 2.1x2.4mm (max), Pitch 0.50mm, IPC Medium Density"
height 0.9
pads (8):
  oval 1.25x0.3 smd: 1(-1.325,0.75) 2(-1.325,0.25) 3(-1.325,-0.25) 4(-1.325,-0.75) 5(1.325,-0.75) 6(1.325,-0.25) 7(1.325,0.25) 8(1.325,0.75)
Top Overlay:
  circle w0.25: c-1.325,1.45 r0.125
  lines w0.2: -0.3,-1.05 -0.3,1.05 0.3,1.05 0.3,-1.05 -0.3,-1.05
M13_Assembly_Info:
  circle w0.1: c-0.77,0.62 r0.26
  lines w0.1: -1.2,-1.05 -1.2,1.05 1.2,1.05 1.2,-1.05 -1.2,-1.05
M15_Country_Yard:
  lines w0.1: -0.5,0 0.5,0 ; 0,-0.5 0,0.5 ; -2.2,-1.3 -2.2,1.3 2.2,1.3 2.2,-1.3 -2.2,-1.3
3D body: height 0.9, standoff 0.1, extent -1.2,-1.05 1.2,1.05

## SSOP63P600X175-16N [mm] "SOP, 16-Leads, Body 5.0x4.0mm (max), Pitch 0.63mm, IPC Medium Density"
height 1.75
pads (16):
  rect 2.2x0.35 smd: 1(-2.4,2.222)
  oval 2.2x0.35 smd: 2(-2.4,1.587) 3(-2.4,0.953) 4(-2.4,0.318) 5(-2.4,-0.318) 6(-2.4,-0.953) 7(-2.4,-1.587) 8(-2.4,-2.222) 9(2.4,-2.222) 10(2.4,-1.587) 11(2.4,-0.953) 12(2.4,-0.318) 13(2.4,0.318) 14(2.4,0.953) 15(2.4,1.587) 16(2.4,2.222)
Top Overlay:
  circle w0.6: c-0.325,1.925 r0.05
  circle w0.25: c-2.4,2.947 r0.125
  lines w0.2: -0.9,-2.5 0.9,-2.5 0.9,2.5 -0.9,2.5 -0.9,-2.5
M13_Assembly_Info:
  circle w0.1: c-1.3,1.8 r0.5
  lines w0.1: -1.995,-2.49 1.995,-2.49 1.995,2.49 -1.995,2.49 -1.995,-2.49
M15_Country_Yard:
  lines w0.1: -0.5,0 0.5,0 ; 0,-0.5 0,0.5 ; -3.75,-2.75 3.75,-2.75 3.75,2.75 -3.75,2.75 -3.75,-2.75
3D body: height 1.75, standoff 0.25, extent -1.995,-2.49 1.995,2.49

## SSOP65P780X200-28N [mm] "SSOP, 28-Leads, Body 10.3x5.6mm (max), Pitch 0.65mm, IPC Medium Density"
height 2
pads (28):
  rect 2.1x0.45 smd: 1(-3.425,4.225)
  oval 2.1x0.45 smd: 2(-3.425,3.575) 3(-3.425,2.925) 4(-3.425,2.275) 5(-3.425,1.625) 6(-3.425,0.975) 7(-3.425,0.325) 8(-3.425,-0.325) 9(-3.425,-0.975) 10(-3.425,-1.625) 11(-3.425,-2.275) 12(-3.425,-2.925) 13(-3.425,-3.575) 14(-3.425,-4.225) 15(3.425,-4.225) 16(3.425,-3.575) 17(3.425,-2.925) 18(3.425,-2.275) 19(3.425,-1.625) 20(3.425,-0.975) 21(3.425,-0.325) 22(3.425,0.325) 23(3.425,0.975) 24(3.425,1.625) 25(3.425,2.275) 26(3.425,2.925) 27(3.425,3.575) 28(3.425,4.225)
Top Overlay:
  circle w0.25: c-3.425,5 r0.125
  circle w0.6: c-0.975,4.15 r0.3
  lines w0.2: -1.975,-5.15 -1.975,5.15 1.975,5.15 1.975,-5.15 -1.975,-5.15
M13_Assembly_Info:
  circle w0.1: c-1.85,4.22 r0.5
  lines w0.1: -2.8,-5.17 -2.8,5.17 2.8,5.17 2.8,-5.17 -2.8,-5.17
M15_Country_Yard:
  lines w0.1: -0.5,0 0.5,0 ; 0,-0.5 0,0.5 ; -4.75,-5.4 -4.75,5.4 4.75,5.4 4.75,-5.4 -4.75,-5.4
3D body: height 2.02, standoff -0.13, extent -3.928,-5.18 3.828,5.15

## SW_36W010001-Apem [mm] "Minature Slide Switch; R/A SP-DT; Apem; 36W010001"
height 6.6
pads (5):
  oval 2x3 hole 1.2: 0(-6.6,9.53) 0(6.6,9.53)
  oval 1.8x3 hole 1: 1(-4.7,0) 2(0,0) 3(4.7,0)
Top Overlay:
  lines w0.254: -6.8,7.71 -6.8,5.33 6.8,5.33 6.8,7.63
M13_Assembly_Info:
  lines w0.1: -3.85,10.83 -3.85,15.53 0,15.53 0,10.83 ; -6.6,5.53 -6.6,10.83 6.6,10.83 6.6,5.53 -6.6,5.53
3D body: height 6.6, standoff 0, extent -6.6,5.53 6.6,10.83

## SW_500ASSP1M2 [mm] "500A series; Sub-Minature; Slide Switch;SP-DT; E-Switch"
height 10.94
pads (3):
  oval 1.8x3 hole 1.09: 1(-2.54,0) 2(0,0) 3(2.54,0)
Top Overlay:
  lines w0.254: -5.08,-2.54 5.08,-2.54 5.08,2.54 -5.08,2.54 -5.08,-2.54
M13_Assembly_Info:
  lines w0.1: -1.27,-1.143 -1.27,1.143 ; -1.27,-1.143 -3.81,-1.143 -3.81,1.143 -1.27,1.143 ; -1.27,-1.143 3.81,-1.143 3.81,1.143 -1.27,1.143 ; -5.08,-2.54 -5.08,2.54 5.08,2.54 5.08,-2.54 -5.08,-2.54
3D body: height 0, standoff 0, extent -5.08,-2.54 5.08,2.54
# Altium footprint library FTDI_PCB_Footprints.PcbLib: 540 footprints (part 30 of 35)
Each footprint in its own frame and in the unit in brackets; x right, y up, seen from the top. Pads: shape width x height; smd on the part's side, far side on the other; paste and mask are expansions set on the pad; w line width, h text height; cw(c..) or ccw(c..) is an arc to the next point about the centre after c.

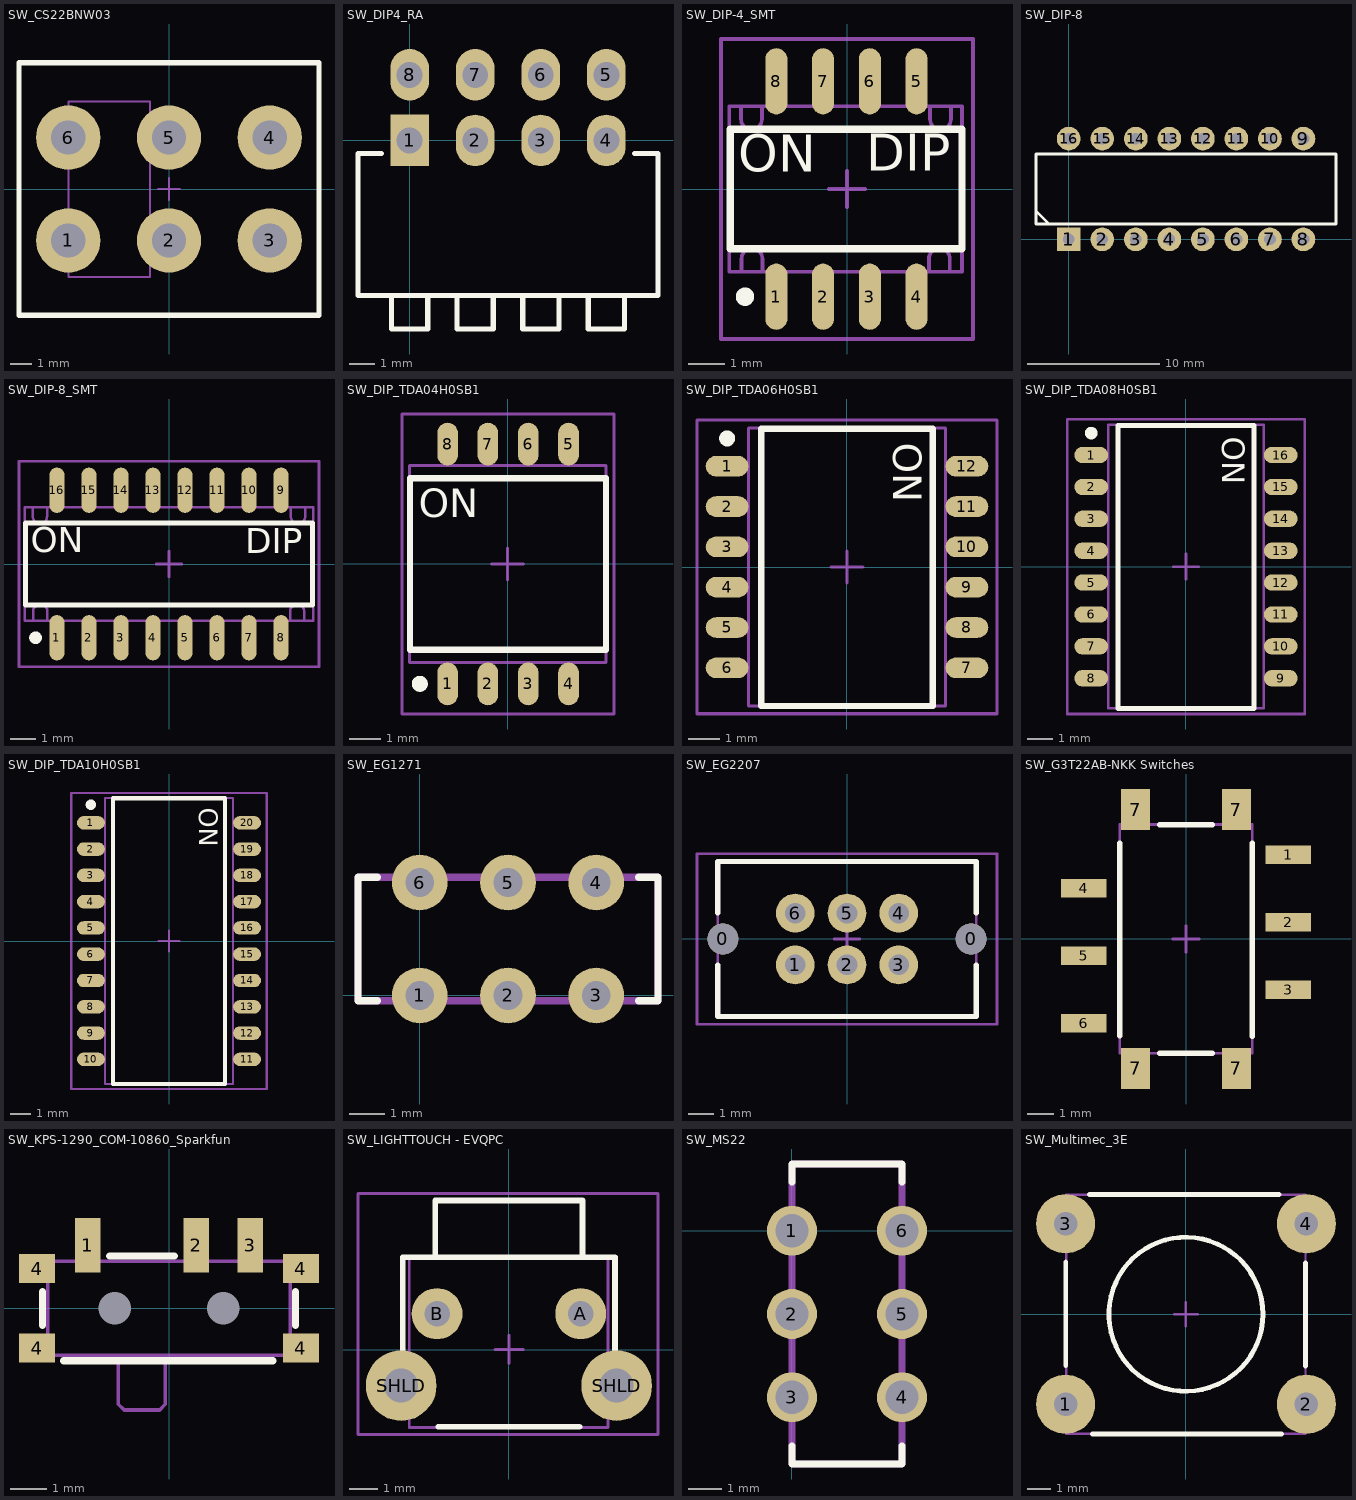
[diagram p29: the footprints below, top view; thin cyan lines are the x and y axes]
## SW_CS22BNW03 [mm] "Switch; DPDT; Minature; Power Rated; NKK Switches"
height 14.8
pads (6):
  round 3 hole 1.6: 1(-4.7,-2.4) 2(0,-2.4) 3(4.7,-2.4) 4(4.7,2.4) 5(0,2.4) 6(-4.7,2.4)
Top Overlay:
  lines w0.254: -7,-5.9 -7,5.9 7,5.9 7,-5.9 -7,-5.9
M13_Assembly_Info:
  lines w0.1: -7,-5.9 -7,5.9 7,5.9 7,-5.9 -7,-5.9 ; -4.69,-4.11 -4.69,4.09 -0.89,4.09 -0.89,-4.11 -4.69,-4.11
M15_Country_Yard:
  lines w0.1: -0.5,0 0.5,0 ; 0,-0.5 0,0.5
3D body: height 0, standoff 0, extent -7,-5.9 7,5.9

## SW_DIP4_RA [mm]
height 9.65
pads (8):
  rect 1.5x2 hole 1: 1(0,0)
  oval 1.5x2 hole 1: 2(2.54,0) 3(5.08,0) 4(7.62,0) 5(7.62,2.54) 6(5.08,2.54) 7(2.54,2.54) 8(0,2.54)
Top Overlay:
  lines w0.2: -1.103,-0.5 -2,-0.5 -2,-6 9.62,-6 9.62,-0.5 8.722,-0.5 ; -0.7,-6.003 -0.7,-7.302 0.7,-7.302 0.7,-6.003 ; 1.84,-6.003 1.84,-7.302 3.24,-7.302 3.24,-6.003 ; 4.38,-6.003 4.38,-7.302 5.78,-7.302 5.78,-6.003 ; 6.92,-6.003 6.92,-7.302 8.32,-7.302 8.32,-6.003
3D body: height 3.6, standoff 2, extent 6.92,-7.3 8.32,-6
3D body: height 3.6, standoff 2, extent 4.38,-7.3 5.78,-6
3D body: height 3.6, standoff 2, extent 1.84,-7.3 3.24,-6
3D body: height 3.6, standoff 2, extent -0.7,-7.3 0.7,-6
3D body: height 9.9, standoff 0, extent -2,-6 9.62,-0.5

## SW_DIP-4_SMT [mm] "DIP Switch; SMT"
height 1.5
pads (8):
  oval 0.6x1.8 smd: 1(-1.92,-2.925) 2(-0.65,-2.925) 3(0.62,-2.925) 4(1.89,-2.925) 5(1.89,2.925) 6(0.62,2.925) 7(-0.65,2.925) 8(-1.92,2.925)
Top Overlay:
  circle w0.25: c-2.77,-2.925 r0.125
  lines w0.2: -3.175,-1.625 3.125,-1.625 3.125,1.625 -3.175,1.625 -3.175,-1.625
  text "ON" at -2.952,0.466 h1
  text "DIP" at 0.525,0.5 h1
M13_Assembly_Info:
  lines w0.1: -2.879,2.249 -2.879,1.892 ccw(c-2.595,1.892) -2.311,1.892 -2.311,2.25 ; -2.866,-2.25 -2.866,-1.892 cw(c-2.582,-1.892) -2.298,-1.892 -2.298,-2.249 ; 2.226,-2.25 2.226,-1.892 cw(c2.51,-1.892) 2.794,-1.892 2.794,-2.25 ; 2.256,2.249 2.256,1.892 ccw(c2.54,1.892) 2.824,1.892 2.824,2.25 ; -3.2,-2.25 3.125,-2.25 3.125,2.25 -3.2,2.25 -3.2,-2.25
M15_Country_Yard:
  lines w0.1: -0.5,0 0.5,0 ; 0,-0.5 0,0.5 ; -3.425,-4.075 3.425,-4.075 3.425,4.075 -3.425,4.075 -3.425,-4.075
3D body: height 1.5, standoff 0.1, extent -3.2,-2.25 3.125,2.25

## SW_DIP-8 [mm] "Switch DIP; 8 way; 16 Leads; Row Spacing 7.62 mm; Pitch 2.54 mm"
height 5.08
pads (16):
  rect 1.8x1.8 hole 0.9: 1(0,0)
  round 1.8 hole 0.9: 2(2.54,0) 3(5.08,0) 4(7.62,0) 5(10.16,0) 6(12.7,0) 7(15.24,0) 8(17.78,0) 9(17.78,7.62) 10(15.24,7.62) 11(12.7,7.62) 12(10.16,7.62) 13(7.62,7.62) 14(5.08,7.62) 15(2.54,7.62) 16(0,7.62)
Top Overlay:
  lines w0.2: -2.48,2.15 -1.495,1.165 ; -2.48,1.16 -2.48,6.46 20.25,6.46 20.25,1.16 -2.48,1.16

## SW_DIP-8_SMT [mm] "DIP Switch; SMT"
height 1.5
pads (16):
  oval 0.6x1.8 smd: 1(-4.445,-2.925) 2(-3.175,-2.925) 3(-1.905,-2.925) 4(-0.635,-2.925) 5(0.635,-2.925) 6(1.905,-2.925) 7(3.175,-2.925) 8(4.445,-2.925) 9(4.445,2.925) 10(3.175,2.925) 11(1.905,2.925) 12(0.635,2.925) 13(-0.635,2.925) 14(-1.905,2.925) 15(-3.175,2.925) 16(-4.445,2.925)
Top Overlay:
  circle w0.25: c-5.295,-2.925 r0.125
  lines w0.2: -5.7,-1.625 -5.7,1.625 5.7,1.625 5.7,-1.625 -5.7,-1.625
  text "DIP" at 3.022,0.423 h1
  text "ON" at -5.477,0.466 h1
M13_Assembly_Info:
  lines w0.1: -5.404,2.249 -5.404,1.892 ccw(c-5.12,1.892) -4.836,1.892 -4.836,2.25 ; -5.391,-2.25 -5.391,-1.892 cw(c-5.107,-1.892) -4.823,-1.892 -4.823,-2.249 ; 4.801,-2.25 4.801,-1.892 cw(c5.085,-1.892) 5.369,-1.892 5.369,-2.249 ; 4.831,2.249 4.831,1.892 ccw(c5.115,1.892) 5.399,1.892 5.399,2.25 ; -5.725,-2.25 -5.725,2.25 5.725,2.25 5.725,-2.25 -5.725,-2.25
M15_Country_Yard:
  lines w0.1: -0.5,0 0.5,0 ; 0,-0.5 0,0.5 ; -5.95,-4.075 -5.95,4.075 5.95,4.075 5.95,-4.075 -5.95,-4.075
3D body: height 1.5, standoff 0.1, extent -5.725,-2.25 5.725,2.25

## SW_DIP_TDA04H0SB1 [mm] "DIP Switch; Half pitch (1.27mm); 4 possitions; C&K; TDA04H0SB1"
height 2.3
pads (8):
  oval 0.65x1.35 smd: 1(-1.89,-3.775) 2(-0.62,-3.775) 3(0.65,-3.775) 4(1.92,-3.775) 5(1.92,3.775) 6(0.65,3.775) 7(-0.62,3.775) 8(-1.89,3.775)
Top Overlay:
  circle w0.25: c-2.765,-3.775 r0.125
  lines w0.2: -3.075,-2.7 -3.075,2.7 3.1,2.7 3.1,-2.7 -3.075,-2.7
  text "ON" at -2.8,1.475 h0.9
M13_Assembly_Info:
  lines w0.1: -3.09,-3.1 -3.09,3.1 3.1,3.1 3.1,-3.1 -3.09,-3.1
M15_Country_Yard:
  lines w0.1: -0.5,0 0.5,0 ; 0,-0.5 0,0.5 ; -3.325,-4.725 -3.325,4.725 3.35,4.725 3.35,-4.725 -3.325,-4.725
3D body: height 0.15, standoff 0, extent 1.7,-4.1 2.15,-3.5
3D body: height 0.55, standoff 0, extent 1.7,-3.5 2.15,-3.35
3D body: height 0.55, standoff 0.4, extent 1.7,-3.35 2.15,-2.95
3D body: height 0.15, standoff 0, extent 0.425,-4.1 0.875,-3.5
3D body: height 0.55, standoff 0, extent 0.425,-3.5 0.875,-3.35
3D body: height 0.55, standoff 0.4, extent 0.425,-3.35 0.875,-2.95
3D body: height 0.15, standoff 0, extent -0.85,-4.1 -0.4,-3.5
3D body: height 0.55, standoff 0, extent -0.85,-3.5 -0.4,-3.35
3D body: height 0.55, standoff 0.4, extent -0.85,-3.35 -0.4,-2.95
3D body: height 0.15, standoff 0, extent -2.1,-4.1 -1.65,-3.5
3D body: height 0.55, standoff 0, extent -2.1,-3.5 -1.65,-3.35
3D body: height 0.55, standoff 0.4, extent -2.1,-3.35 -1.65,-2.95
3D body: height 0.15, standoff 0, extent -2.125,3.5 -1.675,4.1
3D body: height 0.55, standoff 0, extent -2.125,3.35 -1.675,3.5
3D body: height 0.55, standoff 0.4, extent -2.125,2.95 -1.675,3.35
3D body: height 0.15, standoff 0, extent -0.85,3.5 -0.4,4.1
3D body: height 0.55, standoff 0, extent -0.85,3.35 -0.4,3.5
3D body: height 0.55, standoff 0.4, extent -0.85,2.95 -0.4,3.35
3D body: height 0.15, standoff 0, extent 0.425,3.5 0.875,4.1
3D body: height 0.55, standoff 0, extent 0.425,3.35 0.875,3.5
3D body: height 0.55, standoff 0.4, extent 0.425,2.95 0.875,3.35
3D body: height 0.55, standoff 0.4, extent 1.7,2.95 2.15,3.35
3D body: height 0.55, standoff 0, extent 1.7,3.35 2.15,3.5
3D body: height 0.15, standoff 0, extent 1.7,3.5 2.15,4.1
3D body: height 1.9, standoff 0.1, extent -3.1,-3.1 3.09,3.1
3D body: height 2.3, standoff 1.9, extent -3.1,2 3.1,3.1
3D body: height 2.3, standoff 1.9, extent -3.1,-3.1 3.1,-2
3D body: height 2.3, standoff 1.9, extent -2.2,-0.7 -1.6,0
3D body: height 2, standoff 1.3, extent -2.2,0 -1.6,0.7
3D body: height 2, standoff 1.3, extent -0.925,0 -0.325,0.7
3D body: height 2.3, standoff 1.9, extent -0.925,-0.7 -0.325,0
3D body: height 2, standoff 1.3, extent 0.35,0 0.95,0.7
3D body: height 2.3, standoff 1.9, extent 0.35,-0.7 0.95,0
3D body: height 2, standoff 1.3, extent 1.625,0 2.225,0.7
3D body: height 2.3, standoff 1.9, extent 1.625,-0.7 2.225,0

## SW_DIP_TDA06H0SB1 [mm] "DIP Switch; Half pitch (1.27mm); 6 possitions; C&K; TDA06H0SB1"
height 2.3
pads (12):
  oval 1.35x0.65 smd: 1(-3.775,3.175) 2(-3.775,1.905) 3(-3.775,0.635) 4(-3.775,-0.635) 5(-3.775,-1.905) 6(-3.775,-3.175) 7(3.775,-3.175) 8(3.775,-1.905) 9(3.775,-0.635) 10(3.775,0.635) 11(3.775,1.905) 12(3.775,3.175)
Top Overlay:
  circle w0.25: c-3.775,4.05 r0.125
  lines w0.2: -2.7,-4.38 2.7,-4.38 2.7,4.36 -2.7,4.36 -2.7,-4.38
  text "ON" at 1.45,3.91 h0.9
M13_Assembly_Info:
  lines w0.1: -3.1,-4.38 3.1,-4.38 3.1,4.375 -3.1,4.375 -3.1,-4.38
M15_Country_Yard:
  lines w0.1: -0.5,0 0.5,0 ; 0,-0.5 0,0.5 ; -4.725,-4.62 4.725,-4.62 4.725,4.63 -4.725,4.63 -4.725,-4.62
3D body: height 2.3, standoff 0.1, extent -3.1,-4.37 3.1,4.375

## SW_DIP_TDA08H0SB1 [mm] "DIP Switch; Half pitch (1.27mm); 8 possitions; C&K; TDA08H0SB1"
height 2.3
pads (16):
  oval 1.35x0.65 smd: 1(-3.775,4.445) 2(-3.775,3.175) 3(-3.775,1.905) 4(-3.775,0.635) 5(-3.775,-0.635) 6(-3.775,-1.905) 7(-3.775,-3.175) 8(-3.775,-4.445) 9(3.775,-4.445) 10(3.775,-3.175) 11(3.775,-1.905) 12(3.775,-0.635) 13(3.775,0.635) 14(3.775,1.905) 15(3.775,3.175) 16(3.775,4.445)
Top Overlay:
  circle w0.25: c-3.775,5.32 r0.125
  lines w0.2: -2.7,-5.645 2.7,-5.645 2.7,5.63 -2.7,5.63 -2.7,-5.645
  text "ON" at 1.45,5.18 h0.9
M13_Assembly_Info:
  lines w0.1: -3.1,-5.645 3.1,-5.645 3.1,5.645 -3.1,5.645 -3.1,-5.645
M15_Country_Yard:
  lines w0.1: -0.5,0.005 0.5,0.005 ; 0,-0.495 0,0.505 ; -4.725,-5.87 4.725,-5.87 4.725,5.88 -4.725,5.88 -4.725,-5.87
3D body: height 2.3, standoff 0.1, extent -3.1,-5.645 3.1,5.645

## SW_DIP_TDA10H0SB1 [mm] "DIP Switch; Half pitch (1.27mm); 10 possitions; C&K; TDA10H0SB1"
height 2.3
pads (20):
  oval 1.35x0.65 smd: 1(-3.775,5.715) 2(-3.775,4.445) 3(-3.775,3.175) 4(-3.775,1.905) 5(-3.775,0.635) 6(-3.775,-0.635) 7(-3.775,-1.905) 8(-3.775,-3.175) 9(-3.775,-4.445) 10(-3.775,-5.715) 11(3.775,-5.715) 12(3.775,-4.445) 13(3.775,-3.175) 14(3.775,-1.905) 15(3.775,-0.635) 16(3.775,0.635) 17(3.775,1.905) 18(3.775,3.175) 19(3.775,4.445) 20(3.775,5.715)
Top Overlay:
  circle w0.25: c-3.775,6.59 r0.125
  lines w0.2: -2.7,-6.9 -2.7,6.9 2.7,6.9 2.7,-6.9 -2.7,-6.9
  text "ON" at 1.45,6.45 h0.9
M13_Assembly_Info:
  lines w0.1: -3.1,-6.915 -3.1,6.915 3.1,6.915 3.1,-6.915 -3.1,-6.915
M15_Country_Yard:
  lines w0.1: -0.5,0 0.5,0 ; 0,-0.5 0,0.5 ; -4.725,-7.15 -4.725,7.15 4.725,7.15 4.725,-7.15 -4.725,-7.15
3D body: height 2.3, standoff 0.1, extent -3.1,-6.915 3.1,6.915

## SW_EG1271 [mm] "Switch; SPDT; E Switch EG1271A"
pads (6):
  round 1.575 hole 0.813: 1(0,0) 2(2.5,0) 3(5,0) 4(5,3.2) 5(2.5,3.2) 6(0,3.2)
Top Overlay:
  lines w0.2: -1.2,-0.15 -1.75,-0.15 -1.75,3.35 -1.2,3.35 ; 6.2,-0.15 6.75,-0.15 6.75,3.35 6.2,3.35
M13_Assembly_Info:
  lines w0.2: -1.75,-0.15 6.75,-0.15 6.75,3.35 -1.75,3.35 -1.75,-0.15

## SW_EG2207 [mm] "Switch; SPDT; E Switch EG2207"
pads (8):
  round 1.2 hole 1.2 unplated: 0(-4.8,0) 0(4.8,0)
  round 1.5 hole 0.8: 1(-2,-1) 2(0,-1) 3(2,-1) 4(2,1) 5(0,1) 6(-2,1)
Top Overlay:
  lines w0.2: -5,-1 -5,-3 5,-3 5,-1 ; -5,1 -5,3 5,3 5,1
M13_Assembly_Info:
  lines w0.1: -5,-3 5,-3 5,3 -5,3 -5,-3
M15_Country_Yard:
  lines w0.1: -0.5,0 0.5,0 ; 0,-0.5 0,0.5 ; -5.8,-3.3 -5.8,3.3 5.8,3.3 5.8,-3.3 -5.8,-3.3

## SW_G3T22AB-NKK Switches [mm] "Switch; DPDT; Process Sealed Ultra-Miniature SMT Toggle Switch"
height 9
pads (10):
  rect 1.7x0.7 smd: 1(3.85,3.175) 2(3.85,0.635) 3(3.85,-1.905) 4(-3.85,1.905) 5(-3.85,-0.635) 6(-3.85,-3.175)
  rect 1.1x1.55 smd: 7(-1.9,-4.875) 7(-1.9,4.875) 7(1.9,-4.875) 7(1.9,4.875)
Top Overlay:
  lines w0.2: -2.5,-3.64 -2.5,3.61 ; -1,-4.3 1,-4.3 ; -1,4.3 1,4.3 ; 2.5,-3.67 2.5,3.61
M13_Assembly_Info:
  lines w0.1: -2.5,-4.3 2.5,-4.3 2.5,4.31 -2.5,4.31 -2.5,-4.3
M15_Country_Yard:
  lines w0.1: -0.5,0 0.5,0 ; 0,-0.5 0,0.5
3D body: height 0, standoff 0, extent -2.5,-4.3 2.52,4.31

## SW_KPS-1290_COM-10860_Sparkfun [mm] "Surface Mount Right Angle Switch; Sparkfun COM-10860"
height 1.4
pads (9):
  round 0 hole 0.9: 0(-1.5,0) 0(1.5,0)
  rect 0.7x1.5 smd: 1(-2.25,1.75) 2(0.75,1.75) 3(2.25,1.75)
  rect 1x0.8 smd: 4(-3.65,-1.1) 4(-3.65,1.1) 4(3.65,-1.1) 4(3.65,1.1)
Top Overlay:
  lines w0.2: -3.5,-0.47 -3.5,0.47 ; -2.91,-1.45 2.88,-1.45 ; -1.64,1.45 0.15,1.45 ; 3.5,-0.47 3.5,0.47
M13_Assembly_Info:
  lines w0.1: -3.35,-0.9 -3.85,-0.9 -3.85,-1.3 -3.35,-1.3 ; -3.35,0.9 -3.85,0.9 -3.85,1.3 -3.35,1.3 ; -2.45,1.3 -2.45,2.2 -2.05,2.2 -2.05,1.3 ; -1.4,-1.31 -1.4,-2.65 -1.24,-2.81 -0.26,-2.81 -0.1,-2.65 -0.1,-1.31 ; 0.55,1.3 0.55,2.2 0.95,2.2 0.95,1.3 ; 2.05,1.3 2.05,2.2 2.45,2.2 2.45,1.3 ; 3.35,-0.9 3.85,-0.9 3.85,-1.3 3.35,-1.3 ; 3.35,0.9 3.85,0.9 3.85,1.3 3.35,1.3 ; -3.35,-1.3 3.35,-1.3 ; -3.35,-1.3 -3.35,1.3 ; -3.35,1.3 3.35,1.3 ; 3.35,-1.3 3.35,1.3
3D body: height 1.3, standoff 0.1, extent -1.4,-2.81 -0.1,-1.31
3D body: height 1.4, standoff 0, extent -3.35,-1.3 3.35,1.3

## SW_LIGHTTOUCH - EVQPC [mm] "Light Touch Switches"
pads (4):
  round 1.8 hole 0.9: A(2.54,1.275) B(-2.54,1.275)
  round 2.5 hole 1.2: SHLD(-3.81,-1.265) SHLD(3.81,-1.265)
Top Overlay:
  lines w0.2: -3.75,3.275 3.75,3.275 ; -2.6,3.275 -2.6,5.275 2.6,5.275 2.6,3.275
  lines w0.203: -3.75,-0.02 -3.75,3.25 ; -2.5,-2.725 2.5,-2.725 ; 3.75,-0.07 3.75,3.25
M13_Assembly_Info:
  lines w0.1: -3.525,-2.75 -3.525,3.25 3.5,3.25 3.5,-2.75 -3.525,-2.75
M15_Country_Yard:
  lines w0.1: -0.492,0.005 0.508,0.005 ; 0,-0.487 0,0.513 ; -5.334,-3 -5.334,5.529 5.271,5.529 5.271,-3 -5.334,-3
3D body: height 0, standoff 0, extent -3.525,-2.75 3.525,3.248

## SW_MS22 [mm] "Switch; DPDT; Apem; MS22"
height 5.5
pads (6):
  round 1.5 hole 1: 1(0,0) 2(0,-2.5) 3(0,-5) 4(3.3,-5) 5(3.3,-2.5) 6(3.3,0)
Top Overlay:
  lines w0.2: 0,-6.45 0,-7 3.3,-7 3.3,-6.45 ; 0,1.45 0,2 3.3,2 3.3,1.45
M13_Assembly_Info:
  lines w0.2: 0,-7 3.3,-7 3.3,2 0,2 0,-7
3D body: height 3.5, standoff 0, extent 0,-7 3.3,2
3D body: height 5.5, standoff 3.5, extent 0.925,-1.95 2.425,-0.45

## SW_Multimec_3E [mm] "3E series Push-Button Switch; Multimec"
height 10.4
pads (4):
  round 2.5 hole 1: 1(-5.075,-3.8) 2(5.085,-3.8) 3(-5.075,3.82) 4(5.085,3.82)
Top Overlay:
  circle w0.2: c0,0 r3.25
  lines w0.2: -5.075,-2.175 -5.075,2.2 ; -4.075,5.05 3.925,5.05 ; -3.95,-5.05 4.05,-5.05 ; 5.05,-2.2 5.05,2.175
M13_Assembly_Info:
  lines w0.1: -5.05,-5.05 5.05,-5.05 5.05,5.05 -5.05,5.05 -5.05,-5.05
M15_Country_Yard:
  lines w0.1: -0.5,0 0.5,0 ; 0,-0.5 0,0.5
3D body: height 0, standoff 0, extent -5.05,-5.05 5.05,5.05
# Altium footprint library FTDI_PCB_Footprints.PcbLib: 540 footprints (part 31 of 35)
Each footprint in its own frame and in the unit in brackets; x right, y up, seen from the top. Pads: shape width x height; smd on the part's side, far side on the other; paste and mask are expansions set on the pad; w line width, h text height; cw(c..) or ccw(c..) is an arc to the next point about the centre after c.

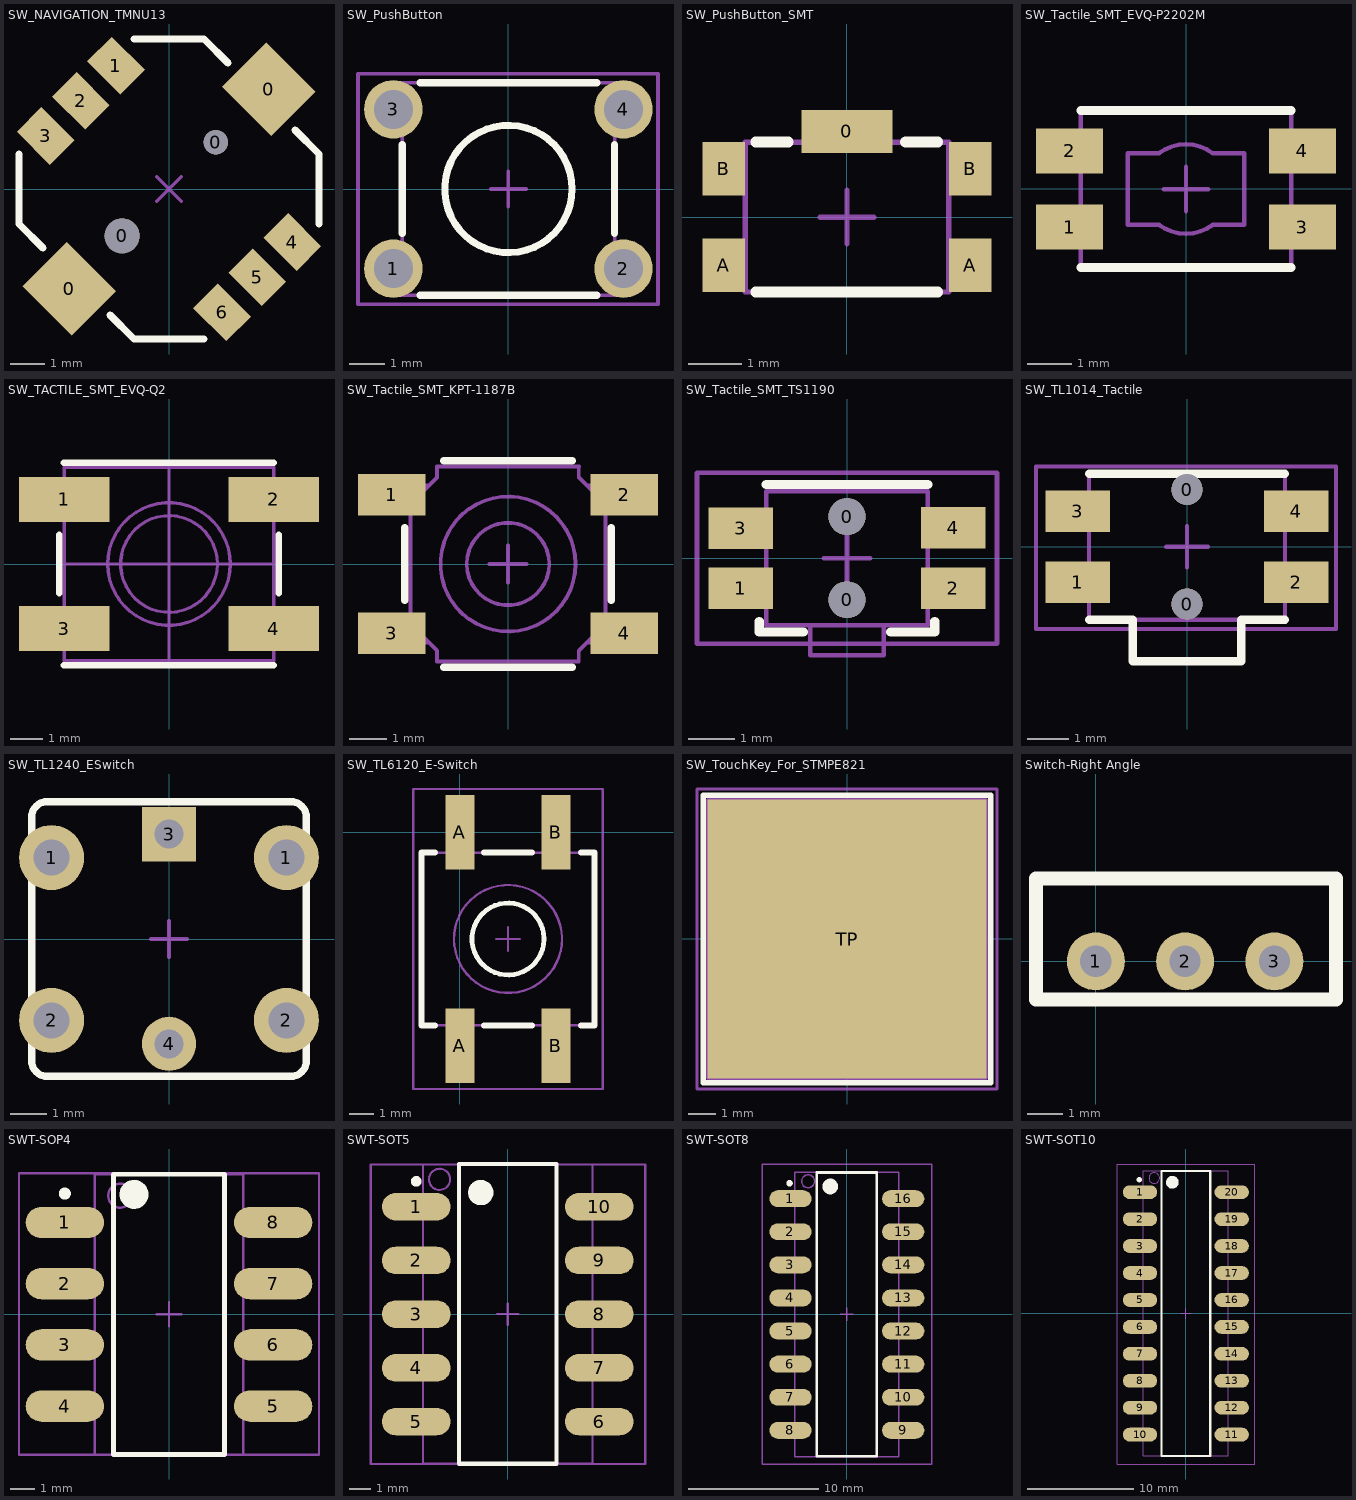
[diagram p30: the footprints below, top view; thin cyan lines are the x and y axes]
## SW_NAVIGATION_TMNU13 [mm] "TMHU13 navigation switch (joystick)"
height 5
pads (10):
  rect 2x1.8 smd rot 135: 0(-2.864,-2.864) 0(2.864,2.864)
  round 1 hole 1 unplated: 0(-1.344,-1.344)
  round 0.7 hole 0.7 unplated: 0(1.344,1.344)
  rect 1.35x1 smd rot 135: 1(-1.52,3.536) 2(-2.528,2.528) 3(-3.536,1.52) 4(3.536,-1.52) 5(2.528,-2.528) 6(1.52,-3.536)
Top Overlay:
  lines w0.2: -4.3,1.003 -4.3,-1.003 -3.606,-1.697 ; -1.698,-3.605 -1.004,-4.3 1.004,-4.3 ; -1.003,4.3 1.003,4.3 1.697,3.606 ; 3.606,1.698 4.3,1.004 4.3,-1.004
M15_Country_Yard:
  lines w0.1: -0.354,-0.354 0.354,0.354 ; -0.354,0.354 0.354,-0.354

## SW_PushButton [mm] "Push button switch"
pads (4):
  round 1.651 hole 1.1: 1(-3.25,-2.25) 2(3.25,-2.25) 3(-3.25,2.25) 4(3.25,2.25)
Top Overlay:
  circle w0.2: c0,0 r1.8
  lines w0.203: -3,-1.25 -3,1.25 ; -2.5,-3 2.5,-3 ; -2.5,3 2.5,3 ; 3,-1.25 3,1.25
M13_Assembly_Info:
  lines w0.1: -3,-3 3,-3 3,3 -3,3 -3,-3
M15_Country_Yard:
  lines w0.1: -0.5,0 0.5,0 ; 0,-0.5 0,0.5 ; -4.25,-3.25 4.225,-3.25 4.225,3.25 -4.25,3.25 -4.25,-3.25
3D body: height 0, standoff 0, extent -3,-3 3,3

## SW_PushButton_SMT [mm] "Push button switch"
pads (5):
  rect 1.7x0.8 smd: 0(0,1.599)
  rect 0.8x1 smd: A(-2.301,-0.9) A(2.302,-0.896) B(-2.301,0.901) B(2.302,0.901)
Top Overlay:
  lines w0.2: -1.702,-1.4 1.698,-1.4 ; -1.702,1.401 -1.098,1.401 ; 1.094,1.401 1.698,1.401
M13_Assembly_Info:
  lines w0.1: -1.9,-1.4 -1.9,1.4 1.9,1.4 1.9,-1.4 -1.9,-1.4
M15_Country_Yard:
  lines w0.1: -0.5,-0.002 0.5,-0.002 ; 0,-0.502 0,0.498
3D body: height 1.9, standoff 0, extent -1.9,-1.4 1.9,1.4

## SW_Tactile_SMT_EVQ-P2202M [mm] "Tactile Switch; EVQ-P2202M; Panasonic"
height 2.5
pads (4):
  rect 1.5x1 smd: 1(-2.6,-0.85) 2(-2.6,0.85) 3(2.6,-0.85) 4(2.6,0.85)
Top Overlay:
  lines w0.2: -2.35,-1.75 2.35,-1.75 ; -2.35,1.75 2.35,1.75
M13_Assembly_Info:
  lines w0.1: -1.3,-0.801 -0.599,-0.801 ccw(c0,0) 0.6,-0.8 1.3,-0.8 1.3,0.8 0.6,0.8 ccw(c0,0) -0.599,0.801 -1.3,0.801 ; -1.3,-0.8 -1.3,0.8 ; -2.35,-1.75 -2.35,1.75 2.35,1.75 2.35,-1.75 -2.35,-1.75
M15_Country_Yard:
  lines w0.1: -0.5,-0.002 0.5,-0.002 ; 0,-0.502 0,0.498
3D body: height 1.9, standoff 0, extent -2.35,-1.75 2.35,1.75

## SW_TACTILE_SMT_EVQ-Q2 [mm] "Tactile switch; EVQQ2K02W; Panasonic"
height 2.5
pads (4):
  rect 2.8x1.4 smd: 1(-3.25,2) 2(3.25,2) 3(-3.25,-2) 4(3.25,-2)
Top Overlay:
  lines w0.2: -3.4,-0.9 -3.4,0.9 ; -3.26,-3.14 3.25,-3.14 ; -3.26,3.14 3.25,3.14 ; 3.4,-0.9 3.4,0.9
M13_Assembly_Info:
  circle w0.1: c0,0 r1.9
  circle w0.1: c0,0 r1.5
  lines w0.1: -3.25,0 3.25,0 ; 0,-3 0,3 ; -3.25,-3 3.25,-3 3.25,3 -3.25,3 -3.25,-3
M15_Country_Yard:
  lines w0.1: -0.5,0 0.5,0 ; 0,-0.5 0,0.5
3D body: height 1.9, standoff 0, extent -3.25,-3 3.25,3

## SW_Tactile_SMT_KPT-1187B [mm] "Tactile Switch; KPT-1187B; On Shine Enterprise Co., Ltd."
height 1.6
pads (4):
  rect 1.8x1.1 smd: 1(-3.1,1.85) 2(3.1,1.85) 3(-3.1,-1.85) 4(3.1,-1.85)
Top Overlay:
  lines w0.2: -2.75,-0.96 -2.75,0.96 ; -1.71,-2.75 1.71,-2.75 ; -1.71,2.75 1.71,2.75 ; 2.75,-0.96 2.75,0.96
M13_Assembly_Info:
  circle w0.1: c0,0 r1.8
  circle w0.1: c0,0 r1.1
  lines w0.1: -2.1,-2.1 -3.2,-2.1 -3.2,-1.6 -2.6,-1.6 ; -2.1,2.1 -3.2,2.1 -3.2,1.6 -2.6,1.6 ; 2.1,-2.1 3.2,-2.1 3.2,-1.6 2.6,-1.6 ; 2.1,2.1 3.2,2.1 3.2,1.6 2.6,1.6 ; -2.6,-1.6 -2.6,1.6 ; -2.6,-1.6 -1.89,-2.31 -1.89,-2.6 1.89,-2.6 1.89,-2.31 2.6,-1.6 ; -2.6,1.6 -1.89,2.31 -1.89,2.6 1.89,2.6 1.89,2.31 2.6,1.6 ; 2.6,-1.6 2.6,1.6
M15_Country_Yard:
  lines w0.1: -0.5,0 0.5,0 ; 0,-0.5 0,0.5
3D body: height 1.9, standoff 0, extent -2.6,-2.6 2.6,2.6

## SW_Tactile_SMT_TS1190 [mm] "ZhengheSwitch; TS1190; Tactile; SMT; R/A;"
height 1.6
pads (6):
  round 0.8 hole 0.8 unplated: 0(0,-0.9) 0(0,0.9)
  rect 1.4x0.9 smd: 1(-2.3,-0.65) 2(2.3,-0.65) 3(-2.3,0.65) 4(2.3,0.66)
Top Overlay:
  lines w0.2: -1.9,-1.37 -1.9,-1.6 -0.95,-1.6 ; -1.75,1.6 1.75,1.6 ; 0.95,-1.6 1.9,-1.6 1.9,-1.37
M13_Assembly_Info:
  lines w0.1: -0.8,-1.45 -0.8,-2.1 0.8,-2.1 0.8,-1.45 ; -1.75,-1.45 -1.75,1.45 1.75,1.45 1.75,-1.45 -1.75,-1.45
M15_Country_Yard:
  lines w0.1: -0.5,0 0.5,0 ; 0,-0.5 0,0.5 ; -3.25,-1.85 -3.25,1.85 3.25,1.85 3.25,-1.85 -3.25,-1.85
3D body: height 1.4, standoff 0, extent -0.8,-2.1 0.8,-1.45
3D body: height 1.6, standoff 0, extent -1.75,-1.45 1.75,1.45

## SW_TL1014_Tactile [mm] "E-Switch; TL1014; Tactile; SMT; R/A;"
height 1.6
pads (6):
  round 0.75 hole 0.75 unplated: 0(0,-1.375) 0(0,1.375)
  rect 1.55x1 smd: 1(-2.625,-0.85) 2(2.625,-0.85) 3(-2.625,0.85) 4(2.625,0.85)
Top Overlay:
  lines w0.2: -2.35,-1.75 -1.3,-1.75 -1.3,-2.75 1.3,-2.75 1.3,-1.75 2.35,-1.75 ; -2.35,1.75 2.35,1.75
M13_Assembly_Info:
  lines w0.1: -1.3,-1.75 -1.3,-2.75 1.3,-2.75 1.3,-1.75 ; -2.35,-1.75 -2.35,1.75 2.35,1.75 2.35,-1.75 -2.35,-1.75
M15_Country_Yard:
  lines w0.1: -0.5,0 0.5,0 ; 0,-0.5 0,0.5 ; -3.625,-1.975 -3.625,1.925 3.575,1.925 3.575,-1.975 -3.625,-1.975
3D body: height 1.4, standoff 0, extent -1.3,-2.75 1.3,-1.75
3D body: height 1.6, standoff 0, extent -2.35,-1.75 2.35,1.75

## SW_TL1240_ESwitch [mm]
height 8.2
pads (6):
  round 1.8 hole 1: 1(-3.25,2.25) 1(3.25,2.25) 2(-3.25,-2.25) 2(3.25,-2.25)
  rect 1.5x1.5 hole 0.8: 3(0,2.9)
  round 1.5 hole 0.8: 4(0,-2.9)
Top Overlay:
  lines w0.2: -3.8,-3.375 ccw(c-3.375,-3.375) -3.375,-3.8 3.375,-3.8 ccw(c3.375,-3.375) 3.8,-3.375 3.8,3.375 ccw(c3.375,3.375) 3.375,3.8 -3.375,3.8 ccw(c-3.375,3.375) -3.8,3.375 -3.8,-3.375
M13_Assembly_Info:
  lines w0.1: -3.8,-3.375 ccw(c-3.375,-3.375) -3.375,-3.8 3.375,-3.8 ccw(c3.375,-3.375) 3.8,-3.375 3.8,3.375 ccw(c3.375,3.375) 3.375,3.8 -3.375,3.8 ccw(c-3.375,3.375) -3.8,3.375 -3.8,-3.375
M15_Country_Yard:
  lines w0.1: -0.5,0 0.5,0 ; 0,-0.5 0,0.5

## SW_TL6120_E-Switch [mm] "TL6120, Sealed SMT Tacctile Switch; E-Switch"
height 6.9
pads (4):
  rect 1.2x3.1 smd: A(0,-8.9) A(0,0) B(4,-8.9) B(4,0)
Top Overlay:
  circle w0.2: c2,-4.45 r1.5
  lines w0.254: -1.05,-8.05 -1.6,-8.05 -1.6,-0.85 -1.05,-0.85 ; 1,-8.05 3,-8.05 ; 1,-0.85 3,-0.85 ; 5.05,-8.05 5.6,-8.05 5.6,-0.85 5.05,-0.85
M13_Assembly_Info:
  circle w0.1: c2,-4.45 r1.5
  lines w0.1: 4.25,-4.45 cw(c2,-4.45) 4.249,-4.4 ; -1.6,-8.05 -1.6,-0.85 5.6,-0.85 5.6,-8.05 -1.6,-8.05
M15_Country_Yard:
  lines w0.1: 1.5,-4.45 2.5,-4.45 ; 2,-4.95 2,-3.95 ; -1.95,-10.7 5.95,-10.7 5.95,1.8 -1.95,1.8 -1.95,-10.7
3D body: height 0, standoff 0, extent -1.6,-8.05 5.6,-0.85

## SW_TouchKey_For_STMPE821 [mm] "PCB pad for STMPE821 Touch-Key controller"
pads (1):
  rect 10x10 smd: TP(0,0)
Top Overlay:
  lines w0.2: -5.15,-5.15 -5.15,5.15 5.15,5.15 5.15,-5.15 -5.15,-5.15
M13_Assembly_Info:
  lines w0.1: -5,0 5,0 ; 0,-5 0,5 ; -5,-5 5,-5 5,5 -5,5 -5,-5
M15_Country_Yard:
  lines w0.1: -0.5,0 0.5,0 ; 0,-0.5 0,0.5 ; -5.375,-5.375 -5.375,5.375 5.375,5.375 5.375,-5.375 -5.375,-5.375

## Switch-Right Angle [mil]
pads (3):
  round 65 hole 35: 1(0,0) 2(100,0) 3(200,0)
Top Overlay:
  lines w15.75: -67,-43 269,-43 269,93 -67,93 -67,-43

## SWT-SOP4 [mm] "SOP, 8-Leads, Body 12.5x6.2mm (max), Pitch 2.54mm, IPC Medium Density"
height 2.65
pads (8):
  oval 3.25x1.3 smd: 1(-4.325,3.81) 2(-4.325,1.27) 3(-4.325,-1.27) 4(-4.325,-3.81) 5(4.325,-3.81) 6(4.325,-1.27) 7(4.325,1.27) 8(4.325,3.81)
Top Overlay:
  circle w0.25: c-4.325,5.01 r0.125
  circle w0.6: c-1.45,4.975 r0.3
  lines w0.2: -2.3,-5.815 -2.3,5.815 2.3,5.815 2.3,-5.815 -2.3,-5.815
M13_Assembly_Info:
  circle w0.1: c-2.025,4.925 r0.5
  lines w0.1: -3.085,-5.825 -3.085,5.8 3.085,5.8 3.085,-5.825 -3.085,-5.825
M15_Country_Yard:
  lines w0.1: -0.5,0 0.5,0 ; 0,-0.5 0,0.5 ; -6.225,-5.825 -6.225,5.85 6.225,5.85 6.225,-5.825 -6.225,-5.825
3D body: height 2.65, standoff 0.1, extent -3.085,-5.825 3.085,5.775

## SWT-SOT5 [mm]
pads (10):
  oval 3.25x1.3 smd: 1(-4.325,5.08) 2(-4.325,2.54) 3(-4.325,0) 4(-4.325,-2.54) 5(-4.325,-5.08) 6(4.325,-5.08) 7(4.325,-2.54) 8(4.325,0) 9(4.325,2.54) 10(4.325,5.08)
Top Overlay:
  circle w0.25: c-4.325,6.28 r0.125
  circle w0.6: c-1.275,5.75 r0.3
  lines w0.2: -2.3,-7.075 -2.3,7.1 2.3,7.1 2.3,-7.075 -2.3,-7.075
M13_Assembly_Info:
  circle w0.1: c-3.225,6.375 r0.5
  lines w0.1: -4,-7.075 -4,7.075 4,7.075 4,-7.075 -4,-7.075
M15_Country_Yard:
  lines w0.1: -0.5,0 0.5,0 ; 0,-0.505 0,0.495 ; -6.475,-7.085 -6.475,7.085 6.5,7.085 6.5,-7.085 -6.475,-7.085
3D body: height 2.65, standoff 0.1, extent -4,-7.075 4,7.075

## SWT-SOT8 [mm]
pads (16):
  oval 3.25x1.3 smd: 1(-4.325,8.89) 2(-4.325,6.35) 3(-4.325,3.81) 4(-4.325,1.27) 5(-4.325,-1.27) 6(-4.325,-3.81) 7(-4.325,-6.35) 8(-4.325,-8.89) 9(4.325,-8.89) 10(4.325,-6.35) 11(4.325,-3.81) 12(4.325,-1.27) 13(4.325,1.27) 14(4.325,3.81) 15(4.325,6.35) 16(4.325,8.89)
Top Overlay:
  circle w0.6: c-1.275,9.825 r0.3
  circle w0.25: c-4.4,10.075 r0.125
  lines w0.2: -2.3,-10.895 2.3,-10.895 2.3,10.895 -2.3,10.895 -2.3,-10.895
M13_Assembly_Info:
  circle w0.1: c-2.975,10.225 r0.5
  lines w0.1: -4,-10.9 4,-10.9 4,10.9 -4,10.9 -4,-10.9
M15_Country_Yard:
  lines w0.1: -0.5,0.01 0.5,0.01 ; 0,-0.495 0,0.505 ; -6.475,-11.475 6.5,-11.475 6.5,11.55 -6.475,11.55 -6.475,-11.475
3D body: height 2.65, standoff 0.1, extent -4,-10.9 4,10.875

## SWT-SOT10 [mm]
pads (20):
  oval 3.25x1.3 smd: 1(-4.325,11.43) 2(-4.325,8.89) 3(-4.325,6.35) 4(-4.325,3.81) 5(-4.325,1.27) 6(-4.325,-1.27) 7(-4.325,-3.81) 8(-4.325,-6.35) 9(-4.325,-8.89) 10(-4.325,-11.43) 11(4.325,-11.43) 12(4.325,-8.89) 13(4.325,-6.35) 14(4.325,-3.81) 15(4.325,-1.27) 16(4.325,1.27) 17(4.325,3.81) 18(4.325,6.35) 19(4.325,8.89) 20(4.325,11.43)
Top Overlay:
  circle w0.25: c-4.4,12.615 r0.125
  circle w0.6: c-1.275,12.365 r0.3
  lines w0.2: -2.3,-13.435 -2.3,13.435 2.3,13.435 2.3,-13.435 -2.3,-13.435
M13_Assembly_Info:
  circle w0.1: c-2.975,12.765 r0.5
  lines w0.1: -4,-13.435 4,-13.435 ; -4,-13.425 -4,13.44 4,13.44 4,-13.425
M15_Country_Yard:
  lines w0.1: -0.5,0 0.5,0 ; 0,-0.505 0,0.495 ; -6.475,-14.2 -6.475,14.09 6.5,14.09 6.5,-14.2 -6.475,-14.2
3D body: height 2.65, standoff 0.1, extent -4,-13.4 4,13.415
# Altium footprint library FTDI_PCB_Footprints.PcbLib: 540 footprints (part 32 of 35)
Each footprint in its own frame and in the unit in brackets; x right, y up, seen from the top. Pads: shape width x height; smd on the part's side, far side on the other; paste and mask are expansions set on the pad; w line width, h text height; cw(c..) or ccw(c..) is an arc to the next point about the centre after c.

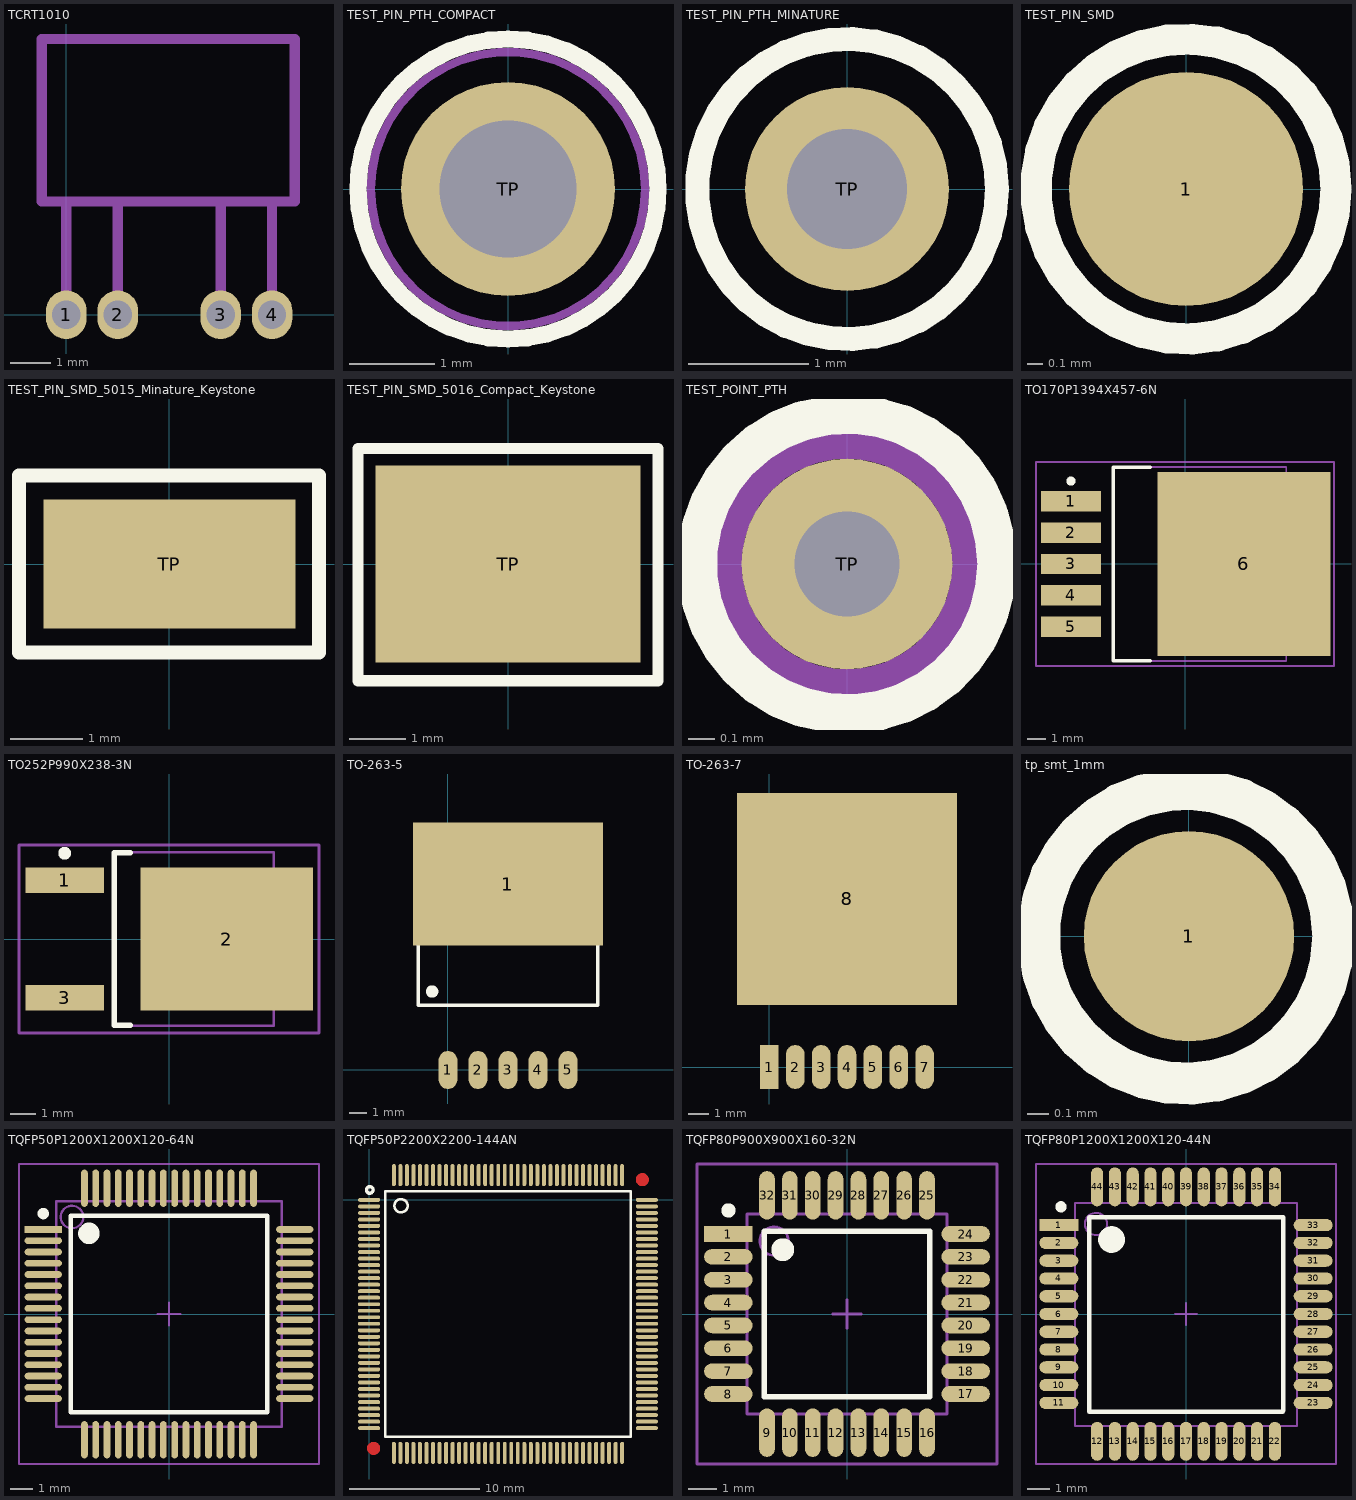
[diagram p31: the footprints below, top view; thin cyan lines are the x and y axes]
## TCRT1010 [mm]
pads (4):
  oval 1x1.2 hole 0.7: 1(0,0) 2(1.27,0) 3(3.81,0) 4(5.08,0)
M13_Assembly_Info:
  lines w0.254: -0.61,2.794 5.639,2.794 ; -0.61,2.807 -0.61,6.782 ; -0.61,6.807 5.639,6.807 ; 0,0 0,2.769 ; 1.27,0 1.27,2.769 ; 3.81,0 3.81,2.769 ; 5.08,0 5.08,2.769 ; 5.639,2.807 5.639,6.782

## TEST_PIN_PTH_COMPACT [mm] "Test pin; 1.8mm loop / 1.6mm mounting hole; Keystone 5005-5009 and 5120-5124"
height 5.6
pads (1):
  round 2.5 hole 1.6: TP(0,0)
Top Overlay:
  circle w0.2: c0,0 r1.75
M13_Assembly_Info:
  circle w0.1: c0,0 r1.6
3D body: height 2, standoff 0, extent -0.5,-0.8 0.5,0.8
3D body: height 3, standoff 0, extent -1.6,-1.6 1.587,1.594
3D body: height 5.6, standoff 2.4, extent -0.55,-1.644 0.45,1.544

## TEST_PIN_PTH_MINATURE [mm] "Test pin; 1.25mm loop / 1.0mm mouting hole; Keystone; 5000-5004 and 5115-5119 series"
height 4.6
pads (1):
  round 1.7 hole 1: TP(0,0)
Top Overlay:
  circle w0.2: c0,0 r1.25
3D body: height 3, standoff 0, extent -1.245,-1.25 1.25,1.24

## TEST_PIN_SMD [mm] "Test pin; SMD"
pads (1):
  round 1.5 smd: 1(0,0)
Top Overlay:
  circle w0.2: c0,0 r0.96
M13_Assembly_Info keep-out:
  circle w0.1: c0,0 r0.96
3D body: height 0, standoff 0, extent -0.96,-0.97 0.96,0.95

## TEST_PIN_SMD_5015_Minature_Keystone [mm] "Test pin; SMD; 5015; Keystone"
height 1.52
pads (1):
  rect 3.5x1.8 smd: TP(0,0)
Top Overlay:
  lines w0.2: -2.09,-1.23 -2.09,1.23 2.08,1.23 2.08,-1.23 -2.09,-1.23

## TEST_PIN_SMD_5016_Compact_Keystone [mm] "Test pin; SMD; 5016; Keystone"
pads (1):
  rect 4.7x3.5 smd: TP(0,0)
Top Overlay:
  lines w0.2: -2.66,-2.07 2.66,-2.07 2.66,2.05 -2.66,2.05 -2.66,-2.07

## TEST_POINT_PTH [mm] "Test point for scope probe"
height 4.6
pads (1):
  round 0.8 hole 0.4: TP(0,0)
Top Overlay:
  circle w0.15: c0,0 r0.57
M13_Assembly_Info:
  circle w0.1: c0,0 r0.45

## TO170P1394X457-6N [mm] "D2-PAK, 6-Pads, Body 9.4x10.5mm (max), IPC Medium Density"
height 4.572
pads (6):
  rect 3.25x1.1 smd: 1(-6.2,3.404) 2(-6.2,1.702) 3(-6.2,0) 4(-6.2,-1.702) 5(-6.2,-3.404)
  rect 9.4x10 smd: 6(3.2,0)
Top Overlay:
  circle w0.25: c-6.2,4.504 r0.125
  lines w0.2: -1.9,-5.25 -3.9,-5.25 -3.9,5.25 -1.9,5.25
M13_Assembly_Info:
  lines w0.1: -3.9,-5.275 -3.9,5.275 5.5,5.275 5.5,-5.275 -3.9,-5.275
M15_Country_Yard:
  lines w0.1: -0.5,0 0.5,0 ; 0,-0.5 0,0.5 ; -8.1,-5.55 -8.1,5.55 8.1,5.55 8.1,-5.55 -8.1,-5.55
3D body: height 4.57, standoff 0.31, extent -3.9,-5.275 5.5,5.275

## TO252P990X238-3N [mm] "D-PAK, 3-Pads, Body 6.2x6.7mm (max), IPC Medium Density"
height 2.38
pads (3):
  rect 3.05x1 smd: 1(-4.05,2.28) 3(-4.05,-2.28)
  rect 6.7x5.55 smd: 2(2.25,0)
Top Overlay:
  circle w0.25: c-4.05,3.33 r0.125
  lines w0.2: -1.5,-3.35 -2.125,-3.35 -2.125,3.35 -1.5,3.35
M13_Assembly_Info:
  lines w0.1: -2.15,-3.375 4.07,-3.375 4.07,3.375 -2.15,3.375 -2.15,-3.375
M15_Country_Yard:
  lines w0.1: -0.5,0 0.5,0 ; 0,-0.5 0,0.5 ; -5.825,-3.65 5.825,-3.65 5.825,3.65 -5.825,3.65 -5.825,-3.65
3D body: height 2.38, standoff 0.13, extent -2.15,-3.375 4.07,3.375

## TO-263-5 [mil]
pads (6):
  oval 42x85 smd: 1(0,0) 2(67,0) 3(134,0) 4(201,0) 5(268,0)
  rect 425x275 smd: 1(134.02,415)
Top Overlay:
  circle w19.68: c-35.43,175.2 r3.94
  lines w7.87: -66,460 334,460 ; -66,145 334,145 334,485 -66,485 -66,145

## TO-263-7 [mil] "TO-263-7pin SMT package"
pads (8):
  rect 35.98x85 smd: 1(0,0)
  oval 36x85 smd: 2(50,0) 3(100,0) 4(150,0) 5(200,0) 6(250,0) 7(300,0)
  rect 425x410 smd: 8(150,325)
Top Overlay:
  circle w10: c-20,160 r10
  lines w7.87: -50,440 350,440 ; -50,130 350,130 350,470 -50,470 -50,130

## tp_smt_1mm [mm]
pads (1):
  round 1 smd: 1(0,0)
Top Overlay:
  circle w0.2: c-0.014,0 r0.7
M13_Assembly_Info keep-out:
  circle w0.1: c-0.014,-0.025 r0.7

## TQFP50P1200X1200X120-64N [mm] "TQFP, 64-Leads, Body 12.0x12.0mm (max), Pitch 0.50mm, IPC Medium Density"
height 1.2
pads (64):
  rect 1.65x0.3 smd: 1(-5.575,3.75)
  oval 1.65x0.3 smd: 2(-5.575,3.25) 3(-5.575,2.75) 4(-5.575,2.25) 5(-5.575,1.75) 6(-5.575,1.25) 7(-5.575,0.75) 8(-5.575,0.25) 9(-5.575,-0.25) 10(-5.575,-0.75) 11(-5.575,-1.25) 12(-5.575,-1.75) 13(-5.575,-2.25) 14(-5.575,-2.75) 15(-5.575,-3.25) 16(-5.575,-3.75) 33(5.575,-3.75) 34(5.575,-3.25) 35(5.575,-2.75) 36(5.575,-2.25) 37(5.575,-1.75) 38(5.575,-1.25) 39(5.575,-0.75) 40(5.575,-0.25) 41(5.575,0.25) 42(5.575,0.75) 43(5.575,1.25) 44(5.575,1.75) 45(5.575,2.25) 46(5.575,2.75) 47(5.575,3.25) 48(5.575,3.75)
  oval 0.3x1.65 smd: 17(-3.75,-5.575) 18(-3.25,-5.575) 19(-2.75,-5.575) 20(-2.25,-5.575) 21(-1.75,-5.575) 22(-1.25,-5.575) 23(-0.75,-5.575) 24(-0.25,-5.575) 25(0.25,-5.575) 26(0.75,-5.575) 27(1.25,-5.575) 28(1.75,-5.575) 29(2.25,-5.575) 30(2.75,-5.575) 31(3.25,-5.575) 32(3.75,-5.575) 49(3.75,5.575) 50(3.25,5.575) 51(2.75,5.575) 52(2.25,5.575) 53(1.75,5.575) 54(1.25,5.575) 55(0.75,5.575) 56(0.25,5.575) 57(-0.25,5.575) 58(-0.75,5.575) 59(-1.25,5.575) 60(-1.75,5.575) 61(-2.25,5.575) 62(-2.75,5.575) 63(-3.25,5.575) 64(-3.75,5.575)
Top Overlay:
  circle w0.6: c-3.55,3.575 r0.175
  circle w0.25: c-5.575,4.45 r0.125
  lines w0.2: -4.35,-4.35 4.35,-4.35 4.35,4.35 -4.35,4.35 -4.35,-4.35
M13_Assembly_Info:
  circle w0.1: c-4.3,4.3 r0.5
  lines w0.1: -5,-5 5,-5 5,5 -5,5 -5,-5
M15_Country_Yard:
  lines w0.1: -0.5,0 0.5,0 ; 0,-0.5 0,0.5 ; -6.65,-6.65 6.65,-6.65 6.65,6.65 -6.65,6.65 -6.65,-6.65
3D body: height 1.2, standoff 0.15, extent -5,-5 5,5

## TQFP50P2200X2200-144AN [mm] "Thin QFP, 144-Leads, Body 20x20mm, Pitch 0.5mm"
pads (144):
  oval 1.7x0.3 smd: 1(0,0) 2(0,-0.5) 3(0,-1) 4(0,-1.5) 5(0,-2) 6(0,-2.5) 7(0,-3) 8(0,-3.5) 9(0,-4) 10(0,-4.5) 11(0,-5) 12(0,-5.5) 13(0,-6) 14(0,-6.5) 15(0,-7) 16(0,-7.5) 17(0,-8) 18(0,-8.5) 19(0,-9) 20(0,-9.5) 21(0,-10) 22(0,-10.5) 23(0,-11) 24(0,-11.5) 25(0,-12) 26(0,-12.5) 27(0,-13) 28(0,-13.5) 29(0,-14) 30(0,-14.5) 31(0,-15) 32(0,-15.5) 33(0,-16) 34(0,-16.5) 35(0,-17) 36(0,-17.5) 73(21.3,-17.5) 74(21.3,-17) 75(21.3,-16.5) 76(21.3,-16) 77(21.3,-15.5) 78(21.3,-15) 79(21.3,-14.5) 80(21.3,-14) 81(21.3,-13.5) 82(21.3,-13) 83(21.3,-12.5) 84(21.3,-12) 85(21.3,-11.5) 86(21.3,-11) 87(21.3,-10.5) 88(21.3,-10) 89(21.3,-9.5) 90(21.3,-9) 91(21.3,-8.5) 92(21.3,-8) 93(21.3,-7.5) 94(21.3,-7) 95(21.3,-6.5) 96(21.3,-6) 97(21.3,-5.5) 98(21.3,-5) 99(21.3,-4.5) 100(21.3,-4) 101(21.3,-3.5) 102(21.3,-3) 103(21.3,-2.5) 104(21.3,-2) 105(21.3,-1.5) 106(21.3,-1) 107(21.3,-0.5) 108(21.3,0)
  oval 0.3x1.7 smd: 37(1.9,-19.4) 38(2.4,-19.4) 39(2.9,-19.4) 40(3.4,-19.4) 41(3.9,-19.4) 42(4.4,-19.4) 43(4.9,-19.4) 44(5.4,-19.4) 45(5.9,-19.4) 46(6.4,-19.4) 47(6.9,-19.4) 48(7.4,-19.4) 49(7.9,-19.4) 50(8.4,-19.4) 51(8.9,-19.4) 52(9.4,-19.4) 53(9.9,-19.4) 54(10.4,-19.4) 55(10.9,-19.4) 56(11.4,-19.4) 57(11.9,-19.4) 58(12.4,-19.4) 59(12.9,-19.4) 60(13.4,-19.4) 61(13.9,-19.4) 62(14.4,-19.4) 63(14.9,-19.4) 64(15.4,-19.4) 65(15.9,-19.4) 66(16.4,-19.4) 67(16.9,-19.4) 68(17.4,-19.4) 69(17.9,-19.4) 70(18.4,-19.4) 71(18.9,-19.4) 72(19.4,-19.4) 109(19.4,1.9) 110(18.9,1.9) 111(18.4,1.9) 112(17.9,1.9) 113(17.4,1.9) 114(16.9,1.9) 115(16.4,1.9) 116(15.9,1.9) 117(15.4,1.9) 118(14.9,1.9) 119(14.4,1.9) 120(13.9,1.9) 121(13.4,1.9) 122(12.9,1.9) 123(12.4,1.9) 124(11.9,1.9) 125(11.4,1.9) 126(10.9,1.9) 127(10.4,1.9) 128(9.9,1.9) 129(9.4,1.9) 130(8.9,1.9) 131(8.4,1.9) 132(7.9,1.9) 133(7.4,1.9) 134(6.9,1.9) 135(6.4,1.9) 136(5.9,1.9) 137(5.4,1.9) 138(4.9,1.9) 139(4.4,1.9) 140(3.9,1.9) 141(3.4,1.9) 142(2.9,1.9) 143(2.4,1.9) 144(1.9,1.9)
Top Layer:
  circle w0.5: c0.35,-19.05 r0.255
  circle w0.5: c20.95,1.55 r0.25
Top Overlay:
  circle w0.2: c2.45,-0.45 r0.51
  circle w0.254: c0.054,0.762 r0.254
  lines w0.2: 1.25,-18.15 20.05,-18.15 20.05,0.65 1.25,0.65 1.25,-18.15

## TQFP80P900X900X160-32N [mm] "TQFP, 32-Leads, Body 9.2x9.2mm (max), Pitch 0.80mm, IPC Medium Density"
height 1.6
pads (32):
  rect 1.7x0.55 smd: 1(-4.15,2.8)
  oval 1.7x0.55 smd: 2(-4.15,2) 3(-4.15,1.2) 4(-4.15,0.4) 5(-4.15,-0.4) 6(-4.15,-1.2) 7(-4.15,-2) 8(-4.15,-2.8) 17(4.15,-2.8) 18(4.15,-2) 19(4.15,-1.2) 20(4.15,-0.4) 21(4.15,0.4) 22(4.15,1.2) 23(4.15,2) 24(4.15,2.8)
  oval 0.55x1.7 smd: 9(-2.8,-4.15) 10(-2,-4.15) 11(-1.2,-4.15) 12(-0.4,-4.15) 13(0.4,-4.15) 14(1.2,-4.15) 15(2,-4.15) 16(2.8,-4.15) 25(2.8,4.15) 26(2,4.15) 27(1.2,4.15) 28(0.4,4.15) 29(-0.4,4.15) 30(-1.2,4.15) 31(-2,4.15) 32(-2.8,4.15)
Top Overlay:
  circle w0.25: c-4.15,3.625 r0.125
  circle w0.6: c-2.25,2.25 r0.1
  lines w0.2: -2.9,-2.9 -2.9,2.9 2.9,2.9 2.9,-2.9 -2.9,-2.9
M13_Assembly_Info:
  circle w0.1: c-2.55,2.55 r0.5
  lines w0.1: -3.5,-3.5 -3.5,3.5 3.5,3.5 3.5,-3.5 -3.5,-3.5
M15_Country_Yard:
  lines w0.1: -0.5,0 0.5,0 ; 0,-0.5 0,0.5 ; -5.25,-5.25 -5.25,5.25 5.25,5.25 5.25,-5.25 -5.25,-5.25
3D body: height 1.6, standoff 0.1, extent -3.5,-3.5 3.5,3.5

## TQFP80P1200X1200X120-44N [mm] "TQFP, 44-Leads, Body 12.3x12.3mm (max), Pitch 0.80mm, IPC Medium Density"
height 1.2
pads (44):
  rect 1.75x0.55 smd: 1(-5.72,4)
  oval 1.75x0.55 smd: 2(-5.72,3.2) 3(-5.72,2.4) 4(-5.72,1.6) 5(-5.72,0.8) 6(-5.72,0) 7(-5.72,-0.8) 8(-5.72,-1.6) 9(-5.72,-2.4) 10(-5.72,-3.2) 11(-5.72,-4) 23(5.72,-4) 24(5.72,-3.2) 25(5.72,-2.4) 26(5.72,-1.6) 27(5.72,-0.8) 28(5.72,0) 29(5.72,0.8) 30(5.72,1.6) 31(5.72,2.4) 32(5.72,3.2) 33(5.72,4)
  oval 0.55x1.75 smd: 12(-4,-5.73) 13(-3.2,-5.73) 14(-2.4,-5.73) 15(-1.6,-5.73) 16(-0.8,-5.73) 17(0,-5.73) 18(0.8,-5.73) 19(1.6,-5.73) 20(2.4,-5.73) 21(3.2,-5.73) 22(4,-5.73) 34(4,5.72) 35(3.2,5.72) 36(2.4,5.72) 37(1.6,5.72) 38(0.8,5.72) 39(0,5.72) 40(-0.8,5.72) 41(-1.6,5.72) 42(-2.4,5.72) 43(-3.2,5.72) 44(-4,5.72)
Top Overlay:
  circle w0.25: c-5.625,4.825 r0.125
  circle w0.6: c-3.35,3.35 r0.3
  lines w0.2: -4.35,-4.39 4.35,-4.39 ; -4.35,-4.35 -4.35,4.35 4.35,4.35 ; 4.38,-4.35 4.38,4.35
M13_Assembly_Info:
  circle w0.1: c-4.05,4.05 r0.5
  lines w0.1: -5,-5.04 5,-5.04 ; -5,-5 -5,5 5,5 5,-5
M15_Country_Yard:
  lines w0.1: -0.5,0 0.5,0 ; 0,-0.5 0,0.5 ; -6.75,-6.75 -6.75,6.75 6.75,6.75 6.75,-6.75 -6.75,-6.75
3D body: height 1.2, standoff 0.15, extent -5,-5 5,5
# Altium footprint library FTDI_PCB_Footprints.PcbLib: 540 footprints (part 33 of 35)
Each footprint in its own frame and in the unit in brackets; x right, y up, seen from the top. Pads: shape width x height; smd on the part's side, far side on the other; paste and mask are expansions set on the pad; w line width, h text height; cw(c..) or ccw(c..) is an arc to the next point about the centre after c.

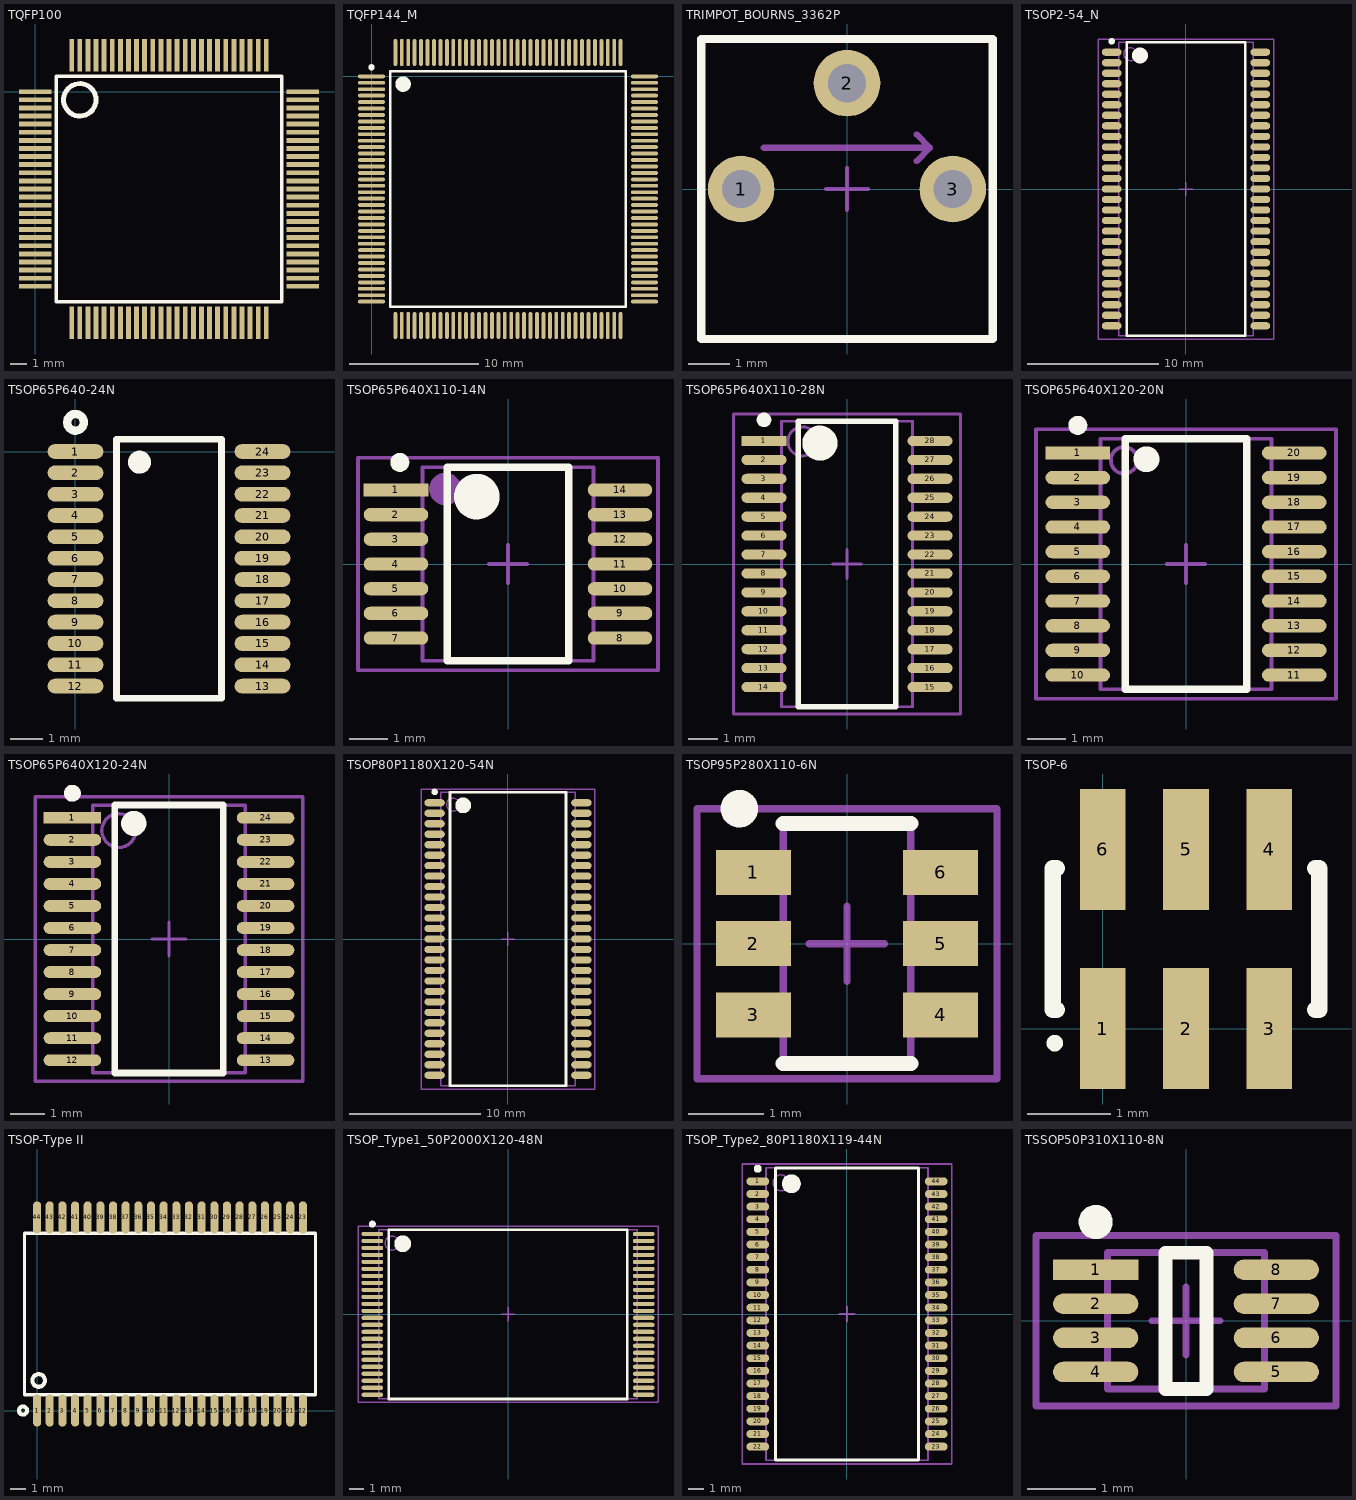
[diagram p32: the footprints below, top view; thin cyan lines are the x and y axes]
## TQFP100 [mm]
pads (100):
  rect 2x0.3 smd: 1(0,0) 2(0,-0.5) 3(0,-1) 4(0,-1.5) 5(0,-2) 6(0,-2.5) 7(0,-3) 8(0,-3.5) 9(0,-4) 10(0,-4.5) 11(0,-5) 12(0,-5.5) 13(0,-6) 14(0,-6.5) 15(0,-7) 16(0,-7.5) 17(0,-8) 18(0,-8.5) 19(0,-9) 20(0,-9.5) 21(0,-10) 22(0,-10.5) 23(0,-11) 24(0,-11.5) 25(0,-12) 51(16.5,-12) 52(16.5,-11.5) 53(16.5,-11) 54(16.5,-10.5) 55(16.5,-10) 56(16.5,-9.5) 57(16.5,-9) 58(16.5,-8.5) 59(16.5,-8) 60(16.5,-7.5) 61(16.5,-7) 62(16.5,-6.5) 63(16.5,-6) 64(16.5,-5.5) 65(16.5,-5) 66(16.5,-4.5) 67(16.5,-4) 68(16.5,-3.5) 69(16.5,-3) 70(16.5,-2.5) 71(16.5,-2) 72(16.5,-1.5) 73(16.5,-1) 74(16.5,-0.5) 75(16.5,0)
  rect 0.3x2 smd: 26(2.25,-14.25) 27(2.75,-14.25) 28(3.25,-14.25) 29(3.75,-14.25) 30(4.25,-14.25) 31(4.75,-14.25) 32(5.25,-14.25) 33(5.75,-14.25) 34(6.25,-14.25) 35(6.75,-14.25) 36(7.25,-14.25) 37(7.75,-14.25) 38(8.25,-14.25) 39(8.75,-14.25) 40(9.25,-14.25) 41(9.75,-14.25) 42(10.25,-14.25) 43(10.75,-14.25) 44(11.25,-14.25) 45(11.75,-14.25) 46(12.25,-14.25) 47(12.75,-14.25) 48(13.25,-14.25) 49(13.75,-14.25) 50(14.25,-14.25) 76(14.25,2.25) 77(13.75,2.25) 78(13.25,2.25) 79(12.75,2.25) 80(12.25,2.25) 81(11.75,2.25) 82(11.25,2.25) 83(10.75,2.25) 84(10.25,2.25) 85(9.75,2.25) 86(9.25,2.25) 87(8.75,2.25) 88(8.25,2.25) 89(7.75,2.25) 90(7.25,2.25) 91(6.75,2.25) 92(6.25,2.25) 93(5.75,2.25) 94(5.25,2.25) 95(4.75,2.25) 96(4.25,2.25) 97(3.75,2.25) 98(3.25,2.25) 99(2.75,2.25) 100(2.25,2.25)
Top Overlay:
  circle w0.305: c2.75,-0.5 r1
  lines w0.2: 1.29,-12.949 1.29,0.949 15.21,0.949 15.21,-12.949 1.29,-12.949

## TQFP144_M [mm] "Thin QFP, 144-Leads, Body 20x20mm, Pitch 0.5mm, IPC Low Density"
height 1.6
pads (144):
  oval 2.1x0.3 smd: 1(0,0) 2(0,-0.5) 3(0,-1) 4(0,-1.5) 5(0,-2) 6(0,-2.5) 7(0,-3) 8(0,-3.5) 9(0,-4) 10(0,-4.5) 11(0,-5) 12(0,-5.5) 13(0,-6) 14(0,-6.5) 15(0,-7) 16(0,-7.5) 17(0,-8) 18(0,-8.5) 19(0,-9) 20(0,-9.5) 21(0,-10) 22(0,-10.5) 23(0,-11) 24(0,-11.5) 25(0,-12) 26(0,-12.5) 27(0,-13) 28(0,-13.5) 29(0,-14) 30(0,-14.5) 31(0,-15) 32(0,-15.5) 33(0,-16) 34(0,-16.5) 35(0,-17) 36(0,-17.5) 73(21.2,-17.5) 74(21.2,-17) 75(21.2,-16.5) 76(21.2,-16) 77(21.2,-15.5) 78(21.2,-15) 79(21.2,-14.5) 80(21.2,-14) 81(21.2,-13.5) 82(21.2,-13) 83(21.2,-12.5) 84(21.2,-12) 85(21.2,-11.5) 86(21.2,-11) 87(21.2,-10.5) 88(21.2,-10) 89(21.2,-9.5) 90(21.2,-9) 91(21.2,-8.5) 92(21.2,-8) 93(21.2,-7.5) 94(21.2,-7) 95(21.2,-6.5) 96(21.2,-6) 97(21.2,-5.5) 98(21.2,-5) 99(21.2,-4.5) 100(21.2,-4) 101(21.2,-3.5) 102(21.2,-3) 103(21.2,-2.5) 104(21.2,-2) 105(21.2,-1.5) 106(21.2,-1) 107(21.2,-0.5) 108(21.2,0)
  oval 0.3x2.1 smd: 37(1.85,-19.35) 38(2.35,-19.35) 39(2.85,-19.35) 40(3.35,-19.35) 41(3.85,-19.35) 42(4.35,-19.35) 43(4.85,-19.35) 44(5.35,-19.35) 45(5.85,-19.35) 46(6.35,-19.35) 47(6.85,-19.35) 48(7.35,-19.35) 49(7.85,-19.35) 50(8.35,-19.35) 51(8.85,-19.35) 52(9.35,-19.35) 53(9.85,-19.35) 54(10.35,-19.35) 55(10.85,-19.35) 56(11.35,-19.35) 57(11.85,-19.35) 58(12.35,-19.35) 59(12.85,-19.35) 60(13.35,-19.35) 61(13.85,-19.35) 62(14.35,-19.35) 63(14.85,-19.35) 64(15.35,-19.35) 65(15.85,-19.35) 66(16.35,-19.35) 67(16.85,-19.35) 68(17.35,-19.35) 69(17.85,-19.35) 70(18.35,-19.35) 71(18.85,-19.35) 72(19.35,-19.35) 109(19.35,1.85) 110(18.85,1.85) 111(18.35,1.85) 112(17.85,1.85) 113(17.35,1.85) 114(16.85,1.85) 115(16.35,1.85) 116(15.85,1.85) 117(15.35,1.85) 118(14.85,1.85) 119(14.35,1.85) 120(13.85,1.85) 121(13.35,1.85) 122(12.85,1.85) 123(12.35,1.85) 124(11.85,1.85) 125(11.35,1.85) 126(10.85,1.85) 127(10.35,1.85) 128(9.85,1.85) 129(9.35,1.85) 130(8.85,1.85) 131(8.35,1.85) 132(7.85,1.85) 133(7.35,1.85) 134(6.85,1.85) 135(6.35,1.85) 136(5.85,1.85) 137(5.35,1.85) 138(4.85,1.85) 139(4.35,1.85) 140(3.85,1.85) 141(3.35,1.85) 142(2.85,1.85) 143(2.35,1.85) 144(1.85,1.85)
Top Overlay:
  circle w0.6: c2.45,-0.6 r0.3
  circle w0.25: c0,0.7 r0.125
  lines w0.2: 1.45,-17.9 19.75,-17.9 19.75,0.4 1.45,0.4 1.45,-17.9

## TRIMPOT_BOURNS_3362P [mm] "TRIMPOT_BOURNS_3362P_2.54MM"
height 5.8
pads (3):
  round 1.6 hole 0.92: 1(-2.54,0) 2(0,2.54) 3(2.54,0)
Top Overlay:
  lines w0.2: -3.5,-3.6 -3.5,3.6 3.5,3.6 3.5,-3.6 -3.5,-3.6
M13_Assembly_Info:
  lines w0.15: -2,0.99 1.99,0.99 ; 1.67,0.67 1.99,0.99 ; 1.67,1.31 1.99,0.99
  text "CW" at -0.965,-0.178 h0.8
M15_Country_Yard:
  lines w0.1: -0.5,0 0.5,0 ; 0,-0.5 0,0.5

## TSOP2-54_N [mm] "SOP, 54-Leads, Body 22.2x10.16mm, Pitch 0.8mm, IPC Medium Density"
height 1.2
pads (54):
  oval 1.5x0.55 smd: 1(-5.65,10.4) 2(-5.65,9.6) 3(-5.65,8.8) 4(-5.65,8) 5(-5.65,7.2) 6(-5.65,6.4) 7(-5.65,5.6) 8(-5.65,4.8) 9(-5.65,4) 10(-5.65,3.2) 11(-5.65,2.4) 12(-5.65,1.6) 13(-5.65,0.8) 14(-5.65,0) 15(-5.65,-0.8) 16(-5.65,-1.6) 17(-5.65,-2.4) 18(-5.65,-3.2) 19(-5.65,-4) 20(-5.65,-4.8) 21(-5.65,-5.6) 22(-5.65,-6.4) 23(-5.65,-7.2) 24(-5.65,-8) 25(-5.65,-8.8) 26(-5.65,-9.6) 27(-5.65,-10.4) 28(5.65,-10.4) 29(5.65,-9.6) 30(5.65,-8.8) 31(5.65,-8) 32(5.65,-7.2) 33(5.65,-6.4) 34(5.65,-5.6) 35(5.65,-4.8) 36(5.65,-4) 37(5.65,-3.2) 38(5.65,-2.4) 39(5.65,-1.6) 40(5.65,-0.8) 41(5.65,0) 42(5.65,0.8) 43(5.65,1.6) 44(5.65,2.4) 45(5.65,3.2) 46(5.65,4) 47(5.65,4.8) 48(5.65,5.6) 49(5.65,6.4) 50(5.65,7.2) 51(5.65,8) 52(5.65,8.8) 53(5.65,9.6) 54(5.65,10.4)
Top Overlay:
  circle w0.6: c-3.5,10.15 r0.3
  circle w0.25: c-5.65,11.225 r0.125
  lines w0.2: -4.5,-11.15 4.5,-11.15 4.5,11.15 -4.5,11.15 -4.5,-11.15
M13_Assembly_Info:
  circle w0.1: c-4.22,10.25 r0.5
  lines w0.1: -5.12,-11.15 5.12,-11.15 5.12,11.15 -5.12,11.15 -5.12,-11.15
M15_Country_Yard:
  lines w0.1: -0.5,0 0.5,0 ; 0,-0.5 0,0.5 ; -6.65,-11.4 6.65,-11.4 6.65,11.4 -6.65,11.4 -6.65,-11.4
3D body: height 1.2, standoff 0, extent -5.12,-11.15 5.12,11.15

## TSOP65P640-24N [mm] "TSOP 24-lead 0.65mm pitch"
height 1.1
pads (24):
  oval 1.7x0.45 smd: 1(0,0) 2(0,-0.65) 3(0,-1.3) 4(0,-1.95) 5(0,-2.6) 6(0,-3.25) 7(0,-3.9) 8(0,-4.55) 9(0,-5.2) 10(0,-5.85) 11(0,-6.5) 12(0,-7.15) 13(5.7,-7.15) 14(5.7,-6.5) 15(5.7,-5.85) 16(5.7,-5.2) 17(5.7,-4.55) 18(5.7,-3.9) 19(5.7,-3.25) 20(5.7,-2.6) 21(5.7,-1.95) 22(5.7,-1.3) 23(5.7,-0.65) 24(5.7,0)
Top Overlay:
  circle w0.254: c0,0.889 r0.254
  circle w0.5: c1.95,-0.325 r0.1
  lines w0.2: 1.25,-7.525 4.45,-7.525 4.45,0.375 1.25,0.375 1.25,-7.525

## TSOP65P640X110-14N [mm] "TSOP, 14-Leads, Body 5.1x4.5mm (max), Pitch 0.65mm, IPC Medium Density"
height 1.1
pads (14):
  rect 1.7x0.35 smd: 1(-2.95,1.95)
  oval 1.7x0.35 smd: 2(-2.95,1.3) 3(-2.95,0.65) 4(-2.95,0) 5(-2.95,-0.65) 6(-2.95,-1.3) 7(-2.95,-1.95) 8(2.95,-1.95) 9(2.95,-1.3) 10(2.95,-0.65) 11(2.95,0) 12(2.95,0.65) 13(2.95,1.3) 14(2.95,1.95)
Top Overlay:
  circle w0.6: c-0.825,1.775 r0.3
  circle w0.25: c-2.85,2.675 r0.125
  lines w0.2: -1.6,-2.55 1.6,-2.55 1.6,2.55 -1.6,2.55 -1.6,-2.55
M13_Assembly_Info:
  circle w0.4: c-1.65,1.975 r0.225
  lines w0.1: -2.25,-2.55 2.25,-2.55 2.25,2.55 -2.25,2.55 -2.25,-2.55
M15_Country_Yard:
  lines w0.1: -0.5,0 0.5,0 ; 0,-0.5 0,0.5 ; -3.95,-2.8 3.95,-2.8 3.95,2.8 -3.95,2.8 -3.95,-2.8
3D body: height 1.1, standoff 0.15, extent -2.25,-2.55 2.25,2.55

## TSOP65P640X110-28N [mm] "TSOP, 28-Leads, Body 9.8x4.5mm (max), Pitch 0.65mm, IPC Medium Density"
height 1.1
pads (28):
  rect 1.55x0.35 smd: 1(-2.85,4.225)
  oval 1.55x0.35 smd: 2(-2.85,3.575) 3(-2.85,2.925) 4(-2.85,2.275) 5(-2.85,1.625) 6(-2.85,0.975) 7(-2.85,0.325) 8(-2.85,-0.325) 9(-2.85,-0.975) 10(-2.85,-1.625) 11(-2.85,-2.275) 12(-2.85,-2.925) 13(-2.85,-3.575) 14(-2.85,-4.225) 15(2.85,-4.225) 16(2.85,-3.575) 17(2.85,-2.925) 18(2.85,-2.275) 19(2.85,-1.625) 20(2.85,-0.975) 21(2.85,-0.325) 22(2.85,0.325) 23(2.85,0.975) 24(2.85,1.625) 25(2.85,2.275) 26(2.85,2.925) 27(2.85,3.575) 28(2.85,4.225)
Top Overlay:
  circle w0.25: c-2.85,4.95 r0.125
  circle w0.6: c-0.93,4.15 r0.3
  lines w0.2: -1.675,-4.9 -1.675,4.9 1.675,4.9 1.675,-4.9 -1.675,-4.9
M13_Assembly_Info:
  circle w0.1: c-1.53,4.21 r0.5
  lines w0.1: -2.25,-4.9 -2.25,4.9 2.25,4.9 2.25,-4.9 -2.25,-4.9
M15_Country_Yard:
  lines w0.1: -0.5,0 0.5,0 ; 0,-0.5 0,0.5 ; -3.9,-5.15 -3.9,5.15 3.9,5.15 3.9,-5.15 -3.9,-5.15
3D body: height 1.1, standoff 0.15, extent -2.25,-4.9 2.25,4.9

## TSOP65P640X120-20N [mm] "TSOP, 20-Leads, Body 6.6x4.5mm (max), Pitch 0.65mm, IPC Medium Density"
height 1.2
pads (20):
  rect 1.7x0.35 smd: 1(-2.85,2.925)
  oval 1.7x0.35 smd: 2(-2.85,2.275) 3(-2.85,1.625) 4(-2.85,0.975) 5(-2.85,0.325) 6(-2.85,-0.325) 7(-2.85,-0.975) 8(-2.85,-1.625) 9(-2.85,-2.275) 10(-2.85,-2.925) 11(2.85,-2.925) 12(2.85,-2.275) 13(2.85,-1.625) 14(2.85,-0.975) 15(2.85,-0.325) 16(2.85,0.325) 17(2.85,0.975) 18(2.85,1.625) 19(2.85,2.275) 20(2.85,2.925)
Top Overlay:
  circle w0.6: c-1.04,2.76 r0.04
  circle w0.25: c-2.85,3.65 r0.125
  lines w0.2: -1.6,-3.3 1.6,-3.3 1.6,3.3 -1.6,3.3 -1.6,-3.3
M13_Assembly_Info:
  circle w0.1: c-1.63,2.73 r0.35
  lines w0.1: -2.25,-3.3 2.25,-3.3 2.25,3.3 -2.25,3.3 -2.25,-3.3
M15_Country_Yard:
  lines w0.1: -0.5,0 0.5,0 ; 0,-0.5 0,0.5 ; -3.95,-3.55 3.95,-3.55 3.95,3.55 -3.95,3.55 -3.95,-3.55
3D body: height 1.2, standoff 0.1, extent -2.25,-3.3 2.25,3.3

## TSOP65P640X120-24N [mm] "TSOP, 24-Leads, Body 7.9x4.5mm (max), Pitch 0.65mm, IPC Medium Density"
height 1.2
pads (24):
  rect 1.7x0.35 smd: 1(-2.85,3.575)
  oval 1.7x0.35 smd: 2(-2.85,2.925) 3(-2.85,2.275) 4(-2.85,1.625) 5(-2.85,0.975) 6(-2.85,0.325) 7(-2.85,-0.325) 8(-2.85,-0.975) 9(-2.85,-1.625) 10(-2.85,-2.275) 11(-2.85,-2.925) 12(-2.85,-3.575) 13(2.85,-3.575) 14(2.85,-2.925) 15(2.85,-2.275) 16(2.85,-1.625) 17(2.85,-0.975) 18(2.85,-0.325) 19(2.85,0.325) 20(2.85,0.975) 21(2.85,1.625) 22(2.85,2.275) 23(2.85,2.925) 24(2.85,3.575)
Top Overlay:
  circle w0.6: c-1.04,3.41 r0.07
  circle w0.25: c-2.85,4.3 r0.125
  lines w0.2: -1.6,-3.95 1.6,-3.95 1.6,3.95 -1.6,3.95 -1.6,-3.95
M13_Assembly_Info:
  circle w0.1: c-1.48,3.2 r0.5
  lines w0.1: -2.25,-3.95 2.25,-3.95 2.25,3.95 -2.25,3.95 -2.25,-3.95
M15_Country_Yard:
  lines w0.1: -0.5,0 0.5,0 ; 0,-0.5 0,0.5 ; -3.95,-4.2 3.95,-4.2 3.95,4.2 -3.95,4.2 -3.95,-4.2
3D body: height 1.2, standoff 0.1, extent -2.25,-3.95 2.25,3.95

## TSOP80P1180X120-54N [mm] "TSOP, 54-Leads, Body 22.4x10.3mm (max), Pitch 0.80mm, IPC Medium Density"
height 1.2
pads (54):
  oval 1.55x0.55 smd: 1(-5.6,10.4) 2(-5.6,9.6) 3(-5.6,8.8) 4(-5.6,8) 5(-5.6,7.2) 6(-5.6,6.4) 7(-5.6,5.6) 8(-5.6,4.8) 9(-5.6,4) 10(-5.6,3.2) 11(-5.6,2.4) 12(-5.6,1.6) 13(-5.6,0.8) 14(-5.6,0) 15(-5.6,-0.8) 16(-5.6,-1.6) 17(-5.6,-2.4) 18(-5.6,-3.2) 19(-5.6,-4) 20(-5.6,-4.8) 21(-5.6,-5.6) 22(-5.6,-6.4) 23(-5.6,-7.2) 24(-5.6,-8) 25(-5.6,-8.8) 26(-5.6,-9.6) 27(-5.6,-10.4) 28(5.6,-10.4) 29(5.6,-9.6) 30(5.6,-8.8) 31(5.6,-8) 32(5.6,-7.2) 33(5.6,-6.4) 34(5.6,-5.6) 35(5.6,-4.8) 36(5.6,-4) 37(5.6,-3.2) 38(5.6,-2.4) 39(5.6,-1.6) 40(5.6,-0.8) 41(5.6,0) 42(5.6,0.8) 43(5.6,1.6) 44(5.6,2.4) 45(5.6,3.2) 46(5.6,4) 47(5.6,4.8) 48(5.6,5.6) 49(5.6,6.4) 50(5.6,7.2) 51(5.6,8) 52(5.6,8.8) 53(5.6,9.6) 54(5.6,10.4)
Top Overlay:
  circle w0.25: c-5.6,11.225 r0.125
  circle w0.6: c-3.425,10.2 r0.3
  lines w0.2: -4.425,-11.2 -4.425,11.2 4.425,11.2 4.425,-11.2 -4.425,-11.2
M13_Assembly_Info:
  circle w0.1: c-4.195,10.26 r0.5
  lines w0.1: -5.145,-11.21 -5.145,11.21 5.145,11.21 5.145,-11.21 -5.145,-11.21
M15_Country_Yard:
  lines w0.1: -0.5,0 0.5,0 ; 0,-0.5 0,0.5 ; -6.625,-11.45 -6.625,11.45 6.625,11.45 6.625,-11.45 -6.625,-11.45
3D body: height 1.2, standoff 0.15, extent -5.145,-11.21 5.145,11.21

## TSOP95P280X110-6N [mm] "TSOP, 6-Leads, Body 3.00x1.50mm, Pitch 0.95mm, IPC Medium Density"
height 1.1
pads (6):
  rect 1x0.6 smd: 1(-1.25,0.95) 2(-1.25,0) 3(-1.25,-0.95) 4(1.25,-0.95) 5(1.25,0) 6(1.25,0.95)
Top Overlay:
  circle w0.25: c-1.435,1.8 r0.125
  lines w0.2: -0.85,-1.6 0.85,-1.6 ; -0.85,1.6 0.85,1.6
M13_Assembly_Info:
  lines w0.1: -0.85,-1.55 -0.85,1.55 0.85,1.55 0.85,-1.55 -0.85,-1.55
M15_Country_Yard:
  lines w0.1: -0.5,0 0.5,0 ; 0,-0.5 0,0.5 ; -2,-1.8 -2,1.8 2,1.8 2,-1.8 -2,-1.8
3D body: height 1.1, standoff 0.1, extent -0.85,-1.55 0.85,1.55

## TSOP-6 [mm] "SOT-457/SC-74; 6 Leads; Body 3.1 x 2.9 mm, inc. leads (LxW max)"
height 1.1
pads (6):
  rect 0.55x1.45 smd: 1(0,0) 2(1,0) 3(2,0) 4(2,2.15) 5(1,2.15) 6(0,2.15)
Top Overlay:
  circle w0.1: c-0.575,-0.175 r0.05
  lines w0.2: -0.55,0.225 -0.6,0.225 -0.6,1.925 -0.55,1.925 ; 2.55,0.225 2.6,0.225 2.6,1.925 2.55,1.925

## TSOP-Type II [mil] "Plastic TSOP Type II"
pads (44):
  oval 20x80 smd: 1(0,0) 2(31.5,0) 3(62.99,0) 4(94.49,0) 5(125.98,0) 6(157.48,0) 7(188.98,0) 8(220.47,0) 9(251.97,0) 10(283.46,0) 11(314.96,0) 12(346.46,0) 13(377.95,0) 14(409.45,0) 15(440.94,0) 16(472.44,0) 17(503.94,0) 18(535.43,0) 19(566.93,0) 20(598.43,0) 21(629.92,0) 22(661.42,0) 23(661.42,480.31) 24(629.92,480.31) 25(598.42,480.31) 26(566.93,480.31) 27(535.43,480.31) 28(503.94,480.31) 29(472.44,480.31) 30(440.94,480.31) 31(409.45,480.31) 32(377.95,480.31) 33(346.46,480.31) 34(314.96,480.31) 35(283.46,480.31) 36(251.97,480.31) 37(220.47,480.31) 38(188.98,480.31) 39(157.48,480.31) 40(125.98,480.31) 41(94.49,480.31) 42(62.99,480.31) 43(31.5,480.31) 44(0,480.31)
Top Overlay:
  circle w10: c-34.92,0 r10
  circle w10: c3.94,74.8 r15.75
  lines w7.87: -31.5,39.37 692.91,39.37 692.91,440.94 -31.5,440.94 -31.5,39.37

## TSOP_Type1_50P2000X120-48N [mm] "TSOP Type 1, 48-Leads, Body 12.1x18.5mm (max), Pitch 0.50mm, IPC Medium Density"
height 1.2
pads (48):
  oval 1.55x0.3 smd: 1(-9.7,5.75) 2(-9.7,5.25) 3(-9.7,4.75) 4(-9.7,4.25) 5(-9.7,3.75) 6(-9.7,3.25) 7(-9.7,2.75) 8(-9.7,2.25) 9(-9.7,1.75) 10(-9.7,1.25) 11(-9.7,0.75) 12(-9.7,0.25) 13(-9.7,-0.25) 14(-9.7,-0.75) 15(-9.7,-1.25) 16(-9.7,-1.75) 17(-9.7,-2.25) 18(-9.7,-2.75) 19(-9.7,-3.25) 20(-9.7,-3.75) 21(-9.7,-4.25) 22(-9.7,-4.75) 23(-9.7,-5.25) 24(-9.7,-5.75) 25(9.7,-5.75) 26(9.7,-5.25) 27(9.7,-4.75) 28(9.7,-4.25) 29(9.7,-3.75) 30(9.7,-3.25) 31(9.7,-2.75) 32(9.7,-2.25) 33(9.7,-1.75) 34(9.7,-1.25) 35(9.7,-0.75) 36(9.7,-0.25) 37(9.7,0.25) 38(9.7,0.75) 39(9.7,1.25) 40(9.7,1.75) 41(9.7,2.25) 42(9.7,2.75) 43(9.7,3.25) 44(9.7,3.75) 45(9.7,4.25) 46(9.7,4.75) 47(9.7,5.25) 48(9.7,5.75)
Top Overlay:
  circle w0.25: c-9.7,6.45 r0.125
  circle w0.6: c-7.525,5.05 r0.3
  lines w0.2: -8.525,-6.05 -8.525,6.05 8.525,6.05 8.525,-6.05 -8.525,-6.05
M13_Assembly_Info:
  circle w0.1: c-8.29,5.09 r0.5
  lines w0.1: -9.24,-6.04 -9.24,6.04 9.24,6.04 9.24,-6.04 -9.24,-6.04
M15_Country_Yard:
  lines w0.1: -0.5,0 0.5,0 ; 0,-0.5 0,0.5 ; -10.725,-6.3 -10.725,6.3 10.725,6.3 10.725,-6.3 -10.725,-6.3
3D body: height 1.2, standoff 0.2, extent -9.24,-6.04 9.24,6.04

## TSOP_Type2_80P1180X119-44N [mm] "TSOP Type 2, 44-Leads, Body 18.5x10.3mm (max), Pitch 0.80mm, IPC Medium Density"
height 1.194
pads (44):
  oval 1.45x0.5 smd: 1(-5.65,8.4) 2(-5.65,7.6) 3(-5.65,6.8) 4(-5.65,6) 5(-5.65,5.2) 6(-5.65,4.4) 7(-5.65,3.6) 8(-5.65,2.8) 9(-5.65,2) 10(-5.65,1.2) 11(-5.65,0.4) 12(-5.65,-0.4) 13(-5.65,-1.2) 14(-5.65,-2) 15(-5.65,-2.8) 16(-5.65,-3.6) 17(-5.65,-4.4) 18(-5.65,-5.2) 19(-5.65,-6) 20(-5.65,-6.8) 21(-5.65,-7.6) 22(-5.65,-8.4) 23(5.65,-8.4) 24(5.65,-7.6) 25(5.65,-6.8) 26(5.65,-6) 27(5.65,-5.2) 28(5.65,-4.4) 29(5.65,-3.6) 30(5.65,-2.8) 31(5.65,-2) 32(5.65,-1.2) 33(5.65,-0.4) 34(5.65,0.4) 35(5.65,1.2) 36(5.65,2) 37(5.65,2.8) 38(5.65,3.6) 39(5.65,4.4) 40(5.65,5.2) 41(5.65,6) 42(5.65,6.8) 43(5.65,7.6) 44(5.65,8.4)
Top Overlay:
  circle w0.25: c-5.65,9.2 r0.125
  circle w0.6: c-3.525,8.25 r0.3
  lines w0.2: -4.525,-9.25 -4.525,9.25 4.525,9.25 4.525,-9.25 -4.525,-9.25
M13_Assembly_Info:
  circle w0.1: c-4.18,8.31 r0.5
  lines w0.1: -5.13,-9.26 -5.13,9.26 5.13,9.26 5.13,-9.26 -5.13,-9.26
M15_Country_Yard:
  lines w0.1: -0.5,0 0.5,0 ; 0,-0.5 0,0.5 ; -6.625,-9.5 -6.625,9.5 6.625,9.5 6.625,-9.5 -6.625,-9.5
3D body: height 1.19, standoff 0.15, extent -5.13,-9.26 5.13,9.26

## TSSOP50P310X110-8N [mm] "TSSOP, 8-Leads, Body 2.0x2.3mm (max), Pitch 0.50mm, IPC Medium Density"
height 1.1
pads (8):
  rect 1.25x0.3 smd: 1(-1.325,0.75)
  oval 1.25x0.3 smd: 2(-1.325,0.25) 3(-1.325,-0.25) 4(-1.325,-0.75) 5(1.325,-0.75) 6(1.325,-0.25) 7(1.325,0.25) 8(1.325,0.75)
Top Overlay:
  circle w0.25: c-1.325,1.45 r0.125
  lines w0.2: -0.3,-1 0.3,-1 0.3,1 -0.3,1 -0.3,-1
M13_Assembly_Info:
  lines w0.1: -1.15,-1 1.15,-1 1.15,1 -1.15,1 -1.15,-1
M15_Country_Yard:
  lines w0.1: -0.5,0 0.5,0 ; 0,-0.5 0,0.5 ; -2.2,-1.25 2.2,-1.25 2.2,1.25 -2.2,1.25 -2.2,-1.25
3D body: height 1.1, standoff 0.1, extent -1.15,-1 1.15,1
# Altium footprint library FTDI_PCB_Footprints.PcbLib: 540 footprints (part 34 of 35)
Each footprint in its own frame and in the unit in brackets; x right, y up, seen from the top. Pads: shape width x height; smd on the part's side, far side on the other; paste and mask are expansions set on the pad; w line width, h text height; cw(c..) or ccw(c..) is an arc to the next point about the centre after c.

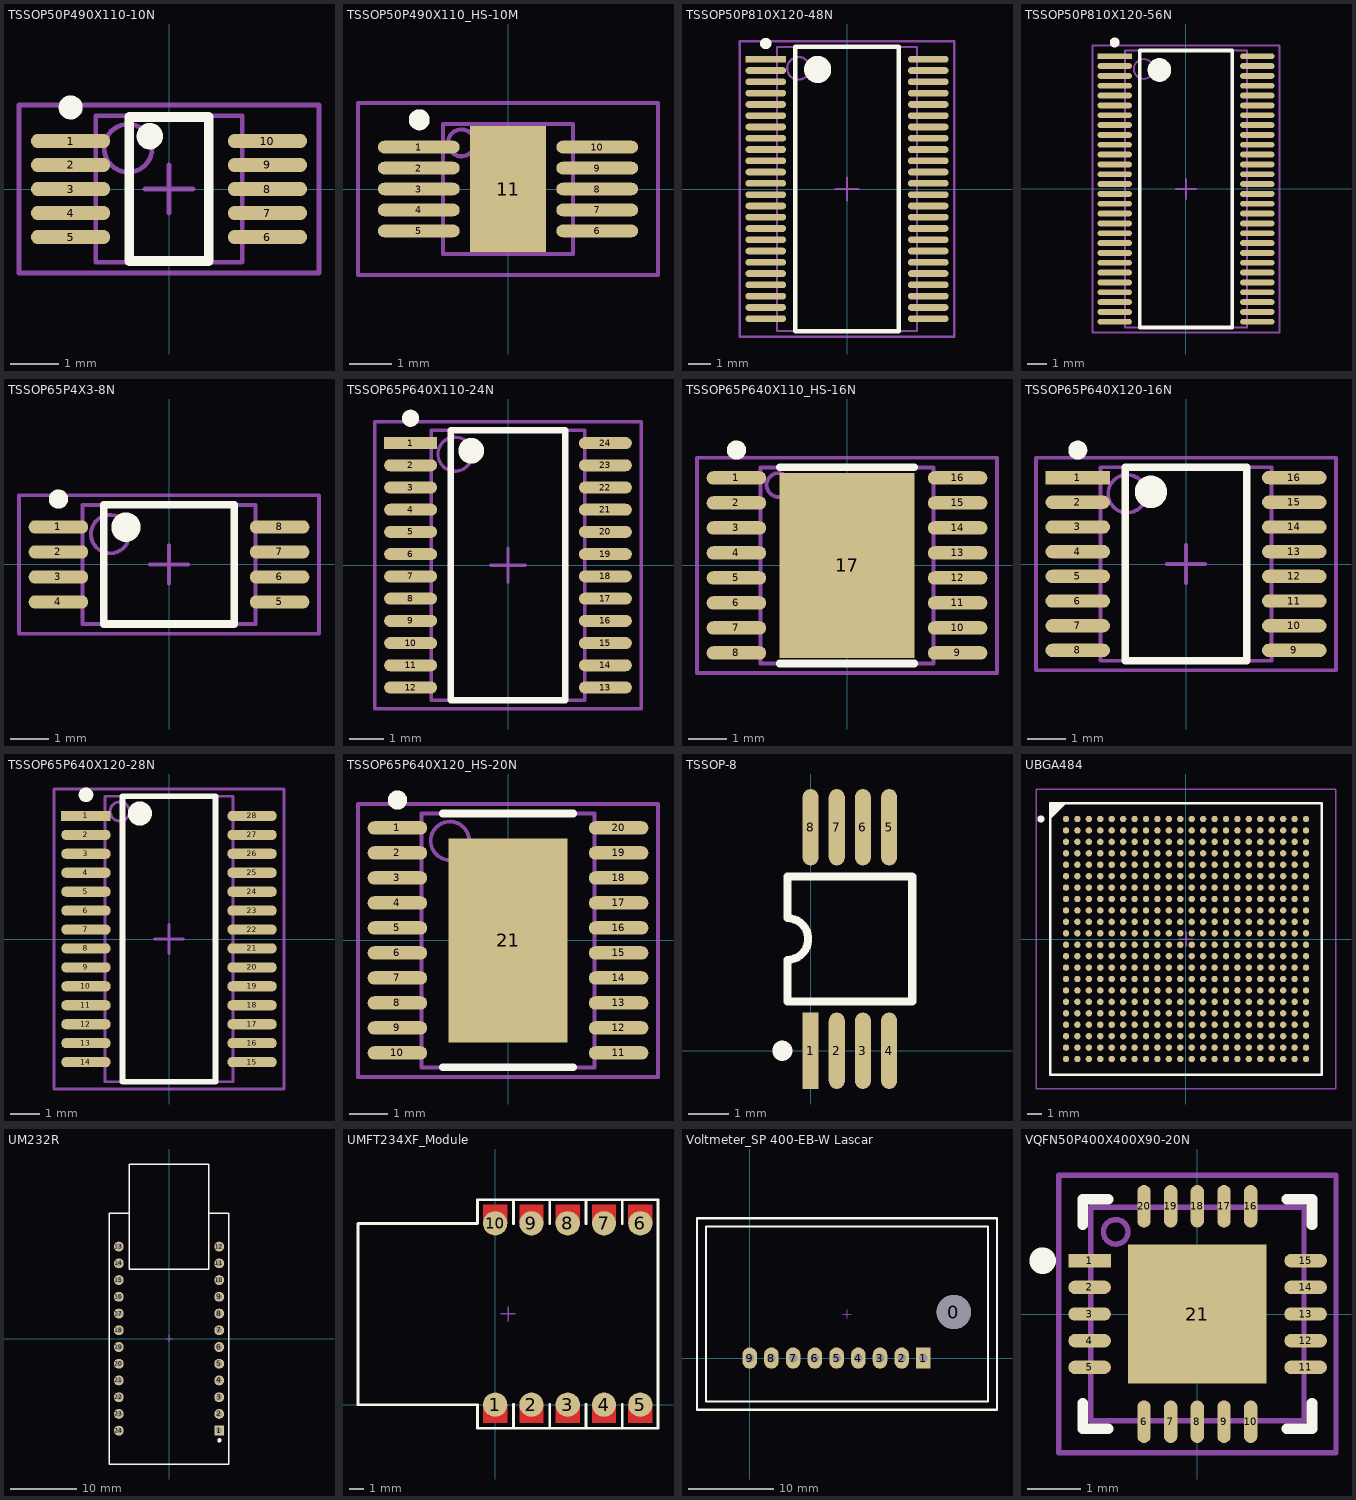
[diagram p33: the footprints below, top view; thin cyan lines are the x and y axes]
## TSSOP50P490X110-10N [mm] "TSSOP, 10-Leads, Body 3.0x3.0mm (max), Pitch 0.50mm, IPC Medium Density"
height 1.1
pads (10):
  oval 1.65x0.3 smd: 1(-2.05,1) 2(-2.05,0.5) 3(-2.05,0) 4(-2.05,-0.5) 5(-2.05,-1) 6(2.05,-1) 7(2.05,-0.5) 8(2.05,0) 9(2.05,0.5) 10(2.05,1)
Top Overlay:
  circle w0.25: c-2.05,1.7 r0.125
  circle w0.35: c-0.4,1.1 r0.1
  lines w0.2: -0.825,-1.5 -0.825,1.5 0.825,1.5 0.825,-1.5 -0.825,-1.5
M13_Assembly_Info:
  circle w0.1: c-0.85,0.85 r0.5
  lines w0.1: -1.525,-1.525 -1.525,1.525 1.525,1.525 1.525,-1.525 -1.525,-1.525
M15_Country_Yard:
  lines w0.1: -0.5,0 0.5,0 ; 0,-0.5 0,0.5 ; -3.125,-1.75 -3.125,1.75 3.125,1.75 3.125,-1.75 -3.125,-1.75
3D body: height 1.1, standoff 0.15, extent -1.525,-1.525 1.525,1.525

## TSSOP50P490X110_HS-10M [mm] "TSSOP, 10-Leads, Body 3.1x3.1mm (max), Pitch 0.50mm, IPC Low Density"
height 1.1
pads (11):
  oval 1.95x0.3 smd: 1(-2.125,1) 2(-2.125,0.5) 3(-2.125,0) 4(-2.125,-0.5) 5(-2.125,-1) 6(2.125,-1) 7(2.125,-0.5) 8(2.125,0) 9(2.125,0.5) 10(2.125,1)
  rect 1.8x3 smd: 11(0,0)
Top Overlay:
  circle w0.25: c-2.115,1.65 r0.125
M13_Assembly_Info:
  circle w0.1: c-1.11,1.1 r0.32
  lines w0.1: -1.55,-1.55 -1.55,1.55 1.55,1.55 1.55,-1.55 -1.55,-1.55
M15_Country_Yard:
  lines w0.1: -0.5,0 0.5,0 ; 0,-0.5 0,0.5 ; -3.575,-2.05 -3.575,2.05 3.575,2.05 3.575,-2.05 -3.575,-2.05
3D body: height 1.1, standoff 0.2, extent -1.55,-1.55 1.55,1.55

## TSSOP50P810X120-48N [mm] "TSSOP, 48-Leads, Body 12.6x6.2mm (max), Pitch 0.50mm, IPC Medium Density"
height 1.2
pads (48):
  rect 1.8x0.3 smd: 1(-3.6,5.75)
  oval 1.8x0.3 smd: 2(-3.6,5.25) 3(-3.6,4.75) 4(-3.6,4.25) 5(-3.6,3.75) 6(-3.6,3.25) 7(-3.6,2.75) 8(-3.6,2.25) 9(-3.6,1.75) 10(-3.6,1.25) 11(-3.6,0.75) 12(-3.6,0.25) 13(-3.6,-0.25) 14(-3.6,-0.75) 15(-3.6,-1.25) 16(-3.6,-1.75) 17(-3.6,-2.25) 18(-3.6,-2.75) 19(-3.6,-3.25) 20(-3.6,-3.75) 21(-3.6,-4.25) 22(-3.6,-4.75) 23(-3.6,-5.25) 24(-3.6,-5.75) 25(3.6,-5.75) 26(3.6,-5.25) 27(3.6,-4.75) 28(3.6,-4.25) 29(3.6,-3.75) 30(3.6,-3.25) 31(3.6,-2.75) 32(3.6,-2.25) 33(3.6,-1.75) 34(3.6,-1.25) 35(3.6,-0.75) 36(3.6,-0.25) 37(3.6,0.25) 38(3.6,0.75) 39(3.6,1.25) 40(3.6,1.75) 41(3.6,2.25) 42(3.6,2.75) 43(3.6,3.25) 44(3.6,3.75) 45(3.6,4.25) 46(3.6,4.75) 47(3.6,5.25) 48(3.6,5.75)
Top Overlay:
  circle w0.6: c-1.3,5.3 r0.3
  circle w0.25: c-3.6,6.45 r0.125
  lines w0.2: -2.3,-6.3 2.3,-6.3 2.3,6.3 -2.3,6.3 -2.3,-6.3
M13_Assembly_Info:
  circle w0.1: c-2.15,5.35 r0.5
  lines w0.1: -3.1,-6.3 3.1,-6.3 3.1,6.3 -3.1,6.3 -3.1,-6.3
M15_Country_Yard:
  lines w0.1: -0.5,0 0.5,0 ; 0,-0.5 0,0.5 ; -4.75,-6.55 4.75,-6.55 4.75,6.55 -4.75,6.55 -4.75,-6.55
3D body: height 1.2, standoff 0.15, extent -3.1,-6.3 3.1,6.3

## TSSOP50P810X120-56N [mm] "TSSOP, 56-Leads, Body 14.1x6.2mm (max), Pitch 0.50mm, IPC Medium Density"
height 1.2
pads (56):
  rect 1.75x0.3 smd: 1(-3.625,6.75)
  oval 1.75x0.3 smd: 2(-3.625,6.25) 3(-3.625,5.75) 4(-3.625,5.25) 5(-3.625,4.75) 6(-3.625,4.25) 7(-3.625,3.75) 8(-3.625,3.25) 9(-3.625,2.75) 10(-3.625,2.25) 11(-3.625,1.75) 12(-3.625,1.25) 13(-3.625,0.75) 14(-3.625,0.25) 15(-3.625,-0.25) 16(-3.625,-0.75) 17(-3.625,-1.25) 18(-3.625,-1.75) 19(-3.625,-2.25) 20(-3.625,-2.75) 21(-3.625,-3.25) 22(-3.625,-3.75) 23(-3.625,-4.25) 24(-3.625,-4.75) 25(-3.625,-5.25) 26(-3.625,-5.75) 27(-3.625,-6.25) 28(-3.625,-6.75) 29(3.625,-6.75) 30(3.625,-6.25) 31(3.625,-5.75) 32(3.625,-5.25) 33(3.625,-4.75) 34(3.625,-4.25) 35(3.625,-3.75) 36(3.625,-3.25) 37(3.625,-2.75) 38(3.625,-2.25) 39(3.625,-1.75) 40(3.625,-1.25) 41(3.625,-0.75) 42(3.625,-0.25) 43(3.625,0.25) 44(3.625,0.75) 45(3.625,1.25) 46(3.625,1.75) 47(3.625,2.25) 48(3.625,2.75) 49(3.625,3.25) 50(3.625,3.75) 51(3.625,4.25) 52(3.625,4.75) 53(3.625,5.25) 54(3.625,5.75) 55(3.625,6.25) 56(3.625,6.75)
Top Overlay:
  circle w0.25: c-3.625,7.45 r0.125
  circle w0.6: c-1.35,6.05 r0.3
  lines w0.2: -2.35,-7.05 -2.35,7.05 2.35,7.05 2.35,-7.05 -2.35,-7.05
M13_Assembly_Info:
  circle w0.1: c-2.15,6.1 r0.5
  lines w0.1: -3.1,-7.05 -3.1,7.05 3.1,7.05 3.1,-7.05 -3.1,-7.05
M15_Country_Yard:
  lines w0.1: -0.5,0 0.5,0 ; 0,-0.5 0,0.5 ; -4.75,-7.3 -4.75,7.3 4.75,7.3 4.75,-7.3 -4.75,-7.3
3D body: height 1.2, standoff 0.15, extent -3.1,-7.05 3.1,7.05

## TSSOP65P4X3-8N [mm] "TSSOP, 8-Leads, Body 3.x4mm (max), Pitch 0.65mm, IPC Medium Density"
height 1.2
pads (8):
  oval 1.55x0.35 smd: 1(-2.875,0.975) 2(-2.875,0.325) 3(-2.875,-0.325) 4(-2.875,-0.975) 5(2.875,-0.975) 6(2.875,-0.325) 7(2.875,0.325) 8(2.875,0.975)
Top Overlay:
  circle w0.6: c-1.12,0.97 r0.08
  circle w0.25: c-2.875,1.7 r0.125
  lines w0.2: -1.7,-1.55 1.7,-1.55 1.7,1.55 -1.7,1.55 -1.7,-1.55
M13_Assembly_Info:
  circle w0.1: c-1.53,0.79 r0.5
  lines w0.1: -2.25,-1.55 2.25,-1.55 2.25,1.55 -2.25,1.55 -2.25,-1.55
M15_Country_Yard:
  lines w0.1: -0.5,0 0.5,0 ; 0,-0.5 0,0.5 ; -3.9,-1.8 3.9,-1.8 3.9,1.8 -3.9,1.8 -3.9,-1.8
3D body: height 1.2, standoff 0.2, extent -2.25,-1.55 2.25,1.55

## TSSOP65P640X110-24N [mm] "TSSOP, 24-Leads, Body 7.9x4.5mm (max), Pitch 0.65mm, IPC Medium Density"
height 1.1
pads (24):
  rect 1.55x0.35 smd: 1(-2.85,3.575)
  oval 1.55x0.35 smd: 2(-2.85,2.925) 3(-2.85,2.275) 4(-2.85,1.625) 5(-2.85,0.975) 6(-2.85,0.325) 7(-2.85,-0.325) 8(-2.85,-0.975) 9(-2.85,-1.625) 10(-2.85,-2.275) 11(-2.85,-2.925) 12(-2.85,-3.575) 13(2.85,-3.575) 14(2.85,-2.925) 15(2.85,-2.275) 16(2.85,-1.625) 17(2.85,-0.975) 18(2.85,-0.325) 19(2.85,0.325) 20(2.85,0.975) 21(2.85,1.625) 22(2.85,2.275) 23(2.85,2.925) 24(2.85,3.575)
Top Overlay:
  circle w0.6: c-1.075,3.35 r0.075
  circle w0.25: c-2.85,4.3 r0.125
  lines w0.2: -1.675,-3.95 1.675,-3.95 1.675,3.95 -1.675,3.95 -1.675,-3.95
M13_Assembly_Info:
  circle w0.1: c-1.55,3.25 r0.5
  lines w0.1: -2.25,-3.95 2.25,-3.95 2.25,3.95 -2.25,3.95 -2.25,-3.95
M15_Country_Yard:
  lines w0.1: -0.5,0 0.5,0 ; 0,-0.5 0,0.5 ; -3.9,-4.2 3.9,-4.2 3.9,4.2 -3.9,4.2 -3.9,-4.2
3D body: height 1.1, standoff 0.15, extent -2.25,-3.95 2.25,3.95

## TSSOP65P640X110_HS-16N [mm] "TSOP, 16-Leads, Body 5.1x4.5mm (max), Pitch 0.65mm, IPC Medium Density"
height 1.1
pads (17):
  oval 1.55x0.35 smd: 1(-2.875,2.275) 2(-2.875,1.625) 3(-2.875,0.975) 4(-2.875,0.325) 5(-2.875,-0.325) 6(-2.875,-0.975) 7(-2.875,-1.625) 8(-2.875,-2.275) 9(2.875,-2.275) 10(2.875,-1.625) 11(2.875,-0.975) 12(2.875,-0.325) 13(2.875,0.325) 14(2.875,0.975) 15(2.875,1.625) 16(2.875,2.275)
  rect 3.5x4.8 smd: 17(0,0)
Top Overlay:
  circle w0.25: c-2.875,3 r0.125
  lines w0.2: -1.75,-2.55 1.75,-2.55 ; -1.75,2.55 1.75,2.55
M13_Assembly_Info:
  circle w0.1: c-1.78,2.09 r0.31
  lines w0.1: -2.25,-2.55 -2.25,2.55 2.25,2.55 2.25,-2.55 -2.25,-2.55
M15_Country_Yard:
  lines w0.1: -0.5,0 0.5,0 ; 0,-0.5 0,0.5 ; -3.9,-2.8 -3.9,2.8 3.9,2.8 3.9,-2.8 -3.9,-2.8
3D body: height 1.1, standoff 0.05, extent -2.25,-2.55 2.25,2.55

## TSSOP65P640X120-16N [mm] "TSOP, 16-Leads, Body 5.1x4.5mm (max), Pitch 0.65mm, IPC Medium Density"
height 1.2
pads (16):
  rect 1.7x0.35 smd: 1(-2.85,2.275)
  oval 1.7x0.35 smd: 2(-2.85,1.625) 3(-2.85,0.975) 4(-2.85,0.325) 5(-2.85,-0.325) 6(-2.85,-0.975) 7(-2.85,-1.625) 8(-2.85,-2.275) 9(2.85,-2.275) 10(2.85,-1.625) 11(2.85,-0.975) 12(2.85,-0.325) 13(2.85,0.325) 14(2.85,0.975) 15(2.85,1.625) 16(2.85,2.275)
Top Overlay:
  circle w0.25: c-2.85,3 r0.125
  circle w0.6: c-0.925,1.9 r0.125
  lines w0.2: -1.6,-2.55 -1.6,2.55 1.6,2.55 1.6,-2.55 -1.6,-2.55
M13_Assembly_Info:
  circle w0.1: c-1.55,1.85 r0.5
  lines w0.1: -2.25,-2.55 -2.25,2.55 2.25,2.55 2.25,-2.55 -2.25,-2.55
M15_Country_Yard:
  lines w0.1: -0.5,0 0.5,0 ; 0,-0.5 0,0.5 ; -3.95,-2.8 -3.95,2.8 3.95,2.8 3.95,-2.8 -3.95,-2.8
3D body: height 1.2, standoff 0.15, extent -2.25,-2.55 2.25,2.55

## TSSOP65P640X120-28N [mm] "TSSOP, 28-Leads, Body 9.8x4.4mm (max), Pitch 0.65mm, IPC Medium Density"
height 1.2
pads (28):
  rect 1.7x0.35 smd: 1(-2.85,4.225)
  oval 1.7x0.35 smd: 2(-2.85,3.575) 3(-2.85,2.925) 4(-2.85,2.275) 5(-2.85,1.625) 6(-2.85,0.975) 7(-2.85,0.325) 8(-2.85,-0.325) 9(-2.85,-0.975) 10(-2.85,-1.625) 11(-2.85,-2.275) 12(-2.85,-2.925) 13(-2.85,-3.575) 14(-2.85,-4.225) 15(2.85,-4.225) 16(2.85,-3.575) 17(2.85,-2.925) 18(2.85,-2.275) 19(2.85,-1.625) 20(2.85,-0.975) 21(2.85,-0.325) 22(2.85,0.325) 23(2.85,0.975) 24(2.85,1.625) 25(2.85,2.275) 26(2.85,2.925) 27(2.85,3.575) 28(2.85,4.225)
Top Overlay:
  circle w0.6: c-1,4.31 r0.11
  circle w0.25: c-2.85,4.95 r0.125
  lines w0.2: -1.6,-4.9 1.6,-4.9 1.6,4.9 -1.6,4.9 -1.6,-4.9
M13_Assembly_Info:
  circle w0.1: c-1.69,4.38 r0.33
  lines w0.1: -2.2,-4.9 2.2,-4.9 2.2,4.9 -2.2,4.9 -2.2,-4.9
M15_Country_Yard:
  lines w0.1: -0.5,0 0.5,0 ; 0,-0.5 0,0.5 ; -3.95,-5.15 3.95,-5.15 3.95,5.15 -3.95,5.15 -3.95,-5.15
3D body: height 1.2, standoff 0.15, extent -2.2,-4.9 2.2,4.9

## TSSOP65P640X120_HS-20N [mm] "TSSOP, 20-Leads, Body 6.6x4.5mm (max), Pitch 0.65mm, IPC Medium Density"
height 1.2
pads (21):
  oval 1.55x0.35 smd: 1(-2.875,2.925) 2(-2.875,2.275) 3(-2.875,1.625) 4(-2.875,0.975) 5(-2.875,0.325) 6(-2.875,-0.325) 7(-2.875,-0.975) 8(-2.875,-1.625) 9(-2.875,-2.275) 10(-2.875,-2.925) 11(2.875,-2.925) 12(2.875,-2.275) 13(2.875,-1.625) 14(2.875,-0.975) 15(2.875,-0.325) 16(2.875,0.325) 17(2.875,0.975) 18(2.875,1.625) 19(2.875,2.275) 20(2.875,2.925)
  rect 3.1x5.3 smd: 21(0,0)
Top Overlay:
  circle w0.25: c-2.875,3.65 r0.125
  lines w0.2: -1.7,-3.3 1.7,-3.3 ; -1.7,3.3 1.7,3.3
M13_Assembly_Info:
  circle w0.1: c-1.51,2.59 r0.5
  lines w0.1: -2.25,-3.3 2.25,-3.3 2.25,3.3 -2.25,3.3 -2.25,-3.3
M15_Country_Yard:
  lines w0.1: -0.5,0 0.5,0 ; 0,-0.5 0,0.5 ; -3.9,-3.55 3.9,-3.55 3.9,3.55 -3.9,3.55 -3.9,-3.55
3D body: height 1.2, standoff 0.15, extent -2.25,-3.3 2.25,3.3

## TSSOP-8 [mm] "Shrink Small Outline; 8 Leads; Body Width 4.4 mm; Pitch 0.65 mm"
height 1.2
pads (8):
  rect 0.4x1.9 smd: 1(0,0)
  oval 0.4x1.9 smd: 2(0.65,0) 3(1.3,0) 4(1.95,0) 5(1.95,5.55) 6(1.3,5.55) 7(0.65,5.55) 8(0,5.55)
Top Overlay:
  circle w0.25: c-0.7,0 r0.125
  lines w0.2: -0.575,1.225 2.525,1.225 2.525,4.325 -0.575,4.325 -0.575,3.292 cw(c-0.575,2.775) -0.575,2.258 -0.575,1.225

## UBGA484 [mm] "BGA, 484-Leads, Body 19x19mm, Pitch 0.8mm"
height 2.2
pads (484):
  round 0.45 smd: A1(-8.4,8.4) A2(-7.6,8.4) A3(-6.8,8.4) A4(-6,8.4) A5(-5.2,8.4) A6(-4.4,8.4) A7(-3.6,8.4) A8(-2.8,8.4) A9(-2,8.4) A10(-1.2,8.4) A11(-0.4,8.4) A12(0.4,8.4) A13(1.2,8.4) A14(2,8.4) A15(2.8,8.4) A16(3.6,8.4) A17(4.4,8.4) A18(5.2,8.4) A19(6,8.4) A20(6.8,8.4) A21(7.6,8.4) A22(8.4,8.4) AA1(-8.4,-7.6) AA2(-7.6,-7.6) AA3(-6.8,-7.6) AA4(-6,-7.6) AA5(-5.2,-7.6) AA6(-4.4,-7.6) AA7(-3.6,-7.6) AA8(-2.8,-7.6) AA9(-2,-7.6) AA10(-1.2,-7.6) AA11(-0.4,-7.6) AA12(0.4,-7.6) AA13(1.2,-7.6) AA14(2,-7.6) AA15(2.8,-7.6) AA16(3.6,-7.6) AA17(4.4,-7.6) AA18(5.2,-7.6) AA19(6,-7.6) AA20(6.8,-7.6) AA21(7.6,-7.6) AA22(8.4,-7.6) AB1(-8.4,-8.4) AB2(-7.6,-8.4) AB3(-6.8,-8.4) AB4(-6,-8.4) AB5(-5.2,-8.4) AB6(-4.4,-8.4) AB7(-3.6,-8.4) AB8(-2.8,-8.4) AB9(-2,-8.4) AB10(-1.2,-8.4) AB11(-0.4,-8.4) AB12(0.4,-8.4) AB13(1.2,-8.4) AB14(2,-8.4) AB15(2.8,-8.4) AB16(3.6,-8.4) AB17(4.4,-8.4) AB18(5.2,-8.4) AB19(6,-8.4) AB20(6.8,-8.4) AB21(7.6,-8.4) AB22(8.4,-8.4) B1(-8.4,7.6) B2(-7.6,7.6) B3(-6.8,7.6) B4(-6,7.6) B5(-5.2,7.6) B6(-4.4,7.6) B7(-3.6,7.6) B8(-2.8,7.6) B9(-2,7.6) B10(-1.2,7.6) B11(-0.4,7.6) B12(0.4,7.6) B13(1.2,7.6) B14(2,7.6) B15(2.8,7.6) B16(3.6,7.6) B17(4.4,7.6) B18(5.2,7.6) B19(6,7.6) B20(6.8,7.6) B21(7.6,7.6) B22(8.4,7.6) C1(-8.4,6.8) C2(-7.6,6.8) C3(-6.8,6.8) C4(-6,6.8) C5(-5.2,6.8) C6(-4.4,6.8) C7(-3.6,6.8) C8(-2.8,6.8) C9(-2,6.8) C10(-1.2,6.8) C11(-0.4,6.8) C12(0.4,6.8) C13(1.2,6.8) C14(2,6.8) C15(2.8,6.8) C16(3.6,6.8) C17(4.4,6.8) C18(5.2,6.8) C19(6,6.8) C20(6.8,6.8) C21(7.6,6.8) C22(8.4,6.8) D1(-8.4,6) D2(-7.6,6) D3(-6.8,6) D4(-6,6) D5(-5.2,6) D6(-4.4,6) D7(-3.6,6) D8(-2.8,6) D9(-2,6) D10(-1.2,6) D11(-0.4,6) D12(0.4,6) D13(1.2,6) D14(2,6) D15(2.8,6) D16(3.6,6) D17(4.4,6) D18(5.2,6) D19(6,6) D20(6.8,6) D21(7.6,6) D22(8.4,6) E1(-8.4,5.2) E2(-7.6,5.2) E3(-6.8,5.2) E4(-6,5.2) E5(-5.2,5.2) E6(-4.4,5.2) E7(-3.6,5.2) E8(-2.8,5.2) E9(-2,5.2) E10(-1.2,5.2) E11(-0.4,5.2) E12(0.4,5.2) E13(1.2,5.2) E14(2,5.2) E15(2.8,5.2) E16(3.6,5.2) E17(4.4,5.2) E18(5.2,5.2) E19(6,5.2) E20(6.8,5.2) E21(7.6,5.2) E22(8.4,5.2) F1(-8.4,4.4) F2(-7.6,4.4) F3(-6.8,4.4) F4(-6,4.4) F5(-5.2,4.4) F6(-4.4,4.4) F7(-3.6,4.4) F8(-2.8,4.4) F9(-2,4.4) F10(-1.2,4.4) F11(-0.4,4.4) F12(0.4,4.4) F13(1.2,4.4) F14(2,4.4) F15(2.8,4.4) F16(3.6,4.4) F17(4.4,4.4) F18(5.2,4.4) F19(6,4.4) F20(6.8,4.4) F21(7.6,4.4) F22(8.4,4.4) G1(-8.4,3.6) G2(-7.6,3.6) G3(-6.8,3.6) G4(-6,3.6) G5(-5.2,3.6) G6(-4.4,3.6) G7(-3.6,3.6) G8(-2.8,3.6) G9(-2,3.6) G10(-1.2,3.6) G11(-0.4,3.6) G12(0.4,3.6) G13(1.2,3.6) G14(2,3.6) G15(2.8,3.6) G16(3.6,3.6) G17(4.4,3.6) G18(5.2,3.6) G19(6,3.6) G20(6.8,3.6) G21(7.6,3.6) G22(8.4,3.6) H1(-8.4,2.8) H2(-7.6,2.8) H3(-6.8,2.8) H4(-6,2.8) H5(-5.2,2.8) H6(-4.4,2.8) H7(-3.6,2.8) H8(-2.8,2.8) H9(-2,2.8) H10(-1.2,2.8) H11(-0.4,2.8) H12(0.4,2.8) H13(1.2,2.8) H14(2,2.8) H15(2.8,2.8) H16(3.6,2.8) H17(4.4,2.8) H18(5.2,2.8) H19(6,2.8) H20(6.8,2.8) H21(7.6,2.8) H22(8.4,2.8) J1(-8.4,2) J2(-7.6,2) J3(-6.8,2) J4(-6,2) J5(-5.2,2) J6(-4.4,2) J7(-3.6,2) J8(-2.8,2) J9(-2,2) J10(-1.2,2) J11(-0.4,2) J12(0.4,2) J13(1.2,2) J14(2,2) J15(2.8,2) J16(3.6,2) J17(4.4,2) J18(5.2,2) J19(6,2) J20(6.8,2) J21(7.6,2) J22(8.4,2) K1(-8.4,1.2) K2(-7.6,1.2) K3(-6.8,1.2) K4(-6,1.2) K5(-5.2,1.2) K6(-4.4,1.2) K7(-3.6,1.2) K8(-2.8,1.2) K9(-2,1.2) K10(-1.2,1.2) K11(-0.4,1.2) K12(0.4,1.2) K13(1.2,1.2) K14(2,1.2) K15(2.8,1.2) K16(3.6,1.2) K17(4.4,1.2) K18(5.2,1.2) K19(6,1.2) K20(6.8,1.2) K21(7.6,1.2) K22(8.4,1.2) L1(-8.4,0.4) L2(-7.6,0.4) L3(-6.8,0.4) L4(-6,0.4) L5(-5.2,0.4) L6(-4.4,0.4) L7(-3.6,0.4) L8(-2.8,0.4) L9(-2,0.4) L10(-1.2,0.4) L11(-0.4,0.4) L12(0.4,0.4) L13(1.2,0.4) L14(2,0.4) L15(2.8,0.4) L16(3.6,0.4) L17(4.4,0.4) L18(5.2,0.4) L19(6,0.4) L20(6.8,0.4) L21(7.6,0.4) L22(8.4,0.4) M1(-8.4,-0.4) M2(-7.6,-0.4) M3(-6.8,-0.4) M4(-6,-0.4) M5(-5.2,-0.4) M6(-4.4,-0.4) M7(-3.6,-0.4) M8(-2.8,-0.4) M9(-2,-0.4) M10(-1.2,-0.4) M11(-0.4,-0.4) M12(0.4,-0.4) M13(1.2,-0.4) M14(2,-0.4) M15(2.8,-0.4) M16(3.6,-0.4) M17(4.4,-0.4) M18(5.2,-0.4) M19(6,-0.4) M20(6.8,-0.4) M21(7.6,-0.4) M22(8.4,-0.4) N1(-8.4,-1.2) N2(-7.6,-1.2) N3(-6.8,-1.2) N4(-6,-1.2) N5(-5.2,-1.2) N6(-4.4,-1.2) N7(-3.6,-1.2) N8(-2.8,-1.2) N9(-2,-1.2) N10(-1.2,-1.2) N11(-0.4,-1.2) N12(0.4,-1.2) N13(1.2,-1.2) N14(2,-1.2) N15(2.8,-1.2) N16(3.6,-1.2) N17(4.4,-1.2) N18(5.2,-1.2) N19(6,-1.2) N20(6.8,-1.2) N21(7.6,-1.2) N22(8.4,-1.2) P1(-8.4,-2) P2(-7.6,-2) P3(-6.8,-2) P4(-6,-2) P5(-5.2,-2) P6(-4.4,-2) P7(-3.6,-2) P8(-2.8,-2) P9(-2,-2) P10(-1.2,-2) P11(-0.4,-2) P12(0.4,-2) P13(1.2,-2) P14(2,-2) P15(2.8,-2) P16(3.6,-2) P17(4.4,-2) P18(5.2,-2) P19(6,-2) P20(6.8,-2) P21(7.6,-2) P22(8.4,-2) R1(-8.4,-2.8) R2(-7.6,-2.8) R3(-6.8,-2.8) R4(-6,-2.8) R5(-5.2,-2.8) R6(-4.4,-2.8) R7(-3.6,-2.8) R8(-2.8,-2.8) R9(-2,-2.8) R10(-1.2,-2.8) R11(-0.4,-2.8) R12(0.4,-2.8) R13(1.2,-2.8) R14(2,-2.8) R15(2.8,-2.8) R16(3.6,-2.8) R17(4.4,-2.8) R18(5.2,-2.8) R19(6,-2.8) R20(6.8,-2.8) R21(7.6,-2.8) R22(8.4,-2.8) T1(-8.4,-3.6) T2(-7.6,-3.6) T3(-6.8,-3.6) T4(-6,-3.6) T5(-5.2,-3.6) T6(-4.4,-3.6) T7(-3.6,-3.6) T8(-2.8,-3.6) T9(-2,-3.6) T10(-1.2,-3.6) T11(-0.4,-3.6) T12(0.4,-3.6) T13(1.2,-3.6) T14(2,-3.6) T15(2.8,-3.6) T16(3.6,-3.6) T17(4.4,-3.6) T18(5.2,-3.6) T19(6,-3.6) T20(6.8,-3.6) T21(7.6,-3.6) T22(8.4,-3.6) U1(-8.4,-4.4) U2(-7.6,-4.4) U3(-6.8,-4.4) U4(-6,-4.4) U5(-5.2,-4.4) U6(-4.4,-4.4) U7(-3.6,-4.4) U8(-2.8,-4.4) U9(-2,-4.4) U10(-1.2,-4.4) U11(-0.4,-4.4) U12(0.4,-4.4) U13(1.2,-4.4) U14(2,-4.4) U15(2.8,-4.4) U16(3.6,-4.4) U17(4.4,-4.4) U18(5.2,-4.4) U19(6,-4.4) U20(6.8,-4.4) U21(7.6,-4.4) U22(8.4,-4.4) V1(-8.4,-5.2) V2(-7.6,-5.2) V3(-6.8,-5.2) V4(-6,-5.2) V5(-5.2,-5.2) V6(-4.4,-5.2) V7(-3.6,-5.2) V8(-2.8,-5.2) V9(-2,-5.2) V10(-1.2,-5.2) V11(-0.4,-5.2) V12(0.4,-5.2) V13(1.2,-5.2) V14(2,-5.2) V15(2.8,-5.2) V16(3.6,-5.2) V17(4.4,-5.2) V18(5.2,-5.2) V19(6,-5.2) V20(6.8,-5.2) V21(7.6,-5.2) V22(8.4,-5.2) W1(-8.4,-6) W2(-7.6,-6) W3(-6.8,-6) W4(-6,-6) W5(-5.2,-6) W6(-4.4,-6) W7(-3.6,-6) W8(-2.8,-6) W9(-2,-6) W10(-1.2,-6) W11(-0.4,-6) W12(0.4,-6) W13(1.2,-6) W14(2,-6) W15(2.8,-6) W16(3.6,-6) W17(4.4,-6) W18(5.2,-6) W19(6,-6) W20(6.8,-6) W21(7.6,-6) W22(8.4,-6) Y1(-8.4,-6.8) Y2(-7.6,-6.8) Y3(-6.8,-6.8) Y4(-6,-6.8) Y5(-5.2,-6.8) Y6(-4.4,-6.8) Y7(-3.6,-6.8) Y8(-2.8,-6.8) Y9(-2,-6.8) Y10(-1.2,-6.8) Y11(-0.4,-6.8) Y12(0.4,-6.8) Y13(1.2,-6.8) Y14(2,-6.8) Y15(2.8,-6.8) Y16(3.6,-6.8) Y17(4.4,-6.8) Y18(5.2,-6.8) Y19(6,-6.8) Y20(6.8,-6.8) Y21(7.6,-6.8) Y22(8.4,-6.8)
Top Overlay:
  circle w0.25: c-10.15,8.4 r0.125
  region: -8.5,9.5 -9.5,8.5 -9.5,9.5
  lines w0.2: -9.5,8.5 -8.5,9.5 ; -9.5,-9.5 -9.5,9.5 9.5,9.5 9.5,-9.5 -9.5,-9.5
M13_Assembly_Info:
  lines w0.1: -9.5,-9.5 -9.5,9.5 9.5,9.5 9.5,-9.5 -9.5,-9.5
M15_Country_Yard:
  lines w0.1: -0.5,0 0.5,0 ; 0,-0.5 0,0.5 ; -10.5,-10.5 -10.5,10.5 10.5,10.5 10.5,-10.5 -10.5,-10.5
3D body: height 2.2, standoff 0, extent -9.5,-9.5 9.5,9.5

## UM232R [mm] "DIP, 24-Pin, Row Spacing 15.24 mm, Pitch 2.54 mm"
height 4.98
pads (24):
  rect 1.5x1.5 hole 0.9: 1(7.62,-13.97)
  round 1.5 hole 0.9: 2(7.62,-11.43) 3(7.62,-8.89) 4(7.62,-6.35) 5(7.62,-3.81) 6(7.62,-1.27) 7(7.62,1.27) 8(7.62,3.81) 9(7.62,6.35) 10(7.62,8.89) 11(7.62,11.43) 12(7.62,13.97) 13(-7.62,13.97) 14(-7.62,11.43) 15(-7.62,8.89) 16(-7.62,6.35) 17(-7.62,3.81) 18(-7.62,1.27) 19(-7.62,-1.27) 20(-7.62,-3.81) 21(-7.62,-6.35) 22(-7.62,-8.89) 23(-7.62,-11.43) 24(-7.62,-13.97)
Top Overlay:
  circle w0.4: c7.652,-15.44 r0.125
  lines w0.2: -6,19.01 -9.1,19.01 -9.1,-19.03 9.1,-19.03 9.1,19.01 6,19.01 ; -6,10.51 -6,26.51 6,26.51 6,10.51 -6,10.51
M15_Country_Yard:
  lines w0.1: -0.5,0 0.5,0 ; 0,-0.5 0,0.5

## UMFT234XF_Module [mm]
pads (10):
  round 1.7 smd: 1(0,0) 2(2.54,0) 3(5.08,0) 4(7.62,0) 5(10.16,0) 6(10.16,12.7) 7(7.62,12.7) 8(5.08,12.7) 9(2.54,12.7) 10(0,12.7)
Top Layer:
  region: 11.01,-1.3 11.01,0 9.31,0 9.31,-1.3
  region: 8.47,-1.3 8.47,0 6.77,0 6.77,-1.3
  region: 5.93,-1.3 5.93,0 4.23,0 4.23,-1.3
  region: 3.39,-1.3 3.39,0 1.69,0 1.69,-1.3
  region: 0.85,-1.3 0.85,0 -0.85,0 -0.85,-1.3
  region: 9.31,14 9.31,12.7 11.01,12.7 11.01,14
  region: 6.77,14 6.77,12.7 8.47,12.7 8.47,14
  region: 4.23,14 4.23,12.7 5.93,12.7 5.93,14
  region: 1.69,14 1.69,12.7 3.39,12.7 3.39,14
  region: -0.85,14 -0.85,12.7 0.85,12.7 0.85,14
Top Overlay:
  lines w0.2: 1.28,-1.652 1.28,0.03 ; 1.28,12.665 1.28,14.348 ; 3.82,-1.652 3.82,0.03 ; 3.82,12.668 3.82,14.35 ; 6.36,-1.652 6.36,0.03 ; 6.36,12.665 6.36,14.348 ; 8.9,-1.652 8.9,0.03 ; 8.9,12.668 8.9,14.35 ; -9.605,-0.002 -1.25,-0.002 -1.25,-1.635 -1.232,-1.652 11.4,-1.652 11.4,14.348 -1.25,14.348 -1.25,12.698 -9.605,12.698 -9.605,-0.002
Mechanical 1:
  lines w0.1: -9.605,-0.002 -9.605,12.698
M13_Assembly_Info:
  text "CTS#" at 0.38,8.94 h0.8
  text "TXD" at 8.05,9.43 h0.8
  text "GND" at 8.01,1.22 h0.8
  text "RXD" at 2.96,9.48 h0.8
  text "RTS#" at 5.47,8.95 h0.8
  text "CBUS0" at 10.6,8.07 h0.8
  text "RESET#" at 0.37,1.24 h0.8
  text "3V3OUT" at 2.91,1.24 h0.8
  text "VBUS" at 10.56,1.22 h0.8
  text "VCCIO" at 5.5,1.27 h0.8
M15_Country_Yard:
  lines w0.1: 0.4,6.35 1.4,6.35 ; 0.9,5.85 0.9,6.85

## Voltmeter_SP 400-EB-W Lascar [mm] "SP 400-EB-W; 3½ Digit Backlit LCD Voltmeter Module; Lascar"
pads (10):
  round 4 hole 4 unplated: 0(23.88,5.38)
  rect 1.7x2.5 hole 1: 1(20.32,0)
  oval 1.7x2.5 hole 1: 2(17.78,0) 3(15.24,0) 4(12.7,0) 5(10.16,0) 6(7.62,0) 7(5.08,0) 8(2.54,0) 9(0,0)
Top Overlay:
  lines w0.254: 20.32,-5.1 27.88,-5.1 ; 27.88,0 27.88,-5.1 ; 27.88,-5.1 27.88,15.4 -5.12,15.4 -5.12,-5.1 27.88,-5.1 ; -6.17,-6.05 28.93,-6.05 28.93,16.35 -6.17,16.35 -6.17,-6.05
M15_Country_Yard:
  lines w0.1: 10.88,5.15 11.88,5.15 ; 11.38,4.65 11.38,5.65

## VQFN50P400X400X90-20N [mm] "VQFN, 20-Leads, Body 4.0x4.0mm (max), Pitch 0.50mm, IPC Medium Density"
height 0.9
pads (21):
  rect 0.8x0.25 smd: 1(-2.02,1)
  oval 0.8x0.25 smd: 2(-2.02,0.5) 3(-2.02,0) 4(-2.02,-0.5) 5(-2.02,-1) 11(2.03,-1) 12(2.03,-0.5) 13(2.03,0) 14(2.03,0.5) 15(2.03,1)
  oval 0.25x0.8 smd: 6(-1,-2.02) 7(-0.5,-2.02) 8(0,-2.02) 9(0.5,-2.02) 10(1,-2.02) 16(1,2.02) 17(0.5,2.02) 18(0,2.02) 19(-0.5,2.02) 20(-1,2.02)
  rect 2.6x2.6 smd: 21(0,0)
Top Overlay:
  circle w0.25: c-2.9,1 r0.125
  lines w0.2: -2.15,-1.675 -2.15,-2.15 -1.675,-2.15 ; -2.15,1.675 -2.15,2.15 -1.675,2.15 ; 1.675,-2.15 2.15,-2.15 2.15,-1.675 ; 1.675,2.15 2.15,2.15 2.15,1.675
M13_Assembly_Info:
  circle w0.1: c-1.53,1.54 r0.23
  lines w0.1: -2,-2 -2,2 2,2 2,-2 -2,-2
M15_Country_Yard:
  lines w0.1: -0.5,0 0.5,0 ; 0,-0.5 0,0.5 ; -2.6,-2.6 -2.6,2.6 2.6,2.6 2.6,-2.6 -2.6,-2.6
3D body: height 1, standoff 0.05, extent -2,-2 2,2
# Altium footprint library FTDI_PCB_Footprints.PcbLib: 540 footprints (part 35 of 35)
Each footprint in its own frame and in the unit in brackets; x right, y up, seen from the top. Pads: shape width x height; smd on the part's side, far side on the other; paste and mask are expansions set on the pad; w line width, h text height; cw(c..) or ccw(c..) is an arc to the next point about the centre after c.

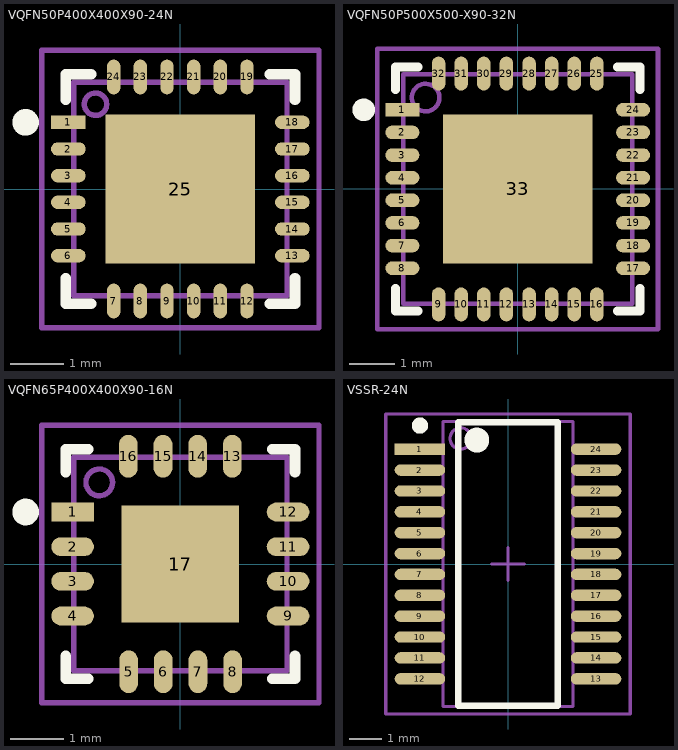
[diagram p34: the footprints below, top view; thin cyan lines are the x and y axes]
## VQFN50P400X400X90-24N [mm] "QFN, 24-Leads, Body 4.0x4.0mm (max), Pitch 0.50mm, IPC Medium Density"
height 0.9
pads (25):
  rect 0.65x0.25 smd: 1(-2.1,1.25)
  oval 0.65x0.25 smd: 2(-2.1,0.75) 3(-2.1,0.25) 4(-2.1,-0.25) 5(-2.1,-0.75) 6(-2.1,-1.25) 13(2.1,-1.25) 14(2.1,-0.75) 15(2.1,-0.25) 16(2.1,0.25) 17(2.1,0.75) 18(2.1,1.25)
  oval 0.25x0.65 smd: 7(-1.25,-2.1) 8(-0.75,-2.1) 9(-0.25,-2.1) 10(0.25,-2.1) 11(0.75,-2.1) 12(1.25,-2.1) 19(1.25,2.1) 20(0.75,2.1) 21(0.25,2.1) 22(-0.25,2.1) 23(-0.75,2.1) 24(-1.25,2.1)
  rect 2.8x2.8 smd: 25(0,0)
Top Overlay:
  circle w0.25: c-2.9,1.25 r0.125
  lines w0.2: -2.15,-1.675 -2.15,-2.15 -1.675,-2.15 ; -2.15,1.675 -2.15,2.15 -1.675,2.15 ; 1.675,-2.15 2.15,-2.15 2.15,-1.675 ; 1.675,2.15 2.15,2.15 2.15,1.675
M13_Assembly_Info:
  circle w0.1: c-1.59,1.59 r0.21
  lines w0.1: -2,-2 2,-2 2,2 -2,2 -2,-2
M15_Country_Yard:
  lines w0.1: -0.5,0 0.5,0 ; 0,-0.5 0,0.5 ; -2.6,-2.6 2.6,-2.6 2.6,2.6 -2.6,2.6 -2.6,-2.6
3D body: height 0.9, standoff 0.02, extent -2,-2 2,2

## VQFN50P500X500-X90-32N [mm] "QFN, 32-Leads, Body 5.1x5.1mm (max), Pitch 0.50mm, IPC Medium Density"
height 0.9
pads (33):
  rect 0.75x0.3 smd: 1(-2.55,1.75)
  oval 0.75x0.3 smd: 2(-2.55,1.25) 3(-2.55,0.75) 4(-2.55,0.25) 5(-2.55,-0.25) 6(-2.55,-0.75) 7(-2.55,-1.25) 8(-2.55,-1.75) 17(2.55,-1.75) 18(2.55,-1.25) 19(2.55,-0.75) 20(2.55,-0.25) 21(2.55,0.25) 22(2.55,0.75) 23(2.55,1.25) 24(2.55,1.75)
  oval 0.3x0.75 smd: 9(-1.75,-2.55) 10(-1.25,-2.55) 11(-0.75,-2.55) 12(-0.25,-2.55) 13(0.25,-2.55) 14(0.75,-2.55) 15(1.25,-2.55) 16(1.75,-2.55) 25(1.75,2.55) 26(1.25,2.55) 27(0.75,2.55) 28(0.25,2.55) 29(-0.25,2.55) 30(-0.75,2.55) 31(-1.25,2.55) 32(-1.75,2.55)
  rect 3.3x3.3 smd: 33(0,0)
Top Overlay:
  circle w0.25: c-3.405,1.75 r0.125
  lines w0.2: -2.7,-2.2 -2.7,-2.7 -2.2,-2.7 ; -2.7,2.2 -2.7,2.7 -2.2,2.7 ; 2.2,-2.7 2.7,-2.7 2.7,-2.2 ; 2.2,2.7 2.7,2.7 2.7,2.2
M13_Assembly_Info:
  circle w0.1: c-2.035,2.02 r0.305
  lines w0.1: -2.535,-2.535 -2.535,2.535 2.535,2.535 2.535,-2.535 -2.535,-2.535
M15_Country_Yard:
  lines w0.1: -0.5,0 0.5,0 ; 0,-0.5 0,0.5 ; -3.1,-3.1 -3.1,3.1 3.1,3.1 3.1,-3.1 -3.1,-3.1
3D body: height 1, standoff 0.05, extent -2.535,-2.535 2.535,2.535

## VQFN65P400X400X90-16N [mm] "VQFN, 16-Leads, Body 4.0x4.0mm (max), Pitch 0.65mm, IPC Medium Density"
height 0.9
pads (17):
  rect 0.8x0.35 smd: 1(-2.02,0.975)
  oval 0.8x0.35 smd: 2(-2.02,0.325) 3(-2.02,-0.325) 4(-2.02,-0.975) 9(2.02,-0.975) 10(2.02,-0.325) 11(2.02,0.325) 12(2.02,0.975)
  oval 0.35x0.8 smd: 5(-0.97,-2.02) 6(-0.32,-2.02) 7(0.33,-2.02) 8(0.98,-2.02) 13(0.975,2.02) 14(0.325,2.02) 15(-0.325,2.02) 16(-0.975,2.02)
  rect 2.2x2.2 smd: 17(0,0)
Top Overlay:
  circle w0.25: c-2.9,0.975 r0.125
  lines w0.2: -2.15,-1.725 -2.15,-2.15 -1.725,-2.15 ; -2.15,1.725 -2.15,2.15 -1.725,2.15 ; 1.725,-2.15 2.15,-2.15 2.15,-1.725 ; 1.725,2.15 2.15,2.15 2.15,1.725
M13_Assembly_Info:
  circle w0.1: c-1.52,1.53 r0.25
  lines w0.1: -2,-2 -2,2 2,2 2,-2 -2,-2
M15_Country_Yard:
  lines w0.1: -0.5,0 0.5,0 ; 0,-0.5 0,0.5 ; -2.6,-2.6 -2.6,2.6 2.6,2.6 2.6,-2.6 -2.6,-2.6
3D body: height 0.9, standoff 0.02, extent -2,-2 2,2

## VSSR-24N [mm] "VSSR resistor network, 24-Leads, Body 8.7x4.0mm (max), Pitch 0.64mm, IPC Medium Density"
height 1.76
pads (24):
  rect 1.55x0.35 smd: 1(-2.7,3.52)
  oval 1.55x0.35 smd: 2(-2.7,2.88) 3(-2.7,2.24) 4(-2.7,1.6) 5(-2.7,0.96) 6(-2.7,0.32) 7(-2.7,-0.32) 8(-2.7,-0.96) 9(-2.7,-1.6) 10(-2.7,-2.24) 11(-2.7,-2.88) 12(-2.7,-3.52) 13(2.7,-3.52) 14(2.7,-2.88) 15(2.7,-2.24) 16(2.7,-1.6) 17(2.7,-0.96) 18(2.7,-0.32) 19(2.7,0.32) 20(2.7,0.96) 21(2.7,1.6) 22(2.7,2.24) 23(2.7,2.88) 24(2.7,3.52)
Top Overlay:
  circle w0.25: c-2.7,4.245 r0.125
  circle w0.6: c-0.954,3.8 r0.079
  lines w0.2: -1.525,-4.35 -1.525,4.35 1.525,4.35 1.525,-4.35 -1.525,-4.35
M13_Assembly_Info:
  circle w0.1: c-1.451,3.85 r0.326
  lines w0.1: -1.995,-4.37 -1.995,4.37 1.995,4.37 1.995,-4.37 -1.995,-4.37
M15_Country_Yard:
  lines w0.1: -0.5,0 0.5,0 ; 0,-0.5 0,0.5 ; -3.75,-4.6 -3.75,4.6 3.75,4.6 3.75,-4.6 -3.75,-4.6
3D body: height 1.76, standoff 0.15, extent -1.995,-4.37 1.995,4.37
